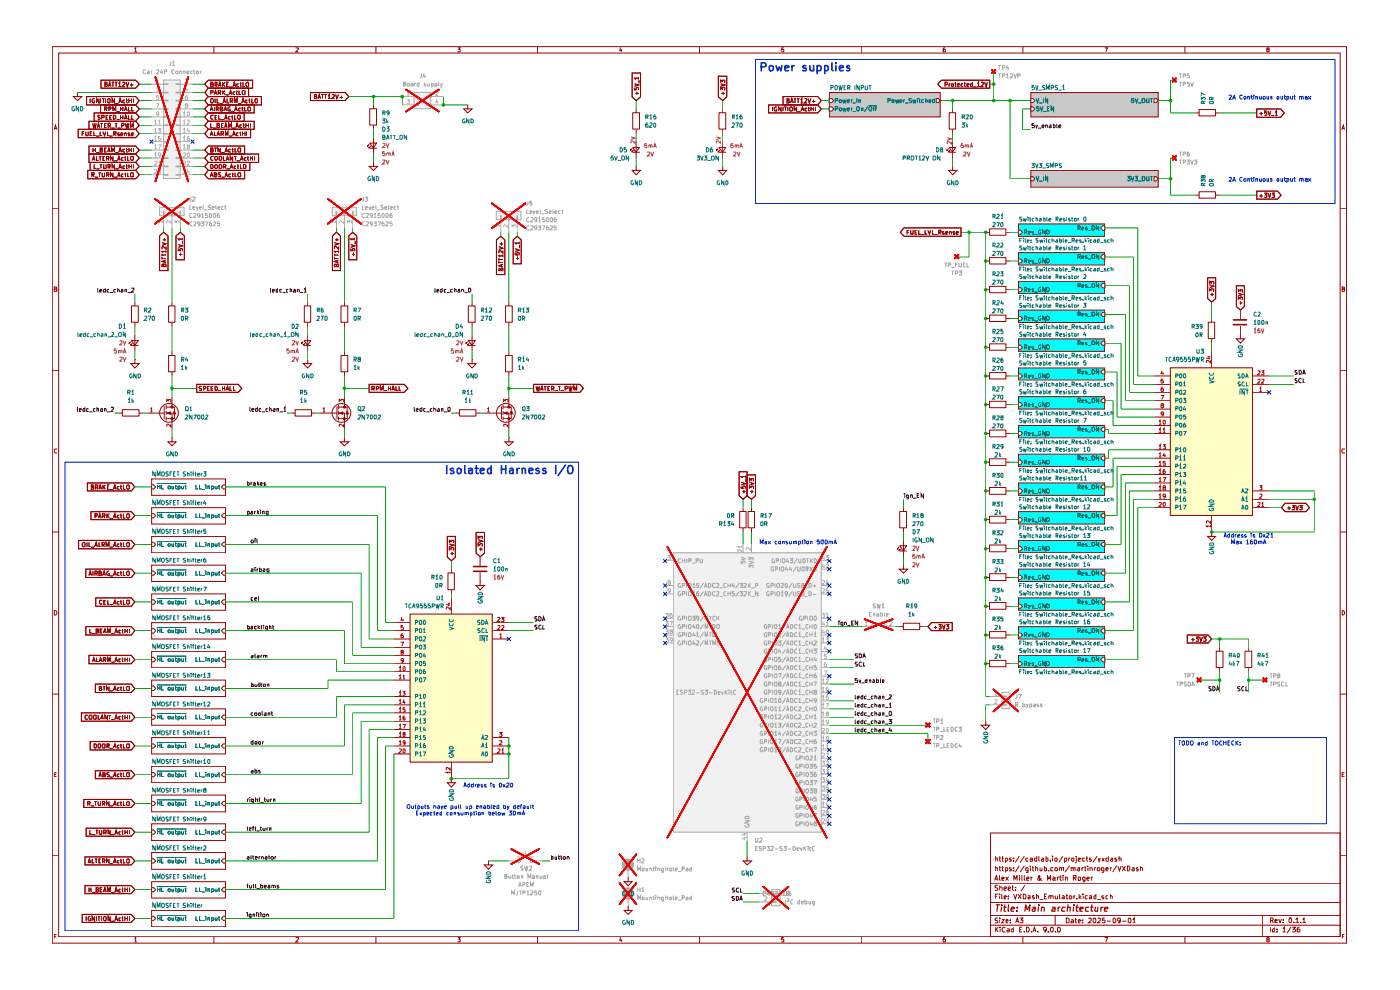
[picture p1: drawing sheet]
<svg xmlns="http://www.w3.org/2000/svg" width="297mm" height="210mm" viewBox="0 0 297 210" stroke-linecap="round" stroke-linejoin="round" font-family="sans-serif">
<g fill="none" stroke="#980000" stroke-width=".21">
<path d="M11.1 9.9h274.6v190.2h-274.6zM12.4 11.3h271.9v187.4h-271.9zM28.5 10.4l.3-.2v.8M28.5 11h.5M45.4 9.9v1.4M62.8 10.2h.4l.1 .2-.6 .6h.6M79.8 9.9v1.4M97.1 10.2h.5l-.2 .3 .2 .1v.3h-.5M114 9.9v1.4M131.7 10.1l-.2 .6h.5M131.9 10.4v.6M148.4 9.9v1.4"/>
<path d="M166.3 10.2h-.4l-.1 .4 .4-.1 .1 .4h-.5M182.7 9.9v1.4M200.5 10.2h-.3l-.1 .6v.2l.5-.1-.1-.4h-.4v.2M217 9.9v1.4M234.4 10.2h.5l-.3 .8M251.4 9.9v1.4M268.9 10.5l-.2-.2 .1-.1h.3l.1 .2-.5 .3 .1 .3 .4-.1v-.3l-.1-.1M11.5 27.5l.3-.9 .3 .9M11.6 27.3h.4M284.6 27.5l.4-.9 .2 .9M284.7 27.3h.5M11.1 44.3h1.3"/>
<path d="M284.3 44.3h1.4M11.1 78.6h1.3M11.5 61.3h.4l.1-.3-.5-.1v.9h.5l.1-.3-.3-.2M284.3 78.6h1.4M284.7 61.3h.5v-.3l-.1-.1h-.4v.9h.5v-.4l-.1-.1M12.1 95.3l-.4-.1-.2 .2v.5l.2 .2 .4-.1M285.2 95.3l-.4-.1-.2 .4 .2 .5 .4-.1M11.1 112.9h1.3M284.3 112.9h1.4M11.5 129.5a.48 .48 0 0 1 .6 .5 .48 .48 0 0 1-.6 .5zM284.7 129.5l.5 .3v.4l-.3 .3h-.2zM11.1 147.2h1.3"/>
<path d="M284.3 147.2h1.4M11.6 164.3h.3M12 163.9h-.4v.9h.4M210.1 176.7h74.2v22h-74.2zM284.7 164.3h.4M285.2 163.9h-.5v.9h.5M11.1 181.5h1.3M11.6 198.6h.3M12 198.2h-.4v.8M28.5 199.1l.3-.2v.9M28.5 199.8h.5M45.4 198.7v1.4"/>
<path d="M62.8 199l.4-.1 .1 .2-.6 .7h.6M79.8 198.7v1.4M97.1 198.9h.5l-.2 .3 .2 .1v.4h-.5M114 198.7v1.4M131.7 198.8l-.2 .7h.5M131.9 199.2v.6M148.4 198.7v1.4M166.3 198.9h-.4l-.1 .4h.5v.4h-.5M182.7 198.7v1.4M200.5 198.9h-.3a.72 .72 0 0 0 0 .9l.4-.1v-.4l-.4-.1-.1 .2M210.1 196.3h74.2M210.1 194.2h74.2"/>
<path d="M210.1 191.4h74.2M210.1 187.4h74.2M211 186.7l.4-1 .3 1M211.1 186.5h.5M211.2 184.1h.4v.6M211.2 182.1l.4-.1v.7M211.2 181.6v1.1M211.2 183.7v1M211.2 196.7v1M211.2 190.2h.3M211.3 197.1l.4 .6M211.7 194.8l-.4-.1-.2 .3 .1 .2 .5 .2v.3h-.6"/>
<path d="M211.7 189.6h-.5v1.1M211.7 187.9h-.5a.44 .44 0 0 0 0 .4 .44 .44 0 0 0 .5 .2l-.2 .4-.4-.1M211.7 196.7l-.5 .6M211.9 184.1h.4M211.9 182h.4M212 189.6v.1M212 190v.7M212 185.7v.9l.2 .1M212.1 194.7v.1M212.1 188.3l.2-.2 .3 .2v.6M212.1 183.7v1h.2M212.1 181.6v1l.2 .1"/>
<path d="M212.1 187.8v1.1M212.1 195.1v.6M212.2 196.7v.1M212.2 197v.7M212.5 195.1h.5l-.5 .6h.5M212.5 189.6v1l.2 .1M212.5 184.1h.4M212.5 182h.4M212.6 186.4l.5-.1-.2-.3-.3 .1v.6h.4M212.7 183.7v1h.2M212.7 181.6v1l.2 .1M213 190.3l.5-.1-.1-.2-.4 .1v.6h.4"/>
<path d="M213 188.5l.5-.1-.1-.3-.4 .1v.6h.4M213.3 196.8a.51 .51 0 0 0-.7 .2 .51 .51 0 0 0 .2 .7l.5-.1M213.3 184.7h.2l.3-.1v-.4l-.2-.1h-.3v1M213.3 182.6l.2 .1 .3-.2-.2-.5h-.3v1M213.4 186l.5 .7M213.4 195.4l.5-.1-.1-.2-.4 .1v.5h.5M213.7 197.1h.4v.6h-.4l-.1-.3 .5-.1M213.9 188.5l.5-.1v-.2l-.4-.1-.1 .2v.4l.1 .2 .4-.1M213.9 186l-.5 .7M213.9 190.6v.1M213.9 190.1v.1M214.4 195.7h.1"/>
<path d="M214.4 195.2h.1M214.5 184.1h-.3l-.1 .1 .4 .2v.3h-.4M214.5 182l-.4 .1 .2 .3h.2v.2h-.4M214.7 188.1h.3M214.8 187.8v.9l.2 .2M215 196.7v1h-.3l-.2-.2v-.3l.3-.2 .2 .1M215 189.6l.4 1.1 .3-1.1M215 184.7h.1M215 184.1v.1M215 182.5v.2M215 182v.1M215.1 186.7v-1l.3 .8 .4-.8v1"/>
<path d="M215.4 188.7v.2M215.4 188.2v.1M215.5 195.7l.3-1 .3 1M215.6 195.5h.5M216 189.6l.7 1.1M216.2 183.6l-.8 1.4M216.2 181.6l-.8 1.4M216.3 185.7v.1M216.3 186v.7M216.3 197.2h.4M216.4 194.7h.6l-.3 .5h.3v.5h-.6M216.7 189.6l-.7 1.1"/>
<path d="M216.8 185.7l.1 1M216.8 196.7h-.5v1h.5M217 198.7v1.4M217.1 189.6a.59 .59 0 0 1 .5 .4 .59 .59 0 0 1-.1 .7h-.4zM217.2 197.6v.1M217.3 185.7v.9l.2 .1M217.3 183.6l-.9 1.4M217.3 181.6l-.9 1.4M217.4 187.8l-.8 1.3M217.8 196.7a.59 .59 0 0 1 .5 .3 .59 .59 0 0 1-.1 .7h-.4zM217.8 186.4l.5-.1-.2-.3-.3 .1v.6h.4M218.1 190.1h.4v.6h-.4v-.4l.4-.1"/>
<path d="M218.1 184.7h-.3l-.2-.1 .1-.5h.4v.9h-.4M218.1 182h-.4l-.1 .2 .1 .4h.4M218.5 182l.5 .1v.6M218.6 183.7v.1M218.6 184.1v.6M218.7 186v.7M218.8 197.6v.1M218.9 184.1h.5M219 186l-.3 .2M219 182.2l-.5 .2 .1 .3 .4-.1M219.1 197.7l.4-1 .3 1M219.1 183.7v1h.3"/>
<path d="M219.2 197.4h.5M219.4 190.1l-.3-.1-.1 .3h.3l.2 .3-.5 .1M219.7 184.1h.3l.1 .6M219.7 183.7v1M219.9 190.2l.1-.2 .3 .1v.6M219.9 189.6v1.1M220 182l-.5 .1v.4l.1 .2 .4-.1M220 181.6v1.1M220.1 197.6v.1M220.4 181.6v.9l.2 .2M220.6 190.8h.7M220.6 184.1v.6h.5"/>
<path d="M220.8 186.2l-.2 .5-.4-.1v-.3l.4-.3-.1-.3-.2 .3 .4 .6 .3 .1M221 182l.4 .1v.6M221.1 184.1v.6M221.4 182.2l-.5 .3 .2 .2 .3-.1M221.6 184.1h.4v.6h-.4M221.6 190.2h.3M221.6 183.7v1M221.9 182l.4 .1v.4l-.1 .2-.3-.1M221.9 181.6v1.1M222 197.1l-.2 .3-.4-.2v-.4l.4-.1a.83 .83 0 0 1 0 1h-.3M222.1 189.6h-.5v1.1h.5M222.2 186.7v-1l.3 .8 .4-.8v1"/>
<path d="M222.4 197.6v.1M222.5 190.2l.2-.2 .2 .1v.6M222.5 184.7h.1M222.5 190v.7M222.8 182.5v.2M222.9 196.8l.3-.1 .2 .1v.7l-.1 .2-.4-.1zM222.9 190.2l.4-.2 .1 .2v.5M223.3 181.6v.2M223.3 182v.7M223.4 186.1h.4v.6h-.4l-.1-.2 .5-.2M223.4 184.1h-.5v.6h.5M223.8 182.1l.4-.1 .1 .5-.2 .2-.3-.2z"/>
<path d="M223.9 197.6v.1M223.9 190v.6h.5M223.9 184.1h.3l.2 .1-.1 .5h-.3l-.2-.1zM223.9 194.2v2.1M224.3 186v.7M224.4 196.8l.2-.1a.52 .52 0 0 1 .4 .6 .52 .52 0 0 1-.6 .4zM224.4 190v.7M224.6 186l-.3 .2M224.8 189.6v1l.2 .1M224.8 184.1h.3l.1 .6M224.8 184.1v.6M224.8 186h.4"/>
<path d="M224.9 185.7v.9l.3 .1M225.2 184.2l.1-.1h.3v.6M225.4 190.1l.2-.1 .2 .2v.5h-.4v-.4l.4-.1M225.5 181.6l-.9 1.4M225.5 185.7v.1M225.5 186v.7M225.8 182.6h.4v-.6h-.4v1M226 186.1h.4v.6M226 186v.7M226.1 190h.5M226.2 194.7l.6 .3v.6l-.2 .1h-.4zM226.3 189.6v1.1h.3"/>
<path d="M226.7 182v.7M226.9 190.1l.3-.1 .2 .2-.2 .5h-.3zM226.9 183.6l-.9 1.4M227.1 182h-.3l-.1 .2M227.2 195.2l.4-.1 .1 .1v.5h-.5v-.3l.5-.1M227.2 184.1h.4l.1 .6M227.2 184.1v.6M227.4 182l.4 .1v.4l-.1 .2-.4-.2zM227.7 184.2v-.1h.4v.6M227.7 186.2h.5l.1-.4-.6-.1v1M227.8 190v.7M228 186.2l.3 .5"/>
<path d="M228.1 190l-.3 .2M228.1 195.1h.3M228.2 194.7v1h.2M228.3 182v.9l-.2 .1M228.3 181.6v.2M228.4 190.6v.1M228.6 184.1h.4v.6M228.7 186.2l.2-.2 .3 .1v.5l-.4 .1zM228.8 195.4l.5-.1-.2-.2-.3 .1v.5h.4M228.8 182.4l.5-.2-.1-.2h-.4v.6h.4M228.9 189.6v1.1M229 184.3h-.3l-.2 .2 .2 .2h.3"/>
<path d="M229 190.3l.4 .4M229.4 190l-.5 .4M229.5 184.1v.6M229.7 195.7h.1M229.7 195.2h.1M229.8 189.6v.1M229.8 190v.7M229.9 184.1h-.3l-.1 .1M230 184.1h.4M230.1 182h-.4l-.1 .2 .1 .4h.4M230.2 186v.9l-.1 .2h-.4M230.2 186.1l-.4-.1-.1 .2v.5h.5"/>
<path d="M230.2 183.7v1h.2M230.4 182h.4M230.5 181.6v.9l.3 .2M230.6 186.4l.5-.1-.2-.3-.3 .2v.4l.1 .1h.3M230.7 190.1l-.3-.1-.2 .2 .1 .5h.4M230.8 183.7v.1M230.8 184.1v.6M230.9 194.8h.6v.4l-.6 .5h.6M231.1 190.1h.5v.6h-.5v-.4l.5-.1M231.2 184.1h.4l.1 .6M231.2 184.1v.6M231.5 182h-.4v.3l.5 .2-.2 .2-.3-.1"/>
<path d="M231.5 186v.7M231.8 186l-.3 .2M232 194.8l.2-.1a.53 .53 0 0 1 .3 .6 .53 .53 0 0 1-.4 .4l-.2-.1zM232.2 184.1v.6M232.5 189.6v1.1h-.3l-.1-.5 .1-.2 .3 .1M232.5 184.1h-.3v.1M232.7 190.8h.9M232.7 181.6l-.9 1.4M232.8 194.8h.6v.4l-.6 .5h.6M232.8 184.1h.4l.1 .1v.5h-.3l-.3-.1zM233 182l.2 .7 .2-.7M233.8 182l.5 .7"/>
<path d="M234.1 190.1h-.3v.2h.2l.2 .3-.4 .1M234.2 184.7h-.3l-.2-.1 .1-.5h.4v.8l-.2 .2-.2-.1M234.3 182l-.5 .7M234.4 198.9h.5l-.3 .9M234.4 194.7h-.5l-.1 .5h.5l.1 .1v.4h-.6M234.6 184.4l.5-.1-.1-.2h-.3l-.1 .1v.4l.2 .1h.2M234.9 195.4h.7M235 190.1l-.2-.1-.2 .2v.4l.4 .1M235.1 182h-.4l-.1 .2 .1 .4h.4M235.1 181.6v1.1M235.5 190.2l.1-.2 .4 .2v.5M235.5 184.1v.6"/>
<path d="M235.5 189.6v1.1M235.6 182l.4 .1v.6M235.9 184.1h-.3l-.1 .1M236 182.2l-.5 .3 .2 .2 .3-.1M236.2 194.8l.3-.1 .2 .5-.1 .5h-.4l-.1-.1zM236.9 182l-.4 .1 .1 .3h.3v.2h-.4M236.9 183.6l-.9 1.4M237.1 183.7l.4 1 .3-1M237.4 182.1h.4v.6M237.4 181.6v1.1M237.7 195.2l-.2 .2-.4-.1v-.5h.6v.8l-.2 .1h-.4M238.1 195.4h.8"/>
<path d="M238.1 183.7l.7 1M238.8 183.7l-.7 1M239.2 183.7h.3l.2 .3v.5l-.4 .2h-.1zM239.4 194.8l.2-.1a.53 .53 0 0 1 .3 .6 .53 .53 0 0 1-.4 .4l-.2-.1zM240.2 184.1h.3l.1 .6M240.3 195.1l.3-.4v1M240.3 195.7h.6M240.6 184.3h-.3l-.2 .2 .2 .2h.3M241.5 184.1h-.4l-.1 .1 .5 .2v.3h-.5M242 184.1h.3l.1 .6M242 183.7v1M251.4 198.7v1.4"/>
<path d="M267.8 194.2v4.5M268.9 199.3l-.2-.2 .1-.2h.3l.1 .3-.4 .1-.1 .2 .2 .3 .3-.1v-.3l-.1-.1M269.5 196.7v1M269.5 195.3l.5-.1v-.4l-.5-.1v1M269.8 195.3l.3 .4M270.4 196.7v1h-.4l-.1-.5 .3-.2 .2 .1M270.5 195.4l.5-.1v-.2l-.4-.1-.1 .2v.5h.5M270.9 197.6v.1M270.9 197.1v.1M271.3 195l.3 .7 .2-.7M272.1 196.9l.4-.2v1M272.1 197.7h.6"/>
<path d="M272.2 195.6v.1M272.2 195.1v.1M273.5 194.8l.2-.1a.53 .53 0 0 1 .3 .5 .53 .53 0 0 1-.4 .5l-.2-.3zM273.9 196.6l-.9 1.3M274.1 196.7h.7l-.4 .4 .4 .2v.2l-.1 .2-.6-.1M274.4 195.6v.1M274.9 195l.3-.3v1M274.9 195.7h.6M275.7 196.7l-.4 .1a.74 .74 0 0 0-.1 .9h.5l.1-.5-.6-.1v.2M276 195.6v.1M276.4 195l.2-.3v1M276.4 195.7h.6"/>
<path d="M284.3 181.5h1.4M284.8 198.6h.3M285.2 198.2h-.4v.8"/>
</g>
<g fill="none" stroke="#980000" stroke-width=".25">
<path d="M211.3 191.9h.8M211.7 191.9l-.2 1.4M212.5 191.9v.2M212.5 192.4l-.2 .9M212.9 192.4h.5M213.2 191.9l-.2 1.2 .1 .2h.3M213.9 191.9v1.4h.1M214.5 192.9l.7-.2-.1-.3h-.5l-.1 .7v.2h.5M215.7 193.2v.1M215.8 192.4v.2M217.4 193.3l.2-1.4 .3 1 .6-1-.2 1.4M219.1 192.4h.5v.2l-.1 .7h-.5v-.4l.6-.2"/>
<path d="M220.3 192.4l-.1 .9M220.4 191.9v.2M221 192.5l.5-.1v.9M221 192.4l-.1 .9M223.3 192.4h.5l.1 .2-.1 .7h-.6l-.1-.2 .2-.3 .6-.1M224.5 192.4l-.1 .9M224.9 192.4h-.3l-.2 .3M226 192.4h-.5l-.3 .6 .1 .3h.6M226.6 192.5l.5-.1-.1 .9M226.6 191.9l-.2 1.4M227.7 192.4v.9M227.8 191.9v.2"/>
<path d="M228.3 192.4h.5M228.5 191.9l-.2 1.2 .1 .2h.3M229.1 192.9l.7-.2v-.3h-.6l-.1 .2v.7h.5M231 192.4h-.5l-.2 .3v.5l.6 .1M231.4 192.4h.5M231.6 191.9l-.1 1.2 .1 .2h.2M232.4 192.4l-.1 .9 .5-.1M232.9 192.4l-.1 .9M233.6 192.4l-.1 .9M234 192.4h-.2l-.2 .3M234.4 192.9l.6-.2-.1-.3h-.5l-.1 .7 .1 .2h.5"/>
</g>
<g fill="none" stroke="#e00" stroke-width=".34">
<path d="M33 16.4l6.9 22.1M39.9 16.4l-6.9 22.1M86.1 19l7 4.7M93.1 19l-7 4.7M210.4 14.9l.7 .6M211.1 14.9l-.7 .6M248.8 16.6l.7 .7M249.5 16.6l-.7 .7M248.8 33.1l.7 .8M249.5 33.1l-.7 .8M32.9 42.2l7.1 5.2M40 42.2l-7.1 5.2"/>
<path d="M69.5 42.2l7.1 5.2M76.6 42.2l-7.1 5.2M104.3 43.1l7.2 5.3M111.5 43.1l-7.2 5.3M202.6 54.1l.7 .7M203.3 54.1l-.7 .7M141.6 116l33.8 61.7M175.4 116l-33.8 61.7M183.4 131.4l6 2.2M189.4 131.4l-6 2.2M196.5 153.5l.7 .6M196.5 156.9l.7 .8"/>
<path d="M197.2 153.5l-.7 .6M197.2 156.9l-.7 .8M210.8 146.3l5.2 4.6M216 146.3l-5.2 4.6M254 143.9l.7 .7M254.7 143.9l-.7 .7M268 143.9l.7 .7M268.7 143.9l-.7 .7M108.5 180.1l5.8 3.2M114.3 180.1l-5.8 3.2M131.4 181.2l3.6 4.5M131.4 187.3l3.6 4.5"/>
<path d="M135 181.2l-3.6 4.5M135 187.3l-3.6 4.5M161.9 188.1l5.4 4.6M167.3 188.1l-5.4 4.6"/>
</g>
<path d="M216.1 128.2h.4l.4 .4-.4 .4h-.4z" fill="#fff"/>
<path d="M216.1 128.2h.4l.4 .4-.4 .4h-.4z" fill="none" stroke="#805e00" stroke-width=".21"/>
<path d="M217.3 128.6h.4l.1-.3-.1-.2h-.4v.8M217.6 128.6l.2 .3M218.2 128.7l.4-.1-.1-.2h-.3v.5h.3M219.3 128.4h-.4l.1 .3h.3v.2h-.4M219.5 129h.6M220.8 128.2l-.2-.1-.3 .2v.5l.2 .1h.3v-.3h-.2M221.7 128.1v.8l-.5-.8v.8M222.1 128.1h.2l.3 .2v.5l-.2 .1h-.3z" fill="none" stroke="#007170" stroke-width=".21"/>
<path d="M233.5 127.7l.4-.5h.5v1h-.5z" fill="#fff"/>
<path d="M233.9 127.2h.5v1h-.5l-.4-.5z" fill="none" stroke="#805e00" stroke-width=".21"/>
<path d="M228.7 127.7h.4l.1-.4-.5-.1v.9M228.9 127.7l.3 .4M229.5 127.8h.4l-.1-.3-.3 .1v.5h.4M230.6 127.6h-.3l.1 .2h.2v.3h-.3M230.8 128.2h.7M231.6 127.3h.6v.5l-.1 .3-.5-.1zM233.1 127.2v.9l-.5-.9v.9" fill="none" stroke="#007170" stroke-width=".21"/>
<path d="M216.1 126.8h18.3v2.6h-18.3z" fill="#0ff"/>
<path d="M216.1 140.4h.4l.4 .4-.4 .4h-.4z" fill="#fff"/>
<path d="M216.1 140.4h.4l.4 .4-.4 .4h-.4z" fill="none" stroke="#805e00" stroke-width=".21"/>
<path d="M217.3 140.8h.4l.1-.3-.1-.2h-.4v.9M217.6 140.8l.2 .4M218.2 140.9l.4-.1-.1-.2h-.3v.5h.3M219.3 140.6h-.4v.3l.4 .1-.1 .2-.3-.1M219.5 141.3h.6M220.8 140.4l-.2-.1-.3 .2v.5l.3 .2 .2-.1v-.3h-.2M221.7 140.3v.9l-.5-.9v.9M222.1 140.3h.2l.3 .2v.5l-.3 .2h-.2z" fill="none" stroke="#007170" stroke-width=".21"/>
<path d="M233.9 139.4h.5v1h-.5l-.4-.5z" fill="#fff"/>
<path d="M233.9 139.4h.5v1h-.5l-.4-.5z" fill="none" stroke="#805e00" stroke-width=".21"/>
<path d="M228.7 139.9h.4l.1-.4-.5-.1v.9M228.9 139.9l.3 .4M230.6 139.8h-.3l.1 .2h.2v.3h-.3M231.7 139.4h.4l.1 .3-.1 .6-.5-.1zM233.1 139.4v.9l-.5-.9v.9M229.5 140l.4-.1-.1-.2-.3 .1v.5h.4M230.8 140.4h.7" fill="none" stroke="#007170" stroke-width=".21"/>
<path d="M216.1 139h18.3v2.6h-18.3z" fill="#0ff"/>
<path d="M216.1 134.3h.4l.4 .4-.4 .4h-.4z" fill="#fff"/>
<path d="M216.1 134.3h.4l.4 .4-.4 .4h-.4z" fill="none" stroke="#805e00" stroke-width=".21"/>
<path d="M217.3 134.7h.4l.1-.3-.1-.2h-.4v.8M217.6 134.7l.2 .3M218.2 134.8l.4-.1-.1-.2h-.3v.5h.3M219.3 134.5h-.4v.3h.3l.1 .2h-.4M219.5 135.1h.6M220.8 134.3l-.2-.1-.3 .2v.5l.2 .1h.3v-.3h-.2M221.7 134.2v.8l-.5-.8v.8M222.1 134.2h.2l.3 .2v.5l-.2 .1h-.3z" fill="none" stroke="#007170" stroke-width=".21"/>
<path d="M233.5 133.8l.4-.5h.5v1h-.5z" fill="#fff"/>
<path d="M233.9 133.3h.5v1h-.5l-.4-.5z" fill="none" stroke="#805e00" stroke-width=".21"/>
<path d="M228.7 133.8h.4l.1-.4-.5-.1v.9M228.9 133.8l.3 .4M229.5 133.9h.4l-.1-.3-.3 .1v.5h.4M230.6 133.7h-.3l.1 .2h.2v.3h-.3M230.8 134.3h.7M231.6 133.4h.6v.5l-.1 .3-.5-.1zM233.1 133.3v.9l-.5-.9v.9" fill="none" stroke="#007170" stroke-width=".21"/>
<path d="M216.1 132.9h18.3v2.6h-18.3z" fill="#0ff"/>
<path d="M216.1 115.9h.4l.4 .5-.4 .4h-.4z" fill="#fff"/>
<path d="M216.1 115.9h.4l.4 .5-.4 .4h-.4z" fill="none" stroke="#805e00" stroke-width=".21"/>
<path d="M217.3 116.3h.5v-.4h-.5v.8M217.6 116.3l.2 .4M218.2 116.5l.4-.1-.2-.2h-.2v.5h.3M219.3 116.2h-.4l.1 .3h.3v.2h-.4M219.5 116.8h.6M220.8 115.9h-.3l-.2 .2v.5l.2 .1h.3v-.3h-.2M221.7 115.9v.8l-.5-.8v.8M222.1 115.9h.3l.2 .2v.5l-.2 .1h-.3z" fill="none" stroke="#007170" stroke-width=".21"/>
<path d="M233.5 115.5l.4-.4h.5v.8h-.5z" fill="#fff"/>
<path d="M233.9 115.1h.5v.8h-.5l-.4-.4z" fill="none" stroke="#805e00" stroke-width=".21"/>
<path d="M228.7 115.5h.4l.1-.4h-.5v.8M228.9 115.5l.3 .4M229.5 115.6h.4l-.1-.3-.3 .1v.4h.4M230.6 115.4h-.3l.1 .2h.2l-.1 .3-.2-.1M230.8 116h.7M231.6 115.1h.5l.1 .2v.3l-.2 .3-.4-.2zM233.1 115.1v.8l-.5-.8v.8" fill="none" stroke="#007170" stroke-width=".21"/>
<path d="M216.1 114.6h18.3v2.7h-18.3z" fill="#0ff"/>
<path d="M216.1 109.8h.4l.4 .4-.4 .5h-.4z" fill="#fff"/>
<path d="M216.1 109.8h.4l.4 .4-.4 .5h-.4z" fill="none" stroke="#805e00" stroke-width=".21"/>
<path d="M217.3 110.2h.5v-.4h-.5v.9M217.6 110.2l.2 .5M218.2 110.4l.4-.1-.2-.2h-.2v.6h.3M219.3 110.1h-.4l.1 .3h.3v.3h-.4M219.5 110.7h.6M220.8 109.8h-.3l-.2 .2v.5l.2 .2h.3v-.4h-.2M221.7 109.8v.9l-.5-.9v.9M222.1 109.8h.3l.2 .2v.5l-.2 .2h-.3z" fill="none" stroke="#007170" stroke-width=".21"/>
<path d="M233.5 109.4l.4-.4h.5v.8h-.5z" fill="#fff"/>
<path d="M233.9 109h.5v.8h-.5l-.4-.4z" fill="none" stroke="#805e00" stroke-width=".21"/>
<path d="M228.7 109.4h.4l.1-.4h-.5v.8M228.9 109.4l.3 .4M229.5 109.5l.4-.1-.1-.2-.3 .1v.4h.4M230.6 109.3h-.3v.2l.3 .1-.1 .2-.2-.1M230.8 109.9h.7M231.6 109h.6a.47 .47 0 0 1-.4 .8l-.2-.2zM233.1 109v.8l-.5-.8v.8" fill="none" stroke="#007170" stroke-width=".21"/>
<path d="M216.1 108.5h18.3v2.7h-18.3z" fill="#0ff"/>
<path d="M216.1 122h.4l.4 .5-.4 .4h-.4z" fill="#fff"/>
<path d="M216.1 122h.4l.4 .5-.4 .4h-.4z" fill="none" stroke="#805e00" stroke-width=".21"/>
<path d="M217.3 122.4h.5v-.2l-.1-.2h-.4v.8M217.6 122.4l.2 .4M218.2 122.6l.4-.1-.2-.2h-.2v.5h.3M219.3 122.3h-.4l.1 .3h.3v.2h-.4M219.5 122.9h.6M220.8 122.1l-.2-.1-.3 .2v.5l.2 .1h.3v-.3h-.2M221.7 122v.8l-.5-.8v.8M222.1 122l.5 .2v.5l-.2 .1h-.3z" fill="none" stroke="#007170" stroke-width=".21"/>
<path d="M233.5 121.6l.4-.4h.5v.8h-.5z" fill="#fff"/>
<path d="M233.9 121.2h.5v.8h-.5l-.4-.4z" fill="none" stroke="#805e00" stroke-width=".21"/>
<path d="M228.7 121.6h.4l.1-.4h-.5v.8M228.9 121.6l.3 .4M229.5 121.7h.4l-.1-.3-.3 .1v.5h.4M230.6 121.5h-.3l.1 .2h.2v.3h-.3M230.8 122.1h.7M231.6 121.2h.6v.5l-.1 .3-.5-.1zM233.1 121.2v.8l-.5-.8v.8" fill="none" stroke="#007170" stroke-width=".21"/>
<path d="M216.1 120.7h18.3v2.7h-18.3z" fill="#0ff"/>
<path d="M47.4 194.4h.4v.8h-.4l-.4-.4z" fill="#fff"/>
<path d="M47.4 194.4h.4v.8h-.4l-.4-.4z" fill="none" stroke="#805e00" stroke-width=".21"/>
<g fill="none" stroke="#007170" stroke-width=".21">
<path d="M41.6 194.4v.8h.4M42.3 194.4v.8h.5M42.8 195.3h.6M43.7 194.4v.1M43.7 194.6v.6M44.1 194.7h.3v.5M44.1 194.6v.6M44.9 194.7h.4v.5h-.4M44.9 194.6v.9M45.6 194.6v.5l.2 .1h.3M46.1 194.6v.6M46.3 194.6h.3"/>
<path d="M46.5 194.4v.8h.1"/>
</g>
<path d="M32.2 194.4h.4l.4 .4-.4 .4h-.4z" fill="#fff"/>
<path d="M32.2 194.4h.4l.4 .4-.4 .4h-.4z" fill="none" stroke="#805e00" stroke-width=".21"/>
<g fill="none" stroke="#007170" stroke-width=".21">
<path d="M33.3 194.1h6.2M33.4 194.4v.8M33.4 194.8h.5M33.9 194.4v.8M34.3 194.4v.8h.4M35.6 194.8l.4-.2 .1 .5-.3 .1zM36.5 194.6v.6h.3M36.8 194.6v.6M37.2 194.6h.3M37.2 194.4v.7l.3 .1M37.8 194.7h.4v.5h-.4M37.8 194.6v.9"/>
<path d="M38.5 194.6v.5l.2 .1h.2M38.9 194.6v.6M39.2 194.6h.3M39.4 194.4v.8h.1"/>
</g>
<g fill="#fff">
<path d="M32.2 193.1h15.6v3.5h-15.6z"/>
<path d="M47 176.5l.4-.4h.4v.8h-.4z"/>
</g>
<path d="M47.4 176.1h.4v.8h-.4l-.4-.4z" fill="none" stroke="#805e00" stroke-width=".21"/>
<path d="M41.6 176v.9h.4M42.3 176v.9h.5M42.8 177h.6M43.7 176v.1M43.7 176.4v.5M44.1 176.4h.3v.5M44.1 176.4v.5M44.9 176.9h.4l-.1-.5h-.3v.8M45.6 176.4v.4l.2 .1h.3M46.1 176.4v.5M46.3 176.4h.3M46.5 176v.9h.1" fill="none" stroke="#007170" stroke-width=".21"/>
<path d="M32.2 176.1h.4l.4 .4-.4 .4h-.4z" fill="#fff"/>
<path d="M32.2 176.1h.4l.4 .4-.4 .4h-.4z" fill="none" stroke="#805e00" stroke-width=".21"/>
<g fill="none" stroke="#007170" stroke-width=".21">
<path d="M33.3 175.8h6.2M33.4 176v.9M33.4 176.4h.5M33.9 176v.9M34.3 176v.9h.4M35.7 176.4h.4v.1l-.1 .4-.4-.1zM36.5 176.4v.5h.3M36.8 176.4v.5M37.2 176.4h.3M37.2 176v.8l.3 .1M37.8 176.9h.4l-.1-.5h-.3v.8M38.5 176.4v.4l.2 .1h.2"/>
<path d="M38.9 176.4v.5M39.2 176.4h.3M39.4 176v.9h.1"/>
</g>
<g fill="#fff">
<path d="M32.2 174.7h15.6v3.6h-15.6z"/>
<path d="M47.4 188.3h.4v.8h-.4l-.4-.4z"/>
</g>
<path d="M47.4 188.3h.4v.8h-.4l-.4-.4z" fill="none" stroke="#805e00" stroke-width=".21"/>
<path d="M41.6 188.3v.8h.4M42.3 188.3v.8h.5M42.8 189.2h.6M43.7 188.3v.1M43.7 188.5v.6M44.1 188.6l.3-.1v.6M44.1 188.5v.6M44.9 189.1h.4l-.1-.6h-.3v.9M45.6 188.5v.5l.2 .1h.3M46.1 188.5v.6M46.3 188.5h.3M46.5 188.3v.8h.1" fill="none" stroke="#007170" stroke-width=".21"/>
<path d="M32.2 188.3h.4l.4 .4-.4 .4h-.4z" fill="#fff"/>
<path d="M32.2 188.3h.4l.4 .4-.4 .4h-.4z" fill="none" stroke="#805e00" stroke-width=".21"/>
<g fill="none" stroke="#007170" stroke-width=".21">
<path d="M33.3 188h6.2M33.4 188.3v.8M33.4 188.6h.5M33.9 188.3v.8M34.3 188.3v.8h.4M35.7 188.5h.4v.2l-.1 .4-.4-.1zM36.5 188.5v.6h.3M36.8 188.5v.6M37.2 188.5h.3M37.2 188.3v.7l.3 .1M37.8 189.1h.4l-.1-.6h-.3v.9M38.5 188.5v.5l.2 .1h.2"/>
<path d="M38.9 188.5v.6M39.2 188.5h.3M39.4 188.3v.8h.1"/>
</g>
<g fill="#fff">
<path d="M32.2 187h15.6v3.5h-15.6z"/>
<path d="M47 182.6l.4-.4h.4v.8h-.4z"/>
</g>
<path d="M47 182.6l.4-.4h.4v.8h-.4z" fill="none" stroke="#805e00" stroke-width=".21"/>
<path d="M41.6 182.1v.9h.4M42.3 182.1v.9h.5M42.8 183.1h.6M43.7 182.1v.1M43.7 182.5v.5M44.1 182.5h.3v.5M44.1 182.5v.5M44.9 183h.4l-.1-.5h-.3v.8M45.6 182.5v.4l.2 .1h.3M46.1 182.5v.5M46.3 182.5h.3M46.5 182.1v.9h.1" fill="none" stroke="#007170" stroke-width=".21"/>
<path d="M32.2 182.2h.4l.4 .4-.4 .4h-.4z" fill="#fff"/>
<path d="M32.2 182.2h.4l.4 .4-.4 .4h-.4z" fill="none" stroke="#805e00" stroke-width=".21"/>
<g fill="none" stroke="#007170" stroke-width=".21">
<path d="M33.3 181.9h6.2M33.4 182.1v.9M33.4 182.5h.5M33.9 182.1v.9M34.3 182.1v.9h.4M35.7 182.5h.4v.1l-.1 .4-.4-.1zM36.5 182.5v.5h.3M36.8 182.5v.5M37.2 182.5h.3M37.2 182.1v.8l.3 .1M37.8 183h.4l-.1-.5h-.3v.8M38.5 182.5v.4l.2 .1h.2"/>
<path d="M38.9 182.5v.5M39.2 182.5h.3M39.4 182.1v.9h.1"/>
</g>
<g fill="#fff">
<path d="M32.2 180.8h15.6v3.6h-15.6z"/>
<path d="M47.4 102.9h.4v.8h-.4l-.4-.4z"/>
</g>
<path d="M47.4 102.9h.4v.8h-.4l-.4-.4z" fill="none" stroke="#805e00" stroke-width=".21"/>
<path d="M41.6 102.9v.8h.4M42.3 102.9v.8h.5M42.8 103.8h.6M43.7 102.9h.1M43.7 103.1v.6M44.1 103.2l.3-.1v.6M44.1 103.1v.6M44.9 103.6h.4l-.1-.5h-.3v.9M45.6 103.1v.4l.2 .2 .3-.1M46.1 103.1v.6M46.3 103.1h.3M46.5 102.9v.7l.1 .1" fill="none" stroke="#007170" stroke-width=".21"/>
<path d="M32.2 102.9h.4l.4 .4-.4 .4h-.4z" fill="#fff"/>
<path d="M32.2 102.9h.4l.4 .4-.4 .4h-.4z" fill="none" stroke="#805e00" stroke-width=".21"/>
<g fill="none" stroke="#007170" stroke-width=".21">
<path d="M33.3 102.6h6.2M33.4 102.9v.8M33.4 103.2h.5M33.9 102.9v.8M34.3 102.9v.8h.4M35.7 103.1h.4v.2l-.1 .4-.4-.2zM36.5 103.1v.5h.3M36.8 103.1v.6M37.2 103.1h.3M37.2 102.9v.6l.3 .2M37.8 103.6h.4l-.1-.5h-.3v.9M38.5 103.1v.4l.2 .2 .2-.1"/>
<path d="M38.9 103.1v.6M39.2 103.1h.3M39.4 102.9v.7l.1 .1"/>
</g>
<g fill="#fff">
<path d="M32.2 101.6h15.6v3.5h-15.6z"/>
<path d="M47.4 121.2h.4v.8h-.4l-.4-.4z"/>
</g>
<path d="M47.4 121.2h.4v.8h-.4l-.4-.4z" fill="none" stroke="#805e00" stroke-width=".21"/>
<g fill="none" stroke="#007170" stroke-width=".21">
<path d="M41.6 121.2v.8h.4M42.3 121.2v.8h.5M42.8 122.1h.6M43.7 121.2h.1M43.7 121.4v.6M44.1 121.5h.3v.5M44.1 121.4v.6M44.9 121.5h.4v.4l-.4 .1M44.9 121.4v.9M45.6 121.4v.5h.5M46.1 121.4v.6M46.3 121.4h.3"/>
<path d="M46.5 121.2v.8h.1"/>
</g>
<path d="M32.2 121.2h.4l.4 .4-.4 .4h-.4z" fill="#fff"/>
<path d="M32.2 121.2h.4l.4 .4-.4 .4h-.4z" fill="none" stroke="#805e00" stroke-width=".21"/>
<g fill="none" stroke="#007170" stroke-width=".21">
<path d="M33.3 120.9h6.2M33.4 121.2v.8M33.4 121.6h.5M33.9 121.2v.8M34.3 121.2v.8h.4M35.8 121.4l.3 .2v.4h-.4l-.1-.2zM36.5 121.4v.6l.3-.1M36.8 121.4v.6M37.2 121.4h.3M37.2 121.2v.7l.3 .1M37.8 121.5h.4v.4l-.4 .1M37.8 121.4v.9"/>
<path d="M38.5 121.4v.5h.4M38.9 121.4v.6M39.2 121.4h.3M39.4 121.2v.8h.1"/>
</g>
<g fill="#fff">
<path d="M32.2 119.9h15.6v3.5h-15.6z"/>
<path d="M47.4 115.1h.4v.8h-.4l-.4-.4z"/>
</g>
<path d="M47.4 115.1h.4v.8h-.4l-.4-.4z" fill="none" stroke="#805e00" stroke-width=".21"/>
<g fill="none" stroke="#007170" stroke-width=".21">
<path d="M41.6 115.1v.8h.4M42.3 115.1v.8h.5M42.8 116h.6M43.7 115.1h.1M43.7 115.3v.6M44.1 115.4h.3v.5M44.1 115.3v.6M44.9 115.4h.4v.4h-.4M44.9 115.3v.9M45.6 115.3v.4l.2 .2 .3-.1M46.1 115.3v.6M46.3 115.3h.3"/>
<path d="M46.5 115.1v.7l.1 .1"/>
</g>
<path d="M32.2 115.1h.4l.4 .4-.4 .4h-.4z" fill="#fff"/>
<path d="M32.2 115.1h.4l.4 .4-.4 .4h-.4z" fill="none" stroke="#805e00" stroke-width=".21"/>
<g fill="none" stroke="#007170" stroke-width=".21">
<path d="M33.3 114.8h6.2M33.4 115.1v.8M33.4 115.5h.5M33.9 115.1v.8M34.3 115.1v.8h.4M35.6 115.5l.4-.2 .1 .4-.3 .2zM36.5 115.3v.5h.3M36.8 115.3v.6M37.2 115.3h.3M37.2 115.1v.6l.3 .2M37.8 115.4h.4v.4h-.4M37.8 115.3v.9"/>
<path d="M38.5 115.3v.4l.2 .2 .2-.1M38.9 115.3v.6M39.2 115.3h.3M39.4 115.1v.7l.1 .1"/>
</g>
<g fill="#fff">
<path d="M32.2 113.8h15.6v3.5h-15.6z"/>
<path d="M47.4 127.2h.4v1h-.4l-.4-.5z"/>
</g>
<path d="M47 127.7l.4-.5h.4v1h-.4z" fill="none" stroke="#805e00" stroke-width=".21"/>
<g fill="none" stroke="#007170" stroke-width=".21">
<path d="M41.6 127.2v.9h.4M42.3 127.2v.9h.5M42.8 128.2h.6M43.7 127.2v.1M43.7 127.5v.6M44.1 127.6h.3v.5M44.1 127.5v.6M44.9 127.6h.4v.4l-.4 .1M44.9 127.5v.9M45.6 127.5v.5h.5M46.1 127.5v.6M46.3 127.5h.3"/>
<path d="M46.5 127.2v.9h.1"/>
</g>
<path d="M32.2 127.2h.4l.4 .5-.4 .5h-.4z" fill="#fff"/>
<path d="M32.2 127.2h.4l.4 .5-.4 .5h-.4z" fill="none" stroke="#805e00" stroke-width=".21"/>
<g fill="none" stroke="#007170" stroke-width=".21">
<path d="M33.3 127h6.2M33.4 127.2v.9M33.4 127.7h.5M33.9 127.2v.9M34.3 127.2v.9h.4M35.6 127.7l.2-.2 .3 .2v.4h-.4zM36.5 127.5v.6l.3-.1M36.8 127.5v.6M37.2 127.5h.3M37.2 127.2v.8l.3 .1M37.8 127.6h.4v.4l-.4 .1M37.8 127.5v.9"/>
<path d="M38.5 127.5v.5h.4M38.9 127.5v.6M39.2 127.5h.3M39.4 127.2v.9h.1"/>
</g>
<g fill="#fff">
<path d="M32.2 126h15.6v3.4h-15.6z"/>
<path d="M47.4 109h.4v.8h-.4l-.4-.4z"/>
</g>
<path d="M47.4 109h.4v.8h-.4l-.4-.4z" fill="none" stroke="#805e00" stroke-width=".21"/>
<g fill="none" stroke="#007170" stroke-width=".21">
<path d="M41.6 109v.8h.4M42.3 109v.8h.5M42.8 109.9h.6M43.7 109h.1M43.7 109.2v.6M44.1 109.3h.3v.5M44.1 109.2v.6M44.9 109.3h.4v.4h-.4M44.9 109.2v.9M45.6 109.2v.4l.2 .2 .3-.1M46.1 109.2v.6M46.3 109.2h.3"/>
<path d="M46.5 109v.7l.1 .1"/>
</g>
<path d="M32.2 109h.4l.4 .4-.4 .4h-.4z" fill="#fff"/>
<path d="M32.2 109h.4l.4 .4-.4 .4h-.4z" fill="none" stroke="#805e00" stroke-width=".21"/>
<g fill="none" stroke="#007170" stroke-width=".21">
<path d="M33.3 108.7h6.2M33.4 109v.8M33.4 109.4h.5M33.9 109v.8M34.3 109v.8h.4M35.6 109.4l.4-.2 .1 .4-.3 .2zM36.5 109.2v.5h.3M36.8 109.2v.6M37.2 109.2h.3M37.2 109v.6l.3 .2M37.8 109.3h.4v.4h-.4M37.8 109.2v.9"/>
<path d="M38.5 109.2v.4l.2 .2 .2-.1M38.9 109.2v.6M39.2 109.2h.3M39.4 109v.7l.1 .1"/>
</g>
<g fill="#fff">
<path d="M32.2 107.7h15.6v3.5h-15.6z"/>
<path d="M47.4 139.4h.4v1h-.4l-.4-.5z"/>
</g>
<path d="M47.4 139.4h.4v1h-.4l-.4-.5z" fill="none" stroke="#805e00" stroke-width=".21"/>
<g fill="none" stroke="#007170" stroke-width=".21">
<path d="M41.6 139.4v.9h.4M42.3 139.4v.9h.5M43.7 139.4v.1M43.7 139.7v.6M44.1 139.8h.3v.5M44.1 139.7v.6M44.9 139.8h.4v.4l-.4 .1M44.9 139.7v.9M45.6 139.7v.5h.5M46.1 139.7v.6M46.3 139.7h.3M46.5 139.4v.9h.1"/>
<path d="M42.8 140.4h.6"/>
</g>
<path d="M32.2 139.4h.4l.4 .5-.4 .5h-.4z" fill="#fff"/>
<path d="M32.2 139.4h.4l.4 .5-.4 .5h-.4z" fill="none" stroke="#805e00" stroke-width=".21"/>
<g fill="none" stroke="#007170" stroke-width=".21">
<path d="M33.3 139.2h6.2M33.4 139.4v.9M33.4 139.9h.5M33.9 139.4v.9M34.3 139.4v.9h.4M35.6 139.9l.2-.2 .3 .2v.4h-.4zM36.5 139.7v.6l.3-.1M36.8 139.7v.6M37.2 139.7h.3M37.2 139.4v.8l.3 .1M37.8 139.8h.4v.4l-.4 .1M37.8 139.7v.9"/>
<path d="M38.5 139.7v.5h.4M38.9 139.7v.6M39.2 139.7h.3M39.4 139.4v.9h.1"/>
</g>
<g fill="#fff">
<path d="M32.2 138.2h15.6v3.4h-15.6z"/>
<path d="M47.4 145.5h.4v1h-.4l-.4-.5z"/>
</g>
<path d="M47.4 145.5h.4v1h-.4l-.4-.5z" fill="none" stroke="#805e00" stroke-width=".21"/>
<g fill="none" stroke="#007170" stroke-width=".21">
<path d="M41.6 145.5v.9h.4M42.3 145.5v.9h.5M42.8 146.5h.6M43.7 145.5v.1M43.7 145.8v.6M44.1 145.9h.3v.5M44.1 145.8v.6M44.9 145.9h.4v.4l-.4 .1M44.9 145.8v.9M45.6 145.8v.5h.5M46.1 145.8v.6M46.3 145.8h.3"/>
<path d="M46.5 145.5v.9h.1"/>
</g>
<path d="M32.2 145.5h.4l.4 .5-.4 .5h-.4z" fill="#fff"/>
<path d="M32.2 145.5h.4l.4 .5-.4 .5h-.4z" fill="none" stroke="#805e00" stroke-width=".21"/>
<g fill="none" stroke="#007170" stroke-width=".21">
<path d="M33.3 145.3h6.2M33.4 145.5v.9M33.4 146h.5M33.9 145.5v.9M34.3 145.5v.9h.4M35.6 146l.2-.2 .3 .2v.4h-.4zM36.5 145.8v.6l.3-.1M36.8 145.8v.6M37.2 145.8h.3M37.2 145.5v.8l.3 .1M37.8 145.9h.4v.4l-.4 .1M37.8 145.8v.9"/>
<path d="M38.5 145.8v.5h.4M38.9 145.8v.6M39.2 145.8h.3M39.4 145.5v.9h.1"/>
</g>
<g fill="#fff">
<path d="M32.2 144.3h15.6v3.4h-15.6z"/>
<path d="M47 133.8l.4-.5h.4v1h-.4z"/>
</g>
<path d="M47.4 133.3h.4v1h-.4l-.4-.5z" fill="none" stroke="#805e00" stroke-width=".21"/>
<g fill="none" stroke="#007170" stroke-width=".21">
<path d="M41.6 133.3v.9h.4M42.3 133.3v.9h.5M42.8 134.3h.6M43.7 133.3v.1M43.7 133.6v.6M44.1 133.7h.3v.5M44.1 133.6v.6M44.9 133.7h.4v.4l-.4 .1M44.9 133.6v.9M45.6 133.6v.5h.5M46.1 133.6v.6M46.3 133.6h.3"/>
<path d="M46.5 133.3v.9h.1"/>
</g>
<path d="M32.2 133.3h.4l.4 .5-.4 .5h-.4z" fill="#fff"/>
<path d="M32.2 133.3h.4l.4 .5-.4 .5h-.4z" fill="none" stroke="#805e00" stroke-width=".21"/>
<g fill="none" stroke="#007170" stroke-width=".21">
<path d="M33.3 133.1h6.2M33.4 133.3v.9M33.4 133.8h.5M33.9 133.3v.9M34.3 133.3v.9h.4M35.8 133.6l.3 .2v.4h-.4l-.1-.2zM36.5 133.6v.6l.3-.1M36.8 133.6v.6M37.2 133.6h.3M37.2 133.3v.8l.3 .1M37.8 133.7h.4v.4l-.4 .1M37.8 133.6v.9"/>
<path d="M38.5 133.6v.5h.4M38.9 133.6v.6M39.2 133.6h.3M39.4 133.3v.9h.1"/>
</g>
<g fill="#fff">
<path d="M32.2 132.1h15.6v3.4h-15.6z"/>
<path d="M47 158.2l.4-.4h.4v.9h-.4z"/>
</g>
<path d="M47.4 157.8h.4v.9h-.4l-.4-.5z" fill="none" stroke="#805e00" stroke-width=".21"/>
<path d="M41.6 157.7v.9h.4M42.3 157.7v.9h.5M42.8 158.7h.6M43.7 157.7v.1M43.7 158.1v.5M44.1 158.2l.3-.1v.5M44.1 158.1v.5M44.9 158.6l.4-.1-.1-.4h-.3v.8M45.6 158.1l.1 .5 .4-.1M46.1 158.1v.5M46.3 158.1h.3M46.5 157.7v.9h.1" fill="none" stroke="#007170" stroke-width=".21"/>
<path d="M32.2 157.8h.4l.4 .4-.4 .5h-.4z" fill="#fff"/>
<path d="M32.2 157.8h.4l.4 .4-.4 .5h-.4z" fill="none" stroke="#805e00" stroke-width=".21"/>
<g fill="none" stroke="#007170" stroke-width=".21">
<path d="M33.3 157.5h6.2M33.4 157.7v.9M33.4 158.2h.5M33.9 157.7v.9M34.3 157.7v.9h.4M35.7 158.1h.4v.5l-.5-.1zM36.5 158.1v.5l.3-.1M36.8 158.1v.5M37.2 158.1h.3M37.2 157.7v.8l.3 .1M37.8 158.6l.4-.1-.1-.4h-.3v.8M38.5 158.1l.1 .5 .3-.1"/>
<path d="M38.9 158.1v.5M39.2 158.1h.3M39.4 157.7v.9h.1"/>
</g>
<g fill="#fff">
<path d="M32.2 156.5h15.6v3.4h-15.6z"/>
<path d="M47 152.1l.4-.4h.4v.9h-.4z"/>
</g>
<path d="M47 152.1l.4-.4h.4v.9h-.4z" fill="none" stroke="#805e00" stroke-width=".21"/>
<path d="M41.6 151.6v.9h.4M42.3 151.6v.9h.5M42.8 152.6h.6M43.7 151.6v.1M43.7 152v.5M44.1 152.1l.3-.1v.5M44.1 152v.5M44.9 152.5l.4-.1-.1-.4h-.3v.8M45.6 152v.4h.5M46.1 152v.5M46.3 152h.3M46.5 151.6v.9h.1" fill="none" stroke="#007170" stroke-width=".21"/>
<path d="M32.2 151.7h.4l.4 .4-.4 .5h-.4z" fill="#fff"/>
<path d="M32.2 151.7h.4l.4 .4-.4 .5h-.4z" fill="none" stroke="#805e00" stroke-width=".21"/>
<g fill="none" stroke="#007170" stroke-width=".21">
<path d="M33.3 151.4h6.2M33.4 151.6v.9M33.4 152.1h.5M33.9 151.6v.9M34.3 151.6v.9h.4M35.7 152l.4 .1v.4h-.4zM36.5 152v.5l.3-.1M36.8 152v.5M37.2 152h.3M37.2 151.6v.8l.3 .1M37.8 152.5l.4-.1-.1-.4h-.3v.8M38.5 152v.4h.4"/>
<path d="M38.9 152v.5M39.2 152h.3M39.4 151.6v.9h.1"/>
</g>
<g fill="#fff">
<path d="M32.2 150.4h15.6v3.4h-15.6z"/>
<path d="M47 164.3l.4-.4h.4v.9h-.4z"/>
</g>
<path d="M47.4 163.9h.4v.9h-.4l-.4-.5z" fill="none" stroke="#805e00" stroke-width=".21"/>
<path d="M41.6 163.8v1h.4M42.3 163.8v1h.5M42.8 164.8h.6M43.7 163.8v.1M43.7 164.2v.6M44.1 164.2h.3v.6M44.1 164.2v.6M44.9 164.7h.4l-.1-.5h-.3v.8M45.6 164.2v.4l.2 .2 .3-.1M46.1 164.2v.6M46.3 164.2h.3M46.5 163.8v.9l.1 .1" fill="none" stroke="#007170" stroke-width=".21"/>
<path d="M32.2 163.9h.4l.4 .4-.4 .5h-.4z" fill="#fff"/>
<path d="M32.2 163.9h.4l.4 .4-.4 .5h-.4z" fill="none" stroke="#805e00" stroke-width=".21"/>
<g fill="none" stroke="#007170" stroke-width=".21">
<path d="M33.3 163.6h6.2M33.4 163.8v1M33.4 164.2h.5M33.9 163.8v1M34.3 163.8v1h.4M35.7 164.2h.4v.1l-.1 .5-.4-.2zM36.5 164.2v.5h.3M36.8 164.2v.6M37.2 164.2h.3M37.2 163.8v.8l.3 .2M37.8 164.7h.4l-.1-.5h-.3v.8M38.5 164.2v.4l.2 .2 .2-.1"/>
<path d="M38.9 164.2v.6M39.2 164.2h.3M39.4 163.8v.9l.1 .1"/>
</g>
<g fill="#fff">
<path d="M32.2 162.6h15.6v3.4h-15.6z"/>
<path d="M47.4 170h.4v.9h-.4l-.4-.5z"/>
</g>
<path d="M47.4 170h.4v.9h-.4l-.4-.5z" fill="none" stroke="#805e00" stroke-width=".21"/>
<path d="M41.6 169.9v1h.4M42.3 169.9v1h.5M42.8 170.9h.6M43.7 169.9v.1M43.7 170.3v.6M44.1 170.3h.3v.6M44.1 170.3v.6M44.9 170.8h.4l-.1-.5h-.3v.8M45.6 170.3v.4l.2 .2 .3-.1M46.1 170.3v.6M46.3 170.3h.3M46.5 169.9v.9l.1 .1" fill="none" stroke="#007170" stroke-width=".21"/>
<path d="M32.2 170h.4l.4 .4-.4 .5h-.4z" fill="#fff"/>
<path d="M32.2 170h.4l.4 .4-.4 .5h-.4z" fill="none" stroke="#805e00" stroke-width=".21"/>
<g fill="none" stroke="#007170" stroke-width=".21">
<path d="M33.3 169.7h6.2M33.4 169.9v1M33.4 170.3h.5M33.9 169.9v1M34.3 169.9v1h.4M35.7 170.3h.4v.1l-.1 .5-.4-.2zM36.5 170.3v.5h.3M36.8 170.3v.6M37.2 170.3h.3M37.2 169.9v.8l.3 .2M37.8 170.8h.4l-.1-.5h-.3v.8M38.5 170.3v.4l.2 .2 .2-.1"/>
<path d="M38.9 170.3v.6M39.2 170.3h.3M39.4 169.9v.9l.1 .1"/>
</g>
<g fill="#fff">
<path d="M32.2 168.7h15.6v3.5h-15.6z"/>
<path d="M244.9 37.5h.4l.4 .4-.4 .4h-.4z"/>
</g>
<path d="M244.9 37.5h.4l.4 .4-.4 .4h-.4z" fill="none" stroke="#805e00" stroke-width=".21"/>
<path d="M239.2 37.4h.6l-.4 .4 .4 .1v.3l-.2 .1h-.4M239.9 37.4l.4 .9 .2-.9M240.8 37.4h.5l-.3 .4h.3v.5h-.5M241.5 38.4h.6M242.5 37.4a.47 .47 0 0 1 .4 .5 .47 .47 0 0 1-.4 .4l-.2-.1v-.6zM243.2 37.4v.8l.2 .1h.3v-.9M244.1 37.4h.4M244.3 37.4v.9" fill="none" stroke="#007170" stroke-width=".21"/>
<path d="M218.7 37.5h.4l.4 .4-.4 .4h-.4z" fill="#fff"/>
<path d="M218.7 37.5h.4l.4 .4-.4 .4h-.4z" fill="none" stroke="#805e00" stroke-width=".21"/>
<path d="M219.8 37.4l.3 .9 .3-.9M220.5 38.4h.6M221.4 37.4v.9M222.2 37.4v.9l-.4-.9v.9" fill="none" stroke="#007170" stroke-width=".21"/>
<path d="M218.7 36.1h27v3.6h-27z" fill="#c9c9c9"/>
<path d="M216.1 48.8h.4l.4 .5-.4 .4h-.4z" fill="#fff"/>
<path d="M216.1 48.8h.4l.4 .5-.4 .4h-.4z" fill="none" stroke="#805e00" stroke-width=".21"/>
<path d="M217.3 49.3h.4l.1-.2-.1-.3h-.4v.8M217.6 49.3l.2 .3M218.2 49.4l.4-.1-.1-.2h-.3v.5h.3M219.3 49.1h-.4v.3h.4v.2h-.4M219.5 49.7h.6M220.8 48.8h-.2l-.3 .2v.4l.2 .2h.3v-.3h-.2M221.7 48.8v.8l-.5-.8v.8M222.1 48.8h.2l.3 .2v.4l-.2 .2h-.3z" fill="none" stroke="#007170" stroke-width=".21"/>
<path d="M233.5 48.3l.4-.4h.5v.9h-.5z" fill="#fff"/>
<path d="M233.9 47.9h.5v.9h-.5l-.4-.5z" fill="none" stroke="#805e00" stroke-width=".21"/>
<path d="M228.7 48.3h.4l.1-.3-.5-.1v.9M228.9 48.3l.3 .5M229.5 48.5l.4-.1-.1-.2-.3 .1v.5h.4M230.6 48.3h-.3l.1 .2h.2v.3h-.3M230.8 48.8h.7M231.7 47.9h.4l.1 .3-.1 .6-.5-.1zM233.1 47.9v.9l-.5-.9v.9" fill="none" stroke="#007170" stroke-width=".21"/>
<path d="M216.1 47.5h18.3v2.6h-18.3z" fill="#0ff"/>
<path d="M198.6 20.9h.4l.5 .4-.5 .5h-.4z" fill="#fff"/>
<path d="M198.6 20.9h.4l.5 .4-.5 .5h-.4z" fill="none" stroke="#805e00" stroke-width=".21"/>
<g fill="none" stroke="#007170" stroke-width=".21">
<path d="M188.4 21.3h.4v-.4h-.4v.9M189.2 21.2h.4v.6l-.4-.1zM190 21.2l.2 .6 .1-.5 .2 .5 .2-.6M190.9 21.5l.4-.1-.1-.2h-.3v.6h.4M191.7 21.2v.6M191.9 21.2l-.2 .1M192 21.8h.7M193.4 20.9l-.5 .1v.2l.5 .3-.1 .3h-.4M193.6 21.2l.2 .6 .2-.5 .1 .5 .2-.6M194.6 20.9v.1M194.6 21.2v.6M195 21.2h.2"/>
<path d="M195.1 20.9v.9h.1M195.9 21.2h-.2l-.2 .1 .1 .5h.3M196.3 21.2h.4v.6M196.3 20.9v.9M197.1 21.5l.3-.1v-.2h-.3v.6h.3M198.2 20.9v.9h-.3l-.1-.5 .1-.1h.3"/>
</g>
<path d="M175.9 20.9h.5l.5 .4-.5 .5h-.5z" fill="#fff"/>
<path d="M175.9 20.9h.5l.5 .4-.5 .5h-.5z" fill="none" stroke="#805e00" stroke-width=".21"/>
<path d="M177.2 21.3h.4l.1-.3-.5-.1v.9M178.2 21.2l.4 .1-.1 .5h-.4l-.1-.2zM178.8 21.2l.2 .6 .1-.5 .2 .5 .2-.6M179.7 21.5l.5-.1-.1-.2-.4 .1v.4l.5 .1M180.6 21.2v.6M180.8 21.2l-.2 .1M180.9 21.8h.6M181.8 20.9v.9M182.2 21.2h.3v.6M182.2 21.2v.6" fill="none" stroke="#007170" stroke-width=".21"/>
<path d="M175.9 22.7h.5l.5 .4-.5 .4h-.5z" fill="#fff"/>
<path d="M175.9 22.7h.5l.5 .4-.5 .4h-.5z" fill="none" stroke="#805e00" stroke-width=".21"/>
<g fill="none" stroke="#007170" stroke-width=".21">
<path d="M177.2 23.1l.5-.1v-.3l-.5-.1v.9M178.1 22.9h.4l.1 .2-.2 .4-.4-.1zM178.8 22.9l.2 .6 .1-.4 .2 .4 .2-.6M179.7 23.2l.5-.1v-.2l-.5 .1v.4l.2 .1 .3-.1M180.6 22.9v.6M180.8 22.9l-.2 .2M180.9 23.6h.6M181.9 22.6l.4 .2v.6l-.2 .1a.49 .49 0 0 1-.4-.4 .49 .49 0 0 1 .2-.5zM182.7 23l.3-.1v.6M182.7 22.9v.6M184.1 22.6l-.7 1.1M184.2 22.3h1.8"/>
<path d="M184.6 22.6l.3 .2v.6l-.2 .1a.49 .49 0 0 1-.4-.4 .49 .49 0 0 1 .3-.5zM185.2 22.9h.3M185.5 22.6l-.2 .1v.8M185.7 22.9h.3M186 22.6l-.2 .2v.7"/>
</g>
<path d="M175.9 19.6h23.6v5.2h-23.6z" fill="#c9c9c9"/>
<path d="M218.7 22.7h.4l.4 .4-.4 .4h-.4z" fill="#fff"/>
<path d="M218.7 22.7h.4l.4 .4-.4 .4h-.4z" fill="none" stroke="#805e00" stroke-width=".21"/>
<path d="M220.4 22.6h-.4l-.1 .4h.5v.4h-.5M220.6 22.6l.4 .9 .2-.9M221.3 23.6h.7M222.2 23h.3M222.6 22.6h-.4v.9h.4M223.5 22.6v.9l-.5-.9v.9" fill="none" stroke="#007170" stroke-width=".21"/>
<path d="M244.9 20.9h.4l.4 .4-.4 .5h-.4z" fill="#fff"/>
<path d="M244.9 20.9h.4l.4 .4-.4 .5h-.4z" fill="none" stroke="#805e00" stroke-width=".21"/>
<path d="M240.5 20.9h-.4l-.1 .4 .4-.1 .1 .5h-.5M240.8 20.9l.3 .9 .3-.9M241.5 21.8h.6M242.3 21h.5l.1 .5-.2 .3-.4-.1zM243.2 20.9l.1 .9 .4-.1v-.8M244.1 20.9h.4M244.3 20.9v.9" fill="none" stroke="#007170" stroke-width=".21"/>
<path d="M218.7 20.9h.4l.4 .4-.4 .5h-.4z" fill="#fff"/>
<path d="M218.7 20.9h.4l.4 .4-.4 .5h-.4z" fill="none" stroke="#805e00" stroke-width=".21"/>
<path d="M219.8 20.9l.3 .9 .3-.9M220.5 21.8h.6M221.4 20.9v.9M222.2 20.9v.9l-.4-.9v.9" fill="none" stroke="#007170" stroke-width=".21"/>
<path d="M218.7 19.6h27v5.2h-27z" fill="#c9c9c9"/>
<path d="M216.1 103.7h.4l.4 .4-.4 .5h-.4z" fill="#fff"/>
<path d="M216.1 103.7h.4l.4 .4-.4 .5h-.4z" fill="none" stroke="#805e00" stroke-width=".21"/>
<path d="M217.3 104.1h.5v-.4h-.5v.9M217.6 104.1l.2 .5M218.2 104.3l.4-.1-.2-.2h-.2v.6h.3M219.3 104h-.4l.1 .3h.3v.3h-.4M219.5 104.6h.6M220.8 103.7h-.3l-.2 .2v.5l.2 .2h.3v-.4h-.2M221.7 103.7v.9l-.5-.9v.9M222.1 103.7h.3l.2 .2v.5l-.2 .2h-.3z" fill="none" stroke="#007170" stroke-width=".21"/>
<path d="M233.9 102.9h.5v.8h-.5l-.4-.4z" fill="#fff"/>
<path d="M233.9 102.9h.5v.8h-.5l-.4-.4z" fill="none" stroke="#805e00" stroke-width=".21"/>
<path d="M228.7 103.3l.5-.1v-.3h-.5v.8M228.9 103.3l.3 .4M229.5 103.4l.4-.1v-.2h-.4v.5h.4M230.6 103.1h-.3v.3l.3 .1-.1 .2-.2-.1M230.8 103.8h.7M231.6 102.9h.6a.47 .47 0 0 1-.4 .8l-.2-.2zM233.1 102.9v.8l-.5-.8v.8" fill="none" stroke="#007170" stroke-width=".21"/>
<path d="M216.1 102.4h18.3v2.7h-18.3z" fill="#0ff"/>
<path d="M216.1 97.6h.4l.4 .4-.4 .5h-.4z" fill="#fff"/>
<path d="M216.1 97.6h.4l.4 .4-.4 .5h-.4z" fill="none" stroke="#805e00" stroke-width=".21"/>
<path d="M217.3 98h.5v-.4h-.5v.9M217.6 98l.2 .5M218.2 98.2l.4-.1-.2-.2-.2 .1v.5h.3M219.3 98h-.4l.1 .2h.3v.3h-.4M219.5 98.5h.6M220.8 97.6h-.3l-.2 .2v.5l.2 .2h.3v-.4h-.2M221.7 97.6v.9l-.5-.9v.9M222.1 97.6h.3l.2 .2v.5l-.2 .2h-.3z" fill="none" stroke="#007170" stroke-width=".21"/>
<path d="M233.9 96.8h.5v.8h-.5l-.4-.4z" fill="#fff"/>
<path d="M233.9 96.8h.5v.8h-.5l-.4-.4z" fill="none" stroke="#805e00" stroke-width=".21"/>
<path d="M228.7 97.2l.5-.1v-.3l-.5-.1v.9M228.9 97.2l.3 .4M229.5 97.3l.4-.1v-.2h-.4v.5h.4M230.6 97h-.3v.3h.2l.1 .2h-.3M230.8 97.7h.7M231.8 96.7a.47 .47 0 0 1 .5 .4 .47 .47 0 0 1-.5 .5l-.2-.2v-.5zM233.1 96.7v.9l-.5-.9v.9" fill="none" stroke="#007170" stroke-width=".21"/>
<path d="M216.1 96.3h18.3v2.7h-18.3z" fill="#0ff"/>
<path d="M216.1 91.5h.4l.4 .4-.4 .5h-.4z" fill="#fff"/>
<path d="M216.1 91.5h.4l.4 .4-.4 .5h-.4z" fill="none" stroke="#805e00" stroke-width=".21"/>
<path d="M217.3 91.9h.5v-.4h-.5v.9M217.6 91.9l.2 .5M218.2 92.1l.4-.1-.2-.2-.2 .1v.4h.3M219.3 91.9h-.4l.1 .2h.3l-.1 .3-.3-.1M219.5 92.5h.6M220.8 91.5h-.3l-.2 .2 .1 .6h.4v-.3h-.2M221.7 91.5v.9l-.5-.9v.9M222.1 91.5h.3l.2 .2v.5l-.3 .2h-.2z" fill="none" stroke="#007170" stroke-width=".21"/>
<path d="M233.9 90.7h.5v.8h-.5l-.4-.4z" fill="#fff"/>
<path d="M233.9 90.7h.5v.8h-.5l-.4-.4z" fill="none" stroke="#805e00" stroke-width=".21"/>
<path d="M228.7 91.1l.5-.1v-.3l-.5-.1v.9M228.9 91.1l.3 .4M229.5 91.2l.4-.1v-.2h-.4v.5h.4M230.6 90.9h-.3v.3h.2l.1 .2h-.3M230.8 91.6h.7M231.8 90.6a.47 .47 0 0 1 .5 .5 .47 .47 0 0 1-.5 .4l-.2-.2v-.5zM233.1 90.6v.9l-.5-.9v.9" fill="none" stroke="#007170" stroke-width=".21"/>
<path d="M216.1 90.2h18.3v2.7h-18.3z" fill="#0ff"/>
<path d="M216.1 54.9h.4l.4 .5-.4 .4h-.4z" fill="#fff"/>
<path d="M216.1 54.9h.4l.4 .5-.4 .4h-.4z" fill="none" stroke="#805e00" stroke-width=".21"/>
<path d="M217.3 55.4h.4l.1-.2-.1-.3h-.4v.9M217.6 55.4l.2 .4M218.2 55.5l.4-.1-.1-.2h-.3v.5h.3M219.3 55.2h-.4v.3h.4l-.1 .3-.3-.1M219.5 55.9h.6M220.8 54.9h-.2l-.3 .2v.4l.3 .3 .2-.1v-.3h-.2M221.7 54.9v.9l-.5-.9v.9M222.1 54.9h.2l.3 .2v.4l-.3 .3h-.2z" fill="none" stroke="#007170" stroke-width=".21"/>
<path d="M233.9 54h.5v.9h-.5l-.4-.4z" fill="#fff"/>
<path d="M233.9 54h.5v.9h-.5l-.4-.4z" fill="none" stroke="#805e00" stroke-width=".21"/>
<path d="M228.7 54.4h.4l.1-.3-.5-.1v.9M228.9 54.4l.3 .5M229.5 54.6l.4-.1-.1-.2-.3 .1v.5h.4M230.6 54.4h-.3l.1 .2h.2v.3h-.3M230.8 54.9h.7M231.6 54.1h.6v.5l-.1 .3-.5-.1zM233.1 54v.9l-.5-.9v.9" fill="none" stroke="#007170" stroke-width=".21"/>
<path d="M216.1 53.6h18.3v2.6h-18.3z" fill="#0ff"/>
<path d="M216.1 61h.4l.4 .5-.4 .4h-.4z" fill="#fff"/>
<path d="M216.1 61h.4l.4 .5-.4 .4h-.4z" fill="none" stroke="#805e00" stroke-width=".21"/>
<path d="M217.3 61.5h.4l.1-.2-.1-.3h-.4v.9M217.6 61.5l.2 .4M218.2 61.5h.4l-.1-.2h-.3v.5h.3M219.3 61.3h-.4v.2l.4 .1-.1 .3-.3-.1M219.5 62h.6M220.8 61h-.2l-.3 .2v.4l.3 .3 .2-.1v-.3h-.2M221.7 61v.9l-.5-.9v.9M222.1 61h.2l.3 .2v.4l-.3 .3h-.2z" fill="none" stroke="#007170" stroke-width=".21"/>
<path d="M233.9 60.1h.5v.9h-.5l-.4-.4z" fill="#fff"/>
<path d="M233.9 60.1h.5v.9h-.5l-.4-.4z" fill="none" stroke="#805e00" stroke-width=".21"/>
<path d="M228.7 60.5h.4l.1-.3-.5-.1v.9M228.9 60.5l.3 .5M229.5 60.7l.4-.1-.1-.2h-.3v.6h.4M230.6 60.4h-.3l.1 .3h.2v.3h-.3M230.8 61h.7M231.8 60.1l.4 .3-.1 .6-.5-.1v-.6zM233.1 60.1v.9l-.5-.9v.9" fill="none" stroke="#007170" stroke-width=".21"/>
<path d="M216.1 59.7h18.3v2.6h-18.3z" fill="#0ff"/>
<path d="M216.1 67.1h.4l.4 .5-.4 .4h-.4z" fill="#fff"/>
<path d="M216.1 67.1h.4l.4 .5-.4 .4h-.4z" fill="none" stroke="#805e00" stroke-width=".21"/>
<path d="M217.3 67.6h.4l.1-.4-.1-.1h-.4v.9M217.6 67.6l.2 .4M218.2 67.6h.4l-.1-.2h-.3v.5h.3M219.3 67.4h-.4v.2l.4 .1-.1 .3-.3-.1M219.5 68.1h.6M220.8 67.1h-.2l-.3 .2v.4l.3 .3 .2-.1v-.3h-.2M221.7 67.1v.9l-.5-.9v.9M222.1 67.1h.2l.3 .2v.4l-.3 .3h-.2z" fill="none" stroke="#007170" stroke-width=".21"/>
<path d="M233.5 66.7l.4-.4h.5v.8h-.5z" fill="#fff"/>
<path d="M233.9 66.3h.5v.8h-.5l-.4-.4z" fill="none" stroke="#805e00" stroke-width=".21"/>
<path d="M228.7 66.6h.5v-.3l-.5-.1v.9M228.9 66.6l.3 .5M229.5 66.8l.4-.1v-.2h-.4v.6h.4M230.6 66.5h-.3l.1 .3h.2v.3h-.3M230.8 67.1h.7M231.8 66.2a.47 .47 0 0 1 .4 .3 .47 .47 0 0 1-.1 .6l-.5-.1v-.6zM233.1 66.2v.9l-.5-.9v.9" fill="none" stroke="#007170" stroke-width=".21"/>
<path d="M216.1 65.8h18.3v2.6h-18.3z" fill="#0ff"/>
<path d="M216.1 85.4h.4l.4 .4-.4 .5h-.4z" fill="#fff"/>
<path d="M216.1 85.4h.4l.4 .4-.4 .5h-.4z" fill="none" stroke="#805e00" stroke-width=".21"/>
<path d="M217.3 85.8h.5v-.4h-.5v.9M217.6 85.8l.2 .5M218.2 85.9l.4-.1-.2-.1-.2 .1v.4h.3M219.3 85.8h-.4v.1l.4 .1-.1 .3-.3-.1M219.5 86.4h.6M220.8 85.4h-.3l-.2 .2v.4l.3 .3 .2-.1v-.4h-.2M221.7 85.4v.9l-.5-.9v.9M222.1 85.4h.3l.2 .2v.4l-.3 .3h-.2z" fill="none" stroke="#007170" stroke-width=".21"/>
<path d="M233.5 85l.4-.4h.5v.8h-.5z" fill="#fff"/>
<path d="M233.9 84.6h.5v.8h-.5l-.4-.4z" fill="none" stroke="#805e00" stroke-width=".21"/>
<path d="M228.7 85l.5-.1v-.3l-.5-.1v.9M228.9 85l.3 .4M229.5 85.1l.4-.1v-.2h-.4v.5h.4M230.6 84.8h-.3v.3l.3 .1-.1 .2-.2-.1M230.8 85.5h.7M231.8 84.5a.47 .47 0 0 1 .5 .5 .47 .47 0 0 1-.5 .4l-.2-.1v-.6zM233.1 84.5v.9l-.5-.9v.9" fill="none" stroke="#007170" stroke-width=".21"/>
<path d="M216.1 84.2h18.3v2.6h-18.3z" fill="#0ff"/>
<path d="M216.1 73.2h.4l.4 .5-.4 .4h-.4z" fill="#fff"/>
<path d="M216.1 73.2h.4l.4 .5-.4 .4h-.4z" fill="none" stroke="#805e00" stroke-width=".21"/>
<path d="M217.3 73.7h.4l.1-.4-.1-.2h-.4v1M217.6 73.7l.2 .4M218.2 73.7h.4l-.1-.2h-.3v.5h.3M219.3 73.5h-.4v.2l.4 .1-.1 .3-.3-.1M219.5 74.2h.6M220.8 73.2l-.2-.1-.3 .3v.4l.3 .3 .2-.1v-.3h-.2M221.7 73.1v1l-.5-1v1M222.1 73.1h.2l.3 .3v.4l-.3 .3h-.2z" fill="none" stroke="#007170" stroke-width=".21"/>
<path d="M233.9 72.4h.5v.8h-.5l-.4-.4z" fill="#fff"/>
<path d="M233.9 72.4h.5v.8h-.5l-.4-.4z" fill="none" stroke="#805e00" stroke-width=".21"/>
<path d="M228.7 72.8l.5-.1v-.3l-.5-.1v.8M228.9 72.8l.3 .3M229.5 72.9l.4-.1v-.2h-.4v.5h.4M230.6 72.6h-.3v.3h.2l.1 .2h-.3M230.8 73.2h.7M231.8 72.3a.47 .47 0 0 1 .4 .3 .47 .47 0 0 1-.1 .5h-.5v-.6zM233.1 72.3v.8l-.5-.8v.8" fill="none" stroke="#007170" stroke-width=".21"/>
<path d="M216.1 71.9h18.3v2.6h-18.3z" fill="#0ff"/>
<path d="M216.1 79.3h.4l.4 .5-.4 .4h-.4z" fill="#fff"/>
<path d="M216.1 79.3h.4l.4 .5-.4 .4h-.4z" fill="none" stroke="#805e00" stroke-width=".21"/>
<path d="M217.3 79.8h.4l.1-.2v-.3h-.5v.9M217.6 79.8l.2 .4M218.2 79.8h.4l-.1-.2h-.3v.5h.3M219.3 79.6h-.4v.2l.4 .1-.1 .3-.3-.1M220.8 79.3h-.3l-.2 .2v.4l.3 .3 .2-.1v-.3h-.2M221.7 79.3v.9l-.5-.9v.9M222.1 79.3h.3l.2 .2v.4l-.3 .3h-.2zM219.5 80.3h.6" fill="none" stroke="#007170" stroke-width=".21"/>
<path d="M233.9 78.5h.5v.8h-.5l-.4-.4z" fill="#fff"/>
<path d="M233.9 78.5h.5v.8h-.5l-.4-.4z" fill="none" stroke="#805e00" stroke-width=".21"/>
<path d="M228.7 78.9l.5-.1v-.3l-.5-.1v.9M228.9 78.9l.3 .4M229.5 79l.4-.1v-.2h-.4v.5h.4M230.6 78.7h-.3v.3l.3 .1-.1 .2-.2-.1M230.8 79.4h.7M231.8 78.4a.47 .47 0 0 1 .5 .5 .47 .47 0 0 1-.5 .4l-.2-.1v-.6zM233.1 78.4v.9l-.5-.9v.9" fill="none" stroke="#007170" stroke-width=".21"/>
<path d="M216.1 78.1h18.3v2.5h-18.3z" fill="#0ff"/>
<path d="M142.8 117.3h31.4v59.2h-31.4z" fill="#f1f1f1"/>
<path d="M141.6 116l33.8 61.7M175.4 116l-33.8 61.7" fill="none" stroke="#e00" stroke-width=".34"/>
<path d="M163.7 188.7h1.8v3.5h-1.8z" fill="#f1f1f1"/>
<path d="M183.4 131.4l6 2.2M189.4 131.4l-6 2.2M196.5 153.5l.7 .6M196.5 156.9l.7 .8M197.2 153.5l-.7 .6M197.2 156.9l-.7 .8M131.4 181.2l3.6 4.5M131.4 187.3l3.6 4.5M135 181.2l-3.6 4.5M135 187.3l-3.6 4.5M161.9 188.1l5.4 4.6M167.3 188.1l-5.4 4.6" fill="none" stroke="#e00" stroke-width=".34"/>
<path d="M212.6 146.9h1.7v3.5h-1.7z" fill="#f1f1f1"/>
<path d="M210.8 146.3l5.2 4.6M216 146.3l-5.2 4.6M254 143.9l.7 .7M254.7 143.9l-.7 .7M268 143.9l.7 .7M268.7 143.9l-.7 .7" fill="none" stroke="#e00" stroke-width=".34"/>
<path d="M87 130.3h17.5v31.4h-17.5z" fill="#fffec7"/>
<path d="M210.4 14.9l.7 .6M211.1 14.9l-.7 .6M248.8 16.6l.7 .7M249.5 16.6l-.7 .7M248.8 33.1l.7 .8M249.5 33.1l-.7 .8M202.6 54.1l.7 .7M203.3 54.1l-.7 .7M108.5 180.1l5.8 3.2M114.3 180.1l-5.8 3.2" fill="none" stroke="#e00" stroke-width=".34"/>
<path d="M248.3 78.1h17.5v31.3h-17.5z" fill="#fffec7"/>
<path d="M70.5 44h5.2v1.8h-5.2z" fill="#f1f1f1"/>
<path d="M69.5 42.2l7.1 5.2M76.6 42.2l-7.1 5.2" fill="none" stroke="#e00" stroke-width=".34"/>
<path d="M105.3 44.9h5.3v1.7h-5.3z" fill="#f1f1f1"/>
<path d="M104.3 43.1l7.2 5.3M111.5 43.1l-7.2 5.3" fill="none" stroke="#e00" stroke-width=".34"/>
<path d="M34.7 17h3.6v20.9h-3.6z" fill="#f1f1f1"/>
<path d="M33 16.4l6.9 22.1M39.9 16.4l-6.9 22.1" fill="none" stroke="#e00" stroke-width=".34"/>
<path d="M33.9 44h5.2v1.8h-5.2z" fill="#f1f1f1"/>
<path d="M32.9 42.2l7.1 5.2M40 42.2l-7.1 5.2" fill="none" stroke="#e00" stroke-width=".34"/>
<path d="M87.9 19.6h3.5v3.5h-3.5z" fill="#f1f1f1"/>
<g fill="none" stroke="#e00" stroke-width=".34">
<path d="M33 16.4l6.9 22.1M39.9 16.4l-6.9 22.1M86.1 19l7 4.7M93.1 19l-7 4.7M210.4 14.9l.7 .6M211.1 14.9l-.7 .6M248.8 16.6l.7 .7M249.5 16.6l-.7 .7M248.8 33.1l.7 .8M249.5 33.1l-.7 .8M32.9 42.2l7.1 5.2M40 42.2l-7.1 5.2"/>
<path d="M69.5 42.2l7.1 5.2M76.6 42.2l-7.1 5.2M104.3 43.1l7.2 5.3M111.5 43.1l-7.2 5.3M202.6 54.1l.7 .7M203.3 54.1l-.7 .7M141.6 116l33.8 61.7M175.4 116l-33.8 61.7M183.4 131.4l6 2.2M189.4 131.4l-6 2.2M196.5 153.5l.7 .6M196.5 156.9l.7 .8"/>
<path d="M197.2 153.5l-.7 .6M197.2 156.9l-.7 .8M210.8 146.3l5.2 4.6M216 146.3l-5.2 4.6M254 143.9l.7 .7M254.7 143.9l-.7 .7M268 143.9l.7 .7M268.7 143.9l-.7 .7M108.5 180.1l5.8 3.2M114.3 180.1l-5.8 3.2M131.4 181.2l3.6 4.5M131.4 187.3l3.6 4.5"/>
<path d="M135 181.2l-3.6 4.5M135 187.3l-3.6 4.5M161.9 188.1l5.4 4.6M167.3 188.1l-5.4 4.6"/>
</g>
<path d="M216.1 128.2h.4l.4 .4-.4 .4h-.4z" fill="#fff"/>
<path d="M216.1 128.2h.4l.4 .4-.4 .4h-.4z" fill="none" stroke="#805e00" stroke-width=".21"/>
<path d="M217.3 128.6h.4l.1-.3-.1-.2h-.4v.8M217.6 128.6l.2 .3M218.2 128.7l.4-.1-.1-.2h-.3v.5h.3M219.3 128.4h-.4l.1 .3h.3v.2h-.4M219.5 129h.6M220.8 128.2l-.2-.1-.3 .2v.5l.2 .1h.3v-.3h-.2M221.7 128.1v.8l-.5-.8v.8M222.1 128.1h.2l.3 .2v.5l-.2 .1h-.3z" fill="none" stroke="#007170" stroke-width=".21"/>
<path d="M233.5 127.7l.4-.5h.5v1h-.5z" fill="#fff"/>
<path d="M233.9 127.2h.5v1h-.5l-.4-.5z" fill="none" stroke="#805e00" stroke-width=".21"/>
<path d="M228.7 127.7h.4l.1-.4-.5-.1v.9M228.9 127.7l.3 .4M229.5 127.8h.4l-.1-.3-.3 .1v.5h.4M230.6 127.6h-.3l.1 .2h.2v.3h-.3M230.8 128.2h.7M231.6 127.3h.6v.5l-.1 .3-.5-.1zM233.1 127.2v.9l-.5-.9v.9" fill="none" stroke="#007170" stroke-width=".21"/>
<path d="M216.1 126.8h18.3v2.6h-18.3z" fill="none" stroke="#980000" stroke-width=".21"/>
<path d="M216.1 140.4h.4l.4 .4-.4 .4h-.4z" fill="#fff"/>
<path d="M216.1 140.4h.4l.4 .4-.4 .4h-.4z" fill="none" stroke="#805e00" stroke-width=".21"/>
<path d="M217.3 140.8h.4l.1-.3-.1-.2h-.4v.9M217.6 140.8l.2 .4M218.2 140.9l.4-.1-.1-.2h-.3v.5h.3M219.3 140.6h-.4v.3l.4 .1-.1 .2-.3-.1M219.5 141.3h.6M220.8 140.4l-.2-.1-.3 .2v.5l.3 .2 .2-.1v-.3h-.2M221.7 140.3v.9l-.5-.9v.9M222.1 140.3h.2l.3 .2v.5l-.3 .2h-.2z" fill="none" stroke="#007170" stroke-width=".21"/>
<path d="M233.9 139.4h.5v1h-.5l-.4-.5z" fill="#fff"/>
<path d="M233.9 139.4h.5v1h-.5l-.4-.5z" fill="none" stroke="#805e00" stroke-width=".21"/>
<path d="M228.7 139.9h.4l.1-.4-.5-.1v.9M228.9 139.9l.3 .4M230.6 139.8h-.3l.1 .2h.2v.3h-.3M231.7 139.4h.4l.1 .3-.1 .6-.5-.1zM233.1 139.4v.9l-.5-.9v.9M229.5 140l.4-.1-.1-.2-.3 .1v.5h.4M230.8 140.4h.7" fill="none" stroke="#007170" stroke-width=".21"/>
<path d="M216.1 139h18.3v2.6h-18.3z" fill="none" stroke="#980000" stroke-width=".21"/>
<path d="M216.1 134.3h.4l.4 .4-.4 .4h-.4z" fill="#fff"/>
<path d="M216.1 134.3h.4l.4 .4-.4 .4h-.4z" fill="none" stroke="#805e00" stroke-width=".21"/>
<path d="M217.3 134.7h.4l.1-.3-.1-.2h-.4v.8M217.6 134.7l.2 .3M218.2 134.8l.4-.1-.1-.2h-.3v.5h.3M219.3 134.5h-.4v.3h.3l.1 .2h-.4M219.5 135.1h.6M220.8 134.3l-.2-.1-.3 .2v.5l.2 .1h.3v-.3h-.2M221.7 134.2v.8l-.5-.8v.8M222.1 134.2h.2l.3 .2v.5l-.2 .1h-.3z" fill="none" stroke="#007170" stroke-width=".21"/>
<path d="M233.5 133.8l.4-.5h.5v1h-.5z" fill="#fff"/>
<path d="M233.9 133.3h.5v1h-.5l-.4-.5z" fill="none" stroke="#805e00" stroke-width=".21"/>
<path d="M228.7 133.8h.4l.1-.4-.5-.1v.9M228.9 133.8l.3 .4M229.5 133.9h.4l-.1-.3-.3 .1v.5h.4M230.6 133.7h-.3l.1 .2h.2v.3h-.3M230.8 134.3h.7M231.6 133.4h.6v.5l-.1 .3-.5-.1zM233.1 133.3v.9l-.5-.9v.9" fill="none" stroke="#007170" stroke-width=".21"/>
<path d="M216.1 132.9h18.3v2.6h-18.3z" fill="none" stroke="#980000" stroke-width=".21"/>
<path d="M216.1 115.9h.4l.4 .5-.4 .4h-.4z" fill="#fff"/>
<path d="M216.1 115.9h.4l.4 .5-.4 .4h-.4z" fill="none" stroke="#805e00" stroke-width=".21"/>
<path d="M217.3 116.3h.5v-.4h-.5v.8M217.6 116.3l.2 .4M218.2 116.5l.4-.1-.2-.2h-.2v.5h.3M219.3 116.2h-.4l.1 .3h.3v.2h-.4M219.5 116.8h.6M220.8 115.9h-.3l-.2 .2v.5l.2 .1h.3v-.3h-.2M221.7 115.9v.8l-.5-.8v.8M222.1 115.9h.3l.2 .2v.5l-.2 .1h-.3z" fill="none" stroke="#007170" stroke-width=".21"/>
<path d="M233.5 115.5l.4-.4h.5v.8h-.5z" fill="#fff"/>
<path d="M233.9 115.1h.5v.8h-.5l-.4-.4z" fill="none" stroke="#805e00" stroke-width=".21"/>
<path d="M228.7 115.5h.4l.1-.4h-.5v.8M228.9 115.5l.3 .4M229.5 115.6h.4l-.1-.3-.3 .1v.4h.4M230.6 115.4h-.3l.1 .2h.2l-.1 .3-.2-.1M230.8 116h.7M231.6 115.1h.5l.1 .2v.3l-.2 .3-.4-.2zM233.1 115.1v.8l-.5-.8v.8" fill="none" stroke="#007170" stroke-width=".21"/>
<path d="M216.1 114.6h18.3v2.7h-18.3z" fill="none" stroke="#980000" stroke-width=".21"/>
<path d="M216.1 109.8h.4l.4 .4-.4 .5h-.4z" fill="#fff"/>
<path d="M216.1 109.8h.4l.4 .4-.4 .5h-.4z" fill="none" stroke="#805e00" stroke-width=".21"/>
<path d="M217.3 110.2h.5v-.4h-.5v.9M217.6 110.2l.2 .5M218.2 110.4l.4-.1-.2-.2h-.2v.6h.3M219.3 110.1h-.4l.1 .3h.3v.3h-.4M219.5 110.7h.6M220.8 109.8h-.3l-.2 .2v.5l.2 .2h.3v-.4h-.2M221.7 109.8v.9l-.5-.9v.9M222.1 109.8h.3l.2 .2v.5l-.2 .2h-.3z" fill="none" stroke="#007170" stroke-width=".21"/>
<path d="M233.5 109.4l.4-.4h.5v.8h-.5z" fill="#fff"/>
<path d="M233.9 109h.5v.8h-.5l-.4-.4z" fill="none" stroke="#805e00" stroke-width=".21"/>
<path d="M228.7 109.4h.4l.1-.4h-.5v.8M228.9 109.4l.3 .4M229.5 109.5l.4-.1-.1-.2-.3 .1v.4h.4M230.6 109.3h-.3v.2l.3 .1-.1 .2-.2-.1M230.8 109.9h.7M231.6 109h.6a.47 .47 0 0 1-.4 .8l-.2-.2zM233.1 109v.8l-.5-.8v.8" fill="none" stroke="#007170" stroke-width=".21"/>
<path d="M216.1 108.5h18.3v2.7h-18.3z" fill="none" stroke="#980000" stroke-width=".21"/>
<path d="M216.1 122h.4l.4 .5-.4 .4h-.4z" fill="#fff"/>
<path d="M216.1 122h.4l.4 .5-.4 .4h-.4z" fill="none" stroke="#805e00" stroke-width=".21"/>
<path d="M217.3 122.4h.5v-.2l-.1-.2h-.4v.8M217.6 122.4l.2 .4M218.2 122.6l.4-.1-.2-.2h-.2v.5h.3M219.3 122.3h-.4l.1 .3h.3v.2h-.4M219.5 122.9h.6M220.8 122.1l-.2-.1-.3 .2v.5l.2 .1h.3v-.3h-.2M221.7 122v.8l-.5-.8v.8M222.1 122l.5 .2v.5l-.2 .1h-.3z" fill="none" stroke="#007170" stroke-width=".21"/>
<path d="M233.5 121.6l.4-.4h.5v.8h-.5z" fill="#fff"/>
<path d="M233.9 121.2h.5v.8h-.5l-.4-.4z" fill="none" stroke="#805e00" stroke-width=".21"/>
<path d="M228.7 121.6h.4l.1-.4h-.5v.8M228.9 121.6l.3 .4M229.5 121.7h.4l-.1-.3-.3 .1v.5h.4M230.6 121.5h-.3l.1 .2h.2v.3h-.3M230.8 122.1h.7M231.6 121.2h.6v.5l-.1 .3-.5-.1zM233.1 121.2v.8l-.5-.8v.8" fill="none" stroke="#007170" stroke-width=".21"/>
<path d="M216.1 120.7h18.3v2.7h-18.3z" fill="none" stroke="#980000" stroke-width=".21"/>
<path d="M47.4 194.4h.4v.8h-.4l-.4-.4z" fill="#fff"/>
<path d="M47.4 194.4h.4v.8h-.4l-.4-.4z" fill="none" stroke="#805e00" stroke-width=".21"/>
<g fill="none" stroke="#007170" stroke-width=".21">
<path d="M41.6 194.4v.8h.4M42.3 194.4v.8h.5M42.8 195.3h.6M43.7 194.4v.1M43.7 194.6v.6M44.1 194.7h.3v.5M44.1 194.6v.6M44.9 194.7h.4v.5h-.4M44.9 194.6v.9M45.6 194.6v.5l.2 .1h.3M46.1 194.6v.6M46.3 194.6h.3"/>
<path d="M46.5 194.4v.8h.1"/>
</g>
<path d="M32.2 194.4h.4l.4 .4-.4 .4h-.4z" fill="#fff"/>
<path d="M32.2 194.4h.4l.4 .4-.4 .4h-.4z" fill="none" stroke="#805e00" stroke-width=".21"/>
<g fill="none" stroke="#007170" stroke-width=".21">
<path d="M33.3 194.1h6.2M33.4 194.4v.8M33.4 194.8h.5M33.9 194.4v.8M34.3 194.4v.8h.4M35.6 194.8l.4-.2 .1 .5-.3 .1zM36.5 194.6v.6h.3M36.8 194.6v.6M37.2 194.6h.3M37.2 194.4v.7l.3 .1M37.8 194.7h.4v.5h-.4M37.8 194.6v.9"/>
<path d="M38.5 194.6v.5l.2 .1h.2M38.9 194.6v.6M39.2 194.6h.3M39.4 194.4v.8h.1"/>
</g>
<path d="M32.2 193.1h15.6v3.5h-15.6z" fill="none" stroke="#980000" stroke-width=".21"/>
<path d="M47 176.5l.4-.4h.4v.8h-.4z" fill="#fff"/>
<path d="M47.4 176.1h.4v.8h-.4l-.4-.4z" fill="none" stroke="#805e00" stroke-width=".21"/>
<path d="M41.6 176v.9h.4M42.3 176v.9h.5M42.8 177h.6M43.7 176v.1M43.7 176.4v.5M44.1 176.4h.3v.5M44.1 176.4v.5M44.9 176.9h.4l-.1-.5h-.3v.8M45.6 176.4v.4l.2 .1h.3M46.1 176.4v.5M46.3 176.4h.3M46.5 176v.9h.1" fill="none" stroke="#007170" stroke-width=".21"/>
<path d="M32.2 176.1h.4l.4 .4-.4 .4h-.4z" fill="#fff"/>
<path d="M32.2 176.1h.4l.4 .4-.4 .4h-.4z" fill="none" stroke="#805e00" stroke-width=".21"/>
<g fill="none" stroke="#007170" stroke-width=".21">
<path d="M33.3 175.8h6.2M33.4 176v.9M33.4 176.4h.5M33.9 176v.9M34.3 176v.9h.4M35.7 176.4h.4v.1l-.1 .4-.4-.1zM36.5 176.4v.5h.3M36.8 176.4v.5M37.2 176.4h.3M37.2 176v.8l.3 .1M37.8 176.9h.4l-.1-.5h-.3v.8M38.5 176.4v.4l.2 .1h.2"/>
<path d="M38.9 176.4v.5M39.2 176.4h.3M39.4 176v.9h.1"/>
</g>
<path d="M32.2 174.7h15.6v3.6h-15.6z" fill="none" stroke="#980000" stroke-width=".21"/>
<path d="M47.4 188.3h.4v.8h-.4l-.4-.4z" fill="#fff"/>
<path d="M47.4 188.3h.4v.8h-.4l-.4-.4z" fill="none" stroke="#805e00" stroke-width=".21"/>
<path d="M41.6 188.3v.8h.4M42.3 188.3v.8h.5M42.8 189.2h.6M43.7 188.3v.1M43.7 188.5v.6M44.1 188.6l.3-.1v.6M44.1 188.5v.6M44.9 189.1h.4l-.1-.6h-.3v.9M45.6 188.5v.5l.2 .1h.3M46.1 188.5v.6M46.3 188.5h.3M46.5 188.3v.8h.1" fill="none" stroke="#007170" stroke-width=".21"/>
<path d="M32.2 188.3h.4l.4 .4-.4 .4h-.4z" fill="#fff"/>
<path d="M32.2 188.3h.4l.4 .4-.4 .4h-.4z" fill="none" stroke="#805e00" stroke-width=".21"/>
<g fill="none" stroke="#007170" stroke-width=".21">
<path d="M33.3 188h6.2M33.4 188.3v.8M33.4 188.6h.5M33.9 188.3v.8M34.3 188.3v.8h.4M35.7 188.5h.4v.2l-.1 .4-.4-.1zM36.5 188.5v.6h.3M36.8 188.5v.6M37.2 188.5h.3M37.2 188.3v.7l.3 .1M37.8 189.1h.4l-.1-.6h-.3v.9M38.5 188.5v.5l.2 .1h.2"/>
<path d="M38.9 188.5v.6M39.2 188.5h.3M39.4 188.3v.8h.1"/>
</g>
<path d="M32.2 187h15.6v3.5h-15.6z" fill="none" stroke="#980000" stroke-width=".21"/>
<path d="M47 182.6l.4-.4h.4v.8h-.4z" fill="#fff"/>
<path d="M47 182.6l.4-.4h.4v.8h-.4z" fill="none" stroke="#805e00" stroke-width=".21"/>
<path d="M41.6 182.1v.9h.4M42.3 182.1v.9h.5M42.8 183.1h.6M43.7 182.1v.1M43.7 182.5v.5M44.1 182.5h.3v.5M44.1 182.5v.5M44.9 183h.4l-.1-.5h-.3v.8M45.6 182.5v.4l.2 .1h.3M46.1 182.5v.5M46.3 182.5h.3M46.5 182.1v.9h.1" fill="none" stroke="#007170" stroke-width=".21"/>
<path d="M32.2 182.2h.4l.4 .4-.4 .4h-.4z" fill="#fff"/>
<path d="M32.2 182.2h.4l.4 .4-.4 .4h-.4z" fill="none" stroke="#805e00" stroke-width=".21"/>
<g fill="none" stroke="#007170" stroke-width=".21">
<path d="M33.3 181.9h6.2M33.4 182.1v.9M33.4 182.5h.5M33.9 182.1v.9M34.3 182.1v.9h.4M35.7 182.5h.4v.1l-.1 .4-.4-.1zM36.5 182.5v.5h.3M36.8 182.5v.5M37.2 182.5h.3M37.2 182.1v.8l.3 .1M37.8 183h.4l-.1-.5h-.3v.8M38.5 182.5v.4l.2 .1h.2"/>
<path d="M38.9 182.5v.5M39.2 182.5h.3M39.4 182.1v.9h.1"/>
</g>
<path d="M32.2 180.8h15.6v3.6h-15.6z" fill="none" stroke="#980000" stroke-width=".21"/>
<path d="M47.4 102.9h.4v.8h-.4l-.4-.4z" fill="#fff"/>
<path d="M47.4 102.9h.4v.8h-.4l-.4-.4z" fill="none" stroke="#805e00" stroke-width=".21"/>
<path d="M41.6 102.9v.8h.4M42.3 102.9v.8h.5M42.8 103.8h.6M43.7 102.9h.1M43.7 103.1v.6M44.1 103.2l.3-.1v.6M44.1 103.1v.6M44.9 103.6h.4l-.1-.5h-.3v.9M45.6 103.1v.4l.2 .2 .3-.1M46.1 103.1v.6M46.3 103.1h.3M46.5 102.9v.7l.1 .1" fill="none" stroke="#007170" stroke-width=".21"/>
<path d="M32.2 102.9h.4l.4 .4-.4 .4h-.4z" fill="#fff"/>
<path d="M32.2 102.9h.4l.4 .4-.4 .4h-.4z" fill="none" stroke="#805e00" stroke-width=".21"/>
<g fill="none" stroke="#007170" stroke-width=".21">
<path d="M33.3 102.6h6.2M33.4 102.9v.8M33.4 103.2h.5M33.9 102.9v.8M34.3 102.9v.8h.4M35.7 103.1h.4v.2l-.1 .4-.4-.2zM36.5 103.1v.5h.3M36.8 103.1v.6M37.2 103.1h.3M37.2 102.9v.6l.3 .2M37.8 103.6h.4l-.1-.5h-.3v.9M38.5 103.1v.4l.2 .2 .2-.1"/>
<path d="M38.9 103.1v.6M39.2 103.1h.3M39.4 102.9v.7l.1 .1"/>
</g>
<path d="M32.2 101.6h15.6v3.5h-15.6z" fill="none" stroke="#980000" stroke-width=".21"/>
<path d="M47.4 121.2h.4v.8h-.4l-.4-.4z" fill="#fff"/>
<path d="M47.4 121.2h.4v.8h-.4l-.4-.4z" fill="none" stroke="#805e00" stroke-width=".21"/>
<g fill="none" stroke="#007170" stroke-width=".21">
<path d="M41.6 121.2v.8h.4M42.3 121.2v.8h.5M42.8 122.1h.6M43.7 121.2h.1M43.7 121.4v.6M44.1 121.5h.3v.5M44.1 121.4v.6M44.9 121.5h.4v.4l-.4 .1M44.9 121.4v.9M45.6 121.4v.5h.5M46.1 121.4v.6M46.3 121.4h.3"/>
<path d="M46.5 121.2v.8h.1"/>
</g>
<path d="M32.2 121.2h.4l.4 .4-.4 .4h-.4z" fill="#fff"/>
<path d="M32.2 121.2h.4l.4 .4-.4 .4h-.4z" fill="none" stroke="#805e00" stroke-width=".21"/>
<g fill="none" stroke="#007170" stroke-width=".21">
<path d="M33.3 120.9h6.2M33.4 121.2v.8M33.4 121.6h.5M33.9 121.2v.8M34.3 121.2v.8h.4M35.8 121.4l.3 .2v.4h-.4l-.1-.2zM36.5 121.4v.6l.3-.1M36.8 121.4v.6M37.2 121.4h.3M37.2 121.2v.7l.3 .1M37.8 121.5h.4v.4l-.4 .1M37.8 121.4v.9"/>
<path d="M38.5 121.4v.5h.4M38.9 121.4v.6M39.2 121.4h.3M39.4 121.2v.8h.1"/>
</g>
<path d="M32.2 119.9h15.6v3.5h-15.6z" fill="none" stroke="#980000" stroke-width=".21"/>
<path d="M47.4 115.1h.4v.8h-.4l-.4-.4z" fill="#fff"/>
<path d="M47.4 115.1h.4v.8h-.4l-.4-.4z" fill="none" stroke="#805e00" stroke-width=".21"/>
<g fill="none" stroke="#007170" stroke-width=".21">
<path d="M41.6 115.1v.8h.4M42.3 115.1v.8h.5M42.8 116h.6M43.7 115.1h.1M43.7 115.3v.6M44.1 115.4h.3v.5M44.1 115.3v.6M44.9 115.4h.4v.4h-.4M44.9 115.3v.9M45.6 115.3v.4l.2 .2 .3-.1M46.1 115.3v.6M46.3 115.3h.3"/>
<path d="M46.5 115.1v.7l.1 .1"/>
</g>
<path d="M32.2 115.1h.4l.4 .4-.4 .4h-.4z" fill="#fff"/>
<path d="M32.2 115.1h.4l.4 .4-.4 .4h-.4z" fill="none" stroke="#805e00" stroke-width=".21"/>
<g fill="none" stroke="#007170" stroke-width=".21">
<path d="M33.3 114.8h6.2M33.4 115.1v.8M33.4 115.5h.5M33.9 115.1v.8M34.3 115.1v.8h.4M35.6 115.5l.4-.2 .1 .4-.3 .2zM36.5 115.3v.5h.3M36.8 115.3v.6M37.2 115.3h.3M37.2 115.1v.6l.3 .2M37.8 115.4h.4v.4h-.4M37.8 115.3v.9"/>
<path d="M38.5 115.3v.4l.2 .2 .2-.1M38.9 115.3v.6M39.2 115.3h.3M39.4 115.1v.7l.1 .1"/>
</g>
<path d="M32.2 113.8h15.6v3.5h-15.6z" fill="none" stroke="#980000" stroke-width=".21"/>
<path d="M47.4 127.2h.4v1h-.4l-.4-.5z" fill="#fff"/>
<path d="M47 127.7l.4-.5h.4v1h-.4z" fill="none" stroke="#805e00" stroke-width=".21"/>
<g fill="none" stroke="#007170" stroke-width=".21">
<path d="M41.6 127.2v.9h.4M42.3 127.2v.9h.5M42.8 128.2h.6M43.7 127.2v.1M43.7 127.5v.6M44.1 127.6h.3v.5M44.1 127.5v.6M44.9 127.6h.4v.4l-.4 .1M44.9 127.5v.9M45.6 127.5v.5h.5M46.1 127.5v.6M46.3 127.5h.3"/>
<path d="M46.5 127.2v.9h.1"/>
</g>
<path d="M32.2 127.2h.4l.4 .5-.4 .5h-.4z" fill="#fff"/>
<path d="M32.2 127.2h.4l.4 .5-.4 .5h-.4z" fill="none" stroke="#805e00" stroke-width=".21"/>
<g fill="none" stroke="#007170" stroke-width=".21">
<path d="M33.3 127h6.2M33.4 127.2v.9M33.4 127.7h.5M33.9 127.2v.9M34.3 127.2v.9h.4M35.6 127.7l.2-.2 .3 .2v.4h-.4zM36.5 127.5v.6l.3-.1M36.8 127.5v.6M37.2 127.5h.3M37.2 127.2v.8l.3 .1M37.8 127.6h.4v.4l-.4 .1M37.8 127.5v.9"/>
<path d="M38.5 127.5v.5h.4M38.9 127.5v.6M39.2 127.5h.3M39.4 127.2v.9h.1"/>
</g>
<path d="M32.2 126h15.6v3.4h-15.6z" fill="none" stroke="#980000" stroke-width=".21"/>
<path d="M47.4 109h.4v.8h-.4l-.4-.4z" fill="#fff"/>
<path d="M47.4 109h.4v.8h-.4l-.4-.4z" fill="none" stroke="#805e00" stroke-width=".21"/>
<g fill="none" stroke="#007170" stroke-width=".21">
<path d="M41.6 109v.8h.4M42.3 109v.8h.5M42.8 109.9h.6M43.7 109h.1M43.7 109.2v.6M44.1 109.3h.3v.5M44.1 109.2v.6M44.9 109.3h.4v.4h-.4M44.9 109.2v.9M45.6 109.2v.4l.2 .2 .3-.1M46.1 109.2v.6M46.3 109.2h.3"/>
<path d="M46.5 109v.7l.1 .1"/>
</g>
<path d="M32.2 109h.4l.4 .4-.4 .4h-.4z" fill="#fff"/>
<path d="M32.2 109h.4l.4 .4-.4 .4h-.4z" fill="none" stroke="#805e00" stroke-width=".21"/>
<g fill="none" stroke="#007170" stroke-width=".21">
<path d="M33.3 108.7h6.2M33.4 109v.8M33.4 109.4h.5M33.9 109v.8M34.3 109v.8h.4M35.6 109.4l.4-.2 .1 .4-.3 .2zM36.5 109.2v.5h.3M36.8 109.2v.6M37.2 109.2h.3M37.2 109v.6l.3 .2M37.8 109.3h.4v.4h-.4M37.8 109.2v.9"/>
<path d="M38.5 109.2v.4l.2 .2 .2-.1M38.9 109.2v.6M39.2 109.2h.3M39.4 109v.7l.1 .1"/>
</g>
<path d="M32.2 107.7h15.6v3.5h-15.6z" fill="none" stroke="#980000" stroke-width=".21"/>
<path d="M47.4 139.4h.4v1h-.4l-.4-.5z" fill="#fff"/>
<path d="M47.4 139.4h.4v1h-.4l-.4-.5z" fill="none" stroke="#805e00" stroke-width=".21"/>
<g fill="none" stroke="#007170" stroke-width=".21">
<path d="M41.6 139.4v.9h.4M42.3 139.4v.9h.5M43.7 139.4v.1M43.7 139.7v.6M44.1 139.8h.3v.5M44.1 139.7v.6M44.9 139.8h.4v.4l-.4 .1M44.9 139.7v.9M45.6 139.7v.5h.5M46.1 139.7v.6M46.3 139.7h.3M46.5 139.4v.9h.1"/>
<path d="M42.8 140.4h.6"/>
</g>
<path d="M32.2 139.4h.4l.4 .5-.4 .5h-.4z" fill="#fff"/>
<path d="M32.2 139.4h.4l.4 .5-.4 .5h-.4z" fill="none" stroke="#805e00" stroke-width=".21"/>
<g fill="none" stroke="#007170" stroke-width=".21">
<path d="M33.3 139.2h6.2M33.4 139.4v.9M33.4 139.9h.5M33.9 139.4v.9M34.3 139.4v.9h.4M35.6 139.9l.2-.2 .3 .2v.4h-.4zM36.5 139.7v.6l.3-.1M36.8 139.7v.6M37.2 139.7h.3M37.2 139.4v.8l.3 .1M37.8 139.8h.4v.4l-.4 .1M37.8 139.7v.9"/>
<path d="M38.5 139.7v.5h.4M38.9 139.7v.6M39.2 139.7h.3M39.4 139.4v.9h.1"/>
</g>
<path d="M32.2 138.2h15.6v3.4h-15.6z" fill="none" stroke="#980000" stroke-width=".21"/>
<path d="M47.4 145.5h.4v1h-.4l-.4-.5z" fill="#fff"/>
<path d="M47.4 145.5h.4v1h-.4l-.4-.5z" fill="none" stroke="#805e00" stroke-width=".21"/>
<g fill="none" stroke="#007170" stroke-width=".21">
<path d="M41.6 145.5v.9h.4M42.3 145.5v.9h.5M42.8 146.5h.6M43.7 145.5v.1M43.7 145.8v.6M44.1 145.9h.3v.5M44.1 145.8v.6M44.9 145.9h.4v.4l-.4 .1M44.9 145.8v.9M45.6 145.8v.5h.5M46.1 145.8v.6M46.3 145.8h.3"/>
<path d="M46.5 145.5v.9h.1"/>
</g>
<path d="M32.2 145.5h.4l.4 .5-.4 .5h-.4z" fill="#fff"/>
<path d="M32.2 145.5h.4l.4 .5-.4 .5h-.4z" fill="none" stroke="#805e00" stroke-width=".21"/>
<g fill="none" stroke="#007170" stroke-width=".21">
<path d="M33.3 145.3h6.2M33.4 145.5v.9M33.4 146h.5M33.9 145.5v.9M34.3 145.5v.9h.4M35.6 146l.2-.2 .3 .2v.4h-.4zM36.5 145.8v.6l.3-.1M36.8 145.8v.6M37.2 145.8h.3M37.2 145.5v.8l.3 .1M37.8 145.9h.4v.4l-.4 .1M37.8 145.8v.9"/>
<path d="M38.5 145.8v.5h.4M38.9 145.8v.6M39.2 145.8h.3M39.4 145.5v.9h.1"/>
</g>
<path d="M32.2 144.3h15.6v3.4h-15.6z" fill="none" stroke="#980000" stroke-width=".21"/>
<path d="M47 133.8l.4-.5h.4v1h-.4z" fill="#fff"/>
<path d="M47.4 133.3h.4v1h-.4l-.4-.5z" fill="none" stroke="#805e00" stroke-width=".21"/>
<g fill="none" stroke="#007170" stroke-width=".21">
<path d="M41.6 133.3v.9h.4M42.3 133.3v.9h.5M42.8 134.3h.6M43.7 133.3v.1M43.7 133.6v.6M44.1 133.7h.3v.5M44.1 133.6v.6M44.9 133.7h.4v.4l-.4 .1M44.9 133.6v.9M45.6 133.6v.5h.5M46.1 133.6v.6M46.3 133.6h.3"/>
<path d="M46.5 133.3v.9h.1"/>
</g>
<path d="M32.2 133.3h.4l.4 .5-.4 .5h-.4z" fill="#fff"/>
<path d="M32.2 133.3h.4l.4 .5-.4 .5h-.4z" fill="none" stroke="#805e00" stroke-width=".21"/>
<g fill="none" stroke="#007170" stroke-width=".21">
<path d="M33.3 133.1h6.2M33.4 133.3v.9M33.4 133.8h.5M33.9 133.3v.9M34.3 133.3v.9h.4M35.8 133.6l.3 .2v.4h-.4l-.1-.2zM36.5 133.6v.6l.3-.1M36.8 133.6v.6M37.2 133.6h.3M37.2 133.3v.8l.3 .1M37.8 133.7h.4v.4l-.4 .1M37.8 133.6v.9"/>
<path d="M38.5 133.6v.5h.4M38.9 133.6v.6M39.2 133.6h.3M39.4 133.3v.9h.1"/>
</g>
<path d="M32.2 132.1h15.6v3.4h-15.6z" fill="none" stroke="#980000" stroke-width=".21"/>
<path d="M47 158.2l.4-.4h.4v.9h-.4z" fill="#fff"/>
<path d="M47.4 157.8h.4v.9h-.4l-.4-.5z" fill="none" stroke="#805e00" stroke-width=".21"/>
<path d="M41.6 157.7v.9h.4M42.3 157.7v.9h.5M42.8 158.7h.6M43.7 157.7v.1M43.7 158.1v.5M44.1 158.2l.3-.1v.5M44.1 158.1v.5M44.9 158.6l.4-.1-.1-.4h-.3v.8M45.6 158.1l.1 .5 .4-.1M46.1 158.1v.5M46.3 158.1h.3M46.5 157.7v.9h.1" fill="none" stroke="#007170" stroke-width=".21"/>
<path d="M32.2 157.8h.4l.4 .4-.4 .5h-.4z" fill="#fff"/>
<path d="M32.2 157.8h.4l.4 .4-.4 .5h-.4z" fill="none" stroke="#805e00" stroke-width=".21"/>
<g fill="none" stroke="#007170" stroke-width=".21">
<path d="M33.3 157.5h6.2M33.4 157.7v.9M33.4 158.2h.5M33.9 157.7v.9M34.3 157.7v.9h.4M35.7 158.1h.4v.5l-.5-.1zM36.5 158.1v.5l.3-.1M36.8 158.1v.5M37.2 158.1h.3M37.2 157.7v.8l.3 .1M37.8 158.6l.4-.1-.1-.4h-.3v.8M38.5 158.1l.1 .5 .3-.1"/>
<path d="M38.9 158.1v.5M39.2 158.1h.3M39.4 157.7v.9h.1"/>
</g>
<path d="M32.2 156.5h15.6v3.4h-15.6z" fill="none" stroke="#980000" stroke-width=".21"/>
<path d="M47 152.1l.4-.4h.4v.9h-.4z" fill="#fff"/>
<path d="M47 152.1l.4-.4h.4v.9h-.4z" fill="none" stroke="#805e00" stroke-width=".21"/>
<path d="M41.6 151.6v.9h.4M42.3 151.6v.9h.5M42.8 152.6h.6M43.7 151.6v.1M43.7 152v.5M44.1 152.1l.3-.1v.5M44.1 152v.5M44.9 152.5l.4-.1-.1-.4h-.3v.8M45.6 152v.4h.5M46.1 152v.5M46.3 152h.3M46.5 151.6v.9h.1" fill="none" stroke="#007170" stroke-width=".21"/>
<path d="M32.2 151.7h.4l.4 .4-.4 .5h-.4z" fill="#fff"/>
<path d="M32.2 151.7h.4l.4 .4-.4 .5h-.4z" fill="none" stroke="#805e00" stroke-width=".21"/>
<g fill="none" stroke="#007170" stroke-width=".21">
<path d="M33.3 151.4h6.2M33.4 151.6v.9M33.4 152.1h.5M33.9 151.6v.9M34.3 151.6v.9h.4M35.7 152l.4 .1v.4h-.4zM36.5 152v.5l.3-.1M36.8 152v.5M37.2 152h.3M37.2 151.6v.8l.3 .1M37.8 152.5l.4-.1-.1-.4h-.3v.8M38.5 152v.4h.4"/>
<path d="M38.9 152v.5M39.2 152h.3M39.4 151.6v.9h.1"/>
</g>
<path d="M32.2 150.4h15.6v3.4h-15.6z" fill="none" stroke="#980000" stroke-width=".21"/>
<path d="M47 164.3l.4-.4h.4v.9h-.4z" fill="#fff"/>
<path d="M47.4 163.9h.4v.9h-.4l-.4-.5z" fill="none" stroke="#805e00" stroke-width=".21"/>
<path d="M41.6 163.8v1h.4M42.3 163.8v1h.5M42.8 164.8h.6M43.7 163.8v.1M43.7 164.2v.6M44.1 164.2h.3v.6M44.1 164.2v.6M44.9 164.7h.4l-.1-.5h-.3v.8M45.6 164.2v.4l.2 .2 .3-.1M46.1 164.2v.6M46.3 164.2h.3M46.5 163.8v.9l.1 .1" fill="none" stroke="#007170" stroke-width=".21"/>
<path d="M32.2 163.9h.4l.4 .4-.4 .5h-.4z" fill="#fff"/>
<path d="M32.2 163.9h.4l.4 .4-.4 .5h-.4z" fill="none" stroke="#805e00" stroke-width=".21"/>
<g fill="none" stroke="#007170" stroke-width=".21">
<path d="M33.3 163.6h6.2M33.4 163.8v1M33.4 164.2h.5M33.9 163.8v1M34.3 163.8v1h.4M35.7 164.2h.4v.1l-.1 .5-.4-.2zM36.5 164.2v.5h.3M36.8 164.2v.6M37.2 164.2h.3M37.2 163.8v.8l.3 .2M37.8 164.7h.4l-.1-.5h-.3v.8M38.5 164.2v.4l.2 .2 .2-.1"/>
<path d="M38.9 164.2v.6M39.2 164.2h.3M39.4 163.8v.9l.1 .1"/>
</g>
<path d="M32.2 162.6h15.6v3.4h-15.6z" fill="none" stroke="#980000" stroke-width=".21"/>
<path d="M47.4 170h.4v.9h-.4l-.4-.5z" fill="#fff"/>
<path d="M47.4 170h.4v.9h-.4l-.4-.5z" fill="none" stroke="#805e00" stroke-width=".21"/>
<path d="M41.6 169.9v1h.4M42.3 169.9v1h.5M42.8 170.9h.6M43.7 169.9v.1M43.7 170.3v.6M44.1 170.3h.3v.6M44.1 170.3v.6M44.9 170.8h.4l-.1-.5h-.3v.8M45.6 170.3v.4l.2 .2 .3-.1M46.1 170.3v.6M46.3 170.3h.3M46.5 169.9v.9l.1 .1" fill="none" stroke="#007170" stroke-width=".21"/>
<path d="M32.2 170h.4l.4 .4-.4 .5h-.4z" fill="#fff"/>
<path d="M32.2 170h.4l.4 .4-.4 .5h-.4z" fill="none" stroke="#805e00" stroke-width=".21"/>
<g fill="none" stroke="#007170" stroke-width=".21">
<path d="M33.3 169.7h6.2M33.4 169.9v1M33.4 170.3h.5M33.9 169.9v1M34.3 169.9v1h.4M35.7 170.3h.4v.1l-.1 .5-.4-.2zM36.5 170.3v.5h.3M36.8 170.3v.6M37.2 170.3h.3M37.2 169.9v.8l.3 .2M37.8 170.8h.4l-.1-.5h-.3v.8M38.5 170.3v.4l.2 .2 .2-.1"/>
<path d="M38.9 170.3v.6M39.2 170.3h.3M39.4 169.9v.9l.1 .1"/>
</g>
<path d="M32.2 168.7h15.6v3.5h-15.6z" fill="none" stroke="#980000" stroke-width=".21"/>
<path d="M244.9 37.5h.4l.4 .4-.4 .4h-.4z" fill="#fff"/>
<path d="M244.9 37.5h.4l.4 .4-.4 .4h-.4z" fill="none" stroke="#805e00" stroke-width=".21"/>
<path d="M239.2 37.4h.6l-.4 .4 .4 .1v.3l-.2 .1h-.4M239.9 37.4l.4 .9 .2-.9M240.8 37.4h.5l-.3 .4h.3v.5h-.5M241.5 38.4h.6M242.5 37.4a.47 .47 0 0 1 .4 .5 .47 .47 0 0 1-.4 .4l-.2-.1v-.6zM243.2 37.4v.8l.2 .1h.3v-.9M244.1 37.4h.4M244.3 37.4v.9" fill="none" stroke="#007170" stroke-width=".21"/>
<path d="M218.7 37.5h.4l.4 .4-.4 .4h-.4z" fill="#fff"/>
<path d="M218.7 37.5h.4l.4 .4-.4 .4h-.4z" fill="none" stroke="#805e00" stroke-width=".21"/>
<path d="M219.8 37.4l.3 .9 .3-.9M220.5 38.4h.6M221.4 37.4v.9M222.2 37.4v.9l-.4-.9v.9" fill="none" stroke="#007170" stroke-width=".21"/>
<path d="M218.7 36.1h27v3.6h-27z" fill="none" stroke="#980000" stroke-width=".21"/>
<path d="M216.1 48.8h.4l.4 .5-.4 .4h-.4z" fill="#fff"/>
<path d="M216.1 48.8h.4l.4 .5-.4 .4h-.4z" fill="none" stroke="#805e00" stroke-width=".21"/>
<path d="M217.3 49.3h.4l.1-.2-.1-.3h-.4v.8M217.6 49.3l.2 .3M218.2 49.4l.4-.1-.1-.2h-.3v.5h.3M219.3 49.1h-.4v.3h.4v.2h-.4M219.5 49.7h.6M220.8 48.8h-.2l-.3 .2v.4l.2 .2h.3v-.3h-.2M221.7 48.8v.8l-.5-.8v.8M222.1 48.8h.2l.3 .2v.4l-.2 .2h-.3z" fill="none" stroke="#007170" stroke-width=".21"/>
<path d="M233.5 48.3l.4-.4h.5v.9h-.5z" fill="#fff"/>
<path d="M233.9 47.9h.5v.9h-.5l-.4-.5z" fill="none" stroke="#805e00" stroke-width=".21"/>
<path d="M228.7 48.3h.4l.1-.3-.5-.1v.9M228.9 48.3l.3 .5M229.5 48.5l.4-.1-.1-.2-.3 .1v.5h.4M230.6 48.3h-.3l.1 .2h.2v.3h-.3M230.8 48.8h.7M231.7 47.9h.4l.1 .3-.1 .6-.5-.1zM233.1 47.9v.9l-.5-.9v.9" fill="none" stroke="#007170" stroke-width=".21"/>
<path d="M216.1 47.5h18.3v2.6h-18.3z" fill="none" stroke="#980000" stroke-width=".21"/>
<path d="M198.6 20.9h.4l.5 .4-.5 .5h-.4z" fill="#fff"/>
<path d="M198.6 20.9h.4l.5 .4-.5 .5h-.4z" fill="none" stroke="#805e00" stroke-width=".21"/>
<g fill="none" stroke="#007170" stroke-width=".21">
<path d="M188.4 21.3h.4v-.4h-.4v.9M189.2 21.2h.4v.6l-.4-.1zM190 21.2l.2 .6 .1-.5 .2 .5 .2-.6M190.9 21.5l.4-.1-.1-.2h-.3v.6h.4M191.7 21.2v.6M191.9 21.2l-.2 .1M192 21.8h.7M193.4 20.9l-.5 .1v.2l.5 .3-.1 .3h-.4M193.6 21.2l.2 .6 .2-.5 .1 .5 .2-.6M194.6 20.9v.1M194.6 21.2v.6M195 21.2h.2"/>
<path d="M195.1 20.9v.9h.1M195.9 21.2h-.2l-.2 .1 .1 .5h.3M196.3 21.2h.4v.6M196.3 20.9v.9M197.1 21.5l.3-.1v-.2h-.3v.6h.3M198.2 20.9v.9h-.3l-.1-.5 .1-.1h.3"/>
</g>
<path d="M175.9 20.9h.5l.5 .4-.5 .5h-.5z" fill="#fff"/>
<path d="M175.9 20.9h.5l.5 .4-.5 .5h-.5z" fill="none" stroke="#805e00" stroke-width=".21"/>
<path d="M177.2 21.3h.4l.1-.3-.5-.1v.9M178.2 21.2l.4 .1-.1 .5h-.4l-.1-.2zM178.8 21.2l.2 .6 .1-.5 .2 .5 .2-.6M179.7 21.5l.5-.1-.1-.2-.4 .1v.4l.5 .1M180.6 21.2v.6M180.8 21.2l-.2 .1M180.9 21.8h.6M181.8 20.9v.9M182.2 21.2h.3v.6M182.2 21.2v.6" fill="none" stroke="#007170" stroke-width=".21"/>
<path d="M175.9 22.7h.5l.5 .4-.5 .4h-.5z" fill="#fff"/>
<path d="M175.9 22.7h.5l.5 .4-.5 .4h-.5z" fill="none" stroke="#805e00" stroke-width=".21"/>
<g fill="none" stroke="#007170" stroke-width=".21">
<path d="M177.2 23.1l.5-.1v-.3l-.5-.1v.9M178.1 22.9h.4l.1 .2-.2 .4-.4-.1zM178.8 22.9l.2 .6 .1-.4 .2 .4 .2-.6M179.7 23.2l.5-.1v-.2l-.5 .1v.4l.2 .1 .3-.1M180.6 22.9v.6M180.8 22.9l-.2 .2M180.9 23.6h.6M181.9 22.6l.4 .2v.6l-.2 .1a.49 .49 0 0 1-.4-.4 .49 .49 0 0 1 .2-.5zM182.7 23l.3-.1v.6M182.7 22.9v.6M184.1 22.6l-.7 1.1M184.2 22.3h1.8"/>
<path d="M184.6 22.6l.3 .2v.6l-.2 .1a.49 .49 0 0 1-.4-.4 .49 .49 0 0 1 .3-.5zM185.2 22.9h.3M185.5 22.6l-.2 .1v.8M185.7 22.9h.3M186 22.6l-.2 .2v.7"/>
</g>
<path d="M175.9 19.6h23.6v5.2h-23.6z" fill="none" stroke="#980000" stroke-width=".21"/>
<path d="M218.7 22.7h.4l.4 .4-.4 .4h-.4z" fill="#fff"/>
<path d="M218.7 22.7h.4l.4 .4-.4 .4h-.4z" fill="none" stroke="#805e00" stroke-width=".21"/>
<path d="M220.4 22.6h-.4l-.1 .4h.5v.4h-.5M220.6 22.6l.4 .9 .2-.9M221.3 23.6h.7M222.2 23h.3M222.6 22.6h-.4v.9h.4M223.5 22.6v.9l-.5-.9v.9" fill="none" stroke="#007170" stroke-width=".21"/>
<path d="M244.9 20.9h.4l.4 .4-.4 .5h-.4z" fill="#fff"/>
<path d="M244.9 20.9h.4l.4 .4-.4 .5h-.4z" fill="none" stroke="#805e00" stroke-width=".21"/>
<path d="M240.5 20.9h-.4l-.1 .4 .4-.1 .1 .5h-.5M240.8 20.9l.3 .9 .3-.9M241.5 21.8h.6M242.3 21h.5l.1 .5-.2 .3-.4-.1zM243.2 20.9l.1 .9 .4-.1v-.8M244.1 20.9h.4M244.3 20.9v.9" fill="none" stroke="#007170" stroke-width=".21"/>
<path d="M218.7 20.9h.4l.4 .4-.4 .5h-.4z" fill="#fff"/>
<path d="M218.7 20.9h.4l.4 .4-.4 .5h-.4z" fill="none" stroke="#805e00" stroke-width=".21"/>
<path d="M219.8 20.9l.3 .9 .3-.9M220.5 21.8h.6M221.4 20.9v.9M222.2 20.9v.9l-.4-.9v.9" fill="none" stroke="#007170" stroke-width=".21"/>
<path d="M218.7 19.6h27v5.2h-27z" fill="none" stroke="#980000" stroke-width=".21"/>
<path d="M216.1 103.7h.4l.4 .4-.4 .5h-.4z" fill="#fff"/>
<path d="M216.1 103.7h.4l.4 .4-.4 .5h-.4z" fill="none" stroke="#805e00" stroke-width=".21"/>
<path d="M217.3 104.1h.5v-.4h-.5v.9M217.6 104.1l.2 .5M218.2 104.3l.4-.1-.2-.2h-.2v.6h.3M219.3 104h-.4l.1 .3h.3v.3h-.4M219.5 104.6h.6M220.8 103.7h-.3l-.2 .2v.5l.2 .2h.3v-.4h-.2M221.7 103.7v.9l-.5-.9v.9M222.1 103.7h.3l.2 .2v.5l-.2 .2h-.3z" fill="none" stroke="#007170" stroke-width=".21"/>
<path d="M233.9 102.9h.5v.8h-.5l-.4-.4z" fill="#fff"/>
<path d="M233.9 102.9h.5v.8h-.5l-.4-.4z" fill="none" stroke="#805e00" stroke-width=".21"/>
<path d="M228.7 103.3l.5-.1v-.3h-.5v.8M228.9 103.3l.3 .4M229.5 103.4l.4-.1v-.2h-.4v.5h.4M230.6 103.1h-.3v.3l.3 .1-.1 .2-.2-.1M230.8 103.8h.7M231.6 102.9h.6a.47 .47 0 0 1-.4 .8l-.2-.2zM233.1 102.9v.8l-.5-.8v.8" fill="none" stroke="#007170" stroke-width=".21"/>
<path d="M216.1 102.4h18.3v2.7h-18.3z" fill="none" stroke="#980000" stroke-width=".21"/>
<path d="M216.1 97.6h.4l.4 .4-.4 .5h-.4z" fill="#fff"/>
<path d="M216.1 97.6h.4l.4 .4-.4 .5h-.4z" fill="none" stroke="#805e00" stroke-width=".21"/>
<path d="M217.3 98h.5v-.4h-.5v.9M217.6 98l.2 .5M218.2 98.2l.4-.1-.2-.2-.2 .1v.5h.3M219.3 98h-.4l.1 .2h.3v.3h-.4M219.5 98.5h.6M220.8 97.6h-.3l-.2 .2v.5l.2 .2h.3v-.4h-.2M221.7 97.6v.9l-.5-.9v.9M222.1 97.6h.3l.2 .2v.5l-.2 .2h-.3z" fill="none" stroke="#007170" stroke-width=".21"/>
<path d="M233.9 96.8h.5v.8h-.5l-.4-.4z" fill="#fff"/>
<path d="M233.9 96.8h.5v.8h-.5l-.4-.4z" fill="none" stroke="#805e00" stroke-width=".21"/>
<path d="M228.7 97.2l.5-.1v-.3l-.5-.1v.9M228.9 97.2l.3 .4M229.5 97.3l.4-.1v-.2h-.4v.5h.4M230.6 97h-.3v.3h.2l.1 .2h-.3M230.8 97.7h.7M231.8 96.7a.47 .47 0 0 1 .5 .4 .47 .47 0 0 1-.5 .5l-.2-.2v-.5zM233.1 96.7v.9l-.5-.9v.9" fill="none" stroke="#007170" stroke-width=".21"/>
<path d="M216.1 96.3h18.3v2.7h-18.3z" fill="none" stroke="#980000" stroke-width=".21"/>
<path d="M216.1 91.5h.4l.4 .4-.4 .5h-.4z" fill="#fff"/>
<path d="M216.1 91.5h.4l.4 .4-.4 .5h-.4z" fill="none" stroke="#805e00" stroke-width=".21"/>
<path d="M217.3 91.9h.5v-.4h-.5v.9M217.6 91.9l.2 .5M218.2 92.1l.4-.1-.2-.2-.2 .1v.4h.3M219.3 91.9h-.4l.1 .2h.3l-.1 .3-.3-.1M219.5 92.5h.6M220.8 91.5h-.3l-.2 .2 .1 .6h.4v-.3h-.2M221.7 91.5v.9l-.5-.9v.9M222.1 91.5h.3l.2 .2v.5l-.3 .2h-.2z" fill="none" stroke="#007170" stroke-width=".21"/>
<path d="M233.9 90.7h.5v.8h-.5l-.4-.4z" fill="#fff"/>
<path d="M233.9 90.7h.5v.8h-.5l-.4-.4z" fill="none" stroke="#805e00" stroke-width=".21"/>
<path d="M228.7 91.1l.5-.1v-.3l-.5-.1v.9M228.9 91.1l.3 .4M229.5 91.2l.4-.1v-.2h-.4v.5h.4M230.6 90.9h-.3v.3h.2l.1 .2h-.3M230.8 91.6h.7M231.8 90.6a.47 .47 0 0 1 .5 .5 .47 .47 0 0 1-.5 .4l-.2-.2v-.5zM233.1 90.6v.9l-.5-.9v.9" fill="none" stroke="#007170" stroke-width=".21"/>
<path d="M216.1 90.2h18.3v2.7h-18.3z" fill="none" stroke="#980000" stroke-width=".21"/>
<path d="M216.1 54.9h.4l.4 .5-.4 .4h-.4z" fill="#fff"/>
<path d="M216.1 54.9h.4l.4 .5-.4 .4h-.4z" fill="none" stroke="#805e00" stroke-width=".21"/>
<path d="M217.3 55.4h.4l.1-.2-.1-.3h-.4v.9M217.6 55.4l.2 .4M218.2 55.5l.4-.1-.1-.2h-.3v.5h.3M219.3 55.2h-.4v.3h.4l-.1 .3-.3-.1M219.5 55.9h.6M220.8 54.9h-.2l-.3 .2v.4l.3 .3 .2-.1v-.3h-.2M221.7 54.9v.9l-.5-.9v.9M222.1 54.9h.2l.3 .2v.4l-.3 .3h-.2z" fill="none" stroke="#007170" stroke-width=".21"/>
<path d="M233.9 54h.5v.9h-.5l-.4-.4z" fill="#fff"/>
<path d="M233.9 54h.5v.9h-.5l-.4-.4z" fill="none" stroke="#805e00" stroke-width=".21"/>
<path d="M228.7 54.4h.4l.1-.3-.5-.1v.9M228.9 54.4l.3 .5M229.5 54.6l.4-.1-.1-.2-.3 .1v.5h.4M230.6 54.4h-.3l.1 .2h.2v.3h-.3M230.8 54.9h.7M231.6 54.1h.6v.5l-.1 .3-.5-.1zM233.1 54v.9l-.5-.9v.9" fill="none" stroke="#007170" stroke-width=".21"/>
<path d="M216.1 53.6h18.3v2.6h-18.3z" fill="none" stroke="#980000" stroke-width=".21"/>
<path d="M216.1 61h.4l.4 .5-.4 .4h-.4z" fill="#fff"/>
<path d="M216.1 61h.4l.4 .5-.4 .4h-.4z" fill="none" stroke="#805e00" stroke-width=".21"/>
<path d="M217.3 61.5h.4l.1-.2-.1-.3h-.4v.9M217.6 61.5l.2 .4M218.2 61.5h.4l-.1-.2h-.3v.5h.3M219.3 61.3h-.4v.2l.4 .1-.1 .3-.3-.1M219.5 62h.6M220.8 61h-.2l-.3 .2v.4l.3 .3 .2-.1v-.3h-.2M221.7 61v.9l-.5-.9v.9M222.1 61h.2l.3 .2v.4l-.3 .3h-.2z" fill="none" stroke="#007170" stroke-width=".21"/>
<path d="M233.9 60.1h.5v.9h-.5l-.4-.4z" fill="#fff"/>
<path d="M233.9 60.1h.5v.9h-.5l-.4-.4z" fill="none" stroke="#805e00" stroke-width=".21"/>
<path d="M228.7 60.5h.4l.1-.3-.5-.1v.9M228.9 60.5l.3 .5M229.5 60.7l.4-.1-.1-.2h-.3v.6h.4M230.6 60.4h-.3l.1 .3h.2v.3h-.3M230.8 61h.7M231.8 60.1l.4 .3-.1 .6-.5-.1v-.6zM233.1 60.1v.9l-.5-.9v.9" fill="none" stroke="#007170" stroke-width=".21"/>
<path d="M216.1 59.7h18.3v2.6h-18.3z" fill="none" stroke="#980000" stroke-width=".21"/>
<path d="M216.1 67.1h.4l.4 .5-.4 .4h-.4z" fill="#fff"/>
<path d="M216.1 67.1h.4l.4 .5-.4 .4h-.4z" fill="none" stroke="#805e00" stroke-width=".21"/>
<path d="M217.3 67.6h.4l.1-.4-.1-.1h-.4v.9M217.6 67.6l.2 .4M218.2 67.6h.4l-.1-.2h-.3v.5h.3M219.3 67.4h-.4v.2l.4 .1-.1 .3-.3-.1M219.5 68.1h.6M220.8 67.1h-.2l-.3 .2v.4l.3 .3 .2-.1v-.3h-.2M221.7 67.1v.9l-.5-.9v.9M222.1 67.1h.2l.3 .2v.4l-.3 .3h-.2z" fill="none" stroke="#007170" stroke-width=".21"/>
<path d="M233.5 66.7l.4-.4h.5v.8h-.5z" fill="#fff"/>
<path d="M233.9 66.3h.5v.8h-.5l-.4-.4z" fill="none" stroke="#805e00" stroke-width=".21"/>
<path d="M228.7 66.6h.5v-.3l-.5-.1v.9M228.9 66.6l.3 .5M229.5 66.8l.4-.1v-.2h-.4v.6h.4M230.6 66.5h-.3l.1 .3h.2v.3h-.3M230.8 67.1h.7M231.8 66.2a.47 .47 0 0 1 .4 .3 .47 .47 0 0 1-.1 .6l-.5-.1v-.6zM233.1 66.2v.9l-.5-.9v.9" fill="none" stroke="#007170" stroke-width=".21"/>
<path d="M216.1 65.8h18.3v2.6h-18.3z" fill="none" stroke="#980000" stroke-width=".21"/>
<path d="M216.1 85.4h.4l.4 .4-.4 .5h-.4z" fill="#fff"/>
<path d="M216.1 85.4h.4l.4 .4-.4 .5h-.4z" fill="none" stroke="#805e00" stroke-width=".21"/>
<path d="M217.3 85.8h.5v-.4h-.5v.9M217.6 85.8l.2 .5M218.2 85.9l.4-.1-.2-.1-.2 .1v.4h.3M219.3 85.8h-.4v.1l.4 .1-.1 .3-.3-.1M219.5 86.4h.6M220.8 85.4h-.3l-.2 .2v.4l.3 .3 .2-.1v-.4h-.2M221.7 85.4v.9l-.5-.9v.9M222.1 85.4h.3l.2 .2v.4l-.3 .3h-.2z" fill="none" stroke="#007170" stroke-width=".21"/>
<path d="M233.5 85l.4-.4h.5v.8h-.5z" fill="#fff"/>
<path d="M233.9 84.6h.5v.8h-.5l-.4-.4z" fill="none" stroke="#805e00" stroke-width=".21"/>
<path d="M228.7 85l.5-.1v-.3l-.5-.1v.9M228.9 85l.3 .4M229.5 85.1l.4-.1v-.2h-.4v.5h.4M230.6 84.8h-.3v.3l.3 .1-.1 .2-.2-.1M230.8 85.5h.7M231.8 84.5a.47 .47 0 0 1 .5 .5 .47 .47 0 0 1-.5 .4l-.2-.1v-.6zM233.1 84.5v.9l-.5-.9v.9" fill="none" stroke="#007170" stroke-width=".21"/>
<path d="M216.1 84.2h18.3v2.6h-18.3z" fill="none" stroke="#980000" stroke-width=".21"/>
<path d="M216.1 73.2h.4l.4 .5-.4 .4h-.4z" fill="#fff"/>
<path d="M216.1 73.2h.4l.4 .5-.4 .4h-.4z" fill="none" stroke="#805e00" stroke-width=".21"/>
<path d="M217.3 73.7h.4l.1-.4-.1-.2h-.4v1M217.6 73.7l.2 .4M218.2 73.7h.4l-.1-.2h-.3v.5h.3M219.3 73.5h-.4v.2l.4 .1-.1 .3-.3-.1M219.5 74.2h.6M220.8 73.2l-.2-.1-.3 .3v.4l.3 .3 .2-.1v-.3h-.2M221.7 73.1v1l-.5-1v1M222.1 73.1h.2l.3 .3v.4l-.3 .3h-.2z" fill="none" stroke="#007170" stroke-width=".21"/>
<path d="M233.9 72.4h.5v.8h-.5l-.4-.4z" fill="#fff"/>
<path d="M233.9 72.4h.5v.8h-.5l-.4-.4z" fill="none" stroke="#805e00" stroke-width=".21"/>
<path d="M228.7 72.8l.5-.1v-.3l-.5-.1v.8M228.9 72.8l.3 .3M229.5 72.9l.4-.1v-.2h-.4v.5h.4M230.6 72.6h-.3v.3h.2l.1 .2h-.3M230.8 73.2h.7M231.8 72.3a.47 .47 0 0 1 .4 .3 .47 .47 0 0 1-.1 .5h-.5v-.6zM233.1 72.3v.8l-.5-.8v.8" fill="none" stroke="#007170" stroke-width=".21"/>
<path d="M216.1 71.9h18.3v2.6h-18.3z" fill="none" stroke="#980000" stroke-width=".21"/>
<path d="M216.1 79.3h.4l.4 .5-.4 .4h-.4z" fill="#fff"/>
<path d="M216.1 79.3h.4l.4 .5-.4 .4h-.4z" fill="none" stroke="#805e00" stroke-width=".21"/>
<path d="M217.3 79.8h.4l.1-.2v-.3h-.5v.9M217.6 79.8l.2 .4M218.2 79.8h.4l-.1-.2h-.3v.5h.3M219.3 79.6h-.4v.2l.4 .1-.1 .3-.3-.1M220.8 79.3h-.3l-.2 .2v.4l.3 .3 .2-.1v-.3h-.2M221.7 79.3v.9l-.5-.9v.9M222.1 79.3h.3l.2 .2v.4l-.3 .3h-.2zM219.5 80.3h.6" fill="none" stroke="#007170" stroke-width=".21"/>
<path d="M233.9 78.5h.5v.8h-.5l-.4-.4z" fill="#fff"/>
<path d="M233.9 78.5h.5v.8h-.5l-.4-.4z" fill="none" stroke="#805e00" stroke-width=".21"/>
<g fill="none" stroke="#007170" stroke-width=".21">
<path d="M228.7 78.9l.5-.1v-.3l-.5-.1v.9M228.9 78.9l.3 .4M229.5 79l.4-.1v-.2h-.4v.5h.4M230.6 78.7h-.3v.3l.3 .1-.1 .2-.2-.1M230.8 79.4h.7M231.8 78.4a.47 .47 0 0 1 .5 .5 .47 .47 0 0 1-.5 .4l-.2-.1v-.6zM233.1 78.4v.9l-.5-.9v.9M249.4 79.8h.4l.1-.2-.1-.3h-.4v.9M250.3 79.4l.3-.1 .1 .2v.5l-.2 .2a.48 .48 0 0 1-.2-.8zM251.1 79.4l.4-.1v.2v.5l-.1 .2a.48 .48 0 0 1-.3-.8zM256.6 79.9l-.1 .3 .3 .2 .6-.1v-.4M256.6 79.1l-.1 .2 .3 .3h.4l.3-.3-.1-.2"/>
<path d="M263.1 79.3l-.5 .1 .1 .3 .4 .1v.3h-.5M263.5 79.3h.3a.48 .48 0 0 1 .2 .6 .48 .48 0 0 1-.5 .3zM264.3 79.9h.4M249.4 81.5h.4l.1-.3-.1-.2h-.4v.9M249.4 83.2h.4v-.4h-.4v.8M249.4 85h.4l.1-.2-.1-.3h-.4v.9M249.4 86.7h.4v-.4h-.4v.8M249.4 88.5h.4l.1-.4-.5-.1v.9M249.4 90.2h.4l.1-.3-.1-.2h-.4v.9M249.4 91.9h.4v-.4h-.4v.9M249.4 95.4h.4v-.4h-.4v.8M249.4 97.2h.4l.1-.3-.1-.2h-.4v.9"/>
<path d="M249.4 98.9h.4l.1-.3-.1-.1h-.4v.8M250.2 95.2l.2-.2v.8M250.2 96.9l.2-.2v.9M250.2 98.7l.2-.2v.8M250.2 95.8h.5M250.2 97.6h.5M250.2 99.3h.5M250.3 81.1l.2-.1 .2 .2-.1 .7h-.2l-.2-.3zM250.3 82.9l.3-.1 .1 .2-.1 .6a.39 .39 0 0 1-.4-.2 .39 .39 0 0 1 .1-.5zM250.3 84.6l.2-.1 .2 .2v.6l-.2 .1a.53 .53 0 0 1-.2-.8zM250.3 86.4l.3-.1 .1 .1-.1 .6a.39 .39 0 0 1-.4-.2 .39 .39 0 0 1 .1-.4zM250.3 88l.4 .1v.6l-.2 .2a.53 .53 0 0 1-.2-.9z"/>
<path d="M250.3 89.8l.2-.1 .2 .2-.1 .6a.39 .39 0 0 1-.4-.2 .39 .39 0 0 1 .1-.5zM250.3 91.6l.3-.1 .1 .2v.5l-.2 .2a.48 .48 0 0 1-.2-.8zM251 81.3l.3-.3v.9M251 82.9h.5v.2l-.5 .5h.5M251 84.5h.5l-.2 .3 .2 .1v.4h-.5M251 91.5h.6l-.4 .9M251 96.9l.3-.2v.9M251 98.5h.5v.3l-.5 .5h.5M251 81.9h.5M251 97.6h.5M251.1 95.1l.4-.1v.8a.39 .39 0 0 1-.5-.3 .39 .39 0 0 1 .1-.4zM251.3 86.2l-.3 .7h.6"/>
<path d="M251.5 89.7l-.3 .1-.2 .6 .1 .2 .4-.1v-.3l-.3-.1-.2 .1M251.5 86.5v.6M251.5 88h-.4l-.1 .4h.5v.4h-.5M256.5 80.7l1 .3-1 .3M263 82.5h1.8M263.1 82.8v.8M263.1 81.1l-.3-.1-.2 .2 .1 .2 .4 .2v.3h-.5M264 81.1l-.3-.1-.2 .3v.4l.1 .2 .4-.1M264 82.8v.8l-.5-.8v.8M264.2 80.2l.3-.9 .3 .9M264.3 82.8h.5M264.4 81v.9h.4"/>
<path d="M264.6 82.8v.8M249.4 100.7h.4v-.5h-.4v.9M249.4 102.4h.4l.1-.3-.1-.2h-.4v1M249.4 104.1h.4v-.4h-.4v.9M249.4 105.9h.4l.1-.3-.1-.2h-.4v.9M249.4 107.6h.4l.1-.2-.1-.2h-.4v.8M250.2 100.5l.2-.3v.9M250.2 102.2l.2-.3v1M250.2 104l.2-.3v.9M250.2 105.7l.2-.3v.9M250.2 107.4l.2-.2v.8M250.2 106.3h.5"/>
<path d="M250.2 101.1h.5M250.2 102.9h.5M250.2 104.6h.5M250.2 108h.5M251 100.2h.5l-.2 .4 .2 .1v.3h-.5M251 107.2h.6l-.4 .8M251.3 101.9l-.3 .6h.6M251.5 105.4l-.3 .1-.2 .7 .2 .1h.3v-.5l-.3-.1-.2 .2M251.5 102.3v.6M251.5 103.7h-.4l-.1 .4 .5-.1v.5h-.5M256.5 106.9h1l-1 .5h1M256.6 107.9h-.1a.43 .43 0 0 0 .5 .5 .43 .43 0 0 0 .4-.5h-.4v.1"/>
<path d="M256.7 106.1a.51 .51 0 0 1 .8 .4h-1zM263.4 104.6l.2-.9 .4 .9M263.4 106.3l.2-.9 .4 .9M263.4 108l.2-.8 .4 .8M263.5 104.3h.4M263.5 106.1h.4M263.5 107.8h.4M264.2 103.8l.5-.1v.3l-.5 .6h.5M264.2 105.7l.3-.3v.9M264.2 106.3h.5M264.4 107.2a.43 .43 0 0 1 .4 .4 .43 .43 0 0 1-.5 .4l-.1-.6zM88.1 132.1h.4l.1-.4-.1-.1h-.4v.9"/>
<path d="M88.1 133.8h.5v-.5h-.5v.9M88.1 135.5h.4l.1-.3-.1-.2h-.4v1M88.1 137.2h.5v-.2l-.1-.2h-.4v.9M88.1 139h.5v-.4h-.5v.8M89.1 133.3a.42 .42 0 0 1 .4 .5 .42 .42 0 0 1-.4 .4zM89.1 138.6a.43 .43 0 0 1 .4 .4 .43 .43 0 0 1-.4 .4l-.1-.1zM89.1 131.6a.48 .48 0 0 1 .4 .4 .48 .48 0 0 1-.4 .5l-.1-.2v-.6zM89.1 135a.48 .48 0 0 1 .4 .5 .48 .48 0 0 1-.4 .5l-.1-.2v-.6zM89.1 136.8a.43 .43 0 0 1 .4 .5 .43 .43 0 0 1-.4 .4l-.1-.7zM89.7 136.8h.5l-.2 .4h.2v.4h-.5M89.8 133.6l.2-.3v.9M89.8 135.1h.4v.4l-.5 .5h.5"/>
<path d="M89.8 134.2h.4M90 131.6l.2 .1v.6l-.1 .2-.3-.2v-.6zM90 138.5l-.2 .7h.5M90.2 138.8v.6M95.3 133l.9 .3-.9 .3M95.4 132.2l-.1 .4 .2 .2h.4l.3-.3-.1-.3M95.4 131.4l-.1 .3a.43 .43 0 0 0 .5 .2 .43 .43 0 0 0 .3-.5M101.7 134.9h1.8M101.8 131.7h-.5v.2l.5 .3-.1 .3-.4-.1M101.8 133.3h-.4l-.1 .2 .2 .3 .3 .1v.2l-.5 .1M101.8 135v1M102.2 131.6h.2l.3 .2v.4l-.3 .3h-.2z"/>
<path d="M102.8 133.4l-.4-.1-.2 .4 .2 .5 .4-.1M102.8 135v1l-.5-1v1M102.9 132.5l.3-.9 .3 .9M103 132.2h.5M103 135h.5M103.1 133.3v.9h.4M103.3 135v1M88.1 140.8h.4l.1-.3-.1-.2h-.4v.9M88.1 142.5h.5v-.4h-.5v.8M88.1 144.3h.4l.1-.2-.1-.3h-.4v.9M88.1 147.7h.5v-.4h-.5v.9M88.1 149.5h.4l.1-.3-.1-.2h-.4v.9"/>
<path d="M88.1 151.2h.5v-.4h-.5v.8M88.1 153h.4l.1-.2-.1-.3h-.4v.9M88.1 154.7h.5v-.4h-.5v.8M88.1 156.5h.4l.1-.2v-.3h-.5v.9M88.1 158.2h.4l.1-.1-.1-.4h-.4v.9M88.1 159.9h.5v-.4h-.5v.9M89 147.6l.2-.3v.9M89 149.3l.2-.3v.9M89 151l.2-.2v.8M89 152.7l.2-.2v.9M89 154.5l.2-.2v.8M89 156.3l.2-.3v.9"/>
<path d="M89 158l.2-.3v.9M89 159.8l.2-.3v.9M89 158.6h.5M89 148.2h.5M89 149.9h.5M89 151.6h.5M89 153.4h.5M89 155.1h.5M89 156.9h.5M89.1 142.1a.42 .42 0 0 1 .4 .4 .42 .42 0 0 1-.4 .4zM89.1 140.3a.48 .48 0 0 1 .4 .5 .48 .48 0 0 1-.4 .4l-.1-.2v-.5zM89.1 143.8a.48 .48 0 0 1 .4 .4 .48 .48 0 0 1-.4 .5l-.1-.2v-.6z"/>
<path d="M89.7 143.8h.6l-.4 .9M89.7 152.5h.5l-.2 .3 .2 .1v.4h-.5M89.7 159.5h.6l-.4 .9M89.8 149.3l.2-.3v.9M89.8 150.9l.4-.1v.3l-.5 .5h.5M89.8 149.9h.4M89.9 147.3h.3v.2v.5l-.1 .2-.3-.2zM90 154.2l-.2 .6h.5M90.2 142.1h-.3l-.1 .1v.6h.4v-.4h-.3l-.1 .2M90.2 157.7l-.4 .3v.5h.4v-.3l-.3-.1-.1 .1M90.2 154.5v.6M90.2 140.3h-.4v.4h.4v.4h-.4"/>
<path d="M90.2 156h-.4v.4h.4v.4h-.4M95.3 159.3h.9l-.9 .5h.9M95.3 158.5a.48 .48 0 0 1 .6-.1 .48 .48 0 0 1 .3 .4h-.9zM102.1 156.9l.3-.9 .3 .9M102.1 158.6l.3-.9 .3 .9M102.2 156.6h.4M102.2 158.4h.4M102.9 156.1l.5-.1 .1 .3-.6 .6h.6M102.9 158l.3-.3v.9M102.9 158.6h.6M103 159.5a.42 .42 0 0 1 .5 .4 .42 .42 0 0 1-.5 .5zM89 160.4h.5"/>
<path d="M95.3 160.2v.3a.44 .44 0 0 0 .6 .1 .44 .44 0 0 0 .2-.5h-.3v.2M102.1 160.4l.3-.9 .3 .9M102.2 160.1h.4"/>
</g>
<g fill="none" stroke="#980000" stroke-width=".21">
<path d="M134.1 15.5h1.8v5.1l-.9 .7-.9-.7zM134.6 18.6v.4h.4v-.4l.3-.1 .2 .2-.1 .3M134.6 17.8l.9 .2-.9 .3M134.8 19.8h.7M135.1 19.5v.6M135.5 16.6h-.9l.3 .2M135.5 16.3v.5M135.5 17v.7M152.4 16.2h1.8v4.4l-.9 .7-.9-.7zM152.9 19.1v-.6l.3 .4v-.3l.2-.1 .3 .1v.5M152.9 17.8l.8 .2-.8 .3M152.9 17.5v-.5l.3 .3 .1-.3h.4v.5"/>
<path d="M153.1 19.8h.6M153.4 19.5v.6M199.7 17h10.3v1.7h-10.3l-.7-.8zM200.5 17.9h.3l.2-.1-.2-.4h-.3v1M201.3 17.8v.6M201.6 17.8l-.3 .1M201.9 17.8l.4 .1v.4l-.2 .1-.3-.2zM202.5 17.8h.4M202.7 17.4v.9l.2 .1M203.1 18l.4-.1v-.1l-.4 .1v.3l.2 .2 .2-.1M204.3 17.8h-.3l-.1 .1 .1 .5 .3-.1M204.5 17.8h.4"/>
<path d="M204.6 17.4v.8l.3 .2M205.1 18l.5-.1-.1-.1h-.4v.5h.4M206.3 17.8l-.4 .1v.4h.4M206.3 17.4v1M206.5 18.5h.7M207.3 17.7l.3-.3v1M207.3 18.4h.6M208.2 17.5h.4v.4l-.5 .5h.5M208.9 17.4l.3 1 .3-1M134.1 31.5l-.3 .3v-.1v.1h.1M134.2 23.9h1.5v3.5h-1.5zM134.2 31.3h1.5l-.8 1z"/>
<path d="M134.2 32.3h1.5M134.4 31.8l-.3 .4v-.2v.2h.2M135 35.3v.8h.9l-.9 1-.9-1h.9M135 35.3h.1M135 23.1v.9M135 27.4v1M135 30.1v3.4M152.4 31.5l-.3 .3v-.1v.1h.1M152.5 23.9h1.5v3.5h-1.5zM152.5 31.3h1.5l-.7 1zM152.5 32.3h1.5M152.7 31.8l-.3 .4v-.2v.2h.2"/>
<path d="M153.3 35.3v.8h.9l-.9 1-.9-1h.9M153.3 35.3h.1M153.3 23.1v.9M153.3 27.4v1M153.3 30.1v3.4M163.1 22.3h10.4l.7 .8-.7 .9h-10.4zM163.9 22.7v.8M164.8 22.8l-.3-.1-.3 .2v.5l.2 .1h.4v-.3h-.2M165.7 22.7v.8l-.5-.8v.8M166.1 20.5h7.4l.7 .8-.7 1h-7.4zM166.1 22.7v.8M166.4 22.7h.5"/>
<path d="M166.6 22.7v.8M167 21.3h.3l.1-.3-.4-.1v.9h.3l.2-.3-.3-.2M167.1 22.7v.8M167.7 22.7l.4 .2-.1 .6-.5-.1v-.5zM167.7 21.8l.3-.9 .3 .9M167.8 21.6h.4M168.4 20.9h.5M168.7 20.9v.9M169 22.7v.8l-.5-.8v.8M169.1 20.9h.5M169.2 23.6h.6M169.3 20.9v.9"/>
<path d="M169.8 21.2l.3-.3v.9M169.8 21.8h.5M169.9 23.5l.4-.8 .2 .8M170 23.3h.4M170.7 21l.3-.1 .2 .3-.6 .6h.6M171.2 23h-.4v.4l.4 .1M171.4 20.9l.3 .9 .3-.9M171.4 22.9h.4M171.5 22.7v.7l.3 .1M172 22.7v.8M172 23.1h.5M172.3 21.5h.7"/>
<path d="M172.5 22.7v.8M172.6 21.2v.6M173 22.7v.8M201.2 31.5l-.3 .3v-.1v.1h.2M201.4 23.9h1.3v3.5h-1.3zM201.4 31.3h1.3l-.6 1zM201.4 32.3h1.3M201.6 31.8l-.4 .4v-.2v.2h.2M202.1 35.3v.8h.9l-.9 1-.9-1h.9M202.1 35.3h.1M202.1 23.1v.9M202.1 27.4v1"/>
<path d="M202.1 30.1v3.4M253.6 24h.8M254.4 23.2h3.4v1.4h-3.4zM257.9 24h.8M266.6 23.1h5.1l.8 .9-.8 .9h-5.1zM267.2 24.1h.7M267.5 23.8v.7M268.7 23.5h-.4v.5h.4v.4h-.4M269 23.5l.3 1 .3-1M269.7 24.5h.6M270.5 23.8l.3-.3v1M270.5 24.5h.5"/>
<path d="M70.5 50l.9-.7 .8 .7v7.4h-1.7zM70.9 51.5l.9 .2-.9 .4M70.9 53.8v.6M70.9 54.5v.5M70.9 54.8h.9M70.9 54.1h.9M71.1 50.9h.7M71.4 56.2l.1-.2 .3 .1v.5h-.9v-.5l.3-.1 .2 .2v.4M71.5 50.5v.6M71.5 55.3v.4M71.8 55.2l-.9 .3 .9 .3M71.8 53.3h-.9l.3 .3"/>
<path d="M71.8 52.3v.5l-.5-.5-.4 .1 .1 .4M71.8 53.2v.4M74 50l.8-.7 .9 .7v5.1h-1.7zM74.4 52.7v.5h.4v-.5l.5 .1-.1 .4M74.4 51.9l.9 .2-.9 .4M74.7 53.9h.6M75 53.6v.7M75.3 50.7h-.9l.3 .3M75.3 50.5v.5M75.3 51.1v.7M191.8 48.3h12.1v1.8h-12.1l-.8-.8zM192.4 49.3h.4"/>
<path d="M192.9 48.8h-.5v.9M193.2 48.8l.1 .9h.3l.1-.9M194.1 49.3h.3M194.6 48.8h-.5v.9h.5M194.9 48.8v.9h.4M195.4 49.8h.7M196.3 48.8v.9h.4M196.8 48.8l.4 .9 .2-.9M197.8 48.8v.9h.3M198.2 49.8h.7M199.1 49.3h.5v-.5h-.5v.9M199.3 49.3l.3 .4"/>
<path d="M200.2 49.2l-.1-.1-.2 .2 .4 .3-.4 .1M200.7 49.4h.4l-.2-.3-.2 .1v.5h.3M201.4 49.2l.3-.1 .1 .2v.4M201.4 49.1v.6M202.5 49.2h-.3l.1 .2h.2v.3h-.3M202.9 49.4h.4l-.1-.3-.3 .2v.3l.4 .1M209.1 49.3h.9M209.1 55.4h.9M209.9 48.6h3.5v1.3h-3.5zM209.9 54.6h3.5v1.4h-3.5zM213.4 49.3h.9M213.4 55.4h.9"/>
<path d="M253.6 41.4h.8M254.4 40.7h3.4v1.3h-3.4zM256.2 58.9h1.7v4.4l-.9 .8-.8-.8zM257.9 41.4h.8M266.6 40.5h4.4l.8 .9-.8 .8h-4.4zM267.2 41.6h.7M267.5 41.2v.7M268.2 41h.5l-.2 .3 .2 .1v.4h-.5M269 41l.3 .9 .3-.9M269.8 41h.5l-.2 .3 .2 .1v.4h-.5M72.3 64.9h1.5v3.5h-1.5zM72.3 75.4h1.5v3.5h-1.5z"/>
<path d="M73.1 64.1v.8M73.1 68.4v.9M73.1 74.5v.9M73.1 78.9v.9M99.2 72.5l-.3 .3v-.2v.2h.2M99.4 64.9h1.4v3.5h-1.4zM99.4 72.3h1.4l-.7 1zM99.4 73.3h1.4M99.6 72.8l-.4 .3v-.1v.1h.2M100.2 76.3v.8h.8l-.8 1-1-1h1M100.2 76.3h.1M100.2 64.1v.8"/>
<path d="M100.2 68.4v.9M100.2 71v3.5M107.2 64.9h1.5v3.5h-1.5zM107.2 75.4h1.5v3.5h-1.5zM107.9 64.1v.8M107.9 68.4v.9M107.9 74.5v.9M107.9 78.9v.9M209.1 73.7h.9M209.1 61.5h.9M209.1 67.6h.9M209.1 79.8h.9"/>
<path d="M209.9 72.9h3.5v1.4h-3.5zM209.9 60.7h3.5v1.4h-3.5zM209.9 66.8h3.5v1.4h-3.5zM209.9 79h3.5v1.4h-3.5zM213.4 73.7h.9M213.4 61.5h.9M213.4 67.6h.9M213.4 79.8h.9M216.1 78.1h18.3v2.5h-18.3zM244.9 79.8h3.4M248.3 78h17.4v31.3h-17.4zM256.3 68.4h1.4v3.4h-1.4z"/>
<path d="M256.6 61.8v-.5l.4 .2v-.2h.4v.5M256.6 60.4l.9 .3-.9 .3M256.6 60.3v-.6l.4 .3v-.2l.1-.1 .4 .1-.1 .5M256.8 62.5h.7M257 67.6v.8M257 71.9v.9M257 74.5v3.6M257.1 62.1v.7M262.3 60.6h1.7v4.4l-.9 .8-.8-.8zM262.7 63.6v-.6l.4 .3 .1-.3 .4 .1-.1 .5M262.7 62.2l.9 .3-.9 .2M262.7 62v-.5l.4 .2v-.2h.4v.5"/>
<path d="M263 64.3h.6M263.1 71v.9h.9l-.9 .9-.8-.9h.8M263.1 71h.1M263.1 65.8v1.9M263.1 69.2v1.8M263.2 63.9v.7M265.8 79.8h3.4M69.6 87.6h1.9M71.5 86.2v2.7M71.8 86v.7M71.8 87.2v.7M71.8 88.4v.7"/>
<path d="M71.9 86.4h1.8v2.4h-1.8M73.1 92.9v.8h.9l-.9 .9-.9-.9h.9M73.1 92.9h.1M78.3 81.5h7.5l.7 .9-.7 .8h-7.5zM78.9 82.5l.5-.1v-.4h-.5v.8M79.2 82.5l.2 .3M79.8 82.5h.4l.1-.2-.1-.3h-.4v.8M80.7 82.8v-.8l.2 .6 .4-.6v.8M81.4 82.9h.7M82.4 82.4h.4M82.4 82v.8M82.8 82v.8"/>
<path d="M83.1 82.8l.3-.8 .3 .8M83.2 82.6h.4M84 82v.8h.4M84.7 82v.8h.4M113.2 81.5h9.8l.8 .9-.8 .8h-9.8zM113.7 82l.3 .8 .1-.6 .2 .6 .2-.8M114.6 82.8l.4-.8 .2 .8M114.7 82.6h.4M115.4 82h.5M115.6 82v.8M116.2 82.4h.3M116.7 82h-.5v.8h.5"/>
<path d="M117 82.5h.3l.2-.2-.2-.3h-.3v.8M117.2 82.5l.3 .3M117.7 82.9h.7M118.4 82h.5M118.7 82v.8M119 82.9h.6M119.9 82.5h.3l.2-.4-.2-.1h-.3v.8M120.6 82l.3 .8 .1-.6 .2 .6 .2-.8M121.7 82.8v-.8l.3 .6 .3-.6v.8M209.1 85.8h.9M209.1 91.9h.9M209.1 98h.9"/>
<path d="M209.9 85.1h3.5v1.4h-3.5zM209.9 91.2h3.5v1.5h-3.5zM209.9 97.3h3.5v1.5h-3.5zM213.4 85.8h.9M213.4 91.9h.9M213.4 98h.9M244.9 91.9h3.4M244.9 81.5h3.4M244.9 83.2h3.4M244.9 85h3.4M244.9 86.8h3.4M244.9 88.5h3.4"/>
<path d="M244.9 90.2h3.4M244.9 95.4h3.4M244.9 97.2h3.4M244.9 99h3.4M265.8 81.5h3.4M265.8 83.2h3.4M16.7 114.6h11.1l.8 .9-.8 .9h-11.1zM17.7 115.1l.3 .1v.6l-.1 .2a.49 .49 0 0 1-.5-.4 .49 .49 0 0 1 .3-.5zM18.5 115.1v.9M18.5 102.4h9.3l.8 .9-.8 .8h-9.3zM18.9 115.1v.9h.3M19.3 108.5h8.5l.8 .9-.8 .8h-8.5z"/>
<path d="M19.3 116.1h.7M19.4 103.3h.3l.1-.4h-.4v.9h.3l.2-.3-.3-.2M20.1 116l.3-.9 .3 .9M20.1 109.5l.6-.1v-.4h-.6v.9M20.1 115.7h.5M20.2 103.4l.5-.1v-.4h-.5v.9M20.5 103.4l.2 .4M20.9 109.9l.3-.9 .3 .9M21 115.1v.9h.3M21 103.8l.2-.9 .4 .9M21 109.6h.4M21.1 103.5h.4"/>
<path d="M21.7 115.6h.3l.2-.2-.2-.3h-.3v.9M21.8 109.5l.5-.1v-.4h-.5v.9M21.8 115.6l.4 .4M21.8 102.9v.9M22 109.5l.3 .4M22 103.3l.3 .5M22.3 102.9l-.5 .5M22.5 116v-.9l.4 .6 .2-.6v.9M22.7 109v.9M22.8 109.4l.4 .5M22.8 103.3h.2M23.2 102.9h-.4v.9h.4"/>
<path d="M23.2 109l-.5 .5M23.3 116.1h.7M23.3 110h.7M23.3 103.9h.7M24 116l.4-.9 .2 .9M24 109.9l.4-.9 .2 .9M24 103.8l.4-.9 .2 .9M24.1 115.7h.4M24.1 109.6h.4M24.1 103.5h.4M25.3 115.4h-.3l-.1 .2 .2 .4 .2-.1M25.3 109.3h-.3l-.1 .2 .2 .4 .2-.1"/>
<path d="M25.3 103.2h-.3l-.1 .2 .2 .4 .2-.1M25.6 115.4h.3M25.6 109.3h.3M25.6 103.2h.3M25.6 115.1v.7l.3 .2M25.6 109v.7l.3 .2M25.6 102.9v.7l.3 .2M26.2 115.1v.9h.4M26.2 109v.9h.4M26.2 102.9v.9h.4M27.1 115.1l.3 .1v.6l-.1 .2a.49 .49 0 0 1-.5-.4 .49 .49 0 0 1 .3-.5zM27.1 109l.3 .1v.6l-.1 .2a.49 .49 0 0 1-.5-.4 .49 .49 0 0 1 .3-.5z"/>
<path d="M27.1 102.9l.3 .1v.6l-.1 .2a.49 .49 0 0 1-.5-.4 .49 .49 0 0 1 .3-.5zM94.9 113.8h1.7v4.4l-.8 .8-.9-.8zM95.3 116.7v-.5l.4 .3 .1-.3h.3l.2 .1-.1 .4M95.3 115.4l1 .2-1 .4M95.3 115.1v-.5l.4 .3 .1-.3h.4v.5M95.6 117.4h.7M95.9 117.1v.7M101 112.9h1.8v4.4l-1 .8-.8-.8zM101.4 115.9v-.6l.4 .3 .1-.3h.3l.2 .2-.1 .4M101.4 114.5l1 .3-1 .3M101.4 114.3v-.5l.4 .2v-.2h.5v.5M101.7 116.5h.7"/>
<path d="M101.8 118.1v2M102 116.2v.6M156.8 100.1h1.7v5.1l-.9 .7-.8-.7zM156.9 108.5h1.4v3.5h-1.4zM157.2 103.2v.3l.4 .1v-.3l.4-.2 .2 .2-.1 .3M157.2 102.3l1 .3-1 .3M157.5 104.3h.7M157.6 107.7v.8M157.6 112v.9M157.8 104v.6M158.2 101.1h-1l.3 .2M158.2 100.9v.4"/>
<path d="M158.2 101.5v.7M158.5 100.7h1.8v4.5l-.9 .7-.9-.7zM158.7 108.5h1.4v3.5h-1.4zM159 103.6v-.5l.3 .3 .2-.3 .3 .1v.4M159 102.3l.8 .3-.8 .3M159 102.1v-.6l.3 .3v-.2h.5v.5M159.2 104.3h.6M159.4 107.7v.8M159.4 112v.9M159.5 104v.6M190.7 116l-.3 .4v-.2v.2h.2M190.9 108.5h1.4v3.5h-1.4z"/>
<path d="M190.9 115.8h1.4l-.7 1.1zM190.9 116.9h1.4M191.2 116.4l-.5 .3v-.1v.1h.2M191.7 119.9v.8h.8l-.8 .9-1-.9h1M191.7 119.9h.1M191.7 107.7v.8M191.7 112v.9M191.7 114.6v3.5M209.1 110.2h.9M209.1 116.4h.9M209.1 104.1h.9M209.9 109.5h3.5v1.4h-3.5z"/>
<path d="M209.9 115.6h3.5v1.4h-3.5zM209.9 103.4h3.5v1.5h-3.5zM213.4 110.2h.9M213.4 116.4h.9M213.4 104.1h.9M244.9 104.1h3.4M244.9 105.9h3.4M244.9 107.7h3.4M244.9 100.7h3.4M244.9 102.4h3.4M257 112.9v.9h.9l-.9 .8-.8-.8h.8M257 112.9h.1"/>
<path d="M257 109.4v3.5M265.8 104.1h3.4M265.8 105.9h3.4M265.8 107.7h3.4M272.6 106.8h4.4l.8 .9-.8 .8h-4.4l-.7-.8zM273.1 107.8h.7M273.5 107.4v.7M274.1 107.3h.6l-.4 .3h.3v.5l-.5-.1M274.9 107.3l.3 .8 .3-.8M275.7 107.3h.6l-.4 .3h.3v.5l-.5-.1M18.2 132.9h9.6l.8 .9-.8 .9h-9.6zM18.2 120.7h9.6l.8 .9-.8 .9h-9.6z"/>
<path d="M18.9 139h8.9l.8 .9-.8 .9h-8.9zM18.9 122.1l.2-.9 .4 .9M19 121.8h.4M19 133.4v.9h.5M19.6 134.4h.6M19.7 121.2v.9M20.1 121.7l.6-.1v-.4h-.6v.9M20.3 126.8h7.5l.8 .9-.8 .9h-7.5zM20.4 133.9h.3l.2-.2-.1-.3h-.4v.9l.5-.1v-.3h-.2M20.4 121.7l.3 .4M20.5 139.5v.9h.4M21 121.6h.4l.1-.3-.2-.1h-.3v.9l.5-.1v-.3l-.2-.1"/>
<path d="M21.2 133.9h.4M21.7 127.4l-.5-.1a.44 .44 0 0 0-.1 .6 .44 .44 0 0 0 .6 .2M21.7 133.4h-.5v.9h.5M21.8 122.1l.3-.9 .2 .9M21.8 121.8h.5M21.9 134.3l.4-.9 .2 .9M21.9 139.9h.4l.1-.3-.5-.1v.9M22 127.7h.3M22 134h.4M22.2 139.9l.2 .5M22.4 127.3h-.4v.9h.4M22.9 127.3v.9h.3"/>
<path d="M22.9 134.3v-.9l.2 .6 .3-.6v.9M23.1 121.2a.41 .41 0 0 0-.5 .5 .41 .41 0 0 0 .6 .3v-.3h-.2M23.3 128.3h.7M23.3 122.2h.7M23.6 134.4h.7M24 128.2l.4-.9 .2 .9M24 122.1l.4-.9 .2 .9M24.1 127.9h.4M24.1 121.8h.4M24.4 134.3l.2-.9 .4 .9M24.5 134h.4M25.3 127.6h-.3l-.1 .2 .2 .4 .2-.1"/>
<path d="M25.3 121.5h-.3l-.1 .2 .2 .4 .2-.1M25.6 133.8h-.4v.4h.4M25.6 139.9h-.4v.4l.4 .1M25.6 127.6h.3M25.6 121.5h.3M25.6 127.3v.7l.3 .2M25.6 121.2v.7l.3 .2M25.8 133.7h.4M25.8 139.8h.4M26 133.4v.8l.2 .1M26 139.5v.9h.2M26.2 127.3v.9h.4"/>
<path d="M26.2 121.2v.9h.4M26.5 133.9h.5M26.5 133.4v.9M26.5 139.5v.9M26.5 139.9h.5M26.9 127.4h.5v.6l-.1 .2a.47 .47 0 0 1-.4-.3 .47 .47 0 0 1 0-.5zM27 133.4v.9M27 139.5v.9M27.1 121.2l.3 .1v.6l-.1 .2a.49 .49 0 0 1-.5-.4 .49 .49 0 0 1 .3-.5zM27.4 133.4v.9M27.4 139.5v.9M83.6 132.1h3.4"/>
<path d="M83.6 133.8h3.4M83.6 135.5h3.4M83.6 137.3h3.4M83.6 139h3.4M87 130.3h17.4v31.4h-17.4zM95 121.5h1.4v3.6h-1.4zM95.8 120.7v.9M95.8 125.1v.9M95.8 126.8v3.5M101.8 123.4v.8h1l-1 .9-.8-.9h.8M101.8 123.4h.1M101.8 121.4v2"/>
<path d="M104.5 132.1h3.4M104.5 133.8h3.4M104.5 135.5h3.4M190.7 132.9h1M191.6 132.2h3.5v1.4h-3.5zM195.2 132.9h.8M197.6 132.1h4.4v1.7h-4.4l-.8-.9zM198.1 133.1h.7M198.5 132.8v.6M199.1 132.5h.5l-.2 .3 .2 .1v.4h-.5M199.9 132.5l.3 .9 .3-.9M200.7 132.5h.5l-.2 .3 .2 .1v.4h-.5"/>
<path d="M209.1 128.6h.9M209.1 134.7h.9M209.1 122.5h.9M209.9 127.8h3.5v1.4h-3.5zM209.9 134h3.5v1.3h-3.5zM209.9 121.7h3.5v1.4h-3.5zM213.4 128.6h.9M213.4 134.7h.9M213.4 122.5h.9M251.9 134.7h4.4l.7 .8-.7 .9h-4.4zM252.7 135.7h.7M253.1 135.4v.7"/>
<path d="M253.7 135.1h.5l-.3 .4 .3 .1v.3l-.1 .2-.4-.1M254.5 135.1l.3 1 .3-1M255.3 135.1h.6l-.4 .4 .4 .1v.3l-.2 .2-.4-.1M258 138.1h1.5v3.5h-1.5zM258.7 137.3v.9M264.1 138.1h1.5v3.5h-1.5zM264.9 137.3v.9M17.3 151.2h10.5l.8 .9-.8 .9h-10.5zM18.6 151.8l-.4-.1-.2 .4 .2 .5 .4-.1M19 151.8h.5l-.1 .8-.4-.1zM19.1 157.3h8.7l.8 .9-.8 .9h-8.7zM19.6 140.4l.3-.9 .3 .9"/>
<path d="M19.7 140.1h.4M19.9 151.8h.5l-.1 .8-.4-.1zM20 157.8l.4 .1 .1 .4-.2 .4h-.3zM20.2 145.1h7.6l.8 .9-.8 .9h-7.6zM20.8 157.9h.5l-.1 .8-.4-.1zM20.8 151.7v.9h.4M21.1 140.4l.2-.9 .4 .9M21.1 146h.4l-.1-.4h-.3v.9h.4l.1-.3-.3-.2M21.2 140.1h.4M21.3 152.6l.4-.9 .2 .9M21.4 152.3h.4M21.8 157.9h.5l-.1 .8-.4-.1z"/>
<path d="M21.8 145.6h.5M22.1 145.6v.9M22.7 158.2h.4v-.4h-.4v.9M22.8 151.7v.9l-.5-.9v.9M22.9 140.4v-.9l.2 .6 .3-.6v.9M22.9 158.2l.3 .5M23 151.7h.5M23.1 145.6v.9l-.5-.9v.9M23.3 146.6h.7M23.3 158.7h.7M23.3 151.7v.9M23.6 140.5h.7"/>
<path d="M23.6 152.6h.7M24 146.5l.4-.9 .2 .9M24 158.7l.4-.9 .2 .9M24.1 146.2h.4M24.1 158.4h.4M24.4 140.4l.2-.9 .4 .9M24.4 152.6l.2-.9 .4 .9M24.5 140.1h.4M24.5 152.3h.4M25.3 146l-.2-.1-.2 .1 .1 .5h.3M25.3 158.2l-.2-.1-.2 .1 .1 .5h.3M25.6 152.1h-.4v.4l.4 .1"/>
<path d="M25.6 145.9h.3M25.6 158.1h.3M25.6 145.6v.8l.3 .1M25.6 157.8v.8l.3 .1M25.8 152h.4M26 151.7v.9h.2M26.2 145.6v.9h.4M26.2 157.8v.9h.4M26.5 151.7v.9M26.5 152.1h.5M26.9 145.7h.5l-.1 .8-.4-.1zM26.9 157.9h.5l-.1 .8-.4-.1z"/>
<path d="M27 151.7v.9M27.4 151.7v.9M83.6 140.8h3.4M83.6 156.5h3.4M83.6 158.2h3.4M83.6 159.9h3.4M83.6 142.5h3.4M83.6 144.3h3.4M83.6 147.7h3.4M83.6 149.5h3.4M83.6 151.2h3.4M83.6 153h3.4"/>
<path d="M83.6 154.8h3.4M104.5 156.5h3.4M104.5 158.2h3.4M104.5 159.9h3.4M209.1 153v.8h.9l-.9 1-.9-1h.9M209.1 153h.1M209.1 140.8h.9M209.9 140.1h3.5v1.3h-3.5zM213.4 140.8h.9M258.7 141.6v.9M264.9 141.6v.9M17.8 169.6h10l.8 .8-.8 .9h-10z"/>
<path d="M18.3 175.7h9.5l.8 .8-.8 .9h-9.5zM18.6 170.4h.4l.1-.2-.1-.2h-.4v.9M18.9 170.4l.2 .5M19 176.1v.8h.5M19.3 170.9h.7M19.6 177h.6M20.1 170h.5M20.2 163.5h7.6l.8 .8-.8 .9h-7.6zM20.3 170v.9M20.3 176.1h.5M20.6 176.1v.8M20.8 170l.1 .9h.3l.1-.2v-.7"/>
<path d="M21 164.8l.2-.9 .3 .9M21 164.5h.4M21.1 176.1l.1 .8h.4v-.8M21.8 170.4h.4l.1-.2-.2-.2h-.3v.9M21.8 164.3l.5-.1-.1-.3h-.4v.9h.5v-.3l-.2-.2M21.9 170.4l.4 .5M22 176.6l.5-.1v-.3l-.5-.1v.8M22.3 176.6l.2 .3M23.1 170v.9l-.5-.9v.9M23.2 163.9l-.5 .1v.2l.5 .3-.1 .3h-.4M23.3 164.8h.7M23.3 170.9h.7"/>
<path d="M23.4 176.1v.8l-.5-.8v.8M23.6 177h.7M24 164.8l.4-.9 .2 .9M24 170.9l.4-.9 .2 .9M24.1 164.5h.4M24.1 170.6h.4M24.4 176.9l.2-.8 .4 .8M24.5 176.7h.4M25.3 164.2h-.2l-.2 .1 .1 .5h.3M25.3 170.3h-.2l-.2 .1 .1 .5h.3M25.6 176.4l-.4 .1v.4h.4M25.6 164.2h.3"/>
<path d="M25.6 170.3h.3M25.6 163.9v.8l.3 .1M25.6 170v.8l.3 .1M25.8 176.4h.4M26 176.1v.8h.2M26.2 163.9v.9h.4M26.2 170v.9h.4M26.5 176.1v.8M26.5 176.5h.5M27 163.9l.4 .1-.1 .8h-.3l-.2-.3zM27 176.1v.8M27.1 170l.3 .2-.1 .7h-.3l-.2-.3v-.3z"/>
<path d="M27.4 176.1v.8M95.8 165.2v.8h.8l-.8 1-.9-1h.9M95.8 165.2h.1M95.8 161.7v3.5M17.4 194h10.4l.8 .8-.8 .9h-10.4zM18 187.9h9.8l.8 .8-.8 .9h-9.8zM18 181.8h9.8l.8 .8-.8 .9h-9.8zM18.3 194.4v.9M18.7 183l.3-.8 .3 .8M18.8 182.9h.4M18.9 188.3v.9M18.9 188.7h.4"/>
<path d="M19.1 194.5l-.1-.1-.3 .2v.5l.3 .2 .2-.1v-.3h-.2M19.3 188.3v.9M19.6 182.2v.8h.4M19.6 189.3h.6M20.1 194.4v.9l-.5-.9v.9M20.1 182.2h.6M20.4 188.7h.4l.1-.2-.2-.2h-.3v.9l.5-.1v-.3l-.2-.1M20.4 182.2v.8M20.5 194.4v.9M20.8 194.4h.4M21 194.4v.9M21 182.6h.2"/>
<path d="M21.2 188.7h.4M21.3 182.2h-.3v.8h.3M21.6 194.4v.9M21.7 188.3h-.5v.9h.5M21.8 182.7h.3l.2-.3-.2-.2h-.3v.8M21.9 189.2l.4-.9 .2 .9M21.9 182.7l.4 .3M22 189h.4M22.2 194.4l.3 .2v.6l-.2 .1a.49 .49 0 0 1-.4-.4 .49 .49 0 0 1 .3-.5zM22.9 189.2v-.9l.2 .7 .3-.7v.9M23.1 182.2v.8l-.5-.8v.8M23.3 183.1h.7"/>
<path d="M23.4 194.4v.9l-.5-.9v.9M23.6 195.4h.7M23.6 189.3h.7M24 183l.4-.8 .2 .8M24.1 182.9h.4M24.4 195.3l.2-.9 .4 .9M24.4 189.2l.2-.9 .4 .9M24.5 195.1h.4M24.5 189h.4M25.3 182.5h-.3l-.1 .2 .1 .3h.3M25.6 194.7l-.4 .1v.4h.4M25.6 188.6l-.4 .1v.4h.4"/>
<path d="M25.6 182.5h.3M25.6 182.2v.8h.3M25.8 194.7h.4M25.8 188.6h.4M26 194.4v.8l.2 .1M26 188.3v.8l.2 .1M26.2 182.2v.8h.4M26.5 188.3v.9M26.5 194.4v.9M26.5 194.8h.5M26.5 188.7h.5M27 188.3v.9"/>
<path d="M27 194.4v.9M27.1 182.2l.3 .2v.6h-.5a.52 .52 0 0 1 .2-.8zM27.4 188.3v.9M27.4 194.4v.9M103.6 182.6v.9h.9l-.9 .9-.8-.9h.8M103.6 182.6h.1M133.3 186.1v.9h.8l-.8 .9-.9-.9h.9M133.3 186.1h.1M133.3 192.2v.9h.8l-.8 .9-.9-.9h.9M133.3 192.2h.1M158.5 181.8v.8h.9l-.9 .9-.9-.9h.9M158.5 181.8h.1"/>
</g>
<g fill="none" stroke="#aaa" stroke-width=".21">
<path d="M210.8 15.2h.1M249.2 17h.1M249.2 33.5h.1M70.5 44h5.1v1.8h-5.1zM71.3 44.9h.2v.9h-.2zM71.4 45.8v2.5M73 44.9h.1v.9h-.1zM73.1 45.8v2.5M74.8 44.9h.1v.9h-.1zM74.8 45.8v2.5M203 54.5h.1M141.1 119h1.7"/>
<path d="M142.8 117.3h31.4v59.2h-31.4zM157.6 115.5v1.8M159.4 115.5v1.8M174.2 119h1.7M141.1 136.4h1.7M141.1 132.9h1.7M141.1 134.7h1.7M141.1 124.2h1.7M141.1 126h1.7M141.1 131.2h1.7M174.2 136.4h1.7M174.2 120.7h1.7"/>
<path d="M174.2 132.9h1.7M174.2 134.7h1.7M174.2 124.2h1.7M174.2 126h1.7M174.2 131.2h1.7M174.2 138.2h1.7M174.2 139.9h1.7M183 132.9h1.7M187.4 131.7l-2 1.1M188.2 132.9h1.7M143.6 146.8h.2M144 146.4h-.4v.9h.4"/>
<path d="M144.8 146.5h-.4v.2l.4 .3v.2h-.4M145.2 146.9h.3l.2-.3-.2-.2h-.3v.9M146 146.4h.6l-.4 .3 .4 .2v.2l-.2 .2-.4-.1M146.8 146.5h.5v.3l-.5 .5h.5M147.7 147h.7M149.3 146.5h-.5v.2l.5 .4-.2 .2-.3-.1M149.5 146.4h.6l-.3 .3 .3 .2v.2l-.2 .2-.4-.1M150.4 147h.7M151.5 146.4a.47 .47 0 0 1 .6 .4 .47 .47 0 0 1-.6 .5zM152.4 147l.4-.1-.1-.2h-.3v.5h.3M153.1 146.7l.1 .6 .3-.6M153.8 146.4v.9"/>
<path d="M153.9 146.8l.4 .5M154.3 146.4l-.5 .5M154.7 146.4v.1M154.7 146.7v.6M155 146.7h.3M155.1 146.4v.8l.2 .1M156.1 146.5a.42 .42 0 0 0-.6 .3 .42 .42 0 0 0 .6 .4M174.2 153.8h1.7M174.2 141.6h1.7M174.2 143.4h1.7M174.2 145.1h1.7M174.2 146.9h1.7"/>
<path d="M174.2 148.7h1.7M174.2 150.4h1.7M174.2 152.1h1.7M174.2 155.6h1.7M174.2 157.3h1.7M174.2 159.1h1.7M196.8 153.8h.1M196.8 157.3h.1M210 147.7h2.6M210 149.5h2.6M212.6 146.8h1.6v3.5h-1.6zM212.6 147.7h.8v.1h-.8z"/>
<path d="M212.6 149.4h.8v.2h-.8zM254.4 144.3h.1M268.4 144.3h.1M158.5 176.5v1.8M174.2 171.3h1.7M174.2 160.9h1.7M174.2 162.6h1.7M174.2 164.3h1.7M174.2 166h1.7M174.2 167.8h1.7M174.2 169.6h1.7M174.2 173.1h1.7"/>
<path d="M174.2 174.7h1.7M107.9 182.6h1.8M109.7 181.8h3.5M111.4 180.5v1.3M113.2 182.6h1.8M133.3 184.4v1.7M133.3 190.5v1.7M161.1 189.6h2.6M161.1 191.3h2.6M163.7 188.7h1.8v3.4h-1.8zM163.7 189.5h1v.1h-1zM163.7 191.3h1v.1h-1z"/>
<circle cx="210.8" cy="15.2" r=".38"/>
<circle cx="249.2" cy="17" r=".38"/>
<circle cx="249.2" cy="33.5" r=".38"/>
<circle cx="203" cy="54.5" r=".38"/>
<circle cx="185" cy="132.9" r=".38"/>
<circle cx="187.8" cy="132.9" r=".38"/>
<circle cx="196.8" cy="157.3" r=".38"/>
<circle cx="196.8" cy="153.8" r=".38"/>
<circle cx="254.4" cy="144.3" r=".38"/>
<circle cx="268.4" cy="144.3" r=".38"/>
<circle cx="110.1" cy="182.6" r=".38"/>
<circle cx="112.9" cy="182.6" r=".38"/>
</g>
<g fill="none" stroke="#b2b2b2" stroke-width=".21">
<path d="M71.1 47.1h-.8l.2 .2M71.1 46.8v.5M72.9 46.8v.5l-.7-.5-.2 .2v.3M73.7 47.3v-.5l.4 .4v-.3l.1-.1 .4 .1-.1 .4M141.6 117.9h.6l-.3 .3 .3 .2v.2l-.1 .2-.5-.1M157.4 116.6v.5l-.4-.5-.5 .1 .1 .3M157.4 116h-.9l.3 .2M157.4 115.7v.5M159.2 116.2v.5l-.5-.5h-.4l.1 .5M174.7 117.9l-.3 .5h.6M174.7 119.5l-.3 .7h.6M174.8 118.2v.6"/>
<path d="M174.8 119.9v.6M175.3 117.9h.5l-.4 .3 .4 .2v.2l-.2 .2-.3-.1M175.3 119.7l.4-.1 .1 .2-.5 .7h.5M141.2 135.3h.6l-.3 .3 .3 .2v.3l-.2 .1-.4-.1M141.2 130.1h.6l-.3 .3 .3 .2v.2l-.2 .2-.4-.1M141.2 131.8h.6l-.3 .4 .3 .1-.1 .4-.5-.1M141.2 133.6h.6l-.3 .3h.2v.5h-.5M141.9 123.5l-.2-.1v-.2l.4-.1 .1 .3-.5 .2 .1 .3h.4l-.1-.4M142.1 131.8h.6l-.4 .9M142.2 125.2l-.1 .2h-.3l-.1-.4 .4-.1 .1 .1-.1 .7h-.3M142.3 133.9l-.2-.2 .5-.1v.3l-.5 .1v.4h.5l.1-.3-.2-.2M142.6 130.1l-.5 .2v.6l.4 .1 .2-.4-.2-.2-.4 .2"/>
<path d="M142.7 135.7l-.2 .2-.4-.1v-.4l.4-.1 .2 .2-.2 .6-.3 .1M174.4 123.2h.5v.3l-.5 .4h.5M174.4 125h.5v.2l-.5 .5h.5M174.4 130.1h.5l-.2 .3 .2 .1v.4h-.5M174.4 135.5l.3-.2v.9M174.4 136.2h.5M174.7 131.8l-.3 .6h.6M174.7 133.5l-.3 .7h.6M174.8 132.2v.5M174.8 133.9v.5M175.1 137l-.3 .7h.6M175.3 132.1l.2-.3v.9"/>
<path d="M175.3 130.3l.2-.2v.9M175.3 135.3h.5l-.4 .3 .4 .2v.3l-.2 .1-.3-.1M175.3 132.7h.5M175.3 131h.5M175.3 137.3v.6M175.3 138.8h-.4l-.1 .4h.5v.4h-.5M175.4 133.6a.43 .43 0 0 1 .4 .4 .43 .43 0 0 1-.4 .4l-.1-.3zM175.7 123.1l-.3 .1-.1 .7h.5l-.2-.5-.3 .2M175.7 124.9h-.4v.4l.4-.1v.5l-.4-.1M183.6 132.1l.2-.3v.9M183.6 132.7h.5M188.8 131.9l.3-.1 .2 .3-.6 .6h.6"/>
<path d="M174.4 153l.3-.3v1M174.4 144.3l.3-.3v.9M174.4 146l.3-.2v.8M174.4 147.7l.3-.2v.9M174.4 149.5l.3-.2v.8M174.4 151.3l.3-.3v.9M174.4 154.6h.5v.2l-.5 .6h.5M174.4 156.5l.3-.3v.9M174.4 158.2l.3-.2v.8M174.4 159.8h.5v.3l-.5 .5h.5M174.4 153.7h.5M174.4 144.9h.5"/>
<path d="M174.4 146.6h.5M174.4 148.4h.5M174.4 150.1h.5M174.4 151.9h.5M174.4 157.1h.5M174.4 158.8h.5M174.8 142.3h.6l-.4 .9M175.3 140.5l-.5 .4v.3l.1 .2 .4-.1v-.4h-.4l-.1 .1M175.3 144.1l.3-.1 .2 .2-.5 .7h.5M175.3 149.3h.5l-.4 .8M175.3 158.2l.2-.2v.8M175.3 159.8h.5l-.4 .8"/>
<path d="M175.3 158.8h.5M175.4 151.4l-.1-.2v-.2h.4v.4l-.4 .1 .1 .4 .4-.2-.2-.3M175.4 154.5a.43 .43 0 0 1 .4 .4 .43 .43 0 0 1-.4 .5l-.1-.4zM175.4 156.2a.48 .48 0 0 1 .4 .5 .48 .48 0 0 1-.4 .4 .69 .69 0 0 1 0-.9zM175.7 145.8h-.4v.4l.4-.1v.5h-.4M175.7 147.5l-.3 .1-.1 .6 .1 .2 .4-.2-.2-.4-.3 .2M175.8 153.2l-.4 .1-.1-.4 .1-.2 .4 .2-.2 .7-.3 .1M211 146.9l.2-.3v.9M211 148.5h.5v.3l-.5 .5h.5M211 147.5h.5M157.7 177.6h.6M157.7 176.8h.6"/>
<path d="M158 177.5v.5l-.6-.1M158 176.7v.5l-.6-.2M174.4 170.4l.3-.2v.8M174.4 161.5h.5l-.2 .3 .2 .1v.4h-.5M174.4 163.2h.5l-.2 .4 .2 .1v.3h-.5M174.4 164.9h.5l-.2 .4h.2v.5h-.5M174.4 166.7h.5l-.2 .3 .2 .1v.4h-.5M174.4 168.5h.5l-.2 .2 .2 .1v.4h-.5M174.4 172h.5v.3l-.5 .5h.5M174.4 173.7h.5v.4l-.5 .5h.5M174.4 171h.5M175.3 161.5h.3l.2 .1-.5 .7h.5"/>
<path d="M175.3 163.2h.5l-.4 .4h.3l.1 .1-.1 .4-.4-.1M175.4 170.2l-.1 .6h.5M175.4 164.9l-.1 .6h.5M175.4 168.5h.2a.48 .48 0 0 1 .2 .5 .48 .48 0 0 1-.4 .3 .6 .6 0 0 1 0-.8zM175.4 172.3l-.1-.2v-.1h.4v.3l-.4 .2v.3h.4l.1-.2-.2-.3M175.7 166.7h-.4v.4l.4-.1v.5h-.4M175.7 165.3v.6M175.7 170.5v.5M175.8 174.1l-.4 .1-.1-.4 .1-.2 .4 .2-.2 .7-.3 .1M162.2 188.7l.3-.2v.9M162.2 190.3l.4-.1 .1 .3-.6 .6h.6M162.2 189.4h.5"/>
</g>
<g fill="none" stroke="#a2a2a2" stroke-width=".21">
<path d="M144.4 118.6l-.4-.1-.2 .4 .2 .5 .4-.1M144.8 118.5v.9M144.8 119h.5M145.3 118.5v.9M145.7 118.5v.9M146.1 119h.5v-.5h-.5v.9M146.8 119.5h.7M147.7 119h.4v-.5h-.4v.9M148.5 118.5l.1 .9 .4-.1v-.8M157.2 119v.5h.4v-.5h.4v.5M157.2 118.2l.9 .3-.9 .3M158.9 119l.9 .3-.9 .3"/>
<path d="M158.9 118.8v-.5l.4 .3 .1-.3 .4 .1-.1 .4M164.2 118.5h-.3l-.2 .4 .2 .5 .4-.1v-.3h-.1M164.7 119h.4v-.5h-.4v.9M165.5 118.5v.9M165.9 118.6h.5l.1 .5-.1 .3-.5-.1zM167 118.4l-.1 .7h.5M167.2 118.8v.6M167.6 118.5h.5l-.2 .4 .2 .1v.3h-.5M169.2 118.4l-.8 1.2M169.4 118.5l.1 .9 .4-.1v-.8M170.4 118.5a.42 .42 0 0 1 .5 .5 .42 .42 0 0 1-.5 .4zM171.1 118.5h.4"/>
<path d="M171.3 118.5v.9M171.8 118.5l.6 .9M172.4 118.5l-.6 .9M172.7 118.5l.4 .1 .1 .4-.1 .4h-.4zM144.4 136h-.4l-.2 .3 .2 .5 .4-.1v-.2h-.1M144.4 123.8h-.4a.44 .44 0 0 0-.1 .5 .44 .44 0 0 0 .5 .2v-.2h-.1M144.4 125.6a.41 .41 0 0 0-.6 .4 .41 .41 0 0 0 .6 .3v-.3h-.1M144.4 130.7h-.4l-.2 .4 .2 .5 .4-.1v-.3h-.1M144.4 132.5h-.4a.44 .44 0 0 0-.1 .6 .44 .44 0 0 0 .5 .2v-.4h-.1M144.4 134.3a.43 .43 0 0 0-.5 .2 .43 .43 0 0 0 .1 .5h.4v-.3h-.1M144.8 136.4h.4l.1-.3-.5-.1v.8M144.8 124.2h.4l.1-.3-.5-.1v.8"/>
<path d="M144.8 126l.5-.1v-.3l-.5-.1v.9M144.8 131.1h.4l.1-.3-.5-.1v.9M144.8 132.9l.5-.1v-.2l-.5-.1v.8M144.8 134.7l.5-.1v-.3l-.5-.1v.8M145.6 123.8v.8M145.6 125.5v.9M145.6 130.7v.9M145.6 132.5v.8M145.6 134.2v.8M145.6 136v.8M146 136.1h.6v.5l-.1 .2-.5-.1zM146 123.9h.6a.47 .47 0 0 1-.4 .7l-.2-.1z"/>
<path d="M146 130.8h.6v.5l-.1 .3-.5-.1zM146 132.6h.6a.47 .47 0 0 1-.4 .7l-.2-.1zM146.2 125.5a.47 .47 0 0 1 .5 .4 .47 .47 0 0 1-.5 .5l-.2-.2v-.6zM146.2 134.2a.47 .47 0 0 1 .4 .3 .47 .47 0 0 1-.1 .5h-.5v-.6zM146.9 130.7h.6l-.4 .4h.3l.1 .1-.1 .4-.5-.1M147 124l.2-.2v.8M147 125.7l.2-.2v.9M147 124.6h.5M147 126.4h.5M147.1 135.9l-.1 .7h.5M147.1 132.4l-.1 .6h.5M147.1 134.2l-.1 .6h.5"/>
<path d="M147.4 132.8v.5M147.4 134.5v.5M147.4 136.2v.6M147.7 136.1h.5v.2l-.5 .5h.5M147.7 134.4l.3-.2v.8M147.7 135h.5M147.8 132.6l.4-.1v.2v.5l-.1 .1a.48 .48 0 0 1-.3-.7zM148.2 125.5l-.3 .1-.2 .6 .2 .2 .3-.1v-.4l-.3-.1-.2 .2M148.2 123.8h-.4l-.1 .4 .5-.1v.4h-.5M148.2 131.1v.1h-.4v-.5l.4 .1v.6l-.4 .2M149.3 135.9l-.8 1.2M149.3 123.7l-.8 1.1"/>
<path d="M149.3 125.5l-.8 1.1M149.3 130.7l-.8 1.1M149.3 132.4l-.8 1.1M149.3 134.2l-.8 1.1M149.4 124.6l.3-.8 .3 .8M149.4 126.4l.3-.9 .3 .9M149.5 124.4h.4M149.5 126.1h.4M149.6 136.8v-.8l.3 .6 .2-.6v.8M149.6 131.6v-.9l.3 .6 .2-.6v.9M149.6 133.3v-.8l.3 .6 .2-.6v.8M149.6 135v-.8l.3 .7 .2-.7v.8"/>
<path d="M150.3 123.8h.3l.2 .1v.5l-.3 .2h-.2zM150.3 125.5h.2l.3 .2v.4l-.3 .3h-.2zM150.4 136h.6M150.4 130.7h.6M150.4 132.5h.6M150.4 134.2h.6M150.7 130.7v.9M150.7 132.5v.8M150.7 134.2v.8M150.7 136v.8M151.2 136.8v-.8l.3 .6 .3-.6v.8M151.2 132.5h.3l.2 .2v.4l-.2 .2h-.3z"/>
<path d="M151.2 134.2h.3l.2 .2v.5l-.2 .1h-.3zM151.7 123.9l-.4-.1a.44 .44 0 0 0-.1 .5 .44 .44 0 0 0 .5 .2M151.7 125.6a.42 .42 0 0 0-.6 .3 .42 .42 0 0 0 .6 .4M151.7 130.8l-.3-.1-.2 .2v.5l.2 .2 .3-.1M152 123.9h.5v.2l-.5 .5h.5M152 125.6h.5v.3l-.5 .5h.5M152.1 132.6h.5a.47 .47 0 0 1-.4 .7l-.1-.1zM152.1 130.7v.9M152.1 134.2v.8M152.2 131.1l.4 .5M152.6 130.7l-.5 .5M152.6 136h-.4l-.1 .1 .2 .3 .3 .1v.2l-.5 .1"/>
<path d="M152.6 124.7h.7M152.6 126.5h.7M154 123.9l-.3-.1a.43 .43 0 0 0-.2 .5 .43 .43 0 0 0 .5 .2M154 125.6a.4 .4 0 0 0-.5 .3 .4 .4 0 0 0 .5 .4M154.4 123.8v.8M154.4 125.5v.9M154.4 124.2h.5M154.4 125.9h.5M154.9 123.8v.8M154.9 125.5v.9M155.5 123.7l-.2 .6h.6M155.7 124v.6"/>
<path d="M155.8 125.5h-.4l-.1 .4h.5v.4h-.5M156.8 123.7l-.8 1.1M156.8 125.5l-.8 1.1M157 123.8h.6l-.4 .3h.3l.1 .4-.2 .1-.4-.1M157 125.5h.6l-.4 .3 .4 .2v.2l-.2 .2-.4-.1M157.9 123.9l.3-.1 .1 .3-.5 .5h.5M157.9 125.6l.3-.1 .1 .4-.5 .5h.5M158.7 123.8v.8M158.7 125.5v.9M158.8 124.1l.5 .5M158.8 125.9l.5 .5M158.9 120.4v-.5l.4 .2v-.2h.4v.5"/>
<path d="M159.3 123.8l-.6 .5M159.3 125.5l-.6 .5M159.4 124.7h.7M159.4 126.5h.7M160.3 124.2h.4v-.4h-.4v.8M160.8 125.5v.9l-.5-.9v.9M162.6 132.5h-.3l-.2 .2v.4l.3 .2h.2v-.4h-.1M162.6 134.3l-.2-.1-.3 .2v.5l.2 .1h.3v-.3h-.1M162.6 136h-.3l-.2 .1v.5l.2 .2h.3v-.3h-.1M162.6 137.7h-.2l-.3 .2v.4l.3 .3 .2-.1v-.3h-.1M162.6 139.4h-.3l-.2 .2v.5l.2 .2h.3v-.4h-.1M163 132.9l.5-.1v-.2l-.5-.1v.8"/>
<path d="M163 134.7l.5-.1v-.3l-.5-.1v.8M163 136.4h.4l.1-.3-.5-.1v.8M163 138.2l.5-.1v-.4h-.5v.9M163 139.9h.4l.1-.4-.5-.1v.9M163.1 123.8h-.3l-.2 .1v.5l.3 .2 .2-.1v-.2h-.1M163.1 125.6l-.2-.1-.3 .2v.4l.3 .3 .2-.1v-.3h-.1M163.6 124.2h.4v-.4h-.4v.8M163.6 126h.3l.2-.4-.2-.1h-.3v.9M163.9 132.5v.8M163.9 134.2v.8M163.9 136v.8M163.9 137.7v.9"/>
<path d="M163.9 139.4v.9M164.1 120.3l-.3-.1-.2 .3v.4l.2 .3 .3-.1v-.4h-.2M164.3 132.6l.1-.1a.46 .46 0 0 1 .5 .3 .46 .46 0 0 1-.2 .5 .47 .47 0 0 1-.4-.2 .47 .47 0 0 1 0-.5zM164.3 136.1l.5-.1v.8l-.5-.1zM164.3 139.5l.5-.1v.9l-.5-.1zM164.4 123.8v.8M164.4 125.5v.9M164.5 120.7l.4-.1v-.3l-.4-.1v1M164.5 134.2l.3 .1v.5v.2h-.5a.52 .52 0 0 1 .2-.8zM164.5 137.7a.48 .48 0 0 1 .4 .4 .48 .48 0 0 1-.4 .5 .54 .54 0 0 1 0-.9zM164.8 123.9h.5v.6l-.1 .1a.47 .47 0 0 1-.4-.3 .47 .47 0 0 1 0-.4zM165 125.5l.3 .1v.6l-.1 .2a.49 .49 0 0 1-.5-.4 .49 .49 0 0 1 .3-.5z"/>
<path d="M165.1 136h.6l-.4 .3h.3l.1 .2-.1 .3-.5-.1M165.2 132.8l.2-.3v.8M165.2 134.3l.3-.1 .2 .2-.6 .6h.6M165.2 133.3h.5M165.3 137.7l-.1 .6h.5M165.3 120.2v1M165.6 139.4h-.4v.5l.4-.1 .1 .1-.1 .4-.4-.1M165.6 138v.6M165.7 123.9h.5v.2l-.5 .5h.5M165.7 125.7l.2-.2v.9M165.7 126.4h.5M165.9 120.2l.4 .2v.6l-.2 .2a.49 .49 0 0 1-.4-.4 .49 .49 0 0 1 .2-.6z"/>
<path d="M166.6 123.9l.1-.1a.45 .45 0 0 1 .4 .4 .45 .45 0 0 1-.3 .4l-.3-.3zM166.7 132.4l-.8 1.1M166.7 134.2l-.8 1.1M166.7 135.9l-.8 1.2M166.7 137.7l-.8 1.1M166.7 139.4l-.8 1.1M166.9 120.2l-.3 .6h.5M166.9 133.3l.2-.8 .3 .8M166.9 135l.2-.8 .3 .8M166.9 136.8l.2-.8 .3 .8M166.9 138.6l.2-.9 .3 .9M166.9 133.1h.4"/>
<path d="M166.9 134.9h.4M166.9 136.6h.4M166.9 138.3h.4M167 125.9l-.3 .2-.2-.5 .2-.1 .3 .1-.1 .7-.3 .1M167 120.6v.6M167.6 120.2l-.1 .6h.5M167.7 132.5h.4a.48 .48 0 0 1 .1 .5 .48 .48 0 0 1-.5 .3zM167.7 134.2a.49 .49 0 0 1 .5 .3 .49 .49 0 0 1-.1 .5h-.4zM167.7 136l.4 .1 .1 .4-.1 .3h-.4zM167.7 137.7a.47 .47 0 0 1 .5 .4 .47 .47 0 0 1-.5 .5zM167.7 139.4l.4 .1 .1 .4-.1 .4h-.4zM167.9 120.6v.6"/>
<path d="M168.1 123.7l-.8 1.1M168.1 125.5l-.8 1.1M168.3 123.8v.7l.2 .1 .3-.1v-.7M168.3 125.5v.7l.2 .2 .3-.1v-.8M169 120.2l-.8 1.1M169.1 132.6l-.4-.1-.1 .2v.4l.2 .2h.3M169.1 134.3l-.3-.1-.2 .2v.5l.1 .1h.4M169.1 136.1l-.4-.1-.1 .1v.5l.1 .2 .4-.1M169.1 137.7h-.3l-.2 .2v.4l.2 .3 .3-.1M169.1 139.5l-.4-.1-.1 .2v.5l.1 .2 .4-.1M169.2 120.2v.9l.2 .1 .4-.2v-.8M169.4 132.8l.3-.3v.8"/>
<path d="M169.4 134.4l.3-.2v.8M169.4 136.2l.3-.2v.8M169.4 137.9l.3-.2v.9M169.4 139.7l.3-.3v.9M169.4 133.3h.5M169.4 135h.5M169.4 136.8h.5M169.4 138.6h.5M169.7 123.8h-.5v.1l.1 .3 .4 .1v.2h-.5M169.7 125.6l-.4-.1-.1 .1v.3l.5 .2v.2h-.5M170.1 124.2l.4-.1-.1-.3h-.3v.8h.3l.2-.1-.1-.3h-.2M170.1 125.9h.3l.1-.3-.4-.1v.9h.3l.2-.3-.3-.2"/>
<path d="M170.1 130.7h-.3l-.2 .4 .2 .5 .4-.1v-.3h-.2M170.1 133.4h.7M170.1 135.1h.7M170.1 136.9h.7M170.1 138.7h.7M170.2 120.3l.2-.1 .2 .2v.6l-.2 .2a.53 .53 0 0 1-.2-.9zM170.5 131.1h.4l.1-.3-.5-.1v.9M170.8 124.7h.6M170.8 126.5h.6M171 120.7l.4-.1v-.3l-.4-.1v1M171.2 120.7l.2 .5M171.4 130.7v.9"/>
<path d="M171.4 132.6l-.3-.1-.2 .2v.4l.3 .2h.2M171.4 134.3l-.2-.1-.3 .2v.5l.2 .1h.3M171.4 136.1l-.3-.1-.2 .1v.5l.2 .2 .3-.1M171.4 137.7h-.2l-.3 .2v.4l.3 .3 .2-.1M171.4 139.5l-.3-.1-.2 .2v.5l.2 .2 .3-.1M171.6 123.8h.4a.47 .47 0 0 1 .1 .5 .47 .47 0 0 1-.5 .3zM171.6 125.5a.47 .47 0 0 1 .5 .4 .47 .47 0 0 1-.5 .5zM171.8 120.2l.6 1M171.8 132.5v.8M171.8 134.2v.8M171.8 136v.8M171.8 137.7v.9"/>
<path d="M171.8 139.4v.9M171.8 132.8h.5M171.8 134.6h.5M171.8 136.4h.5M171.8 138.1h.5M171.8 139.9h.5M171.9 130.7h.3l.2 .3-.2 .6-.4-.1zM172.3 132.5v.8M172.3 134.2v.8M172.3 136v.8M172.3 137.7v.9M172.3 139.4v.9"/>
<path d="M172.4 120.2l-.6 1M172.5 124.3h.6M172.5 126.1h.6M172.6 137.7h.6l-.3 .3 .3 .2v.2l-.1 .2-.5-.1M172.7 120.2a.47 .47 0 0 1 .5 .5 .47 .47 0 0 1-.5 .5zM172.7 134.4l.3-.2v.8M172.7 136.1l.4-.1 .1 .2-.6 .6h.6M172.7 135h.5M172.8 132.5a.43 .43 0 0 1 .4 .4 .43 .43 0 0 1-.3 .4l-.2-.1zM172.8 130.7a.42 .42 0 0 1 .4 .4 .42 .42 0 0 1-.4 .5zM172.8 123.9v.7M172.9 139.4l-.2 .6h.5"/>
<path d="M173.1 139.7v.6M161.8 153.4h-.3l-.2 .2v.5l.2 .2 .3-.1v-.3h-.2M161.8 148.2h-.3l-.2 .1v.5l.2 .2h.3v-.3h-.2M161.8 149.9h-.3l-.2 .2v.4l.2 .3 .3-.1v-.3h-.2M161.8 151.7l-.3-.1-.2 .3v.4l.2 .2h.3v-.4h-.2M161.8 155.2l-.3-.1-.2 .3v.4l.2 .2h.3v-.4h-.2M161.8 156.9h-.3l-.2 .2v.5l.2 .1h.3v-.3h-.2M161.8 158.7l-.3-.1-.2 .2v.5l.2 .2 .3-.1v-.3h-.2M162.2 153.8h.4v-.4h-.4v.9M162.2 148.6h.4v-.4h-.4v.8M162.2 150.4l.4-.1v-.4h-.4v.9M162.2 152.1h.4v-.5h-.4v.9"/>
<path d="M162.2 155.6l.4-.1v-.4h-.4v.9M162.2 157.3h.4v-.4h-.4v.8M162.2 159.1l.4-.1v-.4h-.4v.9M162.6 141.2h-.3l-.2 .2v.4l.3 .3 .2-.1v-.4h-.1M162.6 143l-.2-.1-.3 .3v.4l.2 .2h.3v-.4h-.1M162.6 144.7h-.3l-.2 .2v.5l.2 .1h.3v-.3h-.1M162.6 146.5l-.2-.1-.3 .2v.5l.3 .2 .2-.1v-.3h-.1M163 141.6h.5v-.3l-.5-.1v.9M163 143.4l.5-.1v-.3l-.5-.1v.9M163 145.1h.4l.1-.3-.5-.1v.8M163 146.9l.5-.1v-.3l-.5-.1v.9M163.1 148.2v.8"/>
<path d="M163.1 149.9v.9M163.1 151.6v.9M163.1 153.4v.9M163.1 155.1v.9M163.1 156.9v.8M163.1 158.6v.9M163.5 153.5h.5v.7h-.5zM163.5 148.2h.5l-.1 .8-.4-.1zM163.6 149.9l.4 .1v.6l-.2 .2a.47 .47 0 0 1-.4-.3 .47 .47 0 0 1 .2-.6zM163.6 156.9l.4 .1-.1 .7h-.3l-.2-.2zM163.7 151.6l.3 .2v.6h-.5a.52 .52 0 0 1 .2-.8zM163.7 155.1l.3 .2v.6l-.2 .1a.49 .49 0 0 1-.4-.4 .49 .49 0 0 1 .3-.5z"/>
<path d="M163.7 158.6l.3 .1v.6l-.2 .2a.49 .49 0 0 1-.4-.4 .49 .49 0 0 1 .3-.5zM163.9 141.2v.9M163.9 142.9v.9M163.9 144.7v.8M163.9 146.4v.9M164.3 153.7l.3-.3v.9M164.3 141.3l.1-.1a.46 .46 0 0 1 .5 .3 .46 .46 0 0 1-.2 .6 .47 .47 0 0 1-.4-.3 .47 .47 0 0 1 0-.5zM164.3 144.8l.5-.1v.8h-.5zM164.3 148.4l.3-.2v.8M164.3 150.1l.3-.2v.9M164.3 151.9l.3-.3v.9M164.3 155.4l.3-.3v.9"/>
<path d="M164.3 157.1l.3-.2v.8M164.3 158.8l.3-.2v.9M164.3 154.3h.5M164.3 149h.5M164.3 150.8h.5M164.3 152.5h.5M164.3 156h.5M164.3 157.7h.5M164.3 159.5h.5M164.5 142.9l.3 .1v.5v.3l-.5-.1a.52 .52 0 0 1 .2-.8zM164.5 146.4a.48 .48 0 0 1 .4 .4 .48 .48 0 0 1-.4 .5 .54 .54 0 0 1 0-.9zM165.1 153.4h.6l-.4 .3h.3l.1 .4-.2 .2-.4-.1"/>
<path d="M165.1 142.9h.6l-.4 .9M165.1 156.9h.6l-.4 .8M165.2 150.1l.2-.2v.9M165.2 151.7l.3-.1 .2 .3-.6 .6h.6M165.2 150.8h.5M165.3 148.2a.42 .42 0 0 1 .4 .4 .42 .42 0 0 1-.4 .4zM165.3 145l-.1-.2 .4-.1v.3l-.4 .1v.4h.4l.1-.3-.2-.2M165.3 155.1l-.1 .6h.5M165.3 159l-.1-.1v-.2l.3-.1 .2 .2-.5 .3v.3l.1 .1 .4-.2-.2-.3M165.6 141.2l-.4 .2v.6l.3 .1 .2-.5-.2-.1-.3 .1M165.6 155.4v.6M165.7 146.8l-.2 .2-.3-.1v-.4l.3-.1 .2 .2-.2 .6-.2 .1"/>
<path d="M166.7 153.3l-.8 1.1M166.7 141.1l-.8 1.1M166.7 142.9l-.8 1.1M166.7 144.6l-.8 1.1M166.7 146.4l-.8 1.1M166.7 148.1l-.8 1.2M166.7 149.9l-.8 1.1M166.7 151.6l-.8 1.1M166.7 155.1l-.8 1.1M166.7 156.8l-.8 1.2M166.7 158.6l-.8 1.1M166.9 154.3l.2-.9 .3 .9"/>
<path d="M166.9 140.3l.2-.9 .3 .9M166.9 142.1l.2-.9 .3 .9M166.9 143.8l.2-.9 .3 .9M166.9 145.5l.2-.8 .3 .8M166.9 147.3l.2-.9 .3 .9M166.9 149l.2-.8 .3 .8M166.9 150.8l.2-.9 .3 .9M166.9 152.5l.2-.9 .3 .9M166.9 156l.2-.9 .3 .9M166.9 157.7l.2-.8 .3 .8M166.9 159.5l.2-.9 .3 .9M166.9 154h.4"/>
<path d="M166.9 140h.4M166.9 141.8h.4M166.9 143.5h.4M166.9 145.3h.4M166.9 147.1h.4M166.9 148.8h.4M166.9 150.5h.4M166.9 152.2h.4M166.9 155.8h.4M166.9 157.5h.4M166.9 159.3h.4M167.7 153.4h.4a.47 .47 0 0 1 .1 .6 .47 .47 0 0 1-.5 .3z"/>
<path d="M167.7 141.2h.4a.48 .48 0 0 1 .1 .6 .48 .48 0 0 1-.5 .3zM167.7 142.9a.49 .49 0 0 1 .5 .3 .49 .49 0 0 1-.1 .6h-.4zM167.7 144.7l.4 .1 .1 .4-.1 .3h-.4zM167.7 146.4a.47 .47 0 0 1 .5 .4 .47 .47 0 0 1-.5 .5zM167.7 148.2h.4l.1 .5-.1 .3h-.4zM167.7 149.9h.4a.48 .48 0 0 1 .1 .6 .48 .48 0 0 1-.5 .3zM167.7 151.6a.49 .49 0 0 1 .5 .3 .49 .49 0 0 1-.1 .6h-.4zM167.7 155.1a.47 .47 0 0 1 .5 .5 .47 .47 0 0 1-.5 .4zM167.7 156.9l.4 .1 .1 .4-.1 .3h-.4zM167.7 158.6a.47 .47 0 0 1 .5 .4 .47 .47 0 0 1-.5 .5zM169.1 153.5l-.4-.1-.1 .2v.5l.2 .2 .3-.1M169.1 141.3l-.4-.1-.1 .2v.4l.2 .3 .3-.1"/>
<path d="M169.1 143l-.3-.1-.2 .3v.4l.1 .2 .4-.1M169.1 144.8l-.4-.1-.1 .2v.5l.1 .1h.4M169.1 146.5l-.3-.1-.2 .2v.5l.2 .2 .3-.1M169.1 148.2h-.4l-.1 .1v.5l.1 .2 .4-.1M169.1 149.9h-.4l-.1 .2v.4l.2 .3 .3-.1M169.1 151.7l-.3-.1-.2 .3v.4l.1 .2 .4-.1M169.1 155.2l-.3-.1-.2 .3v.4l.2 .2h.3M169.1 157l-.4-.1-.1 .2v.5l.1 .1 .4-.1M169.1 158.7l-.3-.1-.2 .2v.5l.2 .2 .3-.1M169.4 153.5l.4-.1 .1 .3-.6 .6h.6M169.4 141.4l.3-.2v.9M169.4 143.2l.3-.3v.9"/>
<path d="M169.4 144.9l.3-.2v.8M169.4 146.6l.3-.2v.9M169.4 148.4l.3-.2v.8M169.4 149.9h.4l.1 .2-.6 .7h.6M169.4 151.7l.4-.1 .1 .3-.6 .6h.6M169.4 155.2l.4-.1 .1 .3-.6 .6h.6M169.4 157l.4-.1 .1 .2-.6 .6h.6M169.4 158.7l.4-.1 .1 .2-.6 .7h.6M169.4 140.3h.5M169.4 142.1h.5M169.4 143.8h.5M169.4 145.5h.5"/>
<path d="M169.4 147.3h.5M169.4 149h.5M170.1 154.3h.7M170.1 140.4h.7M170.1 142.1h.7M170.1 143.8h.7M170.1 145.6h.7M170.1 147.4h.7M170.1 149.1h.7M170.1 150.9h.7M170.1 152.6h.7M170.1 156.1h.7"/>
<path d="M170.1 157.8h.7M170.1 159.6h.7M171.4 153.5l-.3-.1-.2 .2v.5l.3 .2 .2-.1M171.4 141.3l-.3-.1-.2 .2v.4l.3 .3 .2-.1M171.4 143l-.2-.1-.3 .3v.4l.2 .2 .3-.1M171.4 144.8l-.3-.1-.2 .2v.5l.2 .1h.3M171.4 146.5l-.2-.1-.3 .2v.5l.3 .2 .2-.1M171.4 148.2h-.3l-.2 .1v.5l.2 .2 .3-.1M171.4 149.9h-.3l-.2 .2v.4l.3 .3 .2-.1M171.4 151.7l-.2-.1-.3 .3v.4l.2 .2 .3-.1M171.4 155.2l-.2-.1-.3 .3v.4l.3 .2h.2M171.4 157l-.3-.1-.2 .2v.5l.2 .1 .3-.1"/>
<path d="M171.4 158.7l-.2-.1-.3 .2v.5l.3 .2 .2-.1M171.8 141.2v.9M171.8 142.9v.9M171.8 144.7v.8M171.8 146.4v.9M171.8 148.2v.8M171.8 149.9v.9M171.8 151.6v.9M171.8 153.4v.9M171.8 155.1v.9M171.8 156.9v.8M171.8 158.6v.9"/>
<path d="M171.8 153.8h.5M171.8 141.6h.5M171.8 143.3h.5M171.8 145.1h.5M171.8 146.8h.5M171.8 148.6h.5M171.8 150.3h.5M171.8 152.1h.5M171.8 155.5h.5M171.8 157.3h.5M171.8 159h.5M172.3 141.2v.9"/>
<path d="M172.3 142.9v.9M172.3 144.7v.8M172.3 146.4v.9M172.3 148.2v.8M172.3 149.9v.9M172.3 151.6v.9M172.3 153.4v.9M172.3 155.1v.9M172.3 156.9v.8M172.3 158.6v.9M172.6 144.7h.6l-.3 .8M172.6 155.1h.6l-.3 .3 .3 .2v.3l-.1 .1h-.5"/>
<path d="M172.6 158.6h.6l-.3 .9M172.7 153.5l.4-.1 .1 .3-.6 .6h.6M172.7 150l.4-.1a.53 .53 0 0 1-.2 .9l-.2-.2zM172.7 151.9l.3-.3v.9M172.7 152.5h.5M172.9 146.8l-.2-.1v-.2l.4-.1 .1 .2-.5 .3v.3l.2 .1 .3-.2-.1-.3M173.1 141.2h-.4v.4l.4-.1 .1 .4-.1 .2-.4-.1M173.1 142.9l-.4 .3v.5l.4 .1 .1-.4-.1-.1-.4 .1M173.1 156.9l-.4 .2v.5l.4 .1v-.5h-.3l-.1 .2M173.2 148.5l-.1 .2h-.3l-.1-.5h.4l.1 .1-.1 .7h-.3M158.1 175v.3l.3 .2 .5-.2-.1-.4h-.2v.2M158.1 174.1h.8l-.8 .5h.8"/>
<path d="M158.1 173.3l.3-.2 .4 .1 .1 .4h-.8zM169.2 170.9l-.4 .1v.4l.3 .3 .2-.1v-.3h-.1M169.2 160.4h-.1l-.3 .2v.4l.2 .2 .3-.1v-.2h-.1M169.2 162.1l-.4 .2v.4l.3 .3 .2-.1v-.3h-.1M169.2 163.9l-.1-.1-.3 .3v.4l.3 .3 .2-.1v-.4h-.1M169.2 165.6l-.4 .2v.5l.2 .1h.3v-.3h-.1M169.2 167.4l-.1-.1-.3 .2v.5l.3 .2 .2-.1v-.3h-.1M169.2 169.2l-.1-.1-.3 .1v.6l.2 .1 .3-.1v-.2h-.1M169.2 172.6l-.1-.1-.3 .3v.4l.2 .2h.3v-.3h-.1M169.2 174.3l-.4 .2v.5l.2 .2 .3-.1v-.3h-.1M169.7 171.3h.4l.1-.4h-.5v.8M169.7 160.8h.4l.1-.4h-.5v.8"/>
<path d="M169.7 162.6h.4l.1-.4-.5-.1v.9M169.7 164.3l.5-.1v-.3l-.5-.1v1M169.7 166h.4l.1-.3-.5-.1v.8M169.7 167.8l.5-.1v-.3l-.5-.1v.9M169.7 169.5h.4l.1-.3-.5-.1v.8M169.7 173.1l.5-.1v-.4l-.5-.1v.9M169.7 174.7h.4l.1-.3-.5-.1v.9M170.6 160.4v.8M170.6 162.1v.9M170.6 163.8v1M170.6 165.6v.8M170.6 167.3v.9"/>
<path d="M170.6 169.1v.8M170.6 170.9v.8M170.6 172.5v.9M170.6 174.3v.9M171 170.9h.4a.48 .48 0 0 1-.2 .8 .52 .52 0 0 1-.2-.8zM171 162.2l.4-.1 .1 .3v.3l-.2 .3-.4-.3zM171 165.7l.4-.1 .1 .3-.1 .5h-.3l-.2-.2zM171 169.2l.3-.1 .2 .2-.1 .6h-.3l-.2-.2zM171 174.4l.4-.1 .1 .3-.1 .6h-.3l-.2-.3zM171.2 160.4l.3 .2-.1 .6h-.3l-.2-.3v-.3zM171.2 163.8h.1a.5 .5 0 0 1 .2 .5 .5 .5 0 0 1-.3 .5 .54 .54 0 0 1 0-1zM171.2 167.3h.1a.5 .5 0 0 1 .2 .5 .5 .5 0 0 1-.3 .4 .54 .54 0 0 1 0-.9z"/>
<path d="M171.2 172.5h.1a.52 .52 0 0 1 .1 .9l-.4-.1a.52 .52 0 0 1 .2-.8zM171.8 162.1h.6l-.4 .4h.3l.1 .3-.2 .2-.4-.1M171.8 163.8h.6l-.4 .4 .4 .1v.3l-.2 .2-.4-.1M171.8 165.6h.6l-.4 .3h.3l.1 .2-.1 .3h-.5M171.8 167.3h.6l-.4 .3 .4 .2v.3l-.2 .1-.4-.1M171.9 160.4h.3l.2 .2-.6 .6h.6M172 170.8l-.1 .6h.5M172 169.1l-.1 .6h.5M172 172.5l-.1 .6h.5M172 174.2l-.1 .7h.5M172.3 169.3v.6M172.3 171.1v.6"/>
<path d="M172.3 172.9v.5M172.3 174.6v.6M172.6 165.6h.6l-.3 .8M172.6 172.5h.6l-.3 .9M172.7 160.6l.3-.2v.8M172.7 161.2h.5M172.9 167.7l-.2-.1v-.2l.4-.1 .1 .2-.5 .3v.3l.2 .1 .3-.1-.1-.4M172.9 174.7l-.2-.3 .4-.1v.4h-.4l.1 .5h.3l.1-.2-.1-.3M173.1 170.9l-.4 .1v.6l.4 .1 .1-.4h-.5M173.1 162.1h-.4v.5l.4-.1 .1 .3-.1 .2-.4-.1M173.1 163.8l-.3 .1-.1 .8 .4 .1 .1-.2-.1-.4-.4 .1M173.1 169.1h-.4v.4l.4-.1 .1 .2-.1 .3-.4-.1"/>
</g>
<g fill="none" stroke="#e00" stroke-width=".34">
<path d="M210.4 14.9l.7 .6M211.1 14.9l-.7 .6M248.8 16.6l.7 .7M249.5 16.6l-.7 .7M248.8 33.1l.7 .8M249.5 33.1l-.7 .8M69.5 42.2l7.1 5.2M76.6 42.2l-7.1 5.2M202.6 54.1l.7 .7M203.3 54.1l-.7 .7M141.6 116l33.8 61.7M175.4 116l-33.8 61.7"/>
<path d="M183.4 131.4l6 2.2M189.4 131.4l-6 2.2M196.5 153.5l.7 .6M196.5 156.9l.7 .8M197.2 153.5l-.7 .6M197.2 156.9l-.7 .8M210.8 146.3l5.2 4.6M216 146.3l-5.2 4.6M254 143.9l.7 .7M254.7 143.9l-.7 .7M268 143.9l.7 .7M268.7 143.9l-.7 .7"/>
<path d="M108.5 180.1l5.8 3.2M114.3 180.1l-5.8 3.2M131.4 181.2l3.6 4.5M131.4 187.3l3.6 4.5M135 181.2l-3.6 4.5M135 187.3l-3.6 4.5M161.9 188.1l5.4 4.6M167.3 188.1l-5.4 4.6"/>
</g>
<g fill="none" stroke="#0c0c0c" stroke-width=".21">
<path d="M219.4 26.2h-.5v.5l.5-.1v.5l-.5-.1M219.7 26.5l.2 .6 .2-.6M220.2 27.2h.7M221.1 26.8l.4-.1-.1-.2-.3 .2v.3l.4 .1M221.8 26.6l.3-.1 .1 .2v.4M221.8 26.5v.6M222.7 26.6h.3v.5h-.3l-.1-.2 .2-.2h.2M223.4 26.2v.9h.4l.1-.4-.2-.2-.3 .1M224.2 26.2v.8l.2 .1M224.6 26.8l.4-.1v-.2l-.4 .2v.3l.4 .1M92.3 61.1l.1 .9M92.7 61.7l.3-.1v-.2l-.3 .1v.5h.3"/>
<path d="M93.8 61.1v.9h-.3l-.1-.5 .2-.1 .2 .1M94.7 61.5h-.5v.4l.5 .1M94.8 62.1h.6M96 61.5l-.2-.1-.2 .1 .1 .5h.3M96.4 61.5h.4v.5M96.4 61.1v.9M97.2 61.5h.3v.5h-.3l-.1-.2 .2-.2h.2M98 61.5l.2-.1 .2 .1v.5M98 61.4v.6M98.5 62.1h.7M99.5 61.1a.42 .42 0 0 1 .4 .4 .42 .42 0 0 1-.4 .5zM275.2 78.6h-.5v.3l.5 .2v.2h-.5"/>
<path d="M275.6 78.6h.3a.47 .47 0 0 1 .2 .5 .47 .47 0 0 1-.5 .3zM276.3 79.4l.3-.8 .3 .8M276.4 79.2h.5M87.9 86.4v.7l.1 .2M88.3 86.9h.4l-.1-.2-.3 .1v.3l.2 .2 .1-.1M89.5 86.7l-.4 .1v.4h.4M89.5 86.4v.9M90.2 86.7h-.3l-.1 .2 .2 .4 .2-.1M90.4 87.4h.7M91.7 86.7l-.4 .1v.4h.4M92 86.8h.5v.5M92 86.4v.9"/>
<path d="M92.9 86.7l.3 .1v.5M93.2 86.9l-.4 .1 .1 .3 .3-.1M93.6 86.8l.4-.1v.6M93.6 86.7v.6M94.2 87.4h.7M95.1 86.4h.2l.2 .1v.6l-.2 .2a.53 .53 0 0 1-.2-.9zM275.2 80.3h-.5v.3l.5 .3v.2h-.5M276.1 80.3a.42 .42 0 0 0-.6 .4 .42 .42 0 0 0 .6 .4M276.4 80.3v.9h.5M52.5 108.5h.2l.2 .1-.1 .4h-.3M52.5 102.4h.2l.2 .1-.2 .4h-.2M52.5 102.1v.8"/>
<path d="M52.5 108.5v.8M53.2 108.5h.4v.5h-.4v-.1l.1-.2h.3M53.2 114.7l.2-.2 .4 .2-.1 .4h-.4zM53.2 102.4v.5M53.5 102.4l-.3 .1M53.8 102.4h.2l.2 .1v.4M54 108.5v.5M54.1 114.3v.1M54.1 114.5v.6M54.2 102.6l-.4 .1v.2h.4M54.3 108.5l-.3 .1M54.5 114.3v.8h.2"/>
<path d="M54.6 102.1v.8M54.6 108.2v.8M54.7 108.7l.2 .3M54.7 102.6l.2 .3M54.9 108.5l-.3 .3M54.9 102.4l-.3 .3M55.2 102.7l.4-.1-.1-.2-.3 .1v.4h.4M55.3 108.2v.1M55.3 108.5v.5M55.7 108.5h.3v.5M55.7 108.5v.5M56.3 102.4h-.2l-.1 .1 .4 .4h-.4"/>
<path d="M56.9 108.5v.7l-.4 .1M56.9 108.5h-.4v.5h.4M191.9 104.7v.1M191.9 105v.6M192.7 105.5l-.3 .1-.1-.2 .1-.4h.3v.7l-.3 .1M193.1 105.1h.4v.5M193.1 105v.6M193.7 105.7h.7M194.6 105.1h.3M195 104.7h-.4v.9h.4M195.9 104.7v.9l-.5-.9v.9M52.5 132.6v.8h.3l.1-.4-.2-.2-.2 .1"/>
<path d="M53.2 132.9h.4v.5h-.4v-.1l.4-.2M53.3 120.7h.4v.5h-.4l-.1-.1 .5-.2M53.3 139h.4v.5h-.4l-.1-.1 .5-.2M53.7 126.8l-.3-.1-.2 .2 .1 .4h.4M54 127.1l.4-.1v-.3l-.4 .2v.3l.4 .1M54.1 120.4v.1M54.1 138.7v.7l.2 .1M54.1 120.6v.6M54.4 132.9h-.4v.4l.4 .1M54.5 120.6v.6M54.6 139h.3v.5h-.3l-.1-.1 .4-.2M54.8 120.6l-.3 .2"/>
<path d="M54.8 132.6v.8M54.9 126.5v.8M54.9 133.1l.2 .3M55 120.4v.8h.4l.1-.5h-.5M55.1 132.8l-.3 .4M55.4 139v.5M55.5 132.6v.7l.1 .1M55.6 139l-.2 .1M55.9 120.7h.3v.5h-.3l-.1-.1 .4-.2M55.9 139.1h.4v.4M55.9 139v.5M56 132.6v.1"/>
<path d="M56 132.8v.6M56.3 139.1l.3-.1v.5M56.7 132.8v.9h-.3M56.7 132.9l-.2-.1-.2 .2 .1 .4h.3M57.1 120.6v.8l-.2 .2-.3-.1M57.1 120.7h-.5v.5h.5M57.1 132.9h.4v.5M57.1 132.6v.8M57.8 132.8h.4M57.9 132.6v.7l.3 .1M114 132.7h-.6v.2l.6 .3-.1 .2h-.5M114 130.9h-.6v.2l.6 .4-.2 .2h-.4"/>
<path d="M114.3 130.8h.2l.3 .3v.4l-.3 .2h-.2zM114.8 132.7l-.3-.1-.2 .2v.5l.2 .1 .3-.1M115.1 131.7l.2-.9 .3 .9M115.1 132.6v.8h.5M115.1 131.5h.5M178 131.7v.1M178 132v.6M178.8 132v.8h-.4M178.8 132.1h-.4v.4l.4 .1M179.1 132.1l.3-.1 .2 .2v.4M179.1 132v.6M179.7 132.7h.7"/>
<path d="M180.7 132.2h.2M181.1 131.7h-.4v.9h.4M181.9 131.7v.9l-.5-.9v.9M181.9 138.8h-.5v.2l.5 .3v.2h-.5M182.3 138.7h.2l.3 .2v.5l-.2 .1h-.3zM183 139.5l.3-.8 .3 .8M183.1 139.3h.5M53.7 157.3h-.4l-.1 .2 .2 .4 .3-.1M53.7 151.2h-.4l-.1 .2 .2 .4 .3-.1M53.7 157v.9M54.1 157.4h.4v.4h-.4zM54.1 151.2h.3l.1 .2-.1 .4-.4-.2z"/>
<path d="M54.9 157.3l.4 .1v.4l-.2 .1-.2-.2zM54.9 151.2h.3l.1 .2-.2 .4-.2-.1zM55.6 150.9v.7l.2 .2M55.7 157.3v.6M56 157.3l-.3 .2M56.1 151.2h.4v.6M56.5 151.4l-.5 .1 .2 .3 .3-.1M56.9 151.3l.3-.1v.6M56.9 151.2v.6M57.6 151.2h.3M57.7 150.9v.7l.2 .2M181.4 150.9v.7l.2 .2"/>
<path d="M181.4 152.6v.8l.2 .1M181.4 154.3v.8l.2 .2M181.4 147.4v.8h.2M181.4 149.2v.7l.2 .1M181.9 151.5l.4-.1v-.2l-.4 .1v.3l.1 .2 .3-.1M181.9 153.2h.4l-.1-.3-.3 .2v.3l.4 .1M181.9 154.9l.4-.1v-.1l-.4 .1v.3l.1 .2 .3-.1M181.9 143.9h-.5v.5l.5-.1v.1v.4l-.5-.1M181.9 148l.4-.1-.1-.2-.3 .1v.4h.4M181.9 149.8l.4-.1-.1-.3-.3 .2v.3l.1 .1 .3-.1M181.9 140.5h-.5v.3l.5 .2v.3h-.5M182.2 144.2l.3 .6 .1-.6"/>
<path d="M182.8 140.5h-.3l-.2 .1v.5l.2 .2 .3-.1M182.8 144.9h.6M183 151.2h-.3l-.1 .2 .2 .4 .2-.1M183 152.6v.9h-.3l-.1-.4 .2-.2 .2 .1M183 154.7h-.3l-.1 .1 .2 .5 .2-.1M183 147.4v.8h-.3l-.1-.4 .2-.1h.2M183 149.5l-.2-.1-.2 .2 .2 .4 .2-.1M183 149.2v.8M183 150.9v.9M183 154.3v1M183.2 140.5v.8h.4M183.6 144.5l.4-.1-.1-.2-.3 .2v.3l.4 .1"/>
<path d="M183.8 151.2h-.3l-.1 .2 .2 .4 .2-.1M183.8 153l-.2-.1-.2 .2 .1 .4h.3M183.8 154.7h-.3l-.1 .1 .2 .5 .2-.1M183.8 147.7h-.2l-.2 .1 .1 .4h.3M183.8 149.5l-.2-.1-.2 .2 .2 .4 .2-.1M184 151.9h.7M184 153.6h.7M184 155.4h.7M184 148.3h.7M184 150.1h.7M184.4 144.3h.3v.5M184.4 144.2v.6"/>
<path d="M185.2 144.3h.3v.5h-.3v-.3l.3-.1M185.2 151.2h-.3l-.1 .2 .2 .4 .2-.1M185.2 153l-.2-.1-.2 .2 .1 .4h.3M185.2 154.7h-.3l-.1 .1 .2 .5 .2-.1M185.2 147.7h-.2l-.2 .1 .1 .4h.3M185.2 149.5l-.2-.1-.2 .2 .2 .4 .2-.1M185.6 151.3h.4v.5M185.6 153l.2-.1 .2 .2v.4M185.6 154.8h.4v.5M185.6 147.7h.2l.2 .1v.4M185.6 149.5l.2-.1 .2 .2v.4M185.6 147.4v.8"/>
<path d="M185.6 149.2v.8M185.6 150.9v.9M185.6 152.6v.9M185.6 154.3v1M185.9 143.9v.9h.4v-.5h-.4M186.4 151.2h.4v.6M186.4 153h.4v.5h-.4l-.1-.2 .5-.1M186.4 154.7h.4v.6M186.4 147.7h.4v.5h-.4l-.1-.1 .5-.2M186.4 149.5h.4v.5M186.8 151.4l-.5 .1 .2 .3 .3-.1M186.8 154.8l-.5 .2 .2 .3 .3-.1"/>
<path d="M186.8 143.9l.1 .9M186.8 149.7l-.5 .1 .2 .2 .3-.1M187.2 151.3l.3-.1v.6M187.2 153h.3v.5M187.2 154.8l.3-.1v.6M187.2 144.5l.3-.1-.1-.2-.2 .1v.5h.3M187.2 147.7h.3v.5M187.2 149.5h.3v.5M187.2 147.7v.5M187.2 149.4v.6M187.2 151.2v.6M187.2 152.9v.6"/>
<path d="M187.2 154.7v.6M187.8 151.9h.7M187.8 153.6h.7M187.8 155.4h.7M187.8 148.3h.7M187.8 150.1h.7M188.5 152.6h.6l-.3 .4h.3v.5l-.6-.1M188.6 147.5l.4-.1 .1 .3-.6 .5h.6M188.6 149.4l.3-.2v.8M188.6 150h.5M188.8 150.9a.48 .48 0 0 1 .4 .4 .48 .48 0 0 1-.4 .5l-.2-.2v-.6zM188.8 154.3l-.2 .6h.5"/>
<path d="M189.1 154.7v.6M257 145.7h-.6v.3l.6 .3-.2 .3-.4-.1M257.3 145.6a.47 .47 0 0 1 .5 .5 .47 .47 0 0 1-.5 .5zM258.1 146.6l.2-1 .4 1M258.1 146.3h.5M263.1 145.7l-.4-.1-.2 .2 .1 .2 .5 .2v.3h-.6M263.9 145.7l-.2-.1a.43 .43 0 0 0-.3 .5 .43 .43 0 0 0 .5 .4M264.3 145.6v1h.4M53.3 163.4h.4v.6M53.7 163.6l-.5 .1 .2 .3 .3-.1M54.1 163.4l.4 .1v.4h-.4M54.1 163.1v.9"/>
<path d="M55.2 163.4l-.3 .1 .3 .4h-.3M52.3 187.8h.4M52.5 181.8h.3v.5M52.5 193.6v.1M52.5 193.9v.6M52.7 187.5h-.2v.9M52.8 181.9l-.4 .1 .2 .3 .2-.1M52.9 187.8v.4l.2 .2 .2-.1M53.2 181.4l.1 .9M53.2 193.9v.7l-.3 .1M53.2 194l-.2-.1-.2 .2 .1 .4h.3M53.3 187.8v.6"/>
<path d="M53.6 181.7h.3M53.7 181.4v.7l.2 .2M53.7 194h.3v.5M53.7 193.9v.6M53.8 187.5v.9M54.2 187.5v.7l.2 .2M54.2 181.9h.4l-.2-.2-.2 .1v.4h.3M54.4 193.6v.1M54.4 188.5h.7M54.4 193.9v.6M54.8 193.9h.2M54.9 193.6v.8l.1 .1"/>
<path d="M54.9 181.7v.6M55.2 181.7l-.3 .2M55.3 187.9h.4v.4h-.4M55.3 187.5v.9M55.4 193.6v.1M55.4 193.9v.6M55.5 181.8l.2-.1 .2 .2v.4M55.5 181.7v.6M55.7 194.1l.2-.2 .3 .2-.1 .4h-.3zM56 188.1l.5-.1-.1-.2-.4 .2v.2l.2 .2 .3-.1M56.3 181.8h.3v.5M56.6 194l.2-.1 .2 .2v.4"/>
<path d="M56.6 193.9v.6M56.6 181.9l-.4 .1 .2 .3 .2-.1M56.9 187.9h.3v.5M57 181.7h.2M57.1 181.4v.7l.1 .2M57.2 188l-.4 .2 .2 .2 .2-.1M57.5 181.9l.3-.2 .2 .4-.3 .2zM57.7 187.9h.3v.5M57.7 187.8v.6M58 188l.2-.2 .2 .2v.4M58.3 181.7v.6M58.6 181.7l-.3 .2"/>
<path d="M59.1 187.9l-.2-.1-.1 .2 .4 .2-.2 .2-.2-.1M155.8 190.2h-.4l-.1 .1 .5 .4v.2h-.5M155.9 188.4l-.5 .1v.2l.5 .3-.1 .2h-.4M156.2 190.2h.3a.48 .48 0 0 1 .2 .5 .48 .48 0 0 1-.5 .3zM156.7 188.5l-.3-.1-.2 .1v.6l.2 .1 .3-.1M156.9 191l.3-.8 .3 .8M157 190.7h.4M157.1 188.4v.8h.4"/>
</g>
<g fill="none" stroke="#aaa" stroke-width=".85">
<circle cx="133.2" cy="183.4" r=".89"/>
<circle cx="133.2" cy="189.5" r=".89"/>
</g>
<g fill="none" stroke="#bd0000" stroke-width=".21">
<path d="M246.5 78.6l-.2 .6h.6M246.7 79v.5M256.2 75.7h.6M256.5 75.6v.5l-.6-.2M256.8 76.4v.6l-.5-.6-.4 .1 .1 .5M266.9 78.7l.3-.1 .1 .4-.5 .5h.5M267.6 78.6h.5l-.2 .4 .2 .1v.3h-.5M245.9 89.4l.2-.3v.9M245.9 91.1l.2-.3v1M245.9 94.6l.2-.3v.9M245.9 96.3l.2-.2v.8M245.9 98.1l.2-.2v.8"/>
<path d="M245.9 99.8l.2-.2v.8M245.9 90h.5M245.9 91.8h.5M245.9 95.2h.5M245.9 96.9h.5M245.9 98.7h.5M246.3 83.9h.6l-.4 .8M246.5 86l-.2-.2 .2-.2 .3 .1v.2l-.4 .1-.1 .2 .2 .3 .3-.1v-.3l-.2-.1M246.7 82.1l-.2 .1-.2 .7 .2 .2 .3-.1v-.5h-.3l-.2 .1M246.7 91.1l.3-.3v1M246.7 94.3h.5l-.2 .4h.2v.5h-.5M246.7 91.8h.5"/>
<path d="M246.8 80.4h-.4l-.1 .5 .4-.1 .1 .4h-.5M246.8 87.7l-.1 .2h-.3l-.1-.4 .2-.1 .3 .1v.5l-.4 .2M246.8 89.2l.3-.1 .1 .2v.5l-.1 .2a.48 .48 0 0 1-.3-.8zM247 96.1l-.3 .6h.6M247.1 99.6h-.2l-.2 .7h.5v-.3l-.3-.1-.2 .2M247.1 96.3v.6M247.2 97.9h-.4l-.1 .3h.5v.4h-.5M266.9 80.5l.3-.1 .1 .4-.5 .5h.5M267.2 82.4l.3-.3v1M267.2 83.1h.5M267.6 80.5h.5v.3l-.5 .5h.5M245.9 101.6l.2-.3v.9"/>
<path d="M245.9 103.3l.2-.3v1M245.9 105.1l.2-.3v.9M245.9 106.7h.5v.2l-.5 .5h.5M245.9 100.4h.5M245.9 102.2h.5M245.9 104h.5M245.9 105.7h.5M246.7 101.3h.6l-.4 .9M246.8 106.7l.3-.1 .1 .2v.5l-.1 .1a.48 .48 0 0 1-.3-.7zM246.9 103.5l-.2-.3 .2-.2 .3 .1v.3l-.4 .1-.1 .1 .2 .4 .3-.1v-.4h-.1M247.2 105.2l-.1 .1h-.3v-.5l.4 .1v.6l-.4 .2M256.8 111.6h-.9l.3 .2"/>
<path d="M256.8 110.5v.5l-.5-.5-.4 .1 .1 .4M256.8 111.3v.5M266.9 106.7l.3-.1 .1 .3-.5 .5h.5M267.2 103h.5l-.2 .4 .2 .1v.4h-.5M267.2 104.9h.5v.3l-.5 .5h.5M267.6 106.8l.3-.2v.8M267.6 107.4h.5M85 136.2h.6l-.3 .9M85.3 130.9l-.2 .7h.5M85.3 138.3h-.2v-.3l.3-.1 .2 .3-.5 .2v.4l.5-.1-.2-.4M85.5 132.7h-.4v.4l.3-.1 .2 .4-.2 .2-.3-.1M85.5 134.4l-.4 .2v.6l.4 .1v-.5h-.3l-.1 .2"/>
<path d="M85.5 131.2v.6M95 128h.5M95.2 127.8v.6l-.5-.2M95.5 128.8v.5l-.5-.5h-.3v.5M105.6 131.1l.4-.1 .1 .2-.6 .6h.6M105.6 132.8l.3-.1 .2 .2-.6 .7h.6M106 134.7l.3-.3v.9M106 135.3h.5M106.3 131h.6l-.3 .3h.2v.5l-.5-.1M106.4 132.8l.4-.1 .1 .2-.6 .7h.6M84.7 141.6l.2-.2v.9M84.7 143.4l.2-.2v.8"/>
<path d="M84.7 146.9l.2-.3v.9M84.7 148.7l.2-.3v.9M84.7 150.4l.2-.3v.9M84.7 152.1l.2-.2v.8M84.7 153.8l.2-.1v.8M84.7 155.6l.2-.2v.8M84.7 157.4l.2-.3v.9M84.7 158.9l.3-.1 .2 .3-.6 .7h.6M84.7 142.3h.5M84.7 144h.5M84.7 147.5h.5M84.7 149.3h.5"/>
<path d="M84.7 151h.5M84.7 152.7h.5M84.7 154.5h.5M84.7 156.2h.5M84.7 158h.5M85.4 146.6h.5l-.2 .4 .2 .1v.3h-.5M85.4 153.7h.6l-.3 .8M85.5 143.4l.2-.2v.8M85.5 144h.4M85.6 140l-.1 .2h-.3l-.1-.4 .4-.1 .1 .2-.2 .6h-.2M85.7 141.4l.2 .2v.5l-.1 .2-.3-.2v-.5zM85.7 148.3l-.2 .7h.5"/>
<path d="M85.7 155.8l-.2-.1v-.3h.3h.1v.3l-.4 .2 .1 .3 .3-.1v-.2l-.1-.1M85.7 158.8l.2 .2v.6l-.1 .2-.3-.2v-.6zM85.8 151.9l-.3 .2v.5h.4l-.1-.4h-.2l-.1 .2M85.8 148.7v.6M85.9 150.1h-.4v.4h.4v.5h-.4M85.9 157.5l-.1 .1h-.2l-.1-.4h.4v.6l-.3 .2M105.6 158.9l.3-.1 .2 .3-.6 .7h.6M105.9 155.4h.6l-.3 .3 .3 .2-.1 .3-.5-.1M106 157.2l.4-.1 .1 .3-.6 .6h.6M106.4 159.1l.3-.3v1M106.4 159.8h.5M95.5 163.8h-.8l.2 .3"/>
<path d="M95.5 162.8v.5l-.5-.5h-.3v.5M95.5 163.7v.4"/>
</g>
<path d="M261.7 68.9h2.8M261.7 67.9h2.8M100.5 121.2h2.7M100.5 120.2h2.7" fill="none" stroke="#980000" stroke-width=".34"/>
<g fill="none" stroke="#000" stroke-width=".21">
<path d="M53.3 144.8v.8h.4v-.5h-.4M54.1 145.1v.4h.4M54.5 145.1v.5M54.8 145.1h.3M54.9 144.8v.8h.2M55.3 145.1h.3M55.4 144.8v.7l.2 .1M56 145.1l.3 .1-.1 .4-.3-.1zM56.7 145.2l.4-.1v.5M56.7 145.1v.5M52.5 175.3l.1 .9M52.5 169.5v.6"/>
<path d="M52.7 169.5l-.2 .2M52.9 175.8h.3v-.2h-.3v.5h.3M53 169.2h.1M53 169.5v.6M53.5 175.6h.3M53.8 170l-.3 .1-.2-.2 .1-.4h.4v.8h-.4M53.8 175.3h-.1v.9M54 175.6h.4M54.2 169.6h.4v.5M54.2 175.3v.8l.2 .1M54.2 169.2v.9M54.4 176.3h.7"/>
<path d="M54.9 169.5h.3M55 169.2v.8l.2 .1M55.2 175.6h.3M55.3 175.3v.7l.2 .2M55.3 170.2h.7M55.8 175.6v.4l.2 .2 .2-.1M56 169.5h.4M56.1 169.2v.7l.3 .2M56.2 175.6v.6M56.6 169.5v.4l.2 .2 .3-.1M56.6 175.6v.6M56.9 175.6l-.3 .2"/>
<path d="M57.1 169.5v.6M57.1 175.7l.4-.1v.6M57.1 175.6v.6M57.4 169.5v.6M57.7 169.5l-.3 .2M58 169.6l.3-.1v.6M58 169.5v.6M117 181.8h.3v.4h-.3M117 181.4v.9M117.8 181.7v.5h.3M118.1 181.7v.6M118.4 181.7h.4"/>
<path d="M118.5 181.4v.7l.3 .2M119 181.7h.2M119 181.4v.7l.2 .2M119.5 181.9l.3-.2 .2 .4-.4 .2zM120.3 181.8l.3-.1 .1 .2v.4M120.3 181.7v.6"/>
</g>
<path d="M72 87.6l.7-.2v.5z" fill="#980000"/>
<g fill="none" stroke="#980000" stroke-width=".21">
<path d="M72 87.6l.7-.2v.5zM73.1 85.8v.6"/>
<circle cx="72.4" cy="87.6" r="1.99"/>
</g>
<path d="M73 86.2l.3 .2-.1 .1-.3-.1z" fill="#980000"/>
<path d="M73 86.2l.3 .2-.1 .1-.3-.1z" fill="none" stroke="#980000" stroke-width=".21"/>
<path d="M73 88.6l.3 .2-.1 .2-.3-.2z" fill="#980000"/>
<g fill="none" stroke="#980000" stroke-width=".21">
<path d="M67.9 87.6h1.7M71.9 87.6h1.2v3.5M73 88.6l.3 .2-.1 .2-.3-.2zM73.1 84.2v1.6M73.4 87.4h.5M73.7 87.4l.2 .4h-.5zM96.6 87.6h.9M97.5 86.9h3.5v1.4h-3.5zM101 87.6h.8M104.5 87.6h1.9M106.4 86.2v2.7M106.7 86v.7"/>
<path d="M106.7 87.2v.7M106.7 88.4v.7M106.8 86.4h1.7v2.4h-1.7M107.9 92.9v.8h1l-1 .9-.8-.9h.8M107.9 92.9h.1"/>
</g>
<path d="M68.5 86.8l.2-.3v.9M68.5 87.4h.5M72 85.3v-.6l.3 .3 .1-.3h.4v.6M72.9 90v.5l-.5-.5h-.4v.5" fill="none" stroke="#bd0000" stroke-width=".21"/>
<path d="M106.9 87.6l.7-.2v.5z" fill="#980000"/>
<g fill="none" stroke="#980000" stroke-width=".21">
<path d="M106.9 87.6l.7-.2v.5zM107.9 85.8v.6"/>
<circle cx="107.3" cy="87.6" r="1.99"/>
</g>
<path d="M107.8 86.2l.4 .2-.2 .1-.3-.1z" fill="#980000"/>
<path d="M107.8 86.2l.4 .2-.2 .1-.3-.1z" fill="none" stroke="#980000" stroke-width=".21"/>
<path d="M107.8 88.6l.4 .2-.2 .2-.3-.2z" fill="#980000"/>
<g fill="none" stroke="#980000" stroke-width=".21">
<path d="M16.4 19.6v.9h1l-1 .8-.8-.8h.8M16.4 19.6h.1M21.4 17h7.4l.7 .9-.7 .8h-7.4zM22.3 17.9h.3l.1-.4-.4-.1v1h.3l.2-.4-.3-.1M23 18.4l.3-1 .2 1M23.1 18.1h.3M23.7 17.4h.5M24 17.4v1M24.4 17.4h.5M24.6 17.4v1M25.1 17.7l.3-.3v1M25.1 18.4h.5"/>
<path d="M26 17.5l.3-.1 .2 .3-.6 .7h.6M26.7 17.4l.3 1 .3-1M27.6 18h.7M27.9 17.7v.7M16.6 27.4h12.2l.7 1-.7 .8h-12.2zM17.4 28.4h.4M17.9 27.9h-.5v.9M18.2 27.9l.1 .9 .4-.1v-.8M18.4 20.5h10.4l.7 .8-.7 1h-10.4zM18.6 36.1h10.2l.7 1-.7 .8h-10.2zM18.9 25.7h9.9l.7 .9-.7 .8h-9.9zM18.9 32.7h9.9l.7 .8-.7 1h-9.9z"/>
<path d="M18.9 31h9.9l.7 .8-.7 .9h-9.9zM19.1 34.5h9.7l.7 .8-.7 .8h-9.7zM19.1 20.9v.9M19.1 28.4h.3M19.5 37.1h.4l.1-.4h-.5v.8M19.6 27.9h-.5v.9h.5M19.6 34l.3-.8 .2 .8M19.6 26.2l.3 .9 .2-.7 .1 .7 .2-.9M19.6 33.8h.5M19.7 31.4v.9M19.7 31.8h.5M19.7 37.1l.3 .4"/>
<path d="M19.9 27.9v.9h.4M20 24h8.8l.7 .8-.7 .9h-8.8zM20 34.9v.8h.4M20.1 21l-.3-.1-.2 .3v.4l.2 .2h.3v-.4h-.2M20.1 37.6h.7M20.2 31.4v.9M20.4 28.9h.7M20.4 32.3h.7M20.5 33.2v.8h.4M20.5 35.8h.6M20.7 27.1l.2-.9 .3 .9M20.7 26.8h.4"/>
<path d="M20.9 36.7h.5M21 20.9v.9l-.5-.9v.9M21 33.2h.5M21.2 34.9h.5M21.2 36.7v.8M21.2 24.5h-.4l-.1 .1 .5 .5-.1 .2-.4-.1M21.2 27.9v.9h.5M21.2 31.8h.4l.2-.1-.1-.3h-.5v.9h.5l.1-.4-.2-.1M21.2 33.2v.8M21.3 22.3h7.5l.7 .8-.7 .9h-7.5zM21.3 20.9v.9M21.3 26.2h.5"/>
<path d="M21.4 34.9v.8M21.6 24.9h.4l.1-.4h-.5v.8M21.6 26.2v.9M21.7 36.7l.1 .8 .4-.1v-.7M21.7 20.9h.5M21.8 27.9l.4 .9 .2-.9M21.8 33.5h.3M21.9 20.9v.9M22 34.9v.8l.5-.1v-.7M22.2 23.1h.4l.1-.3-.5-.1v.8M22.2 26.6h.2M22.2 31.8h.2"/>
<path d="M22.3 33.2h-.5v.8h.5M22.4 23.1l.3 .4M22.4 20.9v.9M22.5 24.9h.3M22.6 26.2h-.4v.9h.4M22.6 33.6l.5-.1v-.2l-.5-.1v.8M22.6 31.4h-.4v.9h.4M22.6 37.1h.4l.1-.4h-.5v.8M22.8 27.9v.9h.4M22.9 32.3l.2-.9 .3 .9M22.9 33.6l.2 .4M22.9 37.1l.2 .4"/>
<path d="M22.9 26.7h.4l.1-.4-.1-.1h-.4v.9M22.9 24.5h-.4v.8h.4M22.9 35.4l.5-.1v-.3l-.5-.1v.8M22.9 32h.4M23 20.9l.4 .2v.6l-.2 .1-.3-.1v-.6zM23.1 23.1h.3l.1-.3-.4-.1v.8M23.1 35.4l.3 .3M23.2 26.7l.2 .4M23.2 28.9h.7M23.3 24.9h.2M23.6 27.2h.7M23.7 24.5h-.4v.8h.4"/>
<path d="M23.7 32.3v-.9l.3 .6 .3-.6v.9M24 23.5v-.8l.2 .6 .3-.6v.8M24 33.2v.8l-.6-.8v.8M24 36.7v.8l-.6-.8v.8M24 24.5h.4l.1 .1v.5l-.2 .2h-.3zM24.1 28.4h.4v-.5h-.4v.9M24.2 34.1h.7M24.2 37.6h.7M24.3 20.9v.9l-.5-.9v.9M24.3 34.9v.8l-.5-.8v.8M24.3 28.4l.3 .4M24.4 26.2h.5"/>
<path d="M24.5 21.9h.6M24.5 35.8h.6M24.5 32.3h.6M24.6 26.2v.9M24.7 23.6h.7M24.7 25.4h.7M25 34l.2-.8 .3 .8M25 37.5l.2-.8 .3 .8M25 27.2h.6M25.1 33.8h.3M25.1 37.2h.3M25.2 21.8l.3-.9 .3 .9"/>
<path d="M25.2 35.7l.3-.8 .3 .8M25.2 32.3l.3-.9 .3 .9M25.3 28.3h-.3l.1 .2h.2v.3h-.3M25.3 21.6h.4M25.3 35.6h.4M25.3 32h.4M25.6 22.7v.8M25.6 24.5v.8M25.6 23.1h.5M25.6 24.9h.5M25.6 28.5l.5-.1-.2-.2-.3 .1v.5h.4M25.8 26.7h.4l.1-.4-.1-.1h-.4v.9"/>
<path d="M26.1 22.7v.8M26.1 24.5v.8M26.2 33.5l-.3-.1-.2 .2 .2 .4 .3-.1M26.2 37l-.3-.1-.2 .2 .1 .4h.4M26.4 23.5l.3-.8 .3 .8M26.4 25.3l.3-.8 .3 .8M26.4 28.3l.3-.1 .1 .2v.4M26.4 28.2v.6M26.4 33.4h.3M26.4 36.9h.3M26.5 21.2l-.4 .1v.5h.4M26.5 35.2l-.4 .1v.4h.4"/>
<path d="M26.5 31.7h-.4v.5l.4 .1M26.5 23.3h.4M26.5 25.1h.4M26.6 26.2l.2 .9 .2-.7 .2 .7 .1-.9M26.6 33.2v.7l.1 .1M26.6 36.7v.8h.1M26.7 21.2h.4M26.7 35.2h.4M26.7 31.7h.4M26.8 20.9v.8l.3 .1M26.8 34.9v.7l.3 .1M26.8 31.4v.8l.3 .1"/>
<path d="M27.1 33.2v.8h.3M27.1 36.7v.8h.3M27.3 22.7v.8h.4M27.3 24.5v.8h.4M27.3 20.9v.9M27.3 31.4v.9M27.3 34.9v.8M27.3 21.3h.5M27.3 35.3h.5M27.3 31.8h.5M27.5 28.3l-.2-.1-.1 .2 .3 .1v.3h-.3M27.7 27.1v-.9l.2 .6 .4-.6v.9"/>
<path d="M27.8 33.3h.5v.6l-.2 .1a.47 .47 0 0 1-.4-.2 .47 .47 0 0 1 .1-.5zM27.8 36.7h.5l-.1 .8-.4-.1zM27.8 28.5l.5-.1-.1-.2-.4 .2v.3l.5 .1M27.8 20.9v.9M27.8 31.4v.9M27.8 34.9v.8M27.9 22.7v.8h.5M27.9 24.5v.8h.5M28.3 20.9v.9M28.3 31.4v.9M28.3 34.9v.8M33.9 50l.8-.7 .9 .7v7.4h-1.7z"/>
<path d="M34.4 51.5l.8 .2-.8 .4M34.4 54.8h.8M34.4 53.8v.6M34.4 54.5v.5M34.4 54.1h.8M34.5 50.9h.7M34.7 56.2l.1-.2h.3l.1 .2v.4h-.8v-.5h.3v.5M34.9 50.5v.6M35 55.3v.4M35.2 55.2l-.8 .3 .8 .3M35.2 53.3h-.8l.2 .3M35.2 52.3v.5l-.5-.5-.3 .1 .1 .4"/>
<path d="M35.2 53.2v.4M37.3 50l1-.7 .8 .7v5.1h-1.8zM37.8 52.7v.5h.5v-.5l.4 .1-.1 .4M37.8 51.9l.9 .2-.9 .4M38 53.9h.7M38.3 53.6v.7M38.7 50.7h-.9l.3 .3M38.7 50.5v.5M38.8 51.1v.7M105.3 50.9l1-.8 .8 .8v7.3h-1.8zM105.8 52.3l.9 .4-.9 .2M105.8 54.8v.5"/>
<path d="M105.8 55.4v.5M105.8 55.6h.9M105.8 55h.9M106 51.7h.7M106.3 57.1l.1-.2 .3 .1v.4h-.9v-.3l.4-.1 .1 .4M106.3 51.4v.7M106.4 56.1v.5M106.7 56l-.9 .4 .9 .2M106.7 54.3h-.9l.3 .2M106.7 53.2v.5l-.5-.5h-.4l.1 .5M106.7 54v.5M108.9 50.9l.8-.8 .9 .8v5.1h-1.7z"/>
<path d="M109.3 53.6v.4l.4 .1-.1-.4 .5-.1v.5M109.3 52.7l.8 .4-.8 .2M109.5 54.8h.6M109.8 54.4v.7M110.1 51.6h-.8l.3 .2M110.1 51.3v.5M110.2 52v.7M27.8 72.5l-.4 .3v-.2v.2h.2M27.9 64.9h1.4v3.5h-1.4zM27.9 72.3h1.4l-.7 1zM27.9 73.3h1.4M28.1 72.8l-.3 .3v-.1v.1h.1"/>
<path d="M28.6 76.3v.8h.9l-.9 1-.8-1h.8M28.6 76.3h.1M28.6 64.1v.8M28.6 68.4v.9M28.6 71v3.5M35.8 64.9h1.3v3.5h-1.3zM35.8 75.4h1.3v3.5h-1.3zM36.5 64.1v.8M36.5 68.4v.9M36.5 74.5v.9M36.5 78.9v.9M64.3 72.5l-.3 .3v-.2v.2h.2"/>
<path d="M64.6 64.9h1.3v3.5h-1.3zM64.6 72.3h1.3l-.7 1zM64.6 73.3h1.3M64.8 72.8l-.5 .3v-.1v.1h.3M65.3 64.1v.8M65.3 68.4v.9M65.3 71v3.5M25.1 87.6h.9M25.9 86.9h3.6v1.4h-3.6zM29.5 87.6h.9M33 87.6h1.9M34.8 86.2v2.7"/>
<path d="M35.3 86v.7M35.3 87.2v.7M35.3 88.4v.7M35.3 86.4h1.7v2.4h-1.7M36.5 92.9v.8h.8l-.8 .9-.9-.9h.9M36.5 92.9h.1M41.7 81.5h8.8l.8 .9-.8 .8h-8.8zM42.8 82h-.4l-.2 .1 .1 .3 .5 .1v.2l-.6 .1M43.2 82.5h.3l.2-.2-.2-.3h-.3v.8M44 82.4h.3M44.4 82h-.4v.8h.4M44.8 82.4h.3"/>
<path d="M45.2 82h-.4v.8h.4M45.6 82a.49 .49 0 0 1 .5 .3 .49 .49 0 0 1-.1 .5h-.4zM46.2 82.9h.7M47.2 82.4h.5M47.2 82v.8M47.7 82v.8M47.9 82.8l.4-.8 .2 .8M48 82.6h.4M48.8 82v.8h.4M49.5 82v.8h.4M102.8 87.6h1.7M106.8 87.6h1.1v3.5"/>
<path d="M107.8 88.6l.4 .2-.2 .2-.3-.2zM107.9 84.2v1.6M108.2 87.4h.6M108.5 87.4l.3 .4h-.6z"/>
</g>
<path d="M103.4 86.8l.2-.3v.9M103.4 87.4h.5M106.8 85.3v-.6l.4 .3 .1-.3h.4v.6M107.8 90v.5l-.5-.5h-.4v.5" fill="none" stroke="#bd0000" stroke-width=".21"/>
<g fill="none" stroke="#aaa" stroke-width=".21">
<path d="M32.2 17.9h2.5M32.2 19.6h2.5M34.7 17h3.5v20.9h-3.5zM34.7 17.8h.9v.1h-.9zM34.7 19.6h.9v.1h-.9zM37.3 17.8h1v.1h-1zM37.3 19.6h1v.1h-1zM38.3 17.9h2.6M38.3 19.6h2.6M32.2 21.3h2.5M32.2 23.1h2.5M32.2 24.8h2.5"/>
<path d="M32.2 26.6h2.5M32.2 28.4h2.5M32.2 30.1h2.5M32.2 31.8h2.5M32.2 33.5h2.5M32.2 35.3h2.5M32.2 37.1h2.5M34.7 21.2h.9v.2h-.9zM34.7 23h.9v.2h-.9zM34.7 24.7h.9v.3h-.9zM34.7 26.5h.9v.2h-.9zM34.7 28.3h.9v.1h-.9z"/>
<path d="M34.7 30h.9v.1h-.9zM34.7 31.7h.9v.2h-.9zM34.7 33.4h.9v.2h-.9zM34.7 35.2h.9v.2h-.9zM34.7 37h.9v.2h-.9zM37.3 21.2h1v.2h-1zM37.3 23h1v.2h-1zM37.3 24.7h1v.3h-1zM37.3 26.5h1v.2h-1zM37.3 28.3h1v.1h-1zM37.3 30h1v.1h-1zM37.3 31.7h1v.2h-1z"/>
<path d="M37.3 33.4h1v.2h-1zM37.3 35.2h1v.2h-1zM37.3 37h1v.2h-1zM38.3 21.3h2.6M38.3 23.1h2.6M38.3 24.8h2.6M38.3 26.6h2.6M38.3 28.4h2.6M38.3 30.1h2.6M38.3 31.8h2.6M38.3 33.5h2.6M38.3 35.3h2.6"/>
<path d="M38.3 37.1h2.6M33.8 44h5.3v1.8h-5.3zM34.6 44.9h.2v.9h-.2zM34.7 45.8v2.5M36.4 44.9h.2v.9h-.2zM36.5 45.8v2.5M38.2 44.9h.1v.9h-.1zM38.3 45.8v2.5M105.3 44.8h5.2v1.8h-5.2zM106.2 45.8h.1v.8h-.1zM106.3 46.6v2.7M107.9 45.8h.1v.8h-.1z"/>
<path d="M107.9 46.6v2.7M109.6 45.8h.2v.8h-.2zM109.7 46.6v2.7"/>
</g>
<g fill="none" stroke="#b2b2b2" stroke-width=".21">
<path d="M33.2 17l.2-.2v.8M33.2 18.5h.5l-.3 .4h.2l.1 .3-.2 .2-.3-.1M33.2 17.6h.5M39.3 16.8h.5v.3l-.5 .5h.5M39.5 18.5l-.2 .6h.5M39.7 18.8v.6M32.8 25.7l.2-.2v.8M32.8 27.5l.2-.2v.8M32.8 29.2l.2-.2v.9M32.8 31l.2-.3v.9M32.8 32.7l.2-.3v1M32.8 34.3h.5v.2l-.5 .5h.5"/>
<path d="M32.8 36.1h.5v.2l-.5 .5h.5M32.8 26.3h.5M32.8 28.1h.5M32.8 29.9h.5M32.8 31.6h.5M32.8 33.4h.5M33.2 22h.5l-.3 .9M33.5 27.3h.6l-.3 .3h.2l.1 .3-.2 .2-.4-.1M33.5 30.7h.6l-.3 .9M33.5 36h.6l-.3 .3 .3 .1v.3l-.2 .1-.4-.1M33.6 20.2h-.3l-.1 .5 .3-.1 .2 .4-.2 .2-.3-.1M33.6 25.7l.3-.2v.8"/>
<path d="M33.6 34.5l.3-.3v.8M33.6 26.3h.5M33.6 35h.5M33.7 24.1l-.3 .2-.2-.4 .2-.2 .3 .2-.2 .6-.2 .1M34 29h-.4v.4l.3-.1 .2 .4-.2 .2-.3-.1M34.1 32.8l-.2 .2-.3-.1v-.4l.3-.1 .2 .2-.2 .7-.2 .1M38.9 24l.2-.3v.9M38.9 25.7l.2-.2v.8M38.9 27.5l.2-.2v.8M38.9 29.2l.2-.2v.9M38.9 31l.2-.3v.9M38.9 32.5h.5v.3l-.5 .6h.5"/>
<path d="M38.9 34.3h.5v.2l-.5 .5h.5M38.9 36.1h.5v.2l-.5 .5h.5M38.9 26.3h.5M38.9 28.1h.5M38.9 29.9h.5M38.9 31.6h.5M38.9 24.6h.5M39.4 22.3l-.1-.1 .1-.2 .4 .1-.1 .2-.4 .2 .1 .4h.3l.1-.5-.2-.1M39.7 20.2l-.3 .1-.1 .7 .1 .2 .4-.1v-.4l-.4-.1-.1 .1M39.7 25.6l.3-.1 .2 .1-.5 .7h.5M39.7 34.3l.4-.1 .1 .2-.5 .6h.5M39.9 23.7a.48 .48 0 0 1 .3 .5 .48 .48 0 0 1-.3 .4l-.2-.3z"/>
<path d="M39.9 27.2l-.2 .6h.5M39.9 31.1l-.2-.2 .1-.2h.3v.4l-.4 .1 .1 .4h.3l.1-.4-.2-.1M39.9 32.4a.48 .48 0 0 1 .3 .5 .48 .48 0 0 1-.3 .5l-.2-.4zM39.9 35.9l-.2 .6h.5M40.1 29h-.3l-.1 .7 .2 .2 .3-.2-.2-.4-.3 .2M40.1 27.5v.6M40.1 36.2v.6M34.5 47.1h-.9l.3 .2M34.5 46.8v.5M36.2 46.8v.5l-.6-.5-.2 .1 .1 .4M37.2 47.3v-.5l.2 .4 .2-.4h.2l.2 .2-.1 .3M106 47.9h-.8l.2 .3"/>
<path d="M106 47.7v.5M107.8 47.7v.6l-.7-.6-.3 .1 .1 .4M108.6 48.3v-.6l.4 .3v-.3h.5l-.1 .6"/>
</g>
<path d="M33 16.4l6.9 22.1M39.9 16.4l-6.9 22.1M32.9 42.2l7.1 5.2M40 42.2l-7.1 5.2M104.3 43.1l7.2 5.3M111.5 43.1l-7.2 5.3" fill="none" stroke="#e00" stroke-width=".34"/>
<g fill="none" stroke="#0c0c0c" stroke-width=".21">
<path d="M20.7 61.1v.8l.2 .1M21.2 61.7l.4-.1-.1-.2-.3 .1v.4l.4 .1M22.3 61.1v.9h-.3l-.1-.5 .2-.1 .2 .1M23.1 61.5l-.2-.1-.2 .1 .1 .5h.3M23.3 62.1h.7M24.5 61.5l-.2-.1-.2 .1 .1 .5h.3M24.9 61.5l.2-.1 .2 .1v.5M24.9 61.1v.9M25.7 61.5h.4v.5h-.4l-.1-.2 .5-.2M26.5 61.5h.3v.5M26.5 61.4v.6M27.1 62.1h.7"/>
<path d="M27.9 61.2l.5-.1v.3l-.6 .6h.6M57.4 61.1l.1 .9M57.8 61.7l.4-.1-.1-.2-.3 .1v.5h.4M58.9 61.1v.9h-.2l-.1-.5h.3M59.8 61.5h-.5v.4l.5 .1M59.9 62.1h.7M61.1 61.5h-.3v.5h.3M61.5 61.5h.4v.5M61.5 61.1v.9M62.3 61.5l.3-.1 .1 .1v.5h-.4l.1-.4h.3M63.1 61.5l.2-.1 .2 .1v.5M63.1 61.4v.6"/>
<path d="M63.7 62.1h.6M64.5 61.4l.3-.3v.9M64.5 62h.5M16.4 86.4l.1 .9M16.8 86.9h.5l-.1-.2h-.4v.5h.4M18 86.7l-.4 .1v.4h.4M18 86.4v.9M18.8 86.7l-.4 .1v.4h.4M19 87.4h.6M20.2 86.7l-.4 .1v.4h.4M20.6 86.8l.3-.1v.6M20.6 86.4v.9"/>
<path d="M21.3 86.7l.5 .1v.5M21.8 86.9h-.5l.1 .4 .4-.1M22.2 86.8h.3v.5M22.2 86.7v.6M22.7 87.4h.7M23.5 86.4h.5v.4l-.5 .5h.5"/>
</g>
<path d="M35.5 87.6l.6-.2v.5z" fill="#980000"/>
<g fill="none" stroke="#980000" stroke-width=".21">
<path d="M35.5 87.6l.6-.2v.5zM36.5 85.8v.6"/>
<circle cx="35.9" cy="87.6" r="1.99"/>
</g>
<path d="M36.4 86.2l.3 .2-.1 .1-.3-.1z" fill="#980000"/>
<path d="M36.4 86.2l.3 .2-.1 .1-.3-.1z" fill="none" stroke="#980000" stroke-width=".21"/>
<path d="M36.4 88.6l.3 .2-.1 .2-.3-.2z" fill="#980000"/>
<g fill="none" stroke="#980000" stroke-width=".21">
<path d="M21.4 17h7.4l.7 .9-.7 .8h-7.4zM22.3 17.9h.3l.1-.4-.4-.1v1h.3l.2-.4-.3-.1M23 18.4l.3-1 .2 1M23.1 18.1h.3M23.7 17.4h.5M24 17.4v1M24.4 17.4h.5M24.6 17.4v1M25.1 17.7l.3-.3v1M25.1 18.4h.5M26 17.5l.3-.1 .2 .3-.6 .7h.6M26.7 17.4l.3 1 .3-1"/>
<path d="M27.6 18h.7M27.9 17.7v.7M44.2 17h9.4v1.7h-9.4l-.8-.8zM44.2 18.7h8.5v1.8h-8.5l-.8-.9zM44.7 17.9h.4l.1-.3-.2-.2h-.3v1l.5-.1v-.4h-.2M44.7 19.6h.4l.1-.3-.5-.1v.9M45.5 19.8h.5M45.6 17.9h.5v-.4l-.5-.1v1M45.8 17.9l.3 .5M46.3 18.4l.3-1 .3 1M46.3 19.6h.4l.1-.3-.5-.1v.9M46.4 18.1h.4"/>
<path d="M46.6 19.6l.2 .5M47.2 17.4v1M47.2 19.2v.9M47.3 17.9l.4 .5M47.3 19.6l.4 .5M47.7 17.4l-.5 .5M47.7 19.2l-.5 .5M48.1 17.9h.2M48.5 17.4h-.4v1h.4M48.7 18.5h.7M48.7 19.8h.4M49.4 18.4l.3-1 .3 1"/>
<path d="M49.5 18.1h.4M49.9 19.6l-.3-.1-.2 .1 .1 .5h.4M50.1 19.5h.4M50.2 19.2v.8l.3 .1M50.6 17.8h-.3l-.1 .1 .2 .5 .2-.1M50.7 19.2v.9h.4M50.9 17.8h.3M51 17.4v.9l.2 .1M51.5 19.3h.5l-.1 .8-.4-.1zM51.6 17.4v1h.4M52.4 17.4l.3 .2v.6l-.1 .2a.49 .49 0 0 1-.5-.4 .49 .49 0 0 1 .3-.6zM65.9 19.6h7.3l.8 .9-.8 .8h-7.3z"/>
<path d="M134.1 15.5h1.8v5.1l-.9 .7-.9-.7zM134.6 18.6v.4h.4v-.4l.3-.1 .2 .2-.1 .3M134.6 17.8l.9 .2-.9 .3M134.8 19.8h.7M135.1 19.5v.6M135.5 16.6h-.9l.3 .2M135.5 16.3v.5M135.5 17v.7M152.4 16.2h1.8v4.4l-.9 .7-.9-.7zM152.9 19.1v-.6l.3 .4v-.3l.2-.1 .3 .1v.5M152.9 17.8l.8 .2-.8 .3M152.9 17.5v-.5l.3 .3 .1-.3h.4v.5"/>
<path d="M153.1 19.8h.6M153.4 19.5v.6M199.7 17h10.3v1.7h-10.3l-.7-.8zM200.5 17.9h.3l.2-.1-.2-.4h-.3v1M201.3 17.8v.6M201.6 17.8l-.3 .1M201.9 17.8l.4 .1v.4l-.2 .1-.3-.2zM202.5 17.8h.4M202.7 17.4v.9l.2 .1M203.1 18l.4-.1v-.1l-.4 .1v.3l.2 .2 .2-.1M204.3 17.8h-.3l-.1 .1 .1 .5 .3-.1M204.5 17.8h.4"/>
<path d="M204.6 17.4v.8l.3 .2M205.1 18l.5-.1-.1-.1h-.4v.5h.4M206.3 17.8l-.4 .1v.4h.4M206.3 17.4v1M206.5 18.5h.7M207.3 17.7l.3-.3v1M207.3 18.4h.6M208.2 17.5h.4v.4l-.5 .5h.5M208.9 17.4l.3 1 .3-1M16.6 27.4h12.2l.7 1-.7 .8h-12.2zM17.4 28.4h.4M17.9 27.9h-.5v.9"/>
<path d="M18.2 27.9l.1 .9 .4-.1v-.8M18.4 20.5h10.4l.7 .8-.7 1h-10.4zM18.6 36.1h10.2l.7 1-.7 .8h-10.2zM18.9 25.7h9.9l.7 .9-.7 .8h-9.9zM18.9 32.7h9.9l.7 .8-.7 1h-9.9zM18.9 31h9.9l.7 .8-.7 .9h-9.9zM19.1 34.5h9.7l.7 .8-.7 .8h-9.7zM19.1 28.4h.3M19.1 20.9v.9M19.5 37.1h.4l.1-.4h-.5v.8M19.6 27.9h-.5v.9h.5M19.6 34l.3-.8 .2 .8"/>
<path d="M19.6 26.2l.3 .9 .2-.7 .1 .7 .2-.9M19.6 33.8h.5M19.7 31.4v.9M19.7 31.8h.5M19.7 37.1l.3 .4M19.9 27.9v.9h.4M20 24h8.8l.7 .8-.7 .9h-8.8zM20 34.9v.8h.4M20.1 21l-.3-.1-.2 .3v.4l.2 .2h.3v-.4h-.2M20.1 37.6h.7M20.2 31.4v.9M20.4 28.9h.7"/>
<path d="M20.4 32.3h.7M20.5 33.2v.8h.4M20.5 35.8h.6M20.7 27.1l.2-.9 .3 .9M20.7 26.8h.4M20.9 36.7h.5M21 20.9v.9l-.5-.9v.9M21 33.2h.5M21.2 34.9h.5M21.2 36.7v.8M21.2 24.5h-.4l-.1 .1 .5 .5-.1 .2-.4-.1M21.2 27.9v.9h.5"/>
<path d="M21.2 31.8h.4l.2-.1-.1-.3h-.5v.9h.5l.1-.4-.2-.1M21.2 33.2v.8M21.3 22.3h7.5l.7 .8-.7 .9h-7.5zM21.3 20.9v.9M21.3 26.2h.5M21.4 34.9v.8M21.6 24.9h.4l.1-.4h-.5v.8M21.6 26.2v.9M21.7 36.7l.1 .8 .4-.1v-.7M21.7 20.9h.5M21.8 27.9l.4 .9 .2-.9M21.8 33.5h.3"/>
<path d="M21.9 20.9v.9M22 34.9v.8l.5-.1v-.7M22.2 23.1h.4l.1-.3-.5-.1v.8M22.2 26.6h.2M22.2 31.8h.2M22.3 33.2h-.5v.8h.5M22.4 23.1l.3 .4M22.4 20.9v.9M22.5 24.9h.3M22.6 26.2h-.4v.9h.4M22.6 33.6l.5-.1v-.2l-.5-.1v.8M22.6 31.4h-.4v.9h.4"/>
<path d="M22.6 37.1h.4l.1-.4h-.5v.8M22.8 27.9v.9h.4M22.9 32.3l.2-.9 .3 .9M22.9 33.6l.2 .4M22.9 37.1l.2 .4M22.9 26.7h.4l.1-.4-.1-.1h-.4v.9M22.9 24.5h-.4v.8h.4M22.9 35.4l.5-.1v-.3l-.5-.1v.8M22.9 32h.4M23 20.9l.4 .2v.6l-.2 .1-.3-.1v-.6zM23.1 23.1h.3l.1-.3-.4-.1v.8M23.1 35.4l.3 .3"/>
<path d="M23.2 28.9h.7M23.2 26.7l.2 .4M23.3 24.9h.2M23.6 27.2h.7M23.7 24.5h-.4v.8h.4M23.7 32.3v-.9l.3 .6 .3-.6v.9M24 23.5v-.8l.2 .6 .3-.6v.8M24 33.2v.8l-.6-.8v.8M24 36.7v.8l-.6-.8v.8M24 24.5h.4l.1 .1v.5l-.2 .2h-.3zM24.1 28.4h.4v-.5h-.4v.9M24.2 37.6h.7"/>
<path d="M24.2 34.1h.7M24.3 20.9v.9l-.5-.9v.9M24.3 34.9v.8l-.5-.8v.8M24.3 28.4l.3 .4M24.4 26.2h.5M24.5 21.9h.6M24.5 35.8h.6M24.5 32.3h.6M24.6 26.2v.9M24.7 23.6h.7M24.7 25.4h.7M25 34l.2-.8 .3 .8"/>
<path d="M25 37.5l.2-.8 .3 .8M25 27.2h.6M25.1 37.2h.3M25.1 33.8h.3M25.2 21.8l.3-.9 .3 .9M25.2 35.7l.3-.8 .3 .8M25.2 32.3l.3-.9 .3 .9M25.3 28.3h-.3l.1 .2h.2v.3h-.3M25.3 21.6h.4M25.3 35.6h.4M25.3 32h.4M25.6 24.9h.5"/>
<path d="M25.6 23.1h.5M25.6 22.7v.8M25.6 24.5v.8M25.6 28.5l.5-.1-.2-.2-.3 .1v.5h.4M25.8 26.7h.4l.1-.4-.1-.1h-.4v.9M26.1 22.7v.8M26.1 24.5v.8M26.2 33.5l-.3-.1-.2 .2 .2 .4 .3-.1M26.2 37l-.3-.1-.2 .2 .1 .4h.4M26.4 23.5l.3-.8 .3 .8M26.4 25.3l.3-.8 .3 .8M26.4 28.3l.3-.1 .1 .2v.4"/>
<path d="M26.4 36.9h.3M26.4 33.4h.3M26.4 28.2v.6M26.5 21.2l-.4 .1v.5h.4M26.5 35.2l-.4 .1v.4h.4M26.5 31.7h-.4v.5l.4 .1M26.5 23.3h.4M26.5 25.1h.4M26.6 26.2l.2 .9 .2-.7 .2 .7 .1-.9M26.6 33.2v.7l.1 .1M26.6 36.7v.8h.1M26.7 21.2h.4"/>
<path d="M26.7 35.2h.4M26.7 31.7h.4M26.8 20.9v.8l.3 .1M26.8 34.9v.7l.3 .1M26.8 31.4v.8l.3 .1M27.1 33.2v.8h.3M27.1 36.7v.8h.3M27.3 22.7v.8h.4M27.3 24.5v.8h.4M27.3 20.9v.9M27.3 31.4v.9M27.3 34.9v.8"/>
<path d="M27.3 21.3h.5M27.3 35.3h.5M27.3 31.8h.5M27.5 28.3l-.2-.1-.1 .2 .3 .1v.3h-.3M27.7 27.1v-.9l.2 .6 .4-.6v.9M27.8 33.3h.5v.6l-.2 .1a.47 .47 0 0 1-.4-.2 .47 .47 0 0 1 .1-.5zM27.8 36.7h.5l-.1 .8-.4-.1zM27.8 28.5l.5-.1-.1-.2-.4 .2v.3l.5 .1M27.8 20.9v.9M27.8 31.4v.9M27.8 34.9v.8M27.9 22.7v.8h.5"/>
<path d="M27.9 24.5v.8h.5M28.3 20.9v.9M28.3 31.4v.9M28.3 34.9v.8M44.2 20.5h11.3v1.8h-11.3l-.8-1zM44.2 25.7h9.7v1.7h-9.7l-.8-.8zM44.2 27.4h9v1.8h-9l-.8-.8zM44.2 22.3h9.7v1.7h-9.7l-.8-.9zM44.2 24h7.6v1.7h-7.6l-.8-.9zM44.2 34.5h8.8v1.6h-8.8l-.8-.8zM44.2 36.1h7.7v1.8h-7.7l-.8-.8zM44.2 32.7h10.7v1.8h-10.7l-.8-1z"/>
<path d="M44.2 31h7.7v1.7h-7.7l-.8-.9zM44.6 28.8l.3-.9 .3 .9M44.6 23.5l.3-.8 .3 .8M44.6 37.5l.3-.8 .3 .8M44.7 26.2v.9h.4M44.7 34.9h.3l.2 .2v.5l-.2 .1h-.3zM44.7 31.8h.3l.2-.1-.1-.3h-.4v.9h.4l.1-.4-.2-.1M44.7 28.5h.4M44.7 23.3h.4M44.7 37.2h.4M44.9 20.9a.47 .47 0 0 1 .4 .5 .47 .47 0 0 1-.4 .4l-.2-.1v-.6zM45.2 24.5h-.3l-.2 .1v.5l.3 .2 .2-.1"/>
<path d="M45.2 33.3l-.3-.1-.2 .2v.4l.3 .2 .2-.1M45.2 27.2h.7M45.5 20.1l.2-.9 .4 .9M45.5 27.9v.9h.4M45.5 37.1l.4-.1-.1-.3h-.3v.8h.4l.1-.3-.3-.1M45.5 22.7v.8M45.5 31.4h.5M45.6 20.9v.9M45.6 24.9h.3M45.7 34.9a.42 .42 0 0 1 .4 .4 .42 .42 0 0 1-.4 .4l-.2-.2zM45.7 33.2l.4 .1a.47 .47 0 0 1-.4 .7l-.2-.3zM45.7 31.4v.9"/>
<path d="M45.9 23.1h.4l.1-.2-.2-.2h-.3v.8M46 24.5h-.4v.8h.4M46.1 20.9v.9h.4M46.1 26.6h.4l.1-.3-.2-.1h-.3v.9l.5-.1v-.3l-.2-.1M46.1 28.8l.2-.9 .3 .9M46.1 23.1l.3 .4M46.1 28.5h.5M46.4 24.5v.8h.4M46.5 33.3h.5a.47 .47 0 0 1-.4 .7l-.1-.1zM46.6 21.9h.6M46.6 34.9a.47 .47 0 0 1 .5 .3 .47 .47 0 0 1-.2 .5l-.4-.1v-.6zM46.7 23.1h.4l.1-.2-.1-.2h-.4v.8h.5v-.3l-.1-.1"/>
<path d="M46.7 31.4v.9l-.5-.9v.9M46.8 36.7h-.5v.3l.5 .2-.1 .3h-.4M46.9 28.4h.4l.1-.4-.5-.1v.9M46.9 25.4h.7M47 26.6h.2M47 37.6h.7M47 32.3h.7M47.2 28.4l.2 .4M47.3 21.8l.3-.9 .2 .9M47.4 26.2h-.4v.9h.4M47.4 35.4h.3l.2-.2-.2-.3h-.3v.8M47.4 33.2v.8h.4"/>
<path d="M47.4 21.6h.4M47.5 23.5l.3-.8 .3 .8M47.6 23.3h.4M47.7 27.1l.2-.9 .3 .9M47.7 25.3l.2-.8 .3 .8M47.7 35.4l.2 .3M47.7 37.5l.3-.8 .3 .8M47.7 32.3l.3-.9 .3 .9M47.7 26.8h.4M47.7 25.1h.4M47.8 28.8v-.9l.3 .6 .2-.6v.9M47.8 20.1h.7"/>
<path d="M47.8 37.2h.4M47.8 32h.4M48 34l.3-.8 .3 .8M48.1 35.8h.7M48.1 33.8h.4M48.2 20.9v.9h.4M48.5 27.1v-.9l.3 .6 .3-.6v.9M48.6 20.1l.3-.9 .3 .9M48.6 28.9h.7M48.8 21.4l.6-.1v-.3l-.6-.1v.9M48.8 22.8l-.2-.1-.3 .2v.5l.2 .1h.3v-.3h-.1M48.8 24.8l-.2-.1-.2 .2 .2 .4 .2-.1"/>
<path d="M48.8 35.7l.3-.8 .3 .8M48.9 37l-.2-.1-.2 .2 .1 .4h.3M48.9 31.7h-.2l-.2 .1 .1 .5h.3M48.9 35.6h.5M49 23.6h.7M49.1 21.4l.3 .4M49.1 24.7h.3M49.2 36.9h.3M49.2 31.7h.3M49.3 24.5v.7l.1 .1M49.3 27.2h.6M49.4 28.8l.2-.9 .3 .9"/>
<path d="M49.4 36.7v.8h.1M49.4 33.2v.8l-.6-.8v.8M49.4 31.4v.9h.1M49.4 28.5h.5M49.7 33.2h.4M49.8 21.8v-.9l.2 .7 .3-.7v.9M49.8 23.5l.2-.8 .4 .8M49.8 24.5v.8h.3M49.9 36.7v.8h.3M49.9 31.4v.9h.3M49.9 23.3h.4M49.9 33.2v.8"/>
<path d="M50 27.1l.3-.9 .3 .9M50 35.2l-.3 .1v.4h.3M50.1 26.8h.4M50.2 34.1h.7M50.3 35.2h.3M50.5 24.5h.5v.6l-.2 .2-.4-.2zM50.5 34.9v.8h.1M50.5 28.3l-.2-.1-.2 .2 .1 .4h.3M50.5 36.7h.5v.8l-.5-.1zM50.5 31.5h.5v.8l-.5-.1zM50.5 21.9h.7M50.8 28.2h.3"/>
<path d="M51 27.9v.9h.1M51 34.9v.8h.4M51 34l.3-.8 .3 .8M51 23h-.4v.4l.4 .1M51 33.8h.5M51.3 21.8l.3-.9 .3 .9M51.3 26.5l-.4 .1v.4h.4M51.3 22.9h.3M51.4 22.7v.7l.2 .1M51.4 21.6h.4M51.5 27.9v.9M51.5 28.4h.5"/>
<path d="M51.6 26.5h.3M51.6 26.2v.7l.3 .2M51.6 35l.2-.1 .3 .1v.7l-.5-.1zM51.9 22.7v.8h.4M52 27.9v.9M52.1 26.6h.6M52.1 26.2v.9M52.2 33.5l-.2-.1-.2 .2 .2 .4 .2-.1M52.3 27.9v.9M52.5 21.2h-.4v.6h.4M52.5 33.4h.3M52.6 33.2v.7l.2 .1"/>
<path d="M52.7 26.2v.9M52.7 22.7l.5 .2-.2 .6-.4-.1v-.5zM52.7 21.2h.4M52.9 20.9v.9h.2M53.1 26.2v.9M53.1 33.2v.8M53.1 33.5h.5M53.4 20.9v.9h.4M53.6 33.2v.8M54 33.2v.8M54.3 20.9l.3 .2v.6l-.2 .1-.3-.1v-.6zM66.7 20.5h.4v-.4h-.4v.8h.4l.1-.2-.2-.2"/>
<path d="M67.5 20.9l.2-.8 .3 .8M67.6 20.7h.4M68.2 20.1h.5M68.4 20.1v.8M68.8 20.1h.5M69.1 20.1v.8M69.6 20.3l.2-.2v.8M69.6 20.9h.5M70.4 20.1h.4l.1 .2-.5 .6h.5M71.2 20.1l.3 .8 .3-.8M72 20.7h.7M72.4 20.3v.6"/>
<path d="M78.3 30.6l-.3 .4v-.2v.2h.1M78.4 23.1h1.5v3.4h-1.5zM78.4 30.3h1.5l-.7 1.1zM78.4 31.4h1.5M78.6 31l-.3 .3v-.1v.1h.2M79.2 34.5v.8h.9l-.9 .8-.9-.8h.9M79.2 34.5h.1M79.2 22.3v.8M79.2 26.6v.8M79.2 29.2v3.5M99.2 22.3v.8h1l-1 .9-.8-.9h.8M99.2 22.3h.1"/>
<path d="M163.1 22.3h10.4l.7 .8-.7 .9h-10.4zM163.9 22.7v.8M164.8 22.8l-.3-.1-.3 .2v.5l.2 .1h.4v-.3h-.2M165.7 22.7v.8l-.5-.8v.8M166.1 20.5h7.4l.7 .8-.7 1h-7.4zM166.1 22.7v.8M166.4 22.7h.5M166.6 22.7v.8M167 21.3h.3l.1-.3-.4-.1v.9h.3l.2-.3-.3-.2M167.1 22.7v.8M167.7 22.7l.4 .2-.1 .6-.5-.1v-.5zM167.7 21.8l.3-.9 .3 .9"/>
<path d="M167.8 21.6h.4M168.4 20.9h.5M168.7 20.9v.9M169 22.7v.8l-.5-.8v.8M169.1 20.9h.5M169.2 23.6h.6M169.3 20.9v.9M169.8 21.2l.3-.3v.9M169.8 21.8h.5M169.9 23.5l.4-.8 .2 .8M170 23.3h.4M170.7 21l.3-.1 .2 .3-.6 .6h.6"/>
<path d="M171.2 23h-.4v.4l.4 .1M171.4 20.9l.3 .9 .3-.9M171.4 22.9h.4M171.5 22.7v.7l.3 .1M172 22.7v.8M172 23.1h.5M172.3 21.5h.7M172.5 22.7v.8M172.6 21.2v.6M173 22.7v.8M266.6 23.1h5.1l.8 .9-.8 .9h-5.1zM267.2 24.1h.7"/>
<path d="M267.5 23.8v.7M268.7 23.5h-.4v.5h.4v.4h-.4M269 23.5l.3 1 .3-1M269.7 24.5h.6M270.5 23.8l.3-.3v1M270.5 24.5h.5M33.9 50l.8-.7 .9 .7v7.4h-1.7zM34.4 51.5l.8 .2-.8 .4M34.4 54.8h.8M34.4 54.1h.8M34.4 53.8v.6M34.4 54.5v.5"/>
<path d="M34.5 50.9h.7M34.7 56.2l.1-.2h.3l.1 .2v.4h-.8v-.5h.3v.5M34.9 50.5v.6M35 55.3v.4M35.2 55.2l-.8 .3 .8 .3M35.2 53.3h-.8l.2 .3M35.2 52.3v.5l-.5-.5-.3 .1 .1 .4M35.2 53.2v.4M37.3 50l1-.7 .8 .7v5.1h-1.8zM37.8 52.7v.5h.5v-.5l.4 .1-.1 .4M37.8 51.9l.9 .2-.9 .4M38 53.9h.7"/>
<path d="M38.3 53.6v.7M38.7 50.7h-.9l.3 .3M38.7 50.5v.5M38.8 51.1v.7M70.5 50l.9-.7 .8 .7v7.4h-1.7zM70.9 51.5l.9 .2-.9 .4M70.9 53.8v.6M70.9 54.5v.5M70.9 54.8h.9M70.9 54.1h.9M71.1 50.9h.7M71.4 56.2l.1-.2 .3 .1v.5h-.9v-.5l.3-.1 .2 .2v.4"/>
<path d="M71.5 50.5v.6M71.5 55.3v.4M71.8 55.2l-.9 .3 .9 .3M71.8 53.3h-.9l.3 .3M71.8 52.3v.5l-.5-.5-.4 .1 .1 .4M71.8 53.2v.4M74 50l.8-.7 .9 .7v5.1h-1.7zM74.4 52.7v.5h.4v-.5l.5 .1-.1 .4M74.4 51.9l.9 .2-.9 .4M74.7 53.9h.6M75 53.6v.7M75.3 50.7h-.9l.3 .3"/>
<path d="M75.3 50.5v.5M75.3 51.1v.7M105.3 50.9l1-.8 .8 .8v7.3h-1.8zM105.8 52.3l.9 .4-.9 .2M105.8 54.8v.5M105.8 55.4v.5M105.8 55.6h.9M105.8 55h.9M106 51.7h.7M106.3 57.1l.1-.2 .3 .1v.4h-.9v-.3l.4-.1 .1 .4M106.3 51.4v.7M106.4 56.1v.5"/>
<path d="M106.7 56l-.9 .4 .9 .2M106.7 54.3h-.9l.3 .2M106.7 53.2v.5l-.5-.5h-.4l.1 .5M106.7 54v.5M108.9 50.9l.8-.8 .9 .8v5.1h-1.7zM109.3 53.6v.4l.4 .1-.1-.4 .5-.1v.5M109.3 52.7l.8 .4-.8 .2M109.5 54.8h.6M109.8 54.4v.7M110.1 51.6h-.8l.3 .2M110.1 51.3v.5M110.2 52v.7"/>
<path d="M191.8 48.3h12.1v1.8h-12.1l-.8-.8zM192.4 49.3h.4M192.9 48.8h-.5v.9M193.2 48.8l.1 .9h.3l.1-.9M194.1 49.3h.3M194.6 48.8h-.5v.9h.5M194.9 48.8v.9h.4M195.4 49.8h.7M196.3 48.8v.9h.4M196.8 48.8l.4 .9 .2-.9M197.8 48.8v.9h.3M198.2 49.8h.7"/>
<path d="M199.1 49.3h.5v-.5h-.5v.9M199.3 49.3l.3 .4M200.2 49.2l-.1-.1-.2 .2 .4 .3-.4 .1M200.7 49.4h.4l-.2-.3-.2 .1v.5h.3M201.4 49.2l.3-.1 .1 .2v.4M201.4 49.1v.6M202.5 49.2h-.3l.1 .2h.2v.3h-.3M202.9 49.4h.4l-.1-.3-.3 .2v.3l.4 .1M256.2 58.9h1.7v4.4l-.9 .8-.8-.8zM266.6 40.5h4.4l.8 .9-.8 .8h-4.4zM267.2 41.6h.7M267.5 41.2v.7"/>
<path d="M268.2 41h.5l-.2 .3 .2 .1v.4h-.5M269 41l.3 .9 .3-.9M269.8 41h.5l-.2 .3 .2 .1v.4h-.5M65.3 76.3v.8h.8l-.8 1-1-1h1M65.3 76.3h.1M256.6 61.8v-.5l.4 .2v-.2h.4v.5M256.6 60.4l.9 .3-.9 .3M256.6 60.3v-.6l.4 .3v-.2l.1-.1 .4 .1-.1 .5M256.8 62.5h.7M257.1 62.1v.7M262.3 60.6h1.7v4.4l-.9 .8-.8-.8zM262.7 63.6v-.6l.4 .3 .1-.3 .4 .1-.1 .5"/>
<path d="M262.7 62.2l.9 .3-.9 .2M262.7 62v-.5l.4 .2v-.2h.4v.5M263 64.3h.6M263.2 63.9v.7M31.2 87.6h1.8M35.3 87.6h1.2v3.5M36.4 88.6l.3 .2-.1 .2-.3-.2zM36.5 84.2v1.6M36.7 87.4h.5M37 87.4l.2 .4h-.5zM41.7 81.5h8.8l.8 .9-.8 .8h-8.8zM42.8 82h-.4l-.2 .1 .1 .3 .5 .1v.2l-.6 .1"/>
<path d="M43.2 82.5h.3l.2-.2-.2-.3h-.3v.8M44 82.4h.3M44.4 82h-.4v.8h.4M44.8 82.4h.3M45.2 82h-.4v.8h.4M45.6 82a.49 .49 0 0 1 .5 .3 .49 .49 0 0 1-.1 .5h-.4zM46.2 82.9h.7M47.2 82.4h.5M47.2 82v.8M47.7 82v.8M47.9 82.8l.4-.8 .2 .8M48 82.6h.4"/>
<path d="M48.8 82v.8h.4M49.5 82v.8h.4M61.8 87.6h.8M62.6 86.9h3.5v1.4h-3.5zM66.1 87.6h.9M78.3 81.5h7.5l.7 .9-.7 .8h-7.5zM78.9 82.5l.5-.1v-.4h-.5v.8M79.2 82.5l.2 .3M79.8 82.5h.4l.1-.2-.1-.3h-.4v.8M80.7 82.8v-.8l.2 .6 .4-.6v.8M81.4 82.9h.7M82.4 82.4h.4"/>
<path d="M82.4 82v.8M82.8 82v.8M83.1 82.8l.3-.8 .3 .8M83.2 82.6h.4M84 82v.8h.4M84.7 82v.8h.4M113.2 81.5h9.8l.8 .9-.8 .8h-9.8zM113.7 82l.3 .8 .1-.6 .2 .6 .2-.8M114.6 82.8l.4-.8 .2 .8M114.7 82.6h.4M115.4 82h.5M115.6 82v.8"/>
<path d="M116.2 82.4h.3M116.7 82h-.5v.8h.5M117 82.5h.3l.2-.2-.2-.3h-.3v.8M117.2 82.5l.3 .3M117.7 82.9h.7M118.4 82h.5M118.7 82v.8M119 82.9h.6M119.9 82.5h.3l.2-.4-.2-.1h-.3v.8M120.6 82l.3 .8 .1-.6 .2 .6 .2-.8M121.7 82.8v-.8l.3 .6 .3-.6v.8M16.7 114.6h11.1l.8 .9-.8 .9h-11.1z"/>
<path d="M17.7 115.1l.3 .1v.6l-.1 .2a.49 .49 0 0 1-.5-.4 .49 .49 0 0 1 .3-.5zM18.5 115.1v.9M18.5 102.4h9.3l.8 .9-.8 .8h-9.3zM18.9 115.1v.9h.3M19.3 108.5h8.5l.8 .9-.8 .8h-8.5zM19.3 116.1h.7M19.4 103.3h.3l.1-.4h-.4v.9h.3l.2-.3-.3-.2M20.1 116l.3-.9 .3 .9M20.1 109.5l.6-.1v-.4h-.6v.9M20.1 115.7h.5M20.2 103.4l.5-.1v-.4h-.5v.9M20.5 103.4l.2 .4"/>
<path d="M20.9 109.9l.3-.9 .3 .9M21 115.1v.9h.3M21 103.8l.2-.9 .4 .9M21 109.6h.4M21.1 103.5h.4M21.7 115.6h.3l.2-.2-.2-.3h-.3v.9M21.8 109.5l.5-.1v-.4h-.5v.9M21.8 115.6l.4 .4M21.8 102.9v.9M22 109.5l.3 .4M22 103.3l.3 .5M22.3 102.9l-.5 .5"/>
<path d="M22.5 116v-.9l.4 .6 .2-.6v.9M22.7 109v.9M22.8 109.4l.4 .5M22.8 103.3h.2M23.2 102.9h-.4v.9h.4M23.2 109l-.5 .5M23.3 116.1h.7M23.3 110h.7M23.3 103.9h.7M24 116l.4-.9 .2 .9M24 109.9l.4-.9 .2 .9M24 103.8l.4-.9 .2 .9"/>
<path d="M24.1 115.7h.4M24.1 109.6h.4M24.1 103.5h.4M25.3 115.4h-.3l-.1 .2 .2 .4 .2-.1M25.3 109.3h-.3l-.1 .2 .2 .4 .2-.1M25.3 103.2h-.3l-.1 .2 .2 .4 .2-.1M25.6 115.4h.3M25.6 109.3h.3M25.6 103.2h.3M25.6 115.1v.7l.3 .2M25.6 109v.7l.3 .2M25.6 102.9v.7l.3 .2"/>
<path d="M26.2 115.1v.9h.4M26.2 109v.9h.4M26.2 102.9v.9h.4M27.1 115.1l.3 .1v.6l-.1 .2a.49 .49 0 0 1-.5-.4 .49 .49 0 0 1 .3-.5zM27.1 109l.3 .1v.6l-.1 .2a.49 .49 0 0 1-.5-.4 .49 .49 0 0 1 .3-.5zM27.1 102.9l.3 .1v.6l-.1 .2a.49 .49 0 0 1-.5-.4 .49 .49 0 0 1 .3-.5zM94.9 113.8h1.7v4.4l-.8 .8-.9-.8zM95.3 116.7v-.5l.4 .3 .1-.3h.3l.2 .1-.1 .4M95.3 115.4l1 .2-1 .4M95.3 115.1v-.5l.4 .3 .1-.3h.4v.5M95.6 117.4h.7M95.9 117.1v.7"/>
<path d="M101 112.9h1.8v4.4l-1 .8-.8-.8zM101.4 115.9v-.6l.4 .3 .1-.3h.3l.2 .2-.1 .4M101.4 114.5l1 .3-1 .3M101.4 114.3v-.5l.4 .2v-.2h.5v.5M101.7 116.5h.7M102 116.2v.6M156.8 100.1h1.7v5.1l-.9 .7-.8-.7zM157.2 103.2v.3l.4 .1v-.3l.4-.2 .2 .2-.1 .3M157.2 102.3l1 .3-1 .3M157.5 104.3h.7M157.8 104v.6M158.2 101.1h-1l.3 .2"/>
<path d="M158.2 100.9v.4M158.2 101.5v.7M158.5 100.7h1.8v4.5l-.9 .7-.9-.7zM159 103.6v-.5l.3 .3 .2-.3 .3 .1v.4M159 102.3l.8 .3-.8 .3M159 102.1v-.6l.3 .3v-.2h.5v.5M159.2 104.3h.6M159.5 104v.6M272.6 106.8h4.4l.8 .9-.8 .8h-4.4l-.7-.8zM273.1 107.8h.7M273.5 107.4v.7M274.1 107.3h.6l-.4 .3h.3v.5l-.5-.1"/>
<path d="M274.9 107.3l.3 .8 .3-.8M275.7 107.3h.6l-.4 .3h.3v.5l-.5-.1M18.2 132.9h9.6l.8 .9-.8 .9h-9.6zM18.2 120.7h9.6l.8 .9-.8 .9h-9.6zM18.9 139h8.9l.8 .9-.8 .9h-8.9zM18.9 122.1l.2-.9 .4 .9M19 121.8h.4M19 133.4v.9h.5M19.6 134.4h.6M19.7 121.2v.9M20.1 121.7l.6-.1v-.4h-.6v.9M20.3 126.8h7.5l.8 .9-.8 .9h-7.5z"/>
<path d="M20.4 133.9h.3l.2-.2-.1-.3h-.4v.9l.5-.1v-.3h-.2M20.4 121.7l.3 .4M20.5 139.5v.9h.4M21 121.6h.4l.1-.3-.2-.1h-.3v.9l.5-.1v-.3l-.2-.1M21.2 133.9h.4M21.7 127.4l-.5-.1a.44 .44 0 0 0-.1 .6 .44 .44 0 0 0 .6 .2M21.7 133.4h-.5v.9h.5M21.8 122.1l.3-.9 .2 .9M21.8 121.8h.5M21.9 134.3l.4-.9 .2 .9M21.9 139.9h.4l.1-.3-.5-.1v.9M22 127.7h.3"/>
<path d="M22 134h.4M22.2 139.9l.2 .5M22.4 127.3h-.4v.9h.4M22.9 127.3v.9h.3M22.9 134.3v-.9l.2 .6 .3-.6v.9M23.1 121.2a.41 .41 0 0 0-.5 .5 .41 .41 0 0 0 .6 .3v-.3h-.2M23.3 128.3h.7M23.3 122.2h.7M23.6 134.4h.7M24 128.2l.4-.9 .2 .9M24 122.1l.4-.9 .2 .9M24.1 127.9h.4"/>
<path d="M24.1 121.8h.4M24.4 134.3l.2-.9 .4 .9M24.5 134h.4M25.3 127.6h-.3l-.1 .2 .2 .4 .2-.1M25.3 121.5h-.3l-.1 .2 .2 .4 .2-.1M25.6 133.8h-.4v.4h.4M25.6 139.9h-.4v.4l.4 .1M25.6 127.6h.3M25.6 121.5h.3M25.6 127.3v.7l.3 .2M25.6 121.2v.7l.3 .2M25.8 133.7h.4"/>
<path d="M25.8 139.8h.4M26 133.4v.8l.2 .1M26 139.5v.9h.2M26.2 127.3v.9h.4M26.2 121.2v.9h.4M26.5 133.9h.5M26.5 133.4v.9M26.5 139.5v.9M26.5 139.9h.5M26.9 127.4h.5v.6l-.1 .2a.47 .47 0 0 1-.4-.3 .47 .47 0 0 1 0-.5zM27 133.4v.9M27 139.5v.9"/>
<path d="M27.1 121.2l.3 .1v.6l-.1 .2a.49 .49 0 0 1-.5-.4 .49 .49 0 0 1 .3-.5zM27.4 133.4v.9M27.4 139.5v.9M197.6 132.1h4.4v1.7h-4.4l-.8-.9zM198.1 133.1h.7M198.5 132.8v.6M199.1 132.5h.5l-.2 .3 .2 .1v.4h-.5M199.9 132.5l.3 .9 .3-.9M200.7 132.5h.5l-.2 .3 .2 .1v.4h-.5M251.9 134.7h4.4l.7 .8-.7 .9h-4.4zM252.7 135.7h.7M253.1 135.4v.7"/>
<path d="M253.7 135.1h.5l-.3 .4 .3 .1v.3l-.1 .2-.4-.1M254.5 135.1l.3 1 .3-1M255.3 135.1h.6l-.4 .4 .4 .1v.3l-.2 .2-.4-.1M17.3 151.2h10.5l.8 .9-.8 .9h-10.5zM18.6 151.8l-.4-.1-.2 .4 .2 .5 .4-.1M19 151.8h.5l-.1 .8-.4-.1zM19.1 157.3h8.7l.8 .9-.8 .9h-8.7zM19.6 140.4l.3-.9 .3 .9M19.7 140.1h.4M19.9 151.8h.5l-.1 .8-.4-.1zM20 157.8l.4 .1 .1 .4-.2 .4h-.3zM20.2 145.1h7.6l.8 .9-.8 .9h-7.6z"/>
<path d="M20.8 157.9h.5l-.1 .8-.4-.1zM20.8 151.7v.9h.4M21.1 140.4l.2-.9 .4 .9M21.1 146h.4l-.1-.4h-.3v.9h.4l.1-.3-.3-.2M21.2 140.1h.4M21.3 152.6l.4-.9 .2 .9M21.4 152.3h.4M21.8 157.9h.5l-.1 .8-.4-.1zM21.8 145.6h.5M22.1 145.6v.9M22.7 158.2h.4v-.4h-.4v.9M22.8 151.7v.9l-.5-.9v.9"/>
<path d="M22.9 140.4v-.9l.2 .6 .3-.6v.9M22.9 158.2l.3 .5M23 151.7h.5M23.1 145.6v.9l-.5-.9v.9M23.3 146.6h.7M23.3 158.7h.7M23.3 151.7v.9M23.6 140.5h.7M23.6 152.6h.7M24 146.5l.4-.9 .2 .9M24 158.7l.4-.9 .2 .9M24.1 146.2h.4"/>
<path d="M24.1 158.4h.4M24.4 140.4l.2-.9 .4 .9M24.4 152.6l.2-.9 .4 .9M24.5 140.1h.4M24.5 152.3h.4M25.3 146l-.2-.1-.2 .1 .1 .5h.3M25.3 158.2l-.2-.1-.2 .1 .1 .5h.3M25.6 152.1h-.4v.4l.4 .1M25.6 145.9h.3M25.6 158.1h.3M25.6 145.6v.8l.3 .1M25.6 157.8v.8l.3 .1"/>
<path d="M25.8 152h.4M26 151.7v.9h.2M26.2 145.6v.9h.4M26.2 157.8v.9h.4M26.5 151.7v.9M26.5 152.1h.5M26.9 145.7h.5l-.1 .8-.4-.1zM26.9 157.9h.5l-.1 .8-.4-.1zM27 151.7v.9M27.4 151.7v.9M17.8 169.6h10l.8 .8-.8 .9h-10zM18.3 175.7h9.5l.8 .8-.8 .9h-9.5z"/>
<path d="M18.6 170.4h.4l.1-.2-.1-.2h-.4v.9M18.9 170.4l.2 .5M19 176.1v.8h.5M19.3 170.9h.7M19.6 177h.6M20.1 170h.5M20.2 163.5h7.6l.8 .8-.8 .9h-7.6zM20.3 170v.9M20.3 176.1h.5M20.6 176.1v.8M20.8 170l.1 .9h.3l.1-.2v-.7M21 164.8l.2-.9 .3 .9"/>
<path d="M21 164.5h.4M21.1 176.1l.1 .8h.4v-.8M21.8 170.4h.4l.1-.2-.2-.2h-.3v.9M21.8 164.3l.5-.1-.1-.3h-.4v.9h.5v-.3l-.2-.2M21.9 170.4l.4 .5M22 176.6l.5-.1v-.3l-.5-.1v.8M22.3 176.6l.2 .3M23.1 170v.9l-.5-.9v.9M23.2 163.9l-.5 .1v.2l.5 .3-.1 .3h-.4M23.3 164.8h.7M23.3 170.9h.7M23.4 176.1v.8l-.5-.8v.8"/>
<path d="M23.6 177h.7M24 164.8l.4-.9 .2 .9M24 170.9l.4-.9 .2 .9M24.1 164.5h.4M24.1 170.6h.4M24.4 176.9l.2-.8 .4 .8M24.5 176.7h.4M25.3 164.2h-.2l-.2 .1 .1 .5h.3M25.3 170.3h-.2l-.2 .1 .1 .5h.3M25.6 176.4l-.4 .1v.4h.4M25.6 164.2h.3M25.6 170.3h.3"/>
<path d="M25.6 163.9v.8l.3 .1M25.6 170v.8l.3 .1M25.8 176.4h.4M26 176.1v.8h.2M26.2 163.9v.9h.4M26.2 170v.9h.4M26.5 176.1v.8M26.5 176.5h.5M27 163.9l.4 .1-.1 .8h-.3l-.2-.3zM27 176.1v.8M27.1 170l.3 .2-.1 .7h-.3l-.2-.3v-.3zM27.4 176.1v.8"/>
<path d="M17.4 194h10.4l.8 .8-.8 .9h-10.4zM18 187.9h9.8l.8 .8-.8 .9h-9.8zM18 181.8h9.8l.8 .8-.8 .9h-9.8zM18.3 194.4v.9M18.7 183l.3-.8 .3 .8M18.8 182.9h.4M18.9 188.3v.9M18.9 188.7h.4M19.1 194.5l-.1-.1-.3 .2v.5l.3 .2 .2-.1v-.3h-.2M19.3 188.3v.9M19.6 182.2v.8h.4M19.6 189.3h.6"/>
<path d="M20.1 194.4v.9l-.5-.9v.9M20.1 182.2h.6M20.4 188.7h.4l.1-.2-.2-.2h-.3v.9l.5-.1v-.3l-.2-.1M20.4 182.2v.8M20.5 194.4v.9M20.8 194.4h.4M21 194.4v.9M21 182.6h.2M21.2 188.7h.4M21.3 182.2h-.3v.8h.3M21.6 194.4v.9M21.7 188.3h-.5v.9h.5"/>
<path d="M21.8 182.7h.3l.2-.3-.2-.2h-.3v.8M21.9 189.2l.4-.9 .2 .9M21.9 182.7l.4 .3M22 189h.4M22.2 194.4l.3 .2v.6l-.2 .1a.49 .49 0 0 1-.4-.4 .49 .49 0 0 1 .3-.5zM22.9 189.2v-.9l.2 .7 .3-.7v.9M23.1 182.2v.8l-.5-.8v.8M23.3 183.1h.7M23.4 194.4v.9l-.5-.9v.9M23.6 195.4h.7M23.6 189.3h.7M24 183l.4-.8 .2 .8"/>
<path d="M24.1 182.9h.4M24.4 195.3l.2-.9 .4 .9M24.4 189.2l.2-.9 .4 .9M24.5 195.1h.4M24.5 189h.4M25.3 182.5h-.3l-.1 .2 .1 .3h.3M25.6 194.7l-.4 .1v.4h.4M25.6 188.6l-.4 .1v.4h.4M25.6 182.5h.3M25.6 182.2v.8h.3M25.8 194.7h.4M25.8 188.6h.4"/>
<path d="M26 194.4v.8l.2 .1M26 188.3v.8l.2 .1M26.2 182.2v.8h.4M26.5 188.3v.9M26.5 194.4v.9M26.5 194.8h.5M26.5 188.7h.5M27 188.3v.9M27 194.4v.9M27.1 182.2l.3 .2v.6h-.5a.52 .52 0 0 1 .2-.8zM27.4 188.3v.9M27.4 194.4v.9"/>
</g>
<path d="M31.9 86.8l.3-.3v.9M31.9 87.4h.4M35.4 85.3v-.6l.3 .3 .1-.3h.3v.6M36.2 90v.5l-.5-.5h-.2v.5" fill="none" stroke="#bd0000" stroke-width=".21"/>
<g fill="none" stroke="#0c0c0c" stroke-width=".21">
<path d="M53 86.4v.7l.2 .2M53.4 86.9h.4v-.2l-.4 .1v.3l.2 .2 .2-.1M54.6 86.7h-.3l-.1 .2 .2 .4 .2-.1M54.6 86.4v.9M55.4 86.7h-.4l-.1 .2 .2 .4 .3-.1M55.5 87.4h.7M56.8 86.7h-.3l-.1 .2 .2 .4 .2-.1M57.1 86.8h.5v.5M57.1 86.4v.9M58 86.7h.3v.6M58.3 86.9l-.4 .1 .2 .3 .2-.1M58.8 86.8l.3-.1v.6"/>
<path d="M58.8 86.7v.6M59.3 87.4h.7M60.2 86.6l.2-.2v.9M60.2 87.3h.5"/>
</g>
<path d="M87.8 19.6h3.6v3.5h-3.6zM85.3 20.5h2.6M85.3 22.3h2.6M87.9 20.4h.9v.2h-.9zM87.9 22.2h.9v.1h-.9zM90.5 20.4h.9v.2h-.9zM90.5 22.2h.9v.1h-.9zM91.4 20.5h2.7M91.4 22.3h2.7" fill="none" stroke="#aaa" stroke-width=".21"/>
<path d="M86.4 19.6l.2-.2v.8M92.5 19.5h.5v.2l-.5 .5h.5M86.4 21.2h.5l-.3 .2 .3 .2v.2l-.2 .2-.3-.1M86.4 20.2h.5M92.7 21.1l-.2 .6h.5M92.9 21.4v.6" fill="none" stroke="#b2b2b2" stroke-width=".21"/>
<path d="M86.1 19l7 4.7M93.1 19l-7 4.7" fill="none" stroke="#e00" stroke-width=".34"/>
<g fill="none" stroke="#00a200" stroke-width=".21">
<path d="M16.4 19.6h15.8M29.5 17.9h2.7M40.9 17.9h2.5M40.9 19.6h2.5M210 17.9h.8M210.8 15.2v6.1M249.2 17h-.9v7h5.3M29.5 21.3h2.7M29.5 33.5h2.7M29.5 23.1h2.7M29.5 28.4h2.7M29.5 26.6h2.7"/>
<path d="M29.5 24.8h2.7M29.5 35.3h2.7M29.5 31.8h2.7M29.5 37.1h2.7M40.9 21.3h2.5M40.9 33.5h2.5M40.9 23.1h2.5M40.9 28.4h2.5M40.9 26.6h2.5M40.9 24.8h2.5M40.9 35.3h2.5M40.9 31.8h2.5"/>
<path d="M40.9 37.1h2.5M74 20.5h11.3v1.8M79.2 20.5v1.8M79.2 27.4v1.8M79.2 32.7v1.8M94.1 20.5v1.8h5.1M135 21.3v1.8M135 28.4v1.7M135 33.5v1.8M153.3 21.3v1.8M153.3 28.4v1.7M153.3 33.5v1.8"/>
<path d="M174.2 21.3h1.7M174.2 23.1h1.7M199.5 21.3h19.2M202.1 21.3v1.8M202.1 28.4v1.7M202.1 33.5v1.8M214.3 21.3v16.6h4.4M218.7 23.1h-1.8v4.3h1.8M245.7 21.3h2.6M245.7 37.9h2.6M249.2 33.5h-.9v7.9h5.3M258.7 24h7.9"/>
<path d="M34.7 48.3v1M36.5 48.3v15.8M38.3 48.3v1M71.4 48.3v1M73.1 48.3v15.8M74.8 48.3v1M106.3 49.3v.8M107.9 49.3v14.8M109.7 49.3v.8M203.9 49.3h5.2v98.4h.9M205.6 49.3v5.2h-2.6M214.3 49.3h1.8"/>
<path d="M214.3 55.4h1.8M234.4 48.3h7v31.5h3.5M234.4 54.5h6v27h4.5M258.7 41.4h7.9M28.6 62.3v1.8M28.6 69.3v1.7M28.6 74.5v1.8M36.5 69.3v5.2M36.5 79.8v4.4M65.3 62.3v1.8M65.3 69.3v1.7M65.3 74.5v1.8"/>
<path d="M73.1 69.3v5.2M73.1 79.8v4.4M100.2 62.3v1.8M100.2 69.3v1.7M100.2 74.5v1.8M107.9 69.3v5.2M107.9 79.8v4.4M214.3 61.5h1.8M214.3 79.8h1.8M214.3 73.7h1.8M214.3 67.6h1.8M234.4 72.8h3.4v14h7.1"/>
<path d="M234.4 66.7h4.4v18.3h6.1M234.4 60.6h5.2v22.6h5.3M234.4 78.9h2.6v9.6h7.9M257 64.1v3.5M257 72.8v1.7M269.2 79.8h5.3M24.3 87.6h.8M30.4 87.6h.8M36.5 82.4h5.2M36.5 91.1v1.8M60.9 87.6h.9M67 87.6h.9"/>
<path d="M73.1 91.1v1.8M73.1 82.4h5.2M95.8 87.6h.8M101.8 87.6h1M107.9 91.1v1.8M107.9 82.4h5.3M214.3 98h1.8M214.3 91.9h1.8M214.3 85.8h1.8M234.4 91.1h.8v.8h9.7M234.4 85h1.7v5.2h8.8M244.9 97.2h-8.8v6.1h-1.7"/>
<path d="M244.9 99h-7.9v10.4h-2.6M244.9 95.4h-9.7v1.8h-.8M269.2 81.5h5.3M28.6 103.3h3.6M28.6 115.5h3.6M28.6 109.4h3.6M47.8 115.5h30.5v20h5.3M47.8 103.3h34v28.8h1.8M47.8 109.4h32.3v24.4h3.5M95.8 119v1.7M157.6 105.9v1.8M157.6 112.9v2.6"/>
<path d="M159.4 105.9v1.8M159.4 112.9v2.6M191.7 105.9v1.8M191.7 112.9v1.7M191.7 118.1v1.8M214.3 104.1h1.8M214.3 110.2h1.8M214.3 116.4h1.8M244.9 107.7h-3.5v32.2h-7M244.9 105.9h-4.5v27.9h-6M244.9 104.1h-5.3v23.6h-5.2M244.9 100.7h-7.1v14.8h-3.4"/>
<path d="M244.9 102.4h-6.1v19.2h-4.4M269.2 104.1h9.6v8.8h-21.8M269.2 105.9h9.6M269.2 107.7h2.7M28.6 139.9h3.6M28.6 127.7h3.6M28.6 121.6h3.6M28.6 133.8h3.6M47.8 139.9h23.6v2.6h12.2M47.8 133.8h25.3v7h10.5M47.8 127.7h27v11.3h8.8M47.8 121.6h28.8v15.7h7"/>
<path d="M95.8 126v.8M107.9 133.8h5.3M107.9 132.1h5.3M175.9 132.9h7.1M175.9 139.9h5.3M189.9 132.9h.8M196 132.9h.8M214.3 122.5h1.8M214.3 128.6h1.8M214.3 134.7h1.8M257 135.5h7.9v1.8M258.7 135.5v1.8"/>
<path d="M28.6 152.1h3.6M28.6 158.2h3.6M28.6 146h3.6M83.6 147.7h-12.2v4.4h-23.6M83.6 149.5h-10.5v8.7h-25.3M83.6 144.3h-14v1.7h-21.8M83.6 153h-7v17.4h-28.8M83.6 151.2h-8.8v13.1h-27M83.6 154.8h-5.3v21.7h-30.5M83.6 156.5h-3.5v26.1h-32.3M83.6 158.2h-1.8v30.5h-34M83.6 159.9v34.9h-35.8"/>
<path d="M107.9 156.5v8.7h-12.1M175.9 153.8h20.9M175.9 155.6h20.9v1.7M175.9 152.1h5.3M175.9 148.7h5.3M175.9 150.4h5.3M175.9 141.6h5.3M175.9 145.1h5.3M210 149.5h-.9v3.5M214.3 140.8h1.8M254.4 144.3h4.3M258.7 142.5v4.4"/>
<path d="M264.9 142.5v4.4M264.9 144.3h3.5M28.6 176.5h3.6M28.6 164.3h3.6M28.6 170.4h3.6M158.5 178.3v3.5M28.6 188.7h3.6M28.6 194.8h3.6M28.6 182.6h3.6M103.6 182.6h4.3M115 182.6h1.7M157.6 189.6h3.5"/>
<path d="M157.6 191.3h3.5"/>
</g>
<g fill="none" stroke="#001dcd" stroke-width=".21">
<path d="M160.3 12.6h122.9v30.6h-122.9zM260.7 20.3h.5v.2l-.5 .5h.5M260.7 37.7h.5v.3l-.5 .5h.5M261.5 21l.3-.8 .3 .8M261.5 38.5l.3-.9 .3 .9M261.6 20.8h.4M261.6 38.2h.4M263.5 20.3l-.3-.1-.2 .2v.4l.3 .2 .2-.1M263.5 37.7l-.3-.1-.2 .2v.4l.3 .3 .2-.1M263.9 20.6l.3-.2 .2 .5-.4 .1zM263.9 37.9h.4l.1 .2-.2 .4-.3-.2zM264.7 20.5h.3v.5"/>
<path d="M264.7 38l.3-.1v.6M264.7 20.4v.6M264.7 37.9v.6M265.4 20.4h.3M265.4 37.9h.3M265.5 20.2v.7l.2 .1M265.5 37.6v.7l.2 .2M266 20.2v.1M266 37.6v.1M266 20.4v.6M266 37.9v.6M266.4 20.5h.3v.5"/>
<path d="M266.4 38l.3-.1v.6M266.4 20.4v.6M266.4 37.9v.6M267.2 20.4v.5l.1 .1 .3-.1M267.2 37.9v.4l.1 .2 .3-.1M267.6 20.4v.6M267.6 37.9v.6M267.9 20.6l.4-.2 .1 .5-.3 .1zM268 37.9h.3l.1 .2-.1 .4-.4-.2zM268.8 20.4v.5h.3M268.8 37.9v.5h.3M269.1 20.4v.6"/>
<path d="M269.1 37.9v.6M269.9 20.5h-.4v.2l.4 .1-.1 .2-.3-.1M269.9 37.9h-.4v.2l.4 .1-.1 .3-.3-.1M270.9 20.6l.2-.2 .2 .1v.4l-.2 .1zM271 37.9l.3 .1v.4l-.2 .1-.2-.2zM271.7 20.4v.5h.4M271.7 37.9v.5h.4M272.1 20.4v.6M272.1 37.9v.6M272.4 20.4h.3M272.4 37.9h.3M272.5 20.2v.7l.2 .1"/>
<path d="M272.5 37.6v.7l.2 .2M273 20.5l.3-.1 .1 .2-.1 .4-.3-.1M273 38.4l.3 .1 .1-.2-.1-.4h-.3v.8M273 20.4v.9M273.8 20.4v.5l.1 .1 .3-.1M273.8 37.9v.4l.1 .2 .3-.1M274.2 20.4v.6M274.2 37.9v.6M274.4 20.4h.4M274.4 37.9h.4M274.6 20.2v.7l.2 .1M274.6 37.6v.8l.2 .1"/>
<path d="M275.7 20.5l.3-.1 .1 .2v.4M275.7 38h.4v.5M275.7 20.4v.6M275.7 37.9v.6M276.1 20.6l.1-.2 .3 .1v.5M276.1 38l.4-.1v.6M276.9 20.5l.3-.1 .1 .2v.4M276.9 37.9l.4 .1v.5M277.3 20.7h-.4l.1 .3 .3-.1M277.3 38.1h-.4l.1 .4 .3-.1M277.6 20.4l.5 .6M277.6 37.9l.5 .6"/>
<path d="M278.1 20.4l-.5 .6M278.1 37.9l-.5 .6M13.8 98h109v99.4h-109zM161.3 115.4v-.9l.3 .6 .3-.6v.9M162.3 114.8h.3v.6M162.6 115l-.3 .1 .1 .3 .2-.1M163 114.8l.5 .6M163.5 114.8l-.5 .6M164.8 114.8h-.3l-.1 .2 .2 .4 .2-.1M165.2 114.9h.4v.4h-.4zM166 114.9l.4-.1v.6M166 114.8v.6"/>
<path d="M167 114.8h-.2l-.1 .2 .4 .2-.1 .2-.3-.1M167.5 114.8v.4l.1 .2 .3-.1M167.9 114.8v.6M168.3 114.9l.4-.1v.6M168.3 114.8v.6M168.7 114.9l.3-.1v.6M169.4 115.3h.4v-.5h-.4v.8M170.1 114.8h.3M170.3 114.5v.8l.1 .1M170.8 114.5v.1M170.8 114.8v.6M171.2 114.8l.3 .1v.4l-.1 .1-.3-.1z"/>
<path d="M172 114.9l.3-.1v.6M172 114.8v.6M173.8 114.5h-.4l-.1 .4h.5v.4h-.5M174.2 114.6h.5v.6l-.2 .2-.3-.1zM175.2 114.5a.43 .43 0 0 1 .3 .5 .43 .43 0 0 1-.3 .4l-.2-.3zM175.8 114.9h.5v.5M175.8 114.8v.6M176.3 114.9l.3-.1v.6M176.9 115.4l.3-.9 .3 .9M177 115.1h.4M259.7 114l.2-.9 .3 .9M259.8 113.7h.3"/>
<path d="M260.9 113.1v.9h-.4l-.1-.5 .2-.1h.3M261.3 115.4v-.9l.3 .6 .3-.6v.9M261.7 113.1v.9h-.3l-.1-.6h.4M262 113.4v.6M262.3 113.4l-.3 .1M262.3 114.9h.4v.5M262.5 113.7l.5-.1-.1-.2-.4 .1v.4l.5 .1M262.7 115l-.4 .1 .1 .3 .3-.1M263 114.8l.5 .6M263.5 114.8l-.5 .6M263.6 113.4h-.1l-.2 .1 .4 .4-.4 .1M264.3 113.4h-.1l-.2 .1 .4 .4-.4 .1"/>
<path d="M264.4 114.8l.3-.3v.9M264.4 115.4h.5M265.4 113.1v.1M265.4 113.4v.6M265.7 114.5l-.4 .2v.6l.3 .1 .2-.4h-.5M266.2 113.4h-.4l.1 .3h.3v.3h-.4M266.2 114.5a.43 .43 0 0 1 .4 .4 .43 .43 0 0 1-.3 .5l-.2-.2zM266.9 114.9h.4v.5M266.9 114.8v.6M267.3 113.1a.42 .42 0 0 1 .4 .4 .42 .42 0 0 1-.4 .5zM267.3 114.9h.4v.5M268 115.4l.3-.9 .3 .9"/>
<path d="M268 113.4l.4 .6M268 115.1h.5M268.4 113.4l-.4 .6M268.7 113.2l.4-.1 .1 .3-.6 .6h.6M269.6 113.4l.2-.3v.9M269.6 114h.5M249.2 156.5h32.2v18.2h-32.2zM250 157.1h.5M250.3 157.1v1M250.9 157.1l.4 .2v.6l-.2 .2-.3-.2v-.6zM251.7 157.1a.47 .47 0 0 1 .5 .5 .47 .47 0 0 1-.5 .5zM252.7 157.1a.47 .47 0 0 1 .5 .5 .47 .47 0 0 1-.5 .5l-.1-.2v-.6z"/>
<path d="M254.2 157.5h.3v.6M254.5 157.6l-.4 .2 .1 .3 .3-.1M254.9 157.6l.4-.1v.6M254.9 157.5v.6M256.1 157.5l-.4 .1v.4h.4M256.1 157.1v1M257 157.1h.6M257.3 157.1v1M258 157.1a.47 .47 0 0 1 .4 .5 .47 .47 0 0 1-.4 .5l-.2-.2v-.6zM259.2 157.2l-.2-.1-.3 .3v.4l.3 .3 .2-.1M259.6 157.1v1M259.6 157.6h.5"/>
<path d="M260.1 157.1v1M260.5 157.6h.4M260.9 157.1h-.4v1h.4M261.8 157.2a.4 .4 0 0 0-.5 .4 .4 .4 0 0 0 .5 .4M262.2 157.1v1M262.3 157.6l.4 .5M262.7 157.1l-.5 .5M263.1 158v.1M263.1 157.5v.1M86.4 170.8h.5v.6l-.1 .1a.47 .47 0 0 1-.4-.2 .47 .47 0 0 1 0-.5zM87.3 170.9v.5l.2 .1 .2-.1M87.7 170.9v.6"/>
<path d="M88 170.9h.3M88.1 170.7v.7l.2 .1M88.3 172.5h.3M88.6 171.4l.3 .1 .2-.1-.1-.5h-.4v.9M88.7 172h-.4v.9h.4M89.1 172.4l.4 .5M89.4 170.9v.5h.3M89.5 172.4l-.4 .5M89.7 170.9v.6M89.8 172.9h.4v-.5h-.4v.8M90.1 170.9h.3M90.2 170.7v.7l.2 .1"/>
<path d="M90.6 172.6l.4-.1-.1-.1h-.3v.5h.3M91 170.9h-.3v.3l.3 .1-.1 .2-.2-.1M91.7 172.4h-.4v.1v.4h.4M91.9 172.4h.4M92 171h.5v.5M92 170.7v.8M92.1 172v.9h.2M92.5 172.6l.5-.1v-.1l-.5 .1 .1 .4h.4M92.9 170.9h.3v.6M93.2 171.1l-.4 .2 .2 .2 .2-.1M93.6 170.9l.1 .6 .3-.6M93.7 172v.9h-.3v-.5h.3"/>
<path d="M94.2 171.2l.5-.1v-.2l-.5 .1v.4l.2 .1 .3-.1M95.2 172.4h-.4l-.1 .1 .1 .4h.4M95.5 172.5h.4l-.1 .4-.3-.1zM95.7 171.4h.4l-.1-.5h-.3v.9M96.3 172.5l.4-.1v.5M96.3 172.4v.5M96.5 170.9v.5h.4M96.9 170.9v.6M97.3 170.7v.7l.1 .1M97.4 172.4h-.3l.1 .2h.2v.3h-.3M97.7 170.7v.7l.2 .1M97.8 172.4l.1 .5 .3-.1"/>
<path d="M98.2 172.4v.5M98.4 167l.2-.9 .4 .9M98.5 166.7h.4M98.6 172.5l.4-.1v.5M98.6 172.4v.5M98.9 170.9v.5h.3M99 172.5h.4v.4M99.2 170.9v.6M99.6 166.1v.9h-.3l-.1-.6h.4M99.6 171.4l.3 .1 .2-.1-.1-.5h-.4v.9M99.8 172.9l.4-.1-.1-.4h-.3v.8M100.4 166.1v.9h-.3l-.1-.6h.4"/>
<path d="M100.4 172.4h.3M100.6 172v.9h.1M100.8 166.4v.6M101.1 166.4l-.3 .1M101.1 171.2l.4-.1-.1-.2h-.3v.5h.3M101.1 172v.1M101.1 172.4v.5M101.3 166.7l.4-.1-.1-.2h-.3v.6h.4M101.5 172.4h.3v.5h-.3zM101.8 171l.4-.1v.6M101.8 170.9v.6M102.3 172.5l.3-.1v.5"/>
<path d="M102.3 172.4v.5M102.4 166.4h-.2l-.2 .1 .4 .4-.4 .1M102.6 170.9l.4 .1v.5M103 171.1l-.4 .1 .1 .3 .3-.1M103.1 166.4h-.3l.1 .3h.2v.3h-.3M103.5 170.9h.3l.1 .2-.2 .4-.2-.1M103.5 170.7v.8M103.7 172v.9h.3v-.5h-.3M104.1 166.1v.1M104.1 166.4v.6M104.2 170.7l.1 .8M104.5 172.6l.4-.1-.1-.1h-.3v.5h.3"/>
<path d="M104.6 171.2l.5-.1-.1-.2h-.4v.5h.4M104.9 166.4h-.3v.3h.3v.3h-.3M105.2 172v.8l.2 .1M105.7 172.4h.4v.5h-.4zM105.8 170.9l-.4 .1v.4h.4M105.8 170.7v.8M106.1 166.1a.43 .43 0 0 1 .3 .5 .43 .43 0 0 1-.4 .4l-.1-.6zM106.4 172.4l.2 .5 .2-.4 .1 .4 .2-.5M106.7 166.4l.5 .6M106.8 170.9l.5 .1v.4h-.5M106.8 170.7v.8M107.2 166.4l-.5 .6"/>
<path d="M107.4 166.2h.5v.2l-.5 .6h.5M107.6 170.9l.2 .6M108 170.9l-.4 .9M108 172h.5l-.2 .4 .2 .1v.4l-.5-.1M108.5 166.1a.43 .43 0 0 1 .3 .5 .43 .43 0 0 1-.4 .4l-.1-.7zM109 172a.43 .43 0 0 1 .4 .5 .43 .43 0 0 1-.4 .4l-.1-.7zM109.4 170.9l-.4 .1v.4h.4M109.4 170.7v.8M109.7 171.2l.4-.1v-.2l-.4 .1v.4l.2 .1 .2-.1M109.7 172.5h.4v.4M109.7 172.4v.5M110.1 172.5l.4-.1v.5"/>
<path d="M110.4 170.9h.3M110.7 170.7l-.2 .1v.7M110.7 172.9l.4-.9 .2 .9M110.8 172.6h.4M111 170.9l.4 .1v.5M111.4 171.1l-.4 .1 .1 .3 .3-.1M111.8 170.9v.5h.4M112.2 170.9v.6M112.6 170.7l.1 .8M112.9 170.9h.4M113 170.7v.7l.3 .1"/>
</g>
<g fill="none" stroke="#001dcd" stroke-width=".34">
<path d="M161.5 14.2l.9-.1v-.6l-.2-.2h-.7v1.7M163.3 14a.52 .52 0 0 1 .7 .2v.7l-.6 .1-.2-.3zM164.6 13.9l.4 1.1 .3-.8 .3 .8 .3-1.1M166.5 14.4l.8-.1v-.3l-.6-.1-.2 .2 .1 .8h.7M168 13.9v1.1M168.5 13.9l-.5 .3M171 14l-.4-.1-.3 .2 .1 .2 .6 .2v.4h-.7M171.8 13.9l.1 1 .4 .1 .3-.1M172.6 13.9v1.1M173.3 14a.6 .6 0 0 1 .9 .2v.5l-.2 .2h-.7M173.3 13.9v1.7M175 14l.4-.1 .3 .3v.5l-.1 .2h-.6"/>
<path d="M175 13.9v1.7M176.5 13.3v1.5l.2 .2M177.3 13.3v.2M177.3 13.9v1.1M178.1 14.4l.8-.1v-.3l-.6-.1-.2 .2 .1 .8h.7M180.2 14l-.4-.1-.2 .2 .2 .3 .4 .1v.4h-.6M94.8 98.8v1.7M96.2 99.4h-.4l-.3 .1 .1 .3 .6 .1v.5h-.7M97.1 99.4a.52 .52 0 0 1 .7 .2l-.1 .7-.5 .2-.2-.4zM98.6 98.8v1.4l.2 .3M99.4 99.4h.5l.3 .1v1M100.2 99.7l-.8 .2v.5h.8"/>
<path d="M100.8 99.4h.7M101 98.8v1.4l.5 .3M101.9 99.9l.8-.2v-.3h-.6l-.2 .1 .1 .9h.7M104.2 99.4h-.4l-.4 .2v.5l.2 .3h.6M104.2 98.8v1.7M106.4 98.8v1.7M106.4 99.5h.9M107.3 98.8v1.7M108.2 99.4h.6v1.1M108.8 99.7l-.5 .1a.35 .35 0 0 0-.2 .3 .35 .35 0 0 0 .2 .4l.5-.1M109.7 99.4v1.1M110.2 99.4l-.5 .2"/>
<path d="M110.8 99.5l.2-.1 .5 .1v1M110.8 99.4v1.1M112.2 99.9l.9-.2-.1-.3h-.5l-.3 .1 .1 .9h.7M114.3 99.4h-.4l-.2 .1v.3l.6 .1v.5h-.6M115.8 99.4h-.4l-.3 .1 .1 .3 .6 .1v.5h-.7M117.9 98.8v1.7M119.9 98.7l-1.5 2.2M120.6 98.8a.59 .59 0 0 1 .6 0 .59 .59 0 0 1 .3 .6v.5a.59 .59 0 0 1-.3 .5 .59 .59 0 0 1-.6 0l-.2-.5z"/>
</g>
<g fill="none" stroke="#007170" stroke-width=".21">
<path d="M176.3 18.6h.3l.2-.1-.2-.4h-.3v.9M177.3 18.1l.3 .2v.6l-.1 .1-.4-.1v-.6zM178 18.1l.1 .9 .2-.6 .2 .6 .2-.9M179.1 18.5h.2M179.4 18.1h-.3v.9h.3M179.8 18.6h.4l.1-.1-.1-.4h-.4v.9M180 18.6l.3 .4M181.4 18.1v.9M182.3 18.1v.9l-.5-.9v.9M182.7 18.6h.3l.2-.1-.2-.4h-.3v.9M183.6 18.1v.9h.1l.4-.1v-.8M184.3 18.1h.5"/>
<path d="M184.6 18.1v.9M219.4 18.1h-.5v.4h.4l.2 .4-.2 .1h-.4M219.7 18.1l.3 .9 .2-.9M220.3 19.1h.7M221.7 18.2l-.4-.1-.2 .2 .1 .2 .5 .2v.3h-.6M222 19v-.9l.3 .7 .3-.7v.9M223 18.6l.5-.1v-.3l-.5-.1v.9M224.4 18.2l-.4-.1-.1 .2 .5 .6-.2 .1h-.3M224.5 19.1h.7M225.4 18.4l.2-.3v.9M225.4 19h.5M218.9 34.7h.6l-.4 .3 .4 .2-.1 .4-.5-.1"/>
<path d="M219.7 34.7l.3 .9 .2-.9M220.5 34.7h.5l-.3 .3 .3 .1v.4h-.5M221.1 35.6h.7M222.5 34.8h-.5v.2l.5 .3-.1 .3h-.4M222.8 35.6v-.9l.4 .6 .2-.6v.9M223.9 35.1h.4l.1-.2-.2-.2h-.3v.9M225.2 34.8h-.5v.2l.5 .3-.1 .3h-.4M216.3 51h.4M216.3 57.1h.4M216.7 50.5h-.4v.9M216.7 56.6h-.4v.9M216.8 46.1h-.5v.3l.5 .2-.1 .3h-.4"/>
<path d="M216.8 52.2h-.5v.3l.5 .2-.1 .3h-.4M216.8 58.3h-.5v.3l.5 .2-.1 .3h-.4M217.1 46.3l.1 .6 .2-.4 .2 .4 .2-.6M217.1 52.4l.1 .6 .2-.4 .2 .4 .2-.6M217.1 58.6l.1 .5 .2-.4 .2 .4 .2-.5M217.1 50.5v.1M217.1 56.6v.1M217.1 50.9v.5M217.1 57v.5M217.5 50.5v.8l.2 .1M217.5 56.6v.8l.2 .1M217.9 51.1l.4-.1v-.1h-.4v.5h.4"/>
<path d="M217.9 57.2l.4-.1v-.1h-.4v.5h.4M218.1 46.1h.1M218.1 52.1v.1M218.1 58.2v.1M218.1 46.3v.6M218.1 52.4v.6M218.1 58.6v.5M218.3 46.3h.4M218.3 52.4h.4M218.3 58.6h.4M218.5 46.1v.8h.2M218.5 52.1v.9h.2"/>
<path d="M218.5 58.2v.9h.2M218.7 51.3v.1M218.7 50.9v.1M218.7 57.4v.1M218.7 57v.1M219.4 46.4l-.3-.1-.2 .2 .1 .4h.4M219.4 52.5l-.3-.1-.2 .2 .1 .4h.4M219.4 58.6l-.5 .1 .1 .4h.4M219.8 46.4l.2-.1 .1 .2v.4M219.8 52.5l.2-.1 .1 .2v.4M219.8 58.7h.3v.4M219.8 46.1v.8"/>
<path d="M219.8 52.1v.9M219.8 58.2v.9M220.2 50.6h-.4v.3l.4 .1-.1 .4h-.3M220.2 56.7h-.4v.3l.4 .2-.1 .3h-.3M220.6 46.4h.3v.5h-.3l-.1-.2 .1-.1h.3M220.6 52.5h.3v.5h-.3l-.1-.2 .4-.1M220.6 58.6h.3v.5h-.3l-.1-.2 .1-.1h.3M220.6 50.9l.1 .5 .2-.4 .2 .4 .1-.5M220.6 57l.1 .5 .2-.4 .2 .4 .1-.5M221.3 46.1v.8h.4v-.5h-.4M221.3 52.1v.9h.4v-.5h-.4M221.3 58.2v.9h.4v-.4l-.4-.1"/>
<path d="M221.6 50.5v.1M221.6 56.6v.1M221.6 50.9v.5M221.6 57v.5M221.8 50.9h.4M221.8 57h.4M222 50.5v.9h.2M222 56.6v.9h.2M222.1 46.1v.7l.1 .1M222.1 52.1v.8l.1 .1M222.1 58.2v.8l.1 .1M222.5 46.6h.4l-.1-.3-.3 .2v.3l.4 .1"/>
<path d="M222.5 52.7h.4l-.1-.3-.3 .2v.3l.4 .1M222.5 58.8h.4v-.2l-.4 .1v.3l.4 .1M222.8 50.9l-.4 .1 .1 .4h.3M222.8 57l-.4 .1 .1 .4h.3M223.2 51l.3-.1 .1 .5M223.2 57.1l.3-.1 .1 .5M223.2 50.5v.9M223.2 56.6v.9M224 46.5h.4v-.4h-.4v.8M224 52.6h.4v-.4l-.4-.1v.9M224 58.7h.4v-.4l-.4-.1v.9M224 50.9l.4 .1v.4h-.4l-.1-.2 .2-.2h.3"/>
<path d="M224 57l.4 .1v.4h-.4l-.1-.2 .5-.2M224.2 46.5l.2 .4M224.2 52.6l.2 .4M224.2 58.7l.2 .4M224.8 46.6h.4l-.1-.3-.3 .2v.3l.4 .1M224.8 52.7h.4l-.1-.3-.3 .2v.3l.4 .1M224.8 58.8h.4v-.2l-.4 .1 .1 .4h.3M224.8 50.5v.9h.3l.1-.4-.4-.1M224.8 56.6v.9h.3v-.5h-.3M225.5 50.5v.8l.2 .1M225.5 56.6v.8l.2 .1M225.9 46.4l-.2-.1-.2 .2 .5 .3-.5 .1"/>
<path d="M225.9 52.5l-.2-.1-.2 .2 .5 .3-.5 .1M225.9 58.6l-.4 .1 .5 .3-.5 .1M226 51.1l.4-.1-.1-.1-.3 .1v.3l.3 .1M226 57.2l.4-.1-.1-.1-.3 .1v.3l.3 .1M226.3 46.1h.1M226.3 52.1v.1M226.3 58.2v.1M226.3 46.3v.6M226.3 52.4v.6M226.3 58.6v.5M226.6 51.5h.6M226.6 57.6h.6"/>
<path d="M227 46.4l-.2-.1-.2 .2 .5 .3-.5 .1M227 52.5l-.2-.1-.2 .2 .5 .3-.5 .1M227 58.6l-.4 .1 .5 .3-.5 .1M227.3 46.3h.4M227.3 52.4h.4M227.3 58.6h.4M227.4 46.1v.7l.3 .1M227.4 52.1v.8l.3 .1M227.4 58.2v.8l.3 .1M227.4 51h.5v-.4l-.5-.1v.9M227.4 57.1h.5v-.4l-.5-.1v.9M227.7 51l.2 .4"/>
<path d="M227.7 57.1l.2 .4M227.9 46.4h.4v.5l-.4-.1zM227.9 52.5h.4v.5l-.4-.1zM227.9 58.7h.4v.4l-.4-.1zM228.3 51.1l.4-.1-.1-.1-.3 .1v.3l.3 .1M228.3 57.2l.4-.1-.1-.1-.3 .1v.3l.3 .1M228.7 46.3v.6M228.7 52.4v.6M228.7 58.6v.5M228.9 46.3l-.2 .2M228.9 52.4l-.2 .2M228.9 58.6l-.2 .1"/>
<path d="M229.4 50.9h-.4l.1 .2h.3v.3h-.4M229.4 57h-.4v.2l.4 .1v.2h-.4M229.8 51.3v.1M229.8 57.4v.1M229.9 52.4l.2-.3v.9M229.9 58.3h.5v.4l-.5 .4h.5M229.9 53h.5M229.9 46.1h.4l.1 .1-.1 .6a.39 .39 0 0 1-.4-.2 .39 .39 0 0 1 0-.5zM230.2 50.5v.9M230.2 56.6v.9M230.3 51l.2 .4M230.3 57.2l.2 .3"/>
<path d="M230.5 50.9l-.3 .2M230.5 57l-.3 .3M230.9 50.5v.1M230.9 56.6v.1M230.9 50.9v.5M230.9 57v.5M231.6 50.9l-.4 .1 .1 .4h.3M231.6 57h-.3l-.1 .1 .1 .4h.3M232.1 50.9h.3v.5h-.3l-.1-.2 .2-.2h.2M232.1 57h.3v.5h-.3l-.1-.2 .4-.2M233.2 50.5v.9h-.4l-.1-.4 .5-.1M233.2 56.6v.9h-.4v-.5h.4"/>
<path d="M233.4 51.5h.7M233.4 57.6h.7M234.6 50.9h-.3l.1 .2h.2v.3h-.3M234.6 57h-.3v.2l.3 .1v.2h-.3M235.4 50.9l-.5 .1 .1 .4h.4M235.4 57l-.5 .1 .1 .4h.4M235.7 51l.3-.1 .1 .5M235.7 57.1l.3-.1 .1 .5M235.7 50.5v.9M235.7 56.6v.9M216.3 63.2h.4M216.3 69.3h.4"/>
<path d="M216.3 75.3h.4M216.7 62.7h-.4v1M216.7 68.8h-.4v1M216.7 74.9h-.4v1M216.8 64.4h-.5v.3l.5 .3-.1 .2h-.4M216.8 70.5h-.5v.3l.5 .3-.1 .3-.4-.1M216.8 76.6h-.5v.3l.5 .3-.1 .3-.4-.1M217.1 64.7l.1 .5 .2-.4 .2 .4 .2-.5M217.1 70.8l.1 .6 .2-.5 .2 .5 .2-.6M217.1 76.9l.1 .6 .2-.5 .2 .5 .2-.6M217.1 62.7v.1M217.1 68.8v.1"/>
<path d="M217.1 74.9v.1M217.1 63.1v.6M217.1 69.2v.6M217.1 75.3v.6M217.5 62.7v.8l.2 .2M217.5 68.8v.8l.2 .2M217.5 74.9v.8l.2 .2M217.9 63.3l.4-.1v-.1h-.4v.5h.4M217.9 69.4l.4-.1v-.1h-.4v.5h.4M217.9 75.5l.4-.1v-.1h-.4v.5h.4M218.1 64.3v.1M218.1 70.4v.1"/>
<path d="M218.1 76.5v.1M218.1 64.7v.5M218.1 70.8v.6M218.1 76.9v.6M218.3 64.7h.4M218.3 70.8h.4M218.3 76.9h.4M218.5 64.3v.9h.2M218.5 70.4v.9l.2 .1M218.5 76.5v.9l.2 .1M218.7 63.6v.1M218.7 63.1v.1"/>
<path d="M218.7 69.7v.1M218.7 69.2v.1M218.7 75.8v.1M218.7 75.3h.1M219.4 64.7h-.4l-.1 .1 .1 .4h.4M219.4 70.8h-.4l-.1 .1 .2 .5 .3-.1M219.4 76.9h-.4l-.1 .1 .2 .5 .3-.1M219.8 64.8h.3v.4M219.8 70.9h.3v.5M219.8 77h.3v.5M219.8 64.3v.9M219.8 70.4v1"/>
<path d="M219.8 76.5v1M220.2 62.8h-.4v.3l.4 .2v.3h-.4M220.2 68.9h-.4v.3l.4 .2v.3h-.4M220.2 75h-.4v.3l.4 .2v.3h-.4M220.6 64.7h.3v.5h-.3v-.3l.3-.1M220.6 70.8h.3v.6M220.6 76.9h.3v.6M220.6 63.1l.1 .6 .2-.5 .2 .5 .1-.6M220.6 69.2l.1 .6 .2-.5 .2 .5 .1-.6M220.6 75.3l.1 .6 .2-.5 .2 .5 .1-.6M220.9 70.9l-.4 .2 .1 .3 .3-.1M220.9 77l-.4 .2 .1 .3 .3-.1"/>
<path d="M221.3 64.3v.9h.4v-.4l-.4-.1M221.3 70.8l.4 .1v.4h-.4M221.3 76.9l.4 .1v.4h-.4M221.3 70.4v1M221.3 76.5v1M221.6 62.7v.1M221.6 68.8v.1M221.6 74.9v.1M221.6 63.1v.6M221.6 69.2v.6M221.6 75.3v.6M221.8 63.1h.4"/>
<path d="M221.8 69.2h.4M221.8 75.3h.4M222 62.7v.9l.2 .1M222 68.8v.9l.2 .1M222 74.9v.9l.2 .1M222.1 64.3v.8l.1 .1M222.1 70.4v.8l.1 .2M222.1 76.5v.8l.1 .2M222.5 64.9l.4-.1v-.1l-.4 .1v.3l.4 .1M222.5 71l.4-.1v-.1l-.4 .1v.3l.2 .2 .2-.1M222.5 77.1l.4-.1v-.1l-.4 .1v.3l.2 .2 .2-.1M222.8 63.1l-.4 .1v.4h.4"/>
<path d="M222.8 69.2l-.4 .1v.4h.4M222.8 75.3h-.4v.5h.4M223.2 63.2h.4v.5M223.2 69.3h.4v.5M223.2 75.3h.4v.6M223.2 62.7v1M223.2 68.8v1M223.2 74.9v1M224 64.8h.4v-.4l-.4-.1v.9M224 70.9h.4v-.4l-.4-.1v1M224 77h.4v-.4l-.4-.1v1M224 63.1l.4 .1v.5"/>
<path d="M224 69.2l.4 .1v.5M224 75.3h.4v.6M224.2 64.8l.2 .4M224.2 70.9l.2 .5M224.2 77l.2 .5M224.4 63.2l-.5 .2 .2 .3 .3-.1M224.4 69.3l-.5 .2 .2 .3 .3-.1M224.4 75.4l-.5 .2 .2 .3 .3-.1M224.8 64.9l.4-.1v-.1l-.4 .1 .1 .4h.3M224.8 71l.4-.1v-.1l-.4 .1v.3l.2 .2 .2-.1M224.8 77.1l.4-.1v-.1l-.4 .1v.3l.2 .2 .2-.1M224.8 63.1h.3l.1 .1-.2 .5-.2-.1"/>
<path d="M224.8 69.2h.3l.1 .1-.2 .5-.2-.1M224.8 75.3h.3l.1 .1-.2 .5-.2-.1M224.8 62.7v1M224.8 68.8v1M224.8 74.9v1M225.5 62.7v.8l.2 .2M225.5 68.8v.8l.2 .2M225.5 74.9v.8l.2 .2M225.9 64.7h-.3l-.1 .1 .5 .3-.5 .1M225.9 70.8h-.3l-.1 .1 .5 .3-.2 .2-.3-.1M225.9 76.9h-.3l-.1 .1 .5 .3-.2 .2-.3-.1M226 63.3l.4-.1-.1-.1-.3 .1v.3l.1 .2 .2-.1"/>
<path d="M226 69.4l.4-.1-.1-.1-.3 .1v.3l.1 .2 .2-.1M226 75.5l.4-.1-.1-.1h-.3v.4l.1 .2 .2-.1M226.3 64.3v.1M226.3 70.4v.1M226.3 76.5v.1M226.3 64.7v.5M226.3 70.8v.6M226.3 76.9v.6M226.6 63.7h.6M226.6 69.8h.6M226.6 75.9h.6M227 64.7h-.3l-.1 .1 .5 .3-.5 .1"/>
<path d="M227 70.8h-.3l-.1 .1 .5 .3-.2 .2-.3-.1M227 76.9h-.3l-.1 .1 .5 .3-.2 .2-.3-.1M227.3 64.7h.4M227.3 70.8h.4M227.3 76.9h.4M227.4 64.3v.8l.3 .1M227.4 70.4v.8l.3 .2M227.4 76.5v.8l.3 .2M227.4 63.2h.5v-.4l-.5-.1v1M227.4 69.3h.5v-.4l-.5-.1v1M227.4 75.4l.5-.1v-.3l-.5-.1v1M227.7 63.2l.2 .5"/>
<path d="M227.7 69.3l.2 .5M227.7 75.4l.2 .5M227.9 64.8h.4v.4l-.4-.1zM227.9 70.9l.4-.1v.5h-.4zM227.9 77l.4-.1v.5h-.4zM228.3 63.3l.4-.1-.1-.1-.3 .1v.3l.1 .2 .2-.1M228.3 69.4l.4-.1-.1-.1-.3 .1v.3l.1 .2 .2-.1M228.3 75.5l.4-.1-.1-.1h-.3v.4l.1 .2 .2-.1M228.7 64.7v.5M228.7 70.8v.6M228.7 76.9v.6M228.9 64.7l-.2 .1"/>
<path d="M228.9 70.8l-.2 .1M228.9 76.9l-.2 .1M229.4 63.1h-.4v.2l.4 .1-.1 .3-.3-.1M229.4 69.2h-.4v.2h.3l.1 .3h-.4M229.4 75.3h-.4v.2h.3l.1 .3h-.4M229.8 63.6v.1M229.8 69.7v.1M229.8 75.8v.1M229.9 64.3h.5l-.3 .4 .3 .1v.3h-.5M230.1 70.4l-.2 .6h.6M230.2 62.7v1M230.2 68.8v1"/>
<path d="M230.2 74.9v1M230.3 70.8v.6M230.3 63.3l.2 .4M230.3 69.4l.2 .4M230.3 75.5l.2 .4M230.4 76.5h-.5v.5h.5v.4h-.5M230.5 63.1l-.3 .3M230.5 69.2l-.3 .3M230.5 75.3l-.3 .3M230.9 62.7v.1M230.9 68.8v.1M230.9 74.9v.1"/>
<path d="M230.9 63.1v.6M230.9 69.2v.6M230.9 75.3v.6M231.6 63.1h-.3l-.1 .1 .2 .5 .2-.1M231.6 69.2h-.3l-.1 .1 .2 .5 .2-.1M231.6 75.3h-.3l-.1 .1 .2 .5 .2-.1M232.1 63.1h.3v.6M232.1 69.2h.3v.6M232.1 75.3h.3v.6M232.4 63.2l-.4 .2 .2 .3 .2-.1M232.4 69.3l-.4 .2 .2 .3 .2-.1M232.4 75.4l-.4 .2 .2 .3 .2-.1"/>
<path d="M233.2 63.1h-.4l-.1 .1 .2 .5 .3-.1M233.2 69.2h-.4l-.1 .1 .2 .5 .3-.1M233.2 75.3h-.4l-.1 .1 .2 .5 .3-.1M233.2 62.7v1M233.2 68.8v1M233.2 74.9v1M233.4 63.7h.7M233.4 69.8h.7M233.4 75.9h.7M234.6 63.1h-.3v.2l.3 .1-.1 .3-.2-.1M234.6 69.2h-.3v.2h.2l.1 .3h-.3M234.6 75.3h-.3v.2h.2l.1 .3h-.3"/>
<path d="M235.4 63.1l-.5 .1v.4h.5M235.4 69.2l-.5 .1v.4h.5M235.4 75.3h-.5v.5h.5M235.7 63.2h.4v.5M235.7 69.3h.4v.5M235.7 75.3h.4v.6M235.7 62.7v1M235.7 68.8v1M235.7 74.9v1M216.3 99.8h.4M216.3 93.6h.4M216.3 87.5h.4"/>
<path d="M216.3 81.4h.4M216.7 99.4h-.4v.8M216.7 93.3h-.4v.8M216.7 87.2h-.4v.8M216.7 81h-.4v1M216.8 94.9l-.5 .1v.2l.4 .1 .1 .3-.1 .2-.4-.1M216.8 88.8h-.5v.3l.5 .3-.1 .3-.4-.1M216.8 82.7h-.5v.3l.5 .3-.1 .3-.4-.1M217.1 95.2l.1 .6 .2-.5 .2 .5 .2-.6M217.1 89.1l.1 .6 .2-.5 .2 .5 .2-.6M217.1 83l.1 .6 .2-.5 .2 .5 .2-.6M217.1 99.4v.1"/>
<path d="M217.1 93.3v.1M217.1 87.2v.1M217.1 81v.1M217.1 81.4v.6M217.1 87.5v.5M217.1 93.6v.5M217.1 99.6v.6M217.5 99.4v.7l.2 .1M217.5 93.3v.7l.2 .1M217.5 87.2v.7l.2 .1M217.5 81v.8l.2 .2M217.9 100l.4-.1-.1-.3-.3 .1v.5h.4"/>
<path d="M217.9 93.8l.4-.2h-.4v.5h.4M217.9 87.7l.4-.1v-.1h-.4v.5h.4M217.9 81.6l.4-.1v-.1h-.4v.5h.4M218.1 94.9v.1M218.1 88.7v.1M218.1 82.6v.1M218.1 83v.6M218.1 89.1v.6M218.1 95.2v.6M218.3 95.2h.4M218.3 89.1h.4M218.3 83h.4"/>
<path d="M218.5 94.9v.8l.2 .1M218.5 88.7v.9l.2 .1M218.5 82.6v.9l.2 .1M218.7 99.7v.1M218.7 94.1h.1M218.7 93.6h.1M218.7 88h.1M218.7 87.5h.1M218.7 81.9v.1M218.7 81.4h.1M219.4 95.2h-.4l-.1 .1 .2 .5 .3-.1M219.4 89.1h-.4l-.1 .1 .2 .5 .3-.1"/>
<path d="M219.4 83h-.4l-.1 .1 .2 .5 .3-.1M219.8 95.2h.3v.6M219.8 89.1h.3v.6M219.8 83.1h.3v.5M219.8 82.6v1M219.8 88.7v1M219.8 94.9v.9M220.2 99.4l-.4 .1v.2l.4 .2v.3h-.4M220.2 93.3l-.4 .1v.2l.4 .2v.3h-.4M220.2 87.2l-.4 .1v.2l.4 .2v.3h-.4M220.2 81.1h-.4v.3l.4 .2v.3h-.4M220.6 95.2h.3v.6"/>
<path d="M220.6 89.1h.3v.6M220.6 83h.3v.6M220.6 99.6l.1 .6 .2-.4 .2 .4 .1-.6M220.6 93.6l.1 .5 .2-.4 .2 .4 .1-.5M220.6 87.5l.1 .5 .2-.4 .2 .4 .1-.5M220.6 81.4l.1 .6 .2-.5 .2 .5 .1-.6M220.9 95.3l-.4 .2 .1 .3 .3-.1M220.9 89.2l-.4 .2 .1 .3 .3-.1M220.9 83.1l-.4 .2 .1 .3 .3-.1M221.3 95.2h.4v.5h-.4M221.3 89.1h.4v.5h-.4M221.3 83l.4 .1v.4h-.4"/>
<path d="M221.3 82.6v1M221.3 88.7v1M221.3 94.9v.9M221.6 99.4v.1M221.6 93.3v.1M221.6 87.2v.1M221.6 81v.1M221.6 81.4v.6M221.6 87.5v.5M221.6 93.6v.5M221.6 99.6v.6M221.8 99.6h.4"/>
<path d="M221.8 93.6h.4M221.8 87.5h.4M221.8 81.4h.4M222 99.4v.8h.2M222 93.3v.8h.2M222 87.2v.8h.2M222 81v.9l.2 .1M222.1 94.9v.7l.1 .2M222.1 88.7v.8l.1 .2M222.1 82.6v.8l.1 .2M222.5 95.4l.4-.1v-.1h-.4v.4l.2 .2 .2-.1M222.5 89.3l.4-.1v-.1h-.4v.4l.2 .2 .2-.1"/>
<path d="M222.5 83.2l.4-.1v-.1l-.4 .1v.3l.2 .2 .2-.1M222.8 99.7h-.4v.5h.4M222.8 93.6h-.4v.5h.4M222.8 87.5h-.4v.5h.4M222.8 81.4h-.4v.5h.4M223.2 99.7l.2-.1 .2 .2v.4M223.2 93.6h.4v.5M223.2 87.5h.4v.5M223.2 81.4h.4v.6M223.2 81v1M223.2 87.2v.8M223.2 93.3v.8"/>
<path d="M223.2 99.4v.8M224 95.3l.4-.1v-.2l-.4-.1v.9M224 89.2l.4-.1v-.3l-.4-.1v1M224 83.1h.4v-.4l-.4-.1v1M224 99.7l.2-.1 .2 .2v.4M224 93.6h.4v.5M224 87.5h.4v.5M224 81.4h.4v.6M224.2 95.3l.2 .5M224.2 89.2l.2 .5M224.2 83.1l.2 .5M224.4 99.9l-.5 .2 .2 .1h.3"/>
<path d="M224.4 93.7l-.5 .2 .2 .2h.3M224.4 87.6l-.5 .2 .2 .2h.3M224.4 81.5l-.5 .2 .2 .3 .3-.1M224.8 95.4l.4-.1v-.1h-.4v.4l.2 .2 .2-.1M224.8 89.3l.4-.1v-.1h-.4v.4l.2 .2 .2-.1M224.8 83.2l.4-.1v-.1l-.4 .1v.3l.2 .2 .2-.1M224.8 99.7l.2-.1 .2 .2-.2 .4h-.2M224.8 93.6h.2l.2 .1-.2 .4h-.2M224.8 87.5h.3l.1 .1-.2 .4h-.2M224.8 81.4h.3l.1 .1-.2 .5-.2-.1M224.8 81v1M224.8 87.2v.8"/>
<path d="M224.8 93.3v.8M224.8 99.4v.8M225.5 99.4v.7l.2 .1M225.5 93.3v.7l.2 .1M225.5 87.2v.7l.2 .1M225.5 81v.8l.2 .2M225.9 95.2h-.3l-.1 .1 .5 .3-.2 .2-.3-.1M225.9 89.1h-.3l-.1 .1 .5 .3-.2 .2-.3-.1M225.9 83h-.3l-.1 .1 .5 .3-.2 .2-.3-.1M226 100l.4-.1-.1-.3-.3 .2v.3l.1 .1h.2M226 93.8l.4-.1-.1-.1h-.3v.4l.1 .1h.2M226 87.7l.4-.1-.1-.1h-.3v.4l.1 .1h.2"/>
<path d="M226 81.6l.4-.1-.1-.1h-.3v.4l.1 .2 .2-.1M226.3 94.9v.1M226.3 88.7v.1M226.3 82.6v.1M226.3 83v.6M226.3 89.1v.6M226.3 95.2v.6M226.6 94.2h.6M226.6 88.1h.6M226.6 82h.6M227 95.2h-.3l-.1 .1 .5 .3-.2 .2-.3-.1M227 89.1h-.3l-.1 .1 .5 .3-.2 .2-.3-.1"/>
<path d="M227 83h-.3l-.1 .1 .5 .3-.2 .2-.3-.1M227.3 95.2h.4M227.3 89.1h.4M227.3 83h.4M227.4 94.9v.7l.3 .2M227.4 88.7v.8l.3 .2M227.4 82.6v.8l.3 .2M227.4 99.8h.4l.1-.3-.5-.1v.8M227.4 93.7l.5-.1v-.2l-.5-.1v.8M227.4 87.6l.5-.1v-.2l-.5-.1v.8M227.4 81.5l.5-.1v-.3l-.5-.1v1M227.7 99.8l.2 .4"/>
<path d="M227.7 93.7l.2 .4M227.7 87.6l.2 .4M227.7 81.5l.2 .5M227.9 95.2h.4v.5h-.4zM227.9 89.1h.4v.5h-.4zM227.9 83.1l.4-.1v.5h-.4zM228.3 100l.4-.1-.2-.3-.2 .2v.3l.1 .1h.2M228.3 93.8l.4-.2h-.4v.4l.1 .1h.2M228.3 87.7l.4-.1-.1-.1h-.3v.4l.1 .1h.2M228.3 81.6l.4-.1-.1-.1h-.3v.4l.1 .2 .2-.1M228.7 83v.6M228.7 89.1v.6"/>
<path d="M228.7 95.2v.6M228.9 95.2l-.2 .1M228.9 89.1l-.2 .1M228.9 83l-.2 .1M229.4 99.7h-.4l.1 .3h.3l-.1 .2h-.3M229.4 93.6h-.4v.2l.4 .1-.1 .2h-.3M229.4 87.5h-.4v.2l.4 .1-.1 .2h-.3M229.4 81.4h-.4v.2l.4 .1-.1 .3-.3-.1M229.8 94.1h.1M229.8 88h.1M229.8 81.9v.1M229.9 95.1l.2-.2v.9"/>
<path d="M229.9 88.7h.6l-.5 1M229.9 95.8h.5M230.2 81v1M230.2 87.2v.8M230.2 93.3v.8M230.2 99.4v.8M230.3 82.6l-.3 .1-.1 .7 .1 .2 .4-.1v-.4l-.4-.1-.1 .1M230.3 99.9l.2 .3M230.3 93.8l.2 .3M230.3 87.7l.2 .3M230.3 81.6l.2 .4M230.5 99.6l-.3 .4"/>
<path d="M230.5 93.6l-.3 .3M230.5 87.5l-.3 .3M230.5 81.4l-.3 .3M230.7 95l.2-.1a.43 .43 0 0 1 .3 .4 .43 .43 0 0 1-.3 .5l-.2-.2zM230.9 99.4v.1M230.9 93.3v.1M230.9 87.2v.1M230.9 81v.1M230.9 81.4v.6M230.9 87.5v.5M230.9 93.6v.5M230.9 99.6v.6"/>
<path d="M231.6 99.7l-.2-.1-.2 .2 .2 .4h.2M231.6 93.6h-.2l-.2 .1 .2 .4h.2M231.6 87.5h-.3l-.1 .1 .2 .4h.2M231.6 81.4h-.3l-.1 .1 .2 .5 .2-.1M232.1 99.7h.3v.5M232.1 93.6h.3v.5M232.1 87.5h.3v.5M232.1 81.4h.3v.6M232.4 99.9l-.4 .2 .2 .1h.2M232.4 93.7l-.4 .2 .2 .2h.2M232.4 87.6l-.4 .2 .2 .2h.2M232.4 81.5l-.4 .2 .2 .3 .2-.1"/>
<path d="M233.2 99.7l-.3-.1-.2 .2 .2 .4h.3M233.2 93.6h-.3l-.2 .1 .2 .4h.3M233.2 87.5h-.4l-.1 .1 .2 .4h.3M233.2 81.4h-.4l-.1 .1 .2 .5 .3-.1M233.2 81v1M233.2 87.2v.8M233.2 93.3v.8M233.2 99.4v.8M233.4 94.2h.7M233.4 88.1h.7M233.4 82h.7M234.6 99.7h-.3l.1 .3h.2l-.1 .2h-.2"/>
<path d="M234.6 93.6h-.3v.2l.3 .1-.1 .2h-.2M234.6 87.5h-.3v.2l.3 .1-.1 .2h-.2M234.6 81.4h-.3v.2l.3 .1-.1 .3-.2-.1M235.4 99.7h-.5v.5h.5M235.4 93.6h-.5v.5h.5M235.4 87.5h-.5v.5h.5M235.4 81.4h-.5v.5h.5M235.7 99.7l.3-.1 .1 .2v.4M235.7 93.6h.4v.5M235.7 87.5h.4v.5M235.7 81.4h.4v.6M235.7 81v1"/>
<path d="M235.7 87.2v.8M235.7 93.3v.8M235.7 99.4v.8M32.9 100.1v.9l-.5-.9v.9M32.9 118.4v.9l-.5-.9v.9M32.9 112.3v.9l-.5-.9v.9M32.9 106.2v.9l-.5-.9v.9M33.4 101v-.9l.2 .6 .3-.6v.9M33.4 119.3v-.9l.2 .6 .3-.6v.9M33.4 113.2v-.9l.2 .6 .3-.6v.9M33.4 107.1v-.9l.2 .6 .3-.6v.9M34.3 118.5h.5a.47 .47 0 0 1-.3 .8l-.2-.2z"/>
<path d="M34.5 100.1a.47 .47 0 0 1 .4 .4 .47 .47 0 0 1-.4 .5l-.2-.2v-.6zM34.5 112.3a.47 .47 0 0 1 .4 .4 .47 .47 0 0 1-.4 .5l-.2-.2v-.6zM34.5 106.2a.47 .47 0 0 1 .4 .4 .47 .47 0 0 1-.4 .5l-.2-.2v-.6zM35.7 100.2h-.5v.2l.5 .3-.1 .3-.4-.1M35.7 118.4h-.5v.3l.5 .3-.1 .3-.4-.1M35.7 112.3h-.5v.3l.5 .3-.1 .3-.4-.1M35.7 106.3h-.5v.2l.5 .3-.1 .3-.4-.1M36.1 100.5h.2M36.1 118.8h.2M36.1 112.7h.2M36.1 106.6h.2M36.5 100.1h-.4v.9"/>
<path d="M36.5 118.4h-.4v.9M36.5 112.3h-.4v.9M36.5 106.2h-.4v.9M36.8 100.5h.3M36.8 118.8h.3M36.8 112.7h.3M36.8 106.6h.3M37.2 100.1h-.4v.9h.4M37.2 118.4h-.4v.9h.4M37.2 112.3h-.4v.9h.4M37.2 106.2h-.4v.9h.4M37.5 100.1h.5"/>
<path d="M37.5 118.4h.5M37.5 112.3h.5M37.5 106.2h.5M37.8 100.1v.9M37.8 106.2v.9M37.8 112.3v.9M37.8 118.4v.9M39.4 100.2l-.4-.1-.1 .1v.3l.5 .2v.2h-.5M39.4 118.4l-.5 .1v.3l.5 .2v.2h-.5M39.4 112.3h-.4l-.1 .1v.3l.5 .2v.2h-.5M39.4 106.3l-.4-.1-.1 .1v.3l.5 .2v.2h-.5M39.8 100.5l.3-.1v.6"/>
<path d="M39.8 118.8l.3-.1v.6M39.8 112.7l.3-.1v.6M39.8 106.6l.3-.1v.6M39.8 100.1v.9M39.8 106.2v.9M39.8 112.3v.9M39.8 118.4v.9M40.5 100.1v.1M40.5 118.4h.1M40.5 112.3h.1M40.5 106.2v.1M40.5 100.4v.6"/>
<path d="M40.5 106.5v.6M40.5 112.6v.6M40.5 118.7v.6M40.8 100.4h.3M40.8 118.7h.3M40.8 112.6h.3M40.8 106.5h.3M41.1 100.1l-.1 .1v.8M41.1 118.4h-.1v.9M41.1 112.3h-.1v.9M41.1 106.2l-.1 .1v.8M41.3 100.4h.4"/>
<path d="M41.3 118.7h.4M41.3 112.6h.4M41.3 106.5h.4M41.5 100.1v.8l.2 .1M41.5 118.4v.8l.2 .1M41.5 112.3v.8l.2 .1M41.5 106.2v.8l.2 .1M41.9 100.7l.4-.1v-.2l-.4 .1v.3l.2 .2 .2-.1M41.9 119l.4-.1v-.2l-.4 .1v.3l.2 .2 .2-.1M41.9 112.9l.4-.1v-.2l-.4 .1v.3l.2 .2 .2-.1M41.9 106.8l.4-.1v-.2l-.4 .1v.3l.2 .2 .2-.1M42.7 100.4v.6"/>
<path d="M42.7 106.5v.6M42.7 112.6v.6M42.7 118.7v.6M42.9 100.4l-.2 .2M42.9 118.7l-.2 .2M42.9 112.6l-.2 .2M42.9 106.5l-.2 .2M43.2 100.1h.5l-.3 .3 .3 .1v.4h-.5M43.4 106.2l-.2 .6h.6M43.6 118.4h-.3l-.1 .7 .1 .2 .4-.1v-.4l-.4-.1-.1 .2M43.6 106.5v.6M43.7 112.3h-.4l-.1 .4h.5v.4h-.5"/>
<path d="M216.3 118.1h.4M216.3 112h.4M216.3 105.9h.4M216.7 117.7h-.4v.8M216.7 111.6h-.4v.8M216.7 105.5h-.4v.8M216.8 113.2l-.5 .1v.2l.5 .3-.1 .2h-.4M216.8 107.1l-.5 .1v.2l.5 .3-.1 .2h-.4M216.8 119.3l-.5 .1v.2l.5 .3-.1 .2h-.4M216.8 101l-.5 .1v.2l.4 .1 .1 .2-.1 .2h-.4M217.1 113.4l.1 .6 .2-.4 .2 .4 .2-.6M217.1 107.4l.1 .5 .2-.4 .2 .4 .2-.5"/>
<path d="M217.1 119.5l.1 .6 .2-.4 .2 .4 .2-.6M217.1 101.3l.1 .5 .2-.4 .2 .4 .2-.5M217.1 117.7v.1M217.1 111.6v.1M217.1 105.5v.1M217.1 105.7v.6M217.1 111.8v.6M217.1 117.9v.6M217.5 117.7v.7l.2 .1M217.5 111.6v.7l.2 .1M217.5 105.5v.8h.2M217.9 118.3l.4-.1-.1-.3-.3 .1v.5h.4"/>
<path d="M217.9 112.2l.4-.1-.1-.3-.3 .1v.5h.4M217.9 106.1l.4-.1-.1-.3-.3 .1v.5h.4M218.1 113.2v.1M218.1 107.1v.1M218.1 119.3v.1M218.1 101v.1M218.1 101.3v.5M218.1 107.4v.5M218.1 113.4v.6M218.1 119.5v.6M218.3 113.4h.4M218.3 107.4h.4"/>
<path d="M218.3 119.5h.4M218.3 101.3h.4M218.5 113.2v.8h.2M218.5 107.1v.8h.2M218.5 119.3v.8h.2M218.5 101v.8h.2M218.7 118.4v.1M218.7 118v.1M218.7 112.3v.1M218.7 111.9v.1M218.7 106.3h.1M218.7 105.8v.1"/>
<path d="M218.7 100.2h.1M219.4 113.5l-.3-.1-.2 .2 .1 .4h.4M219.4 107.4h-.3l-.2 .1 .2 .4h.3M219.4 119.6l-.3-.1-.2 .2 .1 .4h.4M219.4 101.3h-.3l-.2 .1 .2 .4h.3M219.8 113.5l.2-.1 .1 .2v.4M219.8 107.4h.2l.1 .1v.4M219.8 119.6l.2-.1 .1 .2v.4M219.8 101.3h.3v.5M219.8 101v.8M219.8 107.1v.8M219.8 113.2v.8"/>
<path d="M219.8 119.3v.8M220.2 117.7l-.4 .1v.2l.4 .2v.2l-.4 .1M220.2 111.6l-.4 .1v.2l.4 .2-.1 .3h-.3M220.2 105.5l-.4 .1v.2l.4 .2-.1 .3h-.3M220.6 113.5h.3v.5h-.3l-.1-.1 .4-.2M220.6 107.4h.3v.5M220.6 119.6h.3v.5h-.3l-.1-.1 .4-.2M220.6 101.3h.3v.5M220.6 117.9l.1 .6 .2-.4 .2 .4 .1-.6M220.6 111.8l.1 .6 .2-.4 .2 .4 .1-.6M220.6 105.7l.1 .6 .2-.4 .2 .4 .1-.6M220.9 107.6l-.4 .2 .1 .1h.3"/>
<path d="M220.9 101.4l-.4 .2 .1 .2h.3M221.3 113.2v.8h.4v-.5h-.4M221.3 107.4h.4v.5h-.4M221.3 119.3v.8h.4v-.5h-.4M221.3 101.3h.4v.5h-.4M221.3 101v.8M221.3 107.1v.8M221.6 117.7v.1M221.6 111.6v.1M221.6 105.5v.1M221.6 105.7v.6M221.6 111.8v.6"/>
<path d="M221.6 117.9v.6M221.8 117.9h.4M221.8 111.8h.4M221.8 105.7h.4M222 117.7v.8h.2M222 111.6v.8h.2M222 105.5v.8h.2M222.1 113.2v.8h.1M222.1 107.1v.7l.1 .1M222.1 119.3v.8h.1M222.1 101v.7l.1 .1M222.5 113.8l.4-.1-.1-.3-.3 .2v.4h.4"/>
<path d="M222.5 107.7l.4-.1-.1-.2-.3 .1v.3l.2 .1h.2M222.5 119.9l.4-.1-.1-.3-.3 .2v.4h.4M222.5 101.5l.4-.1-.1-.1h-.3v.4l.2 .1h.2M222.8 118h-.4v.4l.4 .1M222.8 111.9h-.4v.4l.4 .1M222.8 105.8h-.4v.5h.4M223.2 118l.2-.1 .2 .2v.4M223.2 111.9l.2-.1 .2 .2v.4M223.2 105.8l.2-.1 .2 .2v.4M223.2 105.5v.8M223.2 111.6v.8M223.2 117.7v.8"/>
<path d="M224 113.6h.4v-.3l-.4-.1v.8M224 107.5h.4v-.3l-.4-.1v.8M224 119.7h.4v-.3l-.4-.1v.8M224 101.4l.4-.1v-.2l-.4-.1v.8M224 118l.2-.1 .2 .2v.4h-.4l-.1-.1 .5-.2M224 111.9l.2-.1 .2 .2v.4h-.4l-.1-.1 .5-.2M224 105.8l.2-.1 .2 .2v.4h-.4l-.1-.1 .5-.2M224.2 113.6l.2 .4M224.2 107.5l.2 .4M224.2 119.7l.2 .4M224.2 101.4l.2 .4M224.8 113.8l.4-.1-.1-.3-.3 .2v.4h.4"/>
<path d="M224.8 107.7l.4-.1-.1-.2-.3 .1v.3l.2 .1h.2M224.8 119.9l.4-.1-.1-.3-.3 .2v.4h.4M224.8 101.5l.4-.1-.1-.1h-.3v.4l.2 .1h.2M224.8 117.7v.8h.3l.1-.4-.2-.2-.2 .1M224.8 111.6v.8h.3l.1-.4-.2-.2-.2 .1M224.8 105.5v.8h.3l.1-.4-.2-.2-.2 .1M225.5 117.7v.7l.2 .1M225.5 111.6v.7l.2 .1M225.5 105.5v.8h.2M225.9 113.5l-.2-.1-.2 .2 .5 .4h-.5M225.9 107.4h-.2l-.2 .1 .5 .3-.2 .1h-.3M225.9 119.6l-.2-.1-.2 .2 .5 .4h-.5"/>
<path d="M225.9 101.3h-.2l-.2 .1 .5 .3-.2 .1h-.3M226 118.3l.4-.1-.1-.3-.3 .2v.3l.3 .1M226 112.2l.4-.1-.1-.3-.3 .2v.3l.3 .1M226 106.1l.4-.1-.1-.3-.3 .2v.4h.3M226.3 113.2v.1M226.3 107.1v.1M226.3 119.3v.1M226.3 101v.1M226.3 101.3v.5M226.3 107.4v.5M226.3 113.4v.6M226.3 119.5v.6"/>
<path d="M226.6 118.6h.6M226.6 112.5h.6M226.6 106.4h.6M226.6 100.3h.6M227 113.5l-.2-.1-.2 .2 .5 .4h-.5M227 107.4h-.2l-.2 .1 .5 .3-.2 .1h-.3M227 119.6l-.2-.1-.2 .2 .5 .4h-.5M227 101.3h-.2l-.2 .1 .5 .3-.2 .1h-.3M227.3 113.4h.4M227.3 107.4h.4M227.3 119.5h.4M227.3 101.3h.4"/>
<path d="M227.4 113.2v.8h.3M227.4 107.1v.7l.3 .1M227.4 119.3v.8h.3M227.4 101v.7l.3 .1M227.4 118.1h.4l.1-.3-.5-.1v.8M227.4 112h.4l.1-.3-.5-.1v.8M227.4 105.9h.4l.1-.3-.5-.1v.8M227.7 118.1l.2 .4M227.7 112l.2 .4M227.7 105.9l.2 .4M227.9 113.5h.4v.5h-.4zM227.9 107.4h.4v.5h-.4z"/>
<path d="M227.9 119.6h.4v.5h-.4zM227.9 101.3h.4v.5h-.4zM228.3 118.3l.4-.1-.2-.3-.2 .2v.3l.3 .1M228.3 112.2l.4-.1-.2-.3-.2 .2v.3l.3 .1M228.3 106.1l.4-.1-.2-.3-.2 .2v.4h.3M228.7 101.3v.5M228.7 107.4v.5M228.7 113.4v.6M228.7 119.5v.6M228.9 113.4l-.2 .2M228.9 107.4l-.2 .1M228.9 119.5l-.2 .2"/>
<path d="M228.9 101.3l-.2 .1M229.2 101.3l.2-.3v.8M229.2 101.8h.5M229.4 118h-.4l.1 .3h.3v.2h-.4M229.4 111.9h-.4l.1 .3h.3v.2h-.4M229.4 105.8h-.4l.1 .3h.3v.2h-.4M229.8 118.4v.1M229.8 112.3v.1M229.8 106.3h.1M229.8 100.2h.1M229.9 113.4l.2-.2v.8M229.9 107.4l.2-.3v.8"/>
<path d="M229.9 119.5l.2-.2v.8M229.9 114h.5M229.9 107.9h.5M230 101.3l.3-.3v.8M230 101.8h.5M230.2 105.5v.8M230.2 111.6v.8M230.2 117.7v.8M230.3 118.2l.2 .3M230.3 112.1l.2 .3M230.3 106l.2 .3M230.5 117.9l-.3 .4"/>
<path d="M230.5 111.8l-.3 .4M230.5 105.7l-.3 .4M230.6 113.2h.6l-.3 .3h.2v.5h-.5M230.7 107.2l.4-.1 .1 .3-.6 .5h.6M230.9 119.2l-.2 .7h.5M230.9 117.7v.1M230.9 111.6v.1M230.9 105.5v.1M230.9 105.7v.6M230.9 111.8v.6M230.9 117.9v.6M231.1 119.5v.6"/>
<path d="M231.6 118l-.2-.1-.2 .2 .1 .4h.3M231.6 111.9l-.2-.1-.2 .2 .1 .4h.3M231.6 105.8l-.2-.1-.2 .2 .1 .4h.3M232.1 118h.3v.5h-.3l-.1-.1 .4-.2M232.1 111.9h.3v.5h-.3l-.1-.1 .4-.2M232.1 105.8h.3v.5h-.3l-.1-.1 .4-.2M233.2 117.7v.8h-.4l-.1-.4 .2-.2 .3 .1M233.2 111.6v.8h-.4l-.1-.4 .2-.2 .3 .1M233.2 105.5v.8h-.4l-.1-.4 .2-.2 .3 .1M233.4 118.6h.7M233.4 112.5h.7M233.4 106.4h.7"/>
<path d="M233.4 100.3h.7M234.6 118h-.3l.1 .3h.2v.2h-.3M234.6 111.9h-.3l.1 .3h.2v.2h-.3M234.6 105.8h-.3l.1 .3h.2v.2h-.3M235.4 118h-.5v.4l.5 .1M235.4 111.9h-.5v.4l.5 .1M235.4 105.8h-.5v.5h.5M235.7 118l.3-.1 .1 .2v.4M235.7 111.9l.3-.1 .1 .2v.4M235.7 105.8l.3-.1 .1 .2v.4M235.7 105.5v.8M235.7 111.6v.8"/>
<path d="M235.7 117.7v.8M32.9 124.5v.9l-.5-.9v.9M32.9 136.7v.9l-.5-.9v.9M32.9 130.6v.9l-.5-.9v.9M33.4 125.4v-.9l.2 .6 .3-.6v.9M33.4 137.6v-.9l.2 .6 .3-.6v.9M33.4 131.5v-.9l.2 .6 .3-.6v.9M34.3 124.6h.5a.47 .47 0 0 1-.3 .8l-.2-.2zM34.3 136.8h.5l.1 .5-.2 .3-.4-.1zM34.3 130.7l.4-.1 .2 .3v.3l-.3 .3-.3-.2zM35.7 124.5l-.5 .1v.3l.4 .1 .1 .1-.1 .3-.4-.1M35.7 136.7l-.5 .1v.3l.5 .2-.1 .3h-.4"/>
<path d="M35.7 130.6l-.5 .1v.3l.5 .2-.1 .3-.4-.1M36.1 124.9h.2M36.1 137.2h.2M36.1 131.1h.2M36.5 124.5h-.4v.9M36.5 136.7h-.4v.9M36.5 130.6h-.4v.9M36.8 124.9h.3M36.8 137.2h.3M36.8 131.1h.3M37.2 124.5h-.4v.9h.4M37.2 136.7h-.4v.9h.4"/>
<path d="M37.2 130.6h-.4v.9h.4M37.5 124.5h.5M37.5 136.7h.5M37.5 130.6h.5M37.8 124.5v.9M37.8 130.6v.9M37.8 136.7v.9M39.4 124.5h-.5v.2l.5 .3v.3h-.5M39.4 136.7h-.5v.2l.1 .3h.4v.3l-.5 .1M39.4 130.6h-.5v.2l.1 .3h.4v.3h-.5M39.8 124.9h.3v.5M39.8 137.1h.3v.5"/>
<path d="M39.8 131h.3v.5M39.8 124.5v.9M39.8 130.6v.9M39.8 136.7v.9M40.5 124.5v.1M40.5 136.7v.1M40.5 130.6v.1M40.5 124.8v.6M40.5 130.9v.6M40.5 137v.6M40.8 124.8h.3M40.8 137h.3"/>
<path d="M40.8 130.9h.3M41.1 124.5h-.1v.9M41.1 136.7h-.1v.9M41.1 130.6h-.1v.9M41.3 124.8h.4M41.3 137h.4M41.3 130.9h.4M41.5 124.5v.8l.2 .1M41.5 136.7v.9h.2M41.5 130.6v.8l.2 .1M41.9 125h.4l-.1-.2-.3 .1v.3l.2 .2 .2-.1M41.9 137.3l.4-.1-.1-.2-.3 .2v.3l.4 .1"/>
<path d="M41.9 131.2l.4-.1-.1-.2-.3 .2v.2l.2 .2 .2-.1M42.7 124.8v.6M42.7 130.9v.6M42.7 137v.6M42.9 124.8l-.2 .2M42.9 137l-.2 .2M42.9 130.9l-.2 .2M43.2 124.5h.6l-.5 .9M43.2 137l.2-.3v.9M43.2 130.9l.2-.3v.9M43.2 137.6h.5M43.2 131.5h.5"/>
<path d="M44.3 136.6l-.3 .7h.6M44.4 137v.6M44.5 130.6h-.4l-.1 .5 .4-.1 .1 .4h-.5M216.3 130.3h.4M216.3 136.4h.4M216.3 124.2h.4M216.7 129.9h-.4v.8M216.7 136h-.4v.8M216.7 123.8h-.4v.8M216.8 125.4l-.5 .1v.2l.5 .3-.1 .2h-.4M216.8 137.7h-.5v.2l.5 .3-.1 .2h-.4M216.8 131.5l-.5 .1v.2l.5 .3-.1 .2h-.4"/>
<path d="M217.1 125.6l.1 .6 .2-.4 .2 .4 .2-.6M217.1 137.8l.1 .6 .2-.4 .2 .4 .2-.6M217.1 131.7l.1 .6 .2-.4 .2 .4 .2-.6M217.1 129.9v.1M217.1 136v.1M217.1 123.8v.1M217.1 124v.6M217.1 130.1v.6M217.1 136.3v.5M217.5 129.9v.7l.2 .1M217.5 136v.7l.2 .1M217.5 123.8v.7l.2 .1"/>
<path d="M217.9 130.5l.4-.1-.1-.3-.3 .1v.5h.4M217.9 136.6l.4-.1v-.2h-.4v.5h.4M217.9 124.4l.4-.1-.1-.3-.3 .1v.5h.4M218.1 125.4v.1M218.1 137.6v.1M218.1 131.5v.1M218.1 125.6v.6M218.1 131.7v.6M218.1 137.8v.6M218.3 125.6h.4M218.3 137.8h.4M218.3 131.7h.4"/>
<path d="M218.5 125.4v.8h.2M218.5 137.6v.8h.2M218.5 131.5v.8h.2M218.7 130.6v.1M218.7 130.2v.1M218.7 136.7v.1M218.7 136.3v.1M218.7 124.5v.1M218.7 124.1v.1M219.4 125.7l-.3-.1-.2 .2 .1 .4h.4M219.4 137.9l-.3-.1-.2 .2 .1 .4h.4M219.4 131.8l-.3-.1-.2 .2 .1 .4h.4"/>
<path d="M219.8 125.7l.2-.1 .1 .2v.4M219.8 137.9l.2-.1 .1 .2v.4M219.8 131.8l.2-.1 .1 .2v.4M219.8 125.4v.8M219.8 131.5v.8M219.8 137.6v.8M220.2 130h-.4l.1 .3 .3 .1-.1 .3h-.3M220.2 136.1h-.4v.2l.4 .2-.1 .3h-.3M220.2 123.8l-.4 .1v.2l.4 .2-.1 .3h-.3M220.6 125.7h.3v.5h-.3l-.1-.1 .4-.2M220.6 137.9h.3v.5h-.3l-.1-.1 .4-.2M220.6 131.8h.3v.5h-.3l-.1-.1 .4-.2"/>
<path d="M220.6 130.1l.1 .6 .2-.4 .2 .4 .1-.6M220.6 136.3l.1 .5 .2-.4 .2 .4 .1-.5M220.6 124l.1 .6 .2-.4 .2 .4 .1-.6M221.3 125.4v.8h.4v-.5h-.4M221.3 137.6v.8h.4v-.5h-.4M221.3 131.5v.8h.4v-.5h-.4M221.6 129.9v.1M221.6 136v.1M221.6 123.8v.1M221.6 124v.6M221.6 130.1v.6M221.6 136.3v.5"/>
<path d="M221.8 130.1h.4M221.8 136.3h.4M221.8 124h.4M222 129.9v.8h.2M222 136v.8h.2M222 123.8v.8h.2M222.1 125.4v.7l.1 .1M222.1 137.6v.7l.1 .1M222.1 131.5v.7l.1 .1M222.5 126l.4-.1-.1-.3-.3 .2v.3l.4 .1M222.5 138.2l.4-.1-.1-.3-.3 .2v.3l.4 .1M222.5 132.1l.4-.1-.1-.3-.3 .2v.3l.4 .1"/>
<path d="M222.8 130.2h-.4v.4l.4 .1M222.8 136.3l-.4 .1 .1 .4h.3M222.8 124.1h-.4v.4l.4 .1M223.2 130.2l.2-.1 .2 .2v.4M223.2 136.4h.4v.4M223.2 124.1l.2-.1 .2 .2v.4M223.2 123.8v.8M223.2 129.9v.8M223.2 136v.8M224 125.8h.4v-.3l-.4-.1v.8M224 138h.4v-.3l-.4-.1v.8M224 131.9h.4v-.3l-.4-.1v.8"/>
<path d="M224 130.2l.2-.1 .2 .2v.4h-.4l-.1-.1 .2-.2h.3M224 136.3l.4 .1v.4h-.4l-.1-.2 .5-.1M224 124.1l.2-.1 .2 .2v.4h-.4l-.1-.1 .5-.2M224.2 125.8l.2 .4M224.2 138l.2 .4M224.2 131.9l.2 .4M224.8 126l.4-.1-.1-.3-.3 .2v.3l.4 .1M224.8 138.2l.4-.1-.1-.3-.3 .2v.3l.4 .1M224.8 132.1l.4-.1-.1-.3-.3 .2v.3l.4 .1M224.8 129.9v.8h.3l.1-.4-.2-.2-.2 .1M224.8 136v.8h.3l.1-.4-.4-.1M224.8 123.8v.8h.3l.1-.4-.2-.2-.2 .1"/>
<path d="M225.5 129.9v.7l.2 .1M225.5 136v.7l.2 .1M225.5 123.8v.7l.2 .1M225.9 125.7l-.2-.1-.2 .2 .5 .3-.5 .1M225.9 137.9l-.2-.1-.2 .2 .5 .3-.5 .1M225.9 131.8l-.2-.1-.2 .2 .5 .3-.5 .1M226 130.5l.4-.1-.1-.3-.3 .2v.3l.3 .1M226 136.6l.4-.1-.1-.2-.3 .1v.3l.3 .1M226 124.4l.4-.1-.1-.3-.3 .2v.3l.3 .1M226.3 125.4v.1M226.3 137.6v.1M226.3 131.5v.1"/>
<path d="M226.3 125.6v.6M226.3 131.7v.6M226.3 137.8v.6M226.6 130.8h.6M226.6 136.9h.6M226.6 124.7h.6M227 125.7l-.2-.1-.2 .2 .5 .3-.5 .1M227 137.9l-.2-.1-.2 .2 .5 .3-.5 .1M227 131.8l-.2-.1-.2 .2 .5 .3-.5 .1M227.3 125.6h.4M227.3 137.8h.4M227.3 131.7h.4"/>
<path d="M227.4 125.4v.7l.3 .1M227.4 137.6v.7l.3 .1M227.4 131.5v.7l.3 .1M227.4 130.3h.4l.1-.3-.5-.1v.8M227.4 136.4h.5v-.3l-.5-.1v.8M227.4 124.2h.4l.1-.3-.5-.1v.8M227.7 130.3l.2 .4M227.7 136.4l.2 .4M227.7 124.2l.2 .4M227.9 125.7h.4v.5l-.4-.1zM227.9 137.9h.4v.5l-.4-.1zM227.9 131.8h.4v.5l-.4-.1z"/>
<path d="M228.3 130.5l.4-.1-.2-.3-.2 .2v.3l.3 .1M228.3 136.6l.4-.1-.1-.2-.3 .1v.3l.3 .1M228.3 124.4l.4-.1-.2-.3-.2 .2v.3l.3 .1M228.7 125.6v.6M228.7 131.7v.6M228.7 137.8v.6M228.9 125.6l-.2 .2M228.9 137.8l-.2 .2M228.9 131.7l-.2 .2M229.4 130.2h-.4l.1 .3h.3v.2h-.4M229.4 136.3h-.4l.1 .3h.3v.2h-.4M229.4 124.1h-.4l.1 .3h.3v.2h-.4"/>
<path d="M229.8 130.6v.1M229.8 136.7v.1M229.8 124.5v.1M229.9 125.6l.2-.2v.8M229.9 137.8l.2-.2v.8M229.9 131.7l.2-.2v.8M229.9 126.2h.5M229.9 138.4h.5M229.9 132.3h.5M229.9 120.1h.5M230.2 123.8v.8M230.2 129.9v.8"/>
<path d="M230.2 136v.8M230.3 130.4l.2 .3M230.3 136.5l.2 .3M230.3 124.3l.2 .3M230.5 130.1l-.3 .4M230.5 136.3l-.3 .3M230.5 124l-.3 .4M230.6 137.6h.6l-.3 .8M230.9 129.9v.1M230.9 136v.1M230.9 123.8v.1M230.9 124v.6"/>
<path d="M230.9 130.1v.6M230.9 136.3v.5M231.1 125.4h-.4v.4l.4-.1v.5l-.4-.1M231.1 131.5l-.4 .2v.5l.4 .1v-.5h-.3l-.1 .2M231.6 130.2l-.2-.1-.2 .2 .1 .4h.3M231.6 136.3l-.4 .1 .1 .4h.3M231.6 124.1l-.2-.1-.2 .2 .1 .4h.3M232.1 130.2h.3v.5h-.3l-.1-.1 .2-.2h.2M232.1 136.3h.3v.5h-.3l-.1-.2 .4-.1M232.1 124.1h.3v.5h-.3l-.1-.1 .4-.2M233.2 129.9v.8h-.4l-.1-.4 .2-.2 .3 .1M233.2 136v.8h-.4l-.1-.4 .5-.1"/>
<path d="M233.2 123.8v.8h-.4l-.1-.4 .2-.2 .3 .1M233.4 130.8h.7M233.4 136.9h.7M233.4 124.7h.7M234.6 130.2h-.3l.1 .3h.2v.2h-.3M234.6 136.3h-.3l.1 .3h.2v.2h-.3M234.6 124.1h-.3l.1 .3h.2v.2h-.3M235.4 130.2h-.5v.4l.5 .1M235.4 136.3l-.5 .1 .1 .4h.4M235.4 124.1h-.5v.4l.5 .1M235.7 130.2l.3-.1 .1 .2v.4M235.7 136.4h.4v.4"/>
<path d="M235.7 124.1l.3-.1 .1 .2v.4M235.7 123.8v.8M235.7 129.9v.8M235.7 136v.8M32.9 142.8v.9l-.5-.9v.9M32.9 155v.9l-.5-.9v.9M32.9 148.9v.9l-.5-.9v.9M33.4 143.7v-.9l.2 .6 .3-.6v.9M33.4 155.9v-.9l.2 .6 .3-.6v.9M33.4 149.8v-.9l.2 .6 .3-.6v.9M34.3 142.9h.5l.1 .5-.2 .3-.4-.1zM34.4 155h.3l.2 .3-.2 .6-.4-.1z"/>
<path d="M34.4 148.9h.3l.2 .3-.2 .6-.4-.1zM35.7 142.8l-.5 .1v.3l.5 .2-.1 .3h-.4M35.7 155l-.5 .1v.3l.5 .2-.1 .3h-.4M35.7 148.9l-.5 .1v.3l.5 .2-.1 .3h-.4M36.1 143.3h.2M36.1 155.4h.2M36.1 149.3h.2M36.5 142.8h-.4v.9M36.5 155h-.4v.9M36.5 148.9h-.4v.9M36.8 143.3h.3M36.8 155.4h.3"/>
<path d="M36.8 149.3h.3M37.2 142.8h-.4v.9h.4M37.2 155h-.4v.9h.4M37.2 148.9h-.4v.9h.4M37.5 142.8h.5M37.5 155h.5M37.5 148.9h.5M37.8 142.8v.9M37.8 148.9v.9M37.8 155v.9M39.4 142.8h-.5v.2l.1 .3h.4v.3l-.5 .1M39.4 155h-.5v.2l.1 .2 .4 .1v.3l-.5 .1"/>
<path d="M39.4 148.9h-.5v.2l.1 .2 .4 .1v.3l-.5 .1M39.8 143.2h.3v.5M39.8 155.4h.3v.5M39.8 149.3h.3v.5M39.8 142.8v.9M39.8 148.9v.9M39.8 155v.9M40.5 142.8v.1M40.5 155v.1M40.5 148.9v.1M40.5 143.1v.6M40.5 149.2v.6"/>
<path d="M40.5 155.3v.6M40.8 143.1h.3M40.8 155.3h.3M40.8 149.2h.3M41.1 142.8h-.1v.9M41.1 155h-.1v.9M41.1 148.9h-.1v.9M41.3 143.1h.4M41.3 155.3h.4M41.3 149.2h.4M41.5 142.8v.9h.2M41.5 155v.9h.2"/>
<path d="M41.5 148.9v.9h.2M41.9 143.4l.4-.1-.1-.2-.3 .2v.3l.4 .1M41.9 155.6l.4-.1-.1-.2-.3 .1v.4l.4 .1M41.9 149.5l.4-.1-.1-.2-.3 .1v.4l.4 .1M42.7 143.1v.6M42.7 149.2v.6M42.7 155.3v.6M42.9 143.1l-.2 .2M42.9 155.3l-.2 .1M42.9 149.2l-.2 .1M43.2 143.1l.2-.3v.9M43.2 155.3l.2-.3v.9"/>
<path d="M43.2 149.2l.2-.3v.9M43.2 143.7h.5M43.2 155.9h.5M43.2 149.8h.5M44 142.8h.5l-.2 .4 .2 .1v.3h-.5M44 155.3l.3-.3v.9M44 149h.5v.3l-.5 .5h.5M44 155.9h.5M216.3 142.5h.4M216.7 142.1h-.4v.8M217.1 142.1h.1M217.1 142.4v.5"/>
<path d="M217.5 142.1v.7l.2 .1M217.9 142.7l.4-.1v-.2h-.4v.5h.4M218.7 142.8v.1M218.7 142.4v.1M220.2 142.1h-.4v.3l.4 .3-.1 .2h-.3M220.6 142.4l.1 .5 .2-.3 .2 .3 .1-.5M221.6 142.1h.1M221.6 142.4v.5M221.8 142.4h.4M222 142.1v.8h.2M222.8 142.4l-.4 .1v.3l.4 .1M223.2 142.5h.4v.4"/>
<path d="M223.2 142.1v.8M224 142.4l.4 .1v.4h-.4l-.1-.2 .5-.1M224.8 142.1v.8h.3v-.5h-.3M225.5 142.1v.7l.2 .1M226 142.7l.4-.1-.1-.2-.3 .1v.3l.3 .1M226.6 143h.6M227.4 142.6l.5-.1v-.4h-.5v.8M227.7 142.6l.2 .3M228.3 142.7l.4-.1-.1-.2-.3 .1v.3l.3 .1M229.4 142.4h-.4v.3h.4v.2h-.4M229.8 142.8v.1M230.2 142.1v.8"/>
<path d="M230.3 142.7l.2 .2M230.5 142.4l-.3 .3M230.9 142.1h.1M230.9 142.4v.5M231.6 142.4h-.3l-.1 .2 .1 .3h.3M232.1 142.4h.3v.5h-.3l-.1-.2 .4-.1M233.2 142.1v.8h-.4v-.5h.4M233.4 143h.7M234.6 142.4h-.3v.3h.3v.2h-.3M235.4 142.4l-.5 .1v.3l.5 .1M235.7 142.5h.4v.4M235.7 142.1v.8"/>
<path d="M32.9 173.3v.9l-.5-.9v.9M32.9 179.4v.9l-.5-.9v.9M32.9 161.1v.9l-.5-.9v.9M32.9 167.2v.9l-.5-.9v.9M33.4 174.2v-.9l.2 .7 .3-.7v.9M33.4 162v-.9l.2 .6 .3-.6v.9M33.4 168.1v-.9l.2 .6 .3-.6v.9M34.3 161.2h.5l.1 .5-.2 .3-.4-.1zM34.5 173.3a.47 .47 0 0 1 .4 .3 .47 .47 0 0 1-.2 .6l-.4-.1v-.6zM34.5 179.4a.47 .47 0 0 1 .4 .5 .47 .47 0 0 1-.4 .4l-.2-.1v-.6zM34.5 167.2a.47 .47 0 0 1 .4 .3 .47 .47 0 0 1-.2 .6l-.4-.1v-.6zM35.7 173.4h-.5v.2l.5 .4-.1 .2h-.4"/>
<path d="M35.7 179.5h-.5v.2l.5 .4-.1 .2-.4-.1M35.7 161.1l-.5 .1v.3l.5 .2-.1 .3h-.4M35.7 167.3h-.5v.2l.5 .3-.1 .3h-.4M36.1 173.7h.2M36.1 179.8h.2M36.1 161.5h.2M36.1 167.6h.2M36.5 173.3h-.4v.9M36.5 179.4h-.4v.9M36.5 161.1h-.4v.9M36.5 167.2h-.4v.9M36.8 173.7h.3"/>
<path d="M36.8 179.8h.3M36.8 161.5h.3M36.8 167.6h.3M37.2 173.3h-.4v.9h.4M37.2 179.4h-.4v.9h.4M37.2 161.1h-.4v.9h.4M37.2 167.2h-.4v.9h.4M37.5 173.3h.5M37.5 179.4h.5M37.5 161.1h.5M37.5 167.2h.5M37.8 161.1v.9"/>
<path d="M37.8 167.2v.9M37.8 173.3v.9M37.8 179.4v.9M39.4 173.4l-.4-.1-.1 .2v.2l.5 .2-.1 .3h-.4M39.4 179.5l-.4-.1-.1 .2v.2l.5 .2v.2h-.5M39.4 161.1h-.5v.2l.1 .2 .4 .1v.3l-.5 .1M39.4 167.3l-.4-.1-.1 .2 .1 .2 .4 .1v.3l-.5 .1M39.8 173.7l.3-.1v.6M39.8 179.8l.3-.1v.6M39.8 161.5h.3v.5M39.8 167.5h.3v.6M39.8 161.1v.9"/>
<path d="M39.8 167.2v.9M39.8 173.3v.9M39.8 179.4v.9M40.5 173.3v.1M40.5 179.4v.1M40.5 161.1v.1M40.5 167.2v.1M40.5 161.4v.6M40.5 167.5v.6M40.5 173.6v.6M40.5 179.7v.6M40.8 173.6h.3"/>
<path d="M40.8 179.7h.3M40.8 161.4h.3M40.8 167.5h.3M41.1 173.3l-.1 .1v.8M41.1 179.4l-.1 .1v.8M41.1 161.1h-.1v.9M41.1 167.2l-.1 .1v.8M41.3 173.6h.4M41.3 179.7h.4M41.3 161.4h.4M41.3 167.5h.4M41.5 173.3v.9h.2"/>
<path d="M41.5 179.4v.8l.2 .1M41.5 161.1v.9h.2M41.5 167.2v.9h.2M41.9 173.9l.4-.1v-.2l-.4 .1 .1 .5h.3M41.9 180l.4-.1v-.2l-.4 .1v.4l.2 .1 .2-.1M41.9 161.7l.4-.1-.1-.2-.3 .1v.4l.4 .1M41.9 167.8l.4-.1v-.2l-.4 .1v.4l.4 .1M42.7 161.4v.6M42.7 167.5v.6M42.7 173.6v.6M42.7 179.7v.6M42.9 173.6l-.2 .2"/>
<path d="M42.9 179.7l-.2 .2M42.9 161.4l-.2 .1M42.9 167.5l-.2 .1M43.2 179.5h.5v.3l-.5 .5h.5M43.2 161.4l.2-.3v.9M43.2 162h.5M43.3 167.5h-.1l.1-.3 .4 .1v.2h-.4l-.1 .2 .1 .4 .4-.1v-.4l-.2-.1M43.7 173.7l-.2 .2-.3-.2 .1-.4 .4 .1v.6l-.4 .2M44.1 161.2l.3-.1 .1 .2-.1 .6a.39 .39 0 0 1-.4-.2 .39 .39 0 0 1 .1-.5zM32.9 191.6v.9l-.5-.9v.9M32.9 185.5v.9l-.5-.9v.9M33.4 192.5v-.9l.2 .7 .3-.7v.9"/>
<path d="M33.4 186.4v-.9l.2 .7 .3-.7v.9M33.4 180.3v-.9l.2 .7 .3-.7v.9M34.5 191.6a.47 .47 0 0 1 .4 .5 .47 .47 0 0 1-.4 .4l-.2-.1v-.6zM34.5 185.5a.47 .47 0 0 1 .4 .5 .47 .47 0 0 1-.4 .4l-.2-.1v-.6zM35.7 191.7h-.5v.2l.5 .4-.1 .2-.4-.1M35.7 185.6h-.5v.2l.5 .4-.1 .2-.4-.1M36.1 192h.2M36.1 185.9h.2M36.5 191.6h-.4v.9M36.5 185.5h-.4v.9M36.8 192h.3M36.8 185.9h.3"/>
<path d="M37.2 191.6h-.4v.9h.4M37.2 185.5h-.4v.9h.4M37.5 191.6h.5M37.5 185.5h.5M37.8 185.5v.9M37.8 191.6v.9M39.4 191.7l-.4-.1-.1 .2v.2l.5 .2v.2h-.5M39.4 185.6l-.4-.1-.1 .2v.2l.5 .2v.2h-.5M39.8 192l.3-.1v.6M39.8 185.9l.3-.1v.6M39.8 185.5v.9M39.8 191.6v.9"/>
<path d="M40.5 191.6v.1M40.5 185.5v.1M40.5 185.8v.6M40.5 191.9v.6M40.8 191.9h.3M40.8 185.8h.3M41.1 191.6l-.1 .1v.8M41.1 185.5l-.1 .1v.8M41.3 191.9h.4M41.3 185.8h.4M41.5 191.6v.8l.2 .1M41.5 185.5v.8l.2 .1"/>
<path d="M41.9 192.2l.4-.1v-.2l-.4 .1v.4l.2 .1 .2-.1M41.9 186.1l.4-.1v-.2l-.4 .1v.4l.2 .1 .2-.1M42.7 185.8v.6M42.7 191.9v.6M42.9 191.9l-.2 .2M42.9 185.8l-.2 .2M43.2 185.8l.2-.3v.9M43.2 186.4h.5"/>
</g>
<path d="M216.1 128.2h.4l.4 .4-.4 .4h-.4z" fill="#fff"/>
<path d="M216.1 128.2h.4l.4 .4-.4 .4h-.4z" fill="none" stroke="#805e00" stroke-width=".21"/>
<path d="M217.3 128.6h.4l.1-.3-.1-.2h-.4v.8M217.6 128.6l.2 .3M218.2 128.7l.4-.1-.1-.2h-.3v.5h.3M219.3 128.4h-.4l.1 .3h.3v.2h-.4M219.5 129h.6M220.8 128.2l-.2-.1-.3 .2v.5l.2 .1h.3v-.3h-.2M221.7 128.1v.8l-.5-.8v.8M222.1 128.1h.2l.3 .2v.5l-.2 .1h-.3z" fill="none" stroke="#007170" stroke-width=".21"/>
<path d="M233.5 127.7l.4-.5h.5v1h-.5z" fill="#fff"/>
<path d="M233.9 127.2h.5v1h-.5l-.4-.5z" fill="none" stroke="#805e00" stroke-width=".21"/>
<path d="M228.7 127.7h.4l.1-.4-.5-.1v.9M228.9 127.7l.3 .4M229.5 127.8h.4l-.1-.3-.3 .1v.5h.4M230.6 127.6h-.3l.1 .2h.2v.3h-.3M230.8 128.2h.7M231.6 127.3h.6v.5l-.1 .3-.5-.1zM233.1 127.2v.9l-.5-.9v.9" fill="none" stroke="#007170" stroke-width=".21"/>
<path d="M216.1 140.4h.4l.4 .4-.4 .4h-.4z" fill="#fff"/>
<path d="M216.1 140.4h.4l.4 .4-.4 .4h-.4z" fill="none" stroke="#805e00" stroke-width=".21"/>
<path d="M217.3 140.8h.4l.1-.3-.1-.2h-.4v.9M217.6 140.8l.2 .4M218.2 140.9l.4-.1-.1-.2h-.3v.5h.3M219.3 140.6h-.4v.3l.4 .1-.1 .2-.3-.1M219.5 141.3h.6M220.8 140.4l-.2-.1-.3 .2v.5l.3 .2 .2-.1v-.3h-.2M221.7 140.3v.9l-.5-.9v.9M222.1 140.3h.2l.3 .2v.5l-.3 .2h-.2z" fill="none" stroke="#007170" stroke-width=".21"/>
<path d="M233.9 139.4h.5v1h-.5l-.4-.5z" fill="#fff"/>
<path d="M233.9 139.4h.5v1h-.5l-.4-.5z" fill="none" stroke="#805e00" stroke-width=".21"/>
<path d="M228.7 139.9h.4l.1-.4-.5-.1v.9M228.9 139.9l.3 .4M230.6 139.8h-.3l.1 .2h.2v.3h-.3M231.7 139.4h.4l.1 .3-.1 .6-.5-.1zM233.1 139.4v.9l-.5-.9v.9M229.5 140l.4-.1-.1-.2-.3 .1v.5h.4M230.8 140.4h.7" fill="none" stroke="#007170" stroke-width=".21"/>
<path d="M216.1 134.3h.4l.4 .4-.4 .4h-.4z" fill="#fff"/>
<path d="M216.1 134.3h.4l.4 .4-.4 .4h-.4z" fill="none" stroke="#805e00" stroke-width=".21"/>
<path d="M217.3 134.7h.4l.1-.3-.1-.2h-.4v.8M217.6 134.7l.2 .3M218.2 134.8l.4-.1-.1-.2h-.3v.5h.3M219.3 134.5h-.4v.3h.3l.1 .2h-.4M219.5 135.1h.6M220.8 134.3l-.2-.1-.3 .2v.5l.2 .1h.3v-.3h-.2M221.7 134.2v.8l-.5-.8v.8M222.1 134.2h.2l.3 .2v.5l-.2 .1h-.3z" fill="none" stroke="#007170" stroke-width=".21"/>
<path d="M233.5 133.8l.4-.5h.5v1h-.5z" fill="#fff"/>
<path d="M233.9 133.3h.5v1h-.5l-.4-.5z" fill="none" stroke="#805e00" stroke-width=".21"/>
<path d="M228.7 133.8h.4l.1-.4-.5-.1v.9M228.9 133.8l.3 .4M229.5 133.9h.4l-.1-.3-.3 .1v.5h.4M230.6 133.7h-.3l.1 .2h.2v.3h-.3M230.8 134.3h.7M231.6 133.4h.6v.5l-.1 .3-.5-.1zM233.1 133.3v.9l-.5-.9v.9" fill="none" stroke="#007170" stroke-width=".21"/>
<path d="M216.1 115.9h.4l.4 .5-.4 .4h-.4z" fill="#fff"/>
<path d="M216.1 115.9h.4l.4 .5-.4 .4h-.4z" fill="none" stroke="#805e00" stroke-width=".21"/>
<path d="M217.3 116.3h.5v-.4h-.5v.8M217.6 116.3l.2 .4M218.2 116.5l.4-.1-.2-.2h-.2v.5h.3M219.3 116.2h-.4l.1 .3h.3v.2h-.4M219.5 116.8h.6M220.8 115.9h-.3l-.2 .2v.5l.2 .1h.3v-.3h-.2M221.7 115.9v.8l-.5-.8v.8M222.1 115.9h.3l.2 .2v.5l-.2 .1h-.3z" fill="none" stroke="#007170" stroke-width=".21"/>
<path d="M233.5 115.5l.4-.4h.5v.8h-.5z" fill="#fff"/>
<path d="M233.9 115.1h.5v.8h-.5l-.4-.4z" fill="none" stroke="#805e00" stroke-width=".21"/>
<path d="M228.7 115.5h.4l.1-.4h-.5v.8M228.9 115.5l.3 .4M229.5 115.6h.4l-.1-.3-.3 .1v.4h.4M230.6 115.4h-.3l.1 .2h.2l-.1 .3-.2-.1M230.8 116h.7M231.6 115.1h.5l.1 .2v.3l-.2 .3-.4-.2zM233.1 115.1v.8l-.5-.8v.8" fill="none" stroke="#007170" stroke-width=".21"/>
<path d="M216.1 109.8h.4l.4 .4-.4 .5h-.4z" fill="#fff"/>
<path d="M216.1 109.8h.4l.4 .4-.4 .5h-.4z" fill="none" stroke="#805e00" stroke-width=".21"/>
<path d="M217.3 110.2h.5v-.4h-.5v.9M217.6 110.2l.2 .5M218.2 110.4l.4-.1-.2-.2h-.2v.6h.3M219.3 110.1h-.4l.1 .3h.3v.3h-.4M219.5 110.7h.6M220.8 109.8h-.3l-.2 .2v.5l.2 .2h.3v-.4h-.2M221.7 109.8v.9l-.5-.9v.9M222.1 109.8h.3l.2 .2v.5l-.2 .2h-.3z" fill="none" stroke="#007170" stroke-width=".21"/>
<path d="M233.5 109.4l.4-.4h.5v.8h-.5z" fill="#fff"/>
<path d="M233.9 109h.5v.8h-.5l-.4-.4z" fill="none" stroke="#805e00" stroke-width=".21"/>
<path d="M228.7 109.4h.4l.1-.4h-.5v.8M228.9 109.4l.3 .4M229.5 109.5l.4-.1-.1-.2-.3 .1v.4h.4M230.6 109.3h-.3v.2l.3 .1-.1 .2-.2-.1M230.8 109.9h.7M231.6 109h.6a.47 .47 0 0 1-.4 .8l-.2-.2zM233.1 109v.8l-.5-.8v.8" fill="none" stroke="#007170" stroke-width=".21"/>
<path d="M216.1 122h.4l.4 .5-.4 .4h-.4z" fill="#fff"/>
<path d="M216.1 122h.4l.4 .5-.4 .4h-.4z" fill="none" stroke="#805e00" stroke-width=".21"/>
<path d="M217.3 122.4h.5v-.2l-.1-.2h-.4v.8M217.6 122.4l.2 .4M218.2 122.6l.4-.1-.2-.2h-.2v.5h.3M219.3 122.3h-.4l.1 .3h.3v.2h-.4M219.5 122.9h.6M220.8 122.1l-.2-.1-.3 .2v.5l.2 .1h.3v-.3h-.2M221.7 122v.8l-.5-.8v.8M222.1 122l.5 .2v.5l-.2 .1h-.3z" fill="none" stroke="#007170" stroke-width=".21"/>
<path d="M233.5 121.6l.4-.4h.5v.8h-.5z" fill="#fff"/>
<path d="M233.9 121.2h.5v.8h-.5l-.4-.4z" fill="none" stroke="#805e00" stroke-width=".21"/>
<path d="M228.7 121.6h.4l.1-.4h-.5v.8M228.9 121.6l.3 .4M229.5 121.7h.4l-.1-.3-.3 .1v.5h.4M230.6 121.5h-.3l.1 .2h.2v.3h-.3M230.8 122.1h.7M231.6 121.2h.6v.5l-.1 .3-.5-.1zM233.1 121.2v.8l-.5-.8v.8" fill="none" stroke="#007170" stroke-width=".21"/>
<path d="M47.4 194.4h.4v.8h-.4l-.4-.4z" fill="#fff"/>
<path d="M47.4 194.4h.4v.8h-.4l-.4-.4z" fill="none" stroke="#805e00" stroke-width=".21"/>
<g fill="none" stroke="#007170" stroke-width=".21">
<path d="M41.6 194.4v.8h.4M42.3 194.4v.8h.5M42.8 195.3h.6M43.7 194.4v.1M43.7 194.6v.6M44.1 194.7h.3v.5M44.1 194.6v.6M44.9 194.7h.4v.5h-.4M44.9 194.6v.9M45.6 194.6v.5l.2 .1h.3M46.1 194.6v.6M46.3 194.6h.3"/>
<path d="M46.5 194.4v.8h.1"/>
</g>
<path d="M32.2 194.4h.4l.4 .4-.4 .4h-.4z" fill="#fff"/>
<path d="M32.2 194.4h.4l.4 .4-.4 .4h-.4z" fill="none" stroke="#805e00" stroke-width=".21"/>
<g fill="none" stroke="#007170" stroke-width=".21">
<path d="M33.3 194.1h6.2M33.4 194.4v.8M33.4 194.8h.5M33.9 194.4v.8M34.3 194.4v.8h.4M35.6 194.8l.4-.2 .1 .5-.3 .1zM36.5 194.6v.6h.3M36.8 194.6v.6M37.2 194.6h.3M37.2 194.4v.7l.3 .1M37.8 194.7h.4v.5h-.4M37.8 194.6v.9"/>
<path d="M38.5 194.6v.5l.2 .1h.2M38.9 194.6v.6M39.2 194.6h.3M39.4 194.4v.8h.1"/>
</g>
<path d="M47 176.5l.4-.4h.4v.8h-.4z" fill="#fff"/>
<path d="M47.4 176.1h.4v.8h-.4l-.4-.4z" fill="none" stroke="#805e00" stroke-width=".21"/>
<path d="M41.6 176v.9h.4M42.3 176v.9h.5M42.8 177h.6M43.7 176v.1M43.7 176.4v.5M44.1 176.4h.3v.5M44.1 176.4v.5M44.9 176.9h.4l-.1-.5h-.3v.8M45.6 176.4v.4l.2 .1h.3M46.1 176.4v.5M46.3 176.4h.3M46.5 176v.9h.1" fill="none" stroke="#007170" stroke-width=".21"/>
<path d="M32.2 176.1h.4l.4 .4-.4 .4h-.4z" fill="#fff"/>
<path d="M32.2 176.1h.4l.4 .4-.4 .4h-.4z" fill="none" stroke="#805e00" stroke-width=".21"/>
<g fill="none" stroke="#007170" stroke-width=".21">
<path d="M33.3 175.8h6.2M33.4 176v.9M33.4 176.4h.5M33.9 176v.9M34.3 176v.9h.4M35.7 176.4h.4v.1l-.1 .4-.4-.1zM36.5 176.4v.5h.3M36.8 176.4v.5M37.2 176.4h.3M37.2 176v.8l.3 .1M37.8 176.9h.4l-.1-.5h-.3v.8M38.5 176.4v.4l.2 .1h.2"/>
<path d="M38.9 176.4v.5M39.2 176.4h.3M39.4 176v.9h.1"/>
</g>
<path d="M47.4 188.3h.4v.8h-.4l-.4-.4z" fill="#fff"/>
<path d="M47.4 188.3h.4v.8h-.4l-.4-.4z" fill="none" stroke="#805e00" stroke-width=".21"/>
<path d="M41.6 188.3v.8h.4M42.3 188.3v.8h.5M42.8 189.2h.6M43.7 188.3v.1M43.7 188.5v.6M44.1 188.6l.3-.1v.6M44.1 188.5v.6M44.9 189.1h.4l-.1-.6h-.3v.9M45.6 188.5v.5l.2 .1h.3M46.1 188.5v.6M46.3 188.5h.3M46.5 188.3v.8h.1" fill="none" stroke="#007170" stroke-width=".21"/>
<path d="M32.2 188.3h.4l.4 .4-.4 .4h-.4z" fill="#fff"/>
<path d="M32.2 188.3h.4l.4 .4-.4 .4h-.4z" fill="none" stroke="#805e00" stroke-width=".21"/>
<g fill="none" stroke="#007170" stroke-width=".21">
<path d="M33.3 188h6.2M33.4 188.3v.8M33.4 188.6h.5M33.9 188.3v.8M34.3 188.3v.8h.4M35.7 188.5h.4v.2l-.1 .4-.4-.1zM36.5 188.5v.6h.3M36.8 188.5v.6M37.2 188.5h.3M37.2 188.3v.7l.3 .1M37.8 189.1h.4l-.1-.6h-.3v.9M38.5 188.5v.5l.2 .1h.2"/>
<path d="M38.9 188.5v.6M39.2 188.5h.3M39.4 188.3v.8h.1"/>
</g>
<path d="M47 182.6l.4-.4h.4v.8h-.4z" fill="#fff"/>
<path d="M47 182.6l.4-.4h.4v.8h-.4z" fill="none" stroke="#805e00" stroke-width=".21"/>
<path d="M41.6 182.1v.9h.4M42.3 182.1v.9h.5M42.8 183.1h.6M43.7 182.1v.1M43.7 182.5v.5M44.1 182.5h.3v.5M44.1 182.5v.5M44.9 183h.4l-.1-.5h-.3v.8M45.6 182.5v.4l.2 .1h.3M46.1 182.5v.5M46.3 182.5h.3M46.5 182.1v.9h.1" fill="none" stroke="#007170" stroke-width=".21"/>
<path d="M32.2 182.2h.4l.4 .4-.4 .4h-.4z" fill="#fff"/>
<path d="M32.2 182.2h.4l.4 .4-.4 .4h-.4z" fill="none" stroke="#805e00" stroke-width=".21"/>
<g fill="none" stroke="#007170" stroke-width=".21">
<path d="M33.3 181.9h6.2M33.4 182.1v.9M33.4 182.5h.5M33.9 182.1v.9M34.3 182.1v.9h.4M35.7 182.5h.4v.1l-.1 .4-.4-.1zM36.5 182.5v.5h.3M36.8 182.5v.5M37.2 182.5h.3M37.2 182.1v.8l.3 .1M37.8 183h.4l-.1-.5h-.3v.8M38.5 182.5v.4l.2 .1h.2"/>
<path d="M38.9 182.5v.5M39.2 182.5h.3M39.4 182.1v.9h.1"/>
</g>
<path d="M47.4 102.9h.4v.8h-.4l-.4-.4z" fill="#fff"/>
<path d="M47.4 102.9h.4v.8h-.4l-.4-.4z" fill="none" stroke="#805e00" stroke-width=".21"/>
<path d="M41.6 102.9v.8h.4M42.3 102.9v.8h.5M42.8 103.8h.6M43.7 102.9h.1M43.7 103.1v.6M44.1 103.2l.3-.1v.6M44.1 103.1v.6M44.9 103.6h.4l-.1-.5h-.3v.9M45.6 103.1v.4l.2 .2 .3-.1M46.1 103.1v.6M46.3 103.1h.3M46.5 102.9v.7l.1 .1" fill="none" stroke="#007170" stroke-width=".21"/>
<path d="M32.2 102.9h.4l.4 .4-.4 .4h-.4z" fill="#fff"/>
<path d="M32.2 102.9h.4l.4 .4-.4 .4h-.4z" fill="none" stroke="#805e00" stroke-width=".21"/>
<g fill="none" stroke="#007170" stroke-width=".21">
<path d="M33.3 102.6h6.2M33.4 102.9v.8M33.4 103.2h.5M33.9 102.9v.8M34.3 102.9v.8h.4M35.7 103.1h.4v.2l-.1 .4-.4-.2zM36.5 103.1v.5h.3M36.8 103.1v.6M37.2 103.1h.3M37.2 102.9v.6l.3 .2M37.8 103.6h.4l-.1-.5h-.3v.9M38.5 103.1v.4l.2 .2 .2-.1"/>
<path d="M38.9 103.1v.6M39.2 103.1h.3M39.4 102.9v.7l.1 .1"/>
</g>
<path d="M47.4 121.2h.4v.8h-.4l-.4-.4z" fill="#fff"/>
<path d="M47.4 121.2h.4v.8h-.4l-.4-.4z" fill="none" stroke="#805e00" stroke-width=".21"/>
<g fill="none" stroke="#007170" stroke-width=".21">
<path d="M41.6 121.2v.8h.4M42.3 121.2v.8h.5M42.8 122.1h.6M43.7 121.2h.1M43.7 121.4v.6M44.1 121.5h.3v.5M44.1 121.4v.6M44.9 121.5h.4v.4l-.4 .1M44.9 121.4v.9M45.6 121.4v.5h.5M46.1 121.4v.6M46.3 121.4h.3"/>
<path d="M46.5 121.2v.8h.1"/>
</g>
<path d="M32.2 121.2h.4l.4 .4-.4 .4h-.4z" fill="#fff"/>
<path d="M32.2 121.2h.4l.4 .4-.4 .4h-.4z" fill="none" stroke="#805e00" stroke-width=".21"/>
<g fill="none" stroke="#007170" stroke-width=".21">
<path d="M33.3 120.9h6.2M33.4 121.2v.8M33.4 121.6h.5M33.9 121.2v.8M34.3 121.2v.8h.4M35.8 121.4l.3 .2v.4h-.4l-.1-.2zM36.5 121.4v.6l.3-.1M36.8 121.4v.6M37.2 121.4h.3M37.2 121.2v.7l.3 .1M37.8 121.5h.4v.4l-.4 .1M37.8 121.4v.9"/>
<path d="M38.5 121.4v.5h.4M38.9 121.4v.6M39.2 121.4h.3M39.4 121.2v.8h.1"/>
</g>
<path d="M47.4 115.1h.4v.8h-.4l-.4-.4z" fill="#fff"/>
<path d="M47.4 115.1h.4v.8h-.4l-.4-.4z" fill="none" stroke="#805e00" stroke-width=".21"/>
<g fill="none" stroke="#007170" stroke-width=".21">
<path d="M41.6 115.1v.8h.4M42.3 115.1v.8h.5M42.8 116h.6M43.7 115.1h.1M43.7 115.3v.6M44.1 115.4h.3v.5M44.1 115.3v.6M44.9 115.4h.4v.4h-.4M44.9 115.3v.9M45.6 115.3v.4l.2 .2 .3-.1M46.1 115.3v.6M46.3 115.3h.3"/>
<path d="M46.5 115.1v.7l.1 .1"/>
</g>
<path d="M32.2 115.1h.4l.4 .4-.4 .4h-.4z" fill="#fff"/>
<path d="M32.2 115.1h.4l.4 .4-.4 .4h-.4z" fill="none" stroke="#805e00" stroke-width=".21"/>
<g fill="none" stroke="#007170" stroke-width=".21">
<path d="M33.3 114.8h6.2M33.4 115.1v.8M33.4 115.5h.5M33.9 115.1v.8M34.3 115.1v.8h.4M35.6 115.5l.4-.2 .1 .4-.3 .2zM36.5 115.3v.5h.3M36.8 115.3v.6M37.2 115.3h.3M37.2 115.1v.6l.3 .2M37.8 115.4h.4v.4h-.4M37.8 115.3v.9"/>
<path d="M38.5 115.3v.4l.2 .2 .2-.1M38.9 115.3v.6M39.2 115.3h.3M39.4 115.1v.7l.1 .1"/>
</g>
<path d="M47.4 127.2h.4v1h-.4l-.4-.5z" fill="#fff"/>
<path d="M47 127.7l.4-.5h.4v1h-.4z" fill="none" stroke="#805e00" stroke-width=".21"/>
<g fill="none" stroke="#007170" stroke-width=".21">
<path d="M41.6 127.2v.9h.4M42.3 127.2v.9h.5M42.8 128.2h.6M43.7 127.2v.1M43.7 127.5v.6M44.1 127.6h.3v.5M44.1 127.5v.6M44.9 127.6h.4v.4l-.4 .1M44.9 127.5v.9M45.6 127.5v.5h.5M46.1 127.5v.6M46.3 127.5h.3"/>
<path d="M46.5 127.2v.9h.1"/>
</g>
<path d="M32.2 127.2h.4l.4 .5-.4 .5h-.4z" fill="#fff"/>
<path d="M32.2 127.2h.4l.4 .5-.4 .5h-.4z" fill="none" stroke="#805e00" stroke-width=".21"/>
<g fill="none" stroke="#007170" stroke-width=".21">
<path d="M33.3 127h6.2M33.4 127.2v.9M33.4 127.7h.5M33.9 127.2v.9M34.3 127.2v.9h.4M35.6 127.7l.2-.2 .3 .2v.4h-.4zM36.5 127.5v.6l.3-.1M36.8 127.5v.6M37.2 127.5h.3M37.2 127.2v.8l.3 .1M37.8 127.6h.4v.4l-.4 .1M37.8 127.5v.9"/>
<path d="M38.5 127.5v.5h.4M38.9 127.5v.6M39.2 127.5h.3M39.4 127.2v.9h.1"/>
</g>
<path d="M47.4 109h.4v.8h-.4l-.4-.4z" fill="#fff"/>
<path d="M47.4 109h.4v.8h-.4l-.4-.4z" fill="none" stroke="#805e00" stroke-width=".21"/>
<g fill="none" stroke="#007170" stroke-width=".21">
<path d="M41.6 109v.8h.4M42.3 109v.8h.5M42.8 109.9h.6M43.7 109h.1M43.7 109.2v.6M44.1 109.3h.3v.5M44.1 109.2v.6M44.9 109.3h.4v.4h-.4M44.9 109.2v.9M45.6 109.2v.4l.2 .2 .3-.1M46.1 109.2v.6M46.3 109.2h.3"/>
<path d="M46.5 109v.7l.1 .1"/>
</g>
<path d="M32.2 109h.4l.4 .4-.4 .4h-.4z" fill="#fff"/>
<path d="M32.2 109h.4l.4 .4-.4 .4h-.4z" fill="none" stroke="#805e00" stroke-width=".21"/>
<g fill="none" stroke="#007170" stroke-width=".21">
<path d="M33.3 108.7h6.2M33.4 109v.8M33.4 109.4h.5M33.9 109v.8M34.3 109v.8h.4M35.6 109.4l.4-.2 .1 .4-.3 .2zM36.5 109.2v.5h.3M36.8 109.2v.6M37.2 109.2h.3M37.2 109v.6l.3 .2M37.8 109.3h.4v.4h-.4M37.8 109.2v.9"/>
<path d="M38.5 109.2v.4l.2 .2 .2-.1M38.9 109.2v.6M39.2 109.2h.3M39.4 109v.7l.1 .1"/>
</g>
<path d="M47.4 139.4h.4v1h-.4l-.4-.5z" fill="#fff"/>
<path d="M47.4 139.4h.4v1h-.4l-.4-.5z" fill="none" stroke="#805e00" stroke-width=".21"/>
<g fill="none" stroke="#007170" stroke-width=".21">
<path d="M41.6 139.4v.9h.4M42.3 139.4v.9h.5M43.7 139.4v.1M43.7 139.7v.6M44.1 139.8h.3v.5M44.1 139.7v.6M44.9 139.8h.4v.4l-.4 .1M44.9 139.7v.9M45.6 139.7v.5h.5M46.1 139.7v.6M46.3 139.7h.3M46.5 139.4v.9h.1"/>
<path d="M42.8 140.4h.6"/>
</g>
<path d="M32.2 139.4h.4l.4 .5-.4 .5h-.4z" fill="#fff"/>
<path d="M32.2 139.4h.4l.4 .5-.4 .5h-.4z" fill="none" stroke="#805e00" stroke-width=".21"/>
<g fill="none" stroke="#007170" stroke-width=".21">
<path d="M33.3 139.2h6.2M33.4 139.4v.9M33.4 139.9h.5M33.9 139.4v.9M34.3 139.4v.9h.4M35.6 139.9l.2-.2 .3 .2v.4h-.4zM36.5 139.7v.6l.3-.1M36.8 139.7v.6M37.2 139.7h.3M37.2 139.4v.8l.3 .1M37.8 139.8h.4v.4l-.4 .1M37.8 139.7v.9"/>
<path d="M38.5 139.7v.5h.4M38.9 139.7v.6M39.2 139.7h.3M39.4 139.4v.9h.1"/>
</g>
<path d="M47.4 145.5h.4v1h-.4l-.4-.5z" fill="#fff"/>
<path d="M47.4 145.5h.4v1h-.4l-.4-.5z" fill="none" stroke="#805e00" stroke-width=".21"/>
<g fill="none" stroke="#007170" stroke-width=".21">
<path d="M41.6 145.5v.9h.4M42.3 145.5v.9h.5M42.8 146.5h.6M43.7 145.5v.1M43.7 145.8v.6M44.1 145.9h.3v.5M44.1 145.8v.6M44.9 145.9h.4v.4l-.4 .1M44.9 145.8v.9M45.6 145.8v.5h.5M46.1 145.8v.6M46.3 145.8h.3"/>
<path d="M46.5 145.5v.9h.1"/>
</g>
<path d="M32.2 145.5h.4l.4 .5-.4 .5h-.4z" fill="#fff"/>
<path d="M32.2 145.5h.4l.4 .5-.4 .5h-.4z" fill="none" stroke="#805e00" stroke-width=".21"/>
<g fill="none" stroke="#007170" stroke-width=".21">
<path d="M33.3 145.3h6.2M33.4 145.5v.9M33.4 146h.5M33.9 145.5v.9M34.3 145.5v.9h.4M35.6 146l.2-.2 .3 .2v.4h-.4zM36.5 145.8v.6l.3-.1M36.8 145.8v.6M37.2 145.8h.3M37.2 145.5v.8l.3 .1M37.8 145.9h.4v.4l-.4 .1M37.8 145.8v.9"/>
<path d="M38.5 145.8v.5h.4M38.9 145.8v.6M39.2 145.8h.3M39.4 145.5v.9h.1"/>
</g>
<path d="M47 133.8l.4-.5h.4v1h-.4z" fill="#fff"/>
<path d="M47.4 133.3h.4v1h-.4l-.4-.5z" fill="none" stroke="#805e00" stroke-width=".21"/>
<g fill="none" stroke="#007170" stroke-width=".21">
<path d="M41.6 133.3v.9h.4M42.3 133.3v.9h.5M42.8 134.3h.6M43.7 133.3v.1M43.7 133.6v.6M44.1 133.7h.3v.5M44.1 133.6v.6M44.9 133.7h.4v.4l-.4 .1M44.9 133.6v.9M45.6 133.6v.5h.5M46.1 133.6v.6M46.3 133.6h.3"/>
<path d="M46.5 133.3v.9h.1"/>
</g>
<path d="M32.2 133.3h.4l.4 .5-.4 .5h-.4z" fill="#fff"/>
<path d="M32.2 133.3h.4l.4 .5-.4 .5h-.4z" fill="none" stroke="#805e00" stroke-width=".21"/>
<g fill="none" stroke="#007170" stroke-width=".21">
<path d="M33.3 133.1h6.2M33.4 133.3v.9M33.4 133.8h.5M33.9 133.3v.9M34.3 133.3v.9h.4M35.8 133.6l.3 .2v.4h-.4l-.1-.2zM36.5 133.6v.6l.3-.1M36.8 133.6v.6M37.2 133.6h.3M37.2 133.3v.8l.3 .1M37.8 133.7h.4v.4l-.4 .1M37.8 133.6v.9"/>
<path d="M38.5 133.6v.5h.4M38.9 133.6v.6M39.2 133.6h.3M39.4 133.3v.9h.1"/>
</g>
<path d="M47 158.2l.4-.4h.4v.9h-.4z" fill="#fff"/>
<path d="M47.4 157.8h.4v.9h-.4l-.4-.5z" fill="none" stroke="#805e00" stroke-width=".21"/>
<path d="M41.6 157.7v.9h.4M42.3 157.7v.9h.5M42.8 158.7h.6M43.7 157.7v.1M43.7 158.1v.5M44.1 158.2l.3-.1v.5M44.1 158.1v.5M44.9 158.6l.4-.1-.1-.4h-.3v.8M45.6 158.1l.1 .5 .4-.1M46.1 158.1v.5M46.3 158.1h.3M46.5 157.7v.9h.1" fill="none" stroke="#007170" stroke-width=".21"/>
<path d="M32.2 157.8h.4l.4 .4-.4 .5h-.4z" fill="#fff"/>
<path d="M32.2 157.8h.4l.4 .4-.4 .5h-.4z" fill="none" stroke="#805e00" stroke-width=".21"/>
<g fill="none" stroke="#007170" stroke-width=".21">
<path d="M33.3 157.5h6.2M33.4 157.7v.9M33.4 158.2h.5M33.9 157.7v.9M34.3 157.7v.9h.4M35.7 158.1h.4v.5l-.5-.1zM36.5 158.1v.5l.3-.1M36.8 158.1v.5M37.2 158.1h.3M37.2 157.7v.8l.3 .1M37.8 158.6l.4-.1-.1-.4h-.3v.8M38.5 158.1l.1 .5 .3-.1"/>
<path d="M38.9 158.1v.5M39.2 158.1h.3M39.4 157.7v.9h.1"/>
</g>
<path d="M47 152.1l.4-.4h.4v.9h-.4z" fill="#fff"/>
<path d="M47 152.1l.4-.4h.4v.9h-.4z" fill="none" stroke="#805e00" stroke-width=".21"/>
<path d="M41.6 151.6v.9h.4M42.3 151.6v.9h.5M42.8 152.6h.6M43.7 151.6v.1M43.7 152v.5M44.1 152.1l.3-.1v.5M44.1 152v.5M44.9 152.5l.4-.1-.1-.4h-.3v.8M45.6 152v.4h.5M46.1 152v.5M46.3 152h.3M46.5 151.6v.9h.1" fill="none" stroke="#007170" stroke-width=".21"/>
<path d="M32.2 151.7h.4l.4 .4-.4 .5h-.4z" fill="#fff"/>
<path d="M32.2 151.7h.4l.4 .4-.4 .5h-.4z" fill="none" stroke="#805e00" stroke-width=".21"/>
<g fill="none" stroke="#007170" stroke-width=".21">
<path d="M33.3 151.4h6.2M33.4 151.6v.9M33.4 152.1h.5M33.9 151.6v.9M34.3 151.6v.9h.4M35.7 152l.4 .1v.4h-.4zM36.5 152v.5l.3-.1M36.8 152v.5M37.2 152h.3M37.2 151.6v.8l.3 .1M37.8 152.5l.4-.1-.1-.4h-.3v.8M38.5 152v.4h.4"/>
<path d="M38.9 152v.5M39.2 152h.3M39.4 151.6v.9h.1"/>
</g>
<path d="M47 164.3l.4-.4h.4v.9h-.4z" fill="#fff"/>
<path d="M47.4 163.9h.4v.9h-.4l-.4-.5z" fill="none" stroke="#805e00" stroke-width=".21"/>
<path d="M41.6 163.8v1h.4M42.3 163.8v1h.5M42.8 164.8h.6M43.7 163.8v.1M43.7 164.2v.6M44.1 164.2h.3v.6M44.1 164.2v.6M44.9 164.7h.4l-.1-.5h-.3v.8M45.6 164.2v.4l.2 .2 .3-.1M46.1 164.2v.6M46.3 164.2h.3M46.5 163.8v.9l.1 .1" fill="none" stroke="#007170" stroke-width=".21"/>
<path d="M32.2 163.9h.4l.4 .4-.4 .5h-.4z" fill="#fff"/>
<path d="M32.2 163.9h.4l.4 .4-.4 .5h-.4z" fill="none" stroke="#805e00" stroke-width=".21"/>
<g fill="none" stroke="#007170" stroke-width=".21">
<path d="M33.3 163.6h6.2M33.4 163.8v1M33.4 164.2h.5M33.9 163.8v1M34.3 163.8v1h.4M35.7 164.2h.4v.1l-.1 .5-.4-.2zM36.5 164.2v.5h.3M36.8 164.2v.6M37.2 164.2h.3M37.2 163.8v.8l.3 .2M37.8 164.7h.4l-.1-.5h-.3v.8M38.5 164.2v.4l.2 .2 .2-.1"/>
<path d="M38.9 164.2v.6M39.2 164.2h.3M39.4 163.8v.9l.1 .1"/>
</g>
<path d="M47.4 170h.4v.9h-.4l-.4-.5z" fill="#fff"/>
<path d="M47.4 170h.4v.9h-.4l-.4-.5z" fill="none" stroke="#805e00" stroke-width=".21"/>
<path d="M41.6 169.9v1h.4M42.3 169.9v1h.5M42.8 170.9h.6M43.7 169.9v.1M43.7 170.3v.6M44.1 170.3h.3v.6M44.1 170.3v.6M44.9 170.8h.4l-.1-.5h-.3v.8M45.6 170.3v.4l.2 .2 .3-.1M46.1 170.3v.6M46.3 170.3h.3M46.5 169.9v.9l.1 .1" fill="none" stroke="#007170" stroke-width=".21"/>
<path d="M32.2 170h.4l.4 .4-.4 .5h-.4z" fill="#fff"/>
<path d="M32.2 170h.4l.4 .4-.4 .5h-.4z" fill="none" stroke="#805e00" stroke-width=".21"/>
<g fill="none" stroke="#007170" stroke-width=".21">
<path d="M33.3 169.7h6.2M33.4 169.9v1M33.4 170.3h.5M33.9 169.9v1M34.3 169.9v1h.4M35.7 170.3h.4v.1l-.1 .5-.4-.2zM36.5 170.3v.5h.3M36.8 170.3v.6M37.2 170.3h.3M37.2 169.9v.8l.3 .2M37.8 170.8h.4l-.1-.5h-.3v.8M38.5 170.3v.4l.2 .2 .2-.1"/>
<path d="M38.9 170.3v.6M39.2 170.3h.3M39.4 169.9v.9l.1 .1"/>
</g>
<path d="M244.9 37.5h.4l.4 .4-.4 .4h-.4z" fill="#fff"/>
<path d="M244.9 37.5h.4l.4 .4-.4 .4h-.4z" fill="none" stroke="#805e00" stroke-width=".21"/>
<path d="M239.2 37.4h.6l-.4 .4 .4 .1v.3l-.2 .1h-.4M239.9 37.4l.4 .9 .2-.9M240.8 37.4h.5l-.3 .4h.3v.5h-.5M241.5 38.4h.6M242.5 37.4a.47 .47 0 0 1 .4 .5 .47 .47 0 0 1-.4 .4l-.2-.1v-.6zM243.2 37.4v.8l.2 .1h.3v-.9M244.1 37.4h.4M244.3 37.4v.9" fill="none" stroke="#007170" stroke-width=".21"/>
<path d="M218.7 37.5h.4l.4 .4-.4 .4h-.4z" fill="#fff"/>
<path d="M218.7 37.5h.4l.4 .4-.4 .4h-.4z" fill="none" stroke="#805e00" stroke-width=".21"/>
<path d="M219.8 37.4l.3 .9 .3-.9M220.5 38.4h.6M221.4 37.4v.9M222.2 37.4v.9l-.4-.9v.9" fill="none" stroke="#007170" stroke-width=".21"/>
<path d="M216.1 48.8h.4l.4 .5-.4 .4h-.4z" fill="#fff"/>
<path d="M216.1 48.8h.4l.4 .5-.4 .4h-.4z" fill="none" stroke="#805e00" stroke-width=".21"/>
<path d="M217.3 49.3h.4l.1-.2-.1-.3h-.4v.8M217.6 49.3l.2 .3M218.2 49.4l.4-.1-.1-.2h-.3v.5h.3M219.3 49.1h-.4v.3h.4v.2h-.4M219.5 49.7h.6M220.8 48.8h-.2l-.3 .2v.4l.2 .2h.3v-.3h-.2M221.7 48.8v.8l-.5-.8v.8M222.1 48.8h.2l.3 .2v.4l-.2 .2h-.3z" fill="none" stroke="#007170" stroke-width=".21"/>
<path d="M233.5 48.3l.4-.4h.5v.9h-.5z" fill="#fff"/>
<path d="M233.9 47.9h.5v.9h-.5l-.4-.5z" fill="none" stroke="#805e00" stroke-width=".21"/>
<path d="M228.7 48.3h.4l.1-.3-.5-.1v.9M228.9 48.3l.3 .5M229.5 48.5l.4-.1-.1-.2-.3 .1v.5h.4M230.6 48.3h-.3l.1 .2h.2v.3h-.3M230.8 48.8h.7M231.7 47.9h.4l.1 .3-.1 .6-.5-.1zM233.1 47.9v.9l-.5-.9v.9" fill="none" stroke="#007170" stroke-width=".21"/>
<path d="M198.6 20.9h.4l.5 .4-.5 .5h-.4z" fill="#fff"/>
<path d="M198.6 20.9h.4l.5 .4-.5 .5h-.4z" fill="none" stroke="#805e00" stroke-width=".21"/>
<g fill="none" stroke="#007170" stroke-width=".21">
<path d="M188.4 21.3h.4v-.4h-.4v.9M189.2 21.2h.4v.6l-.4-.1zM190 21.2l.2 .6 .1-.5 .2 .5 .2-.6M190.9 21.5l.4-.1-.1-.2h-.3v.6h.4M191.7 21.2v.6M191.9 21.2l-.2 .1M192 21.8h.7M193.4 20.9l-.5 .1v.2l.5 .3-.1 .3h-.4M193.6 21.2l.2 .6 .2-.5 .1 .5 .2-.6M194.6 20.9v.1M194.6 21.2v.6M195 21.2h.2"/>
<path d="M195.1 20.9v.9h.1M195.9 21.2h-.2l-.2 .1 .1 .5h.3M196.3 21.2h.4v.6M196.3 20.9v.9M197.1 21.5l.3-.1v-.2h-.3v.6h.3M198.2 20.9v.9h-.3l-.1-.5 .1-.1h.3"/>
</g>
<path d="M175.9 20.9h.5l.5 .4-.5 .5h-.5z" fill="#fff"/>
<path d="M175.9 20.9h.5l.5 .4-.5 .5h-.5z" fill="none" stroke="#805e00" stroke-width=".21"/>
<path d="M177.2 21.3h.4l.1-.3-.5-.1v.9M178.2 21.2l.4 .1-.1 .5h-.4l-.1-.2zM178.8 21.2l.2 .6 .1-.5 .2 .5 .2-.6M179.7 21.5l.5-.1-.1-.2-.4 .1v.4l.5 .1M180.6 21.2v.6M180.8 21.2l-.2 .1M180.9 21.8h.6M181.8 20.9v.9M182.2 21.2h.3v.6M182.2 21.2v.6" fill="none" stroke="#007170" stroke-width=".21"/>
<path d="M175.9 22.7h.5l.5 .4-.5 .4h-.5z" fill="#fff"/>
<path d="M175.9 22.7h.5l.5 .4-.5 .4h-.5z" fill="none" stroke="#805e00" stroke-width=".21"/>
<g fill="none" stroke="#007170" stroke-width=".21">
<path d="M177.2 23.1l.5-.1v-.3l-.5-.1v.9M178.1 22.9h.4l.1 .2-.2 .4-.4-.1zM178.8 22.9l.2 .6 .1-.4 .2 .4 .2-.6M179.7 23.2l.5-.1v-.2l-.5 .1v.4l.2 .1 .3-.1M180.6 22.9v.6M180.8 22.9l-.2 .2M180.9 23.6h.6M181.9 22.6l.4 .2v.6l-.2 .1a.49 .49 0 0 1-.4-.4 .49 .49 0 0 1 .2-.5zM182.7 23l.3-.1v.6M182.7 22.9v.6M184.1 22.6l-.7 1.1M184.2 22.3h1.8"/>
<path d="M184.6 22.6l.3 .2v.6l-.2 .1a.49 .49 0 0 1-.4-.4 .49 .49 0 0 1 .3-.5zM185.2 22.9h.3M185.5 22.6l-.2 .1v.8M185.7 22.9h.3M186 22.6l-.2 .2v.7"/>
</g>
<path d="M218.7 22.7h.4l.4 .4-.4 .4h-.4z" fill="#fff"/>
<path d="M218.7 22.7h.4l.4 .4-.4 .4h-.4z" fill="none" stroke="#805e00" stroke-width=".21"/>
<path d="M220.4 22.6h-.4l-.1 .4h.5v.4h-.5M220.6 22.6l.4 .9 .2-.9M221.3 23.6h.7M222.2 23h.3M222.6 22.6h-.4v.9h.4M223.5 22.6v.9l-.5-.9v.9" fill="none" stroke="#007170" stroke-width=".21"/>
<path d="M244.9 20.9h.4l.4 .4-.4 .5h-.4z" fill="#fff"/>
<path d="M244.9 20.9h.4l.4 .4-.4 .5h-.4z" fill="none" stroke="#805e00" stroke-width=".21"/>
<path d="M240.5 20.9h-.4l-.1 .4 .4-.1 .1 .5h-.5M240.8 20.9l.3 .9 .3-.9M241.5 21.8h.6M242.3 21h.5l.1 .5-.2 .3-.4-.1zM243.2 20.9l.1 .9 .4-.1v-.8M244.1 20.9h.4M244.3 20.9v.9" fill="none" stroke="#007170" stroke-width=".21"/>
<path d="M218.7 20.9h.4l.4 .4-.4 .5h-.4z" fill="#fff"/>
<path d="M218.7 20.9h.4l.4 .4-.4 .5h-.4z" fill="none" stroke="#805e00" stroke-width=".21"/>
<path d="M219.8 20.9l.3 .9 .3-.9M220.5 21.8h.6M221.4 20.9v.9M222.2 20.9v.9l-.4-.9v.9" fill="none" stroke="#007170" stroke-width=".21"/>
<path d="M216.1 103.7h.4l.4 .4-.4 .5h-.4z" fill="#fff"/>
<path d="M216.1 103.7h.4l.4 .4-.4 .5h-.4z" fill="none" stroke="#805e00" stroke-width=".21"/>
<path d="M217.3 104.1h.5v-.4h-.5v.9M217.6 104.1l.2 .5M218.2 104.3l.4-.1-.2-.2h-.2v.6h.3M219.3 104h-.4l.1 .3h.3v.3h-.4M219.5 104.6h.6M220.8 103.7h-.3l-.2 .2v.5l.2 .2h.3v-.4h-.2M221.7 103.7v.9l-.5-.9v.9M222.1 103.7h.3l.2 .2v.5l-.2 .2h-.3z" fill="none" stroke="#007170" stroke-width=".21"/>
<path d="M233.9 102.9h.5v.8h-.5l-.4-.4z" fill="#fff"/>
<path d="M233.9 102.9h.5v.8h-.5l-.4-.4z" fill="none" stroke="#805e00" stroke-width=".21"/>
<path d="M228.7 103.3l.5-.1v-.3h-.5v.8M228.9 103.3l.3 .4M229.5 103.4l.4-.1v-.2h-.4v.5h.4M230.6 103.1h-.3v.3l.3 .1-.1 .2-.2-.1M230.8 103.8h.7M231.6 102.9h.6a.47 .47 0 0 1-.4 .8l-.2-.2zM233.1 102.9v.8l-.5-.8v.8" fill="none" stroke="#007170" stroke-width=".21"/>
<path d="M216.1 97.6h.4l.4 .4-.4 .5h-.4z" fill="#fff"/>
<path d="M216.1 97.6h.4l.4 .4-.4 .5h-.4z" fill="none" stroke="#805e00" stroke-width=".21"/>
<path d="M217.3 98h.5v-.4h-.5v.9M217.6 98l.2 .5M218.2 98.2l.4-.1-.2-.2-.2 .1v.5h.3M219.3 98h-.4l.1 .2h.3v.3h-.4M219.5 98.5h.6M220.8 97.6h-.3l-.2 .2v.5l.2 .2h.3v-.4h-.2M221.7 97.6v.9l-.5-.9v.9M222.1 97.6h.3l.2 .2v.5l-.2 .2h-.3z" fill="none" stroke="#007170" stroke-width=".21"/>
<path d="M233.9 96.8h.5v.8h-.5l-.4-.4z" fill="#fff"/>
<path d="M233.9 96.8h.5v.8h-.5l-.4-.4z" fill="none" stroke="#805e00" stroke-width=".21"/>
<path d="M228.7 97.2l.5-.1v-.3l-.5-.1v.9M228.9 97.2l.3 .4M229.5 97.3l.4-.1v-.2h-.4v.5h.4M230.6 97h-.3v.3h.2l.1 .2h-.3M230.8 97.7h.7M231.8 96.7a.47 .47 0 0 1 .5 .4 .47 .47 0 0 1-.5 .5l-.2-.2v-.5zM233.1 96.7v.9l-.5-.9v.9" fill="none" stroke="#007170" stroke-width=".21"/>
<path d="M216.1 91.5h.4l.4 .4-.4 .5h-.4z" fill="#fff"/>
<path d="M216.1 91.5h.4l.4 .4-.4 .5h-.4z" fill="none" stroke="#805e00" stroke-width=".21"/>
<path d="M217.3 91.9h.5v-.4h-.5v.9M217.6 91.9l.2 .5M218.2 92.1l.4-.1-.2-.2-.2 .1v.4h.3M219.3 91.9h-.4l.1 .2h.3l-.1 .3-.3-.1M219.5 92.5h.6M220.8 91.5h-.3l-.2 .2 .1 .6h.4v-.3h-.2M221.7 91.5v.9l-.5-.9v.9M222.1 91.5h.3l.2 .2v.5l-.3 .2h-.2z" fill="none" stroke="#007170" stroke-width=".21"/>
<path d="M233.9 90.7h.5v.8h-.5l-.4-.4z" fill="#fff"/>
<path d="M233.9 90.7h.5v.8h-.5l-.4-.4z" fill="none" stroke="#805e00" stroke-width=".21"/>
<path d="M228.7 91.1l.5-.1v-.3l-.5-.1v.9M228.9 91.1l.3 .4M229.5 91.2l.4-.1v-.2h-.4v.5h.4M230.6 90.9h-.3v.3h.2l.1 .2h-.3M230.8 91.6h.7M231.8 90.6a.47 .47 0 0 1 .5 .5 .47 .47 0 0 1-.5 .4l-.2-.2v-.5zM233.1 90.6v.9l-.5-.9v.9" fill="none" stroke="#007170" stroke-width=".21"/>
<path d="M216.1 54.9h.4l.4 .5-.4 .4h-.4z" fill="#fff"/>
<path d="M216.1 54.9h.4l.4 .5-.4 .4h-.4z" fill="none" stroke="#805e00" stroke-width=".21"/>
<path d="M217.3 55.4h.4l.1-.2-.1-.3h-.4v.9M217.6 55.4l.2 .4M218.2 55.5l.4-.1-.1-.2h-.3v.5h.3M219.3 55.2h-.4v.3h.4l-.1 .3-.3-.1M219.5 55.9h.6M220.8 54.9h-.2l-.3 .2v.4l.3 .3 .2-.1v-.3h-.2M221.7 54.9v.9l-.5-.9v.9M222.1 54.9h.2l.3 .2v.4l-.3 .3h-.2z" fill="none" stroke="#007170" stroke-width=".21"/>
<path d="M233.9 54h.5v.9h-.5l-.4-.4z" fill="#fff"/>
<path d="M233.9 54h.5v.9h-.5l-.4-.4z" fill="none" stroke="#805e00" stroke-width=".21"/>
<path d="M228.7 54.4h.4l.1-.3-.5-.1v.9M228.9 54.4l.3 .5M229.5 54.6l.4-.1-.1-.2-.3 .1v.5h.4M230.6 54.4h-.3l.1 .2h.2v.3h-.3M230.8 54.9h.7M231.6 54.1h.6v.5l-.1 .3-.5-.1zM233.1 54v.9l-.5-.9v.9" fill="none" stroke="#007170" stroke-width=".21"/>
<path d="M216.1 61h.4l.4 .5-.4 .4h-.4z" fill="#fff"/>
<path d="M216.1 61h.4l.4 .5-.4 .4h-.4z" fill="none" stroke="#805e00" stroke-width=".21"/>
<path d="M217.3 61.5h.4l.1-.2-.1-.3h-.4v.9M217.6 61.5l.2 .4M218.2 61.5h.4l-.1-.2h-.3v.5h.3M219.3 61.3h-.4v.2l.4 .1-.1 .3-.3-.1M219.5 62h.6M220.8 61h-.2l-.3 .2v.4l.3 .3 .2-.1v-.3h-.2M221.7 61v.9l-.5-.9v.9M222.1 61h.2l.3 .2v.4l-.3 .3h-.2z" fill="none" stroke="#007170" stroke-width=".21"/>
<path d="M233.9 60.1h.5v.9h-.5l-.4-.4z" fill="#fff"/>
<path d="M233.9 60.1h.5v.9h-.5l-.4-.4z" fill="none" stroke="#805e00" stroke-width=".21"/>
<path d="M228.7 60.5h.4l.1-.3-.5-.1v.9M228.9 60.5l.3 .5M229.5 60.7l.4-.1-.1-.2h-.3v.6h.4M230.6 60.4h-.3l.1 .3h.2v.3h-.3M230.8 61h.7M231.8 60.1l.4 .3-.1 .6-.5-.1v-.6zM233.1 60.1v.9l-.5-.9v.9" fill="none" stroke="#007170" stroke-width=".21"/>
<path d="M216.1 67.1h.4l.4 .5-.4 .4h-.4z" fill="#fff"/>
<path d="M216.1 67.1h.4l.4 .5-.4 .4h-.4z" fill="none" stroke="#805e00" stroke-width=".21"/>
<path d="M217.3 67.6h.4l.1-.4-.1-.1h-.4v.9M217.6 67.6l.2 .4M218.2 67.6h.4l-.1-.2h-.3v.5h.3M219.3 67.4h-.4v.2l.4 .1-.1 .3-.3-.1M219.5 68.1h.6M220.8 67.1h-.2l-.3 .2v.4l.3 .3 .2-.1v-.3h-.2M221.7 67.1v.9l-.5-.9v.9M222.1 67.1h.2l.3 .2v.4l-.3 .3h-.2z" fill="none" stroke="#007170" stroke-width=".21"/>
<path d="M233.5 66.7l.4-.4h.5v.8h-.5z" fill="#fff"/>
<path d="M233.9 66.3h.5v.8h-.5l-.4-.4z" fill="none" stroke="#805e00" stroke-width=".21"/>
<path d="M228.7 66.6h.5v-.3l-.5-.1v.9M228.9 66.6l.3 .5M229.5 66.8l.4-.1v-.2h-.4v.6h.4M230.6 66.5h-.3l.1 .3h.2v.3h-.3M230.8 67.1h.7M231.8 66.2a.47 .47 0 0 1 .4 .3 .47 .47 0 0 1-.1 .6l-.5-.1v-.6zM233.1 66.2v.9l-.5-.9v.9" fill="none" stroke="#007170" stroke-width=".21"/>
<path d="M216.1 85.4h.4l.4 .4-.4 .5h-.4z" fill="#fff"/>
<path d="M216.1 85.4h.4l.4 .4-.4 .5h-.4z" fill="none" stroke="#805e00" stroke-width=".21"/>
<path d="M217.3 85.8h.5v-.4h-.5v.9M217.6 85.8l.2 .5M218.2 85.9l.4-.1-.2-.1-.2 .1v.4h.3M219.3 85.8h-.4v.1l.4 .1-.1 .3-.3-.1M219.5 86.4h.6M220.8 85.4h-.3l-.2 .2v.4l.3 .3 .2-.1v-.4h-.2M221.7 85.4v.9l-.5-.9v.9M222.1 85.4h.3l.2 .2v.4l-.3 .3h-.2z" fill="none" stroke="#007170" stroke-width=".21"/>
<path d="M233.5 85l.4-.4h.5v.8h-.5z" fill="#fff"/>
<path d="M233.9 84.6h.5v.8h-.5l-.4-.4z" fill="none" stroke="#805e00" stroke-width=".21"/>
<path d="M228.7 85l.5-.1v-.3l-.5-.1v.9M228.9 85l.3 .4M229.5 85.1l.4-.1v-.2h-.4v.5h.4M230.6 84.8h-.3v.3l.3 .1-.1 .2-.2-.1M230.8 85.5h.7M231.8 84.5a.47 .47 0 0 1 .5 .5 .47 .47 0 0 1-.5 .4l-.2-.1v-.6zM233.1 84.5v.9l-.5-.9v.9" fill="none" stroke="#007170" stroke-width=".21"/>
<path d="M216.1 73.2h.4l.4 .5-.4 .4h-.4z" fill="#fff"/>
<path d="M216.1 73.2h.4l.4 .5-.4 .4h-.4z" fill="none" stroke="#805e00" stroke-width=".21"/>
<path d="M217.3 73.7h.4l.1-.4-.1-.2h-.4v1M217.6 73.7l.2 .4M218.2 73.7h.4l-.1-.2h-.3v.5h.3M219.3 73.5h-.4v.2l.4 .1-.1 .3-.3-.1M219.5 74.2h.6M220.8 73.2l-.2-.1-.3 .3v.4l.3 .3 .2-.1v-.3h-.2M221.7 73.1v1l-.5-1v1M222.1 73.1h.2l.3 .3v.4l-.3 .3h-.2z" fill="none" stroke="#007170" stroke-width=".21"/>
<path d="M233.9 72.4h.5v.8h-.5l-.4-.4z" fill="#fff"/>
<path d="M233.9 72.4h.5v.8h-.5l-.4-.4z" fill="none" stroke="#805e00" stroke-width=".21"/>
<path d="M228.7 72.8l.5-.1v-.3l-.5-.1v.8M228.9 72.8l.3 .3M229.5 72.9l.4-.1v-.2h-.4v.5h.4M230.6 72.6h-.3v.3h.2l.1 .2h-.3M230.8 73.2h.7M231.8 72.3a.47 .47 0 0 1 .4 .3 .47 .47 0 0 1-.1 .5h-.5v-.6zM233.1 72.3v.8l-.5-.8v.8" fill="none" stroke="#007170" stroke-width=".21"/>
<path d="M216.1 79.3h.4l.4 .5-.4 .4h-.4z" fill="#fff"/>
<path d="M216.1 79.3h.4l.4 .5-.4 .4h-.4z" fill="none" stroke="#805e00" stroke-width=".21"/>
<path d="M217.3 79.8h.4l.1-.2v-.3h-.5v.9M217.6 79.8l.2 .4M218.2 79.8h.4l-.1-.2h-.3v.5h.3M219.3 79.6h-.4v.2l.4 .1-.1 .3-.3-.1M220.8 79.3h-.3l-.2 .2v.4l.3 .3 .2-.1v-.3h-.2M221.7 79.3v.9l-.5-.9v.9M222.1 79.3h.3l.2 .2v.4l-.3 .3h-.2zM219.5 80.3h.6" fill="none" stroke="#007170" stroke-width=".21"/>
<path d="M233.9 78.5h.5v.8h-.5l-.4-.4z" fill="#fff"/>
<path d="M233.9 78.5h.5v.8h-.5l-.4-.4z" fill="none" stroke="#805e00" stroke-width=".21"/>
<path d="M228.7 78.9l.5-.1v-.3l-.5-.1v.9M228.9 78.9l.3 .4M229.5 79l.4-.1v-.2h-.4v.5h.4M230.6 78.7h-.3v.3l.3 .1-.1 .2-.2-.1M230.8 79.4h.7M231.8 78.4a.47 .47 0 0 1 .5 .5 .47 .47 0 0 1-.5 .4l-.2-.1v-.6zM233.1 78.4v.9l-.5-.9v.9" fill="none" stroke="#007170" stroke-width=".21"/>
<g fill="none" stroke="#001192" stroke-width=".21">
<path d="M31.7 29.6l.8 .9M32.5 29.6l-.8 .9M40.5 29.6l.7 .9M41.2 29.6l-.7 .9M268.8 82.8l.9 .8M269.7 82.8l-.9 .8M140.7 118.6l.8 .8M141.5 118.6l-.8 .8M175.5 118.6l.9 .8M176.4 118.6l-.9 .8M107.5 135.1l.9 .9M108.4 135.1l-.9 .9"/>
<path d="M140.7 125.6l.8 .8M140.7 132.5l.8 .8M140.7 134.3l.8 .8M140.7 136l.8 .8M140.7 130.8l.8 .9M140.7 123.8l.8 .8M141.5 125.6l-.8 .8M141.5 132.5l-.8 .8M141.5 134.3l-.8 .8M141.5 136l-.8 .8M141.5 130.8l-.8 .9M141.5 123.8l-.8 .8"/>
<path d="M175.5 136l.9 .8M175.5 137.7l.9 .9M175.5 125.6l.9 .8M175.5 134.3l.9 .8M175.5 120.3l.9 .9M175.5 130.8l.9 .9M175.5 123.8l.9 .8M176.4 136l-.9 .8M176.4 137.7l-.9 .9M176.4 125.6l-.9 .8M176.4 134.3l-.9 .8M176.4 120.3l-.9 .9"/>
<path d="M176.4 130.8l-.9 .9M176.4 123.8l-.9 .8M175.5 143l.9 .8M175.5 146.5l.9 .8M175.5 157l.9 .7M175.5 158.7l.9 .8M176.4 143l-.9 .8M176.4 146.5l-.9 .8M176.4 157l-.9 .7M176.4 158.7l-.9 .8M175.5 162.1l.9 .9M175.5 163.9l.9 .9"/>
<path d="M175.5 174.3l.9 .9M175.5 170.9l.9 .8M175.5 167.4l.9 .8M175.5 172.6l.9 .9M175.5 169.2l.9 .8M175.5 165.6l.9 .8M175.5 160.4l.9 .9M176.4 162.1l-.9 .9M176.4 163.9l-.9 .9M176.4 174.3l-.9 .9M176.4 170.9l-.9 .8M176.4 167.4l-.9 .8"/>
<path d="M176.4 172.6l-.9 .9M176.4 169.2l-.9 .8M176.4 165.6l-.9 .8M176.4 160.4l-.9 .9"/>
</g>
<g fill="#00a200">
<circle cx="209.1" cy="122.5" r=".38"/>
<circle cx="209.1" cy="134.7" r=".38"/>
<circle cx="209.1" cy="140.8" r=".38"/>
<circle cx="209.1" cy="128.6" r=".38"/>
<circle cx="278.8" cy="105.9" r=".38"/>
<circle cx="258.7" cy="135.5" r=".38"/>
<circle cx="257" cy="112.9" r=".38"/>
<circle cx="264.9" cy="144.3" r=".38"/>
<circle cx="258.7" cy="144.3" r=".38"/>
<circle cx="209.1" cy="110.2" r=".38"/>
<circle cx="209.1" cy="116.4" r=".38"/>
<circle cx="107.9" cy="158.2" r=".38"/>
<circle cx="107.9" cy="159.9" r=".38"/>
<circle cx="95.7" cy="165.2" r=".38"/>
<circle cx="248.3" cy="21.3" r=".38"/>
<circle cx="248.3" cy="37.9" r=".38"/>
<circle cx="205.6" cy="49.3" r=".38"/>
<circle cx="209.1" cy="49.3" r=".38"/>
<circle cx="209.1" cy="79.7" r=".38"/>
<circle cx="209.1" cy="91.9" r=".38"/>
<circle cx="209.1" cy="85.8" r=".38"/>
<circle cx="209.1" cy="98" r=".38"/>
<circle cx="209.1" cy="104.1" r=".38"/>
<circle cx="209.1" cy="73.7" r=".38"/>
<circle cx="209.1" cy="67.6" r=".38"/>
<circle cx="209.1" cy="61.5" r=".38"/>
<circle cx="209.1" cy="55.4" r=".38"/>
<circle cx="202.1" cy="21.3" r=".38"/>
<circle cx="210.8" cy="17.9" r=".38"/>
<circle cx="214.3" cy="21.3" r=".38"/>
<circle cx="210.8" cy="21.3" r=".38"/>
<circle cx="73.1" cy="82.4" r=".38"/>
<circle cx="107.9" cy="82.4" r=".38"/>
<circle cx="36.5" cy="82.4" r=".38"/>
<circle cx="85.3" cy="20.5" r=".38"/>
<circle cx="79.2" cy="20.5" r=".38"/>
<circle cx="94.1" cy="22.3" r=".38"/>
</g>
<g fill="none" stroke="#aaa" stroke-width=".21">
<path d="M40.7 45.4l-.3-.1-.2 .3 .2 .5h.3M40.7 47.2l-.3-.1a.43 .43 0 0 0-.2 .5 .43 .43 0 0 0 .5 .2M41.1 45.4h.5v.2l-.5 .5h.5M41.1 47.2h.5v.2l-.5 .5h.5M42.4 45.6l-.1 .2h-.3v-.5l.4 .1v.6l-.4 .1M42.4 47.4l-.3 .2-.2-.2 .1-.3 .4 .1-.1 .6-.3 .1M42.7 47.1h.6l-.4 .3h.3l.1 .3-.2 .2-.4-.1M42.8 45.5l.2-.2v.8M42.8 46.1h.5M43.5 47.1h.6l-.3 .8M44 45.3h-.4v.4l.4-.1 .1 .2-.1 .3h-.4M44.5 45.3h.3l.1 .2-.1 .6h-.3l-.1-.1z"/>
<path d="M44.8 47.1l-.4 .1v.6h.5v-.4l-.5 .1M45.2 47.2h.5v.2l-.5 .5h.5M45.3 45.4l.3-.1v.8a.39 .39 0 0 1-.4-.3 .39 .39 0 0 1 .1-.4zM46.5 45.3h-.3l-.1 .7v.1h.5l-.1-.5h-.4v.2M46.6 47.1h-.5v.3h.5v.4h-.5M77.4 45.4l-.4-.1-.2 .3 .2 .5h.4M77.4 47.2l-.4-.1a.44 .44 0 0 0-.1 .5 .44 .44 0 0 0 .5 .2M77.7 45.4l.4-.1 .1 .2-.6 .6h.6M77.7 47.2l.4-.1 .1 .2-.6 .6h.6M79 45.6l-.1 .2h-.3v-.4h.4v.6l-.1 .1h-.3M79 47.4l-.1 .2-.3-.1v-.3h.4v.5l-.4 .2M79.3 45.5l.3-.2v.8"/>
<path d="M79.3 47.1h.5l-.2 .3h.2v.4h-.5M79.3 46.1h.5M80.2 47.1h.6l-.5 .8M80.7 45.3h-.4l-.1 .4 .4-.1 .1 .5h-.5M81.1 45.3a.42 .42 0 0 1 .4 .4 .42 .42 0 0 1-.4 .4zM81.4 47.1h-.2l-.2 .3v.3l.4 .2 .1-.4h-.5M81.9 47.2l.4-.1 .1 .2-.6 .6h.6M82 45.3a.42 .42 0 0 1 .4 .4 .42 .42 0 0 1-.4 .4zM83.1 45.3l-.4 .2v.6h.4v-.5h-.3l-.1 .2M83.1 47.1h-.4v.3h.4l.1 .3-.1 .2-.4-.1M112.3 46.2a.42 .42 0 0 0-.6 .4 .42 .42 0 0 0 .6 .4M112.3 48l-.5-.1-.1 .4 .1 .5 .5-.1"/>
<path d="M112.6 46.2l.3-.1 .2 .3-.6 .7h.6M112.6 48l.4-.1 .1 .3-.6 .6h.6M113.9 46.6l-.4 .1-.1-.4 .1-.2 .4 .1v.6l-.5 .3M113.9 48.3l-.1 .1h-.4v-.5l.5 .1v.6l-.5 .2M114.2 46.4l.3-.3v1M114.2 47.9h.5l-.2 .4h.2v.4h-.5M114.2 47.1h.5M115.1 47.9h.5l-.4 .9M115.5 46.1h-.4v.5l.3-.1 .2 .4-.2 .2-.3-.1M116.1 46.1a.48 .48 0 0 1 .3 .5 .48 .48 0 0 1-.3 .5l-.2-.2v-.6zM116.3 47.9l-.4 .2v.6l.4 .1v-.5h-.3l-.1 .1M116.7 48l.5-.1 .1 .3-.6 .6h.6"/>
<path d="M116.9 46.1a.48 .48 0 0 1 .4 .5 .48 .48 0 0 1-.4 .5l-.2-.2v-.6zM117.9 46.1l-.2 .1-.2 .7 .2 .2 .3-.1v-.4l-.3-.1-.2 .1M118 47.9h-.4l-.1 .4h.4l.1 .4h-.5M108.5 189.8v-.8l.4 .6 .2-.6v.8M109.8 189v.7l-.3 .1M110 188l.3-.8 .3 .8M110.1 187.9h.4M110.1 189h.6M110.4 189v.8M110.9 187.7h.3l.2-.3-.2-.2h-.3v.8M110.9 189.4h.4v-.4h-.4v.8M111.8 189.2l.2-.2v.8"/>
<path d="M111.8 187.6h.2M111.8 189.8h.5M112.2 187.2h-.4v.8h.4M112.5 188v-.8l.4 .7 .2-.7v.8M112.6 189.1l.3-.1 .1 .3-.5 .5h.5M113.9 189h-.5v.4l.4-.1 .1 .4h-.5M114.3 189.1l.3-.1v.7a.39 .39 0 0 1-.4-.2 .39 .39 0 0 1 .1-.4zM162.4 189.2l-.4-.1-.1 .2v.5l.1 .2 .4-.1M163 189.1l-.3 .6h.6M163.1 189.4v.6M164.1 189.5l-.1 .1h-.3v-.5h.3l.1 .2-.2 .7h-.2M164.4 189.2l.4-.1 .1 .3-.6 .6h.6"/>
<path d="M165.4 189.1l-.1 .6h.5M165.7 189.4v.6M166 189.4l.3-.3v.9M166 190h.5M167.4 189.5l-.1 .1h-.3v-.5l.4 .1v.6l-.4 .2"/>
</g>
<g fill="none" stroke="#970091" stroke-width=".21">
<path d="M81.2 30.5l.3-.1 .2 .2-.6 .7h.6M81.2 34l.4-.1 .1 .3-.6 .6h.6M81.6 32.2h-.4v.4l.4-.1 .1 .2-.1 .3-.4-.1M82 30.4l.2 .9 .3-.9M82 33.9l.2 .9 .3-.9M82 32.5l.3-.1 .2 .2v.4M82 32.4v.6M82.5 32.6v-.2l.3 .1v.5M83.1 33l.3-.8 .2 .8M83.2 32.8h.4M133.9 29l.8 .3-.8 .3M134.7 29.9v.5l-.5-.5h-.3v.5"/>
<path d="M137.2 30.5h-.4l-.1 .4 .5-.1v.4h-.5M137.3 32.3h.5v.3l-.5 .5h.5M137.7 30.8l.1-.1 .2 .2v.4M137.7 30.7v.6M138 30.9l.1-.2 .2 .1v.5M138.1 32.3l.2 .8 .4-.8M138.7 31.3l.2-.8 .4 .8M138.8 31.1h.4M152 29l.8 .3-.8 .3M152.8 29.9v.5l-.5-.5-.3 .1 .1 .4M155.5 30.5h-.4l-.1 .4 .4-.1 .1 .4h-.5M155.6 32.3h.5v.3l-.5 .5h.5"/>
<path d="M156 30.8h.3v.5M156 30.7v.6M156.3 30.9l.2-.2 .2 .2v.4M156.4 32.3l.3 .8 .3-.8M157 31.3l.2-.8 .4 .8M157.1 31.1h.4M200.9 29.2l.9 .3-.9 .3M201.8 30.1v.5l-.5-.5h-.3v.5M204.3 30.5h-.3l-.1 .4 .4-.1v.5l-.4-.1M204.5 32.3h.4l.1 .2-.6 .6h.6M204.7 30.8l.3-.1 .1 .2v.4M204.7 30.7v.6"/>
<path d="M205.1 30.9l.1-.2 .3 .1v.5M205.2 32.3l.3 .8 .3-.8M205.8 31.3l.3-.8 .2 .8M205.9 31.1h.3M24.7 74h-.4l-.1 .4h.5v.4h-.5M25.1 74.4l.4-.1v.6M25.1 74.3v.6M25.4 72.4h.5v.2l-.5 .5h.5M25.4 75.9h.5v.2l-.5 .5h.5M25.5 74.4h.4v.5M26.2 72.3l.2 .8 .3-.8M26.2 74.9l.2-.9 .3 .9"/>
<path d="M26.2 75.8l.2 .8 .3-.8M26.2 74.7h.5M61.3 74h-.4v.4l.3-.1 .2 .5-.2 .1-.3-.1M61.7 74.4h.4v.5M61.7 74.3v.6M62.1 72.4l.4-.1 .1 .3-.6 .5h.6M62.1 75.9l.4-.1 .1 .2-.6 .6h.6M62.1 74.4l.4-.1v.6M62.7 72.3l.4 .8 .2-.8M62.7 74.9l.4-.9 .2 .9M62.7 75.8l.4 .8 .2-.8M62.8 74.7h.4"/>
<path d="M96.2 74h-.4v.4l.3-.1 .2 .5-.2 .1-.3-.1M96.6 74.4l.3-.1v.6M96.6 74.3v.6M96.9 72.4h.5v.2l-.5 .5h.5M96.9 75.9h.5v.2l-.5 .5h.5M96.9 74.4h.5v.5M97.6 72.3l.4 .8 .2-.8M97.6 74.9l.4-.9 .2 .9M97.6 75.8l.4 .8 .2-.8M97.7 74.7h.4M266 69.9l.3-.2v.9M266 70.6h.5"/>
<path d="M267.2 69.7l-.3 .2v.6h.4v-.4l-.4-.1v.2M267.5 69.7l.4 .9 .2-.9M193.6 115.9h.5v.3l-.5 .5h.5M193.6 119.5h.5v.2l-.5 .5h.5M194.1 117.6h-.4l-.1 .4 .5-.1v.5h-.5M194.4 115.8l.2 .9 .4-.9M194.4 119.4l.2 .8 .4-.8M194.5 117.9h.2l.2 .1v.4M194.5 117.9v.5M194.9 118l.1-.1h.2v.5M195.6 118.4l.2-.8 .4 .8M195.7 118.2h.4"/>
<path d="M104.7 122.3l.3-.3v.8M104.7 122.8h.5M106 122l-.4 .2v.6h.4v-.5h-.3l-.1 .2M106.3 122l.3 .8 .2-.8"/>
</g>
<g fill="none" stroke="#a2a2a2" stroke-width=".21">
<path d="M30.9 14.9l-.4-.1a.44 .44 0 0 0-.1 .6 .44 .44 0 0 0 .5 .2M31.2 15.1h.3l.2 .1v.5M31.7 15.3l-.5 .1 .1 .3 .4-.1M32.1 15.1v.6M32.3 15.1l-.2 .1M33.2 14.9h.5v.2l-.5 .6h.5M34.3 14.7l-.3 .7h.5M34.5 15.1v.6M34.9 15.2h.4l.1-.3-.5-.1v.9M36.2 13v.6l-.3 .3M36.6 13.3l.2-.3v.9M36.6 13.9h.5"/>
<path d="M36.9 14.9l-.3-.1a.42 .42 0 0 0-.2 .5 .42 .42 0 0 0 .5 .3M37.2 15.2l.4-.1 .2 .4-.4 .2zM38.1 15.1h.2l.2 .1v.5M38.1 15.1v.6M38.9 15.1h.2l.2 .1v.5M38.9 15.1v.6M39.6 15.4l.4-.1v-.2l-.4 .1v.3l.2 .2 .2-.1M40.8 15.1h-.3l-.1 .1 .1 .5 .3-.1M41.1 15.1h.3M41.1 14.8v.7l.3 .2M41.7 15.1h.4v.5h-.4zM42.5 15.1v.6"/>
<path d="M42.8 15.1l-.3 .1M85.6 17.8h.3l.1-.3-.4-.1v.9l.4-.1v-.3l-.2-.1M86.4 17.7h.4l.1 .2-.2 .4-.3-.2zM87.2 17.7l.4 .1v.5M87.6 17.9h-.4l.1 .4 .3-.1M88 17.7v.6M88.2 17.7l-.2 .2M88.9 17.7h-.3l-.1 .2 .1 .4 .3-.1M88.9 17.4v.9M89.4 15.7v.6l-.3 .2M90 15.6l-.3 .7h.5M90.2 15.9v.6"/>
<path d="M90.2 17.7h-.2v.2l.3 .2-.1 .2-.2-.1M90.7 17.7v.4l.1 .2 .3-.1M91.1 17.7v.6M91.5 18.2l.3 .1 .1-.2v-.4h-.4v.8M92.3 18.2l.2 .1 .2-.2-.1-.4h-.3v.8M93 17.4v.7l.2 .2M93.5 17.7l.1 .6M93.9 17.7l-.4 .8M211.8 15.7h.5M211.8 13.9h.5M212.1 13.9v.9M212.1 15.7v.8"/>
<path d="M212.7 16.1h.4v-.4h-.4v.8M212.7 14.4h.3l.2-.4-.2-.1h-.3v.9M213.5 15.9l.2-.2v.8M213.5 16.5h.4M213.7 13.9l-.2 .6h.5M213.9 14.2v.6M214.3 15.7h.5v.3l-.5 .5h.5M215 15.7l.4 .8 .2-.8M215.9 16.1h.4l.1-.4h-.5v.8M250.2 17.4h.5M250.2 15.7h.5M250.4 15.7v.8"/>
<path d="M250.4 17.4v.9M251 17.9h.4l.1-.4-.5-.1v.9M251 16.1h.5v-.4h-.5v.8M252.3 17.4h-.4v.4h.4v.4h-.4M252.3 15.7h-.4v.4h.4l-.1 .4-.3-.1M252.6 17.4l.3 .9 .2-.9M250.2 33.9h.5M250.2 32.3h.5M250.4 32.3v.8M250.4 33.9v.9M251 34.5h.4l.1-.4-.1-.2h-.4v.9M251 32.7h.4l.1-.2v-.2h-.5v.8"/>
<path d="M251.8 33.9h.5l-.3 .4 .3 .1v.3h-.5M252.2 32.3h-.2l-.1 .1v.6h.4v-.4l-.3-.1-.1 .2M252.6 33.9l.3 .9 .2-.9M253.4 33.9h.5l-.2 .4 .2 .1v.3h-.5M40.3 43.5v.9h.3M40.5 41.8v.8l-.3 .1M40.9 44.1l.4-.1v-.1h-.4v.4l.2 .1h.2M40.9 41.9l.4-.1 .1 .3-.6 .6h.6M41.7 43.9l.1 .5 .3-.5M42.3 44.1l.5-.1-.1-.1h-.4v.4l.2 .1h.2M43.1 43.5v.8l.2 .1M43.3 44.5h.7"/>
<path d="M44.7 43.6l-.3-.1-.2 .2 .1 .2 .4 .2v.3h-.5M45 44.1l.5-.1-.1-.1h-.4v.5h.4M45.8 43.5v.8l.2 .1M46.2 44.1l.4-.1v-.1h-.4v.4l.2 .1h.2M47.4 43.9h-.4v.5h.4M47.7 43.9h.3M47.7 43.5v.8l.3 .1M76.9 43.5v.9h.4M77.1 41.8v.6l-.3 .3M77.5 41.8h.5l-.3 .4h.3v.4h-.5M77.5 44.1l.5-.1-.1-.1h-.4v.5h.4M78.2 43.9l.3 .5 .1-.5"/>
<path d="M78.9 44.1l.4-.1v-.1h-.4v.4l.2 .1h.2M79.8 43.5v.9M80 44.5h.7M81.3 43.6h-.4v.3l.4 .2v.3h-.4M81.6 44.1l.4-.1v-.1h-.4v.4l.2 .1h.2M82.5 43.5v.9M82.9 44.1l.3-.1v-.1h-.3v.5h.3M84 43.9h-.4v.1l.1 .4h.3M84.2 43.9h.4M84.4 43.5v.9h.2M111.8 44.4v.9h.4M112 42.7v.6l-.3 .2"/>
<path d="M112.4 45h.5l-.2-.3-.3 .1v.5h.4M112.9 42.7h-.5l-.1 .4h.6v.3h-.6M113.1 44.7l.2 .6 .2-.6M113.8 45h.4l-.1-.3-.3 .2v.3l.4 .1M114.6 44.4l.1 .9M114.9 45.4h.6M116.2 44.4h-.5l-.1 .2 .2 .3 .4 .1v.2l-.6 .1M116.5 45h.4l-.1-.3-.3 .2v.3l.4 .1M117.3 44.4l.1 .9M117.7 45h.4l-.1-.3-.3 .2v.3l.4 .1M118.9 44.8l-.3-.1-.2 .2 .1 .4h.4M119.1 44.7h.4"/>
<path d="M119.3 44.4v.9h.2M200.4 55.8h.5M200.7 55.8v.8M201.2 56.2l.5-.1v-.2l-.5-.1v.8M201.8 56.7h.7M201.9 57.5h.4M202.1 57.5v.8M202.7 58h.3l.2-.2-.2-.3h-.3v.8M202.7 56.1h.3M203.1 55.8h-.4v.8M203.4 55.8v.7l.2 .1h.4v-.8M203.4 57.5h.6l-.3 .3 .3 .2v.3l-.6-.1"/>
<path d="M204.4 56.1h.2M204.8 55.8h-.4v.8h.4M205.1 55.8v.8h.5M184.5 130.3h.2M184.9 129.9h-.4v.8h.4M185.2 130.2h.4v.5M185.2 130.1v.6M185.8 128.2l-.4-.1-.2 .2 .1 .2 .5 .1-.1 .3h-.5M186 130.2l.3-.1 .1 .2v.4h-.4l.1-.3h.3M186.1 128.1l.2 .8 .1-.6 .2 .6 .2-.8M186.9 129.9v.8h.2l.1-.5h-.3M187.1 128.3l.3-.2v.8"/>
<path d="M187.1 128.9h.5M187.6 129.9l.1 .8M188 130.5l.5-.1-.2-.3-.3 .1v.5h.4M197.9 154.3h.6M197.9 157.7h.6M197.9 152.5h.6M197.9 156h.6M198.2 152.5v.9M198.2 154.3v.8M198.2 156v.9M198.2 157.7v.9M198.7 154.7h.4v-.4h-.4v.8"/>
<path d="M198.7 158.2h.3l.2-.3-.2-.2h-.3v.9M198.7 153h.3l.2-.4-.2-.1h-.3v.9M198.7 156.5h.3l.2-.2-.1-.3h-.4v.9M199.4 155.2h.7M199.4 158.7h.7M199.6 152.7l.2-.2v.9M199.6 156.1l.4-.1 .1 .3-.6 .6h.6M199.6 153.4h.5M200.2 154.3v.8h.5M200.2 157.7v.9h.5M200.9 154.7h.3M200.9 158.2h.3"/>
<path d="M201.3 154.3h-.4v.8h.4M201.3 157.7h-.4v.9h.4M201.8 154.3h.4l.1 .5-.2 .3h-.3zM201.8 157.7a.49 .49 0 0 1 .4 .3 .49 .49 0 0 1-.1 .6h-.3zM203.1 154.3h-.3l-.2 .1v.5l.2 .2 .3-.1M203.1 157.8l-.2-.1-.3 .3v.4l.2 .2 .3-.1M203.4 154.3h.6l-.4 .3h.3l.1 .2-.1 .3-.5-.1M203.6 157.7l-.2 .6h.6M203.9 158.1v.5M215.5 149.5h.3l.2-.3-.2-.2h-.3v.9M215.6 149.5l.4 .4M215.7 147.3v.6l-.3 .3"/>
<path d="M216.1 147.3h.6l-.5 .9M217 149.3l.4 .1v.5h-.4M217 149v.9M217.8 149.3l.1 .6M218.1 149.3l-.3 .9M218.4 149.9h.5l-.1-.6h-.4v.9M219.3 149.3h.3v.6M219.6 149.5l-.4 .2 .2 .2h.2M220.3 149.3h-.3v.2l.4 .3-.2 .1h-.2M221.1 149.3h-.4v.3l.4 .1-.1 .2h-.3M249.6 144.7h.5M249.8 144.7v.8"/>
<path d="M250.4 145.1h.4v-.4h-.4v.8M251.2 142.9h.5M251.5 142.9v.9M251.7 144.7l-.5 .1v.2l.5 .3-.1 .2h-.4M252 143.4l.5-.1v-.3l-.5-.1v.9M252 144.7h.4l.2 .2v.5l-.2 .1h-.4zM252.7 142.9h.6l-.3 .9M252.8 145.5l.3-.8 .3 .8M252.9 145.3h.4M269.4 144.7h.5M269.4 142.9h.5M269.7 142.9v.9"/>
<path d="M269.7 144.7v.8M270.2 145.1h.4l.1-.3-.5-.1v.8M270.2 143.4l.5-.1v-.3l-.5-.1v.9M271.2 143.3l-.2-.2 .4-.2 .1 .3-.4 .1v.5h.3l.1-.3-.1-.2M271.5 144.7h-.4l-.1 .2 .5 .5-.1 .1h-.4M272.4 144.8l-.4-.1-.1 .2v.5l.1 .1h.4M272.8 144.7v.8h.4M160.3 177.8l.1 .8h.4v-.8M160.3 179.9h.3M160.7 179.6h-.4v.8h.4M161.1 177.9h.5v.2l-.5 .5h.5M161.5 179.6l-.5 .1v.1l.5 .4-.1 .2-.4-.1"/>
<path d="M161.9 180l.5-.1v-.2l-.5-.1v.8M162.7 179.6h.5l-.2 .2 .2 .2v.2l-.1 .2-.4-.1M163.6 179.7l.4-.1 .1 .2-.6 .6h.6M165.9 179.6h-.4l-.1 .1 .5 .4v.2h-.5M166.3 179.6h.5l-.3 .2 .3 .1v.4h-.5M168.2 179.6h.4l.1 .1v.5l-.2 .2h-.3zM169.8 179.8l.2 .6 .2-.6M170.5 179.6v.8M170.7 179.9l.3 .5M171 179.6l-.5 .4M171.4 179.6v.1M171.4 179.8v.6"/>
<path d="M171.7 179.8h.3M171.8 179.6v.6l.2 .2M172.8 179.7l-.3-.1-.2 .1v.5l.2 .2 .3-.1M107.1 185.8h.4v-.2l-.4-.1v.8h.3l.2-.3-.2-.2M107.9 185.8v.4l.2 .1h.3M108.4 185.8v.5M108.6 185.8h.4M108.7 185.5v.7l.3 .1M109.1 185.8h.4M109.2 185.5v.7l.3 .1M109.7 185.8h.4v.5h-.4zM110.6 185.8h.3v.5"/>
<path d="M110.6 185.8v.5M111 183.7l-.5 .1v.3l.5 .2-.1 .3h-.4M111.2 183.7l.3 .9 .2-.6 .1 .6 .2-.9M112 186.3v-.8l.3 .6 .3-.6v.8M112.3 183.8h.5v.3l-.5 .5h.5M112.9 185.8h.5v.5M113.4 185.9l-.5 .1 .1 .3h.4M113.8 185.8h.3v.5M113.8 185.8v.5M114.5 185.8v.4l.2 .1h.3M115 185.8v.5M115.3 185.8h.4v.5"/>
<path d="M115.7 185.9l-.4 .1 .1 .3h.3M116.2 185.5v.8M135.3 184.7v-.8l.2 .6 .4-.6v.8M135.3 190.8v-.8l.2 .6 .4-.6v.8M135.3 182.1v.9M135.3 188.3v.8M135.3 182.5h.5M135.3 188.6h.5M135.8 182.1v.9M135.8 188.3v.8M136.1 182.2l.4-.1 .1 .2-.5 .7h.5M136.1 188.5l.3-.2v.8"/>
<path d="M136.1 189.1h.5M136.2 184.3l.4-.2v.6h-.3zM136.3 190.3l.3 .1v.4h-.3l-.1-.1zM137.1 184.1v.6h.3M137.1 190.3v.5l.3-.1M137.4 184.1v.6M137.4 190.3v.5M137.8 184.2l.3-.1 .2 .2v.4M137.8 190.4h.5v.4M137.8 184.1v.6M137.8 190.3v.5M138.5 184.1h.3"/>
<path d="M138.5 190.3h.3M138.7 183.9v.8h.1M138.7 190v.8h.1M139.1 183.9v.1M139.1 190v.1M139.1 184.1v.6M139.1 190.3v.5M139.5 184.2l.3-.1 .1 .2v.4M139.5 190.4h.4v.4M139.5 184.1v.6M139.5 190.3v.5M140.7 184.1v.9h-.3"/>
<path d="M140.7 184.2l-.2-.1-.2 .2 .1 .4h.3M140.7 190.8h-.3v-.5h.3v.8h-.3M141.1 183.9v.8M141.1 190v.8M141.1 184.3h.5M141.1 190.4h.5M141.6 183.9v.8M141.6 190v.8M142 184.3l.3-.2 .2 .2-.1 .4h-.3zM142.1 190.3h.3v.5h-.3zM142.8 183.9v.8h.2M142.8 190v.7l.2 .1"/>
<path d="M143.3 184.5l.4-.1-.2-.3-.2 .1v.5h.3M143.3 190.6l.4-.1-.1-.2h-.3v.5h.3M143.8 184.8h.7M143.8 190.9h.7M144.7 184.3h.4l.1-.2-.2-.2h-.3v.8M144.7 190.5h.3l.2-.3-.2-.2h-.3v.8M145.5 184.2l.3-.1 .2 .2v.4h-.5l.1-.3h.4M145.5 190.3l.5 .1v.4h-.5l.1-.3h.4M146.7 183.9v.8h-.3l-.1-.4 .2-.2 .2 .1M146.7 190v.8h-.3v-.5h.3M164.4 180.1h.7M166.6 190.8v1"/>
<path d="M166.9 189.1v.8l-.4 .1M167 190.7l.2-.1 .2 .1-.4 .5h.4M167.2 180.1h.6M167.7 189.1l-.4 .2v.6l.4 .1v-.5h-.3l-.1 .1M168.2 190.9l-.2-.1-.3 .3v.4l.3 .3 .2-.1M169.1 180.1l.4-.1v-.2l-.4 .1v.3l.1 .2 .3-.1M169.7 191.2l-.5 .1v.4h.5M169.7 190.8v1M170 191.4l.4-.1v-.1l-.4 .1v.3l.2 .2 .2-.1M170.8 191.2l.4 .1v.4h-.4M170.8 190.8v1M171.6 191.2v.5h.4"/>
<path d="M172 191.2v.6M172.8 191.7h-.4l.1-.5h.3v.6l-.1 .2h-.3"/>
</g>
<g fill="none" stroke="#007170" stroke-width=".21">
<path d="M15.7 22.7a.41 .41 0 0 0-.5 .4 .41 .41 0 0 0 .6 .3v-.3h-.1M16.7 22.6v.9l-.5-.9v.9M17.1 22.6a.47 .47 0 0 1 .5 .5 .47 .47 0 0 1-.5 .4zM78.6 37.5l-.3-.1-.2 .3v.4l.2 .2h.3v-.4h-.2M79.4 37.4v.9l-.4-.9v.9M79.8 37.4h.3l.2 .3v.4l-.2 .2h-.3zM81.1 25.2h.6l-.3 .4 .3 .1v.3l-.6 .1M81.2 29.1h.3l.2-.1-.1-.3h-.4v.8h.5v-.3l-.2-.1M81.2 24h.4l.1-.4-.5-.1v.9M81.2 26.9h.2l.3 .3v.4l-.3 .2h-.2zM81.4 24l.3 .4M82 29.5l.3-.8 .2 .8"/>
<path d="M82 26.9h.5l-.2 .4h.2v.5h-.5M82 25.2v.9M82 29.3h.5M82.1 25.8l.3 .3M82.4 25.6l-.4 .3M82.5 23.9l-.3 .1-.2-.1 .1-.4 .4 .1v.7l-.4 .1M82.7 28.7h.5M83 28.7v.8M83.4 28.7h.5M83.6 28.7v.8M84 29.6h.7M84.8 28.8h.5v.7h-.5z"/>
<path d="M86.3 28.7v.8l-.5-.8v.8M98.5 25.3l-.1-.1-.3 .3v.4l.2 .2h.3v-.4h-.1M99.5 25.2v.9l-.5-.9v.9M99.9 25.2h.3l.2 .3v.4l-.2 .2h-.3zM130.1 33.1h-.4l-.1 .4 .4-.1 .1 .5h-.5M130.4 33.1l.2 .8 .4-.8M131.1 34h.6M131.6 31.3a.47 .47 0 0 1 .5 .5 .47 .47 0 0 1-.5 .5zM131.9 33.2h.5l.1 .5-.2 .2h-.4zM132.8 31.3h-.4v.4h.4l.1 .4-.1 .2-.4-.1M133.3 33.1v.8l-.5-.8v.8M134.4 38.3h-.4l-.1 .2v.4l.2 .3 .3-.1v-.2h-.2"/>
<path d="M135.2 38.3v.9l-.4-.9v.9M135.6 38.3h.4l.1 .2v.4l-.2 .3h-.3zM137 24.8h.4l.1-.3-.5-.1v.8M137.2 24.8l.3 .4M137.4 26.1l-.3 .1-.1 .7 .3 .1 .2-.2-.2-.4-.3 .2M137.8 26.2l.4-.1 .1 .2-.6 .7h.6M137.8 24.6l.3-.2v.8M137.8 25.2h.5M138.7 26.2l.1-.1 .3 .1v.6l-.2 .2-.2-.2zM139.1 24.4h-.3l-.1 .4 .4-.1v.5l-.4-.1M147.8 33.1h.6l-.3 .3h.2l.1 .2-.1 .3h-.5M148.6 33.1l.3 .8 .3-.8"/>
<path d="M149.4 33.1h.5l-.2 .3 .2 .1v.4h-.5M149.9 31.3h.2l.3 .3v.4l-.3 .3h-.2zM150.1 34h.7M151 33.2h.5v.5l-.1 .2h-.4zM151.1 31.3l-.4 .3v.6l.3 .1 .2-.2-.2-.4-.3 .1M152.4 33.1v.8l-.5-.8v.8M152.6 38.3h-.3l-.2 .2v.4l.3 .3 .2-.1v-.2h-.1M153.6 38.3v.9l-.5-.9v.9M154 38.3l.4 .2v.4l-.2 .3h-.2zM155.3 26.2h.5v.3l-.5 .5h.5M155.4 24.8h.4v-.4h-.4v.8M155.5 24.8l.3 .4"/>
<path d="M156 26.1h.6l-.3 .9M156.1 24.6l.3-.2v.8M156.1 25.2h.5M157.1 26.1a.48 .48 0 0 1 .4 .4 .48 .48 0 0 1-.4 .5l-.1-.2v-.6zM157.4 24.4h-.3l-.1 .7 .1 .1 .4-.1-.1-.4h-.3l-.1 .2M191.6 33.5h.4v-.4h-.4v.8M192.4 33.5h.5v-.3l-.5-.1v.8M192.7 33.5l.2 .4M193.3 33.2h.5l.1 .5-.2 .2h-.4zM194.1 33.1h.5M194.4 33.1v.8M194.9 33.4l.3-.3v.8"/>
<path d="M194.9 33.9h.5M195.7 33.2h.5v.2l-.5 .5h.5M196.4 33.1l.4 .8 .2-.8M197.9 33.2h.6v.5l-.1 .2h-.5zM198.7 31.3a.47 .47 0 0 1 .5 .5 .47 .47 0 0 1-.5 .5zM199.4 33.1v.8l-.5-.8v.8M199.6 31.7v-.4l.4 .1v.3h-.4v.6l.4-.1v-.4l-.2-.1M201.4 38.3l-.4 .1v.6l.2 .2 .3-.1v-.2h-.2M202.3 38.3v.9l-.5-.9v.9M202.8 38.3h.3a.47 .47 0 0 1 .2 .6 .47 .47 0 0 1-.5 .3zM204 26.1h.6l-.3 .3 .3 .2v.2l-.1 .2-.5-.1M204.1 24.8h.4l.1-.3-.5-.1v.8"/>
<path d="M204.4 24.8l.2 .4M205 24.5l.4-.1 .1 .1-.5 .7h.5M205 26.1v.9M205.1 26.7l.2 .3M205.3 26.4l-.3 .3M205.9 24.4a.42 .42 0 0 1 .4 .4 .42 .42 0 0 1-.4 .4zM254.8 38.6v-.6l.4 .3v-.2l.3-.1 .2 .2-.1 .4M254.8 21.2v-.5l.4 .2 .1-.2h.3v.5M255.2 37.4l.1-.2h.3l.1 .2-.2 .4h-.2l-.2-.6-.3 .1v.4l.2 .1 .2-.2M255.3 39.4v-.5h-.5v.5h.9M255.3 21.9v-.4h-.5v.4h.9M255.7 20.1l-.9-.4v.6"/>
<path d="M255.7 38.9l-.4 .3M255.7 21.4l-.4 .4M256.7 38.9h.6l.2 .2a.48 .48 0 0 1-.5 .4 .48 .48 0 0 1-.5-.4zM256.7 21.5h.6l.2 .2a.48 .48 0 0 1-.5 .3 .48 .48 0 0 1-.5-.3zM257 38.5v-.3l-.3-.2-.2 .2v.3h1M257 21.1v-.4h-.4l-.1 .4h1M257.5 38l-.5 .3M257.5 20.7l-.5 .2M210.6 47.3l.5-.1 .1 .3-.6 .6h.6M210.6 59.5l.5-.1 .1 .3-.6 .6h.6M210.6 53.4l.5-.1 .1 .3-.6 .6h.6M210.6 45.9h.5l.1-.3-.2-.1h-.4v.8"/>
<path d="M210.6 58.2h.4l.2-.2-.2-.3h-.4v.8M210.6 52.1h.4l.2-.2-.2-.3h-.4v.8M210.8 45.9l.4 .4M210.8 58.2l.4 .3M210.8 52.1l.4 .3M211.4 47.2h.6l-.3 .9M211.4 59.4h.6l-.3 .9M211.4 53.3h.6l-.3 .9M211.5 45.5h.3l.2 .2-.6 .6h.6M211.5 57.7h.3l.2 .2-.6 .6h.6M211.5 51.6h.3l.2 .2-.6 .6h.6M212.3 57.7h.5l-.3 .3 .3 .1v.4h-.5"/>
<path d="M212.3 47.3l.4-.1 .1 .2v.5l-.2 .2a.48 .48 0 0 1-.3-.8zM212.3 59.5l.4-.1 .1 .2-.1 .6a.39 .39 0 0 1-.5-.2 .39 .39 0 0 1 .1-.5zM212.3 53.4l.4-.1 .1 .2-.1 .6a.39 .39 0 0 1-.5-.2 .39 .39 0 0 1 .1-.5zM212.3 45.7l.3-.2v.8M212.3 51.6h.4l.1 .4-.5 .4h.5M212.3 46.3h.5M16.5 70.5v.8l.2 .1M16.9 71.1l.5-.1-.1-.2-.4 .1v.4l.5 .1M18.1 70.5v.9h-.3l-.1-.5h.4M18.9 70.9l-.3-.1-.1 .1v.5h.4M19 71.5h.7M20.3 70.9h-.4v.4l.4 .1"/>
<path d="M20.7 70.9l.2-.1 .2 .1v.5M20.7 70.5v.9M21.5 70.9h.3v.5h-.3l-.1-.2 .2-.2h.2M22.3 70.9h.3v.5M22.3 70.8v.6M22.9 71.5h.6M23.7 70.6l.3-.1 .1 .4-.5 .5h.5M24.3 71.5h.7M25.3 68.7h.3l.2 .3v.4l-.2 .3h-.3zM25.4 70.5l.3 .2-.1 .7h-.3l-.2-.3v-.3zM26.2 69l.2-.3v1M26.2 69.7h.5"/>
<path d="M26.6 70.5v.9l-.4-.9v.9M28 79.3h-.3l-.2 .2v.4l.3 .3 .2-.1v-.3h-.2M28.9 79.3v.9l-.5-.9v.9M29.3 79.3h.3l.2 .2v.4l-.3 .3h-.2zM30.6 67.1h.4l.2 .2-.6 .7h.6M30.6 65.8h.5l.1-.4h-.6v.8M30.9 65.8l.3 .4M31.4 67.1h.6l-.3 .9M31.5 65.4h.5v.3l-.5 .5h.5M32.3 67.1h.3l.2 .1v.6l-.2 .2a.53 .53 0 0 1-.3-.9zM38.4 77.8l.3-.3v.9M38.4 78.4h.5"/>
<path d="M38.5 67.1h.3l.1 .1v.6l-.1 .2a.53 .53 0 0 1-.3-.9zM38.5 65.8h.4v-.4h-.4v.8M38.5 76.3h.4l.1-.4-.1-.1h-.4v.9M38.7 65.8l.3 .4M38.7 76.3l.3 .4M39.3 65.4h.6l-.4 .3h.3v.5l-.5-.1M39.4 67.6h.3l.2-.4-.2-.1h-.3v.9M39.4 77.5v.9M39.4 78.1l.3 .3M39.5 75.8l-.1 .6h.5M39.5 67.6l.4 .4M39.7 77.8l-.3 .3"/>
<path d="M39.8 76.1v.6M53.2 70.5v.9M53.6 71.1l.4-.1-.2-.2-.2 .1v.5h.3M54.7 70.5v.9h-.3l-.1-.5 .1-.1 .3 .1M55.5 70.9h-.4v.4l.4 .1M55.7 71.5h.6M56.9 70.9l-.3-.1-.1 .1 .1 .5h.3M57.3 70.9h.4v.5M57.3 70.5v.9M58.1 70.9h.3v.5h-.3v-.3l.3-.1M58.8 70.9l.3-.1 .2 .1v.5M58.8 70.8v.6"/>
<path d="M59.4 71.5h.7M60.3 70.8l.2-.3v.9M60.3 71.4h.5M61 71.5h.6M62 70.5l.4 .3-.2 .6-.4-.1v-.6zM62 68.7a.47 .47 0 0 1 .5 .5 .47 .47 0 0 1-.5 .5zM62.7 68.8h.5v.4l-.5 .5h.5M63.2 70.5v.9l-.5-.9v.9M64.6 79.3h-.3a.43 .43 0 0 0-.2 .5 .43 .43 0 0 0 .5 .3v-.3h-.2M65.5 79.3v.9l-.5-.9v.9M65.9 79.3h.4a.48 .48 0 0 1 .1 .6 .48 .48 0 0 1-.5 .3zM67.2 67.1h.5v.4l-.5 .5h.5"/>
<path d="M67.3 65.8h.4v-.4h-.4v.8M67.5 65.8l.3 .4M68.1 67.1h.5l-.4 .9M68.5 65.4h-.3v.1v.6h.4l-.1-.4h-.3v.2M69.1 67.1a.48 .48 0 0 1 .3 .4 .48 .48 0 0 1-.3 .5l-.2-.2v-.6zM75.1 77.8l.2-.3v.9M75.1 65.8h.4l.1-.4h-.5v.8M75.1 76.3l.5-.1v-.3l-.5-.1v.9M75.1 78.4h.5M75.3 67.1a.48 .48 0 0 1 .3 .4 .48 .48 0 0 1-.3 .5l-.2-.2v-.6zM75.3 65.8l.3 .4M75.3 76.3l.3 .4"/>
<path d="M75.9 67.6l.5-.1v-.4h-.5v.9M75.9 65.4h.6l-.4 .8M75.9 77.5v.9M76 78.1l.3 .3M76.1 76.2l-.2-.3 .2-.1 .3 .1v.2l-.4 .1-.1 .2 .2 .3 .3-.1v-.3l-.1-.1M76.2 67.6l.2 .4M76.3 77.8l-.4 .3M88 70.5l.1 .9M88.4 71.1l.4-.1-.1-.2-.3 .1v.4l.4 .1M89.6 70.5v.9h-.4l-.1-.5 .2-.1 .3 .1M90.3 70.9h-.3v.4l.3 .1M90.5 71.5h.7"/>
<path d="M91.8 70.9l-.3-.1-.2 .1 .1 .5h.4M92.2 70.9l.3-.1v.6M92.2 70.5v.9M93 70.9h.3v.5h-.3l-.1-.2 .4-.2M93.7 70.9l.3-.1 .1 .1v.5M93.7 70.8v.6M94.3 71.5h.7M95.3 70.5a.43 .43 0 0 1 .4 .5 .43 .43 0 0 1-.5 .4v-.7zM95.8 71.5h.7M96.8 68.7h.2l.3 .3v.4l-.3 .3h-.2zM96.9 70.5l.3 .2-.1 .7-.4-.1v-.6zM97.9 68.7l-.3 .6h.6"/>
<path d="M98 69.1v.6M98.1 70.5v.9l-.5-.9v.9M99.5 79.3h-.4l-.1 .2v.4l.2 .3 .3-.1v-.3h-.2M100.4 79.3v.9l-.5-.9v.9M100.7 79.3h.4l.2 .2v.4l-.3 .3h-.3zM102.1 67.1h.3l.2 .1-.5 .8h.5M102.2 65.8h.3l.1-.4h-.4v.8M102.4 65.8l.2 .4M102.9 67.1h.6l-.4 .9M102.9 65.6l.3-.2v.8M102.9 66.2h.6M103.8 65.4h.5v.3l-.5 .5h.5"/>
<path d="M104 67.1a.48 .48 0 0 1 .3 .4 .48 .48 0 0 1-.3 .5l-.2-.2v-.6zM110 67.2l.1-.1a.48 .48 0 0 1 .4 .4 .48 .48 0 0 1-.4 .5l-.1-.2zM110 77.8l.2-.3v.9M110 65.8h.4l.1-.4h-.5v.8M110 76.3l.5-.1v-.3l-.5-.1v.9M110 78.4h.5M110.2 65.8l.3 .4M110.2 76.3l.3 .4M110.8 67.6h.4l.1-.4-.1-.1h-.4v.9M110.8 65.6l.3-.2v.8M110.8 76l.3-.2v.9M110.8 77.5v.9"/>
<path d="M110.8 66.2h.5M110.8 76.7h.5M110.9 78.1l.3 .3M111 67.6l.3 .4M111.2 77.8l-.4 .3M111.6 65.4h.6l-.4 .3h.3v.5l-.5-.1M111.8 75.8l-.1 .6h.5M112.1 76.1v.6M210.6 71.7l.5-.1 .1 .3-.6 .6h.6M210.6 65.6l.5-.1 .1 .3-.6 .6h.6M210.6 77.8l.5-.1 .1 .3-.6 .6h.6M210.6 70.4h.4l.2-.4-.2-.2h-.4v1"/>
<path d="M210.6 64.3h.4l.2-.2-.2-.4h-.4v1M210.6 76.4h.4l.2-.3-.2-.2h-.4v1M210.8 70.4l.4 .4M210.8 64.3l.4 .4M210.8 76.4l.4 .5M211.4 71.6h.6l-.3 .9M211.4 65.5h.6l-.3 .9M211.4 77.7h.6l-.3 .9M211.5 69.9l.3-.1 .2 .3-.6 .7h.6M211.5 63.8l.3-.1 .2 .3-.6 .7h.6M211.5 76l.3-.1 .2 .3-.6 .7h.6M212.3 71.7l.4-.1 .1 .2-.1 .6a.39 .39 0 0 1-.5-.2 .39 .39 0 0 1 .1-.5z"/>
<path d="M212.3 65.6l.4-.1 .1 .2-.1 .6a.39 .39 0 0 1-.5-.2 .39 .39 0 0 1 .1-.5zM212.3 77.8l.4-.1 .1 .2-.1 .6a.39 .39 0 0 1-.5-.2 .39 .39 0 0 1 .1-.5zM212.5 63.7l-.2 .6h.5M212.8 69.8h-.5v.5h.5v.4h-.5M212.8 75.9l-.5 .3v.6l.4 .1 .1-.5-.3-.1-.2 .1M212.8 64.1v.6M247.2 75.8h.5M247.5 75.8v.9M248.5 75.9l-.3-.1-.2 .2v.4l.2 .3 .3-.1M248.7 76.7l.4-.9 .2 .9M248.8 76.4h.5M250.1 76.2l-.2 .2-.3-.1v-.4l.3-.1 .2 .1-.2 .7-.2 .1"/>
<path d="M250.9 75.8h-.5v.4l.4-.1 .1 .4-.1 .2-.4-.1M251.7 75.8h-.4v.4h.4l-.1 .5-.3-.1M252.6 75.8h-.5l-.1 .4h.6v.4h-.6M252.9 69.3h.4v-.5h-.4v.9M253 76.3h.3l.2-.4-.2-.1h-.3v.9M253.1 69.3l.3 .4M253.7 68.8h.5l-.3 .4h.3v.5l-.5-.1M253.7 75.8l.2 .9 .2-.7 .1 .7 .3-.9M253.7 70.7l.4-.1 .1 .2v.5l-.2 .2a.48 .48 0 0 1-.3-.8zM253.9 74.1l.1 .8 .4-.1v-.7M254.6 71l.4-.1-.1-.3h-.3v.9M254.8 74.1h.5l-.3 .3h.3v.5l-.5-.1"/>
<path d="M254.8 71l.2 .5M254.8 76.3h.4l.1-.4-.1-.1h-.4v.9M255 69.2l-.1 .1h-.2l-.1-.4h.4v.6l-.3 .2M255 76.3l.3 .4M262.7 75.2v.3l.4 .2 .5-.2-.1-.4h-.3v.2M262.7 74.2h.9l-.9 .6h.9M262.7 73.5l.4-.2 .4 .1 .1 .4h-.9zM266 68.2l.3-.2v.8M266 68.8h.5M266.5 66.3l-.2-.1-.3 .3v.4l.2 .2 .3-.1M266.9 66.3l.3-.1 .2 .2-.5 .7h.5M266.9 68h.3l.1 .2v.5l-.2 .1-.2-.1z"/>
<path d="M267.7 68.1l.3-.1 .1 .2v.5l-.1 .1a.48 .48 0 0 1-.3-.7zM268.6 68.3h.3v.5M268.6 68.2v.6M27.1 83.2h.4l.1-.3-.5-.1v.8M27.2 84.7l.2-.2v.9M27.2 85.4h.5M27.3 83.2l.3 .4M27.9 83.1l.3-.3v.8M27.9 83.6h.5M28 84.5v.9M28.1 85.1l.3 .3M28.4 84.8l-.4 .4"/>
<path d="M35.8 95.9a.43 .43 0 0 0-.5 .3 .43 .43 0 0 0 .2 .5l.4-.1v-.3h-.2M36.7 95.8v.9l-.5-.9v.9M37.2 95.8a.49 .49 0 0 1 .4 .3 .49 .49 0 0 1-.1 .6h-.3zM39.4 88h.4l.1 .2-.6 .7h.6M39.4 86.4h.5l.1 .5-.2 .2-.4-.1zM39.5 86.9l.5 .3M40.3 86.5l.2-.2v.8M40.3 87.1h.4M40.7 88v.9l-.5-.9v.9M41.1 88h.6l-.5 .9M42 88l.4 .1v.6l-.2 .2a.53 .53 0 0 1-.2-.9zM42.8 88.1l.4-.1a.53 .53 0 0 1-.3 .9l-.1-.2z"/>
<path d="M43.6 88h.4l.1 .2-.6 .7h.6M63.7 84.7l.3-.2v.9M63.7 83.2h.5v-.4h-.5v.8M63.7 85.4h.6M63.9 83.2l.4 .4M64.7 84.5v.9M64.8 85.1l.2 .3M65 82.8h-.4v.4l.4-.1 .1 .2-.1 .3h-.4M65 84.8l-.3 .4M72.5 95.9l-.3-.1-.2 .3v.4l.1 .2h.4v-.4h-.2M73.3 95.8v.9l-.4-.9v.9M73.7 95.8h.3l.2 .3v.4l-.1 .2h-.4z"/>
<path d="M75.9 88h.5v.4l-.5 .5h.5M76 86.4h.5l-.1 .7-.4-.1zM76.1 86.9l.5 .3M76.9 86.4l.4-.1 .1 .2-.6 .6h.6M77.3 88v.9l-.5-.9v.9M77.6 88h.6l-.3 .9M78.6 88.1h.4v.6l-.2 .2-.2-.2zM79.4 88l.4 .1v.6l-.1 .2a.53 .53 0 0 1-.3-.9zM80.2 88h.5v.4l-.5 .5h.5M98.2 83.2h.4v-.4h-.4v.8M98.4 83.2l.3 .4M98.6 84.7l.3-.2v.9"/>
<path d="M98.6 85.4h.5M99.1 83.1l.2-.3v.8M99.1 83.6h.5M99.6 84.5v.9M99.6 85.1l.2 .3M99.8 83.1l.3-.3v.8M99.8 84.8l-.2 .4M99.8 83.6h.5M107.3 95.9l-.2-.1-.3 .3v.4l.2 .2 .4-.1v-.3h-.2M108.2 95.8v.9l-.5-.9v.9M108.6 95.8h.3l.2 .3v.4l-.1 .2h-.4zM110.8 88l.5 .1-.5 .8h.5"/>
<path d="M110.9 86.4l.3-.1 .2 .2-.2 .6h-.2l-.2-.2zM111 86.9l.4 .3M111.7 86.3h.6l-.4 .3h.3v.5l-.5-.1M112.2 88v.9l-.5-.9v.9M112.5 88h.6l-.3 .9M113.4 88l.5 .1v.6l-.2 .2a.53 .53 0 0 1-.3-.9zM114.3 88l.4 .1v.6l-.2 .2a.53 .53 0 0 1-.2-.9zM115.1 88l.5 .1-.5 .8h.5M210.6 83.9l.4-.1 .2 .3-.6 .6h.6M210.6 90l.4-.1 .2 .3-.6 .6h.6M210.6 82.5h.4l.2-.1-.2-.4h-.4v1M210.6 88.6h.4l.2-.1-.1-.3h-.5v.9"/>
<path d="M210.6 94.7h.5v-.4h-.5v.9M210.8 82.5l.4 .5M210.8 88.6l.4 .5M210.8 94.7l.4 .5M211.1 96.1h.5v.3l-.5 .5h.5M211.4 83.8h.6l-.3 .9M211.4 89.9h.6l-.3 .9M211.5 82.1l.3-.1 .2 .3-.6 .7h.6M211.5 88.3l.4-.1 .1 .3-.6 .6h.6M211.5 94.4l.4-.1 .1 .3-.6 .6h.6M212 96v.9M212.1 96.6l.2 .3"/>
<path d="M212.3 82h.5l-.3 1M212.3 83.9l.3-.1 .2 .2-.1 .6a.39 .39 0 0 1-.5-.2 .39 .39 0 0 1 .1-.5zM212.3 90l.3-.1 .2 .2-.1 .7h-.3l-.1-.3zM212.3 96.3l-.3 .4M212.5 88.6l-.2-.3 .5-.1v.3l-.5 .1v.4l.2 .1 .3-.1-.1-.4M212.8 94.7v.1h-.4l-.1-.4 .5-.1v.6l-.4 .3M105.2 118.6l-.3-.1-.2 .2v.5l.2 .2 .3-.1M105.6 118.8l.2-.3v.9M105.6 119.4h.5M152.6 111.2l.6-.1v-.4h-.6v.8M152.9 111.2l.3 .3M153.5 110.9l.2-.2v.8"/>
<path d="M153.5 111.5h.5M154.3 109h.4l.1 .1v.5l-.2 .2-.3-.1zM154.3 110.7h.5l-.3 .3 .3 .2v.2l-.5 .1M155.2 109.4h.4v-.4h-.4v.8M155.4 110.7l-.2 .5h.5M155.4 109.4l.3 .4M155.6 111v.5M161.5 110.7h.2l.2 .1-.1 .7h-.3zM161.5 109.4h.4v-.4h-.4v.8M161.6 109.4l.4 .4M162.2 111.2l.5-.1v-.4h-.5v.8M162.2 109.2l.3-.2v.8"/>
<path d="M162.2 109.8h.5M162.5 111.2l.2 .3M163.1 109h.6l-.5 .8M193.6 110.7h.5v.4l-.5 .4h.5M193.7 109.4h.4v-.4h-.4v.8M193.7 112.3a.47 .47 0 0 1 .5 .5 .47 .47 0 0 1-.5 .5zM193.7 114.1v.9M193.9 109.4l.3 .4M194.4 110.7h.6l-.4 .8M194.5 109.2l.2-.2v.8M194.5 112.3h.6l-.5 1M194.5 109.8h.5"/>
<path d="M194.6 114.1l-.5 .1v.4l.1 .4h.4v-.4h-.2M195.5 110.7a.53 .53 0 0 1 .2 .8l-.4-.1v-.6zM195.5 114.1v.9l-.5-.9v.9M195.5 109.3l-.2-.2 .1-.1h.3l.1 .2-.5 .3 .2 .3 .3-.1v-.3l-.1-.1M195.7 115.1h.6M196.6 114.1h.3l.2 .3-.2 .6-.4-.1zM197.9 114.1v.9l-.5-.9v.9M210.6 106.9h.5v-.4h-.5v.9M210.6 113h.5v-.4h-.5v.8M210.6 119.1h.5v-.4h-.5v.8M210.6 100.8h.5v-.4h-.5v.9M210.8 106.9l.4 .5"/>
<path d="M210.8 113l.4 .4M210.8 119.1l.4 .4M210.8 100.8l.4 .5M211.1 108.3h.5v.3l-.5 .5h.5M211.1 114.4h.5v.3l-.5 .5h.5M211.1 102.2h.5v.3l-.5 .5h.5M211.4 106.5h.6l-.3 .3h.2v.6l-.5-.1M211.4 112.6h.6l-.3 .3h.2v.5h-.5M211.4 118.7h.6l-.3 .3h.2v.5h-.5M211.4 100.4h.6l-.3 .3h.2v.6l-.5-.1M212 102.1v.9M212 108.2v.9"/>
<path d="M212 114.3v.9M212.1 108.8l.2 .3M212.1 114.9l.2 .3M212.1 102.7l.2 .3M212.3 118.7h.5l-.3 .3h.3v.5h-.5M212.3 106.8l.3-.3v.9M212.3 112.7l.5-.1v.3l-.5 .5h.5M212.3 108.5l-.3 .4M212.3 114.6l-.3 .4M212.3 102.4l-.3 .4M212.3 107.4h.5M212.4 100.4l.4 .1-.1 .8h-.3l-.1-.2z"/>
<path d="M256.6 117v.3l.4 .2 .5-.2v-.3l-.4 .1M256.6 116.1h.9l-.9 .5h.9M256.6 115.3l.4-.2 .4 .1 .1 .4h-.9zM85.9 128.1h.5M86.2 128.1v.8M87.2 128.2a.43 .43 0 0 0-.5 .2 .43 .43 0 0 0 .2 .5h.3M87.5 128.9l.3-.8 .2 .8M87.5 128.7h.5M88.8 128.5h-.5l.2-.4 .3 .1v.6l-.4 .1M89.6 128.1h-.4l-.1 .4 .4-.1 .2 .2-.1 .3h-.5M90.4 128.1h-.4v.4l.3-.1 .2 .2-.1 .3h-.4M91.3 128.1h-.5v.4l.4-.1 .1 .2v.3h-.5"/>
<path d="M91.6 122.4h.4l.1-.3-.5-.1v.8M91.7 128.6h.3l.2-.3-.2-.2h-.3v.8M91.9 122.4l.2 .4M92.5 128.1l.2 .8 .2-.6 .1 .6 .2-.8M92.5 123.9l.3-.1 .1 .1v.6l-.2 .1-.2-.1zM92.5 122.3l.2-.3v.8M92.5 122.8h.5M92.7 126.4v.8h.2l.3-.1v-.7M93.3 124.2h.4v-.4h-.4v.8M93.5 122a.43 .43 0 0 1 .3 .5 .43 .43 0 0 1-.4 .3l-.1-.6zM93.5 124.2l.3 .4M93.6 128.6h.3l.2-.3-.2-.2h-.3v.8"/>
<path d="M93.6 126.6l.2-.2v.8M93.6 127.2h.5M93.7 128.6l.4 .3M101.4 126.6h1l-1 .5h1M101.4 125.9l.3-.3h.4l.3 .3v.2h-1zM101.5 127.5l-.1 .2 .3 .2h.4l.3-.2-.1-.3h-.4v.2M104.7 120.5l.3-.3v1M104.7 121.2h.5M105.7 120.2a.48 .48 0 0 1 .4 .5 .48 .48 0 0 1-.4 .5l-.1-.2v-.6zM106.6 120.2l.2 .2v.6l-.1 .2-.3-.2v-.6zM107.3 120.6h.3v.6M107.3 120.6v.6"/>
<path d="M191 122.9l-.3-.1-.2 .3v.4l.2 .3 .3-.1v-.3h-.2M191.9 122.8v1l-.5-1v1M192.4 122.8l.4 .3v.4l-.3 .3h-.1zM192.4 128.6h.3l.2-.3-.2-.2h-.3v.8M192.5 128.6l.4 .3M192.8 130.1l.2-.2v.8M192.8 130.7h.5M193.2 128.3l.3-.2v.8M193.2 128.9h.4M193.6 129.9v.8M193.7 130.4l.3 .3M194 130.1l-.4 .4"/>
<path d="M194.5 128.5h-.5l.1-.4 .4 .1v.6l-.4 .1M210.6 125.2h.5v-.4h-.5v.8M210.6 131.3h.5l.1-.2-.2-.2h-.4v.8M210.6 137.5h.4l.2-.3-.2-.2h-.4v.8M210.8 125.2l.4 .4M210.8 131.3l.4 .4M210.8 137.5l.4 .3M211.1 126.7h.5v.2l-.5 .5h.5M211.1 132.8h.5v.2l-.5 .5h.5M211.1 138.8h.5v.3l-.5 .5h.5M211.1 120.5h.5v.3l-.5 .5h.5M211.4 124.8h.6l-.3 .3h.2v.5h-.5"/>
<path d="M211.4 130.9h.6l-.3 .3h.2v.5h-.5M211.4 137h.6l-.3 .3 .3 .2-.1 .3-.5-.1M212 120.5v.8M212 126.6v.8M212 132.7v.8M212 138.8v.8M212.1 127.1l.2 .3M212.1 133.2l.2 .3M212.1 139.3l.2 .3M212.1 121l.2 .3M212.3 126.8l-.3 .4M212.3 132.9l-.3 .4"/>
<path d="M212.3 139l-.3 .4M212.3 120.7l-.3 .4M212.5 124.7l-.2 .7h.5M212.8 130.9h-.5v.4l.5-.1v.5h-.5M212.8 137l-.5 .2v.5l.5 .1-.1-.5-.4 .2M212.8 125v.6M260.8 139h.4l.1-.3-.5-.1v.8M261 139l.3 .4M261.9 138.5l-.3 .7h.6M262 138.8v.6M262.5 138.7a.36 .36 0 0 1 .5 .2 .36 .36 0 0 1-.2 .5h-.1a.55 .55 0 0 1-.2-.7zM266.9 139h.4l.1-.3-.5-.1v.8"/>
<path d="M267.1 139l.3 .4M268 138.5l-.3 .7h.6M268.1 138.8v.6M268.6 138.8l.2-.2v.8M268.6 139.4h.5M208.7 157.1v.4a.44 .44 0 0 0 .6 .1 .44 .44 0 0 0 .2-.5h-.3v.1M208.7 156.2h.8l-.8 .5h.8M208.7 155.4a.47 .47 0 0 1 .6-.1 .47 .47 0 0 1 .2 .5h-.8zM260.9 140.3l-.1 .6h.5M261.2 140.6v.6M261.6 140.3v.9M261.7 140.9l.3 .3"/>
<path d="M262 140.6l-.4 .4M262.3 140.3h.5l-.3 .9M267 140.3l-.1 .6h.5M267.3 140.6v.6M267.7 140.3v.9M267.8 140.9l.2 .3M268 140.6l-.3 .4M268.4 140.3h.6l-.4 .9M95.3 168.4h.9l-.9 .5h.9M95.4 169.3a.43 .43 0 0 0 .3 .5 .43 .43 0 0 0 .5-.1l-.1-.5h-.3v.2M95.5 167.5h.6l.1 .5h-.9zM103.2 186.8v.3l.3 .2 .5-.2v-.4h-.3v.2"/>
<path d="M103.2 185.8h.8l-.8 .5h.8M103.2 185.1l.3-.2 .5 .1v.4h-.8zM132.6 189.1h-.4l-.1 .4 .1 .5 .5-.1v-.3h-.2M132.6 195.2h-.4l-.1 .4 .1 .5 .5-.1v-.3h-.2M133.5 189.1v.9l-.5-.9v.9M133.5 195.2v.9l-.5-.9v.9M133.9 189.1l.5 .1v.4l-.1 .4h-.4zM133.9 195.2l.5 .1v.4l-.1 .4h-.4zM157.9 184.8l-.3-.1-.2 .3v.4l.2 .3 .3-.1v-.4h-.2M158.7 184.7v1l-.4-1v1M159.2 184.7h.2l.3 .3v.4l-.3 .3h-.2z"/>
</g>
<g fill="none" stroke="#e00" stroke-width=".34">
<path d="M33 16.4l6.9 22.1M39.9 16.4l-6.9 22.1M86.1 19l7 4.7M93.1 19l-7 4.7M210.4 14.9l.7 .6M211.1 14.9l-.7 .6M248.8 16.6l.7 .7M249.5 16.6l-.7 .7M248.8 33.1l.7 .8M249.5 33.1l-.7 .8M32.9 42.2l7.1 5.2M40 42.2l-7.1 5.2"/>
<path d="M69.5 42.2l7.1 5.2M76.6 42.2l-7.1 5.2M104.3 43.1l7.2 5.3M111.5 43.1l-7.2 5.3M202.6 54.1l.7 .7M203.3 54.1l-.7 .7M141.6 116l33.8 61.7M175.4 116l-33.8 61.7M183.4 131.4l6 2.2M189.4 131.4l-6 2.2M196.5 153.5l.7 .6M196.5 156.9l.7 .8"/>
<path d="M197.2 153.5l-.7 .6M197.2 156.9l-.7 .8M210.8 146.3l5.2 4.6M216 146.3l-5.2 4.6M254 143.9l.7 .7M254.7 143.9l-.7 .7M268 143.9l.7 .7M268.7 143.9l-.7 .7M108.5 180.1l5.8 3.2M114.3 180.1l-5.8 3.2M131.4 181.2l3.6 4.5M131.4 187.3l3.6 4.5"/>
<path d="M135 181.2l-3.6 4.5M135 187.3l-3.6 4.5M161.9 188.1l5.4 4.6M167.3 188.1l-5.4 4.6"/>
</g>
</svg>
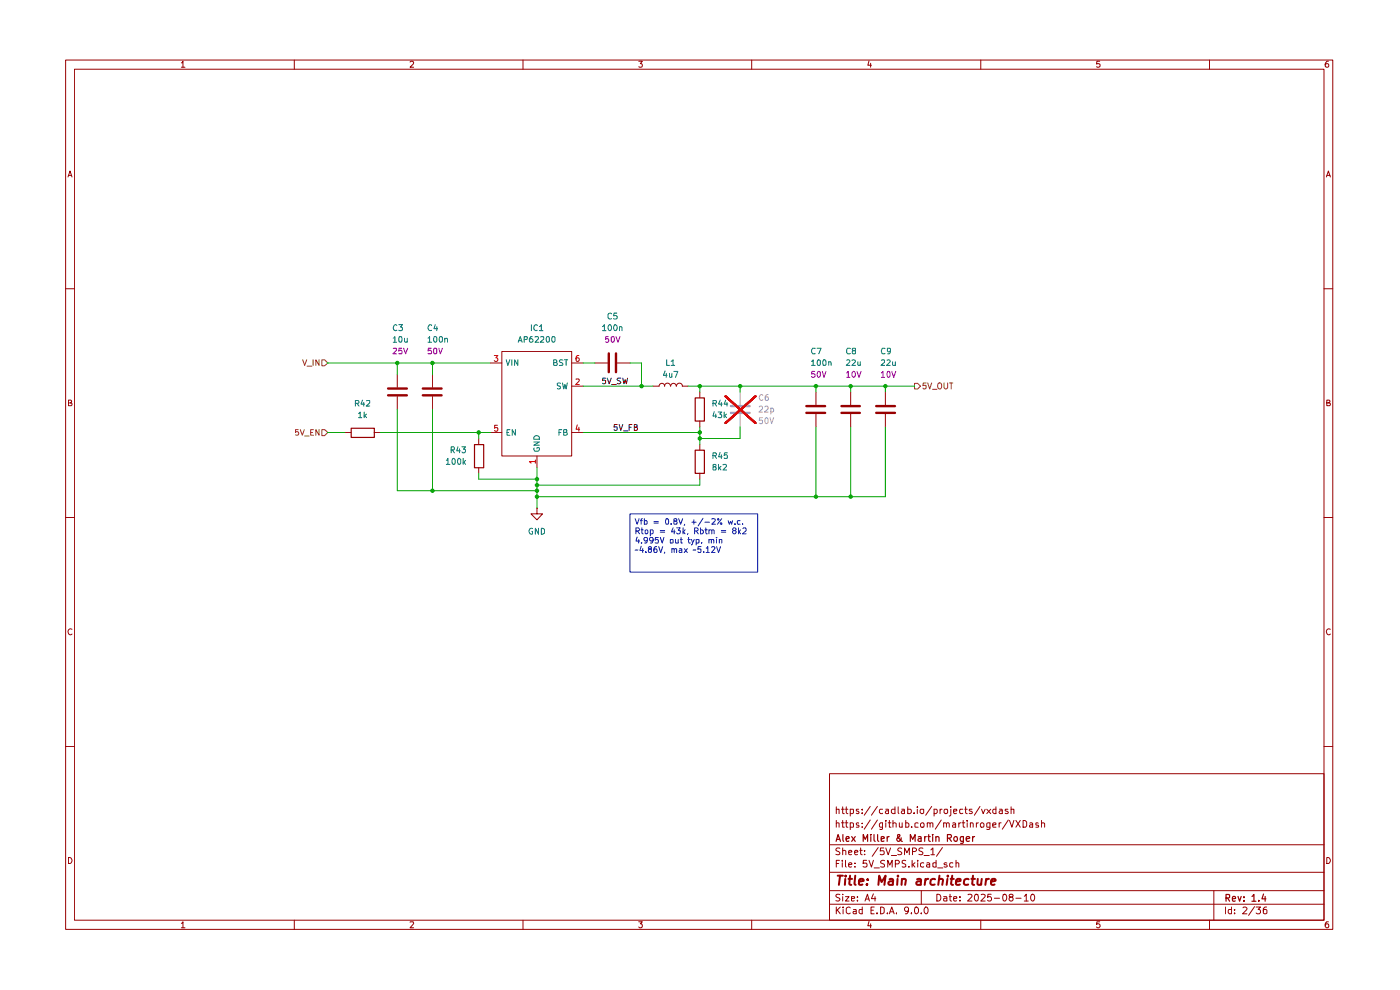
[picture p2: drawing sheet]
<svg xmlns="http://www.w3.org/2000/svg" width="297mm" height="210mm" viewBox="0 0 297 210" stroke-linecap="round" stroke-linejoin="round" font-family="sans-serif">
<g fill="none" stroke="#980000" stroke-width=".21">
<path d="M13.9 12.7h268.8v184.4h-268.8zM15.8 14.7h265.1v180.5h-265.1zM38.5 13.3h.1l.2-.3v1.3M38.5 14.3h.7M62.4 12.7v2M87 13.2l.5-.2 .3 .2-.1 .4-.7 .7h.8M111 12.7v2M135.5 13h.8l-.5 .5 .4 .1v.6h-.7M159.5 12.7v2M184.4 12.9l-.3 .9h.8M184.7 13.4v.9M208.1 12.7v2"/>
<path d="M233.3 13h-.6l-.1 .6h.7v.6h-.7M256.6 12.7v2M281.8 13a.71 .71 0 0 0-.7 .5 .71 .71 0 0 0 .3 .8l.4-.1v-.6l-.4-.1-.3 .3M14.4 37.5l.5-1.2 .4 1.2M14.5 37.2h.7M281.4 37.5l.4-1.2 .4 1.2M281.5 37.2h.6M13.9 61.3h1.9M84.3 79.5v2.7M91.7 79.5v2.7M104 77h2.5M106.5 74.5h14.8v22.2h-14.8z"/>
<path d="M121.3 77h2.4M126.2 77h2.7M130.9 77h2.7M280.9 61.3h1.8M14.5 85.5h.4l.3-.3-.2-.3h-.5v1.2h.6l.2-.5-.4-.1M84.3 84.1v2.7M91.7 84.1v2.7M101.6 93v1.3M101.6 99.2v1.2M104 91.7h2.5M113.9 96.7v2.5M121.3 81.9h2.4"/>
<path d="M121.3 91.7h2.4M141 81.9a.64 .64 0 0 1 .6-.6 .64 .64 0 0 1 .6 .6M141 81.9a.59 .59 0 0 0-.6-.6 .59 .59 0 0 0-.6 .6h-1.2M142.3 81.9a.59 .59 0 0 1 .6-.6 .59 .59 0 0 1 .6 .6M143.5 81.9a.64 .64 0 0 1 .6-.6 .64 .64 0 0 1 .7 .6M144.7 81.9h1.2M148.5 83.2v1.2M148.5 89.3v1.2M148.5 94.3v1.2M281.5 85.5h.4l.2-.3-.1-.3h-.5v1.2h.6l.1-.5-.3-.1M13.9 109.8h1.9M113.9 107.8v1.2h1.2l-1.2 1.3-1.3-1.3h1.3"/>
<path d="M113.9 107.8h.1M148.5 100.4v1.2M280.9 109.8h1.8M15.3 133.5a.59 .59 0 0 0-.9 .5 .59 .59 0 0 0 .8 .6l.1-.1M282.2 133.5a.59 .59 0 0 0-.8 .5 .59 .59 0 0 0 .7 .6l.1-.1M13.9 158.4h1.9M280.9 158.4h1.8M176 164.1h104.9v31.1h-104.9zM176 179.2h104.9M177.4 174.7l.2-.2 .4 .1v.9M177.4 171.7h.6v.9M177.4 171.1v1.5"/>
<path d="M177.4 174v1.5M178.2 180l-.6-.1-.3 .2 .1 .4 .8 .4-.1 .3h-.8M178.5 174.5h.6M178.5 171.7h.6M178.8 174v1.5h.3M178.8 171.1v1.4l.3 .1M178.8 179.9v1.4M179.4 174.5h.5M179.4 171.7h.5M179.5 174v1.3l.1 .2h.3M179.5 171.1v1.3l.4 .2M180.4 174.6l.4-.1 .3 .2v.7l-.7 .1"/>
<path d="M180.4 172.5l.4 .1 .3-.2-.1-.7h-.6v1.4M180.4 174.5v1.5M182.2 174.6l-.4-.1-.2 .2 .2 .3h.4v.5h-.6M182.2 171.7h-.5l-.1 .2 .5 .2 .1 .3-.1 .2-.5-.1M182.6 179.9v1.2l.3 .2M182.9 175.4v.1M182.9 174.6v.1M182.9 172.4v.2M182.9 171.7v.1M184.6 173.9l-1.3 2M184.6 171.1l-1.3 1.8M186.1 173.9l-1.2 2"/>
<path d="M186.1 171.1l-1.2 1.8M186.3 179.8l-1.3 1.8M187.2 174.5v1.2a.36 .36 0 0 1-.6 .2M187.2 174.6l-.4-.1-.2 .3v.6l.6 .1M187.2 171.7h-.5l-.1 .2v.4l.2 .3 .4-.1M187.5 179.9h-.7l-.1 .6h.7l.2 .2-.1 .5h-.8M187.9 179.9l.5 1.4 .5-1.4M187.9 174v.2M187.9 171.7h.5l.1 .9M187.9 174.5v1M188.4 174.5h.6M188.5 172h-.5l-.2 .2 .2 .4 .5-.1"/>
<path d="M188.7 174v1.5h.3M189.4 174.7l.3-.2 .4 .2v.8M189.4 174v1.5M189.9 171.7h-.6l-.2 .6a.52 .52 0 0 0 .8 .2M189.9 171.1v1.5M190.5 171.1v1.3l.2 .2M190.8 174.5l.1 1 .5-.1M191.3 180l-.6-.1-.2 .2v.4l.8 .4-.1 .3h-.7M191.3 171.7h.5l.1 .9M191.4 174.5v1M191.9 172h-.5l-.2 .2 .2 .4 .5-.1M192.1 174v1.5l.6-.1 .1-.6a.45 .45 0 0 0-.7-.2"/>
<path d="M192.6 171.7h.6l.1 .6a.52 .52 0 0 1-.7 .2M192.6 171.1v1.5M193.4 175.4v.1M193.9 172.4v.2M194.6 171.1v.1M194.6 171.7v.9M194.8 174.6l-.5-.1-.2 .2v.7l.7 .1M195.3 174.8a.45 .45 0 0 1 .7-.2v.9l-.6-.1zM195.3 171.7h.7l-.1 .8a.45 .45 0 0 1-.7-.2zM195.8 180l-.6-.1-.3 .2 .1 .4 .8 .4-.1 .3h-.8M196.7 174.7l.2-.2 .4 .2v.8M196.7 174.5v1"/>
<path d="M197.3 174.7l.2-.2 .4 .1v.9M197.6 171.1l-1.2 1.8M198.2 172.5l.4 .1 .2-.3-.1-.6h-.5v1.4M199.4 171.7v.9M199.7 173.9l-1.3 2M199.9 171.7h-.3l-.2 .2M199.9 179.8l-1.2 1.8M200.2 174.7l.2-.2 .4 .2v.8M200.2 174.5v1M200.4 171.7h.6v.8l-.5 .1-.2-.3zM200.8 174.7l.2-.2 .4 .2v.8M201.7 171.7v1.1l-.3 .3"/>
<path d="M201.7 171.1v.1M202.1 174.6l.4-.1 .2 .2v.8h-.6v-.4l.6-.2M202.3 172.1l.7-.1-.1-.3h-.5l-.1 .1v.6l.2 .2 .4-.1M203.4 174.5v1M203.8 174.5l-.4 .3M204.1 174.5h.6M204.3 171.7h-.6l-.1 .2 .1 .6h.6M204.3 174v1.3l.1 .2h.3M204.7 171.7h.5M204.8 171.1v1.3l.4 .2M205.2 174v.2M205.2 174.5v1"/>
<path d="M205.9 174.7l.1-.2 .5 .2v.8M205.9 174.5v1M206.2 171.7h-.5l-.1 .2 .6 .3 .1 .2-.3 .2-.4-.1M207.1 174.5v1M207.6 174.5l-.5 .3M207.9 171.1l-1.2 1.8M208.2 174.5h.3l.2 .3-.1 .7h-.5l-.1-.3v-.4zM208.2 171.7l.4 .9 .4-.9M209.3 171.7l.9 .9M210 174.5v1.2l-.2 .3-.5-.1M210 174.6l-.4-.1-.3 .2v.7l.7 .1M210.2 171.7l-.9 .9"/>
<path d="M210.6 175l.7-.1v-.3l-.4-.1-.3 .2 .1 .8h.6M211.3 171.7h-.5l-.2 .6a.45 .45 0 0 0 .7 .2M211.3 171.1v1.5M212 174.5v1M212 171.7h.6v.9M212.4 174.5l-.4 .3M212.6 172h-.5l-.1 .2 .1 .4 .5-.1M213.8 171.7h-.5l-.1 .2 .6 .3 .1 .2-.2 .2-.5-.1M213.9 173.9l-1.3 2M214.2 174l.5 1.5 .4-1.5M214.5 171.7h.6v.9M214.5 171.1v1.5"/>
<path d="M215.5 174l.9 1.5M216.4 174l-.9 1.5M217 174h.4l.4 .4v.7l-.3 .4h-.5zM218.5 174.6l.4-.1 .2 .2v.8h-.6l-.1-.4 .7-.2M220.3 174.6h-.6v.4h.6v.2v.3h-.6M220.9 174.7l.3-.2 .4 .2v.8M220.9 174v1.5M14.5 181.9a.65 .65 0 0 1 .8 .6 .65 .65 0 0 1-.8 .7zM38.5 195.9l.3-.4v1.3M38.5 196.8h.7M62.4 195.2v1.9M87 195.6l.7-.1 .1 .3-.8 1h.8"/>
<path d="M111 195.2v1.9M135.5 195.5h.8l-.5 .5 .5 .2-.1 .5-.5 .1-.2-.2M159.5 195.2v1.9M176 191.8h104.9M176 188.9h104.9M176 185h104.9M177.4 192.4v1.4M177.4 183.2h.5M177.6 193l.7 .8M178.1 182.5h-.7v1.4M178.2 189.8h-.8l-.1 .3 .8 .4 .1 .4-.3 .2-.6-.1M178.3 192.4l-.9 .8"/>
<path d="M178.7 182.5v.2M178.7 183v.9M178.8 189.7v.1M178.8 180.5l.4-.1 .2 .1v.8M178.8 190.2v.9M178.9 192.4v.2M178.9 192.9v.9M179.4 190.2h.7l-.7 .9h.7M179.4 182.5v1.3l.1 .1M180 183.4l.7-.1-.2-.3-.5 .2v.6l.3 .1 .3-.1M180 180.8l.7-.1-.2-.3-.5 .1v.6l.3 .2 .3-.1M180.4 192.6l-.4-.2-.5 .3 .1 1 .4 .1 .4-.1"/>
<path d="M180.6 190.6l.7-.1-.1-.3h-.6v.8h.6M181.1 192.9h.5v.9M181.3 180.8l.7-.1-.2-.3h-.3l-.2 .1v.6l.2 .2 .4-.1M181.4 183.8v.1M181.4 183.1v.1M181.6 193.2l-.5 .1-.1 .2 .1 .3h.5M181.9 191v.1M181.9 190.2v.2M182.4 180.4h.5M182.9 192.9h-.5l-.2 .7a.45 .45 0 0 0 .7 .2M182.9 192.4v1.4M183.4 181.2v.1"/>
<path d="M183.4 180.5h.1M183.5 191.1l.5-1.4 .4 1.4M183.7 190.7h.7M183.8 182.5h-.6l-.1 .7 .7-.1 .1 .2-.1 .5h-.7M184.4 195.4l-.3 1h.8M184.4 182.5l.5 1.4 .4-1.4M184.7 196v.8M184.8 193.1h.5M185.3 189.6l-.4 1h.9M185.5 192.4h-.7v1.4h.7M185.5 184.1h1.1M185.6 190.2v.9"/>
<path d="M186 193.7v.1M186.8 192.4h.4l.4 .3v.8l-.4 .3h-.4zM187.7 182.6a.6 .6 0 0 0-.9 .1l.1 .4 .7 .2 .1 .2-.3 .4-.6-.1M188.3 193.7v.1M188.3 183.9v-1.4l.5 1 .5-1v1.4M188.7 193.8l.5-1.4 .5 1.4M188.8 193.4h.7M189.1 181.5h1.1M189.9 183.3h.6l.3-.3v-.3l-.3-.2h-.6v1.4M190.2 193.7v.1M191.9 181.3v-1.4l.5 1 .5-1v1.4M192.1 182.6l-.5-.1-.2 .2v.4l.7 .3v.4h-.7"/>
<path d="M192.7 193l-.2 .3h-.4l-.2-.3v-.3l.2-.3h.4l.2 .3v.8l-.2 .3h-.4M192.8 183.8v.1M193.3 193.7v.1M193.5 182.5v1.4M193.6 180.6l.7-.1 .1-.4-.3-.2h-.5v1.4M193.7 183.4l.4 .5M194.1 192.6l.2-.2a.75 .75 0 0 1 .6 .7 .75 .75 0 0 1-.6 .7l-.2-.1-.1-.4zM194.1 183l-.6 .5M194.7 182.5v.2M194.7 183v.9M195.4 193.7v.1M195.4 188.9v2.9"/>
<path d="M196 183.1l-.4-.1-.3 .3 .1 .5h.6M196 181.5h1.1M196.4 192.4h.1a.8 .8 0 0 1 .4 .8 .8 .8 0 0 1-.5 .6 .89 .89 0 0 1 0-1.4zM196.6 183.1l.5-.1 .1 .2v.7M197.2 183.3l-.6 .1-.1 .2 .2 .3 .5-.1M197.5 180.3l.4-.4v1.4M197.5 181.3h.7M198.6 183.1h-.7v.7h.7M198.6 182.5v1.4M198.7 189.7a.73 .73 0 0 1 .9 .7 .73 .73 0 0 1-.9 .7zM198.9 184.1h1.1M200.2 190.2h.6l.1 .9"/>
<path d="M200.9 190.5l-.7 .1v.4h.7M200.9 183.1l-.4-.1-.2 .3 .1 .1 .5 .1 .1 .3-.3 .1-.4-.1M201.4 190.2h.5M201.5 189.7v1.3l.4 .1M202.1 183.1l-.4-.1-.2 .3v.5h.6M202.3 190.6l.7-.1-.1-.3h-.5l-.1 .2v.6l.2 .1 .4-.1M202.8 183.1l.4-.1 .2 .2v.7M202.8 182.5v1.4M203.7 191v.1M203.7 190.2v.2M205.4 189.8l.5-.1 .3 .4-.9 1h.9M206.9 189.8h.5a1.01 1.01 0 0 1-.2 1.3 .87 .87 0 0 1-.3-1.3z"/>
<path d="M208.1 195.2v1.9M208.1 189.8h.8l.1 .3-.9 1h.9M210.3 189.7h-.7l-.1 .7 .6-.2 .2 .3v.4l-.2 .2-.6-.1M210.9 190.5h1.1M212.8 189.8l.3-.1a.73 .73 0 0 1 .5 .7 .73 .73 0 0 1-.5 .7l-.3-.1-.1-.5zM214.3 190.3l-.2-.3 .1-.2h.6v.4l-.5 .1-.2 .2v.4l.2 .2h.4l.2-.2v-.4l-.2-.2M215.5 190.5h1.1M217.3 190.1l.4-.4v1.4M217.3 191.1h.8M218.8 189.8l.2-.1a.76 .76 0 0 1 .5 .7 .76 .76 0 0 1-.5 .7 1.01 1.01 0 0 1-.2-1.3zM233.3 195.5h-.6l-.1 .6 .2-.1h.3l.3 .2v.3l-.3 .3h-.3l-.2-.2M256.6 195.2v1.9"/>
<path d="M257.5 188.9v6.3M260 192.4v1.4M261.2 192.9h-.5l-.1 .3v.4l.2 .2h.4M261.2 192.4v1.4M261.9 193.7v.1M261.9 192.9v.2M263.7 192.6l.2-.2h.3l.3 .4-.9 1h.9M266.1 192.3l-1.2 1.9M266.5 192.4h.9l-.5 .5 .4 .2 .1 .5-.2 .2-.7-.1M268.7 192.4h-.4l-.3 .3v1l.3 .1 .5-.1-.1-.7-.4-.1-.3 .3M281.5 181.9a.65 .65 0 0 1 .7 .6 .65 .65 0 0 1-.7 .7zM281.8 195.5h-.4l-.3 .5v.5l.3 .3 .4-.1v-.7h-.4l-.3 .2"/>
</g>
<g fill="none" stroke="#980000" stroke-width=".25">
<path d="M100.7 94.3h1.9v4.9h-1.9zM147.5 95.5h1.9v4.9h-1.9zM147.5 84.4h1.9v4.9h-1.9zM177.4 178.5l.4-1.5 .5 1.5M177.5 178h.6M178.8 177v1.2l.2 .3M179.5 178l.7-.2-.2-.3h-.4l-.1 .7 .2 .3 .4-.1M180.7 177.5l.7 1M181.4 177.5l-.7 1M183.1 178.5v-1.5l.5 1 .5-1v1.5M184.7 177v.1M184.7 177.5v1"/>
<path d="M185.4 177v1.2l.3 .3M186.2 177v1.2l.2 .3M186.9 178l.7-.2-.1-.3h-.6v.9h.6M188.2 177.5v1M188.6 177.5l-.4 .3M191.2 177.7v.3l-.5 .5a.43 .43 0 0 1-.4-.2 .43 .43 0 0 1 0-.5l.6-.5-.1-.3h-.3a.55 .55 0 0 0 .2 .8l.7 .7M193.1 178.5v-1.5l.5 1 .5-1v1.5M194.8 177.5h.6v1M195.4 177.8l-.4 .1-.3 .2 .3 .4 .4-.1M196.2 177.5v1M196.5 177.5h-.2l-.1 .3M196.8 177.5h.6"/>
<path d="M197 177v1.2l.4 .3M197.9 177v.1M197.9 177.5v1M198.5 177.6l.1-.1a.36 .36 0 0 1 .6 .2v.8M198.5 177.5v1M201 177.8l.7-.1 .1-.2v-.4l-.8-.1v1.5M201.3 177.8l.5 .7M204.4 177.5v1.1l-.2 .3h-.4M204.4 177.5h-.4l-.3 .3 .1 .6h.6M205 178l.7-.2-.1-.3h-.4l-.2 .2 .1 .7h.5M206.3 177.5v1M206.8 177.5l-.5 .3"/>
<path d="M260.1 190.5l.7-.1 .1-.6-.8-.1v1.5M260.4 190.5l.5 .7M261.4 190.7l.7-.1-.1-.4h-.5l-.1 .7 .2 .3 .4-.1M262.6 190.2l.4 1 .3-1M263.9 191v.2M263.9 190.2v.2M265.6 190.2l.4-.5v1.5M265.6 191.2h.8M267 191v.2M268 189.6l-.3 1.1h.9M268.4 190.2v1"/>
<circle cx="202.7" cy="178" r=".48"/>
</g>
<g fill="none" stroke="#980000" stroke-width=".42">
<path d="M177.7 185.8h1.1M178.2 185.8l-.2 1.9M179.3 186.4l-.1 1.3M179.4 185.8v.1M180 186.4h.8M180.3 185.8l-.1 1.6 .4 .3M181.4 185.8l-.1 1.6 .2 .3M182.2 187l1-.1-.1-.4a.6 .6 0 0 0-.8 .2v.9h.7M184 187.5l-.1 .2-.1-.1 .2-.1-.1 .2M184.1 186.5v.2M186.3 187.7l.2-1.9 .5 1.3 .9-1.3-.3 1.9M188.7 186.5h.7v1.2"/>
<path d="M189.5 186.9h-.7l-.3 .3v.2l.2 .3 .7-.1M190.4 186.4l-.1 1.3M190.5 185.8v.1M191.3 186.6l.1-.1a.48 .48 0 0 1 .8 .2l-.2 1M191.3 186.4v1.3M194.6 186.5h.7v1.2M195.4 186.9h-.7l-.3 .3v.2l.2 .3 .7-.1M196.3 186.4l-.1 1.3M196.9 186.4l-.4 .1-.2 .3M198.4 186.5a.65 .65 0 0 0-1 .3v.7a.64 .64 0 0 0 .9 .1M199.2 186.6l.1-.1a.48 .48 0 0 1 .8 .2l-.2 1M199.3 185.8l-.3 1.9"/>
<path d="M201 186.4l-.2 1.3M201.1 185.8v.1M201.7 186.4h.6M202 185.8l-.2 1.6 .4 .3M202.9 187l.9-.1v-.4l-.6-.1-.3 .3v.9h.7M205.5 186.5a.65 .65 0 0 0-1 .3v.7a.64 .64 0 0 0 .9 .1M206.1 186.4h.7M206.4 185.8l-.2 1.6 .5 .3M207.4 186.4v1.2l.5 .1 .3-.2M208.3 186.4l-.2 1.3M209.2 186.4l-.2 1.3M209.8 186.4l-.4 .1-.2 .3"/>
<path d="M210.2 187l1-.1v-.4a.6 .6 0 0 0-.9 .2v.9h.7"/>
</g>
<path d="M153.9 84.1l6.4 5.6M160.3 84.1l-6.4 5.6" fill="none" stroke="#e00" stroke-width=".42"/>
<path d="M128.5 80.2h-.6l-.1 .5h.7v.6h-.7M128.8 80.2l.4 1.2 .5-1.2M129.7 81.6h1.1M130.9 90h-.6v.6l.5-.1 .1 .6-.1 .2h-.4l-.1-.2M131.4 90l.3 1.3 .4-1.3M131.7 80.2h-.6l-.2 .2 .2 .3 .6 .4-.1 .2h-.7M132.1 80.2l.3 1.2 .2-.8 .3 .8 .2-1.2M132.3 91.4h.9M133.5 90.6h.4M134.1 90h-.6v1.3M134.6 90.6l.6-.1v-.4l-.6-.1v1.3h.4l.2-.4-.3-.3" fill="none" stroke="#0c0c0c" stroke-width=".21"/>
<path d="M129.2 75v3.9M130.7 75v3.9M82.3 83.9h4M82.3 82.4h4M89.7 83.9h4M89.7 82.4h4" fill="none" stroke="#980000" stroke-width=".51"/>
<path d="M155.1 86.1h3.9M155.1 87.6h3.9" fill="none" stroke="#aaa" stroke-width=".51"/>
<path d="M157 83.2v2.7M157 87.8v2.7" fill="none" stroke="#aaa" stroke-width=".21"/>
<path d="M104.9 75.4h.7l-.4 .5 .4 .3-.1 .4-.5 .1-.1-.2M122.8 75.4l-.4 .1-.2 .2v.8l.2 .2 .4-.1v-.6l-.4-.1-.2 .3M105.5 90.2h-.6v.6l.6-.1 .1 .2-.1 .5-.4 .1-.2-.2M113.6 97.9h-1.3l.3 .3M113.6 97.6v.6M122.2 80.5l.6-.1 .1 .3-.8 .9h.8M122.5 90.1l-.3 1h.8M122.8 90.6v.9" fill="none" stroke="#bd0000" stroke-width=".21"/>
<g fill="none" stroke="#007170" stroke-width=".21">
<path d="M107.4 76.3l.3 1.2 .5-1.2M108.6 76.3v1.2M109.8 76.3v1.2l-.6-1.2v1.2M117.5 76.9l.6-.1v-.4l-.6-.1v1.2h.6l.1-.3-.3-.3M119.4 76.4h-.7v.3l.2 .2h.3l.2 .4-.2 .2h-.5M119.8 76.3h.6M120.1 76.3v1.2M107.6 91.7h.3M108.2 91.1h-.6v1.2h.6M109.3 91.1v1.2l-.6-1.2v1.2M113.2 93.8h1.2l-1.2 .6h1.2M113.3 95l-.1 .3 .3 .4h.7l.2-.2-.1-.6h-.4v.3"/>
<path d="M113.3 92.7a.72 .72 0 0 1 1.1 0v.5h-1.2zM118.6 91.7h.4M118.9 81.3h-.7v.4l.6 .2 .1 .2-.2 .4-.5-.1M119.2 91.1h-.6v1.2M119.3 81.2l.3 1.3 .2-.9 .3 .9 .2-1.3M119.6 91.7l.6-.1v-.5h-.6v1.2l.7-.1v-.3l-.3-.2"/>
</g>
<path d="M68.3 76.3h.6l.6 .7-.6 .6h-.6z" fill="#fff"/>
<path d="M64.2 76.3l.4 1.2 .5-1.2M65.1 77.7h1.1M66.4 76.3v1.2M67.7 76.3v1.2l-.7-1.2v1.2M68.3 76.3h.6l.6 .7-.6 .6h-.6z" fill="none" stroke="#805e00" stroke-width=".21"/>
<path d="M68.3 91.1h.6l.6 .6-.6 .7h-.6z" fill="#fff"/>
<path d="M63.3 91.1h-.6v.6l.4-.1 .3 .2-.1 .4h-.6M63.7 91.1l.4 1.2 .5-1.2M64.6 92.5h1M65.9 91.7h.4M66.5 91.1h-.6v1.2h.6M67.7 91.1v1.2l-.7-1.2v1.2M68.3 91.1h.6l.6 .6-.6 .7h-.6z" fill="none" stroke="#805e00" stroke-width=".21"/>
<path d="M74.5 90.8h4.9v2h-4.9z" fill="none" stroke="#980000" stroke-width=".25"/>
<path d="M73.2 91.7h1.3M79.4 91.7h1.2" fill="none" stroke="#980000" stroke-width=".21"/>
<path d="M194 81.3h.7l.6 .6-.6 .6h-.7z" fill="#fff"/>
<path d="M194 81.3h.7l.6 .6-.6 .6h-.7zM196.5 81.2h-.6l-.1 .6 .6-.1 .1 .6-.3 .2-.4-.2M196.8 81.2l.4 1.3 .4-1.3M197.8 82.6h.9M199 81.4l.5-.2a.86 .86 0 0 1 0 1.3 .46 .46 0 0 1-.6-.4zM200.3 81.2v1l.2 .3h.3l.2-.3v-1M201.5 81.2h.6M201.8 81.2v1.3" fill="none" stroke="#805e00" stroke-width=".21"/>
<path d="M171.1 86.1h3.9M171.1 87.6h3.9M178.5 86.1h3.9M178.5 87.6h3.9M185.9 86.1h4M185.9 87.6h4" fill="none" stroke="#980000" stroke-width=".51"/>
<path d="M173.1 83.2v2.7M173.1 87.8v2.7M180.5 83.2v2.7M180.5 87.8v2.7M187.8 83.2v2.7M187.8 87.8v2.7" fill="none" stroke="#980000" stroke-width=".21"/>
<g fill="none" stroke="#00a200" stroke-width=".21">
<path d="M69.5 77h34.5M84.3 77v2.5M91.7 77v2.5M123.7 77h2.5M133.6 77h2.5v4.9M69.5 91.7h3.7M80.6 91.7h23.4M84.3 86.8v17.3h29.6M91.7 86.8v17.3M101.6 91.7v1.3M113.9 99.2v8.6M123.7 81.9h14.9"/>
<path d="M123.7 91.7h24.8M145.9 81.9h48.1M148.5 81.9v1.3M148.5 90.5v3.8M157 81.9v1.3M157 90.5v2.5h-8.5M173.1 81.9v1.3M173.1 90.5v14.9M180.5 81.9v1.3M180.5 90.5v14.9M187.8 90.5v14.9h-73.9M187.8 81.9v1.3"/>
<path d="M101.6 100.4v1.2h12.3M148.5 101.6v1.3h-34.6"/>
</g>
<g fill="none" stroke="#001dcd" stroke-width=".21">
<path d="M133.6 109h27.1v12.4h-27.1zM134.7 110l.5 1.2 .4-1.2M134.9 112.6h.7l.1-.4-.3-.2h-.5v1.2M135.2 113.9l-.3 .9h.8M135.2 112.6l.5 .6M135.3 116.6l-.6 .1M135.5 114.4v.8M135.8 110.4h.5M136 115.9l-.2 .9h.7M136 112.4h.4M136.1 115.1v.1M136.2 112v1.1l.2 .1"/>
<path d="M136.3 110l-.3 .1v1.1M136.4 116.4v.8M136.7 110v1.2h.5v-.8h-.5M136.9 112.6l.1-.2 .4 .1v.7h-.4l-.1-.1zM137 117v.2M137.4 114.5l-.3 .3h-.2l-.3-.3 .1-.4 .5-.1 .2 .3-.2 .8-.4 .1M137.8 116.5h-.2a.31 .31 0 0 1 .1-.5 .31 .31 0 0 1 .4 .1v.4h-.3l-.3 .2v.3l.3 .2 .4-.2v-.3l-.2-.2M138 112.5l.4-.1 .2 .2v.5l-.2 .1h-.4M138 112.4v1.3M138.6 114.5l-.3 .3h-.3l-.2-.3 .1-.4 .5-.1 .2 .3-.2 .8-.4 .1M138.7 110.6h1M138.7 110.9h1"/>
<path d="M139.3 115.9l-.4 .1-.2 .3v.7l.2 .2 .4-.1v-.6h-.5l-.1 .2M139.7 114h-.6l-.1 .6 .1-.2h.4l.2 .2v.5h-.7M139.7 115.9l.5 1.3 .4-1.3M140.1 114l.4 1.2 .3-1.2M140.1 112.6h.9M140.1 112.9h.9M141 117.1l-.1 .3M141.3 110.1l.3-.1a.86 .86 0 0 1 .1 1.2l-.4-.1zM142.2 114.5h.6l-.1 .7-.5-.1zM142.4 111.1v.1M142.5 116.5l.4-.1 .1 .1v.7M142.5 116.4v.8"/>
<path d="M142.8 112l-.4 .8h.8M143 116.5l.2-.1 .3 .1v.7M143 112.4v.8M143.1 110.5l-.1-.1v-.3h.5v.3l-.5 .2v.5l.5 .1 .1-.4-.2-.3M143.3 114.4l.1 .8 .5-.1M143.5 112h.8l-.4 .5 .4 .1v.5l-.2 .1h-.4l-.2-.1M143.9 114.4v.8M144 110l.4 1.2 .4-1.2M144.1 116.5h.5v.7M144.3 114.4h.4M144.5 114v1.2h.2M144.6 116.7l-.5 .2 .2 .3 .3-.1"/>
<path d="M144.9 112v1.2M145 112.7l.3 .5M145.2 116.4l.6 .8M145.2 111.2v.3M145.3 112.4l-.4 .5M145.8 116.4l-.6 .8M145.9 113.2l-.1 .2M145.9 114.4h.5M146.1 114v1l.1 .2h.2M146.7 114.4l.2 .8M146.8 110.8h.9M147.2 110.3v.9"/>
<path d="M147.3 114.4l-.5 1.1-.1 .1M147.4 112.6h.6l.1-.4-.2-.2h-.5v1.2M147.6 116.6l-.6 .1M147.7 115.2l.6-.1-.1-.7h-.5v1.2M147.7 112.6l.4 .6M148.6 112.5l.4-.1 .2 .2v.4l-.2 .2h-.4M148.6 112v1.2M148.7 115.9h-.6l-.1 .6h.6l.1 .5-.2 .2-.5-.2M148.9 115.1v.1M149.1 109.9l-1 1.6M149.3 117v.2M149.6 110.8h.9"/>
<path d="M149.6 112.4h.5M149.7 112v1.1l.4 .1M149.8 116.3l.4-.4v1.3M149.8 117.2h.7M150.4 112.6l.2-.2 .4 .2v.6M150.4 114.5l.4-.1 .1 .8M150.4 112.4v.8M150.4 114.4v.8M150.9 114.6l.1-.2h.3l.1 .8M151 110.1l.5-.1 .3 .3-.8 .9h.8M151 112.6l.2-.2 .3 .2v.6M151 116.1l.4-.2 .3 .4-.8 .9h.8"/>
<path d="M152 114v.1M152 115.9l.4 1.3 .5-1.3M152 114.4v.8M152.4 110l.1 .1-.1 .3-.2-.2zM152.6 114.5l.5-.1v.8M152.6 114.4v.8M152.8 111l.1-.1h.2v.3h-.2zM153 112.6h1M153 112.9h1M153.1 110l-.9 1.2M154.5 110.4l.2 .8 .3-.6 .2 .6 .2-.8M155.7 112.6l-.3-.4 .3-.2h.2l.3 .3-.8 .4v.3l.3 .2h.2l.3-.2v-.3l-.3-.1"/>
<path d="M155.9 111.1v.1M156.7 112v1.2M156.8 112.7l.3 .5M157 110.4h-.5l-.1 .2 .1 .6h.5M157.1 112.4l-.4 .5M157.5 111.1v.1M157.6 112.1l.2-.1h.3l.2 .1v.5l-.8 .6h.8"/>
</g>
<g fill="#00a200">
<circle cx="148.5" cy="93" r=".47"/>
<circle cx="148.5" cy="91.7" r=".47"/>
<circle cx="113.9" cy="101.6" r=".47"/>
<circle cx="136.1" cy="81.9" r=".47"/>
<circle cx="157" cy="81.9" r=".47"/>
<circle cx="148.5" cy="81.9" r=".47"/>
<circle cx="113.9" cy="104.1" r=".47"/>
<circle cx="113.9" cy="102.9" r=".47"/>
<circle cx="113.9" cy="105.4" r=".47"/>
<circle cx="91.7" cy="104.1" r=".47"/>
<circle cx="91.7" cy="77" r=".47"/>
<circle cx="84.3" cy="77" r=".47"/>
<circle cx="101.6" cy="91.7" r=".47"/>
<circle cx="180.5" cy="105.4" r=".47"/>
<circle cx="173.1" cy="105.4" r=".47"/>
<circle cx="173.1" cy="81.9" r=".47"/>
<circle cx="187.8" cy="81.9" r=".47"/>
<circle cx="180.5" cy="81.9" r=".47"/>
</g>
<g fill="none" stroke="#970091" stroke-width=".21">
<path d="M83.4 74l.6-.1 .1 .3-.8 .9h.8M85.2 73.9h-.6v.6l.4-.2 .3 .2-.1 .6-.6-.1M85.6 73.9l.5 1.2 .4-1.2M91.5 73.9h-.6l-.1 .6 .2-.2h.3l.3 .2v.4l-.2 .2-.6-.1M92.1 74l.4-.1 .2 .1v.9l-.2 .2-.4-.1zM93.1 73.9l.3 1.2 .4-1.2M129.1 71.4h-.6v.6l.4-.2 .3 .3-.1 .4h-.6M129.7 71.6l.1-.2h.4a.77 .77 0 0 1-.2 1.2l-.3-.3zM130.7 71.4l.4 1.2 .4-1.2M172.8 78.8h-.6v.6l.6-.1 .1 .2v.3l-.2 .2h-.4l-.1-.1M173.4 78.9l.4-.1 .2 .2v.8l-.2 .2a.77 .77 0 0 1-.4-1.1zM174.5 78.8l.3 1.2 .4-1.2"/>
<path d="M179.6 79.1l.4-.3v1.2M180.9 78.9h.1a.6 .6 0 0 1 .5 .4 .6 .6 0 0 1-.2 .7h-.2a.75 .75 0 0 1-.2-1.1zM181.8 78.8l.4 1.2 .5-1.2M187 79.1l.3-.3v1.2M188.3 78.9l.3-.1a.78 .78 0 0 1-.2 1.2l-.2-.5zM189.2 78.8l.4 1.2 .4-1.2M179.6 80h.7M187 80h.7"/>
</g>
<path d="M161.8 88.6h-.6l-.1 .6h.7v.6h-.7M162.3 88.8l.4-.2 .2 .3v.7l-.2 .3-.4-.1zM163.4 88.6l.3 1.3 .4-1.3" fill="none" stroke="#aaa" stroke-width=".21"/>
<g fill="none" stroke="#007170" stroke-width=".21">
<path d="M83.4 71.7l.4-.3v1.2M83.4 72.6h.7M84.2 69h-.1a.61 .61 0 0 0-.7 .2 .61 .61 0 0 0 .1 .8l.4 .1h.3M84.6 71.6l.2-.2h.3a.86 .86 0 0 1-.1 1.2l-.4-.3zM84.6 68.9h.8l-.4 .5 .3 .1v.6h-.7M85.8 71.7v.7l.2 .2 .4-.1M86.4 71.7v.9M90.8 71.7l.3-.3v1.2M90.8 72.6h.8M91.6 69a.58 .58 0 0 0-.8 .5 .58 .58 0 0 0 .8 .6M92.1 71.5l.4-.1 .2 .2v.7a.35 .35 0 0 1-.5 .3 .35 .35 0 0 1-.2-.4zM92.3 68.9l-.2 .8h.7"/>
<path d="M92.7 69.3v.8M93.3 71.5l.4-.1 .1 .2v.7a.35 .35 0 0 1-.4 .3 .35 .35 0 0 1-.2-.4zM94.4 71.9l.2-.2 .3 .1v.8M94.4 71.7v.9M109.9 72.6l.5-1.2 .4 1.2M110 72.3h.6M111.2 72h.6v-.6h-.6v1.2M112.7 68.9v1.2M112.9 71.4a.55 .55 0 0 0-.6 .5l.1 .6 .4 .1 .3-.3v-.2l-.3-.3h-.2l-.3 .3M113.5 71.5l.6-.1 .2 .2-.1 .3-.7 .7h.8M114 69h-.1a.61 .61 0 0 0-.7 .2 .61 .61 0 0 0 .1 .8l.4 .1h.3M114.4 69.3l.4-.4v1.2"/>
<path d="M114.4 70.1h.8M114.7 71.5l.6-.1 .1 .5-.8 .7h.8M115.9 71.5l.5-.1 .1 .2v.7a.35 .35 0 0 1-.4 .3 .35 .35 0 0 1-.2-.4zM117.1 71.5l.5-.1 .1 .2v.7a.35 .35 0 0 1-.4 .3 .35 .35 0 0 1-.3-.4zM127.8 69.3l.4-.4v1.2M127.8 70.1h.8M129.2 69a.6 .6 0 0 1 .6 .5 .6 .6 0 0 1-.5 .6l-.3-.5zM129.7 66.6l-.3-.2-.4 .4 .1 .7 .3 .2 .3-.1M130.3 69l.2-.1a.68 .68 0 0 1 .4 .6 .68 .68 0 0 1-.4 .6l-.3-.5zM130.8 66.4h-.5l-.1 .6h.6v.6h-.6M131.4 69.5l.2-.2 .3 .2v.6M131.4 69.3v.8"/>
<path d="M141.1 78.7l-.3 .9h.7M141.3 79.2v.8M141.4 76.3v1.2h.6M142 79.2v.8h.4l.1-.1M142.4 76.7l.4-.4v1.2M142.4 77.5h.7M142.5 79.2v.8M143 78.8h.8l-.5 1.2M172.2 76.7l.3-.4v1.2M172.2 77.5h.7M172.9 74l-.5-.1-.2 .5 .2 .7 .5-.1M173.3 73.9h.9l-.5 1.2"/>
<path d="M173.4 76.4l.4-.1 .2 .3v.7l-.1 .2-.5-.1zM174.6 76.4l.4-.1 .2 .3v.7l-.2 .2-.4-.1zM175.8 76.8l.4-.1 .1 .8M175.8 76.7v.8M179.6 76.4l.4-.1 .3 .4-.8 .8h.8M180.4 74l-.6-.1-.2 .2v.7l.2 .3 .6-.1M180.7 76.4l.5-.1 .3 .3-.8 .9h.8M181.1 74.4l-.3-.3 .2-.2h.4l.1 .4a.48 .48 0 0 0-.6 .2 .48 .48 0 0 0 .1 .6l.5-.1v-.5l-.2-.1M182 76.7l.1 .8 .4-.1M182.5 76.7v.8M187 76.4h.7v.4l-.8 .7h.8M187.7 74v-.1a.66 .66 0 0 0-.7 .4 .66 .66 0 0 0 .2 .8l.5-.1"/>
<path d="M188.2 76.4l.4-.1 .2 .4-.7 .8h.7M188.9 74.4l-.2 .2-.4-.1v-.5l.5-.1a.91 .91 0 0 1-.1 1.2h-.4M189.4 76.7v.8l.5-.1M189.9 76.7v.8M75.4 85.5h.6l.2-.1-.1-.4h-.7v1.1M75.7 85.5l.5 .6M76.1 87.8l.3-.4v1.2M76.1 88.6h.6M76.9 84.9l-.3 .8h.7M77.2 85.4v.7M77.3 87.4v1.2M77.4 88.2l.4 .4"/>
<path d="M77.8 85h.6v.5l-.7 .6h.7M77.8 87.8l-.5 .5M94.7 97.7l.3-.5v1.3M94.7 98.5h.8M95.7 95.5h.5l.2-.2v-.4l-.2-.1h-.5v1.2M96 97.4l.3-.2 .3 .3v.7l-.3 .3-.3-.1zM96 95.5l.4 .5M97.1 94.8l-.2 .8h.8M97.3 97.2l.4 .3v.7l-.4 .3a.9 .9 0 0 1 0-1.3zM97.5 95.2v.8M98 94.8h.8l-.5 .5h.4v.7h-.5l-.2-.1M98.3 97.2v1.3"/>
<path d="M98.4 98l.4 .5M98.8 97.7l-.5 .5M151.3 96.6h.5l.2-.1-.1-.4-.6-.1v1.2M151.3 85.5h.5l.2-.1-.1-.4h-.6v1.1M151.4 99l-.1-.1v-.3h.5v.3l-.5 .3v.5h.5l.1-.4-.2-.3M151.5 87.3l-.2 1h.7M151.6 96.6l.4 .6M151.6 85.5l.4 .6M151.8 87.8v.8M152.4 87.4h.7l-.4 .4 .4 .3v.3l-.2 .2-.5-.1M152.4 98.5v1.2M152.6 99.3l.3 .4"/>
<path d="M152.8 96l-.4 .9h.8M152.8 84.9l-.4 .8h.8M152.9 98.9l-.5 .5M153 85.4v.7M153 96.5v.7M153.4 98.6l.5-.1 .2 .3-.7 .9h.7M153.6 87.4v1.2M153.8 88.2l.3 .4M154 84.9l-.4 .8h.8M154.1 87.8l-.5 .5M154.2 85.4v.7M154.3 96h-.6l-.1 .6 .2-.1h.3l.2 .1v.5h-.7"/>
<path d="M113 112.1h-.2a.64 .64 0 0 0-.6 .6 .64 .64 0 0 0 .6 .6l.2-.1v-.5h-.2M114.3 112.1v1.2l-.7-1.2v1.2M114.8 112.1l.6 .1 .1 .2v.6l-.4 .3h-.3z"/>
</g>
<path d="M161.1 86.3l.1-.2h.4l.2 .2v.4l-.8 .7h.8M161.8 83.9l-.2-.2a.65 .65 0 0 0-.5 .6 .65 .65 0 0 0 .5 .7l.2-.2M162.3 86.3l.1-.2h.4l.1 .2v.4l-.7 .7h.7M162.9 83.7h-.2l-.4 .3 .1 .9a.43 .43 0 0 0 .6-.2 .43 .43 0 0 0-.1-.5h-.5l-.1 .2M163.5 86.7l.4-.1 .2 .2-.1 .5h-.5M163.5 86.6v1.2" fill="none" stroke="#a2a2a2" stroke-width=".21"/>
<path d="M153.9 84.1l6.4 5.6M160.3 84.1l-6.4 5.6" fill="none" stroke="#e00" stroke-width=".42"/>
</svg>
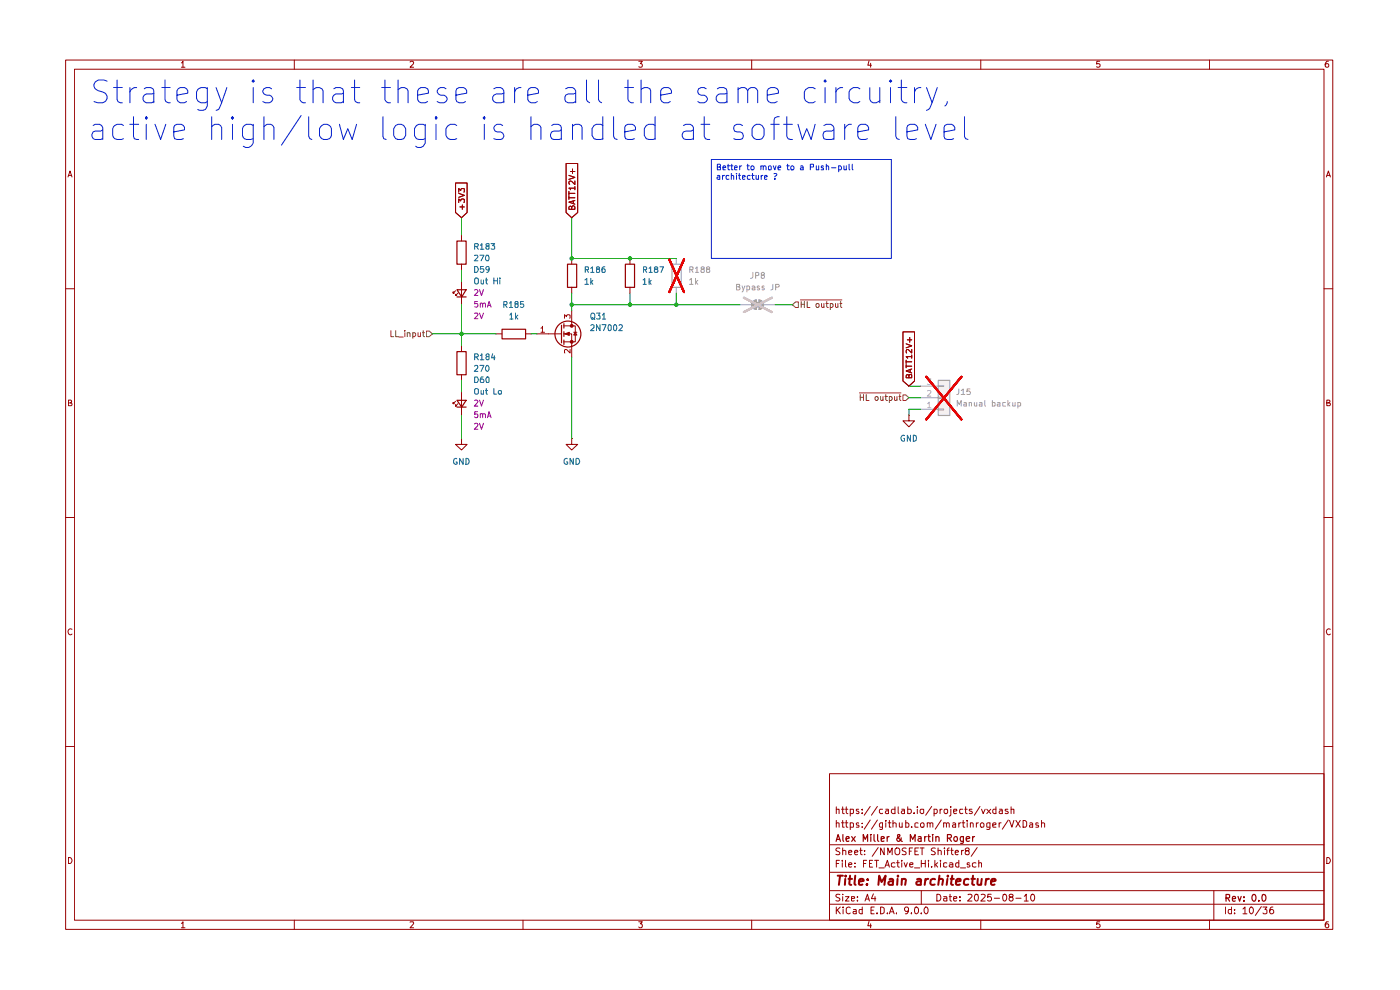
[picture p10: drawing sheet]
<svg xmlns="http://www.w3.org/2000/svg" width="297mm" height="210mm" viewBox="0 0 297 210" stroke-linecap="round" stroke-linejoin="round" font-family="sans-serif">
<g fill="none" stroke="#980000" stroke-width=".21">
<path d="M13.9 12.7h268.8v184.4h-268.8zM15.8 14.7h265.1v180.5h-265.1zM38.5 13.3h.1l.2-.3v1.3M38.5 14.3h.7M62.4 12.7v2M87 13.2l.5-.2 .3 .2-.1 .4-.7 .7h.8M111 12.7v2M135.5 13h.8l-.5 .5 .4 .1v.6h-.7M159.5 12.7v2M184.4 12.9l-.3 .9h.8M184.7 13.4v.9M208.1 12.7v2"/>
<path d="M233.3 13h-.6l-.1 .6h.7v.6h-.7M256.6 12.7v2M281.8 13a.71 .71 0 0 0-.7 .5 .71 .71 0 0 0 .3 .8l.4-.1v-.6l-.4-.1-.3 .3M14.4 37.5l.5-1.2 .4 1.2M14.5 37.2h.7M281.4 37.5l.4-1.2 .4 1.2M281.5 37.2h.6M13.9 61.3h1.9M280.9 61.3h1.8M14.5 85.5h.4l.3-.3-.2-.3h-.5v1.2h.6l.2-.5-.4-.1M281.5 85.5h.4l.2-.3-.1-.3h-.5v1.2h.6l.1-.5-.3-.1M13.9 109.8h1.9"/>
<path d="M280.9 109.8h1.8M15.3 133.5a.59 .59 0 0 0-.9 .5 .59 .59 0 0 0 .8 .6l.1-.1M282.2 133.5a.59 .59 0 0 0-.8 .5 .59 .59 0 0 0 .7 .6l.1-.1M13.9 158.4h1.9M280.9 158.4h1.8M176 164.1h104.9v31.1h-104.9zM176 179.2h104.9M177.4 174.7l.2-.2 .4 .1v.9M177.4 171.7h.6v.9M177.4 171.1v1.5M177.4 174v1.5M178.2 180l-.6-.1-.3 .2 .1 .4 .8 .4-.1 .3h-.8"/>
<path d="M178.5 174.5h.6M178.5 171.7h.6M178.8 174v1.5h.3M178.8 171.1v1.4l.3 .1M178.8 179.9v1.4M179.4 174.5h.5M179.4 171.7h.5M179.5 174v1.3l.1 .2h.3M179.5 171.1v1.3l.4 .2M180.4 174.6l.4-.1 .3 .2v.7l-.7 .1M180.4 172.5l.4 .1 .3-.2-.1-.7h-.6v1.4M180.4 174.5v1.5"/>
<path d="M182.2 174.6l-.4-.1-.2 .2 .2 .3h.4v.5h-.6M182.2 171.7h-.5l-.1 .2 .5 .2 .1 .3-.1 .2-.5-.1M182.6 179.9v1.2l.3 .2M182.9 175.4v.1M182.9 174.6v.1M182.9 172.4v.2M182.9 171.7v.1M184.6 173.9l-1.3 2M184.6 171.1l-1.3 1.8M186.1 173.9l-1.2 2M186.1 171.1l-1.2 1.8M186.3 179.8l-1.3 1.8"/>
<path d="M187.2 174.5v1.2a.36 .36 0 0 1-.6 .2M187.2 174.6l-.4-.1-.2 .3v.6l.6 .1M187.2 171.7h-.5l-.1 .2v.4l.2 .3 .4-.1M187.6 179.9v1.4l-.8-1.4v1.4M187.9 174v.2M187.9 171.7h.5l.1 .9M187.9 174.5v1M188.4 174.5h.6M188.5 172h-.5l-.2 .2 .2 .4 .5-.1M188.7 174v1.5h.3M189.4 174.7l.3-.2 .4 .2v.8M189.4 174v1.5"/>
<path d="M189.9 171.7h-.6l-.2 .6a.52 .52 0 0 0 .8 .2M189.9 171.1v1.5M190.5 171.1v1.3l.2 .2M190.8 174.5l.1 1 .5-.1M191.3 171.7h.5l.1 .9M191.4 174.5v1M191.9 172h-.5l-.2 .2 .2 .4 .5-.1M192.1 174v1.5l.6-.1 .1-.6a.45 .45 0 0 0-.7-.2M192.2 180a.6 .6 0 0 0-.8 .1l.1 .4 .6 .2 .1 .2-.2 .4-.6-.1M192.6 171.7h.6l.1 .6a.52 .52 0 0 1-.7 .2M192.6 171.1v1.5M193.4 175.4v.1"/>
<path d="M193.6 179.9h-.7v1.4M193.9 172.4v.2M194.6 171.1v.1M194.6 171.7v.9M194.8 174.6l-.5-.1-.2 .2v.7l.7 .1M194.9 179.9h-.8v1.4h.8M195.2 179.9h.8M195.3 174.8a.45 .45 0 0 1 .7-.2v.9l-.6-.1zM195.3 171.7h.7l-.1 .8a.45 .45 0 0 1-.7-.2zM195.6 179.9v1.4M196.7 174.7l.2-.2 .4 .2v.8M196.7 174.5v1"/>
<path d="M197.3 174.7l.2-.2 .4 .1v.9M197.6 171.1l-1.2 1.8M198.2 172.5l.4 .1 .2-.3-.1-.6h-.5v1.4M198.4 180a.6 .6 0 0 0-.8 .1v.4l.8 .4-.2 .4-.6-.1M199 179.9v1.4M199.4 171.7v.9M199.7 173.9l-1.3 2M199.9 171.7h-.3l-.2 .2M200.2 174.7l.2-.2 .4 .2v.8M200.2 174.5v1M200.4 179.9v.1M200.4 171.7h.6v.8l-.5 .1-.2-.3z"/>
<path d="M200.8 174.7l.2-.2 .4 .2v.8M201.4 179.9l-.4 .1v1.3M201.7 171.7v1.1l-.3 .3M201.7 171.1v.1M201.9 179.9v1.2l.3 .2M202.1 174.6l.4-.1 .2 .2v.8h-.6v-.4l.6-.2M202.3 172.1l.7-.1-.1-.3h-.5l-.1 .1v.6l.2 .2 .4-.1M203.4 174.5v1M203.8 174.5l-.4 .3M204.1 174.5h.6M204.3 171.7h-.6l-.1 .2 .1 .6h.6M204.3 174v1.3l.1 .2h.3"/>
<path d="M204.7 171.7h.5M204.8 171.1v1.3l.4 .2M205.2 174v.2M205.2 174.5v1M205.9 174.7l.1-.2 .5 .2v.8M205.9 174.5v1M206.2 171.7h-.5l-.1 .2 .6 .3 .1 .2-.3 .2-.4-.1M207.1 174.5v1M207.3 179.8l-1.3 1.8M207.6 174.5l-.5 .3M207.9 171.1l-1.2 1.8M208.2 174.5h.3l.2 .3-.1 .7h-.5l-.1-.3v-.4z"/>
<path d="M208.2 171.7l.4 .9 .4-.9M209.3 171.7l.9 .9M210 174.5v1.2l-.2 .3-.5-.1M210 174.6l-.4-.1-.3 .2v.7l.7 .1M210.2 171.7l-.9 .9M210.6 175l.7-.1v-.3l-.4-.1-.3 .2 .1 .8h.6M211.3 171.7h-.5l-.2 .6a.45 .45 0 0 0 .7 .2M211.3 171.1v1.5M212 174.5v1M212 171.7h.6v.9M212.4 174.5l-.4 .3M212.6 172h-.5l-.1 .2 .1 .4 .5-.1"/>
<path d="M213.8 171.7h-.5l-.1 .2 .6 .3 .1 .2-.2 .2-.5-.1M213.9 173.9l-1.3 2M214.2 174l.5 1.5 .4-1.5M214.5 171.7h.6v.9M214.5 171.1v1.5M215.5 174l.9 1.5M216.4 174l-.9 1.5M217 174h.4l.4 .4v.7l-.3 .4h-.5zM218.5 174.6l.4-.1 .2 .2v.8h-.6l-.1-.4 .7-.2M220.3 174.6h-.6v.4h.6v.2v.3h-.6M220.9 174.7l.3-.2 .4 .2v.8M220.9 174v1.5"/>
<path d="M14.5 181.9a.65 .65 0 0 1 .8 .6 .65 .65 0 0 1-.8 .7zM38.5 195.9l.3-.4v1.3M38.5 196.8h.7M62.4 195.2v1.9M87 195.6l.7-.1 .1 .3-.8 1h.8M111 195.2v1.9M135.5 195.5h.8l-.5 .5 .5 .2-.1 .5-.5 .1-.2-.2M159.5 195.2v1.9M176 191.8h104.9M176 188.9h104.9M176 185h104.9M177.4 192.4v1.4"/>
<path d="M177.4 183.2h.5M177.6 193l.7 .8M178.1 182.5h-.7v1.4M178.2 189.8h-.8l-.1 .3 .8 .4 .1 .4-.3 .2-.6-.1M178.3 192.4l-.9 .8M178.7 182.5v.2M178.7 183v.9M178.8 189.7v.1M178.8 180.5l.4-.1 .2 .1v.8M178.8 190.2v.9M178.9 192.4v.2M178.9 192.9v.9"/>
<path d="M179.4 190.2h.7l-.7 .9h.7M179.4 182.5v1.3l.1 .1M180 183.4l.7-.1-.2-.3-.5 .2v.6l.3 .1 .3-.1M180 180.8l.7-.1-.2-.3-.5 .1v.6l.3 .2 .3-.1M180.4 192.6l-.4-.2-.5 .3 .1 1 .4 .1 .4-.1M180.6 190.6l.7-.1-.1-.3h-.6v.8h.6M181.1 192.9h.5v.9M181.3 180.8l.7-.1-.2-.3h-.3l-.2 .1v.6l.2 .2 .4-.1M181.4 183.8v.1M181.4 183.1v.1M181.6 193.2l-.5 .1-.1 .2 .1 .3h.5M181.9 191v.1"/>
<path d="M181.9 190.2v.2M182.4 180.4h.5M182.9 192.9h-.5l-.2 .7a.45 .45 0 0 0 .7 .2M182.9 192.4v1.4M183.2 183.2h.5M183.4 181.2v.1M183.4 180.5h.1M183.5 191.1l.5-1.4 .4 1.4M183.7 190.7h.7M183.8 182.5h-.6v1.4M184.4 195.4l-.3 1h.8M184.4 183.2h.5"/>
<path d="M184.7 196v.8M184.8 193.1h.5M185.1 182.5h-.7v1.4h.7M185.3 189.6l-.4 1h.9M185.5 192.4h-.7v1.4h.7M185.5 182.5h.9M185.6 190.2v.9M186 182.5v1.4M186 193.7v.1M186.5 184.1h1.1M186.8 192.4h.4l.4 .3v.8l-.4 .3h-.4zM187.7 183.9l.6-1.4 .4 1.4"/>
<path d="M187.9 183.5h.7M188.3 193.7v.1M188.3 181.3v-1.4l.5 1 .5-1v1.4M188.7 193.8l.5-1.4 .5 1.4M188.8 193.4h.7M189.9 183.1l-.5-.1-.3 .3 .1 .5h.7M189.9 180l.3-.1a.57 .57 0 0 1 .7 .5v.4a.57 .57 0 0 1-.7 .5l-.1-.1a.99 .99 0 0 1-.2-1.2zM190.2 193.7v.1M190.2 183h.6M190.5 182.5v1.3l.3 .1M191.3 182.5v.2M191.3 183v.9"/>
<path d="M191.8 183l.3 .9 .4-.9M192.7 193l-.2 .3h-.4l-.2-.3v-.3l.2-.3h.4l.2 .3v.8l-.2 .3h-.4M192.9 180.5h.4M193 183.4l.7-.1v-.2l-.5-.1-.2 .2 .1 .6h.6M193.3 193.7v.1M194 184.1h1.1M194.1 192.6l.2-.2a.75 .75 0 0 1 .6 .7 .75 .75 0 0 1-.6 .7l-.2-.1-.1-.4zM194.1 180.5h.5M195.4 193.7v.1M195.4 183.2h.9M195.4 182.5v1.4M195.4 188.9v2.9"/>
<path d="M196.3 182.5v1.4M196.4 192.4h.1a.8 .8 0 0 1 .4 .8 .8 .8 0 0 1-.5 .6 .89 .89 0 0 1 0-1.4zM197 182.5v.2M197 183v.9M197.6 183.8v.1M198.3 182.5v1.4M198.5 183.4l.4 .5M198.7 189.7a.73 .73 0 0 1 .9 .7 .73 .73 0 0 1-.9 .7zM198.9 183l-.6 .5M199 180.5l.4-.1 .3 .1v.8M199.5 182.5v.2M199.5 183v.9"/>
<path d="M200.2 190.2h.6l.1 .9M200.4 180.4v.9M200.9 190.5l-.7 .1v.4h.7M200.9 183.1h-.7v.7h.7M200.9 180.4h.5M201.4 190.2h.5M201.5 183.1l.4-.1 .2 .2v.7M201.5 189.7v1.3l.4 .1M201.7 180.4h.5M202.1 183.3l-.6 .1-.1 .2 .2 .3 .5-.1M202.3 190.6l.7-.1-.1-.3h-.5l-.1 .2v.6l.2 .1 .4-.1M202.6 180.8l.7-.1-.1-.3-.6 .1v.6l.3 .2 .3-.1"/>
<path d="M203.4 183.1l-.4-.1-.3 .3 .1 .5h.6M203.4 182.5v1.4M203.7 191v.1M203.7 190.2v.2M203.7 184.1h1.1M204 180.4v.9M204.4 180.4l-.4 .1v.1M205.1 180.5l-.3-.1v-.3a.46 .46 0 0 1 .4-.3 .46 .46 0 0 1 .4 .3l-.1 .4h-.4a.44 .44 0 0 0-.3 .5 .44 .44 0 0 0 .6 .3l.2-.2-.1-.6h-.1M205.4 189.8l.5-.1 .3 .4-.9 1h.9M205.7 183.1h-.5v.3l.5 .1 .1 .3-.3 .1-.3-.1M206.9 189.8h.5a1.01 1.01 0 0 1-.2 1.3 .87 .87 0 0 1-.3-1.3zM207 183.1l-.4-.1-.3 .3 .1 .5h.6"/>
<path d="M207.6 183.1h.6v.8M207.6 182.5v1.4M208.1 195.2v1.9M208.1 189.8h.8l.1 .3-.9 1h.9M210.3 189.7h-.7l-.1 .7 .6-.2 .2 .3v.4l-.2 .2-.6-.1M210.9 190.5h1.1M212.8 189.8l.3-.1a.73 .73 0 0 1 .5 .7 .73 .73 0 0 1-.5 .7l-.3-.1-.1-.5zM214.3 190.3l-.2-.3 .1-.2h.6v.4l-.5 .1-.2 .2v.4l.2 .2h.4l.2-.2v-.4l-.2-.2M215.5 190.5h1.1M217.3 190.1l.4-.4v1.4M217.3 191.1h.8M218.8 189.8l.2-.1a.76 .76 0 0 1 .5 .7 .76 .76 0 0 1-.5 .7 1.01 1.01 0 0 1-.2-1.3z"/>
<path d="M233.3 195.5h-.6l-.1 .6 .2-.1h.3l.3 .2v.3l-.3 .3h-.3l-.2-.2M256.6 195.2v1.9M257.5 188.9v6.3M260 192.4v1.4M261.2 192.9h-.5l-.1 .3v.4l.2 .2h.4M261.2 192.4v1.4M261.9 193.7v.1M261.9 192.9v.2M263.7 192.8l.4-.4v1.4M263.7 193.8h.8M265.1 192.7l.5-.3a.8 .8 0 0 1 .3 .8 .8 .8 0 0 1-.5 .6 .93 .93 0 0 1-.3-1.1zM267.6 192.3l-1.3 1.9"/>
<path d="M267.9 192.4h.9l-.5 .5 .5 .2v.6l-.3 .1h-.4l-.2-.1M270 192.4l-.5 .2a1.02 1.02 0 0 0 .1 1.2h.4l.2-.2v-.4l-.3-.3h-.3l-.2 .3M281.5 181.9a.65 .65 0 0 1 .7 .6 .65 .65 0 0 1-.7 .7zM281.8 195.5h-.4l-.3 .5v.5l.3 .3 .4-.1v-.7h-.4l-.3 .2"/>
</g>
<g fill="none" stroke="#980000" stroke-width=".25">
<path d="M177.4 178.5l.4-1.5 .5 1.5M177.5 178h.6M178.8 177v1.2l.2 .3M179.5 178l.7-.2-.2-.3h-.4l-.1 .7 .2 .3 .4-.1M180.7 177.5l.7 1M181.4 177.5l-.7 1M183.1 178.5v-1.5l.5 1 .5-1v1.5M184.7 177v.1M184.7 177.5v1M185.4 177v1.2l.3 .3M186.2 177v1.2l.2 .3M186.9 178l.7-.2-.1-.3h-.6v.9h.6"/>
<path d="M188.2 177.5v1M188.6 177.5l-.4 .3M191.2 177.7v.3l-.5 .5a.43 .43 0 0 1-.4-.2 .43 .43 0 0 1 0-.5l.6-.5-.1-.3h-.3a.55 .55 0 0 0 .2 .8l.7 .7M193.1 178.5v-1.5l.5 1 .5-1v1.5M194.8 177.5h.6v1M195.4 177.8l-.4 .1-.3 .2 .3 .4 .4-.1M196.2 177.5v1M196.5 177.5h-.2l-.1 .3M196.8 177.5h.6M197 177v1.2l.4 .3M197.9 177v.1M197.9 177.5v1"/>
<path d="M198.5 177.6l.1-.1a.36 .36 0 0 1 .6 .2v.8M198.5 177.5v1M201 177.8l.7-.1 .1-.2v-.4l-.8-.1v1.5M201.3 177.8l.5 .7M204.4 177.5v1.1l-.2 .3h-.4M204.4 177.5h-.4l-.3 .3 .1 .6h.6M205 178l.7-.2-.1-.3h-.4l-.2 .2 .1 .7h.5M206.3 177.5v1M206.8 177.5l-.5 .3M260.1 190.5l.7-.1 .1-.6-.8-.1v1.5M260.4 190.5l.5 .7M261.4 190.7l.7-.1-.1-.4h-.5l-.1 .7 .2 .3 .4-.1"/>
<path d="M262.6 190.2l.4 1 .3-1M263.9 191v.2M263.9 190.2v.2M265.8 189.8l.1-.1a.76 .76 0 0 1 .6 .8 .76 .76 0 0 1-.6 .7 1.01 1.01 0 0 1-.1-1.4zM267 191v.2M267.8 189.8l.2-.1a.75 .75 0 0 1 .6 .8 .75 .75 0 0 1-.6 .7l-.2-.2-.1-.4z"/>
<circle cx="202.7" cy="178" r=".48"/>
</g>
<g fill="none" stroke="#980000" stroke-width=".42">
<path d="M177.7 185.8h1.1M178.2 185.8l-.2 1.9M179.3 186.4l-.1 1.3M179.4 185.8v.1M180 186.4h.8M180.3 185.8l-.1 1.6 .4 .3M181.4 185.8l-.1 1.6 .2 .3M182.2 187l1-.1-.1-.4a.6 .6 0 0 0-.8 .2v.9h.7M184 187.5l-.1 .2-.1-.1 .2-.1-.1 .2M184.1 186.5v.2M186.3 187.7l.2-1.9 .5 1.3 .9-1.3-.3 1.9M188.7 186.5h.7v1.2"/>
<path d="M189.5 186.9h-.7l-.3 .3v.2l.2 .3 .7-.1M190.4 186.4l-.1 1.3M190.5 185.8v.1M191.3 186.6l.1-.1a.48 .48 0 0 1 .8 .2l-.2 1M191.3 186.4v1.3M194.6 186.5h.7v1.2M195.4 186.9h-.7l-.3 .3v.2l.2 .3 .7-.1M196.3 186.4l-.1 1.3M196.9 186.4l-.4 .1-.2 .3M198.4 186.5a.65 .65 0 0 0-1 .3v.7a.64 .64 0 0 0 .9 .1M199.2 186.6l.1-.1a.48 .48 0 0 1 .8 .2l-.2 1M199.3 185.8l-.3 1.9"/>
<path d="M201 186.4l-.2 1.3M201.1 185.8v.1M201.7 186.4h.6M202 185.8l-.2 1.6 .4 .3M202.9 187l.9-.1v-.4l-.6-.1-.3 .3v.9h.7M205.5 186.5a.65 .65 0 0 0-1 .3v.7a.64 .64 0 0 0 .9 .1M206.1 186.4h.7M206.4 185.8l-.2 1.6 .5 .3M207.4 186.4v1.2l.5 .1 .3-.2M208.3 186.4l-.2 1.3M209.2 186.4l-.2 1.3M209.8 186.4l-.4 .1-.2 .3"/>
<path d="M210.2 187l1-.1v-.4a.6 .6 0 0 0-.9 .2v.9h.7"/>
</g>
<path d="M142 55l3.1 7M145.1 55l-3.1 7M196.5 79.9l7.5 9.1M204 79.9l-7.5 9.1" fill="none" stroke="#e00" stroke-width=".42"/>
<path d="M157.8 63.2l5.9 3M163.7 63.2l-5.9 3" fill="none" stroke="#c9c9c9" stroke-width=".42"/>
<path d="M199 80.6h2.5v7.5h-2.5z" fill="#f1f1f1"/>
<path d="M142 55l3.1 7M145.1 55l-3.1 7M196.5 79.9l7.5 9.1M204 79.9l-7.5 9.1" fill="none" stroke="#e00" stroke-width=".42"/>
<path d="M157.8 63.2l5.9 3M163.7 63.2l-5.9 3" fill="none" stroke="#c9c9c9" stroke-width=".42"/>
<g fill="none" stroke="#980000" stroke-width=".21">
<path d="M191.6 70.4h2.4v10.4l-1.2 1.1-1.2-1.1zM192.2 72.9l1.2 .5-1.2 .4M192.2 76.4v.7M192.2 77.3v.7M192.2 77.7h1.2M192.2 76.7h1.2M192.5 72.1h.9M192.8 79.7l.1-.2h.5v.6h-1.2l.1-.6h.3l.2 .2v.4M193 71.6v1M193.1 78.4v.5M193.4 78.3l-1.2 .4 1.2 .4M193.4 75.6h-1.2l.4 .4"/>
<path d="M193.4 74.1v.8l-.8-.8-.4 .3 .1 .5M193.4 75.3v.7"/>
</g>
<path d="M191.6 83.8h.5l.7 .6-.7 .6h-.5z" fill="#fff"/>
<g fill="none" stroke="#805e00" stroke-width=".21">
<path d="M182.3 83.3h8.8M182.5 83.7v1.3M182.5 84.3h.7M183.2 83.7v1.3M183.8 83.7v1.3h.6M185.7 84.2l.3-.1 .3 .3v.3l-.3 .3-.4-.3zM186.8 84.1v.7l.2 .2 .3-.2M187.3 84.1v.9M187.7 84.1h.6M187.9 83.7v1.1l.4 .2M188.7 84.2l.3-.1 .3 .3v.3l-.3 .3-.3-.1M188.7 84.1v1.3"/>
<path d="M189.8 84.1v.8l.3 .1 .2-.2M190.3 84.1v.9M190.7 84.1h.4M190.9 83.7v1.1l.2 .2M191.6 83.8h.5l.7 .6-.7 .6h-.5z"/>
</g>
<path d="M168.1 64.6l.7-.6h.6v1.2h-.6z" fill="#fff"/>
<g fill="none" stroke="#805e00" stroke-width=".21">
<path d="M168.1 64.6l.7-.6h.6v1.2h-.6zM169.8 63.6h8.8M170 64v1.2M170 64.6h.6M170.6 64v1.2M171.2 64v1.2h.6M173.2 64.5h.5v.6l-.4 .1-.2-.2zM174.3 64.4v.7l.2 .1 .3-.1M174.8 64.4v.8M175.2 64.4h.5M175.4 64v1.1l.3 .1M176.1 64.5l.4-.1 .2 .2v.4l-.2 .2-.4-.1"/>
<path d="M176.1 64.4v1.3M177.2 64.4v.7l.2 .1 .4-.1M177.8 64.4v.8M178.2 64.4h.4M178.3 64v1.1l.3 .1"/>
</g>
<g fill="none" stroke="#980000" stroke-width=".21">
<path d="M97.9 73.3v1.2M97.9 79.5v1.1M116.4 70.8h2.7M119.6 69.1h2.4v3.4h-2.4M96.6 85.1l-.5 .5v-.2v.2h.3M97.1 85.6l-.5 .5v-.2v.2h.3M97.9 93v1.3h1.2l-1.2 1.2-1.3-1.2h1.3M97.9 93h.1M97.9 83.2v4.9M121.3 93v1.3h1.2l-1.2 1.2-1.2-1.2h1.2M121.3 93h.1M192.8 88.1v1.2h1.2l-1.2 1.2-1.2-1.2h1.2"/>
<path d="M192.8 88.1h.1"/>
</g>
<path d="M199 80.7h2.5v7.4h-2.5z" fill="none" stroke="#aaa" stroke-width=".25"/>
<path d="M195.3 86.8h3.7M195.3 84.4h3.7M195.3 81.9h3.7M199 86.7h1.2v.3h-1.2zM199 84.3h1.2v.2h-1.2zM199 81.8h1.2v.2h-1.2z" fill="none" stroke="#aaa" stroke-width=".21"/>
<path d="M196.7 80.4h.8l-.4 .4 .4 .3-.1 .4h-.7M196.8 85.6l.3-.3v1.2M196.8 82.9l.5-.1 .2 .4-.8 .8h.8M196.8 86.5h.7" fill="none" stroke="#b2b2b2" stroke-width=".21"/>
<path d="M196.5 79.9l7.5 9.1M204 79.9l-7.5 9.1" fill="none" stroke="#e00" stroke-width=".42"/>
<path d="M96.9 74.6h2v4.9h-2zM119.1 69v3.7M119.6 68.7v.9M119.6 70.4v1M119.6 72.1v1M96.9 84.9h2l-.9 1.5zM96.9 86.4h2" fill="none" stroke="#980000" stroke-width=".25"/>
<path d="M119.8 70.8l1-.3v.7z" fill="#980000"/>
<path d="M119.8 70.8l1-.3v.7zM121.3 68.4v.7" fill="none" stroke="#980000" stroke-width=".21"/>
<circle cx="120.5" cy="70.9" r="2.75" fill="none" stroke="#980000" stroke-width=".25"/>
<path d="M121.1 68.9h.4v.4h-.4z" fill="#980000"/>
<path d="M121.1 68.9h.4v.4h-.4z" fill="none" stroke="#980000" stroke-width=".21"/>
<path d="M121.1 72.3h.4v.4h-.4z" fill="#980000"/>
<path d="M121.3 54.8v1.2M105.3 70.8h1.2M111.5 70.8h1.1M113.9 70.8h2.5M119.6 70.8h1.7v4.9M121.1 72.3h.4v.4h-.4zM121.3 60.9v1.3M121.3 65.9v2.5M121.7 70.5h.7M122 70.5l.4 .6h-.7z" fill="none" stroke="#980000" stroke-width=".21"/>
<path d="M114.8 69.6l.3-.4v1.3M114.8 70.5h.7M119.8 67.5v-.7l.4 .4 .2-.4h.5v.7M120.9 74.1v.8l-.8-.8-.3 .2v.6" fill="none" stroke="#bd0000" stroke-width=".21"/>
<path d="M120.4 56h1.9v5h-1.9zM106.5 69.8h5v2.1h-5z" fill="none" stroke="#980000" stroke-width=".25"/>
<path d="M160.2 64.1h1v1h-1z" fill="#aaa"/>
<path d="M159.8 63.9l.7-.3v2.1a1.02 1.02 0 0 1-1-.7 1.02 1.02 0 0 1 .3-1.1zM160.2 64.1h1v1h-1z" fill="none" stroke="#aaa" stroke-width=".21"/>
<path d="M159.8 63.9l.7-.3v2.1a1.02 1.02 0 0 1-1-.7 1.02 1.02 0 0 1 .3-1.1z" fill="#aaa"/>
<path d="M160.5 63.6a1.02 1.02 0 0 0-1 1 1.02 1.02 0 0 0 1 1.1M161 63.6a1.02 1.02 0 0 1 1 1 1.02 1.02 0 0 1-1 1.1" fill="none" stroke="#aaa" stroke-width=".21"/>
<path d="M161 63.6a1.02 1.02 0 0 1 1 1 1.02 1.02 0 0 1-1 1.1z" fill="#aaa"/>
<path d="M143.5 54.8v1.2M143.5 60.9v1.3M157 64.6h2.5M161 63.6v2.1M161 63.6a1.02 1.02 0 0 1 1 1 1.02 1.02 0 0 1-1 1.1M162 64.6h2.5" fill="none" stroke="#aaa" stroke-width=".21"/>
<path d="M157.8 63.2l5.9 3M163.7 63.2l-5.9 3" fill="none" stroke="#c9c9c9" stroke-width=".42"/>
<path d="M96.9 51.1h2v4.9h-2zM132.7 56h1.9v5h-1.9z" fill="none" stroke="#980000" stroke-width=".25"/>
<g fill="none" stroke="#980000" stroke-width=".21">
<path d="M96.6 38.8h2.5v6.3l-1.2 1.1-1.3-1.1zM120.1 34.7h2.4v10.4l-1.2 1.1-1.2-1.1zM120.7 37.2l1.3 .4-1.3 .5M121 36.4h1M121.4 35.9v.9M122 39.9h-1.3l.3 .4M122 38.4v.8l-1-.8-.3 .2 .2 .5M122 39.6v.7M97.3 43v-.8l.4 .4 .3-.4 .5 .1-.1 .7M97.3 41l1.2 .4-1.2 .5M97.3 40.8v-.8l.4 .4 .2-.4h.5v.8M97.6 43.9h.9"/>
<path d="M97.9 49.8v1.3M97.9 56v1.3M98.1 43.5v.9M120.7 40.6v.8M120.7 41.5v.8M120.7 41.9h1.3M120.7 41h1.3M121.3 44l.2-.4 .5 .3v.5h-1.3l.1-.6h.5v.6M121.6 42.6v.6M122 42.5l-1.3 .4 1.3 .4M133.6 54.8v1.2M133.6 60.9v1.3"/>
</g>
<path d="M142.6 56h1.9v5h-1.9z" fill="none" stroke="#aaa" stroke-width=".25"/>
<path d="M142 55l3.1 7M145.1 55l-3.1 7" fill="none" stroke="#e00" stroke-width=".42"/>
<path d="M90.5 70.2h.6l.6 .6-.6 .6h-.6z" fill="#fff"/>
<g fill="none" stroke="#805e00" stroke-width=".21">
<path d="M82.9 70.1v1.3h.6M83.9 70.1v1.3h.6M84.6 71.5h1M85.9 70.1v.1M85.9 70.6v.8M86.4 70.6h.4l.2 .1v.7M86.4 70.6v.8M87.6 70.6h.3l.3 .2v.4l-.3 .2-.3-.1M87.6 70.6v1.1M88.7 70.6v.7l.3 .1 .2-.2M89.2 70.6v.8M89.6 70.6h.4"/>
<path d="M89.8 70.1v1.1l.2 .2M90.5 70.2h.6l.6 .6-.6 .6h-.6z"/>
</g>
<path d="M96.9 61.5h2l-.9 1.5zM96.9 63h2" fill="none" stroke="#980000" stroke-width=".25"/>
<g fill="none" stroke="#980000" stroke-width=".21">
<path d="M96.6 38.8h2.5v6.3l-1.2 1.1-1.3-1.1zM120.1 34.7h2.4v10.4l-1.2 1.1-1.2-1.1zM120.7 37.2l1.3 .4-1.3 .5M121 36.4h1M121.4 35.9v.9M122 39.9h-1.3l.3 .4M122 38.4v.8l-1-.8-.3 .2 .2 .5M122 39.6v.7M97.3 43v-.8l.4 .4 .3-.4 .5 .1-.1 .7M97.3 41l1.2 .4-1.2 .5M97.3 40.8v-.8l.4 .4 .2-.4h.5v.8M97.6 43.9h.9"/>
<path d="M97.9 59.7v4.9M98.1 43.5v.9M120.7 40.6v.8M120.7 41.5v.8M120.7 41.9h1.3M120.7 41h1.3M121.3 44l.2-.4 .5 .3v.5h-1.3l.1-.6h.5v.6M121.6 42.6v.6M122 42.5l-1.3 .4 1.3 .4M96.6 61.7l-.5 .5v-.3v.3h.3M97.1 62.2l-.5 .5v-.3v.3h.3M191.6 70.4h2.4v10.4l-1.2 1.1-1.2-1.1z"/>
<path d="M192.2 72.9l1.2 .5-1.2 .4M192.2 76.4v.7M192.2 77.3v.7M192.2 77.7h1.2M192.2 76.7h1.2M192.5 72.1h.9M192.8 79.7l.1-.2h.5v.6h-1.2l.1-.6h.3l.2 .2v.4M193 71.6v1M193.1 78.4v.5M193.4 78.3l-1.2 .4 1.2 .4M193.4 75.6h-1.2l.4 .4M193.4 74.1v.8l-.8-.8-.4 .3 .1 .5"/>
<path d="M193.4 75.3v.7"/>
</g>
<g fill="none" stroke="#00a200" stroke-width=".21">
<path d="M97.9 46.2v3.6M97.9 57.3v2.4M121.3 46.2v8.6h22.2M91.7 70.8h13.6M97.9 64.6v8.7M112.6 70.8h1.3M121.3 64.6h35.7M121.3 62.2v3.7M121.3 75.7v17.3M133.6 62.2v2.4M143.5 62.2v2.4M164.5 64.6h3.6"/>
<path d="M97.9 80.6v2.6M97.9 88.1v4.9M192.8 84.4h2.5M192.8 81.9h2.5M195.3 86.8h-2.5v1.3"/>
</g>
<g fill="none" stroke="#001dcd" stroke-width=".21">
<path d="M22.7 17.2l-.6-.2h-1.2a1.16 1.16 0 0 0-1 1.1 1.16 1.16 0 0 0 1 1.2 1.77 1.77 0 0 1 1.8 1.1 1.21 1.21 0 0 1-.9 1.4h-1.1l-.8-.3M24.1 18.6h1.8M24.8 17v4.1l.2 .4 .5 .3h.4M27.6 18.6v3.2M29 18.6a1.4 1.4 0 0 0-1.4 .9M30.6 18.8l.4-.2h1l.5 .2 .1 .5v2.5M32.6 19.8l-.4 .1h-1.2a.97 .97 0 0 0-.7 1 .97 .97 0 0 0 .7 .9h1.2l.4-.3M34.3 18.6h1.8M35 17v4.1l.2 .4 .5 .3h.4M44 18.6v3.9l-.3 .5a1.38 1.38 0 0 1-1.8 .2M44 18.8l-.4-.2h-1l-.7 .4-.2 .5v1.4l.4 .6 .5 .3h1l.4-.3M45.8 18.6l1.2 3.2"/>
<path d="M48.1 18.6l-1.6 4.4-.2 .2-.5 .2M53.7 17l-.2 .2 .2 .2 .3-.2-.3-.2v.4M53.7 18.6v3.2M57.6 18.8a1.17 1.17 0 0 0-1.9 .5l.3 .6 .5 .3h.7l.4 .2 .3 .5-.3 .6-.4 .3h-.9l-.6-.3M62.9 18.6h1.9M63.6 17v4.1l.3 .4 .4 .3h.5M66.4 19a1.27 1.27 0 0 1 2.1 .3v2.5M66.4 17v4.8M70.8 18.8l.4-.2h1l.5 .2 .2 .5v2.5M72.9 19.8l-.5 .1h-1.2a.97 .97 0 0 0-.7 1 .97 .97 0 0 0 .7 .9h1.2l.5-.3M74.5 18.6h1.8M75.2 17v4.1l.2 .4 .5 .3h.4"/>
<path d="M81 18.6h1.8M81.7 17v4.1l.2 .4 .4 .3h.5M84.4 19a1.27 1.27 0 0 1 2.2 .3v2.5M84.4 17v4.8M94.6 18.8l-.4-.2h-.8l-.4 .2-.3 .5 .3 .6 .4 .3h.8l.4 .2 .3 .5-.3 .6-.4 .3h-.9l-.6-.3M104.8 18.8l.5-.2h.9l.4 .2 .3 .5v2.5M106.9 19.8l-.5 .1h-1.1l-.5 .3-.3 .4v.5l.3 .4 .5 .3h1.1l.5-.3M109.2 18.6v3.2M110.5 18.6a1.21 1.21 0 0 0-1.3 .9M120 18.8l.5-.2h.9l.5 .2 .2 .5v2.5M122.1 19.8l-.5 .1h-1.1a.97 .97 0 0 0-.7 1 .97 .97 0 0 0 .7 .9h1.1l.5-.3M124.4 17v4.1l.3 .4 .4 .3"/>
<path d="M127 17v4.1l.2 .4 .4 .3M132.5 18.6h1.9M133.2 17v4.1l.3 .4 .4 .3h.5M136 19a1.2 1.2 0 0 1 2 .3v2.5M136 17v4.8M149.8 18.8l-.4-.2h-.7l-.5 .2-.2 .5 .2 .6 .5 .3h.7l.4 .2 .3 .5-.3 .6-.4 .3h-.9l-.5-.3M152.2 18.8l.4-.2h.9l.5 .2 .2 .5v2.5M154.2 19.8l-.4 .1h-1.2a.97 .97 0 0 0-.7 1 .97 .97 0 0 0 .7 .9h1.2l.4-.3M156.6 19a1.2 1.2 0 0 1 2 .3v2.5M156.6 18.6v3.2M158.6 19.3l.3-.5 .4-.2h.8l.4 .2 .2 .5v2.5M172.9 18.8l-.4-.2h-.9l-.7 .4-.3 .5v1.4l.3 .5 .7 .4h.9l.4-.3"/>
<path d="M175 17l-.2 .2 .2 .2 .3-.2-.3-.2v.4M175 18.6v3.2M177.3 18.6v3.2M178.8 18.6a1.4 1.4 0 0 0-1.5 .9M182.4 18.8l-.4-.2h-.9l-.7 .4-.3 .5v1.4l.3 .5 .7 .4h.9l.4-.3M184.5 18.6v2.5l.3 .4a1.4 1.4 0 0 0 1.8-.1M186.6 18.6v3.2M188.9 17l-.2 .2 .2 .2 .3-.2-.3-.2v.4M188.9 18.6v3.2M190.5 18.6h1.9M191.2 17v4.1l.3 .4 .4 .3h.5M194 18.6v3.2"/>
<path d="M195.4 18.6a1.21 1.21 0 0 0-1.4 .9M196.5 18.6l1.2 3.2M198.8 18.6l-1.6 4.4-.7 .4M19.8 26.6l.4-.2h.9l.4 .2 .3 .4v2.6M21.8 27.6l-.4 .2h-1.2l-.4 .2-.3 .5v.4l.3 .5 .4 .2h1.2l.4-.2M26.2 26.6l-.4-.2h-1l-.7 .5-.2 .4v1.4l.2 .5a1.81 1.81 0 0 0 2.1 .2M27.6 26.4h1.8M28.3 24.8v4.1l.2 .5 .9 .2M31 24.8l-.1 .2 .1 .3 .3-.3-.3-.2v.5M31 26.4v3.2M32.9 26.4l1.2 3.2 1.1-3.2M36.9 28l2.3-.4v-.6l-.3-.4-.4-.2h-1l-.5 .2-.1 .4v1.9l.1 .5 .5 .2h1l.4-.2"/>
<path d="M37.5 20.2l2.3-.4v-.5l-.2-.5-.4-.2h-1l-.4 .2-.3 .5v1.8l.3 .4 .4 .3h1l.4-.3M44.9 26.9l.7-.5h.7l.5 .2 .2 .4v2.6M44.9 24.8v4.8M49.3 24.8l-.2 .2 .2 .3 .3-.3-.3-.2v.5M49.3 26.4v3.2M53.7 26.4v3.9a1.39 1.39 0 0 1-2.1 .7M53.7 26.6l-.5-.2h-.9l-.7 .5-.2 .4v1.4l.2 .5a1.7 1.7 0 0 0 2.1 .2M56 26.9l.7-.5h.7l.5 .2 .2 .4v2.6M56 24.8v4.8M63.9 24.5l-4.2 6.3M65.5 24.8v4.1l.2 .5 .5 .2M68.3 26.6a1.26 1.26 0 0 1 2 .7v1.4a1.35 1.35 0 0 1-1.3 .9 1.35 1.35 0 0 1-1.2-.9v-1.4z"/>
<path d="M72 26.4l.9 3.2 .9-2.3 .9 2.3 .9-3.2M81.2 24.8v4.1l.2 .5 .5 .2M83.9 26.6a1.32 1.32 0 0 1 2.2 .7v1.4a1.35 1.35 0 0 1-1.3 .9 1.35 1.35 0 0 1-1.3-.9v-1.4zM88.6 20.2l2.3-.4-.2-1-.5-.2h-.9l-.4 .2-.3 .5v1.8l.3 .4 .4 .3h.9l.5-.3M90.2 26.4v3.9a1.26 1.26 0 0 1-2 .7M90.2 26.6l-.4-.2h-.9l-.6 .2-.4 .7v1.4l.3 .5a1.62 1.62 0 0 0 2 .2M92.5 24.8l-.2 .2 .2 .3 .2-.3-.2-.2v.5M92.5 26.4v3.2M96.7 20.2l2.3-.4v-.5l-.2-.5-.5-.2h-.9l-.5 .2-.2 .5v1.8l.2 .4 .5 .3h.9l.5-.3M96.9 26.6l-.4-.2h-1l-.6 .5-.3 .4v1.4l.3 .5a1.62 1.62 0 0 0 2 .2M102.7 24.8l-.2 .2 .2 .3 .2-.3-.2-.2v.5M102.7 26.4v3.2"/>
<path d="M106.6 26.6l-.4-.2h-.8l-.4 .2-.2 .4 .2 .8 .4 .2h.8l.4 .2 .3 .5-.3 .7-.4 .2h-.9l-.5-.2M112 20.2l2.3-.4v-.5l-.3-.5-.4-.2h-1l-.4 .2-.2 .5v1.8l.2 .4 .4 .3h1l.4-.3M112.6 26.9a1.2 1.2 0 0 1 2.2 .1v2.6M112.6 24.8v4.8M117 26.6l.5-.2h.9l.5 .2 .2 .4v2.6M119.1 27.6l-.4 .2h-1.2l-.5 .2-.2 .5v.4l.2 .5 .5 .2h1.2l.4-.2M121.4 26.9a1.14 1.14 0 0 1 1.1-.6 1.14 1.14 0 0 1 1 .7v2.6M121.4 26.4v3.2M127.9 26.6l-.4-.2h-1l-.5 .2-.4 .7v1.4l.3 .5a1.62 1.62 0 0 0 2 .2M127.9 24.8v4.8M130.2 24.8v4.1l.2 .5 .5 .2M132.5 28l2.3-.4v-.6l-.2-.4-.5-.2h-.9l-.5 .2-.2 .4v1.9l.2 .5 .5 .2h.9l.5-.2"/>
<path d="M139 26.6l-.4-.2h-1l-.5 .2-.4 .7v1.4l.2 .5a1.62 1.62 0 0 0 2.1 .2M139 24.8v4.8M140.2 20.2l2.2-.4v-.5l-.2-.5-.4-.2h-1l-.4 .2-.2 .5v1.8l.2 .4 .4 .3h1l.4-.3M145 26.6l.5-.2h.9l.4 .2 .3 .4v2.6M147.1 27.6l-.5 .2h-1.1l-.5 .2-.3 .5v.4l.3 .5 .5 .2h1.1l.5-.2M148.7 26.4h1.9M149.4 24.8v4.1l.2 .5 1 .2M150.9 33.8h38.2v21h-38.2zM152.2 35.4h.4l.3-.2-.2-.4h-.5v1.2h.6l.1-.5-.3-.1M152.2 37.3h.5v.8M152.7 37.5l-.6 .2 .3 .4 .3-.1M153.3 37.2v.9"/>
<path d="M153.4 35.6l.6-.1-.2-.3-.3 .1-.1 .6 .1 .1h.4M153.7 37.2l-.4 .3M154.3 35.2h.5M154.5 34.8v1.1l.1 .1h.2M154.6 37.3h-.6v.6l.2 .2 .4-.1M155 35.2h.5M155.1 37.3l.4-.1 .2 .2v.7M155.1 36.8v1.3M155.2 34.8v1.2h.3M155.8 35.6l.6-.1-.2-.3-.3 .1-.1 .6 .1 .1h.4M156.2 36.8v.1M156.2 37.2v.9"/>
<path d="M156.7 37.2h.4M156.8 36.8v1.1l.3 .2M156.9 35.2v.8M157.3 35.2l-.4 .2M157.5 26.6l-.5-.2h-.7l-.5 .2-.1 .4 .1 .8 1.2 .2 .5 .2 .2 .5-.2 .7-.5 .2h-.9l-.4-.2M157.5 37.6l.6-.1-.1-.2h-.5v.7h.5M158.4 35.2h.6M158.6 34.8v1.1l.1 .1h.3M159.1 37.3l-.3-.1-.3 .3 .1 .5h.5M159.4 35.3l.3-.1 .3 .2-.2 .6h-.4zM159.5 37.2h.5M159.6 36.8v1.1l.4 .2"/>
<path d="M159.8 26.9a1.28 1.28 0 0 1 1.3-.5 1.28 1.28 0 0 1 1 .9v1.4a1.35 1.35 0 0 1-1.3 .9 1.35 1.35 0 0 1-1.3-.9v-1.4zM160.4 37.2v.8l.3 .1 .2-.2M160.9 37.2v.9M161.4 35.3l.2-.1 .3 .1v.7M161.4 35.2v.8M161.5 37.2v.9M161.8 37.2l-.3 .1v.2M161.9 35.4l.2-.2 .3 .1 .1 .7M162.2 37.6l.6-.1-.2-.3-.4 .2v.5l.1 .2 .4-.1M162.8 20.2l2.3-.4v-.5l-.2-.5-.5-.2h-.9l-.5 .2-.2 .5v1.8l.2 .4 .5 .3h.9l.5-.3M163.1 35.3l.3-.1 .2 .1-.1 .7-.5-.1zM163.5 26.4h1.8"/>
<path d="M164 35.2l.4 .8 .2-.8M164.2 36.9l.3-.1 .3 .2-.4 .5M164.4 37.9v.2M165.1 35.6l.5-.1-.1-.3-.4 .1v.6v.1h.5M165.3 24.8h-.4l-.5 .2-.2 .4v4.2M166.2 26.4h1.9M166.9 24.8v4.1l.3 .5 .9 .2M166.9 35.2h.5M167.1 34.8v1.1l.1 .1h.2M167.8 35.3l.4-.1 .2 .2-.1 .6h-.5zM169.3 26.4l.9 3.2 .9-2.3 1 2.3 .8-3.2M169.9 35.3l.3-.1 .2 .2v.6h-.5v-.4l.5-.1"/>
<path d="M171.9 35.4h.6l.1-.5-.7-.1v1.2M173.2 35.2v.8l.5-.1M173.7 35.2v.8M174.7 35.3l-.3-.1-.2 .2 .1 .2 .4 .1v.3h-.5M174.8 26.6l.5-.2h.9l.5 .2 .2 .4v2.6M175.3 35.3l.2-.1 .2 .1 .1 .7M175.3 34.8v1.2M176.4 35.6h.9M176.9 27.6l-.5 .2h-1.1l-.5 .2-.2 .5 .2 .9 .5 .2h1.1l.5-.2M177.9 35.3l.4-.1 .2 .2-.1 .5-.5 .1M177.9 35.2v1.2M179 35.2l.1 .8 .4-.1"/>
<path d="M179.2 26.4v3.2M179.5 35.2v.8M180.1 34.8v1.1l.2 .1M180.6 26.4a1.4 1.4 0 0 0-1.4 .9M180.8 34.8v1.1l.2 .1M182 28l2.3-.4v-.6l-.3-.4-.4-.2h-.9l-.5 .2-.2 .4v1.9l.2 .5 .5 .2h.9l.4-.2M190 24.8v4.1l.3 .5 .5 .2M192.4 28l2.3-.4v-.6l-.3-.4-.4-.2h-.9l-.5 .2-.2 .4v1.9l.2 .5 .5 .2h.9l.4-.2M196.3 26.4l1.2 3.2 1.1-3.2M200.3 28l2.3-.4v-.6l-.3-.4-.4-.2h-.9l-.6 .2-.1 .4v1.9l.1 .5 .6 .2h.9l.4-.2M201 21.5l-.3 .8-.3 .2M204.6 24.8v4.1l.2 .5 .6 .2"/>
</g>
<g fill="#00a200">
<circle cx="143.5" cy="64.6" r=".47"/>
<circle cx="133.6" cy="64.6" r=".47"/>
<circle cx="121.3" cy="64.6" r=".47"/>
<circle cx="133.6" cy="54.8" r=".47"/>
<circle cx="121.3" cy="54.8" r=".47"/>
<circle cx="97.9" cy="70.8" r=".47"/>
</g>
<g fill="none" stroke="#970091" stroke-width=".21">
<path d="M100.7 61.6l.4-.2 .3 .4-.8 .9h.8M100.7 66.5l.6-.1 .1 .4-.8 .8h.8M101.3 64h-.6v.5l.4-.1 .3 .2-.1 .5h-.6M101.7 61.4l.4 1.3 .5-1.3M101.7 66.4l.4 1.2 .5-1.2M101.9 64.5l.2-.2 .3 .1v.7M101.9 64.3v.8M102.4 64.5l.3-.2 .3 .2v.6M103.4 65.1l.4-1.1 .4 1.1M103.5 64.8h.6M100.7 85l.4-.1 .3 .3-.8 .9h.8M100.7 90l.4-.2 .3 .3-.8 1h.8"/>
<path d="M101.3 87.3h-.6v.6l.6-.1 .1 .2-.1 .5-.4 .1-.2-.2M101.7 84.9l.4 1.2 .5-1.2M101.7 89.8l.4 1.3 .5-1.3M101.9 87.8h.5v.8M101.9 87.8v.8M102.4 87.9l.3-.1 .3 .1v.7M103.4 88.6l.4-1.3 .4 1.3M103.5 88.3h.6"/>
</g>
<g fill="none" stroke="#007170" stroke-width=".21">
<path d="M100.7 54.2l.6-.1 .1 .4-.8 .8h.8M100.7 59.1l.3-.1 .5 .1v1l-.3 .1-.5-.1zM100.7 52.3h.6l.2-.4-.2-.2h-.6v1.2M100.7 56.5a.65 .65 0 0 1 .8 .6 .65 .65 0 0 1-.8 .7zM101 52.3l.5 .6M101.8 54.1h.9l-.6 1.2M101.9 52l.3-.3v1.2M101.9 52.9h.8M102.1 59.4v.7l.3 .1 .2-.1M102.6 56.5h-.6l-.1 .6 .6-.1 .2 .2v.3l-.3 .3h-.3l-.2-.2M102.6 59.4v.8M103 59.4h.4"/>
<path d="M103.2 54.2h.4a.94 .94 0 0 1 0 1.1h-.4a.78 .78 0 0 1 0-1.1zM103.2 59v1.1l.2 .1M103.3 52.2l-.2-.3 .1-.2h.5l.1 .3-.7 .4 .2 .5 .5-.1v-.5l-.2-.1M103.8 57v.2l-.5 .1-.2-.3v-.2l.2-.3 .5 .2v.7l-.2 .3-.4 .1M104.2 51.7h.7l-.4 .4 .4 .2v.5h-.7M104.8 59v1.2M104.8 59.6h.7M105.5 59v1.2M106 59v.1M106 59.4v.8M124.1 59.4l.4-.4v1.3M124.2 57.2h.6v-.5l-.6-.1v1.2"/>
<path d="M124.5 57.2l.3 .6M125.3 56.9l.4-.3v1.2M125.3 59v1.3M125.3 57.8h.7M125.4 59.8l.4 .5M125.8 59.5l-.5 .4M126.8 57.1l-.3-.1 .1-.3a.36 .36 0 0 1 .6 .1l-.1 .2-.6 .2 .1 .6h.5l.1-.2v-.2l-.2-.3M128.3 56.6l-.6 .2v.9l.6 .1v-.7l-.4-.1-.2 .3M136.4 59.4l.4-.4v1.3M136.5 57.2h.6v-.5l-.6-.1v1.2M136.8 57.2l.4 .6M137.7 56.9l.3-.3v1.2"/>
<path d="M137.7 59v1.3M137.7 57.8h.7M137.8 59.8l.3 .5M138.1 59.5l-.4 .4M139.1 57.1l-.3-.3 .3-.2 .4 .1v.3a.48 .48 0 0 0-.5 .2 .48 .48 0 0 0 0 .6h.4l.2-.2-.1-.4-.2-.1M140 56.6h.8l-.6 1.2M100.7 77.7l.4-.2 .3 .4-.8 .9h.8M100.7 75.7l.7-.1 .1-.3-.3-.2h-.5v1.2M100.7 80h.5l.2 .2 .1 .4-.3 .5h-.5zM101 75.7l.5 .6M101.8 77.5h.9l-.6 1.3M101.9 75.4h.2l.1-.3v1.2"/>
<path d="M101.9 76.3h.8M102.5 80h-.4a.94 .94 0 0 0 0 1.1h.4l.2-.1v-.4l-.3-.2h-.3l-.2 .2M103.2 80h.4l.2 .2v.8l-.2 .1h-.4a.87 .87 0 0 1 0-1.1zM103.3 77.5a.68 .68 0 0 1 .5 .6 .68 .68 0 0 1-.5 .7l-.2-.3a.77 .77 0 0 1 .2-1zM103.3 75.6l-.2-.3 .2-.2h.3l.2 .4-.7 .3v.3l.2 .2 .5-.1v-.5l-.2-.1M104.5 75.1l-.2 .8h.7M104.9 75.5v.8M106.9 64.6h.5l.2-.1v-.4l-.2-.1h-.5v1.2M107.1 64.6l.5 .6M108.1 64.3l.3-.3v1.2M108.1 65.2h.6M108.2 66.8l.3-.4v1.3"/>
<path d="M108.2 67.7h.6M109.3 66.4v1.3M109.4 64.5l-.1-.1 .1-.4h.4v.5h-.4l-.1 .1v.5l.1 .1h.3l.2-.2-.1-.4-.1-.1M109.4 67.2l.4 .5M109.8 66.8l-.5 .5M111 64h-.6v.6l.6-.1 .1 .5-.2 .2-.5-.1M124.1 60.3h.7M125.3 69l.2-.1 .4 .1 .1 .5-.7 .6h.7M125.4 66.6l.2-.2a.46 .46 0 0 1 .6 .4v.5a.46 .46 0 0 1-.6 .4 .9 .9 0 0 1-.2-1.1zM125.6 67.3l.6 .5M126.5 66.4h.8l-.3 .5 .3 .1v.6h-.8M127.3 68.9v1.2l-.8-1.2v1.2"/>
<path d="M127.7 68.9h.9l-.5 1.2M127.8 66.8l.3-.4v1.3M127.8 67.7h.7M129.2 68.9l.5 .2v.8l-.5 .2a.9 .9 0 0 1 0-1.2zM130.4 68.9a.75 .75 0 0 1 .2 1.2l-.4-.2v-.8zM131.4 69l.4-.1 .2 .4-.7 .8h.7M136.4 60.3h.7M96.9 97.3l-.1-.1a.64 .64 0 0 0-.6 .6 .64 .64 0 0 0 .5 .7l.3-.1v-.4h-.3M98.3 97.2v1.3l-.8-1.3v1.3M98.8 97.2a.64 .64 0 0 1 .7 .7 .64 .64 0 0 1-.7 .6zM100.7 82.6l.3-.2 .5 .2v.8l-.2 .2h-.4l-.2-.2zM102.1 82.8v.8l.5-.1"/>
<path d="M102.6 82.8v.8M103 82.8h.4M103.2 82.4v1l.2 .2M104.8 82.4v1.2h.6M105.8 82.9l.5-.1v.8h-.4l-.2-.2zM120.3 97.3l-.2-.1-.4 .4 .1 .7 .3 .2 .3-.1v-.4h-.2M121.6 97.2v1.3l-.7-1.3v1.3M122.2 97.2a.65 .65 0 0 1 .8 .7 .65 .65 0 0 1-.8 .6zM191.9 92.4l-.2-.1a.64 .64 0 0 0-.6 .7 .64 .64 0 0 0 .6 .6l.2-.1v-.5h-.2M193.2 92.3v1.3l-.7-1.3v1.3M193.8 92.3a.64 .64 0 0 1 .6 .7 .64 .64 0 0 1-.6 .6z"/>
</g>
<g fill="none" stroke="#a2a2a2" stroke-width=".21">
<path d="M146.3 59.4l.4-.4v1.3M146.3 57.2h.6l.1-.5-.7-.1v1.2M146.7 57.2l.3 .6M147.5 56.9l.4-.3v1.2M147.5 59v1.3M147.5 57.8h.7M147.6 59.8l.4 .5M148 59.5l-.5 .4M149 57.1l-.3-.3a.42 .42 0 0 1 .7-.1v.3l-.6 .2v.6l.6-.1v-.5l-.3-.1M150.2 57.1l-.3-.1 .1-.3a.36 .36 0 0 1 .6 .1l-.1 .2-.6 .2 .1 .6h.5l.1-.4-.3-.3M159.7 57.8v.9l-.2 .3h-.3M160.3 58.5l.7-.1v-.5l-.7-.1v1.2"/>
<path d="M161.8 58.4l-.3-.2 .1-.3a.34 .34 0 0 1 .4 0 .34 .34 0 0 1 .1 .4l-.6 .2 .1 .5a.36 .36 0 0 0 .6-.2l-.1-.4h-.2M146.3 60.3h.7M156.2 60.8h.6v-.5h-.6v1.2h.6l.2-.4-.3-.3M157.4 60.7l.3 .8M158 60.7l-.4 1.1-.2 .1M158.4 60.7h.4l.2 .2v.5h-.6M158.4 60.7v1.2M159.5 60.7h.4l.2 .1v.7M160.1 61l-.6 .1v.3h.6M161.1 60.7h-.5v.4h.4l.2 .2-.2 .2-.4-.1M162.1 60.7h-.4v.4h.3l.2 .2-.2 .2-.3-.1M164 60.3v1l-.5 .2"/>
<path d="M164.5 60.9l.7-.1 .1-.3-.2-.2h-.6v1.2M203.1 86.1v-1.1l.4 .8 .4-.8v1.1M203.4 82.5v.8l-.2 .4h-.2M203.9 82.8l.4-.3v1.2M203.9 83.7h.8M204.5 85.4h.4l.1 .1v.6h-.5v-.4l.5-.1M205.6 85.5l.4-.1 .1 .7M205.6 85.4v.7M205.8 82.5h-.6l-.1 .6 .2-.2h.3l.3 .3-.1 .4h-.7M206.7 85.4l.1 .7h.4M207.2 85.4v.7M207.8 85.4h.5v.7h-.5v-.4l.5-.1"/>
<path d="M208.9 85v1l.2 .1M210.5 85v1.1h.5v-.7h-.5M211.6 85.4h.5v.7h-.5v-.4l.5-.1M213.3 85.4l-.6 .1v.6h.6M213.8 85v1.1M213.9 85.7l.3 .4M214.2 85.4l-.4 .4M214.8 85.4v.7h.5M215.3 85.4v.7M215.9 86.1h.5l.1-.1v-.5l-.1-.1h-.5v1.2"/>
</g>
<path d="M142 55l3.1 7M145.1 55l-3.1 7M196.5 79.9l7.5 9.1M204 79.9l-7.5 9.1" fill="none" stroke="#e00" stroke-width=".42"/>
<path d="M157.8 63.2l5.9 3M163.7 63.2l-5.9 3" fill="none" stroke="#c9c9c9" stroke-width=".42"/>
</svg>
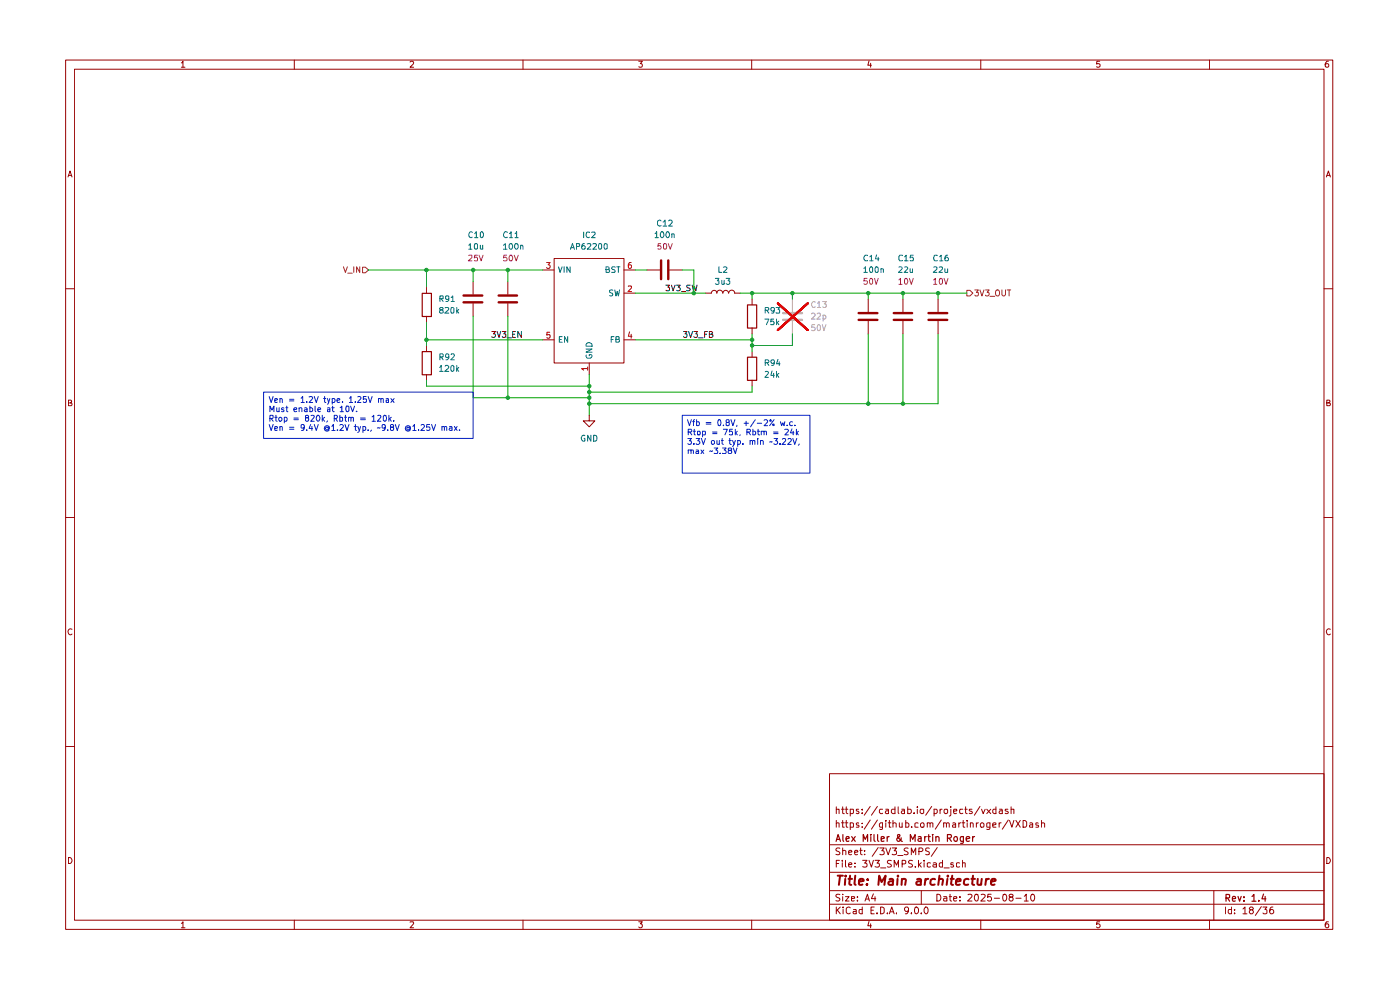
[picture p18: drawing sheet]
<svg xmlns="http://www.w3.org/2000/svg" width="297mm" height="210mm" viewBox="0 0 297 210" stroke-linecap="round" stroke-linejoin="round" font-family="sans-serif">
<g fill="none" stroke="#980000" stroke-width=".21">
<path d="M13.9 12.7h268.8v184.4h-268.8zM15.8 14.7h265.1v180.5h-265.1zM38.5 13.3h.1l.2-.3v1.3M38.5 14.3h.7M62.4 12.7v2M87 13.2l.5-.2 .3 .2-.1 .4-.7 .7h.8M111 12.7v2M135.5 13h.8l-.5 .5 .4 .1v.6h-.7M159.5 12.7v2M184.4 12.9l-.3 .9h.8M184.7 13.4v.9M208.1 12.7v2"/>
<path d="M233.3 13h-.6l-.1 .6h.7v.6h-.7M256.6 12.7v2M281.8 13a.71 .71 0 0 0-.7 .5 .71 .71 0 0 0 .3 .8l.4-.1v-.6l-.4-.1-.3 .3M14.4 37.5l.5-1.2 .4 1.2M14.5 37.2h.7M281.4 37.5l.4-1.2 .4 1.2M281.5 37.2h.6M100.4 59.7v2.7M107.7 59.7v2.7M115.1 57.3h2.5M117.6 54.8h14.8v22.2h-14.8zM132.4 57.3h2.4"/>
<path d="M13.9 61.3h1.9M90.5 60.9v1.3M90.5 67.1v1.3M90.5 73.3v1.2M90.5 79.5v1.1M100.4 64.4v2.7M107.7 64.4v2.7M115.1 72.1h2.5M125 77v2.5M132.4 72.1h2.4M132.4 62.2h2.4M280.9 61.3h1.8"/>
<path d="M14.5 85.5h.4l.3-.3-.2-.3h-.5v1.2h.6l.2-.5-.4-.1M125 88.1v1.2h1.2l-1.2 1.2-1.3-1.2h1.3M125 88.1h.1M281.5 85.5h.4l.2-.3-.1-.3h-.5v1.2h.6l.1-.5-.3-.1M13.9 109.8h1.9M280.9 109.8h1.8M15.3 133.5a.59 .59 0 0 0-.9 .5 .59 .59 0 0 0 .8 .6l.1-.1M282.2 133.5a.59 .59 0 0 0-.8 .5 .59 .59 0 0 0 .7 .6l.1-.1M13.9 158.4h1.9M280.9 158.4h1.8M176 164.1h104.9v31.1h-104.9zM176 179.2h104.9"/>
<path d="M177.4 174.7l.2-.2 .4 .1v.9M177.4 171.7h.6v.9M177.4 171.1v1.5M177.4 174v1.5M178.2 180l-.6-.1-.3 .2 .1 .4 .8 .4-.1 .3h-.8M178.5 174.5h.6M178.5 171.7h.6M178.8 174v1.5h.3M178.8 171.1v1.4l.3 .1M178.8 179.9v1.4M179.4 174.5h.5M179.4 171.7h.5"/>
<path d="M179.5 174v1.3l.1 .2h.3M179.5 171.1v1.3l.4 .2M180.4 174.6l.4-.1 .3 .2v.7l-.7 .1M180.4 172.5l.4 .1 .3-.2-.1-.7h-.6v1.4M180.4 174.5v1.5M182.2 174.6l-.4-.1-.2 .2 .2 .3h.4v.5h-.6M182.2 171.7h-.5l-.1 .2 .5 .2 .1 .3-.1 .2-.5-.1M182.6 179.9v1.2l.3 .2M182.9 175.4v.1M182.9 174.6v.1M182.9 172.4v.2M182.9 171.7v.1"/>
<path d="M184.6 173.9l-1.3 2M184.6 171.1l-1.3 1.8M186.1 173.9l-1.2 2M186.1 171.1l-1.2 1.8M186.3 179.8l-1.3 1.8M186.6 179.9h1l-.5 .6h.4v.7h-.9M187.2 174.5v1.2a.36 .36 0 0 1-.6 .2M187.2 174.6l-.4-.1-.2 .3v.6l.6 .1M187.2 171.7h-.5l-.1 .2v.4l.2 .3 .4-.1M187.9 179.9l.5 1.4 .5-1.4M187.9 174v.2M187.9 171.7h.5l.1 .9"/>
<path d="M187.9 174.5v1M188.4 174.5h.6M188.5 172h-.5l-.2 .2 .2 .4 .5-.1M188.7 174v1.5h.3M189.3 179.9h.9l-.5 .6h.4v.7h-.8M189.4 174.7l.3-.2 .4 .2v.8M189.4 174v1.5M189.9 171.7h-.6l-.2 .6a.52 .52 0 0 0 .8 .2M189.9 171.1v1.5M190.5 171.1v1.3l.2 .2M190.8 174.5l.1 1 .5-.1M191.3 171.7h.5l.1 .9"/>
<path d="M191.4 174.5v1M191.9 172h-.5l-.2 .2 .2 .4 .5-.1M192.1 174v1.5l.6-.1 .1-.6a.45 .45 0 0 0-.7-.2M192.6 171.7h.6l.1 .6a.52 .52 0 0 1-.7 .2M192.6 171.1v1.5M192.7 180a.6 .6 0 0 0-.9 .1l.1 .4 .8 .4-.3 .4-.6-.1M193.4 175.4v.1M193.9 172.4v.2M194.6 171.1v.1M194.6 171.7v.9M194.8 174.6l-.5-.1-.2 .2v.7l.7 .1M195.3 174.8a.45 .45 0 0 1 .7-.2v.9l-.6-.1z"/>
<path d="M195.3 171.7h.7l-.1 .8a.45 .45 0 0 1-.7-.2zM196.7 174.7l.2-.2 .4 .2v.8M196.7 174.5v1M197.1 180l-.5-.1-.2 .1v.5l.7 .2v.5h-.7M197.3 174.7l.2-.2 .4 .1v.9M197.6 171.1l-1.2 1.8M198.2 172.5l.4 .1 .2-.3-.1-.6h-.5v1.4M198.8 179.8l-1.2 1.8M199.4 171.7v.9M199.7 173.9l-1.3 2M199.9 171.7h-.3l-.2 .2M200.2 174.7l.2-.2 .4 .2v.8"/>
<path d="M200.2 174.5v1M200.4 171.7h.6v.8l-.5 .1-.2-.3zM200.8 174.7l.2-.2 .4 .2v.8M201.7 171.7v1.1l-.3 .3M201.7 171.1v.1M202.1 174.6l.4-.1 .2 .2v.8h-.6v-.4l.6-.2M202.3 172.1l.7-.1-.1-.3h-.5l-.1 .1v.6l.2 .2 .4-.1M203.4 174.5v1M203.8 174.5l-.4 .3M204.1 174.5h.6M204.3 171.7h-.6l-.1 .2 .1 .6h.6M204.3 174v1.3l.1 .2h.3"/>
<path d="M204.7 171.7h.5M204.8 171.1v1.3l.4 .2M205.2 174v.2M205.2 174.5v1M205.9 174.7l.1-.2 .5 .2v.8M205.9 174.5v1M206.2 171.7h-.5l-.1 .2 .6 .3 .1 .2-.3 .2-.4-.1M207.1 174.5v1M207.6 174.5l-.5 .3M207.9 171.1l-1.2 1.8M208.2 174.5h.3l.2 .3-.1 .7h-.5l-.1-.3v-.4zM208.2 171.7l.4 .9 .4-.9"/>
<path d="M209.3 171.7l.9 .9M210 174.5v1.2l-.2 .3-.5-.1M210 174.6l-.4-.1-.3 .2v.7l.7 .1M210.2 171.7l-.9 .9M210.6 175l.7-.1v-.3l-.4-.1-.3 .2 .1 .8h.6M211.3 171.7h-.5l-.2 .6a.45 .45 0 0 0 .7 .2M211.3 171.1v1.5M212 174.5v1M212 171.7h.6v.9M212.4 174.5l-.4 .3M212.6 172h-.5l-.1 .2 .1 .4 .5-.1M213.8 171.7h-.5l-.1 .2 .6 .3 .1 .2-.2 .2-.5-.1"/>
<path d="M213.9 173.9l-1.3 2M214.2 174l.5 1.5 .4-1.5M214.5 171.7h.6v.9M214.5 171.1v1.5M215.5 174l.9 1.5M216.4 174l-.9 1.5M217 174h.4l.4 .4v.7l-.3 .4h-.5zM218.5 174.6l.4-.1 .2 .2v.8h-.6l-.1-.4 .7-.2M220.3 174.6h-.6v.4h.6v.2v.3h-.6M220.9 174.7l.3-.2 .4 .2v.8M220.9 174v1.5M14.5 181.9a.65 .65 0 0 1 .8 .6 .65 .65 0 0 1-.8 .7z"/>
<path d="M38.5 195.9l.3-.4v1.3M38.5 196.8h.7M62.4 195.2v1.9M87 195.6l.7-.1 .1 .3-.8 1h.8M111 195.2v1.9M135.5 195.5h.8l-.5 .5 .5 .2-.1 .5-.5 .1-.2-.2M159.5 195.2v1.9M176 191.8h104.9M176 188.9h104.9M176 185h104.9M177.4 192.4v1.4M177.4 183.2h.5"/>
<path d="M177.6 193l.7 .8M178.1 182.5h-.7v1.4M178.2 189.8h-.8l-.1 .3 .8 .4 .1 .4-.3 .2-.6-.1M178.3 192.4l-.9 .8M178.7 182.5v.2M178.7 183v.9M178.8 189.7v.1M178.8 180.5l.4-.1 .2 .1v.8M178.8 190.2v.9M178.9 192.4v.2M178.9 192.9v.9M179.4 190.2h.7l-.7 .9h.7"/>
<path d="M179.4 182.5v1.3l.1 .1M180 183.4l.7-.1-.2-.3-.5 .2v.6l.3 .1 .3-.1M180 180.8l.7-.1-.2-.3-.5 .1v.6l.3 .2 .3-.1M180.4 192.6l-.4-.2-.5 .3 .1 1 .4 .1 .4-.1M180.6 190.6l.7-.1-.1-.3h-.6v.8h.6M181.1 192.9h.5v.9M181.3 180.8l.7-.1-.2-.3h-.3l-.2 .1v.6l.2 .2 .4-.1M181.4 183.8v.1M181.4 183.1v.1M181.6 193.2l-.5 .1-.1 .2 .1 .3h.5M181.9 191v.1M181.9 190.2v.2"/>
<path d="M182.4 180.4h.5M182.9 192.9h-.5l-.2 .7a.45 .45 0 0 0 .7 .2M182.9 192.4v1.4M183 182.5h.9l-.5 .6 .4 .1v.6h-.8M183.4 181.2v.1M183.4 180.5h.1M183.5 191.1l.5-1.4 .4 1.4M183.7 190.7h.7M184.4 195.4l-.3 1h.8M184.4 182.5l.5 1.4 .4-1.4M184.7 196v.8M184.8 193.1h.5"/>
<path d="M185.3 189.6l-.4 1h.9M185.5 192.4h-.7v1.4h.7M185.6 182.5h1l-.6 .6 .5 .1v.6h-.9M185.6 190.2v.9M186 193.7v.1M186.8 192.4h.4l.4 .3v.8l-.4 .3h-.4zM186.8 184.1h1.1M188.3 193.7v.1M188.7 193.8l.5-1.4 .5 1.4M188.8 193.4h.7M189.1 182.6h-.8v.5l.6 .2 .2 .4-.3 .2-.5-.1M189.7 183.9v-1.4l.5 1 .4-1v1.4"/>
<path d="M190.2 193.7v.1M190.5 181.5h1.1M191.4 183.3l.7-.1v-.5l-.2-.2h-.5v1.4M192.7 193l-.2 .3h-.4l-.2-.3v-.3l.2-.3h.4l.2 .3v.8l-.2 .3h-.4M193.3 193.7v.1M193.3 181.3v-1.4l.5 1 .5-1v1.4M193.6 182.6l-.6-.1-.3 .2 .1 .4 .8 .4-.1 .3h-.8M194.1 192.6l.2-.2a.75 .75 0 0 1 .6 .7 .75 .75 0 0 1-.6 .7l-.2-.1-.1-.4zM194.2 183.8v.1M194.9 182.5v1.4M194.9 180.6h.6l.3-.2v-.3l-.3-.2h-.6v1.4M195 183.4l.4 .5"/>
<path d="M195.4 193.7v.1M195.4 183l-.5 .5M195.4 188.9v2.9M196 182.5v.2M196 183v.9M196.4 192.4h.1a.8 .8 0 0 1 .4 .8 .8 .8 0 0 1-.5 .6 .89 .89 0 0 1 0-1.4zM197.4 183.1h-.7v.7h.7M198 183.1l.4-.1 .3 .2v.7M198.7 183.3l-.7 .1-.1 .2 .3 .3 .5-.1M198.7 189.7a.73 .73 0 0 1 .9 .7 .73 .73 0 0 1-.9 .7zM199.9 183.1l-.4-.1-.2 .3v.5h.6M199.9 182.5v1.4"/>
<path d="M200.2 190.2h.6l.1 .9M200.3 184.1h1.1M200.9 190.5l-.7 .1v.4h.7M201.4 190.2h.5M201.5 189.7v1.3l.4 .1M202.2 183.1h-.5v.3h.4l.2 .4-.2 .1-.4-.1M202.3 190.6l.7-.1-.1-.3h-.5l-.1 .2v.6l.2 .1 .4-.1M203.6 183.1h-.7v.7h.7M203.7 191v.1M203.7 190.2v.2M204.2 183.1h.6v.8M204.2 182.5v1.4"/>
<path d="M205.4 189.8l.5-.1 .3 .4-.9 1h.9M206.9 189.8h.5a1.01 1.01 0 0 1-.2 1.3 .87 .87 0 0 1-.3-1.3zM208.1 195.2v1.9M208.1 189.8h.8l.1 .3-.9 1h.9M210.3 189.7h-.7l-.1 .7 .6-.2 .2 .3v.4l-.2 .2-.6-.1M210.9 190.5h1.1M212.8 189.8l.3-.1a.73 .73 0 0 1 .5 .7 .73 .73 0 0 1-.5 .7l-.3-.1-.1-.5zM214.3 190.3l-.2-.3 .1-.2h.6v.4l-.5 .1-.2 .2v.4l.2 .2h.4l.2-.2v-.4l-.2-.2M215.5 190.5h1.1M217.3 190.1l.4-.4v1.4M217.3 191.1h.8M218.8 189.8l.2-.1a.76 .76 0 0 1 .5 .7 .76 .76 0 0 1-.5 .7 1.01 1.01 0 0 1-.2-1.3z"/>
<path d="M233.3 195.5h-.6l-.1 .6 .2-.1h.3l.3 .2v.3l-.3 .3h-.3l-.2-.2M256.6 195.2v1.9M257.5 188.9v6.3M260 192.4v1.4M261.2 192.9h-.5l-.1 .3v.4l.2 .2h.4M261.2 192.4v1.4M261.9 193.7v.1M261.9 192.9v.2M263.7 192.8l.4-.4v1.4M263.7 193.8h.8M265.3 193l-.3-.3 .3-.3h.3l.3 .3-.1 .2-.7 .3-.1 .4 .3 .2h.3l.3-.2-.3-.6M267.6 192.3l-1.3 1.9"/>
<path d="M267.9 192.4h.9l-.5 .5 .5 .2v.6l-.3 .1h-.4l-.2-.1M270 192.4l-.5 .2a1.02 1.02 0 0 0 .1 1.2h.4l.2-.2v-.4l-.3-.3h-.3l-.2 .3M281.5 181.9a.65 .65 0 0 1 .7 .6 .65 .65 0 0 1-.7 .7zM281.8 195.5h-.4l-.3 .5v.5l.3 .3 .4-.1v-.7h-.4l-.3 .2"/>
</g>
<g fill="none" stroke="#980000" stroke-width=".25">
<path d="M89.6 74.6h1.9v4.9h-1.9zM89.6 62.2h1.9v4.9h-1.9zM177.4 178.5l.4-1.5 .5 1.5M177.5 178h.6M178.8 177v1.2l.2 .3M179.5 178l.7-.2-.2-.3h-.4l-.1 .7 .2 .3 .4-.1M180.7 177.5l.7 1M181.4 177.5l-.7 1M183.1 178.5v-1.5l.5 1 .5-1v1.5M184.7 177v.1M184.7 177.5v1M185.4 177v1.2l.3 .3"/>
<path d="M186.2 177v1.2l.2 .3M186.9 178l.7-.2-.1-.3h-.6v.9h.6M188.2 177.5v1M188.6 177.5l-.4 .3M191.2 177.7v.3l-.5 .5a.43 .43 0 0 1-.4-.2 .43 .43 0 0 1 0-.5l.6-.5-.1-.3h-.3a.55 .55 0 0 0 .2 .8l.7 .7M193.1 178.5v-1.5l.5 1 .5-1v1.5M194.8 177.5h.6v1M195.4 177.8l-.4 .1-.3 .2 .3 .4 .4-.1M196.2 177.5v1M196.5 177.5h-.2l-.1 .3M196.8 177.5h.6M197 177v1.2l.4 .3"/>
<path d="M197.9 177v.1M197.9 177.5v1M198.5 177.6l.1-.1a.36 .36 0 0 1 .6 .2v.8M198.5 177.5v1M201 177.8l.7-.1 .1-.2v-.4l-.8-.1v1.5M201.3 177.8l.5 .7M204.4 177.5v1.1l-.2 .3h-.4M204.4 177.5h-.4l-.3 .3 .1 .6h.6M205 178l.7-.2-.1-.3h-.4l-.2 .2 .1 .7h.5M206.3 177.5v1M206.8 177.5l-.5 .3M260.1 190.5l.7-.1 .1-.6-.8-.1v1.5"/>
<path d="M260.4 190.5l.5 .7M261.4 190.7l.7-.1-.1-.4h-.5l-.1 .7 .2 .3 .4-.1M262.6 190.2l.4 1 .3-1M263.9 191v.2M263.9 190.2v.2M265.6 190.2l.4-.5v1.5M265.6 191.2h.8M267 191v.2M268 189.6l-.3 1.1h.9M268.4 190.2v1"/>
<circle cx="202.7" cy="178" r=".48"/>
</g>
<g fill="none" stroke="#980000" stroke-width=".42">
<path d="M177.7 185.8h1.1M178.2 185.8l-.2 1.9M179.3 186.4l-.1 1.3M179.4 185.8v.1M180 186.4h.8M180.3 185.8l-.1 1.6 .4 .3M181.4 185.8l-.1 1.6 .2 .3M182.2 187l1-.1-.1-.4a.6 .6 0 0 0-.8 .2v.9h.7M184 187.5l-.1 .2-.1-.1 .2-.1-.1 .2M184.1 186.5v.2M186.3 187.7l.2-1.9 .5 1.3 .9-1.3-.3 1.9M188.7 186.5h.7v1.2"/>
<path d="M189.5 186.9h-.7l-.3 .3v.2l.2 .3 .7-.1M190.4 186.4l-.1 1.3M190.5 185.8v.1M191.3 186.6l.1-.1a.48 .48 0 0 1 .8 .2l-.2 1M191.3 186.4v1.3M194.6 186.5h.7v1.2M195.4 186.9h-.7l-.3 .3v.2l.2 .3 .7-.1M196.3 186.4l-.1 1.3M196.9 186.4l-.4 .1-.2 .3M198.4 186.5a.65 .65 0 0 0-1 .3v.7a.64 .64 0 0 0 .9 .1M199.2 186.6l.1-.1a.48 .48 0 0 1 .8 .2l-.2 1M199.3 185.8l-.3 1.9"/>
<path d="M201 186.4l-.2 1.3M201.1 185.8v.1M201.7 186.4h.6M202 185.8l-.2 1.6 .4 .3M202.9 187l.9-.1v-.4l-.6-.1-.3 .3v.9h.7M205.5 186.5a.65 .65 0 0 0-1 .3v.7a.64 .64 0 0 0 .9 .1M206.1 186.4h.7M206.4 185.8l-.2 1.6 .5 .3M207.4 186.4v1.2l.5 .1 .3-.2M208.3 186.4l-.2 1.3M209.2 186.4l-.2 1.3M209.8 186.4l-.4 .1-.2 .3"/>
<path d="M210.2 187l1-.1v-.4a.6 .6 0 0 0-.9 .2v.9h.7"/>
</g>
<path d="M165 64.3l6.4 5.7M171.4 64.3l-6.4 5.7" fill="none" stroke="#e00" stroke-width=".42"/>
<path d="M115.9 55.7h.8l-.4 .5 .4 .2-.1 .4-.5 .1-.2-.1M133.9 55.7h-.4l-.2 .3v.8l.2 .1 .4-.1v-.5l-.4-.1-.2 .2M116.6 70.5h-.6v.6l.6-.1 .1 .2-.1 .5h-.4l-.2-.1M124.7 78.2h-1.3l.4 .3M124.7 77.8v.7M133.3 60.7h.6l.1 .3-.8 .8h.8M133.6 70.4l-.3 .9h.8M133.9 70.9v.8" fill="none" stroke="#bd0000" stroke-width=".21"/>
<g fill="none" stroke="#007170" stroke-width=".21">
<path d="M118.5 56.6l.3 1.2 .4-1.2M119.7 56.6v1.2M120.9 56.6v1.2l-.6-1.2v1.2M128.6 57.2l.6-.1v-.4l-.6-.1v1.2h.6l.1-.4-.3-.2M130.5 56.7h-.7l-.1 .2 .3 .3h.3l.2 .4-.2 .2h-.6M130.8 56.6h.7M131.2 56.6v1.2M118.7 72h.4M119.2 71.4h-.5v1.2h.5M120.4 71.4v1.2l-.6-1.2v1.2M124.3 74h1.3l-1.3 .7h1.3M124.4 75.3l-.1 .3 .3 .4h.7l.3-.4-.2-.4h-.4v.3"/>
<path d="M124.4 72.9a.67 .67 0 0 1 .8-.2 .67 .67 0 0 1 .4 .7h-1.3zM129.7 72h.4M130 61.6h-.7v.4l.6 .2 .1 .2-.3 .4-.4-.1M130.3 71.4h-.6v1.2M130.4 61.5l.3 1.3 .2-1 .3 1 .2-1.3M130.7 72l.6-.1v-.5h-.6v1.2l.7-.1v-.3l-.3-.2"/>
</g>
<path d="M98.3 64.1h4M98.3 62.7h4M105.8 64.1h3.9M105.8 62.7h3.9" fill="none" stroke="#980000" stroke-width=".51"/>
<path d="M104.3 70.3h.8l-.4 .5 .4 .2v.3l-.2 .3h-.4l-.2-.2M105.4 70.3l.5 1.3 .3-1.3M106.5 70.3h.8l-.4 .5h.3v.7l-.5 .1-.2-.2M107.6 71.7h.9M108.7 70.9h.5M109.3 70.3h-.6v1.3h.6M110.6 70.3v1.3l-.8-1.3v1.3" fill="none" stroke="#0c0c0c" stroke-width=".21"/>
<path d="M76.9 56.7h.6l.7 .6-.7 .6h-.6z" fill="#fff"/>
<path d="M72.9 56.6l.4 1.2 .4-1.2M73.8 57.9h.9M75.1 56.6v1.2M76.3 56.6v1.2l-.7-1.2v1.2M76.9 56.7h.6l.7 .6-.7 .6h-.6z" fill="none" stroke="#805e00" stroke-width=".21"/>
<path d="M158.6 64.7h1.9v4.9h-1.9zM158.6 75.8h1.9v4.9h-1.9z" fill="none" stroke="#980000" stroke-width=".25"/>
<path d="M137.3 57.3h2.8M142 57.3h2.7M152.1 62.2a.64 .64 0 0 1 .6-.7 .64 .64 0 0 1 .6 .7M152.1 62.2a.59 .59 0 0 0-.6-.6 .59 .59 0 0 0-.6 .6h-1.3M153.4 62.2a.59 .59 0 0 1 .6-.6 .59 .59 0 0 1 .6 .6M154.6 62.2a.64 .64 0 0 1 .6-.7 .64 .64 0 0 1 .7 .7M155.8 62.2h1.2M159.5 63.5v1.1M159.5 69.5v1.3M159.5 74.5v1.2M159.5 80.6v1.3" fill="none" stroke="#980000" stroke-width=".21"/>
<path d="M166.2 66.4h3.9M166.2 67.9h3.9" fill="none" stroke="#aaa" stroke-width=".51"/>
<path d="M168.1 63.5v2.7M168.1 68.1v2.7" fill="none" stroke="#aaa" stroke-width=".21"/>
<path d="M165 64.3l6.4 5.7M171.4 64.3l-6.4 5.7" fill="none" stroke="#e00" stroke-width=".42"/>
<g fill="none" stroke="#0c0c0c" stroke-width=".21">
<path d="M141.3 60.5h.7l-.3 .4 .3 .2v.5h-.7M142.4 60.5l.4 1.2 .4-1.2M143.5 60.5h.8l-.4 .4 .4 .3-.1 .4h-.7M144.6 61.8h.9M145 70.3h.7l-.4 .5h.4v.2v.5l-.5 .1-.2-.2M146.1 70.3l.4 1.3 .4-1.3M146.4 60.5h-.6l-.1 .2 .2 .4h.3l.2 .2-.1 .3h-.6M146.8 60.5l.3 1.2 .3-.9 .2 .9 .3-1.2M147.2 70.3h.7l-.3 .5 .3 .1v.5l-.1 .2h-.4l-.2-.2M148.2 71.7h.9M149.5 70.9h.4M150.1 70.3h-.6v1.3"/>
<path d="M150.5 70.9l.6-.1v-.4l-.6-.1v1.3h.5l.3-.4-.4-.3"/>
</g>
<path d="M140.2 55.2v4M141.8 55.2v4" fill="none" stroke="#980000" stroke-width=".51"/>
<path d="M205.1 61.6h.7l.6 .6-.6 .6h-.7z" fill="#fff"/>
<path d="M205.1 61.6h.7l.6 .6-.6 .6h-.7zM206.8 61.5h.8l-.5 .5 .5 .1v.5l-.2 .2h-.4l-.2-.2M207.9 61.5l.4 1.3 .4-1.3M209.1 61.5h.7l-.4 .5 .4 .2v.3l-.2 .3h-.4l-.1-.2M210 62.9h1M211.3 61.7l.5-.2a.86 .86 0 0 1 0 1.3 .46 .46 0 0 1-.6-.4zM212.6 61.5v1l.2 .3h.3l.2-.3v-1M213.7 61.5h.7M214.1 61.5v1.3" fill="none" stroke="#805e00" stroke-width=".21"/>
<path d="M182.2 66.4h3.9M182.2 67.9h3.9M189.6 66.4h3.9M189.6 67.9h3.9M197 66.4h4M197 67.9h4" fill="none" stroke="#980000" stroke-width=".51"/>
<path d="M184.2 63.5v2.7M184.2 68.1v2.7M191.6 63.5v2.7M191.6 68.1v2.7M199 63.5v2.7M199 68.1v2.7" fill="none" stroke="#980000" stroke-width=".21"/>
<g fill="none" stroke="#00a200" stroke-width=".21">
<path d="M78.2 57.3h36.9M90.5 57.3v3.6M100.4 57.3v2.4M107.7 57.3v2.4M134.8 57.3h2.5M144.7 57.3h2.5v4.9M90.5 68.4v4.9M90.5 72.1h24.6M100.4 67.1v17.3h24.6M107.7 67.1v17.3M125 79.5v8.6M134.8 72.1h24.7"/>
<path d="M134.8 62.2h14.8M157 62.2h48.1M159.5 62.2v1.3M159.5 70.8v3.7M168.1 70.8v2.5h-8.6M168.1 62.2v1.3M184.2 62.2v1.3M184.2 70.8v14.8M191.6 62.2v1.3M191.6 70.8v14.8M199 70.8v14.8h-74M199 62.2v1.3"/>
<path d="M90.5 80.6v1.3h34.5M159.5 81.9v1.3h-34.5"/>
</g>
<g fill="none" stroke="#001dcd" stroke-width=".21">
<path d="M55.9 83.2h44.5v9.8h-44.5zM57.1 84.1l.4 1.3 .4-1.3M57.1 90l.4 1.3 .4-1.3M57.3 87.3v-1.2l.4 .9 .4-.9v1.2M57.3 88.8h.5l.1-.2v-.4l-.6-.1v1.3M57.5 88.8l.4 .6M58.3 85l.6-.2-.2-.3-.4 .1v.7h.5M58.3 90.9l.6-.1-.2-.3h-.4v.7h.5M58.3 88.5h.5M58.5 88.1v1.2l.3 .1M58.7 86.5v.7h.5M59.2 88.6l.4-.1 .2 .3v.3l-.2 .3-.5-.3z"/>
<path d="M59.2 86.5v.8M59.4 84.6l.3-.1 .2 .2v.7M59.4 90.6l.2-.1 .3 .1v.7M59.4 84.5v.9M59.4 90.5v.8M60.2 86.6l-.3-.1-.2 .2 .1 .2 .4 .1v.2h-.5M60.3 88.6l.4-.1 .2 .3-.1 .5h-.5M60.3 88.5v1.2M60.7 86.5h.4M60.8 86.1v1.1l.3 .1M61.4 84.7h1M61.4 85h1"/>
<path d="M61.4 90.6h1M61.4 91.1h1M62.4 86.9l.5-.1v-.2l-.4-.1-.1 .2v.5l.1 .1 .4-.1M62.4 88.7h.9M62.4 89h.9M63.5 86.7l.2-.2 .3 .2v.6M63.5 86.5v.8M63.9 84.4l.3-.3v1.3M63.9 85.4h.7M64.6 90.6l-.1 .2h-.5l-.1-.6 .4-.2 .3 .3-.2 .9-.4 .1M64.6 86.6l.4-.1 .1 .2v.6M65.1 85.2v.2"/>
<path d="M65.1 88.6l-.3-.1 .1-.3a.33 .33 0 0 1 .5-.1 .33 .33 0 0 1 0 .5l-.6 .2v.4l.3 .2 .4-.3v-.2l-.3-.3M65.1 91.2v.1M65.1 86.8l-.5 .1v.2l.1 .2 .4-.1M65.6 84.2l.5-.1 .2 .3-.7 1h.7M65.7 86.6l.4-.1 .2 .2-.1 .5h-.5M65.7 86.1v1.2M65.9 90l-.3 .9h.7M66 88.2l.4-.1 .3 .3-.8 1h.8M66.2 90.5v.8M66.7 84.1l.4 1.3 .4-1.3M66.7 90l.4 1.3 .4-1.3M66.8 86.1v1.1l.2 .1"/>
<path d="M67.3 88.2a.6 .6 0 0 1 .6 .4 .6 .6 0 0 1-.2 .7l-.2 .1a.75 .75 0 0 1-.2-1.2zM67.4 86.9l.6-.1-.1-.3-.5 .2v.5l.2 .1 .3-.1M68.4 88.1v1.3M68.4 88.9l.5 .5M68.6 84.5h.5M68.9 84.1v1.2l.2 .1M68.9 88.5l-.5 .4M69.5 86.6h.5v.7M69.5 89.3l-.2 .2M69.5 84.5l.2 .9M69.6 90.7l-.4-.1-.2 .2 .3 .4 .3-.1M69.6 90.6v.5l.3-.1a.58 .58 0 0 0-.7-.7 .58 .58 0 0 0-.4 .8 .58 .58 0 0 0 .8 .3l.2-.1"/>
<path d="M70 84.5l-.4 1.1-.1 .1M70 86.8l-.5 .1v.3h.5M70.4 90.5l.3-.5v1.3M70.4 86.5h.5M70.4 91.3h.7M70.5 84.6l.3-.1 .3 .3-.1 .5h-.5M70.5 84.5v1.2M70.6 86.1v1.1l.3 .1M70.9 88.8l.6-.1v-.5l-.6-.1v1.3M71.2 88.8l.4 .6M71.5 85l.6-.2v-.2l-.4-.1-.2 .2 .1 .6h.5M71.6 91.2v.1"/>
<path d="M72.1 88.6h.6v.6l-.2 .2-.4-.1M72.1 90.2l.2-.2h.3l.3 .3-.1 .3-.7 .7h.8M72.1 88.1v1.3M72.2 86.5l.3-.4v1.2M72.2 87.3h.7M72.7 85.2v.2M73.1 88.5h.4M73.2 90l.4 1.3 .4-1.3M73.3 88.1v1.2l.2 .1M73.4 86.2l.5-.1 .1 .2v.8a.35 .35 0 0 1-.4 .2 .35 .35 0 0 1-.2-.4zM74 88.6l.3-.1 .2 .2v.7M74 88.5v.9"/>
<path d="M74.1 84.4l.4-.3v1.3M74.1 85.4h.7M74.4 86.1l.4 1.2 .4-1.2M74.5 88.7l.1-.2 .4 .1v.8M75.1 90.5h.5M75.4 85.2v.2M75.4 90v1.2l.2 .1M75.6 87.2v.1M75.9 84.2l.4-.1 .3 .3-.8 1h.8M75.9 90.5l.3 .8M76.5 90.5l-.3 1.1-.3 .1M76.5 88.7h1"/>
<path d="M76.5 89h1M77 90.5h.3l.3 .2-.1 .5h-.5M77 90.5v1.2M77.7 84.1h-.6v.6l.6-.1v.7l-.4 .1-.2-.2M78.1 84.1l.4 1.3 .4-1.3M78.1 91.2v.1M78.8 91.2l-.2 .3M78.9 88.4l.4-.3v1.3M78.9 89.4h.7M80.1 88.2l.5-.1 .2 .3-.8 1h.8M80.3 84.6l.3-.1 .2 .2v.7M80.3 84.5v.9"/>
<path d="M80.6 90.7l-.6 .1M80.8 84.7l.2-.2 .3 .1v.8M81.4 88.2h.4a.75 .75 0 0 1-.2 1.2l-.3-.3zM81.7 90.6v.2h-.6v-.6l.4-.2 .2 .3-.1 .9-.5 .1M81.9 84.6h.5v.8M82.2 91.2v.1M82.4 84.8l-.5 .2v.3h.5M82.5 88.1v1.3M82.7 88.9l.3 .5M82.9 84.5l.7 .9M83 90.6l-.2-.4 .2-.2 .4 .1v.4l-.6 .2v.5l.2 .1h.3l.2-.2-.1-.5h-.1M83 88.5l-.5 .4"/>
<path d="M83.5 89.2v.2M83.6 84.5l-.7 .9M83.9 90l.4 1.3 .4-1.3M86.8 90.7h-.5v.4l.2 .1 .3-.1M86.8 90.6v.5h.3v-.5a.58 .58 0 0 0-.9-.2 .58 .58 0 0 0-.1 .9 .58 .58 0 0 0 .9 0M87.6 90.5l.3-.5v1.3M87.6 91.3h.7M88.8 91.2v.1M89.4 90.2l.4-.2 .2 .5-.7 .8h.7M91.1 90h-.6v.6a.45 .45 0 0 1 .6 0 .45 .45 0 0 1 0 .6h-.6M91.6 90l.4 1.3 .4-1.3M93.8 90.6l.1-.1 .4 .1v.7"/>
<path d="M93.8 90.5v.8M94.3 90.6l.1-.1 .4 .1v.7M95.4 90.5h.5v.8M95.9 90.8h-.4l-.2 .3 .2 .2 .4-.1M96.4 90.5l.6 .8M97 90.5l-.6 .8M97.5 91.2v.1M144.7 88.1h27.1v12.3h-27.1zM145.8 89l.5 1.3 .4-1.3M145.9 93h.8l-.4 .5h.3v.7l-.5 .1-.2-.2M146 91.6h.6l.2-.1-.1-.4h-.7v1.1M146 95.5h.5l.1 .7"/>
<path d="M146 95.5v.7M146.3 91.6l.5 .6M146.6 95.6v-.1h.4l.1 .7M146.9 89.4h.5M147.1 91.5h.4M147.2 94.1v.2M147.3 91.1v1l.2 .1M147.4 89l-.3 .2v1.1M147.7 93h.8l-.5 .5 .4 .1 .1 .4-.3 .3h-.3l-.2-.2M147.7 95.5h.4l.1 .1v.6h-.5v-.4l.5-.1M147.8 89.5h.5l.1 .5a.36 .36 0 0 1-.6 .2M147.8 89v1.3"/>
<path d="M147.9 91.6l.6-.1v.7h-.6zM148.7 95.5l.6 .7M148.8 93l.4 1.3 .4-1.3M149.1 92.2h.5v-.7h-.5v1.2M149.3 95.5l-.6 .7M149.8 89.6h1M149.8 90h1M151 93.5l.3-.1 .3 .3v.3l-.3 .3-.4-.3zM151.2 95.6l-.2 .2-.3-.2-.1 .2M151.2 91.6h.9M151.2 92h.9M151.5 95h.8l-.5 .5 .5 .2-.1 .4h-.7"/>
<path d="M152.1 93.4v.8l.3 .1 .2-.2M152.5 89a.75 .75 0 0 1 .2 1.3h-.2a.9 .9 0 0 1 0-1.3zM152.6 93.4v.9M152.8 96.1v.1M153 93.4h.5M153.2 93v1.1l.3 .2M153.3 95h.7l-.4 .5 .4 .2v.4h-.7M153.5 90.2v.1M153.5 91.1h.8l-.5 1.1M154.2 89.6l-.2-.4 .2-.2 .4 .1v.4l-.6 .2v.5l.2 .1h.3l.2-.3-.1-.4h-.1M154.6 93.4h.5M154.7 95.5l-.2-.2 .1-.3h.5l.1 .2-.1 .3a.48 .48 0 0 0-.5 .2 .48 .48 0 0 0 0 .5h.5l.1-.2-.2-.5"/>
<path d="M154.8 93v1.1l.3 .2M155.1 89l.4 1.3 .4-1.3M155.4 91.1h-.6l-.1 .5 .2-.1h.3l.2 .1v.6h-.7M155.4 93.4l.3 .9M155.6 95l.4 1.2 .3-1.2M156 93.4l-.3 .9-.3 .4M156 91.1v1.1M156.1 91.8l.3 .4M156.3 90.2l-.1 .3M156.4 91.5l-.4 .4M156.5 93.5l.3-.1 .3 .3v.3l-.3 .3-.3-.1M156.5 93.4v1.3"/>
<path d="M157 92.2l-.1 .2M157.6 94.1v.2M157.9 89.8h.9M158.3 89.4v.9M158.4 91.6h.6l.2-.1-.1-.4h-.7v1.1M158.8 91.6l.4 .6M159.1 93.5h.5v.8M159.1 93.4v.9M159.6 93.6l.2-.2 .3 .1v.8M159.7 91.1v1.1h.4l.2-.1v-.5l-.2-.1h-.4M160.2 89l-1 1.5M160.6 89.8h1"/>
<path d="M160.6 91.5h.6M160.7 93v.2M160.7 93.4v.9M160.8 91.1v1l.1 .1h.3M161.3 93.5l.5-.1 .1 .2v.7M161.3 93.4v.9M161.5 91.6l.5-.1 .1 .7M161.5 91.5v.7M162.1 89.2l.2-.2h.3l.3 .3-.1 .3-.7 .7h.8M162.1 91.6v-.1h.4l.1 .7M163.4 89l.2 .1v.3h-.2l-.1-.2zM163.8 93.7l-.5 .1"/>
<path d="M164 90h.2v.2l-.2 .1-.1-.2zM164.1 91.6h1M164.1 92h1M164.2 93h.8l-.5 .5 .4 .1 .1 .4-.3 .3h-.3l-.2-.2M164.2 89l-.9 1.3M165.5 94.1v.2M165.6 89.4l.2 .9 .3-.6 .2 .6 .2-.9M166 93.2l.2-.2h.3l.2 .2v.3l-.8 .8h.8M166.5 91.1h.6l.2 .2-.8 .9h.8M167 90.2v.1M167.2 93.2l.1-.2h.4l.1 .2v.3l-.7 .8h.7M168 91l-.3 .8h.7"/>
<path d="M168.1 89.5l-.3-.1-.3 .3 .1 .5h.5M168.2 93l.4 1.3 .4-1.3M168.3 91.5v.7M168.6 90.2v.1M168.9 91.1v1.1M169 91.8l.4 .4M169.4 91.5l-.5 .4M169.5 94.2l-.1 .2"/>
</g>
<g fill="#00a200">
<circle cx="107.7" cy="84.4" r=".47"/>
<circle cx="125" cy="81.9" r=".47"/>
<circle cx="125" cy="83.2" r=".47"/>
<circle cx="100.4" cy="57.3" r=".47"/>
<circle cx="107.7" cy="57.3" r=".47"/>
<circle cx="90.5" cy="72.1" r=".47"/>
<circle cx="125" cy="85.6" r=".47"/>
<circle cx="125" cy="84.4" r=".47"/>
<circle cx="90.5" cy="57.3" r=".47"/>
<circle cx="159.5" cy="73.3" r=".47"/>
<circle cx="159.5" cy="62.2" r=".47"/>
<circle cx="147.2" cy="62.2" r=".47"/>
<circle cx="159.5" cy="72.1" r=".47"/>
<circle cx="168.1" cy="62.2" r=".47"/>
<circle cx="199" cy="62.2" r=".47"/>
<circle cx="191.6" cy="62.2" r=".47"/>
<circle cx="184.2" cy="62.2" r=".47"/>
<circle cx="191.6" cy="85.6" r=".47"/>
<circle cx="184.2" cy="85.6" r=".47"/>
</g>
<g fill="none" stroke="#970091" stroke-width=".21">
<path d="M99.4 54.2l.6-.1 .1 .5-.7 .7h.7M101.3 54.1h-.6l-.1 .6 .2-.1h.3l.2 .1v.5h-.7M101.6 54.1l.5 1.2 .4-1.2M107.5 54.1h-.6l-.1 .6 .5-.1 .3 .2v.4l-.2 .1-.6-.1M108.2 54.1l.4 .1a.94 .94 0 0 1 0 1.1l-.4-.1a.87 .87 0 0 1 0-1.1zM109.1 54.1l.4 1.2 .4-1.2M140.2 51.7h-.5l-.1 .6 .1-.2 .5 .1v.6h-.6M140.8 51.9l.1-.2h.4a.86 .86 0 0 1-.1 1.2l-.4-.3zM141.8 51.7l.4 1.2 .4-1.2M183.9 59h-.6v.6h.5l.2 .1v.4l-.2 .2h-.4l-.1-.2M184.6 59.1l.3-.1 .2 .3v.8l-.2 .2a.71 .71 0 0 1-.3-1.2zM185.5 59l.4 1.3 .4-1.3"/>
<path d="M190.7 59.4l.3-.4v1.3M192 59.1h.1a.6 .6 0 0 1 .5 .5 .6 .6 0 0 1-.2 .6l-.3 .1-.2-.2zM192.9 59l.4 1.3 .5-1.3M198.1 59.4l.3-.4v1.3M199.3 59.1l.4-.1 .2 .3v.8l-.2 .2-.4-.2zM200.3 59l.4 1.3 .4-1.3M190.7 60.3h.7M198.1 60.3h.6"/>
</g>
<path d="M172.8 68.9h-.6v.6h.6v.6h-.6M173.4 69l.4-.1 .2 .2v.8l-.2 .2h-.4zM174.5 68.9l.3 1.2 .4-1.2" fill="none" stroke="#aaa" stroke-width=".21"/>
<g fill="none" stroke="#007170" stroke-width=".21">
<path d="M99.4 52l.4-.3v1.2M99.4 52.9h.7M100.2 49.3l-.1-.1a.57 .57 0 0 0-.7 .6 .57 .57 0 0 0 .8 .5M100.7 51.8l.4-.1 .2 .2v.7a.35 .35 0 0 1-.4 .3 .35 .35 0 0 1-.3-.5zM100.7 49.6l.3-.5v1.3M100.7 50.4h.7M101.9 52v.8h.5M102.1 49.1a.67 .67 0 0 1 .5 .7 .67 .67 0 0 1-.5 .6l-.2-.2v-.8zM102.4 52v.9M106.8 52l.4-.3v1.2M106.8 52.9h.8M107.6 49.3a.57 .57 0 0 0-.7 .1 .57 .57 0 0 0 0 .8 .52 .52 0 0 0 .7 .1"/>
<path d="M108.1 49.6l.3-.5v1.3M108.1 50.4h.6M108.2 51.7l.4 .1a.66 .66 0 0 1-.3 1.1 .84 .84 0 0 1-.1-1.2zM109.3 49.6l.3-.5v1.3M109.3 50.4h.6M109.3 51.7h.2a.62 .62 0 0 1 .5 .6 .62 .62 0 0 1-.5 .6 .84 .84 0 0 1-.2-1.2zM110.4 52.2l.2-.2 .3 .1 .1 .8M110.4 52v.9M121 52.9l.4-1.2 .5 1.2M121.1 52.5h.6M122.3 52.3h.6v-.6h-.6v1.2M123.8 49.2v1.2"/>
<path d="M124 51.7a.55 .55 0 0 0-.6 .5l.1 .6 .4 .1 .3-.3v-.2l-.3-.3h-.2l-.3 .3M124.6 51.8l.6-.1 .1 .2v.3l-.7 .7h.7M125.1 49.3l-.5-.1a.61 .61 0 0 0-.3 .8 .61 .61 0 0 0 .8 .3M125.5 49.3l.6-.1 .2 .2-.1 .3-.7 .7h.8M125.8 51.8l.6-.1 .1 .2-.1 .3-.6 .7h.7M127 51.8l.5-.1 .1 .2v.7a.35 .35 0 0 1-.4 .3 .35 .35 0 0 1-.2-.5zM128.2 51.8l.4-.1 .2 .2v.7a.35 .35 0 0 1-.4 .3 .35 .35 0 0 1-.3-.5zM139 49.6l.3-.5v1.3M139 50.4h.7M140.2 49.2l.2-.1a.67 .67 0 0 1 .5 .7 .67 .67 0 0 1-.5 .6 .84 .84 0 0 1-.2-1.2zM140.2 46.9l-.3-.2-.4 .3 .1 .8 .3 .2 .3-.1M140.7 47.1l.4-.4v1.3"/>
<path d="M140.7 48h.7M141.4 49.2l.2-.1a.67 .67 0 0 1 .5 .7 .67 .67 0 0 1-.5 .6 .84 .84 0 0 1-.2-1.2zM141.9 46.9l.1-.2h.4l.2 .2-.1 .4-.6 .7h.7M142.5 49.7l.2-.1 .3 .1v.7M142.5 49.6v.8M151.8 59h.7l-.3 .6h.3v.5l-.1 .2h-.5l-.1-.2M152.5 56.6v1.2h.6M153.1 59.5v.7l.4 .1 .1-.2M153.5 56.7l.5-.1 .2 .2-.7 1h.7M153.6 59.5v.8M154 59h.8l-.3 .6h.3v.5l-.2 .2-.6-.2M183.3 56.9l.3-.3v1.2"/>
<path d="M183.3 57.8h.7M184 54.2l-.5-.1-.2 .5 .2 .7 .5-.1M184.5 54.5l.4-.4v1.2M184.5 55.3h.7M184.6 56.7l.3-.1 .2 .2v.8l-.2 .2-.3-.1a.78 .78 0 0 1 0-1zM185.7 56.7l.3-.1 .3 .2v.8l-.2 .2-.4-.1zM186 54.1l-.3 .8h.8M186.3 54.6v.7M186.9 57.1l.4-.1 .1 .8M186.9 57v.8M190.7 56.7l.4-.1 .3 .3-.8 .9h.8M191.5 54.2l-.6-.1-.2 .3v.7l.2 .2 .6-.1"/>
<path d="M191.9 56.7l.4-.1 .3 .3-.8 .9h.8M191.9 54.5l.3-.4v1.2M191.9 55.3h.8M193.1 57l.1 .8 .4-.1M193.6 57v.8M193.8 54.1h-.6l-.1 .6 .1-.1h.4l.2 .1v.5h-.7M198.1 56.7h.6v.4l-.7 .7h.7M198.8 54.2l-.1-.1a.66 .66 0 0 0-.6 .5 .66 .66 0 0 0 .2 .7l.5-.1M199.3 56.7h.6v.4l-.7 .7h.7M199.3 54.5l.4-.4v1.2M199.3 55.3h.7M200.4 57l.1 .8 .5-.1"/>
<path d="M201 54.1a.55 .55 0 0 0-.6 .5v.6l.2 .1h.4l.2-.1v-.4l-.2-.2h-.3l-.3 .2M201 57v.8M93.3 77.9l.3-.4v1.3M93.3 78.8h.7M93.3 75.7l.7-.1v-.4l-.2-.1h-.5v1.2M93.3 63.4h.6l.1-.5-.7-.1v1.2M93.5 65.7l-.2-.2 .1-.3h.4l.2 .3-.1 .2a.48 .48 0 0 0-.5 .2 .48 .48 0 0 0 0 .5h.4l.2-.2-.1-.4-.1-.1M93.6 75.7l.4 .6M93.6 63.4l.4 .6M94.4 77.7l.2-.2h.3l.3 .4-.8 .9h.8M94.4 65.3l.6-.1 .2 .4-.8 .8h.8M95.2 75.6l-.1 .2h-.5v-.7h.3l.3 .1v.8l-.3 .3h-.3"/>
<path d="M95.2 63.3l-.3 .2h-.3v-.7l.6 .1v.8l-.3 .3h-.3M95.7 77.7l.3-.2 .3 .3v.7l-.3 .3-.3-.1zM95.7 65.3l.4-.1 .2 .3v.7l-.2 .2-.4-.1zM95.7 75.2l.4-.1 .3 .3-.8 .9h.8M95.7 63.1l.3-.3v1.2M95.7 64h.7M96.9 65.2v1.2M96.9 77.5v1.3M97 78.3l.3 .5M97 66l.3 .4M97.3 77.9l-.4 .5M97.3 65.7l-.4 .4"/>
<path d="M162.3 67.7h.8l-.5 1.2M162.3 78.9l.5-.1 .2 .3-.7 .9h.7M162.3 65.8h.6l.2-.1-.1-.4-.7-.1v1.2M162.3 76.9h.6l.2-.2-.1-.3-.7-.1v1.2M162.7 65.8l.4 .6M162.7 76.9l.4 .6M163.8 78.7l-.3 .9h.8M164.1 67.7h-.6v.6l.2-.2 .4 .1v.7l-.6-.1M164.1 79.2v.8M164.3 65.7l-.3 .3h-.2l-.3-.3 .1-.4 .5-.1 .2 .3-.2 .8-.4 .1M164.3 76.8l-.3 .3h-.2l-.3-.3 .1-.4 .4-.1 .3 .3-.2 .8-.4 .1M164.6 65.2h.8l-.3 .5 .3 .1v.5h-.8"/>
<path d="M164.7 67.7v1.2M164.7 78.8v1.2M164.9 68.4l.3 .5M164.9 79.5l.3 .5M165.1 76.2l-.4 1h.8M165.2 68.1l-.5 .4M165.2 79.2l-.5 .4M165.3 76.7v.8M124.1 92.4l-.2-.1a.64 .64 0 0 0-.6 .7 .64 .64 0 0 0 .6 .6l.2-.1v-.5h-.2M125.3 92.3v1.3l-.6-1.3v1.3M125.9 92.3a.52 .52 0 0 1 .7 .4v.6a.52 .52 0 0 1-.7 .3z"/>
</g>
<path d="M172.2 66.6l.1-.2h.4l.2 .3-.1 .3-.6 .7h.7M172.9 64.1l-.2-.1a.65 .65 0 0 0-.5 .6 .65 .65 0 0 0 .5 .6l.2-.1M173.3 66.6l.2-.2h.4l.1 .2v.4l-.7 .7h.7M173.4 64.3l.4-.3v1.2M173.4 65.2h.7M174.5 64h.8l-.4 .5h.3v.6l-.5 .1-.2-.1M174.6 66.9l.4-.1 .2 .3-.1 .5h-.5M174.6 66.8v1.3" fill="none" stroke="#a2a2a2" stroke-width=".21"/>
<path d="M165 64.3l6.4 5.7M171.4 64.3l-6.4 5.7" fill="none" stroke="#e00" stroke-width=".42"/>
</svg>
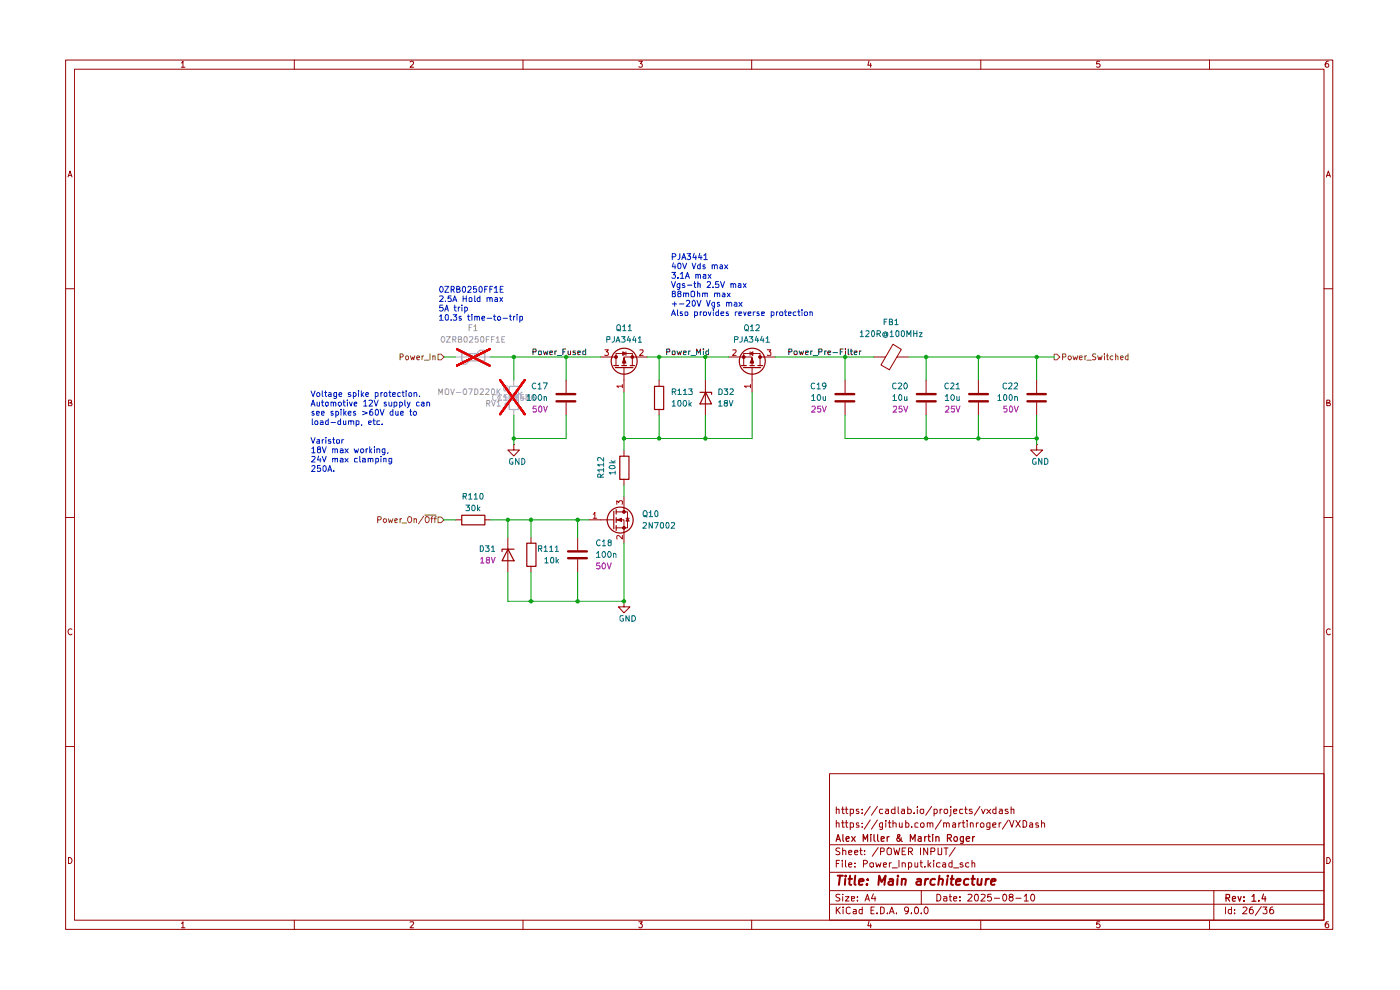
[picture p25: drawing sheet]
<svg xmlns="http://www.w3.org/2000/svg" width="297mm" height="210mm" viewBox="0 0 297 210" stroke-linecap="round" stroke-linejoin="round" font-family="sans-serif">
<g fill="none" stroke="#980000" stroke-width=".21">
<path d="M13.9 12.7h268.8v184.4h-268.8zM15.8 14.7h265.1v180.5h-265.1zM38.5 13.3h.1l.2-.3v1.3M38.5 14.3h.7M62.4 12.7v2M87 13.2l.5-.2 .3 .2-.1 .4-.7 .7h.8M111 12.7v2M135.5 13h.8l-.5 .5 .4 .1v.6h-.7M159.5 12.7v2M184.4 12.9l-.3 .9h.8M184.7 13.4v.9M208.1 12.7v2"/>
<path d="M233.3 13h-.6l-.1 .6h.7v.6h-.7M256.6 12.7v2M281.8 13a.71 .71 0 0 0-.7 .5 .71 .71 0 0 0 .3 .8l.4-.1v-.6l-.4-.1-.3 .3M14.4 37.5l.5-1.2 .4 1.2M14.5 37.2h.7M281.4 37.5l.4-1.2 .4 1.2M281.5 37.2h.6M13.9 61.3h1.9M280.9 61.3h1.8M14.5 85.5h.4l.3-.3-.2-.3h-.5v1.2h.6l.2-.5-.4-.1M281.5 85.5h.4l.2-.3-.1-.3h-.5v1.2h.6l.1-.5-.3-.1M13.9 109.8h1.9"/>
<path d="M280.9 109.8h1.8M15.3 133.5a.59 .59 0 0 0-.9 .5 .59 .59 0 0 0 .8 .6l.1-.1M282.2 133.5a.59 .59 0 0 0-.8 .5 .59 .59 0 0 0 .7 .6l.1-.1M13.9 158.4h1.9M280.9 158.4h1.8M176 164.1h104.9v31.1h-104.9zM176 179.2h104.9M177.4 174.7l.2-.2 .4 .1v.9M177.4 171.7h.6v.9M177.4 171.1v1.5M177.4 174v1.5M178.2 180l-.6-.1-.3 .2 .1 .4 .8 .4-.1 .3h-.8"/>
<path d="M178.5 174.5h.6M178.5 171.7h.6M178.8 174v1.5h.3M178.8 171.1v1.4l.3 .1M178.8 179.9v1.4M179.4 174.5h.5M179.4 171.7h.5M179.5 174v1.3l.1 .2h.3M179.5 171.1v1.3l.4 .2M180.4 174.6l.4-.1 .3 .2v.7l-.7 .1M180.4 172.5l.4 .1 .3-.2-.1-.7h-.6v1.4M180.4 174.5v1.5"/>
<path d="M182.2 174.6l-.4-.1-.2 .2 .2 .3h.4v.5h-.6M182.2 171.7h-.5l-.1 .2 .5 .2 .1 .3-.1 .2-.5-.1M182.6 179.9v1.2l.3 .2M182.9 175.4v.1M182.9 174.6v.1M182.9 172.4v.2M182.9 171.7v.1M184.6 173.9l-1.3 2M184.6 171.1l-1.3 1.8M186.1 173.9l-1.2 2M186.1 171.1l-1.2 1.8M186.3 179.8l-1.3 1.8"/>
<path d="M187.2 174.5v1.2a.36 .36 0 0 1-.6 .2M187.2 174.6l-.4-.1-.2 .3v.6l.6 .1M187.2 171.7h-.5l-.1 .2v.4l.2 .3 .4-.1M187.9 174v.2M187.9 171.7h.5l.1 .9M187.9 174.5v1M188.4 174.5h.6M188.5 172h-.5l-.2 .2 .2 .4 .5-.1M188.7 174v1.5h.3M189.4 174.7l.3-.2 .4 .2v.8M189.4 174v1.5M189.6 179.9l.3 1.4 .3-1 .3 1 .4-1.4"/>
<path d="M189.9 171.7h-.6l-.2 .6a.52 .52 0 0 0 .8 .2M189.9 171.1v1.5M190.5 171.1v1.3l.2 .2M190.8 174.5l.1 1 .5-.1M191.3 171.7h.5l.1 .9M191.4 174.5v1M191.9 172h-.5l-.2 .2 .2 .4 .5-.1M192.1 179.9h-.7v1.4h.7M192.1 174v1.5l.6-.1 .1-.6a.45 .45 0 0 0-.7-.2M192.6 171.7h.6l.1 .6a.52 .52 0 0 1-.7 .2M192.6 171.1v1.5M193.4 175.4v.1"/>
<path d="M193.9 172.4v.2M194.6 171.1v.1M194.6 171.7v.9M194.8 174.6l-.5-.1-.2 .2v.7l.7 .1M195.3 174.8a.45 .45 0 0 1 .7-.2v.9l-.6-.1zM195.3 171.7h.7l-.1 .8a.45 .45 0 0 1-.7-.2zM195.3 179.9v1.4M196.7 174.7l.2-.2 .4 .2v.8M196.7 174.5v1M196.8 179.9v1.4l-.8-1.4v1.4M197.3 174.7l.2-.2 .4 .1v.9M197.6 171.1l-1.2 1.8"/>
<path d="M198.2 172.5l.4 .1 .2-.3-.1-.6h-.5v1.4M199 179.9v1.3l.3 .1 .5-.1v-1.3M199.4 171.7v.9M199.7 173.9l-1.3 2M199.9 171.7h-.3l-.2 .2M200.2 174.7l.2-.2 .4 .2v.8M200.2 174.5v1M200.3 179.9h.8M200.4 171.7h.6v.8l-.5 .1-.2-.3zM200.7 179.9v1.4M200.8 174.7l.2-.2 .4 .2v.8M201.7 171.7v1.1l-.3 .3"/>
<path d="M201.7 171.1v.1M202.1 174.6l.4-.1 .2 .2v.8h-.6v-.4l.6-.2M202.3 172.1l.7-.1-.1-.3h-.5l-.1 .1v.6l.2 .2 .4-.1M202.6 179.8l-1.2 1.8M203.4 174.5v1M203.8 174.5l-.4 .3M204.1 174.5h.6M204.3 171.7h-.6l-.1 .2 .1 .6h.6M204.3 174v1.3l.1 .2h.3M204.7 171.7h.5M204.8 171.1v1.3l.4 .2M205.2 174v.2"/>
<path d="M205.2 174.5v1M205.9 174.7l.1-.2 .5 .2v.8M205.9 174.5v1M206.2 171.7h-.5l-.1 .2 .6 .3 .1 .2-.3 .2-.4-.1M207.1 174.5v1M207.6 174.5l-.5 .3M207.9 171.1l-1.2 1.8M208.2 174.5h.3l.2 .3-.1 .7h-.5l-.1-.3v-.4zM208.2 171.7l.4 .9 .4-.9M209.3 171.7l.9 .9M210 174.5v1.2l-.2 .3-.5-.1M210 174.6l-.4-.1-.3 .2v.7l.7 .1"/>
<path d="M210.2 171.7l-.9 .9M210.6 175l.7-.1v-.3l-.4-.1-.3 .2 .1 .8h.6M211.3 171.7h-.5l-.2 .6a.45 .45 0 0 0 .7 .2M211.3 171.1v1.5M212 174.5v1M212 171.7h.6v.9M212.4 174.5l-.4 .3M212.6 172h-.5l-.1 .2 .1 .4 .5-.1M213.8 171.7h-.5l-.1 .2 .6 .3 .1 .2-.2 .2-.5-.1M213.9 173.9l-1.3 2M214.2 174l.5 1.5 .4-1.5M214.5 171.7h.6v.9"/>
<path d="M214.5 171.1v1.5M215.5 174l.9 1.5M216.4 174l-.9 1.5M217 174h.4l.4 .4v.7l-.3 .4h-.5zM218.5 174.6l.4-.1 .2 .2v.8h-.6l-.1-.4 .7-.2M220.3 174.6h-.6v.4h.6v.2v.3h-.6M220.9 174.7l.3-.2 .4 .2v.8M220.9 174v1.5M14.5 181.9a.65 .65 0 0 1 .8 .6 .65 .65 0 0 1-.8 .7zM38.5 195.9l.3-.4v1.3M38.5 196.8h.7M62.4 195.2v1.9"/>
<path d="M87 195.6l.7-.1 .1 .3-.8 1h.8M111 195.2v1.9M135.5 195.5h.8l-.5 .5 .5 .2-.1 .5-.5 .1-.2-.2M159.5 195.2v1.9M176 191.8h104.9M176 188.9h104.9M176 185h104.9M177.4 192.4v1.4M177.4 183.2h.5M177.6 193l.7 .8M178.1 182.5h-.7v1.4M178.2 189.8h-.8l-.1 .3 .8 .4 .1 .4-.3 .2-.6-.1"/>
<path d="M178.3 192.4l-.9 .8M178.7 182.5v.2M178.7 183v.9M178.8 189.7v.1M178.8 180.5l.4-.1 .2 .1v.8M178.8 190.2v.9M178.9 192.4v.2M178.9 192.9v.9M179.4 190.2h.7l-.7 .9h.7M179.4 182.5v1.3l.1 .1M180 183.4l.7-.1-.2-.3-.5 .2v.6l.3 .1 .3-.1M180 180.8l.7-.1-.2-.3-.5 .1v.6l.3 .2 .3-.1"/>
<path d="M180.4 192.6l-.4-.2-.5 .3 .1 1 .4 .1 .4-.1M180.6 190.6l.7-.1-.1-.3h-.6v.8h.6M181.1 192.9h.5v.9M181.3 180.8l.7-.1-.2-.3h-.3l-.2 .1v.6l.2 .2 .4-.1M181.4 183.8v.1M181.4 183.1v.1M181.6 193.2l-.5 .1-.1 .2 .1 .3h.5M181.9 191v.1M181.9 190.2v.2M182.4 180.4h.5M182.9 192.9h-.5l-.2 .7a.45 .45 0 0 0 .7 .2M182.9 192.4v1.4"/>
<path d="M183.2 183.3l.6-.1 .2-.5-.3-.2h-.5v1.4M183.4 181.2v.1M183.4 180.5h.1M183.5 191.1l.5-1.4 .4 1.4M183.7 190.7h.7M184.4 195.4l-.3 1h.8M184.6 183.1h.7v.7h-.7zM184.7 196v.8M184.8 193.1h.5M185.3 189.6l-.4 1h.9M185.5 192.4h-.7v1.4h.7M185.6 190.2v.9"/>
<path d="M185.8 183l.2 .9 .4-.6 .2 .6 .3-.9M186 193.7v.1M186.8 192.4h.4l.4 .3v.8l-.4 .3h-.4zM186.8 180.6l.7-.1 .1-.5-.3-.1h-.5v1.4M187.4 183.4l.7-.1-.2-.3h-.3l-.2 .2v.6l.2 .1 .4-.1M188.3 193.7v.1M188.3 180l.2-.1 .6 .1v1.1l-.3 .2-.5-.2zM188.7 193.8l.5-1.4 .5 1.4M188.7 183v.9M188.8 193.4h.7M189.1 183l-.4 .3M189.3 184.1h1.1"/>
<path d="M190.2 193.7v.1M190.7 182.5v1.4M191.4 183.1l.4-.1 .3 .2v.7M191.4 183v.9M191.4 180.5h.5M192.7 193l-.2 .3h-.4l-.2-.3v-.3l.2-.3h.4l.2 .3v.8l-.2 .3h-.4M192.7 183.1l.5-.1 .2 .3-.1 .5h-.6M192.7 180.6h.6l.3-.2v-.3l-.3-.2h-.6v1.4M192.7 183v1.4M193.1 180.6l.5 .7M193.3 193.7v.1M194.1 192.6l.2-.2a.75 .75 0 0 1 .6 .7 .75 .75 0 0 1-.6 .7l-.2-.1-.1-.4z"/>
<path d="M194.1 183v.8h.6M194.7 183v.9M195.2 183h.5M195.4 182.5v1.3l.3 .1M195.4 193.7v.1M195.4 188.9v2.9M196.2 183.8v.1M196.4 192.4h.1a.8 .8 0 0 1 .4 .8 .8 .8 0 0 1-.5 .6 .89 .89 0 0 1 0-1.4zM196.9 182.5v1.4M197.1 183.4l.4 .5M197.5 180.6l.7-.1v-.5l-.7-.1v1.4M197.5 183l-.6 .5"/>
<path d="M198.1 182.5v.2M198.1 183v.9M198.7 189.7a.73 .73 0 0 1 .9 .7 .73 .73 0 0 1-.9 .7zM199.4 183.1l-.4-.1-.3 .3v.5h.7M200 183.1l.4-.1 .2 .2v.7M200.2 190.2h.6l.1 .9M200.6 183.3l-.6 .1-.1 .2 .3 .3 .4-.1M200.9 190.5l-.7 .1v.4h.7M201.4 190.2h.5M201.5 189.7v1.3l.4 .1M202 183.1l-.5-.1-.2 .3 .1 .5h.6M202 182.5v1.4"/>
<path d="M202.3 190.6l.7-.1-.1-.3h-.5l-.1 .2v.6l.2 .1 .4-.1M202.3 184.1h1.1M203.7 191v.1M203.7 190.2v.2M204.3 183.1l-.4-.1-.2 .3v.1l.6 .1v.3l-.2 .1-.4-.1M205.4 189.8l.5-.1 .3 .4-.9 1h.9M205.5 183.1l-.3-.1-.4 .3 .1 .5h.6M206.2 183.1l.4-.1 .2 .2v.7M206.2 182.5v1.4M206.9 189.8h.5a1.01 1.01 0 0 1-.2 1.3 .87 .87 0 0 1-.3-1.3zM208.1 195.2v1.9M208.1 189.8h.8l.1 .3-.9 1h.9"/>
<path d="M210.3 189.7h-.7l-.1 .7 .6-.2 .2 .3v.4l-.2 .2-.6-.1M210.9 190.5h1.1M212.8 189.8l.3-.1a.73 .73 0 0 1 .5 .7 .73 .73 0 0 1-.5 .7l-.3-.1-.1-.5zM214.3 190.3l-.2-.3 .1-.2h.6v.4l-.5 .1-.2 .2v.4l.2 .2h.4l.2-.2v-.4l-.2-.2M215.5 190.5h1.1M217.3 190.1l.4-.4v1.4M217.3 191.1h.8M218.8 189.8l.2-.1a.76 .76 0 0 1 .5 .7 .76 .76 0 0 1-.5 .7 1.01 1.01 0 0 1-.2-1.3zM233.3 195.5h-.6l-.1 .6 .2-.1h.3l.3 .2v.3l-.3 .3h-.3l-.2-.2M256.6 195.2v1.9M257.5 188.9v6.3M260 192.4v1.4"/>
<path d="M261.2 192.9h-.5l-.1 .3v.4l.2 .2h.4M261.2 192.4v1.4M261.9 193.7v.1M261.9 192.9v.2M263.7 192.6l.2-.2h.3l.3 .4-.9 1h.9M265.7 192.4l-.4 .1-.2 .2-.1 .9 .3 .2h.3l.3-.2v-.4l-.3-.3h-.3l-.3 .3M267.6 192.3l-1.3 1.9M267.9 192.4h.9l-.5 .5 .5 .2v.6l-.3 .1h-.4l-.2-.1M270 192.4l-.5 .2a1.02 1.02 0 0 0 .1 1.2h.4l.2-.2v-.4l-.3-.3h-.3l-.2 .3M281.5 181.9a.65 .65 0 0 1 .7 .6 .65 .65 0 0 1-.7 .7zM281.8 195.5h-.4l-.3 .5v.5l.3 .3 .4-.1v-.7h-.4l-.3 .2"/>
</g>
<g fill="none" stroke="#980000" stroke-width=".25">
<path d="M177.4 178.5l.4-1.5 .5 1.5M177.5 178h.6M178.8 177v1.2l.2 .3M179.5 178l.7-.2-.2-.3h-.4l-.1 .7 .2 .3 .4-.1M180.7 177.5l.7 1M181.4 177.5l-.7 1M183.1 178.5v-1.5l.5 1 .5-1v1.5M184.7 177v.1M184.7 177.5v1M185.4 177v1.2l.3 .3M186.2 177v1.2l.2 .3M186.9 178l.7-.2-.1-.3h-.6v.9h.6"/>
<path d="M188.2 177.5v1M188.6 177.5l-.4 .3M191.2 177.7v.3l-.5 .5a.43 .43 0 0 1-.4-.2 .43 .43 0 0 1 0-.5l.6-.5-.1-.3h-.3a.55 .55 0 0 0 .2 .8l.7 .7M193.1 178.5v-1.5l.5 1 .5-1v1.5M194.8 177.5h.6v1M195.4 177.8l-.4 .1-.3 .2 .3 .4 .4-.1M196.2 177.5v1M196.5 177.5h-.2l-.1 .3M196.8 177.5h.6M197 177v1.2l.4 .3M197.9 177v.1M197.9 177.5v1"/>
<path d="M198.5 177.6l.1-.1a.36 .36 0 0 1 .6 .2v.8M198.5 177.5v1M201 177.8l.7-.1 .1-.2v-.4l-.8-.1v1.5M201.3 177.8l.5 .7M204.4 177.5v1.1l-.2 .3h-.4M204.4 177.5h-.4l-.3 .3 .1 .6h.6M205 178l.7-.2-.1-.3h-.4l-.2 .2 .1 .7h.5M206.3 177.5v1M206.8 177.5l-.5 .3M260.1 190.5l.7-.1 .1-.6-.8-.1v1.5M260.4 190.5l.5 .7M261.4 190.7l.7-.1-.1-.4h-.5l-.1 .7 .2 .3 .4-.1"/>
<path d="M262.6 190.2l.4 1 .3-1M263.9 191v.2M263.9 190.2v.2M265.6 190.2l.4-.5v1.5M265.6 191.2h.8M267 191v.2M268 189.6l-.3 1.1h.9M268.4 190.2v1"/>
<circle cx="202.7" cy="178" r=".48"/>
</g>
<g fill="none" stroke="#980000" stroke-width=".42">
<path d="M177.7 185.8h1.1M178.2 185.8l-.2 1.9M179.3 186.4l-.1 1.3M179.4 185.8v.1M180 186.4h.8M180.3 185.8l-.1 1.6 .4 .3M181.4 185.8l-.1 1.6 .2 .3M182.2 187l1-.1-.1-.4a.6 .6 0 0 0-.8 .2v.9h.7M184 187.5l-.1 .2-.1-.1 .2-.1-.1 .2M184.1 186.5v.2M186.3 187.7l.2-1.9 .5 1.3 .9-1.3-.3 1.9M188.7 186.5h.7v1.2"/>
<path d="M189.5 186.9h-.7l-.3 .3v.2l.2 .3 .7-.1M190.4 186.4l-.1 1.3M190.5 185.8v.1M191.3 186.6l.1-.1a.48 .48 0 0 1 .8 .2l-.2 1M191.3 186.4v1.3M194.6 186.5h.7v1.2M195.4 186.9h-.7l-.3 .3v.2l.2 .3 .7-.1M196.3 186.4l-.1 1.3M196.9 186.4l-.4 .1-.2 .3M198.4 186.5a.65 .65 0 0 0-1 .3v.7a.64 .64 0 0 0 .9 .1M199.2 186.6l.1-.1a.48 .48 0 0 1 .8 .2l-.2 1M199.3 185.8l-.3 1.9"/>
<path d="M201 186.4l-.2 1.3M201.1 185.8v.1M201.7 186.4h.6M202 185.8l-.2 1.6 .4 .3M202.9 187l.9-.1v-.4l-.6-.1-.3 .3v.9h.7M205.5 186.5a.65 .65 0 0 0-1 .3v.7a.64 .64 0 0 0 .9 .1M206.1 186.4h.7M206.4 185.8l-.2 1.6 .5 .3M207.4 186.4v1.2l.5 .1 .3-.2M208.3 186.4l-.2 1.3M209.2 186.4l-.2 1.3M209.8 186.4l-.4 .1-.2 .3"/>
<path d="M210.2 187l1-.1v-.4a.6 .6 0 0 0-.9 .2v.9h.7"/>
</g>
<path d="M96.9 74.1l7 3.4M103.9 74.1l-7 3.4M106.1 80.6l5.2 7.3M111.3 80.6l-5.2 7.3" fill="none" stroke="#e00" stroke-width=".42"/>
<path d="M92.9 75.1h.7l.6 .6-.6 .6h-.7z" fill="#fff"/>
<path d="M84.9 75.7l.6-.1v-.5h-.6v1.2M86.1 75.6l.1-.1 .4 .1 .1 .6-.5 .1-.1-.1zM87.1 75.5l.2 .8 .3-.6 .2 .6 .2-.8M88.4 75.9l.6-.1-.1-.3-.5 .1v.6l.2 .1 .3-.1M89.5 75.5v.8M89.9 75.5l-.4 .2M90 76.4h1M91.2 75.1v1.2M91.8 75.6l.2-.1 .3 .1v.7M91.8 75.5v.8M92.9 75.1h.7l.6 .6-.6 .6h-.7z" fill="none" stroke="#805e00" stroke-width=".21"/>
<path d="M92.9 109.7h.7l.6 .6-.6 .6h-.7z" fill="#fff"/>
<g fill="none" stroke="#805e00" stroke-width=".21">
<path d="M80.1 110.3h.5l.3-.3-.1-.3-.7-.1v1.3M81.4 110.1l.3-.1 .3 .3v.3l-.3 .3-.4-.3zM82.4 110l.2 .9 .2-.6 .3 .6 .2-.9M83.8 110.4l.5-.1v-.2h-.5v.7h.5M84.9 110v.9M85.2 110l-.3 .1v.2M85.3 110.9h.9M86.6 109.8l.2-.2 .4 .1a.8 .8 0 0 1-.2 1.2h-.2a.79 .79 0 0 1-.2-1.1zM87.8 110.1h.5v.8M87.8 110v.9M89.9 109.5l-1.1 1.6M90.1 109.3h2.4"/>
<path d="M90.3 109.8l.2-.2 .5 .2a.79 .79 0 0 1-.3 1.1h-.2a.9 .9 0 0 1-.2-1.1zM91.4 110h.4M91.8 109.6l-.2 .1v1.2M92.1 110h.5M92.6 109.6l-.4 .2v1.1M92.9 109.7h.7l.6 .6-.6 .6h-.7z"/>
</g>
<path d="M98 109.3h4.9v2h-4.9z" fill="none" stroke="#980000" stroke-width=".25"/>
<path d="M120.1 80.6v2.7M120.1 85.4v2.7M196.5 80.6v2.7M196.5 85.4v2.7M207.6 80.6v2.7M207.6 85.4v2.7M96.6 110.3h1.3M102.8 110.3h1.2" fill="none" stroke="#980000" stroke-width=".21"/>
<path d="M96.6 75.7h7.4M102.8 74.3h-1l-3 3h-.9M106.9 81.7l.1 1.2 .6-.1v-1.1M109 80.6v1.3M109 86.8v1.3M110.8 83.2l-3.7 2.4v1.2" fill="none" stroke="#aaa" stroke-width=".21"/>
<path d="M98 75h4.9v1.5h-4.9zM108 82h2v4.9h-2z" fill="none" stroke="#aaa" stroke-width=".25"/>
<path d="M96.9 74.1l7 3.4M103.9 74.1l-7 3.4M106.1 80.6l5.2 7.3M111.3 80.6l-5.2 7.3" fill="none" stroke="#e00" stroke-width=".42"/>
<g fill="none" stroke="#0c0c0c" stroke-width=".21">
<path d="M113.1 74.6h.6v-.6h-.6v1.2M114.3 74.5h.5v.7l-.5-.1zM115.3 74.5l.2 .7 .3-.6 .2 .6 .2-.7M116.6 74.8l.6-.1-.1-.2h-.4l-.1 .1 .1 .6h.4M117.7 74.5v.7M118.1 74.5l-.4 .1M118.2 75.4h1M119.4 74.6h.4M120 74h-.6v1.2M120.5 74.5l.1 .7 .4-.1M121 74.5v.7M122 74.5h-.4l-.1 .1 .1 .2 .4 .1v.3h-.5"/>
<path d="M122.5 74.8l.6-.1v-.2h-.5l-.1 .1 .1 .6h.5M124.2 74v1.2h-.5v-.7h.5"/>
</g>
<path d="M118.1 85.1h3.9M118.1 83.6h3.9M194.5 85.1h4M194.5 83.6h4M205.6 85.1h4M205.6 83.6h4" fill="none" stroke="#980000" stroke-width=".51"/>
<path d="M223.6 75.1h.6l.6 .6-.6 .6h-.6z" fill="#fff"/>
<g fill="none" stroke="#805e00" stroke-width=".21">
<path d="M223.6 75.1h.6l.6 .6-.6 .6h-.6zM225.4 75.7l.7-.1v-.4l-.2-.1h-.5v1.2M226.7 75.6l.3-.1 .3 .2v.4l-.3 .2-.4-.2zM227.6 75.5l.3 .8 .2-.6 .3 .6 .2-.8M229 75.9l.6-.1v-.2l-.5-.1-.1 .1v.6l.1 .1 .5-.1M230.2 75.5v.8M230.5 75.5l-.3 .2M230.6 76.4h.9M232.4 75.1h-.4l-.2 .2 .1 .3 .5 .2v.4l-.1 .1-.5-.1M232.9 75.5l.2 .8 .3-.6 .1 .6 .3-.8M234.3 75.1v.1M234.3 75.5v.8"/>
<path d="M234.7 75.5h.5M234.9 75.1v1.1l.3 .1M236.1 75.6l-.4-.1-.2 .2v.4l.2 .2 .4-.1M236.7 75.6l.1-.1 .4 .1v.7M236.7 75.1v1.2M237.7 75.9l.6-.1-.2-.3-.4 .1v.6l.2 .1 .3-.1M239.3 75.6l-.3-.1-.3 .2v.4l.3 .2 .3-.1M239.3 75.1v1.2"/>
</g>
<path d="M130.7 77.5v-2.5h3.4v2.5M132.4 77.9v2.7M139.8 80.6v1.3M139.8 86.8v1.3M219.9 94.3v1.2h1.3l-1.3 1.2-1.3-1.2h1.3M219.9 94.3h.1M219.9 80.6v2.7M219.9 85.4v2.7" fill="none" stroke="#980000" stroke-width=".21"/>
<path d="M218 85.1h3.9M218 83.6h3.9" fill="none" stroke="#980000" stroke-width=".51"/>
<g fill="none" stroke="#0c0c0c" stroke-width=".21">
<path d="M141.4 74.6h.6v-.6h-.6v1.2M142.6 74.5h.6l-.1 .7-.5-.1zM143.6 74.5l.3 .7 .2-.6 .2 .6 .3-.7M145 74.8l.6-.1-.1-.2h-.4l-.1 .1 .1 .6h.4M146.1 74.5v.7M146.4 74.5l-.3 .1M146.6 75.4h.9M147.8 75.2v-1.2l.4 .9 .4-.9v1.2M149.2 74v.1M149.2 74.5v.7M150.3 74v1.2h-.4l-.2-.1v-.5l.2-.1h.4M167.3 74.6h.5l.2-.1-.1-.4-.6-.1v1.2"/>
<path d="M168.4 74.6l.2-.1h.4v.7h-.4l-.2-.1zM169.5 74.5l.3 .7 .2-.6 .2 .6 .3-.7M170.9 74.8l.6-.1-.1-.2h-.4l-.1 .1 .1 .6h.4M172 74.5v.7M172.3 74.5h-.2l-.1 .1M172.5 75.4h.9M173.7 74.6h.6l.1-.5-.7-.1v1.2M175 74.5v.7M175.3 74.5h-.3v.1M175.6 74.8l.6-.1-.1-.2h-.4l-.1 .1 .1 .6h.4M176.7 74.8h1M178.3 74.6h.4"/>
<path d="M178.9 74h-.6v1.2M179.4 74v.1M179.4 74.5v.7M180 74v1.2h.1M180.4 74.5h.5M180.5 74v1.1l.1 .1h.3M181.2 74.8l.6-.1-.1-.2h-.4l-.1 .1 .1 .6h.4M182.3 74.5v.7M182.7 74.5h-.3l-.1 .1"/>
</g>
<g fill="none" stroke="#980000" stroke-width=".25">
<path d="M130.2 77.5h1M130.6 78h3.7M131.9 77.5h1M133.7 77.5h.9M138.8 82h2v4.9h-2z"/>
<circle cx="132.4" cy="76.6" r="2.75"/>
</g>
<path d="M132.4 76l.4 1h-.7z" fill="#980000"/>
<path d="M129.9 75.7h.8M132.4 76l.4 1h-.8z" fill="none" stroke="#980000" stroke-width=".21"/>
<path d="M130.5 75.5h.4v.5h-.4z" fill="#980000"/>
<path d="M130.5 75.5h.4v.5h-.4z" fill="none" stroke="#980000" stroke-width=".21"/>
<path d="M133.9 75.5h.5v.5h-.5z" fill="#980000"/>
<g fill="none" stroke="#980000" stroke-width=".21">
<path d="M127.5 75.7h2.4M132.1 74.6l.7 .4-.7 .4zM132.8 74.6v.8M133.9 75.5h.5v.5h-.5zM137.3 75.7h-4.9v1.8M157.8 77.5v-2.5h3.4v2.5M159.5 77.9v2.7M185.4 75.7h2.4M187.8 75.7h.1M189.4 73l1.8 1.1-2.5 4.3-1.8-1zM190.3 75.7h2.5M132.4 80.6v2.6"/>
<path d="M179.3 80.6v2.7M179.3 85.4v2.7"/>
</g>
<path d="M128.3 74.2h.8l-.5 .4 .5 .3v.3l-.2 .2-.6-.1M135.8 74.3l.6-.1v.3l-.7 .9h.7M132 81.9h-1.2l.4 .3M132 81.6v.6" fill="none" stroke="#bd0000" stroke-width=".21"/>
<path d="M177.2 85.1h4M177.2 83.6h4" fill="none" stroke="#980000" stroke-width=".51"/>
<g fill="none" stroke="#980000" stroke-width=".25">
<path d="M157.3 77.5h1M157.7 78h3.7M159.1 77.5h.9M160.8 77.5h1"/>
<circle cx="159.6" cy="76.6" r="2.75"/>
</g>
<path d="M159.6 76l.3 1h-.7z" fill="#980000"/>
<path d="M159.5 76l.4 1h-.8zM161.2 75.7h.8" fill="none" stroke="#980000" stroke-width=".21"/>
<path d="M161 75.5h.4v.5h-.4z" fill="#980000"/>
<path d="M161 75.5h.4v.5h-.4z" fill="none" stroke="#980000" stroke-width=".21"/>
<path d="M157.6 75.5h.4v.5h-.4z" fill="#980000"/>
<path d="M154.6 75.7h4.9v1.8M157.6 75.5h.4v.5h-.4zM159.1 75l.6-.4v.8zM159.1 74.6v.8M162 75.7h2.5M132.4 95.5v1.2M149.6 80.6v7.5M159.5 80.6v2.6M127.5 110.3h2.7M130.7 108.6h2.4v3.4h-2.4M132.4 101.6v1.3" fill="none" stroke="#980000" stroke-width=".21"/>
<path d="M155.5 74.3l.6-.1 .1 .3-.8 .9h.8M162.8 74.2h.7l-.3 .4 .3 .2v.5h-.7M159.2 81.9h-1.3l.4 .3M159.2 81.6v.6" fill="none" stroke="#bd0000" stroke-width=".21"/>
<path d="M131.5 96.8h1.9v4.9h-1.9zM148.5 83.2h2.5v.4M149.7 83.2l1.3 2.5h-2.5zM130.2 108.5v3.7M130.7 108.1v.9M130.7 109.8v1M130.7 111.5v1" fill="none" stroke="#980000" stroke-width=".25"/>
<path d="M130.9 110.3l1-.4v.7z" fill="#980000"/>
<path d="M130.9 110.3l1-.4v.7zM132.4 107.8v.8" fill="none" stroke="#980000" stroke-width=".21"/>
<circle cx="131.6" cy="110.3" r="2.75" fill="none" stroke="#980000" stroke-width=".25"/>
<path d="M132.2 108.4h.4v.4h-.4z" fill="#980000"/>
<path d="M132.2 108.4h.4v.4h-.4z" fill="none" stroke="#980000" stroke-width=".21"/>
<path d="M132.2 111.7h.4v.5h-.4z" fill="#980000"/>
<g fill="none" stroke="#980000" stroke-width=".21">
<path d="M109 94.3v1.2h1.2l-1.2 1.2-1.3-1.2h1.3M109 94.3h.1M107.7 114v7.4M112.6 114v1.2M122.5 114v2.7M122.5 118.7v2.7M125 110.3h2.5M130.7 110.3h1.7v4.9M132.2 111.7h.4v.5h-.4zM132.4 105.4v2.4M132.8 109.9h.7M133.1 109.9l.4 .6h-.7z"/>
<path d="M112.6 120.1v1.3M132.4 127.5v1.2h1.2l-1.2 1.3-1.2-1.3h1.2M132.4 127.5h.1"/>
</g>
<path d="M125.9 109.1l.3-.4v1.2M125.9 109.9h.7M130.8 107v-.8l.5 .4 .2-.4 .5 .1-.1 .7M132 113.6v.7l-.8-.7-.4 .1 .1 .6" fill="none" stroke="#bd0000" stroke-width=".21"/>
<path d="M120.5 118.4h4M120.5 117h4" fill="none" stroke="#980000" stroke-width=".51"/>
<path d="M107.8 116.5l1.2 2.5h-2.5zM109 116.5h-2.5v.5M111.8 115.2h1.9v4.9h-1.9z" fill="none" stroke="#980000" stroke-width=".25"/>
<g fill="none" stroke="#00a200" stroke-width=".21">
<path d="M94.2 75.7h2.4M104 75.7h23.5M109 75.7v4.9M120.1 75.7v4.9M137.3 75.7h17.3M139.8 75.7v4.9M149.6 75.7v4.9M164.5 75.7h20.9M179.3 75.7v4.9M192.8 75.7h30.8M196.5 75.7v4.9M207.6 75.7v4.9"/>
<path d="M219.9 75.7v4.9M109 88.1v6.2M120.1 88.1v4.9h-11.1M132.4 83.2v12.3M139.8 88.1v4.9M149.6 88.1v4.9M159.5 83.2v9.8h-27.1M179.3 88.1v4.9h40.6M196.5 88.1v4.9M207.6 88.1v4.9M219.9 88.1v6.2M94.2 110.3h2.4"/>
<path d="M104 110.3h21M107.7 110.3v3.7M112.6 110.3v3.7M122.5 110.3v3.7M132.4 115.2v12.3h-24.7v-6.1M132.4 102.9v2.5M112.6 121.4v6.1M122.5 121.4v6.1"/>
</g>
<g fill="none" stroke="#001dcd" stroke-width=".21">
<path d="M142.4 59.7l.5 1.3 .4-1.3M142.5 57.8h.8l-.4 .5h.3l.1 .2-.1 .5h-.5l-.2-.1M142.6 54.5h.5l.3-.3-.1-.3-.7-.1v1.3M142.9 55.7l-.3 .9h.8M143.2 56.2v.8M143.8 56l.2-.2 .3 .1a.66 .66 0 0 1-.2 1.1l-.3-.2zM143.8 58.9v.1M144.2 53.8l-.1 1.1-.3 .2M144.3 58.1l.4-.3v1.2M144.3 59h.8M144.6 55.1l.5-1.3 .4 1.3M144.7 54.6h.6"/>
<path d="M144.8 55.8l.4 1.2 .5-1.2M145.4 59l.4-1.2 .5 1.2M145.5 58.6h.6M145.7 53.8h.8l-.4 .5h.3l.1 .2-.1 .5-.5 .1-.2-.2M146.8 55.8l.4 1.2 .4-1.2M147.3 53.7l-.3 .9h.8M147.4 59.7v1.2l.2 .1M147.6 58.3l.3-.1 .2 .2v.6M147.6 54.2v.9M147.6 58.2v.8M148 59.7v1.3M148.1 58.4l.2-.2 .3 .2v.6"/>
<path d="M148.5 53.7l-.3 .9h.8M148.5 56.3l-.3-.1-.3 .2 .1 .5h.5M148.5 55.8v1.2M148.7 54.2v.9M149.2 58.3h.5v.7M149.3 54.1l.4-.3v1.3M149.3 55.1h.8M149.6 56.3h-.5v.3h.4l.1 .2-.1 .2-.4-.1M149.7 58.5l-.6 .2 .2 .3h.4M150.1 59.9l.4-.2 .2 .4-.7 .9h.7M150.2 58.2l.6 .8M150.8 58.2l-.6 .8"/>
<path d="M151.1 56.3l.2-.1 .3 .1v.7M151.1 56.2v.8M151.6 56.3l.2-.1 .4 .1v.7M152.4 59.7h-.6v.6a.45 .45 0 0 1 .6 0 .45 .45 0 0 1 0 .6h-.6M152.8 56.3l.3-.1 .2 .1v.7M152.9 59.7l.4 1.3 .4-1.3M153.3 56.5l-.5 .1-.1 .2 .2 .2 .4-.1M153.7 56.2l.7 .8M154.4 56.2l-.7 .8M93.3 62.9l.5-.1 .2 .1-.1 .4-.6 .7h.7M93.3 67.1l.3-.3v1.1M93.3 67.9h.7"/>
<path d="M93.4 60.8l.2-.1a.68 .68 0 0 1 .4 .7 .68 .68 0 0 1-.4 .6 .81 .81 0 0 1-.2-1.2zM93.9 64.7h-.6v.6l.5-.1 .2 .2v.3l-.2 .3h-.4l-.1-.2M94.4 60.7h.8l-.8 1.3h.8M94.4 66l.4-1.3 .3 1.3M94.4 65.6h.6M94.5 63.9v.1M94.5 66.8h.4l.2 .1v.8a.35 .35 0 0 1-.4 .2 .35 .35 0 0 1-.3-.4zM95.7 61.4l.6-.1v-.5l-.6-.1v1.3M95.7 62.8h-.6l-.1 .6 .2-.2h.3l.2 .2v.5h-.7M95.7 67.9h.1M96 61.4l.4 .6M96 64l.5-1.2 .4 1.2"/>
<path d="M96.1 66.8h.8l-.4 .4 .3 .1v.6h-.7M96.2 63.6h.6M96.3 65.1h.5M96.5 64.7v1.1l.3 .2M96.9 61.3h.4l.3-.3-.3-.3h-.4v1.3h.5l.3-.4-.4-.3M97.2 65.1v.9M97.6 65.1l-.4 .1v.2M97.8 67.2h-.4v.3h.3l.2 .3-.2 .1h-.3M98 64.7v.1M98 65.1v.9M98.2 60.9l.3-.2 .3 .3v.8l-.3 .2a.72 .72 0 0 1-.3-1.1zM98.3 62.8v1.2"/>
<path d="M98.3 63.4h.6M98.6 65.2l.3-.1 .3 .3v.3l-.3 .3-.3-.1M98.6 65.1v1.3M98.9 62.8v1.2M99.2 67.1h.5M99.3 60.9l.4-.2 .2 .2v.4l-.7 .7h.7M99.4 66.8v1l.3 .1M99.5 63.3l.2-.2 .4 .2-.1 .7-.5-.1zM100.1 66.8h.1M100.1 67.1v.8M100.7 62.8v1.2h.2M100.7 67.3l.2-.2 .3 .2v.6"/>
<path d="M100.7 67.1v.8M101 60.7h-.5v.6h.5a.45 .45 0 0 1 0 .5 .45 .45 0 0 1-.5 .1v-.1M101.2 67.3l.2-.2 .3 .2v.6M101.8 62.8v1.2h-.4l-.2-.6 .3-.3 .3 .1M101.9 60.7a.68 .68 0 0 1 .4 .7 .68 .68 0 0 1-.4 .6l-.3-.2v-.8zM102.2 67.5l.6-.1v-.2l-.4-.1-.2 .2v.5l.2 .1h.4M102.8 61.3h.4M103.3 63.3l.3-.2 .2 .1 .1 .8M103.3 63.1v.9M103.3 67.5h1M103.4 60.7h-.6v1.3M103.9 63.4l.2-.3 .2 .1 .1 .8"/>
<path d="M103.9 61.3h.4M104.5 60.7h-.6v1.3M104.7 67.1h.5M104.9 61.1l.4-.4v1.3M104.9 66.8v1l.3 .1M104.9 62h.7M105 63.2l.4-.1 .1 .3v.6h-.5v-.5h.5M105.5 67.3l.5-.2 .2 .2-.1 .6h-.5zM106 63.1l.6 .9M106.1 61.3h.4M106.6 63.1l-.6 .9M106.7 60.7h-.6v1.3h.6"/>
<path d="M106.7 67.5h.9M108.1 67.1h.4M108.2 66.8v1l.3 .1M108.9 67.1v.8M109.3 67.1l-.4 .2M109.7 66.8h.1M109.7 67.1v.8M110.3 67.2l.3-.1 .3 .2v.6h-.6M110.3 67.1v1.3M142.4 66.9l.5-1.2 .4 1.2M142.6 64.5h.9M142.6 66.6h.6"/>
<path d="M142.8 62.3l-.2-.1v-.4h.6v.4l-.6 .2v.5h.6l.1-.4-.3-.2M143.1 64v1M143.7 65.7v1.1l.2 .1M144 62.3l-.2-.1v-.4h.6v.4l-.6 .2 .1 .5h.4l.2-.1v-.3l-.3-.2M144.1 64.5h1M144.2 60.1v1.1l-.2 .2-.3-.1M144.2 60.2l-.3-.1-.3 .3 .1 .5h.5M144.7 66.2h-.4v.3l.4 .1v.3h-.4M145 62.3l.5-.1v.7M145 62.2v.7M145.2 60.2l-.3-.1-.2 .3 .6 .4-.2 .2-.4-.1M145.3 66.2h.5v.7l-.5-.1z"/>
<path d="M145.5 62.4l.1-.2h.4l.1 .7M145.7 63.9l.4-.2 .2 .3-.7 1h.7M145.8 60.5h1M146.6 61.9l.2-.1 .6 .1v.9l-.2 .1h-.4l-.2-.1zM147.1 63.7a.68 .68 0 0 1 .4 .6 .68 .68 0 0 1-.4 .7l-.3-.3v-.7zM147.2 60.1h.4M147.4 66.9l.5-.1v-.6h-.5v1.1M147.9 63.7l.4 1.3 .4-1.3M147.9 62.3l.5-.1 .1 .7M147.9 61.8v1.1M148 60.3l.2-.2 .3 .1v.8M148.5 66.2v.7"/>
<path d="M148.9 66.2h-.3l-.1 .1M149.1 62.3l.4-.1 .1 .7M149.1 62.2v.7M149.3 66.2h.4l.2 .1v.5l-.2 .1h-.4zM149.6 62.4v-.2h.5v.7M149.9 63.7l.3 1.3 .5-1.3M150.2 66.2l.4 .7 .2-.7M151.3 60.9v.1M151.3 65.7v.1M151.3 66.2v.7M151.6 62.3l.5-.1 .1 .7M151.6 64.1v1.1l-.2 .2-.3-.1"/>
<path d="M151.6 64.2l-.3-.1-.3 .3v.3l.3 .3 .3-.1M151.6 62.2v.7M152.2 62.4v-.2h.4l.1 .7M152.4 65.7v1.2h-.4l-.2-.1v-.5l.2-.1h.4M152.6 64.2h-.4v.3l.3 .1 .2 .2-.2 .2-.3-.1M152.9 66.5l.6-.1v-.2h-.5l-.1 .1 .1 .6h.5M153.3 62.2h.4l.1 .2v.5h-.5l-.1-.2 .2-.2 .4-.1M154.1 64.3l.2-.2 .3 .1v.8M154.1 64.1v.9M154.3 62.2l.6 .7M154.5 66.2h-.4l-.1 .1 .5 .3v.3h-.5M154.6 64.3l.3-.2 .3 .2v.7"/>
<path d="M154.9 62.2l-.6 .7M155.1 60.3l.1-.2 .4 .2v.7M155.1 60.1v.9M155.6 60.3l.1-.2 .4 .2v.7M155.8 64.2l.4-.1 .1 .2v.7M156 66.2v.7M156.3 64.5h-.4l-.2 .1 .2 .4 .4-.1M156.4 66.2l-.4 .1M156.7 60.2h.5v.8M156.8 66.5l.5-.1v-.2h-.5v.7h.5M156.8 64.1l.6 .9M157.2 60.5h-.4l-.2 .2 .2 .3 .4-.1"/>
<path d="M157.4 64.1l-.6 .9M157.7 60.1l.6 .9M157.8 66.2l.2 .7 .3-.7M158.3 60.1l-.6 .9M158.7 66.5l.6-.1v-.2h-.5l-.1 .1 .1 .6h.5M159.8 66.2v.7M160.2 66.2l-.4 .1M161 66.2h-.4v.1l.4 .3v.3h-.4M161.6 66.5l.6-.1-.1-.2h-.5v.7h.5M163.6 66.9h.4l.2-.1v-.5l-.2-.1h-.4v1.1M164.7 66.2v.7M165.1 66.2h-.3l-.1 .1"/>
<path d="M165.4 66.3l.2-.1h.4v.7h-.4l-.2-.1zM166.4 66.2h.5M166.6 65.7v1.1l.1 .1h.2M167.3 66.5l.5-.1v-.2h-.5v.1v.6h.5M168.9 66.2h-.5l-.1 .1v.5l.1 .1h.5M169.2 66.2h.5M169.5 65.7v1.2h.2M170.1 65.7v.1M170.1 66.2v.7M170.7 66.2h.4l.2 .1v.5l-.2 .1h-.4zM171.8 66.2h.4l.1 .7M171.8 66.2v.7"/>
<path d="M66 82.9l.4 1.2 .4-1.2M66 86.1l.4-1.2 .4 1.2M66 92.8l.4 1.2 .4-1.2M66.2 95.1l.3-.3v1.2M66.2 96.9l.6-.1v.3l-.7 .9h.7M66.2 98.9l.4-.1 .2 .3-.7 .9h.7M66.2 85.7h.6M66.2 96h.6M66.2 88.9v1.1h.2M66.6 87.3l-.3-.1-.1 .3 .5 .4-.2 .2-.3-.1M66.8 89.4l.5-.1v.7h-.4l-.1-.1zM67.2 83.5l.2-.2h.4v.7h-.5z"/>
<path d="M67.2 87.7l.6-.1-.1-.3h-.5v.7h.5M67.3 85.3v.7l.1 .1 .4-.1M67.3 93.3h.5v.7h-.5v-.4l.5-.1M67.5 95.3l-.2-.1v-.3l.2-.1 .4 .1v.4h-.4l-.2 .2v.4l.2 .1h.3l.2-.2-.1-.4-.1-.1M67.6 96.7l-.3 .9h.8M67.8 85.3v.8M67.9 89.3h.5l.1 .1v.6h-.6v-.3l.6-.2M67.9 98.8h-.6v.6l.6-.1v.6l-.4 .1-.2-.1M67.9 97.2v.8M68.2 87.7l.6-.1-.2-.4-.4 .2v.5l.2 .2 .3-.1M68.2 85.3h.5M68.4 82.9v1l.1 .2"/>
<path d="M68.4 84.9v1.1l.3 .1M68.4 94.8l.4 1.2 .4-1.2M68.4 96.8l.4 1.2 .4-1.2M68.4 93.3v.7M68.7 93.3l-.3 .1M68.8 98.8a.68 .68 0 0 1 .4 .6 .68 .68 0 0 1-.4 .6l-.3-.2v-.8zM68.9 83.3h.4M69 82.9v1l.3 .2M69.1 85.4h.5v.6l-.1 .1-.5-.2zM69.1 92.8v.1M69.1 93.3v.7M69.6 88.9v1.1h-.5v-.7h.5"/>
<path d="M69.6 99.7h.6M69.7 83.3h.5v.8M70.1 93.3h-.4l-.1 .1 .1 .2 .4 .1v.3h-.5M70.2 83.6l-.5 .1-.1 .2 .3 .2 .3-.1M70.2 85.4l.4-.1 .1 .2v.6M70.2 85.3v.8M70.2 89.6h1M70.6 95.3l.3-.1 .2 .2v.6M70.6 97.3l.4-.1 .1 .8M70.6 93.3h.4M70.6 95.2v.8M70.6 97.2v.8"/>
<path d="M70.6 87.3h-.4v.3l.4 .1 .1 .2-.1 .2-.4-.1M70.7 85.5l.2-.2 .3 .2v.6M70.7 92.8v1l.3 .2M70.8 99.9v.1M71.1 95.4l.1-.2 .4 .1v.7M71.1 97.4l.1-.2h.4v.8M71.2 87.3h.5l.1 .5a.36 .36 0 0 1-.6 .2M71.2 87.2v1.3M71.4 83.3l-.1 1.1h-.5M71.4 83.3h-.4l-.2 .1v.6h.6M71.4 93.3h.6l-.1 .7-.5-.1zM71.8 85.4h.5v.7h-.3l-.3-.2z"/>
<path d="M71.9 83.7l.6-.1-.2-.3h-.3l-.1 .6 .2 .2 .3-.1M72.2 95.3l.3-.1 .3 .2v.6M72.2 97.2h.5l.1 .2v.6h-.6v-.4l.6-.1M72.3 88.9v1.1h-.6v-.7h.6M72.3 86.8v.2M72.3 87.2v.9M72.5 93.3v.7M72.8 95.5l-.6 .1v.4h.6M72.8 85.3h.5M72.9 89.3v.7h.5M72.9 84.9v1.1l.4 .1M72.9 93.3l-.4 .1"/>
<path d="M72.9 86.8v1.3M73.1 87.6l.3 .5M73.2 95.2l.7 .8M73.2 97.2l.7 .8M73.4 89.3v.7M73.4 87.2l-.5 .6M73.7 84.9v.1M73.7 85.3v.8M73.9 87.7l.6-.1v-.3l-.5-.1-.1 .2v.5l.1 .2 .5-.1M73.9 95.2l-.7 .8M73.9 97.2l-.7 .8M74 89.4l.5-.1v.7"/>
<path d="M74 89.3v.7M74.1 85.3l.4 .8 .2-.8M74.4 83.3h-.4l-.1 .2 .1 .2h.3l.2 .2-.2 .2-.4-.1M74.5 89.4v-.1h.5l.1 .7M75 83.3h.3l.3 .2-.1 .5h-.5M75 83.3v1.2M75.1 85.7l.6-.2-.1-.2-.5 .2v.5l.2 .1h.3M75.1 95.2l.3 .8 .2-.5 .2 .5 .3-.8M75.4 87.3l-.3-.1-.1 .3 .5 .4-.2 .2-.3-.1M75.6 90h.6l-.1-.7h-.5v1.2M75.8 97.2l-.6 .1v.6l.6 .1M76.1 82.9v.1"/>
<path d="M76.1 83.3v.8M76.3 96.8v1l.2 .2M76.6 95.3l.3-.1 .3 .3v.3l-.3 .2-.4-.2zM76.7 82.9v1.2M76.7 90v.3M76.7 83.7l.5 .4M76.9 87.2l1 .4-1 .4M76.9 97.2h.5l.1 .2v.6h-.6v-.4l.6-.1M77.2 85.2l.3-.3v1.2M77.2 83.3l-.5 .5M77.2 86.1h.6M77.6 83.7l.6-.1-.2-.3h-.3l-.1 .6 .2 .2 .3-.1"/>
<path d="M77.7 95.2v.8M78 95.2l-.3 .1v.2M78.1 97.3l.4-.1 .1 .8M78.1 97.2v.8M78.2 89.7l.6-.2-.1-.2h-.4l-.1 .1 .1 .6h.4M78.3 85l.5-.1 .2 .2-.7 1h.7M78.4 94.8v1.2M78.5 95.5l.4 .5M78.6 97.4l.1-.2h.3l.1 .8M78.9 95.2l-.5 .5M79 86.8h-.2l-.4 .4 .1 .8a.36 .36 0 0 0 .6-.2v-.2a.35 .35 0 0 0-.3-.3 .35 .35 0 0 0-.4 .3M79.1 89.3h.5"/>
<path d="M79.3 88.9v1l.1 .1h.2M79.4 84.9l.4 1.2 .4-1.2M79.5 94.8v.1M79.5 95.2v.8M79.6 83.3h.4l.2 .1v.6h-.6M79.6 83.3v1.2M79.7 98h.5v-.8h-.5v1.2M79.9 86.8a.71 .71 0 0 1 .4 .6 .71 .71 0 0 1-.3 .7l-.4-.3v-.7zM80 95.3l.4-.1 .2 .2v.6M80 95.2v.8M80.6 89.3l-.6 .1v.6h.6M80.6 86.8l.5 1.3 .4-1.3"/>
<path d="M80.8 96.8v.1M80.8 83.3v.8M80.8 97.2v.8M81.1 90h.1M81.1 83.3l-.3 .2M81.4 97.3l.5-.1v.8M81.4 97.2v.8M81.6 83.3h.3l.2 .1v.6h-.5zM81.7 95.2v1l-.3 .3-.3-.1M81.7 95.3l-.4-.1-.2 .3v.5h.6M81.9 85.4l-.2-.1-.2 .2 .4 .2 .1 .3-.2 .1h-.3M82.3 96l-.1 .2"/>
<path d="M82.5 85.3v.7l.2 .1 .4-.1M82.5 83.3h.4M82.7 82.9v1.1l.2 .1M83.1 98l-.6-.1 .1-.7h.5v1l-.3 .2-.3-.1M83.1 85.3v.8M83.3 83.7l.6-.1v-.3h-.5l-.1 .2v.4l.1 .2 .5-.1M83.3 87.3l-.3-.1-.2 .3v.5h.5M83.3 86.8v1.3M83.6 85.4h.6v.6l-.2 .1h-.4M83.6 85.3v1.2M83.9 87.2v.7l.2 .2 .3-.1M84.4 87.2v.9"/>
<path d="M84.8 85.4l.3-.1 .3 .2v.4l-.3 .2h-.3M84.8 85.3v1.2M85 83.3h-.4l-.2 .1v.6h.6M85 87.7l.6-.1v-.3l-.4-.1-.2 .2v.5l.2 .2 .4-.1M85.3 83.3h.4M85.5 82.9v1l.2 .2M85.9 84.9v1.1l.2 .1M86.1 82.9v.1M86.1 83.3v.8M86.4 85.3l.3 .8M86.7 83.4l.2-.1h.3v.7h-.5zM86.9 87.2h.4"/>
<path d="M87 85.3l-.3 .8-.3 .4M87.1 86.8v1.2l.2 .1M87.7 87.5l.2-.3 .4 .1v.7h-.5zM87.8 83.4l.2-.1h.3l.1 .8M87.8 83.3v.8M88.9 85.4a.36 .36 0 0 0-.6 .1l.1 .6h.5M89 84v.1M89.4 85.4h.6v.7M90 85.5l-.6 .3 .2 .3h.4M90.5 85.4l.4-.1 .2 .2v.6M90.5 85.3v.8M69.5 100l.5-1.2 .4 1.2"/>
</g>
<g fill="#00a200">
<circle cx="109" cy="93" r=".47"/>
<circle cx="107.7" cy="110.3" r=".47"/>
<circle cx="109" cy="75.7" r=".47"/>
<circle cx="120.1" cy="75.7" r=".47"/>
<circle cx="207.6" cy="93" r=".47"/>
<circle cx="196.5" cy="93" r=".47"/>
<circle cx="207.6" cy="75.7" r=".47"/>
<circle cx="219.9" cy="75.7" r=".47"/>
<circle cx="219.9" cy="93" r=".47"/>
<circle cx="179.3" cy="75.7" r=".47"/>
<circle cx="149.6" cy="93" r=".47"/>
<circle cx="139.8" cy="75.7" r=".47"/>
<circle cx="149.6" cy="75.7" r=".47"/>
<circle cx="196.5" cy="75.7" r=".47"/>
<circle cx="122.5" cy="110.3" r=".47"/>
<circle cx="122.5" cy="127.5" r=".47"/>
<circle cx="132.4" cy="127.5" r=".47"/>
<circle cx="112.6" cy="110.3" r=".47"/>
<circle cx="112.6" cy="127.5" r=".47"/>
<circle cx="139.8" cy="93" r=".47"/>
<circle cx="132.4" cy="93" r=".47"/>
</g>
<g fill="none" stroke="#aaa" stroke-width=".21">
<path d="M105.3 83.9l-.4-.2-.4 .3 .1 .8 .3 .2 .4-.2M105.7 84l.3-.3v1.3M105.7 85h.7M106.4 83.9l-.2-.2a.64 .64 0 0 0-.6 .6 .64 .64 0 0 0 .6 .7l.2-.2M106.9 84l.3-.3v1.3M106.9 85h.7M107.6 83.7h-.6l-.1 .6 .6-.1 .1 .6-.2 .2h-.3l-.2-.2M108.1 83.9l.4-.2 .2 .3-.7 1h.7M108.7 83.7h-.5l-.1 .6 .6-.1v.7l-.5 .1-.1-.2M109.3 84l.3-.3v1.3M109.3 85h.6M109.4 84.2l-.1-.1v-.2l.1-.2 .4 .1v.4h-.4l-.1 .2v.4l.1 .2h.3l.2-.3v-.3l-.2-.2"/>
<path d="M110.7 83.7l-.3 .8h.8M111 84.1v.9M111 83.7h-.6v.6l.6-.1 .1 .5-.2 .3-.5-.2M111.5 83.7h.8l-.5 1.3M111.8 84.2l-.3-.3 .3-.2h.3l.2 .3-.8 .4v.3l.3 .3h.3l.2-.3v-.3l-.2-.2M113.3 83.7l-.4 .2-.2 .8 .3 .3h.2l.3-.3-.2-.5h-.4l-.2 .2"/>
</g>
<g fill="none" stroke="#970091" stroke-width=".21">
<path d="M113.7 86.1h-.5l-.1 .6h.6v.6h-.6M114.3 86.3l.4-.2 .2 .3v.8l-.2 .2-.4-.1zM115.4 86.1l.3 1.3 .4-1.3M172.2 86.3l.2-.2h.4l.1 .2v.4l-.7 .7h.7M174.1 86.1h-.6l-.1 .6h.7v.6h-.7M174.5 86.1l.4 1.3 .4-1.3M189.5 86.3l.2-.2h.3l.2 .2v.4l-.8 .7h.8M191.3 86.1h-.5l-.1 .6h.6v.6h-.6M191.7 86.1l.4 1.3 .5-1.3M200.6 86.3l.2-.2h.3l.2 .2v.4l-.8 .7h.8M202.5 86.1h-.6l-.1 .6h.7v.6h-.7M202.8 86.1l.4 1.3 .5-1.3"/>
<path d="M213.6 86.1h-.6v.6h.6l.1 .5-.3 .2-.4-.1M214.4 86.1a.68 .68 0 0 1 .4 .7 .68 .68 0 0 1-.4 .6l-.2-.2v-.8zM215.2 86.1l.4 1.3 .4-1.3M102 118.6l.3-.4v1.2M102 119.4h.7M103.4 118.7l-.2-.2 .2-.3 .4 .1v.4a.51 .51 0 0 0-.5 .2 .51 .51 0 0 0-.1 .5l.6-.1v-.4l-.1-.2M104.3 118.2l.3 1.2 .4-1.2M127.2 119.4h-.6l-.1 .6a.45 .45 0 0 1 .6 0 .45 .45 0 0 1 .1 .6h-.7M127.9 119.5a.6 .6 0 0 1 .7 .5 .6 .6 0 0 1-.5 .7l-.4-.5zM128.8 119.4l.4 1.3 .5-1.3"/>
</g>
<g fill="none" stroke="#007170" stroke-width=".21">
<path d="M128.7 72h.6l.1-.5-.7-.1v1.2M130.3 71.4v.9l-.1 .2-.4 .1M130.7 72.6l.4-1.2 .4 1.2M130.8 69.1l.3-.2h.3l.2 .2v.9l-.2 .1-.6-.1zM130.8 72.3h.6M131 69.9h.3l.4 .3M131.9 71.4h.7l-.4 .4 .4 .3-.1 .4h-.6M132.1 69.3l.4-.4v1.2M132.1 70.1h.7M133.3 69.3l.3-.4v1.2M133.3 70.1h.7M133.4 71.3l-.4 .9h.8"/>
<path d="M133.6 71.7v.9M134.6 71.3l-.4 .9h.8M134.8 71.7v.9M135.4 71.7l.4-.3v1.2M135.4 72.6h.7M155.8 72h.6l.2-.4-.2-.2h-.6v1.2M157.4 71.4v.9l-.1 .2-.4 .1M157.9 72.6l.4-1.2 .4 1.2M157.9 72.3h.6M158.1 69l.3-.1a.73 .73 0 0 1 0 1.2h-.2a.86 .86 0 0 1-.1-1.1zM158.2 69.9l.6 .3M159 71.4h.7l-.4 .4 .4 .3-.1 .4h-.6"/>
<path d="M159.2 69.3l.3-.4v1.2M159.2 70.1h.7M160.4 69l.2-.1h.3l.2 .1v.5l-.8 .6h.8M160.5 71.3l-.3 .9h.8M160.7 71.7v.9M161.7 71.3l-.4 .9h.8M161.9 71.7v.9M162.5 71.7l.4-.3v1.2M162.5 72.6h.8M182.5 70.5h.2l.1-.4v1.3M182.5 71.4h.7M183.7 70.2h.7v.4l-.8 .8h.8"/>
<path d="M184.9 70.2l.4-.1a.78 .78 0 0 1-.2 1.3l-.2-.5zM186 70.8h.6l.2-.2-.1-.4-.7-.1v1.3M186.4 70.8l.4 .6M187.6 68.3h.4M188.1 70.8l-.2-.2-.3 .2 .1 .4h.4M188.1 70.6l.1 .6h.1v-.5a.58 .58 0 0 0-.8-.2 .58 .58 0 0 0-.1 .9 .58 .58 0 0 0 .9 0M188.2 67.7h-.6v1.2M188.7 68.3h.4l.3-.3-.1-.2-.6-.1v1.2h.6l.1-.5-.3-.1M188.8 70.5l.4-.4v1.3M188.8 71.4h.7M189.9 68l.3-.3v1.2M189.9 68.9h.6"/>
<path d="M190.1 70.2l.4-.1 .2 .3v.8l-.2 .2-.4-.2zM191.3 70.2l.3-.1a.78 .78 0 0 1-.1 1.3l-.3-.2zM192.4 71.4v-1.3l.4 .9 .4-.9v1.3M193.8 70.1v1.3M193.8 70.7h.7M194.5 70.1v1.3M195 70.6h.6l-.6 .8h.6M108.7 97.3v-.1a.64 .64 0 0 0-.6 .6 .64 .64 0 0 0 .5 .7l.2-.1v-.4h-.2M110.1 97.2v1.3l-.8-1.3v1.3M110.7 97.2a.64 .64 0 0 1 .7 .7 .64 .64 0 0 1-.7 .6zM111.9 84l.3-.3v1.3M111.9 85h.7"/>
<path d="M113.1 83.9l.2-.2a.68 .68 0 0 1 .5 .6 .68 .68 0 0 1-.5 .7l-.2-.3zM113.7 81.3l-.3-.1a.65 .65 0 0 0-.5 .7 .65 .65 0 0 0 .5 .6l.3-.2M114.2 81.6l.3-.4v1.3M114.2 82.5h.6M114.3 83.8a.61 .61 0 0 1 .7 .4 .61 .61 0 0 1-.4 .8 .71 .71 0 0 1-.3-1.2zM115.3 81.2h.8l-.6 1.3M115.4 84.2l.4-.1 .1 .2v.7M115.4 84.1v.9M128.1 99.7h-1.3l.3 .4M128.1 98.6h-1.3l.3 .2v.1M128.1 97.1v.7l-.8-.7h-.4v.6M128.1 98.2v.7"/>
<path d="M128.1 99.4v.7M129.2 99l.3-.2h.8l.2 .2a.68 .68 0 0 1-.6 .4 .68 .68 0 0 1-.7-.4zM129.2 98.2h1.3M129.7 97.7l.5 .5M130.5 99.9v.7M130.5 97.7l-.5 .4M142.6 85.3l.4-.3v1.1M142.6 83.1h.6l.2-.4-.2-.2h-.6v1.2M142.6 86.1h.7M143 83.1l.4 .6M143.8 82.8l.3-.3v1.2M143.8 83.7h.8"/>
<path d="M143.9 85h.5l.1 .7-.2 .4h-.3l-.2-.1zM145 82.8l.3-.3v1.2M145 83.7h.7M145.2 85h.3a.94 .94 0 0 1 0 1.1h-.3a.78 .78 0 0 1 0-1.1zM146.1 82.5h.7l-.3 .4 .3 .2v.5h-.7M146.2 85v1.1M146.3 85.7l.4 .4M146.7 85.4l-.5 .4M152.4 85.3l.4-.3v1.1M152.4 86.1h.8M152.5 82.5h.4l.3 .3v.6l-.3 .3h-.4zM153.6 82.5h.8l-.4 .4 .4 .3-.1 .5-.7-.1"/>
<path d="M153.9 85.5l-.3-.3 .2-.2h.4l.1 .4a.48 .48 0 0 0-.5 .2 .48 .48 0 0 0 0 .5h.5v-.6h-.2M154.7 85l.4 1.1 .4-1.1M154.9 82.6l.6-.1 .1 .3-.8 .9h.8M172.2 84l.4-.3v1.3M172.2 85h.7M172.8 81.3l-.2-.1a.65 .65 0 0 0-.5 .7 .65 .65 0 0 0 .5 .6l.2-.2M173.3 81.6l.4-.4v1.3M173.3 82.5h.7M173.5 83.8a.61 .61 0 0 1 .7 .4 .61 .61 0 0 1-.4 .8 .71 .71 0 0 1-.3-1.2zM174.6 84.1v.7l.2 .2 .3-.2M175.1 84.1v.9M175.2 81.7l-.1 .2a.42 .42 0 0 1-.5 0 .42 .42 0 0 1-.1-.6l.5-.1a.72 .72 0 0 1 .2 .8 .72 .72 0 0 1-.6 .5"/>
<path d="M189.4 84h.2l.2-.3v1.3M189.4 85h.8M190.1 81.3l-.2-.1a.65 .65 0 0 0-.6 .7 .65 .65 0 0 0 .6 .6l.2-.2M190.5 81.3l.5-.1 .3 .3-.8 1h.8M190.8 83.8l.2-.1 .3 .2v.8l-.3 .3a.71 .71 0 0 1-.2-1.2zM191.9 84.1v.8l.3 .1 .2-.2M191.9 81.3a.61 .61 0 0 1 .6 .4 .61 .61 0 0 1-.2 .7 .6 .6 0 0 1-.6-.4 .6 .6 0 0 1 .2-.7zM192.4 84.1v.9M200.5 84l.5-.3v1.3M200.5 85h.8M201.2 81.3l-.2-.1a.65 .65 0 0 0-.6 .7 .65 .65 0 0 0 .6 .6l.2-.2M201.7 81.3l.4-.1 .3 .4-.8 .9h.8"/>
<path d="M201.9 83.8l.2-.1a.68 .68 0 0 1 .4 .6 .68 .68 0 0 1-.4 .7 .81 .81 0 0 1-.2-1.2zM202.8 81.6l.4-.4v1.3M202.8 82.5h.8M203 84.1v.8l.3 .1 .2-.2M203.5 84.1v.9M211.7 84l.3-.3v1.3M211.7 85h.7M213.1 83.7l.5 .2v.8l-.3 .3a.75 .75 0 0 1-.2-1.3zM213.6 81.3l-.5-.1-.3 .4v.6l.2 .2 .3 .1 .3-.2M214 81.3h.7v.4l-.8 .8h.8M214.3 83.7a.68 .68 0 0 1 .5 .6 .68 .68 0 0 1-.5 .7l-.2-.6 .1-.5zM215.2 81.3h.7v.4l-.8 .8h.8"/>
<path d="M215.3 84.2l.4-.1 .2 .2v.7M215.3 84.1v.9M219.7 97.3l-.3-.1-.3 .4v.6l.1 .2h.6v-.4h-.2M221 97.2v1.3l-.7-1.3v1.3M221.6 97.2h.3l.4 .4v.6l-.4 .3h-.3zM98.3 105.3h.5l.1-.5-.6-.1v1.2M98.5 105.3l.4 .6M98.8 107.1h.8l-.4 .5 .4 .2-.1 .5-.7-.1M99.4 105l.4-.3v1.2M99.4 105.9h.7M100.2 107.2l.3-.1a.84 .84 0 0 1 .1 1.2h-.3l-.2-.1zM100.6 105l.4-.3v1.2"/>
<path d="M100.6 105.9h.7M101.3 107.1v1.2M101.4 107.9l.4 .4M101.8 107.6l-.5 .4M101.9 104.8h.5l.1 .6-.2 .5h-.3l-.2-.2zM101.9 115.8a.66 .66 0 0 1 .6 .4 .66 .66 0 0 1-.2 .8h-.4zM103 115.8h.8l-.5 .4 .5 .3-.1 .5-.7-.1M104.3 116.1l.3-.3v1.2M104.3 117h.6M114.3 116.4h.5l.1-.5-.6-.1v1.2M114.6 116.4l.3 .6M115.4 116.1l.4-.3v1.2"/>
<path d="M115.4 117h.7M115.6 118.6l.3-.4v1.2M115.6 119.4h.7M116.6 116.1l.4-.3v1.2M116.6 117h.7M116.9 118.3l.3-.1 .3 .3v.7l-.2 .2-.4-.1zM117.8 116.1l.3-.3v1.2M117.8 117h.7M118 118.2v1.2M118.1 119l.4 .4M118.5 118.7l-.5 .4M126.5 117.4l.5-.4v1.2"/>
<path d="M126.5 118.2h.8M127.3 114.7l-.2-.2a.64 .64 0 0 0-.6 .6 .64 .64 0 0 0 .6 .7l.2-.2M127.5 101.2v-.4l-.3-.3-.3 .1-.1 .6h1.3M127.8 114.8l.3-.3v1.3M127.8 115.8h.7M127.9 117a.6 .6 0 0 1 .7 .6 .6 .6 0 0 1-.5 .6l-.4-.5zM128.1 100.5l-.6 .5M129.1 117h.1a.68 .68 0 0 1 .5 .6 .68 .68 0 0 1-.5 .6l-.3-.5zM129.2 115h-.1a.34 .34 0 0 1 .1-.5 .34 .34 0 0 1 .5 .2l-.1 .3h-.4l-.2 .3 .1 .4 .1 .1 .5-.2v-.4l-.3-.2M130.2 117.6l.1-.2 .4 .2v.6M130.2 117.4v.8M130.5 100.3h-1.3l.4 .2v.1"/>
<path d="M136.4 110.9h.6l.1 .5-.7 .7h.7M136.6 108.4l.3-.1a.73 .73 0 0 1 0 1.3h-.2a.86 .86 0 0 1-.1-1.2zM136.7 109.3h.2l.4 .4M137.7 108.7l.3-.4v1.3M137.7 109.6h.8M138.4 110.9v1.2l-.7-1.2v1.2M138.8 110.9h.9l-.6 1.2M139 108.5l.3-.2 .3 .3v.7l-.3 .3-.3-.1zM140.2 110.9h.4l.2 .1v.8a.35 .35 0 0 1-.5 .3 .35 .35 0 0 1-.2-.5zM141.3 110.9h.5a.86 .86 0 0 1-.1 1.2l-.4-.1zM142.4 110.9h.6l.1 .3-.7 .9h.7M132.2 130.6h-.5l-.2 .2v.7a.55 .55 0 0 0 .8 .2v-.4h-.3"/>
<path d="M133.5 130.6v1.2l-.7-1.2v1.2M134.1 130.6h.5a.66 .66 0 0 1 .2 .8 .66 .66 0 0 1-.7 .4z"/>
</g>
<g fill="none" stroke="#a2a2a2" stroke-width=".21">
<path d="M93.8 71.4h.1a.62 .62 0 0 1 .5 .6 .62 .62 0 0 1-.5 .6 .84 .84 0 0 1-.1-1.2zM94.7 71.4h.8l-.8 1.2h.8M96 72h.6v-.6h-.6v1.2M96.3 72l.4 .6M97.2 72h.5l.2-.4-.2-.2h-.5v1.2h.5l.3-.4-.3-.2M98.5 71.5l.4-.1 .2 .2v.7a.35 .35 0 0 1-.4 .3 .35 .35 0 0 1-.3-.4zM99.5 69.5h.4M99.6 71.5l.6-.1 .1 .5-.8 .7h.8M100.1 68.9h-.6v1.2M100.5 69.3l.4-.4v1.2M100.5 70.1h.7M101.4 71.4h-.5l-.1 .6 .2-.2 .4 .1v.6h-.6"/>
<path d="M102 71.6l.1-.2h.4a.86 .86 0 0 1-.1 1.2l-.4-.3zM103.2 72h.4M103.8 71.4h-.6v1.2M104.3 72h.4M104.9 71.4h-.6v1.2M105.3 71.7l.3-.3v1.2M105.3 72.6h.7M106.5 72h.4M107.1 71.4h-.6v1.2h.6M93.1 83.7v-1.2l.4 .8 .3-.8v1.2M94.4 82.7l.2-.2h.4l.2 .2v.8l-.2 .2h-.4l-.2-.2zM95.6 82.5l.4 1.2 .4-1.2"/>
<path d="M96.8 83.3h.9M98.3 82.7l.2-.2 .3 .1a.87 .87 0 0 1 0 1.1h-.3a.82 .82 0 0 1-.2-1zM99.4 82.5h.8l-.5 1.2M100.7 82.5h.4l.3 .3v.6l-.3 .3h-.4zM101.9 82.6l.6-.1 .1 .3-.8 .9h.8M103.1 82.6l.6-.1 .1 .3-.8 .9h.8M103.2 85.5h.6v-.5h-.6v1.1M103.5 85.5l.4 .6M104.3 82.7l.1-.2 .4 .1a.87 .87 0 0 1 0 1.1l-.5-.1zM104.3 85l.4 1.1 .4-1.1M105.4 85.3l.4-.3v1.1M105.4 82.5v1.2"/>
<path d="M105.4 86.1h.7M105.6 83l.5 .7M106.1 82.5l-.7 .7"/>
</g>
<path d="M96.9 74.1l7 3.4M103.9 74.1l-7 3.4M106.1 80.6l5.2 7.3M111.3 80.6l-5.2 7.3" fill="none" stroke="#e00" stroke-width=".42"/>
</svg>
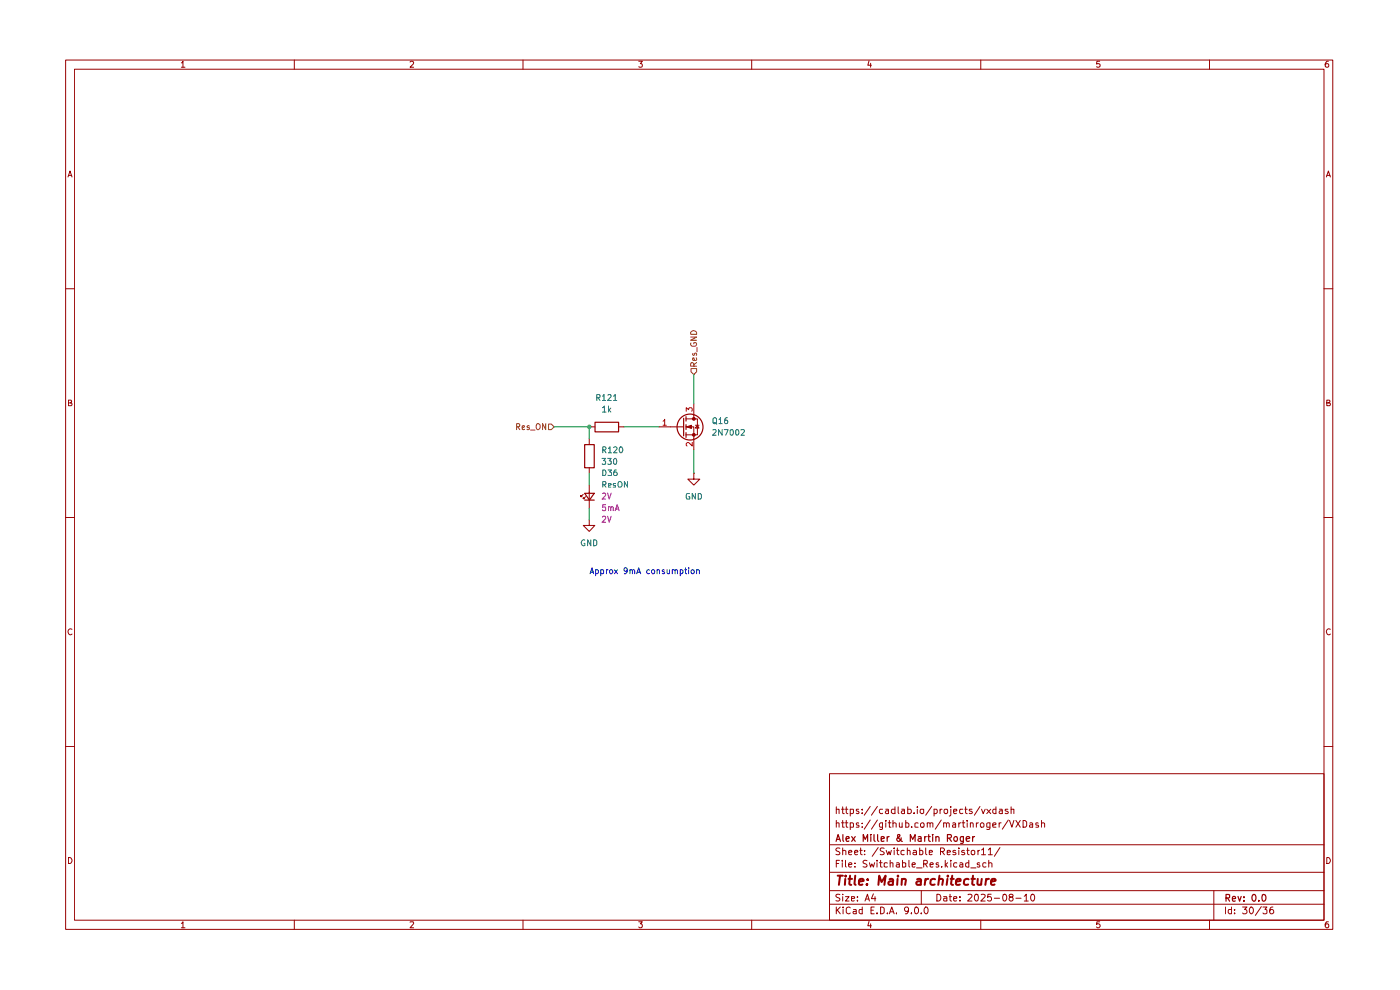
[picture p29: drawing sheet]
<svg xmlns="http://www.w3.org/2000/svg" width="297mm" height="210mm" viewBox="0 0 297 210" stroke-linecap="round" stroke-linejoin="round" font-family="sans-serif">
<g fill="none" stroke="#980000" stroke-width=".21">
<path d="M13.9 12.7h268.8v184.4h-268.8zM15.8 14.7h265.1v180.5h-265.1zM38.5 13.3h.1l.2-.3v1.3M38.5 14.3h.7M62.4 12.7v2M87 13.2l.5-.2 .3 .2-.1 .4-.7 .7h.8M111 12.7v2M135.5 13h.8l-.5 .5 .4 .1v.6h-.7M159.5 12.7v2M184.4 12.9l-.3 .9h.8M184.7 13.4v.9M208.1 12.7v2"/>
<path d="M233.3 13h-.6l-.1 .6h.7v.6h-.7M256.6 12.7v2M281.8 13a.71 .71 0 0 0-.7 .5 .71 .71 0 0 0 .3 .8l.4-.1v-.6l-.4-.1-.3 .3M14.4 37.5l.5-1.2 .4 1.2M14.5 37.2h.7M281.4 37.5l.4-1.2 .4 1.2M281.5 37.2h.6M13.9 61.3h1.9M280.9 61.3h1.8M14.5 85.5h.4l.3-.3-.2-.3h-.5v1.2h.6l.2-.5-.4-.1M281.5 85.5h.4l.2-.3-.1-.3h-.5v1.2h.6l.1-.5-.3-.1M13.9 109.8h1.9"/>
<path d="M123.7 104.9l-.5 .5v-.3v.3h.3M124.2 105.4l-.5 .4v-.2v.2h.3M125 110.3v1.2h1.2l-1.2 1.2-1.3-1.2h1.3M125 110.3h.1M125 102.9v4.9M280.9 109.8h1.8M15.3 133.5a.59 .59 0 0 0-.9 .5 .59 .59 0 0 0 .8 .6l.1-.1M282.2 133.5a.59 .59 0 0 0-.8 .5 .59 .59 0 0 0 .7 .6l.1-.1M13.9 158.4h1.9M280.9 158.4h1.8M176 164.1h104.9v31.1h-104.9zM176 179.2h104.9"/>
<path d="M177.4 174.7l.2-.2 .4 .1v.9M177.4 171.7h.6v.9M177.4 171.1v1.5M177.4 174v1.5M178.2 180l-.6-.1-.3 .2 .1 .4 .8 .4-.1 .3h-.8M178.5 174.5h.6M178.5 171.7h.6M178.8 174v1.5h.3M178.8 171.1v1.4l.3 .1M178.8 179.9v1.4M179.4 174.5h.5M179.4 171.7h.5"/>
<path d="M179.5 174v1.3l.1 .2h.3M179.5 171.1v1.3l.4 .2M180.4 174.6l.4-.1 .3 .2v.7l-.7 .1M180.4 172.5l.4 .1 .3-.2-.1-.7h-.6v1.4M180.4 174.5v1.5M182.2 174.6l-.4-.1-.2 .2 .2 .3h.4v.5h-.6M182.2 171.7h-.5l-.1 .2 .5 .2 .1 .3-.1 .2-.5-.1M182.6 179.9v1.2l.3 .2M182.9 175.4v.1M182.9 174.6v.1M182.9 172.4v.2M182.9 171.7v.1"/>
<path d="M184.6 173.9l-1.3 2M184.6 171.1l-1.3 1.8M186.1 173.9l-1.2 2M186.1 171.1l-1.2 1.8M186.3 179.8l-1.3 1.8M187.2 174.5v1.2a.36 .36 0 0 1-.6 .2M187.2 174.6l-.4-.1-.2 .3v.6l.6 .1M187.2 171.7h-.5l-.1 .2v.4l.2 .3 .4-.1M187.6 180l-.6-.1-.3 .2 .1 .4 .8 .4-.1 .3h-.8M187.9 174v.2M187.9 171.7h.5l.1 .9M187.9 174.5v1"/>
<path d="M188.4 174.5h.6M188.5 172h-.5l-.2 .2 .2 .4 .5-.1M188.7 174v1.5h.3M189.4 174.7l.3-.2 .4 .2v.8M189.4 174v1.5M189.7 179.9v.1M189.9 171.7h-.6l-.2 .6a.52 .52 0 0 0 .8 .2M189.9 171.1v1.5M190.4 179.9v1.2l.3 .2M190.5 171.1v1.3l.2 .2M190.8 174.5l.1 1 .5-.1M191.3 171.7h.5l.1 .9"/>
<path d="M191.4 174.5v1M191.9 172h-.5l-.2 .2 .2 .4 .5-.1M192.1 174v1.5l.6-.1 .1-.6a.45 .45 0 0 0-.7-.2M192.5 179.9v1.4M192.6 171.7h.6l.1 .6a.52 .52 0 0 1-.7 .2M192.6 171.1v1.5M193.4 175.4v.1M193.9 172.4v.2M194.6 171.1v.1M194.6 171.7v.9M194.8 174.6l-.5-.1-.2 .2v.7l.7 .1M195.1 179.9v1.4"/>
<path d="M195.3 174.8a.45 .45 0 0 1 .7-.2v.9l-.6-.1zM195.3 171.7h.7l-.1 .8a.45 .45 0 0 1-.7-.2zM196.4 179.9v1.2l.2 .2M196.7 174.7l.2-.2 .4 .2v.8M196.7 174.5v1M197.3 174.7l.2-.2 .4 .1v.9M197.6 171.1l-1.2 1.8M198.2 172.5l.4 .1 .2-.3-.1-.6h-.5v1.4M199.4 171.7v.9M199.7 173.9l-1.3 2M199.9 171.7h-.3l-.2 .2M200.2 174.7l.2-.2 .4 .2v.8"/>
<path d="M200.2 174.5v1M200.4 171.7h.6v.8l-.5 .1-.2-.3zM200.8 174.7l.2-.2 .4 .2v.8M201.7 171.7v1.1l-.3 .3M201.7 171.1v.1M202.1 174.6l.4-.1 .2 .2v.8h-.6v-.4l.6-.2M202.3 172.1l.7-.1-.1-.3h-.5l-.1 .1v.6l.2 .2 .4-.1M203.4 179.9v.1M203.4 174.5v1M203.8 174.5l-.4 .3M204.1 174.5h.6M204.3 171.7h-.6l-.1 .2 .1 .6h.6"/>
<path d="M204.3 174v1.3l.1 .2h.3M204.7 171.7h.5M204.8 171.1v1.3l.4 .2M205.2 174v.2M205.2 174.5v1M205.3 179.9v1.2l.3 .2M205.9 174.7l.1-.2 .5 .2v.8M205.9 174.5v1M206.2 171.7h-.5l-.1 .2 .6 .3 .1 .2-.3 .2-.4-.1M207.1 174.5v1M207.6 174.5l-.5 .3M207.9 171.1l-1.2 1.8"/>
<path d="M208.2 174.5h.3l.2 .3-.1 .7h-.5l-.1-.3v-.4zM208.2 171.7l.4 .9 .4-.9M209.3 171.7l.9 .9M210 174.5v1.2l-.2 .3-.5-.1M210 174.6l-.4-.1-.3 .2v.7l.7 .1M210.2 171.7l-.9 .9M210.6 175l.7-.1v-.3l-.4-.1-.3 .2 .1 .8h.6M211.3 171.7h-.5l-.2 .6a.45 .45 0 0 0 .7 .2M211.3 171.1v1.5M212 174.5v1M212 171.7h.6v.9M212.1 179.8l-1.2 1.8"/>
<path d="M212.4 174.5l-.4 .3M212.6 172h-.5l-.1 .2 .1 .4 .5-.1M213.8 171.7h-.5l-.1 .2 .6 .3 .1 .2-.2 .2-.5-.1M213.9 173.9l-1.3 2M214.2 174l.5 1.5 .4-1.5M214.5 171.7h.6v.9M214.5 171.1v1.5M215.5 174l.9 1.5M216.4 174l-.9 1.5M217 174h.4l.4 .4v.7l-.3 .4h-.5zM218.5 174.6l.4-.1 .2 .2v.8h-.6l-.1-.4 .7-.2M220.3 174.6h-.6v.4h.6v.2v.3h-.6"/>
<path d="M220.9 174.7l.3-.2 .4 .2v.8M220.9 174v1.5M14.5 181.9a.65 .65 0 0 1 .8 .6 .65 .65 0 0 1-.8 .7zM38.5 195.9l.3-.4v1.3M38.5 196.8h.7M62.4 195.2v1.9M87 195.6l.7-.1 .1 .3-.8 1h.8M111 195.2v1.9M135.5 195.5h.8l-.5 .5 .5 .2-.1 .5-.5 .1-.2-.2M159.5 195.2v1.9M176 191.8h104.9M176 188.9h104.9"/>
<path d="M176 185h104.9M177.4 192.4v1.4M177.4 183.2h.5M177.6 193l.7 .8M178.1 182.5h-.7v1.4M178.2 189.8h-.8l-.1 .3 .8 .4 .1 .4-.3 .2-.6-.1M178.3 192.4l-.9 .8M178.7 182.5v.2M178.7 183v.9M178.8 189.7v.1M178.8 180.5l.4-.1 .2 .1v.8M178.8 190.2v.9"/>
<path d="M178.9 192.4v.2M178.9 192.9v.9M179.4 190.2h.7l-.7 .9h.7M179.4 182.5v1.3l.1 .1M180 183.4l.7-.1-.2-.3-.5 .2v.6l.3 .1 .3-.1M180 180.8l.7-.1-.2-.3-.5 .1v.6l.3 .2 .3-.1M180.4 192.6l-.4-.2-.5 .3 .1 1 .4 .1 .4-.1M180.6 190.6l.7-.1-.1-.3h-.6v.8h.6M181.1 192.9h.5v.9M181.3 180.8l.7-.1-.2-.3h-.3l-.2 .1v.6l.2 .2 .4-.1M181.4 183.8v.1M181.4 183.1v.1"/>
<path d="M181.6 193.2l-.5 .1-.1 .2 .1 .3h.5M181.9 191v.1M181.9 190.2v.2M182.4 180.4h.5M182.9 192.9h-.5l-.2 .7a.45 .45 0 0 0 .7 .2M182.9 192.4v1.4M183.4 181.2v.1M183.4 180.5h.1M183.5 191.1l.5-1.4 .4 1.4M183.7 190.7h.7M183.9 182.6l-.6-.1-.2 .2 .1 .4 .7 .4-.1 .3h-.7M184.4 195.4l-.3 1h.8"/>
<path d="M184.4 183l.3 .9 .2-.6 .4 .6 .2-.9M184.7 196v.8M184.8 193.1h.5M185.3 189.6l-.4 1h.9M185.5 192.4h-.7v1.4h.7M185.6 190.2v.9M186 193.7v.1M186 182.5v.2M186 183v.9M186.6 183h.6M186.8 192.4h.4l.4 .3v.8l-.4 .3h-.4zM186.8 182.5v1.3l.4 .1"/>
<path d="M188 180.4l.3 .9 .3-.7 .2 .7 .3-.9M188.3 193.7v.1M188.3 183.1h-.7v.7h.7M188.7 193.8l.5-1.4 .5 1.4M188.8 183.1h.6v.8M188.8 193.4h.7M188.8 182.5v1.4M189.7 180.4v.9M190.2 193.7v.1M190.2 183.1l.4-.1 .2 .2v.7M190.2 180.4h.5M190.8 183.3l-.6 .1-.1 .2 .2 .3 .5-.1"/>
<path d="M191.5 183.1h.6v.7h-.6M191.5 182.5v1.4M191.8 180.5l-.4-.1-.3 .2 .1 .6h.6M192.5 180.5l.4-.1 .2 .1v.8M192.7 193l-.2 .3h-.4l-.2-.3v-.3l.2-.3h.4l.2 .3v.8l-.2 .3h-.4M192.8 182.5v1.3l.2 .1M193.3 193.7v.1M193.5 183.4l.7-.1-.2-.3h-.3l-.2 .2v.6l.2 .1 .4-.1M193.8 180.5l.4-.1 .2 .1v.8M194.1 192.6l.2-.2a.75 .75 0 0 1 .6 .7 .75 .75 0 0 1-.6 .7l-.2-.1-.1-.4zM194.4 180.7l-.6 .1-.1 .2 .2 .3 .5-.1M194.4 184.1h1.2"/>
<path d="M195.1 180.5l.4-.1 .3 .2-.1 .6h-.6M195.4 193.7v.1M195.4 188.9v2.9M196 183.3l.6-.1 .1-.5-.2-.2h-.5v1.4M196.3 183.3l.4 .6M196.4 192.4h.1a.8 .8 0 0 1 .4 .8 .8 .8 0 0 1-.5 .6 .89 .89 0 0 1 0-1.4zM197.1 180.8l.7-.1-.1-.2h-.6v.7h.6M197.3 183.4l.7-.1-.2-.3h-.3l-.2 .2v.6l.2 .1 .4-.1M198.7 189.7a.73 .73 0 0 1 .9 .7 .73 .73 0 0 1-.9 .7zM199.1 183.1l-.4-.1-.1 .3 .1 .1h.3l.2 .4-.2 .1-.4-.1M199.5 180.6h.6l.3-.2v-.3l-.3-.2h-.6v1.4M199.8 183.8v.1"/>
<path d="M199.9 180.6l.5 .7M200.2 190.2h.6l.1 .9M200.5 182.5v1.4M200.6 183.4l.4 .5M200.9 190.5l-.7 .1v.4h.7M201 180.8l.6-.1-.1-.2h-.5v.7h.5M201 183l-.5 .5M201.4 190.2h.5M201.5 189.7v1.3l.4 .1M201.7 182.5v.2M201.7 183v.9M202.3 190.6l.7-.1-.1-.3h-.5l-.1 .2v.6l.2 .1 .4-.1"/>
<path d="M202.7 180.5l-.3-.1-.3 .2 .1 .2 .5 .1 .1 .2-.2 .2-.5-.1M203 183.1l-.4-.1-.3 .3 .1 .5h.6M203.4 180.4v.9M203.7 191v.1M203.7 190.2v.2M203.7 183.1l.3-.1 .3 .2v.7M204.3 183.3l-.6 .1-.1 .2 .1 .3 .6-.1M204.6 180.5l-.3-.1-.3 .2 .1 .2 .5 .1 .1 .2-.3 .2-.4-.1M205.1 180.4h.5M205.4 189.8l.5-.1 .3 .4-.9 1h.9M205.5 183.1l-.3-.1-.4 .3 .1 .5h.6M205.5 182.5v1.4"/>
<path d="M205.9 184.1h1.1M206.1 180.5h.6v.7h-.6zM206.9 189.8h.5a1.01 1.01 0 0 1-.2 1.3 .87 .87 0 0 1-.3-1.3zM207.5 180.4v.9M207.8 183.1l-.3-.1-.2 .3 .1 .1h.3l.2 .4-.2 .1-.4-.1M207.8 180.4l-.3 .1v.1M208.1 195.2v1.9M208.1 189.8h.8l.1 .3-.9 1h.9M208.2 180.3l.5-.4v1.4M208.2 181.3h.9M209.2 183.1l-.5-.1-.2 .3 .1 .5h.6M209.7 180.3l.4-.4v1.4"/>
<path d="M209.7 181.3h.8M209.8 183.1l.4-.1 .2 .2v.7M209.8 182.5v1.4M210.3 189.7h-.7l-.1 .7 .6-.2 .2 .3v.4l-.2 .2-.6-.1M210.9 190.5h1.1M212.8 189.8l.3-.1a.73 .73 0 0 1 .5 .7 .73 .73 0 0 1-.5 .7l-.3-.1-.1-.5zM214.3 190.3l-.2-.3 .1-.2h.6v.4l-.5 .1-.2 .2v.4l.2 .2h.4l.2-.2v-.4l-.2-.2M215.5 190.5h1.1M217.3 190.1l.4-.4v1.4M217.3 191.1h.8M218.8 189.8l.2-.1a.76 .76 0 0 1 .5 .7 .76 .76 0 0 1-.5 .7 1.01 1.01 0 0 1-.2-1.3zM233.3 195.5h-.6l-.1 .6 .2-.1h.3l.3 .2v.3l-.3 .3h-.3l-.2-.2"/>
<path d="M256.6 195.2v1.9M257.5 188.9v6.3M260 192.4v1.4M261.2 192.9h-.5l-.1 .3v.4l.2 .2h.4M261.2 192.4v1.4M261.9 193.7v.1M261.9 192.9v.2M263.6 192.4h.9l-.5 .5 .5 .2v.5l-.3 .2h-.4l-.2-.1M265.1 192.7l.5-.3a.8 .8 0 0 1 .3 .8 .8 .8 0 0 1-.5 .6 .93 .93 0 0 1-.3-1.1zM267.6 192.3l-1.3 1.9M267.9 192.4h.9l-.5 .5 .5 .2v.6l-.3 .1h-.4l-.2-.1M270 192.4l-.5 .2a1.02 1.02 0 0 0 .1 1.2h.4l.2-.2v-.4l-.3-.3h-.3l-.2 .3"/>
<path d="M281.5 181.9a.65 .65 0 0 1 .7 .6 .65 .65 0 0 1-.7 .7zM281.8 195.5h-.4l-.3 .5v.5l.3 .3 .4-.1v-.7h-.4l-.3 .2"/>
</g>
<g fill="none" stroke="#980000" stroke-width=".25">
<path d="M124 104.6h2.1l-1.1 1.5zM124 106.1h2.1M177.4 178.5l.4-1.5 .5 1.5M177.5 178h.6M178.8 177v1.2l.2 .3M179.5 178l.7-.2-.2-.3h-.4l-.1 .7 .2 .3 .4-.1M180.7 177.5l.7 1M181.4 177.5l-.7 1M183.1 178.5v-1.5l.5 1 .5-1v1.5M184.7 177v.1M184.7 177.5v1M185.4 177v1.2l.3 .3"/>
<path d="M186.2 177v1.2l.2 .3M186.9 178l.7-.2-.1-.3h-.6v.9h.6M188.2 177.5v1M188.6 177.5l-.4 .3M191.2 177.7v.3l-.5 .5a.43 .43 0 0 1-.4-.2 .43 .43 0 0 1 0-.5l.6-.5-.1-.3h-.3a.55 .55 0 0 0 .2 .8l.7 .7M193.1 178.5v-1.5l.5 1 .5-1v1.5M194.8 177.5h.6v1M195.4 177.8l-.4 .1-.3 .2 .3 .4 .4-.1M196.2 177.5v1M196.5 177.5h-.2l-.1 .3M196.8 177.5h.6M197 177v1.2l.4 .3"/>
<path d="M197.9 177v.1M197.9 177.5v1M198.5 177.6l.1-.1a.36 .36 0 0 1 .6 .2v.8M198.5 177.5v1M201 177.8l.7-.1 .1-.2v-.4l-.8-.1v1.5M201.3 177.8l.5 .7M204.4 177.5v1.1l-.2 .3h-.4M204.4 177.5h-.4l-.3 .3 .1 .6h.6M205 178l.7-.2-.1-.3h-.4l-.2 .2 .1 .7h.5M206.3 177.5v1M206.8 177.5l-.5 .3M260.1 190.5l.7-.1 .1-.6-.8-.1v1.5"/>
<path d="M260.4 190.5l.5 .7M261.4 190.7l.7-.1-.1-.4h-.5l-.1 .7 .2 .3 .4-.1M262.6 190.2l.4 1 .3-1M263.9 191v.2M263.9 190.2v.2M265.8 189.8l.1-.1a.76 .76 0 0 1 .6 .8 .76 .76 0 0 1-.6 .7 1.01 1.01 0 0 1-.1-1.4zM267 191v.2M267.8 189.8l.2-.1a.75 .75 0 0 1 .6 .8 .75 .75 0 0 1-.6 .7l-.2-.2-.1-.4z"/>
<circle cx="202.7" cy="178" r=".48"/>
</g>
<g fill="none" stroke="#980000" stroke-width=".42">
<path d="M177.7 185.8h1.1M178.2 185.8l-.2 1.9M179.3 186.4l-.1 1.3M179.4 185.8v.1M180 186.4h.8M180.3 185.8l-.1 1.6 .4 .3M181.4 185.8l-.1 1.6 .2 .3M182.2 187l1-.1-.1-.4a.6 .6 0 0 0-.8 .2v.9h.7M184 187.5l-.1 .2-.1-.1 .2-.1-.1 .2M184.1 186.5v.2M186.3 187.7l.2-1.9 .5 1.3 .9-1.3-.3 1.9M188.7 186.5h.7v1.2"/>
<path d="M189.5 186.9h-.7l-.3 .3v.2l.2 .3 .7-.1M190.4 186.4l-.1 1.3M190.5 185.8v.1M191.3 186.6l.1-.1a.48 .48 0 0 1 .8 .2l-.2 1M191.3 186.4v1.3M194.6 186.5h.7v1.2M195.4 186.9h-.7l-.3 .3v.2l.2 .3 .7-.1M196.3 186.4l-.1 1.3M196.9 186.4l-.4 .1-.2 .3M198.4 186.5a.65 .65 0 0 0-1 .3v.7a.64 .64 0 0 0 .9 .1M199.2 186.6l.1-.1a.48 .48 0 0 1 .8 .2l-.2 1M199.3 185.8l-.3 1.9"/>
<path d="M201 186.4l-.2 1.3M201.1 185.8v.1M201.7 186.4h.6M202 185.8l-.2 1.6 .4 .3M202.9 187l.9-.1v-.4l-.6-.1-.3 .3v.9h.7M205.5 186.5a.65 .65 0 0 0-1 .3v.7a.64 .64 0 0 0 .9 .1M206.1 186.4h.7M206.4 185.8l-.2 1.6 .5 .3M207.4 186.4v1.2l.5 .1 .3-.2M208.3 186.4l-.2 1.3M209.2 186.4l-.2 1.3M209.8 186.4l-.4 .1-.2 .3"/>
<path d="M210.2 187l1-.1v-.4a.6 .6 0 0 0-.9 .2v.9h.7"/>
</g>
<path d="M116.4 90h.6l.6 .5-.6 .6h-.6z" fill="#fff"/>
<path d="M109.6 90.5h.6v-.5l-.6-.1v1.2M109.8 90.5l.5 .6M110.8 90.7l.5-.2v-.1h-.5v.7h.5M112.3 90.4l-.3-.1-.2 .2 .2 .2h.3v.4h-.5M112.6 91.2h.9M114 89.9l.5 .1a.79 .79 0 0 1-.2 1.1h-.3a.86 .86 0 0 1 0-1.2zM115.8 89.9v1.2l-.7-1.2v1.2M116.4 90h.6l.6 .5-.6 .6h-.6z" fill="none" stroke="#805e00" stroke-width=".21"/>
<path d="M126.2 89.6h5v2h-5z" fill="none" stroke="#980000" stroke-width=".25"/>
<path d="M125 90.5h1.2M131.2 90.5h1.2" fill="none" stroke="#980000" stroke-width=".21"/>
<path d="M146.6 78.2h1.2v.7l-.6 .6-.6-.6z" fill="#fff"/>
<path d="M146.5 71.5h1.3l-1.3 .7h1.3M146.6 78.2h1.2v.7l-.6 .6-.6-.6zM146.6 72.8v.5l.2 .1h.6l.3-.1 .1-.4-.2-.2h-.4v.2M146.6 70.4a.67 .67 0 0 1 .8-.2 .67 .67 0 0 1 .4 .7h-1.3zM147 75l-.1 .2 .3 .2 .2-.4 .2-.1 .2 .2-.1 .3M147.2 77.7v-.5l-.3-.3-.3 .1-.1 .7h1.3M147.7 75.9l.1 .4-.2 .2h-.5l-.2-.2 .1-.4h.2l.2 .6M147.8 76.9l-.6 .4M147.9 73.7v.9" fill="none" stroke="#805e00" stroke-width=".21"/>
<path d="M125 93v1.3M125 99.2v1.2M142.3 90.5h2.7M145.5 88.9h2.4v3.3h-2.4M147.2 100.4v1.2h1.3l-1.3 1.3-1.3-1.3h1.3M147.2 100.4h.1" fill="none" stroke="#980000" stroke-width=".21"/>
<path d="M124 94.3h2.1v4.9h-2.1zM145 88.7v3.8M145.5 88.4v.9M145.5 90.1v1M145.5 91.8v1" fill="none" stroke="#980000" stroke-width=".25"/>
<path d="M145.7 90.5l1-.3v.7z" fill="#980000"/>
<path d="M145.7 90.5l1-.3v.7zM147.2 88.1v.8" fill="none" stroke="#980000" stroke-width=".21"/>
<circle cx="146.4" cy="90.6" r="2.75" fill="none" stroke="#980000" stroke-width=".25"/>
<path d="M147 88.6h.4v.5h-.4z" fill="#980000"/>
<path d="M147 88.6h.4v.5h-.4z" fill="none" stroke="#980000" stroke-width=".21"/>
<path d="M147 92h.4v.5h-.4z" fill="#980000"/>
<path d="M139.8 90.5h2.5M145.5 90.5h1.7v5M147 92h.4v.5h-.4zM147.2 85.6v2.5M147.5 90.2h.8M147.9 90.2l.4 .6h-.8z" fill="none" stroke="#980000" stroke-width=".21"/>
<path d="M140.7 89.4l.3-.5v1.3M140.7 90.2h.6M145.6 87.2v-.7l.5 .4 .2-.4 .5 .1v.6M146.8 93.8v.8l-.8-.8-.4 .3v.3l.1 .2" fill="none" stroke="#bd0000" stroke-width=".21"/>
<path d="M147.2 79.5v6.1M117.6 90.5h7.4v2.5M132.4 90.5h7.4M147.2 95.5v4.9M125 100.4v2.5M125 107.8v2.5" fill="none" stroke="#00a200" stroke-width=".21"/>
<g fill="none" stroke="#001dcd" stroke-width=".21">
<path d="M125.2 121.7l.4-1.3 .3 1.3M125.3 121.4h.6M126.4 120.9a.36 .36 0 0 1 .6 .2l-.1 .5h-.5M126.4 120.9v1.2M127.5 120.9h.6v.6l-.2 .2-.4-.1M127.5 120.9v1.2M128.6 120.9v.8M129 120.9h-.4v.2M129.4 120.9h.3l.3 .2v.3l-.3 .3-.4-.3zM130.3 120.9l.7 .8M131 120.9l-.7 .8M133 120.9v.2a.36 .36 0 0 1-.6-.2l.1-.4 .3-.1 .2 .2v.8l-.3 .3h-.2"/>
<path d="M133.6 120.9h.4l.1 .1v.7M133.6 120.9v.8M134.1 121l.2-.1 .4 .1v.7M135.1 121.7l.4-1.3 .4 1.3M135.2 121.4h.6M137.8 120.9a.36 .36 0 0 0-.6 .2l.1 .5h.5M138.3 120.9h.5v.7l-.3 .1-.3-.3zM139.4 120.9h.5v.8M139.4 120.9v.8M140.9 120.9h-.4v.3l.3 .1 .2 .2-.2 .2-.3-.1M141.5 120.9v.6l.2 .2 .3-.2M142 120.9v.8"/>
<path d="M142.6 120.9h.4l.2 .1v.7M142.6 120.9v.8M143.2 121l.2-.1 .3 .1v.7M144.3 120.9h.3l.3 .2v.3l-.3 .3-.3-.1M144.3 120.9v1.2M145.2 120.9h.5M145.4 120.4v1.1l.3 .2M146.1 120.4v.2M146.1 120.9v.8M146.7 120.9h.5v.7l-.4 .1-.2-.3zM147.8 120.9h.3l.3 .1v.7M147.8 120.9v.8"/>
</g>
<circle cx="125" cy="90.5" r=".47" fill="#00a200"/>
<path d="M127.8 104.7h.7v.4l-.8 .8h.8M127.8 109.7l.2-.2h.3l.2 .2v.3l-.8 .8h.8M128.5 107.1h-.6l-.1 .5h.6l.1 .6-.2 .1h-.3l-.2-.1M128.9 104.6l.3 1.3 .5-1.3M128.9 109.5l.3 1.3 .5-1.3M129.1 107.6l.3-.1 .2 .1v.7M129.1 107.5v.8M129.6 107.6l.1-.1 .4 .1v.7M130.5 108.3l.4-1.2 .5 1.2M130.6 108h.6" fill="none" stroke="#970091" stroke-width=".21"/>
<g fill="none" stroke="#007170" stroke-width=".21">
<path d="M126.6 84.4l.6-.1 .1-.4-.7-.2v1.3M126.9 84.4l.4 .6M127.7 97.2h.8l-.4 .5 .4 .1v.6h-.8M127.8 86.5l.4-.4v1.3M127.8 84l.3-.3v1.3M127.8 87.4h.8M127.8 85h.7M127.9 99.7a.66 .66 0 0 1 .6 .4 .66 .66 0 0 1-.2 .8h-.4zM127.9 95.5l.6-.1v-.5l-.6-.1v1.2M128.1 95.5l.5 .5M128.9 97.2h.8l-.5 .5 .5 .1v.6h-.8M129 99.7h.7l-.4 .4 .4 .3v.5l-.7-.1"/>
<path d="M129 83.9l.4-.2 .3 .3-.8 1h.8M129.1 95.1l.3-.3v1.2M129.1 86.1v1.3M129.1 96h.6M129.2 86.9l.4 .5M129.6 86.6l-.5 .5M130.2 84l.3-.3v1.3M130.2 94.9l.5-.1 .2 .2-.7 1h.7M130.2 85h.6M130.4 97.2a.75 .75 0 0 1 .2 1.3l-.4-.3v-.7zM130.8 99.7a.55 .55 0 0 0-.6 .5v.5l.1 .2h.5l.1-.2v-.3l-.2-.3h-.3l-.2 .3M131.5 94.9a.61 .61 0 0 1 .7 .4 .61 .61 0 0 1-.4 .7 .71 .71 0 0 1-.3-1.1z"/>
<path d="M151.3 91.2l.5-.1 .1 .4-.7 .8h.7M151.3 88.9l.2-.3h.3l.2 .3v.8l-.2 .2-.5-.2zM151.4 89.6h.3l.4 .4M152.5 89l.4-.4v1.3M152.5 89.9h.7M153.2 91.1v1.2l-.8-1.2v1.2M153.6 91.1h.9l-.5 1.2M154.3 88.6a.72 .72 0 0 0-.6 .5 .72 .72 0 0 0 .3 .8l.3-.1 .1-.4a.35 .35 0 0 0-.4-.3 .35 .35 0 0 0-.3 .3M154.9 91.3l.2-.2h.3a.86 .86 0 0 1-.1 1.2l-.4-.2zM156.1 91.3l.1-.2 .4 .1a.66 .66 0 0 1-.3 1.1l-.2-.2zM157.2 91.2l.6-.1 .1 .2v.3l-.7 .7h.7M124.1 114.6l-.2-.1a.64 .64 0 0 0-.6 .6 .64 .64 0 0 0 .6 .7l.2-.1v-.4h-.2"/>
<path d="M125.3 114.5v1.3l-.6-1.3v1.3M125.9 114.5a.52 .52 0 0 1 .7 .3v.6a.52 .52 0 0 1-.7 .4zM127.9 102.8l.6-.1v-.5l-.6-.1v1.2M128.1 102.8l.5 .5M129.1 103l.6-.2-.1-.2h-.5v.7h.5M130.6 102.6h-.4l-.1 .1 .2 .3h.3v.3h-.5M131.4 102.1l.5 .2a.74 .74 0 0 1-.2 1h-.4a.86 .86 0 0 1 .1-1.2zM133.1 102.1v1.2l-.6-1.2v1.2M146.3 104.7h-.6l-.1 .2v.7l.1 .3 .6-.1v-.4h-.2M147.5 104.7v1.2l-.7-1.2v1.2M148.1 104.7h.5l.2 .2v.7l-.2 .3h-.5z"/>
</g>
</svg>
